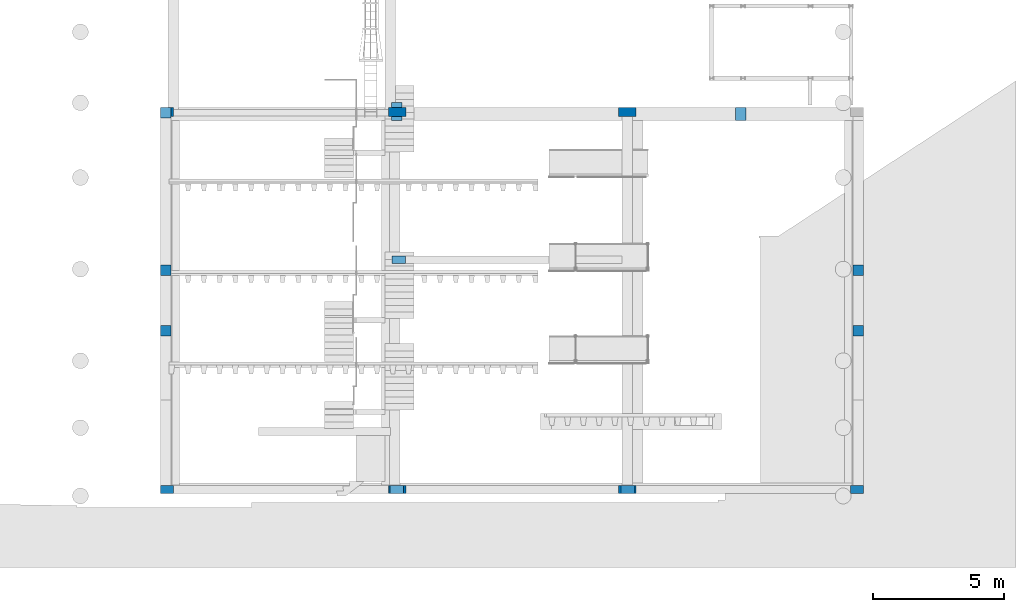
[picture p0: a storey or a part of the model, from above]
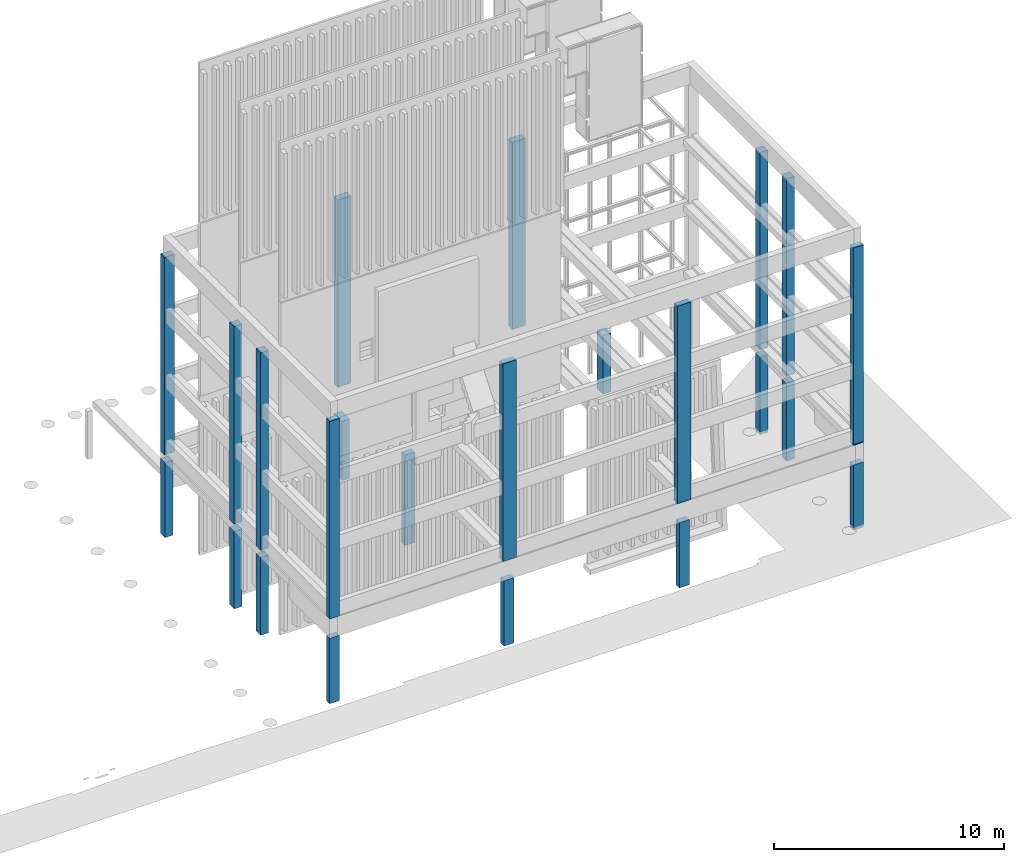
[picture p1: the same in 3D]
Properties of the parts of a building model (IFC2X3), part 1 of 16

# File
Description: ViewDefinition [CoordinationView_V2.0], Comment [Comments], Comment [System: OpenBuildings Designer24.00.03.14]
File name: SHE_DRAWING+SHEET revF16
Time: 2026-03-13T23:36:26+01:00
Author: First Name Last Name
Organization: Organization Name
Written by: ST-DEVELOPER v16.13
Made in: OpenBuildings Designer 24.00.03.14
Authorization: Administrator
Comment: Generated by software containing ST-Developer * from STEP Tools, Inc. (www.steptools.com)
Comment: description
Comment: implementation_level
Comment: name
Comment: time_stamp
Comment: author
Comment: organization
Comment: preprocessor_version
Comment: originating_system
Comment: authorisation

# IfcProject, BuildingTemplate_UK
Project - Project Name: BuildingTemplate_UK

# IfcSite, Site
RefElevation: 0 m
Pset_SiteCommon - BuildableArea: 0 m2
Site - Site Name: Site; Building Height Limit: 0 m

# IfcBuilding, Building01
ElevationOfRefHeight: 4.64 m; ElevationOfTerrain: 0 m
Classification - Uniclass2015: Co_20
Building Parameters - Building Name: Building01

# IfcBuildingStorey (2)
In: Building01
Pset_BuildingStoreyCommon - GrossAreaPlanned: 9600 m2; NetAreaPlanned: 9600 m2
Structural Floor Parameters - Column Splice Floor: no
Floor Parameters - Length (Approx.): 120 m; Width (Approx.): 80 m; Typical Floor: no; Typical Floor Base Elevation: 0 m; ACS Rotation Angle: 0:0; Annotate: yes
Floor - Area (Gross): 9600 m2; Area (Net): 9600 m2
Name | Elevation (m) = Elevation | Finished Floor | Floor Name | Typical Floor Height (m)
GF | 0 | GF | 3 | Description: Ground Floor; Floor Parameters - Description: Ground Floor
RL | 20.78 | RL | 0 | Classification - Uniclass2015: EF_30_20

# IfcSpace: A-AdministrativeCommercialAndProtectiveSer, 0
In: RL
Type - PredefinedType: USERDEFINED
Type - Space Parameters - Label: Administrative & Commercial Spaces; Ceiling Height: 3 m; major: 1; minor: 1
Type - Materials - Part Definition: A-Spaces::A_BSUK_AdministrativeCommercialAndProtectiveSer
Type - Energy Analysis - Energy Analysis | Space Category: Interior
Type - Discipline - Discipline: Architectural
Type - Construction Phase - Phase: New Construction
Type - Classification - Uniclass2015: SL_20
Description: UNIT; LongName: commercial; ElevationWithFlooring: -4.64 m
Space Parameters - Label: UNIT; Space Number: 0; Label 2: commercial; Ceiling Height: 4.5 m; Perimeter: 44.9707 m; Area | Program: 0 m2; Area | Actual: 99.3628 m2

# IfcSpace: A-CirculationAndStorageSpaces (61)
In: RL
Type - PredefinedType: USERDEFINED
Type - Space Parameters - Label: Circulation & Storage Spaces; Ceiling Height: 3 m; major: 1; minor: 1
Type - Materials - Part Definition: A-Spaces::A_BSUK_CirculationAndStorageSpaces
Type - Energy Analysis - Energy Analysis | Space Category: Interior
Type - Discipline - Discipline: Architectural
Type - Construction Phase - Phase: New Construction
ElevationWithFlooring: -4.64 m
Space Parameters - Area | Program: 0 m2
Name | Description = Label | LongName | Space Number | Label 2 | Ceiling Height (m) | Perimeter (m) | Area | Actual (m2)
1 | stair | vinyl (acD) | 1 | vinyl (acD) | 2.5 | 9.93685 | 4.25527
1 | riser | 1 | 1 |  | 2.5 | 3.72964 | 0.510705
0 | riser | 0 | 0 |  | 2.5 | 11.4772 | 2.99959
bike store | bike store | asphalt |  | asphalt | 2 | 15.5649 | 11.0029
bike store | bike store | asphalt |  | asphalt | 2 | 9.73329 | 5.58868
landing | landing | carpet (acD) |  | carpet (acD) | 2.5 | 11.3025 | 5.20961
WC | WC | tile |  | tile | 2.5 | 8.28221 | 4.08071
1 | storage | screed | 1 | screed | 2.5 | 8.26251 | 3.91896
storage | storage | screed |  | screed | 2.5 | 13.8687 | 10.5472
1 | stair | vinyl (acD) | 1 | vinyl (acD) | 2.5 | 11.6311 | 5.18709
2 | stair | vinyl (acD) | 2 | vinyl (acD) | 2.5 | 9.10975 | 3.67745
landing | landing | carpet (acD) |  | carpet (acD) | 2.5 | 6.70142 | 2.46885
storage | storage | parquet |  | parquet | 2.5 | 6.66153 | 2.57457
bath | bath | tile |  | tile | 2.5 | 8.02096 | 3.98235
3 x 1 | AOV | 1 | 1 |  | 2.6 | 3.35384 | 0.672727
3 x 1 | riser | 1 | 1 |  | 2.6 | 3.35384 | 0.672727
3 x hall (vented) | hall (vented) | carpet (acC) |  | carpet (acC) | 2.6 | 20.6 | 10.6
1 | stair | vinyl (acD) | 1 | vinyl (acD) | 2.5 | 11.2192 | 7.00439
landing | landing | vinyl (acD) |  | vinyl (acD) | 2.6 | 7.88137 | 3.11561
3 x 1 | lobby | carpet (acC) | 1 | carpet (acC) | 2.6 | 6.79532 | 2.84649
3 x 2 | riser | 2 | 2 |  | 2.6 | 3 | 0.36
3 x 2 | lobby | carpet (acC) | 2 | carpet (acC) | 2.6 | 13.6601 | 7.68884
2 x 1 | stair | vinyl (acD) | 1 | vinyl (acD) | 2.5 | 11.2192 | 7.00458
2 x landing | landing | vinyl (acD) |  | vinyl (acD) | 2.6 | 7.9118 | 3.13941
landing | landing | vinyl (acD) |  | vinyl (acD) | 2.5 | 7.02024 | 2.75607
hall (vented) | hall (vented) | carpet (acC) |  | carpet (acC) | 2.5 | 16.6709 | 8.79017
1 | lobby | carpet (acC) | 1 | carpet (acC) | 2.5 | 7.86583 | 3.64937
2 | lobby | carpet (acC) | 2 | carpet (acC) | 2.5 | 7.53988 | 3.40491
1 | AOV | 1 | 1 |  | 2.5 | 4.25 | 0.936464
1 | riser | 1 | 1 |  | 2.5 | 3.23114 | 0.605336
1 | stair | vinyl (acD) | 1 | vinyl (acD) | 2.5 | 11.3017 | 7.67441
3 | stair | parquet | 3 | parquet | 2.5 | 9.30005 | 3.43648
4 | stair | parquet | 4 | parquet | 2.5 | 9.86062 | 3.62728
5 | stair | parquet | 5 | parquet | 2.5 | 9.09993 | 3.28497
6 | stair | parquet | 6 | parquet | 2.5 | 9.4 | 3.42
26 | FLAT | 4b6p (upper) | 26 | 4b6p (upper) | 2.5 | 35.2527 | 38.2118
23 | FLAT | 4b6p (upper) | 23 | 4b6p (upper) | 2.5 | 35.2129 | 43.2149
24 | FLAT | 3b6p (upper) | 24 | 3b6p (upper) | 2.5 | 35.1807 | 43.4478
25 | FLAT | 3b6p (upper) | 25 | 3b6p (upper) | 2.5 | 38.0413 | 41.0862
1 | AOV | 1 | 1 |  | 2.5 | 3.5 | 0.715
2 | AOV | hatch over | 2 | hatch over | 2.5 | 5.99988 | 1.99994
ter.23 | ter.23 | tile |  | tile | 2.5 | 19.7927 | 12.5632
ter.24 | ter.24 | tile |  | tile | 2.5 | 19.7924 | 12.5622
ter.26 | ter.26 | tile |  | tile | 2.5 | 19.7922 | 12.5629
ter.25 | ter.25 | tile |  | tile | 2.5 | 19.7919 | 12.5618
2 | AOV | access hatch | 2 | access hatch | 2.5 | 5.99988 | 1.99994
1 | AOV | MSVS | 1 | MSVS | 2.5 | 10.8891 | 5.66237

# IfcSpace: A-ResidentialSpaces (28)
In: RL
Type - PredefinedType: USERDEFINED
Type - Space Parameters - Label: Residential Spaces; Ceiling Height: 3 m; major: 1; minor: 1
Type - Materials - Part Definition: A-Spaces::A_BSUK_ResidentialSpaces
Type - Energy Analysis - Energy Analysis | Space Category: Interior
Type - Discipline - Discipline: Architectural
Type - Construction Phase - Phase: New Construction
Type - Classification - Uniclass2015: SL_45
ElevationWithFlooring: -4.64 m
Space Parameters - Area | Program: 0 m2
Name | Description = Label | LongName = Label 2 | Space Number | Ceiling Height (m) | Perimeter (m) | Area | Actual (m2)
01 | FLAT | 2b4p (lower) | 01 | 2.5 | 30.3387 | 47.5078
ENTRANCE | ENTRANCE | residential |  | 4.5 | 31.3079 | 32.4907
01 | FLAT | 2b4p (upper) | 01 | 2.5 | 38.9093 | 49.176
07 | FLAT | 1b1p | 07 | 2.6 | 25.786 | 41.2992
06 | FLAT | 1b1p | 06 | 2.6 | 30.6107 | 40.6276
05 | FLAT | 1b1p | 05 | 2.6 | 28.883 | 41.0837
04 | FLAT | 1b1p | 04 | 2.6 | 28.903 | 41.1303
03 | FLAT | 1b1p | 03 | 2.6 | 30.9647 | 42.3191
02 | FLAT | 2b4p | 02 | 2.6 | 40.6617 | 73.0942
08 | FLAT | 1b1p | 08 | 2.6 | 29.5789 | 45.4997
21 | FLAT | 1b1p | 21 | 2.6 | 27.53 | 42.5859
20 | FLAT | 1b1p | 20 | 2.6 | 31.4827 | 41.2785
19 | FLAT | 1b1p | 19 | 2.6 | 28.883 | 41.0727
18 | FLAT | 1b1p | 18 | 2.6 | 28.903 | 41.1303
17 | FLAT | 1b1p | 17 | 2.6 | 31.8367 | 42.96
16 | FLAT | 2b4p | 16 | 2.6 | 41.0977 | 73.4146
22 | FLAT | 1b1p | 22 | 2.6 | 30.0149 | 45.8163
26 | FLAT | 4b6p (lower) | 26 | 2.5 | 39.478 | 74.3995
23 | FLAT | 4b6p (lower) | 23 | 2.5 | 39.2381 | 76.1835
24 | FLAT | 3b6p (lower) | 24 | 2.5 | 39.6636 | 68.1409
25 | FLAT | 3b6p (lower) | 25 | 2.5 | 39.3775 | 63.4613
14 | FLAT | 1b1p | 14 | 2.6 | 27.53 | 42.5859
13 | FLAT | 1b1p | 13 | 2.6 | 31.4827 | 41.2785
12 | FLAT | 1b1p | 12 | 2.6 | 28.883 | 41.0837
11 | FLAT | 1b1p | 11 | 2.6 | 28.903 | 41.1303
10 | FLAT | 1b1p | 10 | 2.6 | 31.8367 | 42.96
09 | FLAT | 2b4p | 09 | 2.6 | 41.0977 | 73.4146
15 | FLAT | 1b1p | 15 | 2.6 | 30.0149 | 45.8163

# IfcSpace: _Exterior Space (23)
Type - PredefinedType: USERDEFINED
Type - Space Parameters - Label: EXTERIOR SPACE; Ceiling Height: 3 m; Area | Program: 0 m2; major: 1; minor: 1
Type - Materials - Part Definition: A-Spaces::_Exterior_Space
Type - Energy Analysis - Energy Analysis | Space Category: Exterior
Type - Discipline - Discipline: Architectural
Type - Construction Phase - Phase: New Construction
Type - Classification - Uniclass2015: PM_40_30_17
ElevationWithFlooring: -4.64 m
Name | In | Description = Label | LongName = Label 2 | Ceiling Height (m) | Perimeter (m) | Area | Actual (m2) | Space Number
storage | RL | storage | asphalt | 2.5 | 10.2434 | 4.88146
plant | RL | plant | sprinkler | 2.5 | 13.8942 | 9.76522
refuse area | RL | refuse area | asphalt | 2 | 23.634 | 16.6836
bike store | RL | bike store | asphalt | 2 | 15.0532 | 9.86402
0 | RL | YARD | asphalt | 4 | 45.5698 | 90.2117 | 0
UNDERCROFT (front) | RL | UNDERCROFT (front) | paving | 4 | 62.6011 | 86.1884
UNDERCROFT (back) | RL | UNDERCROFT (back) | asphalt | 4 | 58.8215 | 136.239
1 | RL | Car P. | flat23 | 2 | 14.8 | 12 | 1
2 | RL | Car P. | flat24 | 2 | 14.8 | 12 | 2
3 | RL | Car P. | flat25 | 2 | 14.8002 | 12.0005 | 3
4 | RL | Car P. | flat26 | 2 | 14.8 | 12 | 4
1 | RL | YARD | asphalt (flat01) | 4 | 17.9409 | 17.4995 | 1
5 | RL | Car P. | flat01 | 2 | 14.8 | 12 | 5
storage | RL | storage | carpet | 2.5 | 8.04048 | 2.75523
storage | RL | storage | carpet | 2.5 | 8.04048 | 3.18825
1 | RL | AC | optional |  | 2.79325 | 0.397029 | 1
2 | RL | AC | optional |  | 2.79325 | 0.397029 | 2
4 | RL | AC | optional |  | 2.79325 | 0.397029 | 4
3 | RL | AC | optional |  | 2.79325 | 0.397029 | 3
flat roof | RL | flat roof | brown roof (tbc) | 2 | 56.1601 | 160.64
16 | GF | balc. | tile |  | 17.6972 | 14.8939 | 16
09 | GF | balc. | tile |  | 17.6972 | 14.8939 | 09
02 | GF | balc. | tile |  | 17.6972 | 14.8939 | 02

# IfcSpace: _Interior (139)
In: RL
Type - PredefinedType: USERDEFINED
Type - Space Parameters - Label: INTERIOR SPACE; Ceiling Height: 3 m; Area | Program: 0 m2; major: 1; minor: 1
Type - Materials - Part Definition: A-Spaces::_Interior_Space
Type - Energy Analysis - Energy Analysis | Space Category: Interior
Type - Discipline - Discipline: Architectural
Type - Construction Phase - Phase: New Construction
Type - Classification - Uniclass2015: PM_40_30_17
ElevationWithFlooring: -4.64 m
Name | Description = Label | LongName = Label 2 | Ceiling Height (m) | Perimeter (m) | Area | Actual (m2)
7 x firef. LIFT | firef. LIFT | (1.1x1.4m) | 2.2 | 4.8 | 1.4
bed | bed | carpet | 2.6 | 16.9306 | 16.1823
bath | bath | tile | 2.6 | 8.42663 | 4.02329
corridor | corridor | parquet | 2.6 | 22.8095 | 18.4831
F | WC | tile (disab.) | 2.6 | 8.46664 | 4.29711 | Space Parameters - Space Number: F
M | WC | tile | 2.6 | 6.8273 | 2.65638 | Space Parameters - Space Number: M
2 | bed | carpet | 2.6 | 15.1363 | 13.1528 | Space Parameters - Space Number: 2
k/d/l | k/d/l | parquet | 2.6 | 21.6917 | 25.0467
k/d/l | k/d/l | parquet | 2.6 | 19.206 | 18.8529
3 x bath | bath | tile | 2.6 | 7.57 | 3.188
3 x storage | storage | parquet | 2.6 | 5 | 1.26
3 x bath | bath | tile | 2.6 | 8.85627 | 3.75315
3 x storage | storage | parquet | 2.6 | 4.75839 | 1.24325
k/d/l | k/d/l | parquet | 2.6 | 25.4441 | 23.3097
6 x bed | bed | carpet | 2.6 | 14.94 | 11.4885
3 x k/d/l | k/d/l | parquet | 2.6 | 24.0409 | 23.4095
6 x bath | bath | tile | 2.6 | 7.8 | 3.6
3 x storage | storage | parquet | 2.6 | 6.58993 | 1.70217
3 x storage | storage | parquet | 2.6 | 6.59 | 1.70223
3 x k/d/l | k/d/l | parquet | 2.6 | 24.497 | 23.2991
studio | studio | parquet | 2.6 | 31.4647 | 37.2975
3 x bath | bath | tile | 2.6 | 7.898 | 3.43088
3 x corridor | corridor | parquet | 2.6 | 16.5296 | 9.0203
3 x bath | bath | tile | 2.6 | 8.35 | 4.35
k/d/l | k/d/l | parquet | 2.6 | 20.4702 | 23.828
3 x 2 | bed | carpet | 2.6 | 15.0894 | 11.9399 | Space Parameters - Space Number: 2
3 x 1 | bed | carpet | 2.6 | 17.0797 | 15.1572 | Space Parameters - Space Number: 1
3 x storage | storage | parquet | 2.6 | 2.74374 | 0.470142
k/d/l | k/d/l | parquet | 2.6 | 20.6123 | 21.7383
corridor | corridor | parquet | 2.6 | 11.3315 | 6.13542
3 x bath | bath | tile | 2.6 | 7.80943 | 3.60707
3 x storage | storage | parquet | 2.6 | 4.56315 | 1.30038
3 x corridor | corridor | parquet | 2.6 | 13.57 | 6.7325
bed | bed | carpet | 2.6 | 14.4144 | 11.4258
bed | bed | carpet | 2.6 | 12.7068 | 9.99626
3 x bed | bed | carpet | 2.6 | 14.3106 | 11.3749
3 x ensuite | ensuite | tile | 2.6 | 7.89374 | 3.31102
3 x storage | storage | parquet | 2.6 | 4.59 | 1.1165
3 x storage | storage | parquet | 2.6 | 10.8267 | 2.53079
2 x k/d/l | k/d/l | parquet | 2.6 | 20.514 | 19.8142
2 x k/d/l | k/d/l | parquet | 2.6 | 26.3161 | 23.9605
2 x studio | studio | parquet | 2.6 | 32.3367 | 37.9385
2 x k/d/l | k/d/l | parquet | 2.6 | 20.9062 | 24.1484
2 x k/d/l | k/d/l | parquet | 2.6 | 20.8123 | 22.155
2 x corridor | corridor | parquet | 2.6 | 11.1315 | 6.01011
2 x bed | bed | carpet | 2.6 | 14.6504 | 11.4605
2 x bed | bed | carpet | 2.6 | 13.1428 | 10.3217
1 | bed | carpet | 2.5 | 18.5595 | 16.7018 | Space Parameters - Space Number: 1
2 | bed | carpet | 2.5 | 17.0596 | 17.0642 | Space Parameters - Space Number: 2
3 | bed | carpet | 2.5 | 15.5204 | 13.1055 | Space Parameters - Space Number: 3
1 | bed | carpet | 2.5 | 15.4796 | 12.4714 | Space Parameters - Space Number: 1
2 | bed | carpet | 2.5 | 17.0597 | 17.0642 | Space Parameters - Space Number: 2
3 | bed | carpet | 2.5 | 21.2205 | 20.0816 | Space Parameters - Space Number: 3
1 | bed | carpet | 2.5 | 15.8135 | 14.5623 | Space Parameters - Space Number: 1
2 | bed | carpet | 2.5 | 13.9942 | 11.7202 | Space Parameters - Space Number: 2
3 | bed | carpet | 2.5 | 15.43 | 13.4523 | Space Parameters - Space Number: 3
1 | bed | carpet | 2.5 | 15.9594 | 15.0373 | Space Parameters - Space Number: 1
2 | bed | carpet | 2.5 | 13.98 | 10.1834 | Space Parameters - Space Number: 2
3 | bed | carpet | 2.5 | 15.39 | 13.2723 | Space Parameters - Space Number: 3
corridor (protected) | corridor (protected) | parquet | 2.5 | 17.0031 | 11.5791
corridor (protected) | corridor (protected) | parquet | 2.5 | 15.5899 | 9.09301
corridor (protected) | corridor (protected) | parquet | 2.5 | 14.14 | 7.78613
corridor (protected) | corridor (protected) | parquet | 2.5 | 17.46 | 9.28961
bath | bath | tile | 2.5 | 11.4399 | 7.26747
bath | bath | tile | 2.5 | 9.60027 | 4.97525
bath | bath | tile | 2.5 | 9.61248 | 4.99208
ensuite | ensuite | tile | 2.5 | 9.6127 | 4.9406
ensuite | ensuite | tile | 2.5 | 8.21964 | 4.07132
ensuite | ensuite | tile | 2.5 | 8.21964 | 4.07133
bath | bath | tile | 2.5 | 8.94446 | 4.54559
ensuite | ensuite | tile | 2.5 | 7.27294 | 3.08918
storage | storage | parquet | 2.5 | 4.47976 | 1.20139
storage | storage | parquet | 2.5 | 5.08042 | 1.46085

# IfcBeam: A-Beams-Steel (168)
Type - PredefinedType: BEAM
Type - Profile - Name: UB203X133X25
Type - Thermal Transmittance - Is External: no; Is Below Grade: no
Type - Structural Usage - Structural | Material: Steel
Type - Structural Parameters - Section Name: UB203X133X25; Structural Type: Beam; Tapered Member: no
Type - Steel Beam Results - End 1 Shear: 0; End 2 Shear: 0
Type - Materials - Part Definition: A-Beams::A_BSUK_Beams_Steel
Type - Fireproofing - Has Fireproofing: no
Type - Fire Resistance - Fire | IsCombustible: no; Fire | Compartmentation: no
Type - Discipline - Discipline: Architectural
Type - Construction Phase - Phase: New Construction
Type - Classification - Uniclass2015: Pr_20_85_08_11
Material: A_BSUK_Beams_Steel
Pset_BeamCommon - IsExternal: no; LoadBearing: no
Steel Beam Results - Camber: 0 m
Quantities | Structural - Material Density: 7850.000000
Fireproofing - Fireproofing Thickness: 0 m
BuildingDesignerForm - Cope Flange Clearance: 0.000; Cope Web Clearance: 0.000; Cope Corner Treatment: 0; Cope Corner Radius: 0.000; Local Y Offset: 0.000; Local Z Offset: 0.000
Name | In | Description | CodeSystem | Name = StructuralFramingCommon, Section Name | Structural Parameters, Section Name | Length (m) | Area | Cross-sectional (m2) | Area | Cross-sectional Modeled (m2) | Area | Side Surfaces Modeled (Gross) (m2) | Area | All Surfaces Modeled (Net) (m2) | Volume | Perforation(s) (m3) | Volume (Gross) (m3) | Volume (Gross Modeled) (m3) | Volume (Net) (m3) | Volume (Net Modeled) (m3) | Unit Weight | Length x Unit Weight | Volume (Gross) x Density | Volume (Gross Modeled) x Density | Volume (Net) x Density | Volume (Net Modeled) x Density
A-Beams-Steel | RL | 1 ,SHE_DRAWING+SHEET.dgn,Design Model;2,SHE-02.MEZZANINE.dgn,Design Model:192737 | BS UC | UC203X203X46 | 1\BS UC\UC203X203X46 | 6.35664 | 0.00587 | 0.005784 | 7.66866 | 7.68022 | 0 | 0.037314 | 0.036766 | 0.037314 | 0.036766 | 46.100000 | 293.041306 | 292.910995 | 288.611640 | 292.910995 | 288.611640 | Construction Phase - Phase: Existing to Remain
A-Beams-Steel | RL | 1 ,SHE_DRAWING+SHEET.dgn,Design Model;2,SHE-02.MEZZANINE.dgn,Design Model:192800 | BS UC | UC203X203X46 | 1\BS UC\UC203X203X46 | 6.46778 | 0.00587 | 0.005784 | 7.80273 | 7.8143 | 0 | 0.037966 | 0.037409 | 0.037966 | 0.037409 | 46.100000 | 298.164608 | 298.032018 | 293.657497 | 298.032018 | 293.657497 | Construction Phase - Phase: Existing to Remain
A-Beams-Steel | RL | 1 ,SHE_DRAWING+SHEET.dgn,Design Model;5,SHE-13.STEEL.dgn,Design Model:105049 | BS UC | UC203X203X46 | 1\BS UC\UC203X203X46 | 2.3816 | 0.00587 | 0.005784 | 2.87316 | 2.88473 | 0 | 0.01398 | 0.013775 | 0.01398 | 0.013775 | 46.100000 | 109.791760 | 109.742937 | 108.132128 | 109.742937 | 108.132128
A-Beams-Steel | RL | 1 ,SHE_DRAWING+SHEET.dgn,Design Model;5,SHE-13.STEEL.dgn,Design Model:105052 | BS UC | UC305X305X158 | 1\BS UC\UC305X305X158 | 4.03635 | 0.0201 | 0.019938 | 7.53748 | 7.57736 | 0 | 0.081131 | 0.080477 | 0.081131 | 0.080477 | 158.100000 | 638.146935 | 636.875485 | 631.748162 | 636.875485 | 631.748162 | Identification - ID | Notes: PRE-CAMBER
A-Beams-Steel | RL | 1 ,SHE_DRAWING+SHEET.dgn,Design Model;5,SHE-13.STEEL.dgn,Design Model:105055 | BS UC | UC305X305X240 | 1\BS UC\UC305X305X240 | 4.2009 | 0.0306 | 0.030381 | 8.11866 | 8.17942 | 0 | 0.128548 | 0.127626 | 0.128548 | 0.127626 | 240.000000 | 1008.216000 | 1009.098189 | 1001.865000 | 1009.098189 | 1001.865000 | Identification - ID | Notes: PRE-CAMBER
A-Beams-Steel | RL | 1 ,SHE_DRAWING+SHEET.dgn,Design Model;5,SHE-13.STEEL.dgn,Design Model:105057 | BS UC | UC305X305X158 | 1\BS UC\UC305X305X158 | 3.9209 | 0.0201 | 0.019938 | 7.32189 | 7.36177 | 0 | 0.07881 | 0.078176 | 0.07881 | 0.078176 | 158.100000 | 619.894290 | 618.659207 | 613.678538 | 618.659207 | 613.678538 | Identification - ID | Notes: PRE-CAMBER
A-Beams-Steel | RL | 1 ,SHE_DRAWING+SHEET.dgn,Design Model;5,SHE-13.STEEL.dgn,Design Model:105059 | BS UC | UC305X305X158 | 1\BS UC\UC305X305X158 | 3.9185 | 0.0201 | 0.019938 | 7.31741 | 7.35728 | 0 | 0.078762 | 0.078128 | 0.078762 | 0.078128 | 158.100000 | 619.514850 | 618.280523 | 613.302903 | 618.280523 | 613.302903 | Identification - ID | Notes: PRE-CAMBER
A-Beams-Steel | RL | 1 ,SHE_DRAWING+SHEET.dgn,Design Model;5,SHE-13.STEEL.dgn,Design Model:105061 | BS UC | UC305X305X240 | 1\BS UC\UC305X305X240 | 4.2009 | 0.0306 | 0.030381 | 8.11866 | 8.17942 | 0 | 0.128548 | 0.127626 | 0.128548 | 0.127626 | 240.000000 | 1008.216000 | 1009.098189 | 1001.865000 | 1009.098189 | 1001.865000 | Identification - ID | Notes: PRE-CAMBER
A-Beams-Steel | RL | 1 ,SHE_DRAWING+SHEET.dgn,Design Model;5,SHE-13.STEEL.dgn,Design Model:105063 | BS UC | UC305X305X240 | 1\BS UC\UC305X305X240 | 8.42545 | 0.0306 | 0.030381 | 16.283 | 16.3438 | 0 | 0.257819 | 0.255971 | 0.257819 | 0.255971 | 240.000000 | 2022.108000 | 2023.877344 | 2009.370245 | 2023.877344 | 2009.370245
A-Beams-Steel | RL | 1 ,SHE_DRAWING+SHEET.dgn,Design Model;5,SHE-13.STEEL.dgn,Design Model:105065 | BS UC | UC305X305X240 | 1\BS UC\UC305X305X240 | 5.70725 | 0.0306 | 0.030381 | 11.0298 | 11.0906 | 0 | 0.174642 | 0.17339 | 0.174642 | 0.17339 | 240.000000 | 1369.740000 | 1370.938522 | 1361.111671 | 1370.938522 | 1361.111671
A-Beams-Steel | RL | 1 ,SHE_DRAWING+SHEET.dgn,Design Model;5,SHE-13.STEEL.dgn,Design Model:105067 | BS UC | UC305X305X240 | 1\BS UC\UC305X305X240 | 8.385 | 0.0306 | 0.030381 | 16.2049 | 16.2656 | 0 | 0.256581 | 0.254742 | 0.256581 | 0.254742 | 240.000000 | 2012.400000 | 2014.160850 | 1999.723398 | 2014.160850 | 1999.723398
A-Beams-Steel | RL | 1 ,SHE_DRAWING+SHEET.dgn,Design Model;5,SHE-13.STEEL.dgn,Design Model:105069 | BS UC | UC305X305X240 | 1\BS UC\UC305X305X240 | 8.42545 | 0.0306 | 0.030381 | 16.283 | 16.3438 | 0 | 0.257819 | 0.255971 | 0.257819 | 0.255971 | 240.000000 | 2022.108000 | 2023.877344 | 2009.370245 | 2023.877344 | 2009.370245
A-Beams-Steel | RL | 1 ,SHE_DRAWING+SHEET.dgn,Design Model;5,SHE-13.STEEL.dgn,Design Model:105071 | BS UC | UC305X305X240 | 1\BS UC\UC305X305X240 | 8.66545 | 0.0306 | 0.030381 | 16.7468 | 16.8076 | 0 | 0.265163 | 0.263262 | 0.265163 | 0.263262 | 240.000000 | 2079.708000 | 2081.527744 | 2066.607408 | 2081.527744 | 2066.607408
A-Beams-Steel | RL | 1 ,SHE_DRAWING+SHEET.dgn,Design Model;5,SHE-13.STEEL.dgn,Design Model:105073 | BS UC | UC305X305X240 | 1\BS UC\UC305X305X240 | 8.36 | 0.0306 | 0.030381 | 16.1565 | 16.2173 | 0 | 0.255816 | 0.253982 | 0.255816 | 0.253982 | 240.000000 | 2006.400000 | 2008.155600 | 1993.761193 | 2008.155600 | 1993.761193
A-Beams-Steel | RL | 1 ,SHE_DRAWING+SHEET.dgn,Design Model;5,SHE-13.STEEL.dgn,Design Model:105076 | BS UC | UC203X203X86 | 1\BS UC\UC203X203X86 | 5.4208 | 0.011 | 0.010874 | 6.80527 | 6.82702 | 0 | 0.059629 | 0.058948 | 0.059629 | 0.058948 | 86.100000 | 466.730880 | 468.086080 | 462.738835 | 468.086080 | 462.738835
A-Beams-Steel | RL | 1 ,SHE_DRAWING+SHEET.dgn,Design Model;5,SHE-13.STEEL.dgn,Design Model:105078 | BS UC | UC203X203X86 | 1\BS UC\UC203X203X86 | 5.4208 | 0.011 | 0.010874 | 6.80527 | 6.82702 | 0 | 0.059629 | 0.058948 | 0.059629 | 0.058948 | 86.100000 | 466.730880 | 468.086080 | 462.738835 | 468.086080 | 462.738835
A-Beams-Steel | RL | 1 ,SHE_DRAWING+SHEET.dgn,Design Model;5,SHE-13.STEEL.dgn,Design Model:105080 | BS UC | UC203X203X86 | 1\BS UC\UC203X203X86 | 5.7392 | 0.011 | 0.010874 | 7.20499 | 7.22674 | 0 | 0.063131 | 0.06241 | 0.063131 | 0.06241 | 86.100000 | 494.145120 | 495.579920 | 489.918595 | 495.579920 | 489.918595
A-Beams-Steel | RL | 1 ,SHE_DRAWING+SHEET.dgn,Design Model;5,SHE-13.STEEL.dgn,Design Model:105082 | BS UC | UC203X203X86 | 1\BS UC\UC203X203X86 | 5.4208 | 0.011 | 0.010874 | 6.80527 | 6.82702 | 0 | 0.059629 | 0.058948 | 0.059629 | 0.058948 | 86.100000 | 466.730880 | 468.086080 | 462.738835 | 468.086080 | 462.738835
A-Beams-Steel | RL | 1 ,SHE_DRAWING+SHEET.dgn,Design Model;5,SHE-13.STEEL.dgn,Design Model:105084 | BS UC | UC203X203X86 | 1\BS UC\UC203X203X86 | 5.505 | 0.011 | 0.010874 | 6.91098 | 6.93273 | 0 | 0.060555 | 0.059863 | 0.060555 | 0.059863 | 86.100000 | 473.980500 | 475.356750 | 469.926447 | 475.356750 | 469.926447
A-Beams-Steel | RL | 1 ,SHE_DRAWING+SHEET.dgn,Design Model;5,SHE-13.STEEL.dgn,Design Model:105086 | BS UC | UC203X203X86 | 1\BS UC\UC203X203X86 | 5.4208 | 0.011 | 0.010874 | 6.80527 | 6.82702 | 0 | 0.059629 | 0.058948 | 0.059629 | 0.058948 | 86.100000 | 466.730880 | 468.086080 | 462.738835 | 468.086080 | 462.738835
A-Beams-Steel | RL | 1 ,SHE_DRAWING+SHEET.dgn,Design Model;5,SHE-13.STEEL.dgn,Design Model:105088 | BS UC | UC203X203X86 | 1\BS UC\UC203X203X86 | 5.4208 | 0.011 | 0.010874 | 6.80527 | 6.82702 | 0 | 0.059629 | 0.058948 | 0.059629 | 0.058948 | 86.100000 | 466.730880 | 468.086080 | 462.738835 | 468.086080 | 462.738835
A-Beams-Steel | RL | 1 ,SHE_DRAWING+SHEET.dgn,Design Model;5,SHE-13.STEEL.dgn,Design Model:105090 | BS UC | UC203X203X86 | 1\BS UC\UC203X203X86 | 5.4208 | 0.011 | 0.010874 | 6.80527 | 6.82702 | 0 | 0.059629 | 0.058948 | 0.059629 | 0.058948 | 86.100000 | 466.730880 | 468.086080 | 462.738835 | 468.086080 | 462.738835
A-Beams-Steel | RL | 1 ,SHE_DRAWING+SHEET.dgn,Design Model;5,SHE-13.STEEL.dgn,Design Model:105092 | BS UC | UC203X203X86 | 1\BS UC\UC203X203X86 | 5.4208 | 0.011 | 0.010874 | 6.80527 | 6.82702 | 0 | 0.059629 | 0.058948 | 0.059629 | 0.058948 | 86.100000 | 466.730880 | 468.086080 | 462.738835 | 468.086080 | 462.738835
A-Beams-Steel | RL | 1 ,SHE_DRAWING+SHEET.dgn,Design Model;5,SHE-13.STEEL.dgn,Design Model:105094 | BS UC | UC203X203X86 | 1\BS UC\UC203X203X86 | 5.7392 | 0.011 | 0.010874 | 7.20499 | 7.22674 | 0 | 0.063131 | 0.06241 | 0.063131 | 0.06241 | 86.100000 | 494.145120 | 495.579920 | 489.918595 | 495.579920 | 489.918595
A-Beams-Steel | RL | 1 ,SHE_DRAWING+SHEET.dgn,Design Model;5,SHE-13.STEEL.dgn,Design Model:105096 | BS UC | UC203X203X86 | 1\BS UC\UC203X203X86 | 5.4208 | 0.011 | 0.010874 | 6.80527 | 6.82702 | 0 | 0.059629 | 0.058948 | 0.059629 | 0.058948 | 86.100000 | 466.730874 | 468.086074 | 462.738829 | 468.086074 | 462.738829
A-Beams-Steel | RL | 1 ,SHE_DRAWING+SHEET.dgn,Design Model;5,SHE-13.STEEL.dgn,Design Model:105098 | BS UC | UC203X203X86 | 1\BS UC\UC203X203X86 | 5.58 | 0.011 | 0.010874 | 7.00513 | 7.02688 | 0 | 0.06138 | 0.060679 | 0.06138 | 0.060679 | 86.100000 | 480.438000 | 481.833000 | 476.328715 | 481.833000 | 476.328715
A-Beams-Steel | RL | 1 ,SHE_DRAWING+SHEET.dgn,Design Model;5,SHE-13.STEEL.dgn,Design Model:105100 | BS UC | UC203X203X86 | 1\BS UC\UC203X203X86 | 5.4208 | 0.011 | 0.010874 | 6.80527 | 6.82702 | 0 | 0.059629 | 0.058948 | 0.059629 | 0.058948 | 86.100000 | 466.730880 | 468.086080 | 462.738835 | 468.086080 | 462.738835
A-Beams-Steel | RL | 1 ,SHE_DRAWING+SHEET.dgn,Design Model;5,SHE-13.STEEL.dgn,Design Model:105102 | BS UC | UC203X203X86 | 1\BS UC\UC203X203X86 | 5.4208 | 0.011 | 0.010874 | 6.80527 | 6.82702 | 0 | 0.059629 | 0.058948 | 0.059629 | 0.058948 | 86.100000 | 466.730880 | 468.086080 | 462.738835 | 468.086080 | 462.738835
A-Beams-Steel | RL | 1 ,SHE_DRAWING+SHEET.dgn,Design Model;5,SHE-13.STEEL.dgn,Design Model:105104 | BS UC | UC203X203X46 | 1\BS UC\UC203X203X46 | 2.3816 | 0.00587 | 0.005784 | 2.87316 | 2.88473 | 0 | 0.01398 | 0.013775 | 0.01398 | 0.013775 | 46.100000 | 109.791760 | 109.742937 | 108.132128 | 109.742937 | 108.132128
A-Beams-Steel | RL | 1 ,SHE_DRAWING+SHEET.dgn,Design Model;5,SHE-13.STEEL.dgn,Design Model:105106 | BS UC | UC203X203X46 | 1\BS UC\UC203X203X46 | 2.3816 | 0.00587 | 0.005784 | 2.87316 | 2.88473 | 0 | 0.01398 | 0.013775 | 0.01398 | 0.013775 | 46.100000 | 109.791763 | 109.742940 | 108.132131 | 109.742940 | 108.132131
A-Beams-Steel | RL | 1 ,SHE_DRAWING+SHEET.dgn,Design Model;5,SHE-13.STEEL.dgn,Design Model:105108 | BS UC | UC203X203X46 | 1\BS UC\UC203X203X46 | 2.3816 | 0.00587 | 0.005784 | 2.87316 | 2.88473 | 0 | 0.01398 | 0.013775 | 0.01398 | 0.013775 | 46.100000 | 109.791763 | 109.742940 | 108.132131 | 109.742940 | 108.132131
A-Beams-Steel | RL | 1 ,SHE_DRAWING+SHEET.dgn,Design Model;5,SHE-13.STEEL.dgn,Design Model:105110 | BS UC | UC203X203X46 | 1\BS UC\UC203X203X46 | 1.9664 | 0.00587 | 0.005784 | 2.37227 | 2.38383 | 0 | 0.011543 | 0.011373 | 0.011543 | 0.011373 | 46.100000 | 90.651040 | 90.610729 | 89.280742 | 90.610729 | 89.280742
A-Beams-Steel | RL | 1 ,SHE_DRAWING+SHEET.dgn,Design Model;5,SHE-13.STEEL.dgn,Design Model:105112 | BS UC | UC203X203X46 | 1\BS UC\UC203X203X46 | 2.3816 | 0.00587 | 0.005784 | 2.87316 | 2.88473 | 0 | 0.01398 | 0.013775 | 0.01398 | 0.013775 | 46.100000 | 109.791760 | 109.742937 | 108.132128 | 109.742937 | 108.132128
A-Beams-Steel | RL | 1 ,SHE_DRAWING+SHEET.dgn,Design Model;5,SHE-13.STEEL.dgn,Design Model:105114 | BS UC | UC203X203X46 | 1\BS UC\UC203X203X46 | 2.3816 | 0.00587 | 0.005784 | 2.87316 | 2.88473 | 0 | 0.01398 | 0.013775 | 0.01398 | 0.013775 | 46.100000 | 109.791760 | 109.742937 | 108.132128 | 109.742937 | 108.132128
A-Beams-Steel | RL | 1 ,SHE_DRAWING+SHEET.dgn,Design Model;5,SHE-13.STEEL.dgn,Design Model:105116 | BS UC | UC203X203X46 | 1\BS UC\UC203X203X46 | 4.2009 | 0.00587 | 0.005784 | 5.06797 | 5.07953 | 0 | 0.024659 | 0.024297 | 0.024659 | 0.024297 | 46.100000 | 193.661490 | 193.575372 | 190.734068 | 193.575372 | 190.734068
A-Beams-Steel | RL | 1 ,SHE_DRAWING+SHEET.dgn,Design Model;5,SHE-13.STEEL.dgn,Design Model:105118 | BS UC | UC203X203X46 | 1\BS UC\UC203X203X46 | 4.2009 | 0.00587 | 0.005784 | 5.06797 | 5.07953 | 0 | 0.024659 | 0.024297 | 0.024659 | 0.024297 | 46.100000 | 193.661490 | 193.575372 | 190.734068 | 193.575372 | 190.734068
A-Beams-Steel | RL | 1 ,SHE_DRAWING+SHEET.dgn,Design Model;5,SHE-13.STEEL.dgn,Design Model:105120 | BS UC | UC203X203X46 | 1\BS UC\UC203X203X46 | 0.7764 | 0.00587 | 0.005784 | 0.936649 | 0.948217 | 0 | 0.004557 | 0.004491 | 0.004557 | 0.004491 | 46.100000 | 35.792040 | 35.776124 | 35.251001 | 35.776124 | 35.251001
A-Beams-Steel | RL | 1 ,SHE_DRAWING+SHEET.dgn,Design Model;5,SHE-13.STEEL.dgn,Design Model:105122 | BS UC | UC203X203X46 | 1\BS UC\UC203X203X46 | 0.7764 | 0.00587 | 0.005784 | 0.936649 | 0.948217 | 0 | 0.004557 | 0.004491 | 0.004557 | 0.004491 | 46.100000 | 35.792040 | 35.776124 | 35.251001 | 35.776124 | 35.251001
A-Beams-Steel | RL | 1 ,SHE_DRAWING+SHEET.dgn,Design Model;5,SHE-13.STEEL.dgn,Design Model:105124 | BS UC | UC203X203X46 | 1\BS UC\UC203X203X46 | 4.2509 | 0.00587 | 0.005784 | 5.12829 | 5.13985 | 0 | 0.024953 | 0.024587 | 0.024953 | 0.024587 | 46.100000 | 195.966490 | 195.879347 | 193.004225 | 195.879347 | 193.004225
A-Beams-Steel | RL | 1 ,SHE_DRAWING+SHEET.dgn,Design Model;5,SHE-13.STEEL.dgn,Design Model:105126 | BS UC | UC203X203X46 | 1\BS UC\UC203X203X46 | 4.2509 | 0.00587 | 0.005784 | 5.12829 | 5.13985 | 0 | 0.024953 | 0.024587 | 0.024953 | 0.024587 | 46.100000 | 195.966490 | 195.879347 | 193.004225 | 195.879347 | 193.004225
A-Beams-Steel | RL | 1 ,SHE_DRAWING+SHEET.dgn,Design Model;5,SHE-13.STEEL.dgn,Design Model:105252 | BS UC | UC305X305X240 | 1\BS UC\UC305X305X240 | 4.2509 | 0.0306 | 0.030381 | 8.21529 | 8.27605 | 0 | 0.130078 | 0.129145 | 0.130078 | 0.129145 | 240.000000 | 1020.216000 | 1021.108689 | 1013.789409 | 1021.108689 | 1013.789409 | Identification - ID | Notes: PRE-CAMBER
A-Beams-Steel | RL | 1 ,SHE_DRAWING+SHEET.dgn,Design Model;5,SHE-13.STEEL.dgn,Design Model:105254 | BS UC | UC305X305X158 | 1\BS UC\UC305X305X158 | 4.01635 | 0.0201 | 0.019938 | 7.50013 | 7.54001 | 0 | 0.080729 | 0.080079 | 0.080729 | 0.080079 | 158.100000 | 634.984935 | 633.719785 | 628.617868 | 633.719785 | 628.617868 | Identification - ID | Notes: PRE-CAMBER
A-Beams-Steel | RL | 1 ,SHE_DRAWING+SHEET.dgn,Design Model;5,SHE-13.STEEL.dgn,Design Model:105256 | BS UC | UC305X305X158 | 1\BS UC\UC305X305X158 | 3.9709 | 0.0201 | 0.019938 | 7.41526 | 7.45514 | 0 | 0.079815 | 0.079173 | 0.079815 | 0.079173 | 158.100000 | 627.799290 | 626.548457 | 621.504274 | 626.548457 | 621.504274 | Identification - ID | Notes: PRE-CAMBER
A-Beams-Steel | RL | 1 ,SHE_DRAWING+SHEET.dgn,Design Model;5,SHE-13.STEEL.dgn,Design Model:105258 | BS UC | UC305X305X158 | 1\BS UC\UC305X305X158 | 4.03635 | 0.0201 | 0.019938 | 7.53748 | 7.57736 | 0 | 0.081131 | 0.080477 | 0.081131 | 0.080477 | 158.100000 | 638.146935 | 636.875485 | 631.748162 | 636.875485 | 631.748162 | Identification - ID | Notes: PRE-CAMBER
A-Beams-Steel | RL | 1 ,SHE_DRAWING+SHEET.dgn,Design Model;5,SHE-13.STEEL.dgn,Design Model:105260 | BS UC | UC305X305X158 | 1\BS UC\UC305X305X158 | 3.9709 | 0.0201 | 0.019938 | 7.41526 | 7.45514 | 0 | 0.079815 | 0.079173 | 0.079815 | 0.079173 | 158.100000 | 627.799290 | 626.548457 | 621.504274 | 626.548457 | 621.504274 | Identification - ID | Notes: PRE-CAMBER
A-Beams-Steel | RL | 1 ,SHE_DRAWING+SHEET.dgn,Design Model;5,SHE-13.STEEL.dgn,Design Model:105262 | BS UC | UC305X305X240 | 1\BS UC\UC305X305X240 | 4.2509 | 0.0306 | 0.030381 | 8.21529 | 8.27605 | 0 | 0.130078 | 0.129145 | 0.130078 | 0.129145 | 240.000000 | 1020.216000 | 1021.108689 | 1013.789409 | 1021.108689 | 1013.789409 | Identification - ID | Notes: PRE-CAMBER
A-Beams-Steel | RL | 1 ,SHE_DRAWING+SHEET.dgn,Design Model;5,SHE-13.STEEL.dgn,Design Model:105264 | BS UC | UC305X305X158 | 1\BS UC\UC305X305X158 | 4.01635 | 0.0201 | 0.019938 | 7.50013 | 7.54001 | 0 | 0.080729 | 0.080079 | 0.080729 | 0.080079 | 158.100000 | 634.984935 | 633.719785 | 628.617868 | 633.719785 | 628.617868 | Identification - ID | Notes: PRE-CAMBER
A-Beams-Steel | RL | 1 ,SHE_DRAWING+SHEET.dgn,Design Model;5,SHE-13.STEEL.dgn,Design Model:105292 | BS UC | UC305X305X240 | 1\BS UC\UC305X305X240 | 3.97593 | 0.0306 | 0.030381 | 7.68388 | 7.74464 | 0 | 0.121663 | 0.120791 | 0.121663 | 0.120791 | 240.000000 | 954.222994 | 955.057939 | 948.212108 | 955.057939 | 948.212108
A-Beams-Steel | RL | 1 ,SHE_DRAWING+SHEET.dgn,Design Model;5,SHE-13.STEEL.dgn,Design Model:105294 | BS UC | UC305X305X240 | 1\BS UC\UC305X305X240 | 4.2564 | 0.0306 | 0.030381 | 8.22592 | 8.28668 | 0 | 0.130246 | 0.129312 | 0.130246 | 0.129312 | 240.000000 | 1021.536000 | 1022.429844 | 1015.101094 | 1022.429844 | 1015.101094
A-Beams-Steel | RL | 1 ,SHE_DRAWING+SHEET.dgn,Design Model;5,SHE-13.STEEL.dgn,Design Model:105296 | BS UC | UC305X305X240 | 1\BS UC\UC305X305X240 | 3.92637 | 0.0306 | 0.030381 | 7.5881 | 7.64886 | 0 | 0.120147 | 0.119286 | 0.120147 | 0.119286 | 240.000000 | 942.327813 | 943.152349 | 936.391858 | 943.152349 | 936.391858
A-Beams-Steel | RL | 1 ,SHE_DRAWING+SHEET.dgn,Design Model;5,SHE-13.STEEL.dgn,Design Model:105298 | BS UC | UC305X305X240 | 1\BS UC\UC305X305X240 | 4.2064 | 0.0306 | 0.030381 | 8.12929 | 8.19005 | 0 | 0.128716 | 0.127793 | 0.128716 | 0.127793 | 240.000000 | 1009.536000 | 1010.419344 | 1003.176685 | 1010.419344 | 1003.176685
A-Beams-Steel | RL | 1 ,SHE_DRAWING+SHEET.dgn,Design Model;5,SHE-13.STEEL.dgn,Design Model:105300 | BS UC | UC203X203X46 | 1\BS UC\UC203X203X46 | 2.3424 | 0.00587 | 0.005784 | 2.82587 | 2.83744 | 0 | 0.01375 | 0.013548 | 0.01375 | 0.013548 | 46.100000 | 107.984640 | 107.936621 | 106.352325 | 107.936621 | 106.352325
A-Beams-Steel | RL | 1 ,SHE_DRAWING+SHEET.dgn,Design Model;5,SHE-13.STEEL.dgn,Design Model:105302 | BS UC | UC203X203X46 | 1\BS UC\UC203X203X46 | 2.546 | 0.00587 | 0.005784 | 3.07149 | 3.08306 | 0 | 0.014945 | 0.014726 | 0.014945 | 0.014726 | 46.100000 | 117.370600 | 117.318407 | 115.596405 | 117.318407 | 115.596405
A-Beams-Steel | RL | 1 ,SHE_DRAWING+SHEET.dgn,Design Model;5,SHE-13.STEEL.dgn,Design Model:105304 | BS UC | UC203X203X46 | 1\BS UC\UC203X203X46 | 2.49165 | 0.00587 | 0.005784 | 3.00593 | 3.01749 | 0 | 0.014626 | 0.014411 | 0.014626 | 0.014411 | 46.100000 | 114.865065 | 114.813986 | 113.128744 | 114.813986 | 113.128744
A-Beams-Steel | RL | 1 ,SHE_DRAWING+SHEET.dgn,Design Model;5,SHE-13.STEEL.dgn,Design Model:105306 | BS UC | UC203X203X46 | 1\BS UC\UC203X203X46 | 2.4936 | 0.00587 | 0.005784 | 3.00828 | 3.01985 | 0 | 0.014637 | 0.014423 | 0.014637 | 0.014423 | 46.100000 | 114.954960 | 114.903841 | 113.217280 | 114.903841 | 113.217280
A-Beams-Steel | RL | 1 ,SHE_DRAWING+SHEET.dgn,Design Model;5,SHE-13.STEEL.dgn,Design Model:105308 | BS UC | UC203X203X46 | 1\BS UC\UC203X203X46 | 2.546 | 0.00587 | 0.005784 | 3.07149 | 3.08306 | 0 | 0.014945 | 0.014726 | 0.014945 | 0.014726 | 46.100000 | 117.370600 | 117.318407 | 115.596405 | 117.318407 | 115.596405
A-Beams-Steel | RL | 1 ,SHE_DRAWING+SHEET.dgn,Design Model;5,SHE-13.STEEL.dgn,Design Model:105310 | BS UC | UC203X203X46 | 1\BS UC\UC203X203X46 | 2.3424 | 0.00587 | 0.005784 | 2.82587 | 2.83744 | 0 | 0.01375 | 0.013548 | 0.01375 | 0.013548 | 46.100000 | 107.984640 | 107.936621 | 106.352325 | 107.936621 | 106.352325
A-Beams-Steel | RL | 1 ,SHE_DRAWING+SHEET.dgn,Design Model;5,SHE-13.STEEL.dgn,Design Model:105312 | BS UC | UC203X203X46 | 1\BS UC\UC203X203X46 | 1.15342 | 0.00587 | 0.005784 | 1.39149 | 1.40306 | 0 | 0.006771 | 0.006671 | 0.006771 | 0.006671 | 46.100000 | 53.172740 | 53.149095 | 52.368971 | 53.149095 | 52.368971
A-Beams-Steel | RL | 1 ,SHE_DRAWING+SHEET.dgn,Design Model;5,SHE-13.STEEL.dgn,Design Model:105314 | BS UC | UC203X203X46 | 1\BS UC\UC203X203X46 | 1.15342 | 0.00587 | 0.005784 | 1.39149 | 1.40306 | 0 | 0.006771 | 0.006671 | 0.006771 | 0.006671 | 46.100000 | 53.172740 | 53.149095 | 52.368971 | 53.149095 | 52.368971
A-Beams-Steel | RL | 1 ,SHE_DRAWING+SHEET.dgn,Design Model;5,SHE-13.STEEL.dgn,Design Model:105316 | BS UC | UC203X203X46 | 1\BS UC\UC203X203X46 | 2.546 | 0.00587 | 0.005784 | 3.07149 | 3.08306 | 0 | 0.014945 | 0.014726 | 0.014945 | 0.014726 | 46.100000 | 117.370600 | 117.318407 | 115.596405 | 117.318407 | 115.596405
A-Beams-Steel | RL | 1 ,SHE_DRAWING+SHEET.dgn,Design Model;5,SHE-13.STEEL.dgn,Design Model:105318 | BS UC | UC203X203X46 | 1\BS UC\UC203X203X46 | 2.4968 | 0.00587 | 0.005784 | 3.01214 | 3.02371 | 0 | 0.014656 | 0.014441 | 0.014656 | 0.014441 | 46.100000 | 115.102480 | 115.051296 | 113.362570 | 115.051296 | 113.362570
A-Beams-Steel | RL | 1 ,SHE_DRAWING+SHEET.dgn,Design Model;5,SHE-13.STEEL.dgn,Design Model:105320 | BS UC | UC203X203X46 | 1\BS UC\UC203X203X46 | 2.6492 | 0.00587 | 0.005784 | 3.19599 | 3.20756 | 0 | 0.015551 | 0.015323 | 0.015551 | 0.015323 | 46.100000 | 122.128120 | 122.073811 | 120.282009 | 122.073811 | 120.282009
A-Beams-Steel | RL | 1 ,SHE_DRAWING+SHEET.dgn,Design Model;5,SHE-13.STEEL.dgn,Design Model:105322 | BS UC | UC203X203X46 | 1\BS UC\UC203X203X46 | 2.5349 | 0.00587 | 0.005784 | 3.0581 | 3.06967 | 0 | 0.01488 | 0.014661 | 0.01488 | 0.014661 | 46.100000 | 116.858890 | 116.806925 | 115.092430 | 116.806925 | 115.092430
A-Beams-Steel | RL | 1 ,SHE_DRAWING+SHEET.dgn,Design Model;5,SHE-13.STEEL.dgn,Design Model:105324 | BS UC | UC203X203X46 | 1\BS UC\UC203X203X46 | 2.4857 | 0.00587 | 0.005784 | 2.99875 | 3.01032 | 0 | 0.014591 | 0.014377 | 0.014591 | 0.014377 | 46.100000 | 114.590770 | 114.539813 | 112.858595 | 114.539813 | 112.858595
A-Beams-Steel | RL | 1 ,SHE_DRAWING+SHEET.dgn,Design Model;5,SHE-13.STEEL.dgn,Design Model:105326 | BS UC | UC203X203X46 | 1\BS UC\UC203X203X46 | 2.6492 | 0.00587 | 0.005784 | 3.19599 | 3.20756 | 0 | 0.015551 | 0.015323 | 0.015551 | 0.015323 | 46.100000 | 122.128120 | 122.073811 | 120.282009 | 122.073811 | 120.282009
A-Beams-Steel | RL | 1 ,SHE_DRAWING+SHEET.dgn,Design Model;5,SHE-13.STEEL.dgn,Design Model:105328 | BS UC | UC203X203X46 | 1\BS UC\UC203X203X46 | 2.546 | 0.00587 | 0.005784 | 3.07149 | 3.08306 | 0 | 0.014945 | 0.014726 | 0.014945 | 0.014726 | 46.100000 | 117.370600 | 117.318407 | 115.596405 | 117.318407 | 115.596405
A-Beams-Steel | RL | 1 ,SHE_DRAWING+SHEET.dgn,Design Model;5,SHE-13.STEEL.dgn,Design Model:105330 | BS UC | UC203X203X46 | 1\BS UC\UC203X203X46 | 2.495 | 0.00587 | 0.005784 | 3.00997 | 3.02154 | 0 | 0.014646 | 0.014431 | 0.014646 | 0.014431 | 46.100000 | 115.019500 | 114.968353 | 113.280844 | 114.968353 | 113.280844
A-Beams-Steel | RL | 1 ,SHE_DRAWING+SHEET.dgn,Design Model;5,SHE-13.STEEL.dgn,Design Model:105332 | BS UC | UC203X203X46 | 1\BS UC\UC203X203X46 | 2.5474 | 0.00587 | 0.005784 | 3.07318 | 3.08475 | 0 | 0.014953 | 0.014734 | 0.014953 | 0.014734 | 46.100000 | 117.435140 | 117.382918 | 115.659969 | 117.382918 | 115.659969
A-Beams-Steel | RL | 1 ,SHE_DRAWING+SHEET.dgn,Design Model;5,SHE-13.STEEL.dgn,Design Model:105334 | BS UC | UC203X203X46 | 1\BS UC\UC203X203X46 | 2.546 | 0.00587 | 0.005784 | 3.07149 | 3.08306 | 0 | 0.014945 | 0.014726 | 0.014945 | 0.014726 | 46.100000 | 117.370600 | 117.318407 | 115.596405 | 117.318407 | 115.596405
A-Beams-Steel | RL | 1 ,SHE_DRAWING+SHEET.dgn,Design Model;5,SHE-13.STEEL.dgn,Design Model:105336 | BS UC | UC203X203X46 | 1\BS UC\UC203X203X46 | 2.4936 | 0.00587 | 0.005784 | 3.00828 | 3.01985 | 0 | 0.014637 | 0.014423 | 0.014637 | 0.014423 | 46.100000 | 114.954960 | 114.903841 | 113.217280 | 114.903841 | 113.217280
A-Beams-Steel | RL | 1 ,SHE_DRAWING+SHEET.dgn,Design Model;5,SHE-13.STEEL.dgn,Design Model:105338 | BS UC | UC203X203X46 | 1\BS UC\UC203X203X46 | 2.546 | 0.00587 | 0.005784 | 3.07149 | 3.08306 | 0 | 0.014945 | 0.014726 | 0.014945 | 0.014726 | 46.100000 | 117.370600 | 117.318407 | 115.596405 | 117.318407 | 115.596405
A-Beams-Steel | RL | 1 ,SHE_DRAWING+SHEET.dgn,Design Model;5,SHE-13.STEEL.dgn,Design Model:105340 | BS UC | UC203X203X46 | 1\BS UC\UC203X203X46 | 2.3424 | 0.00587 | 0.005784 | 2.82587 | 2.83744 | 0 | 0.01375 | 0.013548 | 0.01375 | 0.013548 | 46.100000 | 107.984640 | 107.936621 | 106.352325 | 107.936621 | 106.352325
A-Beams-Steel | RL | 1 ,SHE_DRAWING+SHEET.dgn,Design Model;5,SHE-13.STEEL.dgn,Design Model:105342 | BS UC | UC203X203X46 | 1\BS UC\UC203X203X46 | 2.4936 | 0.00587 | 0.005784 | 3.00828 | 3.01985 | 0 | 0.014637 | 0.014423 | 0.014637 | 0.014423 | 46.100000 | 114.954960 | 114.903841 | 113.217280 | 114.903841 | 113.217280
A-Beams-Steel | RL | 1 ,SHE_DRAWING+SHEET.dgn,Design Model;5,SHE-13.STEEL.dgn,Design Model:105344 | BS UC | UC203X203X46 | 1\BS UC\UC203X203X46 | 2.3424 | 0.00587 | 0.005784 | 2.82587 | 2.83744 | 0 | 0.01375 | 0.013548 | 0.01375 | 0.013548 | 46.100000 | 107.984640 | 107.936621 | 106.352325 | 107.936621 | 106.352325
A-Beams-Steel | RL | 1 ,SHE_DRAWING+SHEET.dgn,Design Model;5,SHE-13.STEEL.dgn,Design Model:105346 | BS UC | UC203X203X46 | 1\BS UC\UC203X203X46 | 1.13364 | 0.00587 | 0.005784 | 1.36762 | 1.37919 | 0 | 0.006654 | 0.006557 | 0.006654 | 0.006557 | 46.100000 | 52.260631 | 52.237392 | 51.470650 | 52.237392 | 51.470650
A-Beams-Steel | RL | 1 ,SHE_DRAWING+SHEET.dgn,Design Model;5,SHE-13.STEEL.dgn,Design Model:105348 | BS UC | UC203X203X46 | 1\BS UC\UC203X203X46 | 1.13364 | 0.00587 | 0.005784 | 1.36762 | 1.37919 | 0 | 0.006654 | 0.006557 | 0.006654 | 0.006557 | 46.100000 | 52.260631 | 52.237392 | 51.470650 | 52.237392 | 51.470650
A-Beams-Steel | RL | 1 ,SHE_DRAWING+SHEET.dgn,Design Model;5,SHE-13.STEEL.dgn,Design Model:105350 | BS UC | UC203X203X46 | 1\BS UC\UC203X203X46 | 2.0364 | 0.00587 | 0.005784 | 2.45671 | 2.46828 | 0 | 0.011954 | 0.011778 | 0.011954 | 0.011778 | 46.100000 | 93.878040 | 93.836294 | 92.458962 | 93.836294 | 92.458962
A-Beams-Steel | RL | 1 ,SHE_DRAWING+SHEET.dgn,Design Model;5,SHE-13.STEEL.dgn,Design Model:105352 | BS UC | UC203X203X46 | 1\BS UC\UC203X203X46 | 1.9664 | 0.00587 | 0.005784 | 2.37227 | 2.38383 | 0 | 0.011543 | 0.011373 | 0.011543 | 0.011373 | 46.100000 | 90.651040 | 90.610729 | 89.280742 | 90.610729 | 89.280742
A-Beams-Steel | RL | 1 ,SHE_DRAWING+SHEET.dgn,Design Model;5,SHE-13.STEEL.dgn,Design Model:105354 | BS UC | UC203X203X46 | 1\BS UC\UC203X203X46 | 1.9597 | 0.00587 | 0.005784 | 2.36418 | 2.37575 | 0 | 0.011503 | 0.011335 | 0.011503 | 0.011335 | 46.100000 | 90.342170 | 90.301996 | 88.976541 | 90.301996 | 88.976541
A-Beams-Steel | RL | 1 ,SHE_DRAWING+SHEET.dgn,Design Model;5,SHE-13.STEEL.dgn,Design Model:105356 | BS UC | UC203X203X46 | 1\BS UC\UC203X203X46 | 2.4839 | 0.00587 | 0.005784 | 2.99658 | 3.00814 | 0 | 0.01458 | 0.014366 | 0.01458 | 0.014366 | 46.100000 | 114.507790 | 114.456870 | 112.776869 | 114.456870 | 112.776869
A-Beams-Steel | RL | 1 ,SHE_DRAWING+SHEET.dgn,Design Model;5,SHE-13.STEEL.dgn,Design Model:105358 | BS UC | UC203X203X46 | 1\BS UC\UC203X203X46 | 2.0297 | 0.00587 | 0.005784 | 2.44863 | 2.4602 | 0 | 0.011914 | 0.011739 | 0.011914 | 0.011739 | 46.100000 | 93.569170 | 93.527561 | 92.154761 | 93.527561 | 92.154761
A-Beams-Steel | RL | 1 ,SHE_DRAWING+SHEET.dgn,Design Model;5,SHE-13.STEEL.dgn,Design Model:105360 | BS UC | UC203X203X46 | 1\BS UC\UC203X203X46 | 0.6964 | 0.00587 | 0.005784 | 0.840137 | 0.851705 | 0 | 0.004088 | 0.004028 | 0.004088 | 0.004028 | 46.100000 | 32.104040 | 32.089764 | 31.618749 | 32.089764 | 31.618749
A-Beams-Steel | RL | 1 ,SHE_DRAWING+SHEET.dgn,Design Model;5,SHE-13.STEEL.dgn,Design Model:105362 | BS UC | UC203X203X46 | 1\BS UC\UC203X203X46 | 2.229 | 0.00587 | 0.005784 | 2.68907 | 2.70063 | 0 | 0.013084 | 0.012892 | 0.013084 | 0.012892 | 46.100000 | 102.756900 | 102.711206 | 101.203608 | 102.711206 | 101.203608
A-Beams-Steel | RL | 1 ,SHE_DRAWING+SHEET.dgn,Design Model;5,SHE-13.STEEL.dgn,Design Model:105364 | BS UC | UC203X203X46 | 1\BS UC\UC203X203X46 | 4.25305 | 0.00587 | 0.005784 | 5.13088 | 5.14245 | 0 | 0.024965 | 0.024599 | 0.024965 | 0.024599 | 46.100000 | 196.065605 | 195.978417 | 193.101842 | 195.978417 | 193.101842
A-Beams-Steel | RL | 1 ,SHE_DRAWING+SHEET.dgn,Design Model;5,SHE-13.STEEL.dgn,Design Model:105366 | BS UC | UC203X203X46 | 1\BS UC\UC203X203X46 | 4.2564 | 0.00587 | 0.005784 | 5.13492 | 5.14649 | 0 | 0.024985 | 0.024618 | 0.024985 | 0.024618 | 46.100000 | 196.220040 | 196.132784 | 193.253942 | 196.132784 | 193.253942
A-Beams-Steel | RL | 1 ,SHE_DRAWING+SHEET.dgn,Design Model;5,SHE-13.STEEL.dgn,Design Model:105368 | BS UC | UC203X203X46 | 1\BS UC\UC203X203X46 | 4.2582 | 0.00587 | 0.005784 | 5.13709 | 5.14866 | 0 | 0.024996 | 0.024629 | 0.024996 | 0.024629 | 46.100000 | 196.303020 | 196.215727 | 193.335668 | 196.215727 | 193.335668
A-Beams-Steel | RL | 1 ,SHE_DRAWING+SHEET.dgn,Design Model;5,SHE-13.STEEL.dgn,Design Model:105370 | BS UC | UC203X203X46 | 1\BS UC\UC203X203X46 | 4.2082 | 0.00587 | 0.005784 | 5.07677 | 5.08834 | 0 | 0.024702 | 0.02434 | 0.024702 | 0.02434 | 46.100000 | 193.998020 | 193.911752 | 191.065511 | 193.911752 | 191.065511
A-Beams-Steel | RL | 1 ,SHE_DRAWING+SHEET.dgn,Design Model;5,SHE-13.STEEL.dgn,Design Model:105373 | BS UC | UC203X203X71 | 1\BS UC\UC203X203X71 | 5.53365 | 0.00904 | 0.008953 | 6.84623 | 6.86414 | 0 | 0.050024 | 0.049545 | 0.050024 | 0.049545 | 71.000000 | 392.889150 | 392.689939 | 388.929846 | 392.689939 | 388.929846
A-Beams-Steel | RL | 1 ,SHE_DRAWING+SHEET.dgn,Design Model;5,SHE-13.STEEL.dgn,Design Model:105375 | BS UC | UC203X203X71 | 1\BS UC\UC203X203X71 | 5.537 | 0.00904 | 0.008953 | 6.85038 | 6.86828 | 0 | 0.050054 | 0.049575 | 0.050054 | 0.049575 | 71.000000 | 393.127000 | 392.927668 | 389.165299 | 392.927668 | 389.165299
A-Beams-Steel | RL | 1 ,SHE_DRAWING+SHEET.dgn,Design Model;5,SHE-13.STEEL.dgn,Design Model:105377 | BS UC | UC203X203X71 | 1\BS UC\UC203X203X71 | 5.4672 | 0.00904 | 0.008953 | 6.76402 | 6.78193 | 0 | 0.049424 | 0.04895 | 0.049424 | 0.04895 | 71.000000 | 388.171352 | 387.974533 | 384.259591 | 387.974533 | 384.259591
A-Beams-Steel | RL | 1 ,SHE_DRAWING+SHEET.dgn,Design Model;5,SHE-13.STEEL.dgn,Design Model:105379 | BS UC | UC203X203X71 | 1\BS UC\UC203X203X71 | 5.4672 | 0.00904 | 0.008953 | 6.76402 | 6.78193 | 0 | 0.049424 | 0.04895 | 0.049424 | 0.04895 | 71.000000 | 388.171352 | 387.974533 | 384.259591 | 387.974533 | 384.259591
A-Beams-Steel | RL | 1 ,SHE_DRAWING+SHEET.dgn,Design Model;5,SHE-13.STEEL.dgn,Design Model:105381 | BS UC | UC305X305X240 | 1\BS UC\UC305X305X240 | 4.2564 | 0.0306 | 0.030381 | 8.22592 | 8.28668 | 0 | 0.130246 | 0.129312 | 0.130246 | 0.129312 | 240.000000 | 1021.536000 | 1022.429844 | 1015.101094 | 1022.429844 | 1015.101094
A-Beams-Steel | RL | 1 ,SHE_DRAWING+SHEET.dgn,Design Model;5,SHE-13.STEEL.dgn,Design Model:105383 | BS UC | UC305X305X240 | 1\BS UC\UC305X305X240 | 3.97638 | 0.0306 | 0.030381 | 7.68475 | 7.74551 | 0 | 0.121677 | 0.120805 | 0.121677 | 0.120805 | 240.000000 | 954.330796 | 955.165835 | 948.319231 | 955.165835 | 948.319231
A-Beams-Steel | RL | 1 ,SHE_DRAWING+SHEET.dgn,Design Model;5,SHE-13.STEEL.dgn,Design Model:105385 | BS UC | UC305X305X240 | 1\BS UC\UC305X305X240 | 4.2064 | 0.0306 | 0.030381 | 8.12929 | 8.19005 | 0 | 0.128716 | 0.127793 | 0.128716 | 0.127793 | 240.000000 | 1009.536000 | 1010.419344 | 1003.176685 | 1010.419344 | 1003.176685
A-Beams-Steel | RL | 1 ,SHE_DRAWING+SHEET.dgn,Design Model;5,SHE-13.STEEL.dgn,Design Model:105387 | BS UC | UC305X305X240 | 1\BS UC\UC305X305X240 | 3.92637 | 0.0306 | 0.030381 | 7.5881 | 7.64886 | 0 | 0.120147 | 0.119286 | 0.120147 | 0.119286 | 240.000000 | 942.327813 | 943.152349 | 936.391858 | 943.152349 | 936.391858
A-Beams-Steel | RL | 1 ,SHE_DRAWING+SHEET.dgn,Design Model;5,SHE-13.STEEL.dgn,Design Model:105389 | BS UC | UC203X203X46 | 1\BS UC\UC203X203X46 | 2.4348 | 0.00587 | 0.005784 | 2.93734 | 2.94891 | 0 | 0.014292 | 0.014082 | 0.014292 | 0.014082 | 46.100000 | 112.244283 | 112.194370 | 110.547578 | 112.194370 | 110.547578
A-Beams-Steel | RL | 1 ,SHE_DRAWING+SHEET.dgn,Design Model;5,SHE-13.STEEL.dgn,Design Model:105391 | BS UC | UC203X203X46 | 1\BS UC\UC203X203X46 | 3.5036 | 0.00587 | 0.005784 | 4.22674 | 4.23831 | 0 | 0.020566 | 0.020264 | 0.020566 | 0.020264 | 46.100000 | 161.515960 | 161.444136 | 159.074455 | 161.444136 | 159.074455
A-Beams-Steel | RL | 1 ,SHE_DRAWING+SHEET.dgn,Design Model;5,SHE-13.STEEL.dgn,Design Model:105393 | BS UC | UC203X203X46 | 1\BS UC\UC203X203X46 | 8.3836 | 0.00587 | 0.005784 | 10.114 | 10.1255 | 0 | 0.049212 | 0.048489 | 0.049212 | 0.048489 | 46.100000 | 386.483960 | 386.312096 | 380.641798 | 386.312096 | 380.641798
A-Beams-Steel | RL | 1 ,SHE_DRAWING+SHEET.dgn,Design Model;5,SHE-13.STEEL.dgn,Design Model:105395 | BS UC | UC203X203X46 | 1\BS UC\UC203X203X46 | 8.3936 | 0.00587 | 0.005784 | 10.126 | 10.1376 | 0 | 0.04927 | 0.048547 | 0.04927 | 0.048547 | 46.100000 | 386.944960 | 386.772891 | 381.095829 | 386.772891 | 381.095829
A-Beams-Steel | RL | 1 ,SHE_DRAWING+SHEET.dgn,Design Model;5,SHE-13.STEEL.dgn,Design Model:105397 | BS UC | UC203X203X46 | 1\BS UC\UC203X203X46 | 3.4636 | 0.00587 | 0.005784 | 4.17849 | 4.19006 | 0 | 0.020331 | 0.020033 | 0.020331 | 0.020033 | 46.100000 | 159.671960 | 159.600956 | 157.258330 | 159.600956 | 157.258330
A-Beams-Steel | RL | 1 ,SHE_DRAWING+SHEET.dgn,Design Model;5,SHE-13.STEEL.dgn,Design Model:105399 | BS UC | UC203X203X71 | 1\BS UC\UC203X203X71 | 4.66557 | 0.00904 | 0.008953 | 5.77225 | 5.79015 | 0 | 0.042177 | 0.041773 | 0.042177 | 0.041773 | 71.000000 | 331.255712 | 331.087752 | 327.917513 | 331.087752 | 327.917513
A-Beams-Steel | RL | 1 ,SHE_DRAWING+SHEET.dgn,Design Model;5,SHE-13.STEEL.dgn,Design Model:105401 | BS UC | UC203X203X71 | 1\BS UC\UC203X203X71 | 4.66557 | 0.00904 | 0.008953 | 5.77225 | 5.79015 | 0 | 0.042177 | 0.041773 | 0.042177 | 0.041773 | 71.000000 | 331.255712 | 331.087752 | 327.917513 | 331.087752 | 327.917513
A-Beams-Steel | RL | 1 ,SHE_DRAWING+SHEET.dgn,Design Model;5,SHE-13.STEEL.dgn,Design Model:105403 | BS UC | UC203X203X71 | 1\BS UC\UC203X203X71 | 4.6839 | 0.00904 | 0.008953 | 5.79492 | 5.81283 | 0 | 0.042342 | 0.041937 | 0.042342 | 0.041937 | 71.000000 | 332.556900 | 332.388280 | 329.205588 | 332.388280 | 329.205588
A-Beams-Steel | RL | 1 ,SHE_DRAWING+SHEET.dgn,Design Model;5,SHE-13.STEEL.dgn,Design Model:105405 | BS UC | UC203X203X71 | 1\BS UC\UC203X203X71 | 4.6839 | 0.00904 | 0.008953 | 5.79492 | 5.81283 | 0 | 0.042342 | 0.041937 | 0.042342 | 0.041937 | 71.000000 | 332.556900 | 332.388280 | 329.205588 | 332.388280 | 329.205588
A-Beams-Steel | RL | 1 ,SHE_DRAWING+SHEET.dgn,Design Model;5,SHE-13.STEEL.dgn,Design Model:105407 | BS UC | UC203X203X71 | 1\BS UC\UC203X203X71 | 4.7232 | 0.00904 | 0.008953 | 5.84354 | 5.86145 | 0 | 0.042698 | 0.042289 | 0.042698 | 0.042289 | 71.000000 | 335.347200 | 335.177165 | 331.967769 | 335.177165 | 331.967769
A-Beams-Steel | RL | 1 ,SHE_DRAWING+SHEET.dgn,Design Model;5,SHE-13.STEEL.dgn,Design Model:105409 | BS UC | UC203X203X71 | 1\BS UC\UC203X203X71 | 4.66557 | 0.00904 | 0.008953 | 5.77225 | 5.79015 | 0 | 0.042177 | 0.041773 | 0.042177 | 0.041773 | 71.000000 | 331.255712 | 331.087752 | 327.917513 | 331.087752 | 327.917513
A-Beams-Steel | RL | 1 ,SHE_DRAWING+SHEET.dgn,Design Model;5,SHE-13.STEEL.dgn,Design Model:105411 | BS UC | UC203X203X71 | 1\BS UC\UC203X203X71 | 4.66557 | 0.00904 | 0.008953 | 5.77225 | 5.79015 | 0 | 0.042177 | 0.041773 | 0.042177 | 0.041773 | 71.000000 | 331.255712 | 331.087752 | 327.917513 | 331.087752 | 327.917513
A-Beams-Steel | RL | 1 ,SHE_DRAWING+SHEET.dgn,Design Model;5,SHE-13.STEEL.dgn,Design Model:105413 | BS UC | UC203X203X46 | 1\BS UC\UC203X203X46 | 3.5036 | 0.00587 | 0.005784 | 4.22674 | 4.23831 | 0 | 0.020566 | 0.020264 | 0.020566 | 0.020264 | 46.100000 | 161.515960 | 161.444136 | 159.074455 | 161.444136 | 159.074455
A-Beams-Steel | RL | 1 ,SHE_DRAWING+SHEET.dgn,Design Model;5,SHE-13.STEEL.dgn,Design Model:105415 | BS UC | UC203X203X46 | 1\BS UC\UC203X203X46 | 8.3836 | 0.00587 | 0.005784 | 10.114 | 10.1255 | 0 | 0.049212 | 0.048489 | 0.049212 | 0.048489 | 46.100000 | 386.483960 | 386.312096 | 380.641798 | 386.312096 | 380.641798
A-Beams-Steel | RL | 1 ,SHE_DRAWING+SHEET.dgn,Design Model;5,SHE-13.STEEL.dgn,Design Model:105417 | BS UC | UC203X203X46 | 1\BS UC\UC203X203X46 | 8.3936 | 0.00587 | 0.005784 | 10.126 | 10.1376 | 0 | 0.04927 | 0.048547 | 0.04927 | 0.048547 | 46.100000 | 386.944960 | 386.772891 | 381.095829 | 386.772891 | 381.095829
A-Beams-Steel | RL | 1 ,SHE_DRAWING+SHEET.dgn,Design Model;5,SHE-13.STEEL.dgn,Design Model:105419 | BS UC | UC203X203X46 | 1\BS UC\UC203X203X46 | 3.4636 | 0.00587 | 0.005784 | 4.17849 | 4.19006 | 0 | 0.020331 | 0.020033 | 0.020331 | 0.020033 | 46.100000 | 159.671960 | 159.600956 | 157.258330 | 159.600956 | 157.258330
A-Beams-Steel | RL | 1 ,SHE_DRAWING+SHEET.dgn,Design Model;5,SHE-13.STEEL.dgn,Design Model:105421 | BS UC | UC203X203X71 | 1\BS UC\UC203X203X71 | 4.66557 | 0.00904 | 0.008953 | 5.77225 | 5.79015 | 0 | 0.042177 | 0.041773 | 0.042177 | 0.041773 | 71.000000 | 331.255712 | 331.087752 | 327.917513 | 331.087752 | 327.917513
A-Beams-Steel | RL | 1 ,SHE_DRAWING+SHEET.dgn,Design Model;5,SHE-13.STEEL.dgn,Design Model:105423 | BS UC | UC203X203X71 | 1\BS UC\UC203X203X71 | 4.66557 | 0.00904 | 0.008953 | 5.77225 | 5.79015 | 0 | 0.042177 | 0.041773 | 0.042177 | 0.041773 | 71.000000 | 331.255712 | 331.087752 | 327.917513 | 331.087752 | 327.917513
A-Beams-Steel | RL | 1 ,SHE_DRAWING+SHEET.dgn,Design Model;5,SHE-13.STEEL.dgn,Design Model:105425 | BS UC | UC203X203X71 | 1\BS UC\UC203X203X71 | 4.7982 | 0.00904 | 0.008953 | 5.93633 | 5.95424 | 0 | 0.043376 | 0.04296 | 0.043376 | 0.04296 | 71.000000 | 340.672200 | 340.499465 | 337.239107 | 340.499465 | 337.239107
A-Beams-Steel | RL | 1 ,SHE_DRAWING+SHEET.dgn,Design Model;5,SHE-13.STEEL.dgn,Design Model:105427 | BS UC | UC203X203X71 | 1\BS UC\UC203X203X71 | 4.7982 | 0.00904 | 0.008953 | 5.93633 | 5.95424 | 0 | 0.043376 | 0.04296 | 0.043376 | 0.04296 | 71.000000 | 340.672200 | 340.499465 | 337.239107 | 340.499465 | 337.239107
A-Beams-Steel | RL | 1 ,SHE_DRAWING+SHEET.dgn,Design Model;5,SHE-13.STEEL.dgn,Design Model:105429 | BS UC | UC203X203X71 | 1\BS UC\UC203X203X71 | 4.7982 | 0.00904 | 0.008953 | 5.93633 | 5.95424 | 0 | 0.043376 | 0.04296 | 0.043376 | 0.04296 | 71.000000 | 340.672200 | 340.499465 | 337.239107 | 340.499465 | 337.239107
A-Beams-Steel | RL | 1 ,SHE_DRAWING+SHEET.dgn,Design Model;5,SHE-13.STEEL.dgn,Design Model:105431 | BS UC | UC203X203X71 | 1\BS UC\UC203X203X71 | 4.66557 | 0.00904 | 0.008953 | 5.77225 | 5.79015 | 0 | 0.042177 | 0.041773 | 0.042177 | 0.041773 | 71.000000 | 331.255712 | 331.087752 | 327.917513 | 331.087752 | 327.917513
A-Beams-Steel | RL | 1 ,SHE_DRAWING+SHEET.dgn,Design Model;5,SHE-13.STEEL.dgn,Design Model:105433 | BS UC | UC203X203X71 | 1\BS UC\UC203X203X71 | 4.66557 | 0.00904 | 0.008953 | 5.77225 | 5.79015 | 0 | 0.042177 | 0.041773 | 0.042177 | 0.041773 | 71.000000 | 331.255712 | 331.087752 | 327.917513 | 331.087752 | 327.917513
A-Beams-Steel | RL | 1 ,SHE_DRAWING+SHEET.dgn,Design Model;5,SHE-13.STEEL.dgn,Design Model:105435 | BS UC | UC203X203X46 | 1\BS UC\UC203X203X46 | 1.06349 | 0.00587 | 0.005784 | 1.283 | 1.29456 | 0 | 0.006243 | 0.006151 | 0.006243 | 0.006151 | 46.100000 | 49.027000 | 49.005198 | 48.285899 | 49.005198 | 48.285899
A-Beams-Steel | RL | 1 ,SHE_DRAWING+SHEET.dgn,Design Model;5,SHE-13.STEEL.dgn,Design Model:105437 | BS UC | UC203X203X46 | 1\BS UC\UC203X203X46 | 1.06349 | 0.00587 | 0.005784 | 1.283 | 1.29456 | 0 | 0.006243 | 0.006151 | 0.006243 | 0.006151 | 46.100000 | 49.027000 | 49.005198 | 48.285899 | 49.005198 | 48.285899
A-Beams-Steel | RL | 1 ,SHE_DRAWING+SHEET.dgn,Design Model;5,SHE-13.STEEL.dgn,Design Model:105439 | BS UC | UC203X203X46 | 1\BS UC\UC203X203X46 | 1.06349 | 0.00587 | 0.005784 | 1.283 | 1.29456 | 0 | 0.006243 | 0.006151 | 0.006243 | 0.006151 | 46.100000 | 49.027000 | 49.005198 | 48.285899 | 49.005198 | 48.285899
A-Beams-Steel | RL | 1 ,SHE_DRAWING+SHEET.dgn,Design Model;5,SHE-13.STEEL.dgn,Design Model:105441 | BS UC | UC203X203X46 | 1\BS UC\UC203X203X46 | 1.06349 | 0.00587 | 0.005784 | 1.283 | 1.29456 | 0 | 0.006243 | 0.006151 | 0.006243 | 0.006151 | 46.100000 | 49.027000 | 49.005198 | 48.285899 | 49.005198 | 48.285899
A-Beams-Steel | RL | 1 ,SHE_DRAWING+SHEET.dgn,Design Model;5,SHE-13.STEEL.dgn,Design Model:105443 | BS UC | UC203X203X46 | 1\BS UC\UC203X203X46 | 2.4857 | 0.00587 | 0.005784 | 2.99875 | 3.01032 | 0 | 0.014591 | 0.014377 | 0.014591 | 0.014377 | 46.100000 | 114.590770 | 114.539813 | 112.858595 | 114.539813 | 112.858595
A-Beams-Steel | RL | 1 ,SHE_DRAWING+SHEET.dgn,Design Model;5,SHE-13.STEEL.dgn,Design Model:105445 | BS UC | UC203X203X46 | 1\BS UC\UC203X203X46 | 2.4839 | 0.00587 | 0.005784 | 2.99658 | 3.00815 | 0 | 0.01458 | 0.014366 | 0.01458 | 0.014366 | 46.100000 | 114.507833 | 114.456913 | 112.776911 | 114.456913 | 112.776911
A-Beams-Steel | RL | 1 ,SHE_DRAWING+SHEET.dgn,Design Model;5,SHE-13.STEEL.dgn,Design Model:105447 | BS UC | UC203X203X46 | 1\BS UC\UC203X203X46 | 2.4857 | 0.00587 | 0.005784 | 2.99875 | 3.01032 | 0 | 0.014591 | 0.014377 | 0.014591 | 0.014377 | 46.100000 | 114.590770 | 114.539813 | 112.858595 | 114.539813 | 112.858595
A-Beams-Steel | RL | 1 ,SHE_DRAWING+SHEET.dgn,Design Model;5,SHE-13.STEEL.dgn,Design Model:105449 | BS UC | UC203X203X46 | 1\BS UC\UC203X203X46 | 2.525 | 0.00587 | 0.005784 | 3.04616 | 3.05773 | 0 | 0.014822 | 0.014604 | 0.014822 | 0.014604 | 46.100000 | 116.402500 | 116.350737 | 114.642939 | 116.350737 | 114.642939
A-Beams-Steel | RL | 1 ,SHE_DRAWING+SHEET.dgn,Design Model;5,SHE-13.STEEL.dgn,Design Model:105451 | BS UC | UC203X203X46 | 1\BS UC\UC203X203X46 | 1.08642 | 0.00587 | 0.005784 | 1.31065 | 1.32222 | 0 | 0.006377 | 0.006284 | 0.006377 | 0.006284 | 46.100000 | 50.083858 | 50.061587 | 49.326781 | 50.061587 | 49.326781
A-Beams-Steel | RL | 1 ,SHE_DRAWING+SHEET.dgn,Design Model;5,SHE-13.STEEL.dgn,Design Model:105453 | BS UC | UC203X203X46 | 1\BS UC\UC203X203X46 | 1.08642 | 0.00587 | 0.005784 | 1.31065 | 1.32222 | 0 | 0.006377 | 0.006284 | 0.006377 | 0.006284 | 46.100000 | 50.083858 | 50.061587 | 49.326781 | 50.061587 | 49.326781
A-Beams-Steel | RL | 1 ,SHE_DRAWING+SHEET.dgn,Design Model;5,SHE-13.STEEL.dgn,Design Model:105455 | BS UC | UC203X203X46 | 1\BS UC\UC203X203X46 | 2.43448 | 0.00587 | 0.005784 | 2.93696 | 2.94853 | 0 | 0.01429 | 0.014081 | 0.01429 | 0.014081 | 46.100000 | 112.229692 | 112.179785 | 110.533208 | 112.179785 | 110.533208
A-Beams-Steel | RL | 1 ,SHE_DRAWING+SHEET.dgn,Design Model;5,SHE-13.STEEL.dgn,Design Model:105457 | BS UC | UC203X203X46 | 1\BS UC\UC203X203X46 | 2.53639 | 0.00587 | 0.005784 | 3.0599 | 3.07147 | 0 | 0.014889 | 0.01467 | 0.014889 | 0.01467 | 46.100000 | 116.927702 | 116.875705 | 115.160201 | 116.875705 | 115.160201
A-Beams-Steel | RL | 1 ,SHE_DRAWING+SHEET.dgn,Design Model;5,SHE-13.STEEL.dgn,Design Model:105459 | BS UC | UC203X203X46 | 1\BS UC\UC203X203X46 | 0.695 | 0.00587 | 0.005784 | 0.838448 | 0.850016 | 0 | 0.00408 | 0.00402 | 0.00408 | 0.00402 | 46.100000 | 32.039500 | 32.025252 | 31.555185 | 32.025252 | 31.555185
A-Beams-Steel | RL | 1 ,SHE_DRAWING+SHEET.dgn,Design Model;5,SHE-13.STEEL.dgn,Design Model:105461 | BS UC | UC203X203X46 | 1\BS UC\UC203X203X46 | 0.695 | 0.00587 | 0.005784 | 0.838448 | 0.850016 | 0 | 0.00408 | 0.00402 | 0.00408 | 0.00402 | 46.100000 | 32.039500 | 32.025252 | 31.555185 | 32.025252 | 31.555185
A-Beams-Steel | RL | 1 ,SHE_DRAWING+SHEET.dgn,Design Model;5,SHE-13.STEEL.dgn,Design Model:105463 | BS UC | UC203X203X46 | 1\BS UC\UC203X203X46 | 1.9682 | 0.00587 | 0.005784 | 2.37444 | 2.386 | 0 | 0.011553 | 0.011384 | 0.011553 | 0.011384 | 46.100000 | 90.734020 | 90.693672 | 89.362468 | 90.693672 | 89.362468
A-Beams-Steel | RL | 1 ,SHE_DRAWING+SHEET.dgn,Design Model;5,SHE-13.STEEL.dgn,Design Model:105465 | BS UC | UC203X203X46 | 1\BS UC\UC203X203X46 | 1.86305 | 0.00587 | 0.005784 | 2.24758 | 2.25915 | 0 | 0.010936 | 0.010776 | 0.010936 | 0.010776 | 46.100000 | 85.886605 | 85.848412 | 84.588327 | 85.848412 | 84.588327
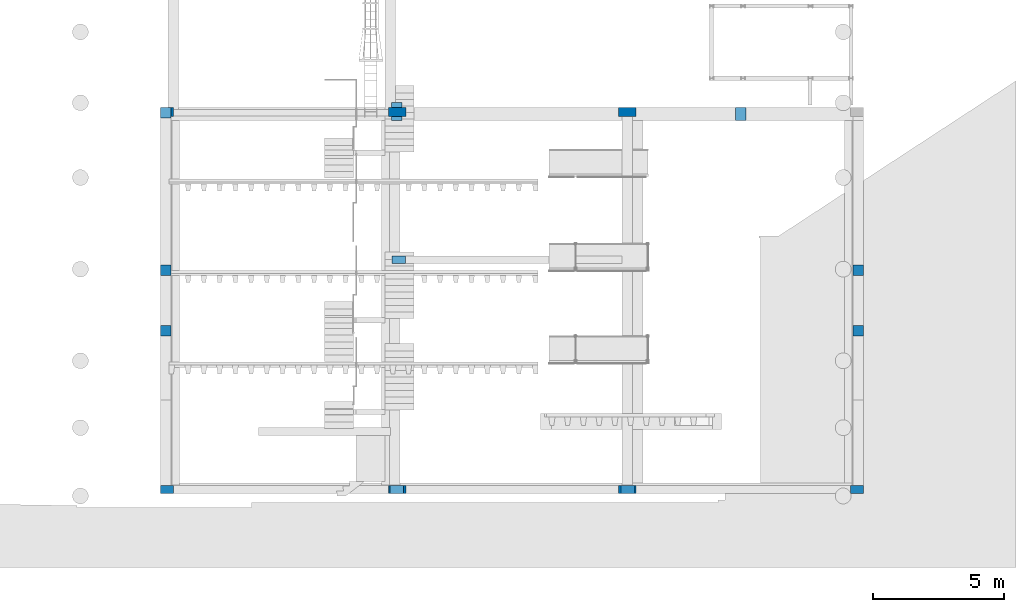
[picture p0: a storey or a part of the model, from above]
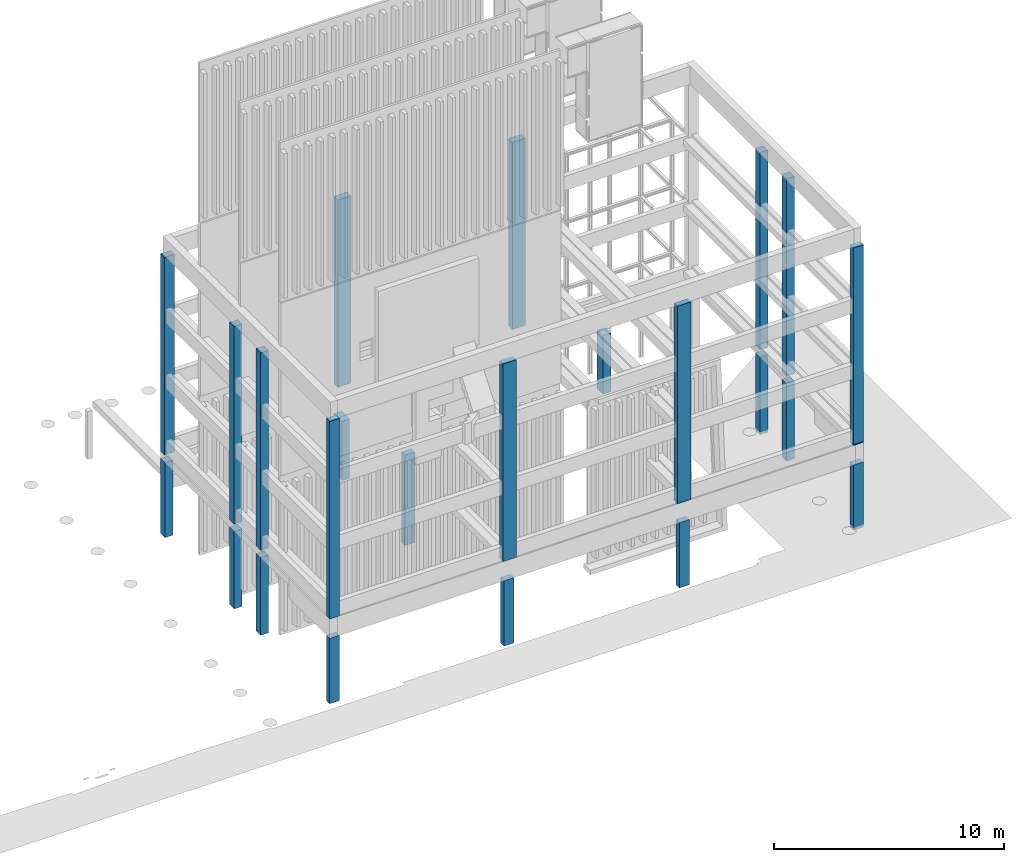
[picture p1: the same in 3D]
Properties of the parts of a building model (IFC2X3), part 2 of 16

# IfcBeam: A-Beams-Steel (168)
Name | In | Description | CodeSystem | Name = StructuralFramingCommon, Section Name | Structural Parameters, Section Name | Length (m) | Area | Cross-sectional (m2) | Area | Cross-sectional Modeled (m2) | Area | Side Surfaces Modeled (Gross) (m2) | Area | All Surfaces Modeled (Net) (m2) | Volume | Perforation(s) (m3) | Volume (Gross) (m3) | Volume (Gross Modeled) (m3) | Volume (Net) (m3) | Volume (Net Modeled) (m3) | Unit Weight | Length x Unit Weight | Volume (Gross) x Density | Volume (Gross Modeled) x Density | Volume (Net) x Density | Volume (Net Modeled) x Density
A-Beams-Steel | RL | 1 ,SHE_DRAWING+SHEET.dgn,Design Model;5,SHE-13.STEEL.dgn,Design Model:105467 | BS UC | UC203X203X46 | 1\BS UC\UC203X203X46 | 2.1297 | 0.00587 | 0.005784 | 2.56927 | 2.58084 | 0 | 0.012501 | 0.012318 | 0.012501 | 0.012318 | 46.100000 | 98.179170 | 98.135511 | 96.695076 | 98.135511 | 96.695076
A-Beams-Steel | RL | 1 ,SHE_DRAWING+SHEET.dgn,Design Model;5,SHE-13.STEEL.dgn,Design Model:105469 | BS UC | UC203X203X46 | 1\BS UC\UC203X203X46 | 4.27985 | 0.00587 | 0.005784 | 5.16321 | 5.17478 | 0 | 0.025123 | 0.024754 | 0.025123 | 0.024754 | 46.100000 | 197.301085 | 197.213348 | 194.318646 | 197.213348 | 194.318646
A-Beams-Steel | RL | 1 ,SHE_DRAWING+SHEET.dgn,Design Model;5,SHE-13.STEEL.dgn,Design Model:105471 | BS UC | UC203X203X46 | 1\BS UC\UC203X203X46 | 4.26 | 0.00587 | 0.005784 | 5.13926 | 5.15083 | 0 | 0.025006 | 0.024639 | 0.025006 | 0.024639 | 46.100000 | 196.386000 | 196.298670 | 193.417393 | 196.298670 | 193.417393
A-Beams-Steel | RL | 1 ,SHE_DRAWING+SHEET.dgn,Design Model;5,SHE-13.STEEL.dgn,Design Model:105473 | BS UC | UC203X203X46 | 1\BS UC\UC203X203X46 | 2.13899 | 0.00587 | 0.005784 | 2.58047 | 2.59204 | 0 | 0.012556 | 0.012372 | 0.012556 | 0.012372 | 46.100000 | 98.607302 | 98.563452 | 97.116736 | 98.563452 | 97.116736
A-Beams-Steel | RL | 1 ,SHE_DRAWING+SHEET.dgn,Design Model;5,SHE-13.STEEL.dgn,Design Model:105475 | BS UC | UC203X203X46 | 1\BS UC\UC203X203X46 | 1.865 | 0.00587 | 0.005784 | 2.24994 | 2.2615 | 0 | 0.010948 | 0.010787 | 0.010948 | 0.010787 | 46.100000 | 85.976500 | 85.938268 | 84.676864 | 85.938268 | 84.676864
A-Beams-Steel | RL | 1 ,SHE_DRAWING+SHEET.dgn,Design Model;5,SHE-13.STEEL.dgn,Design Model:105477 | BS UC | UC203X203X46 | 1\BS UC\UC203X203X46 | 4.2536 | 0.00587 | 0.005784 | 5.13154 | 5.14311 | 0 | 0.024969 | 0.024602 | 0.024969 | 0.024602 | 46.100000 | 196.090960 | 196.003761 | 193.126813 | 196.003761 | 193.126813
A-Beams-Steel | RL | 1 ,SHE_DRAWING+SHEET.dgn,Design Model;5,SHE-13.STEEL.dgn,Design Model:105479 | BS UC | UC203X203X46 | 1\BS UC\UC203X203X46 | 3.9336 | 0.00587 | 0.005784 | 4.7455 | 4.75706 | 0 | 0.02309 | 0.022751 | 0.02309 | 0.022751 | 46.100000 | 181.338960 | 181.258321 | 178.597807 | 181.258321 | 178.597807
A-Beams-Steel | RL | 1 ,SHE_DRAWING+SHEET.dgn,Design Model;5,SHE-13.STEEL.dgn,Design Model:105481 | BS UC | UC203X203X46 | 1\BS UC\UC203X203X46 | 4.20358 | 0.00587 | 0.005784 | 5.07119 | 5.08276 | 0 | 0.024675 | 0.024313 | 0.024675 | 0.024313 | 46.100000 | 193.784852 | 193.698678 | 190.855564 | 193.698678 | 190.855564
A-Beams-Steel | RL | 1 ,SHE_DRAWING+SHEET.dgn,Design Model;5,SHE-13.STEEL.dgn,Design Model:105483 | BS UC | UC203X203X46 | 1\BS UC\UC203X203X46 | 3.9736 | 0.00587 | 0.005784 | 4.79375 | 4.80532 | 0 | 0.023325 | 0.022983 | 0.023325 | 0.022983 | 46.100000 | 183.182960 | 183.101501 | 180.413933 | 183.101501 | 180.413933
A-Beams-Steel | RL | 1 ,SHE_DRAWING+SHEET.dgn,Design Model;5,SHE-13.STEEL.dgn,Design Model:105485 | BS UC | UC203X203X46 | 1\BS UC\UC203X203X46 | 3.9736 | 0.00587 | 0.005784 | 4.79375 | 4.80532 | 0 | 0.023325 | 0.022983 | 0.023325 | 0.022983 | 46.100000 | 183.182960 | 183.101501 | 180.413933 | 183.101501 | 180.413933
A-Beams-Steel | RL | 1 ,SHE_DRAWING+SHEET.dgn,Design Model;5,SHE-13.STEEL.dgn,Design Model:105487 | BS UC | UC203X203X46 | 1\BS UC\UC203X203X46 | 4.20358 | 0.00587 | 0.005784 | 5.07119 | 5.08276 | 0 | 0.024675 | 0.024313 | 0.024675 | 0.024313 | 46.100000 | 193.784852 | 193.698678 | 190.855564 | 193.698678 | 190.855564
A-Beams-Steel | RL | 1 ,SHE_DRAWING+SHEET.dgn,Design Model;5,SHE-13.STEEL.dgn,Design Model:105489 | BS UC | UC203X203X46 | 1\BS UC\UC203X203X46 | 4.2536 | 0.00587 | 0.005784 | 5.13154 | 5.14311 | 0 | 0.024969 | 0.024602 | 0.024969 | 0.024602 | 46.100000 | 196.090960 | 196.003761 | 193.126813 | 196.003761 | 193.126813
A-Beams-Steel | RL | 1 ,SHE_DRAWING+SHEET.dgn,Design Model;5,SHE-13.STEEL.dgn,Design Model:105491 | BS UC | UC203X203X46 | 1\BS UC\UC203X203X46 | 3.9336 | 0.00587 | 0.005784 | 4.7455 | 4.75706 | 0 | 0.02309 | 0.022751 | 0.02309 | 0.022751 | 46.100000 | 181.338960 | 181.258321 | 178.597807 | 181.258321 | 178.597807
A-Beams-Steel | RL | 1 ,SHE_DRAWING+SHEET.dgn,Design Model;5,SHE-13.STEEL.dgn,Design Model:105494 | BS UC | UC254X254X167 | 1\BS UC\UC254X254X167 | 7.88305 | 0.0213 | 0.021147 | 12.6176 | 12.6599 | 0 | 0.167909 | 0.166704 | 0.167909 | 0.166704 | 167.100000 | 1317.257655 | 1318.085375 | 1308.624864 | 1318.085375 | 1308.624864
A-Beams-Steel | RL | 1 ,SHE_DRAWING+SHEET.dgn,Design Model;5,SHE-13.STEEL.dgn,Design Model:105496 | BS UC | UC254X254X167 | 1\BS UC\UC254X254X167 | 7.685 | 0.0213 | 0.021147 | 12.3006 | 12.3429 | 0 | 0.163691 | 0.162516 | 0.163691 | 0.162516 | 167.100000 | 1284.163500 | 1284.970425 | 1275.747595 | 1284.970425 | 1275.747595
A-Beams-Steel | RL | 1 ,SHE_DRAWING+SHEET.dgn,Design Model;5,SHE-13.STEEL.dgn,Design Model:105498 | BS UC | UC254X254X167 | 1\BS UC\UC254X254X167 | 7.685 | 0.0213 | 0.021147 | 12.3006 | 12.3429 | 0 | 0.16369 | 0.162516 | 0.16369 | 0.162516 | 167.100000 | 1284.163500 | 1284.970425 | 1275.747595 | 1284.970425 | 1275.747595
A-Beams-Steel | RL | 1 ,SHE_DRAWING+SHEET.dgn,Design Model;5,SHE-13.STEEL.dgn,Design Model:105500 | BS UC | UC254X254X167 | 1\BS UC\UC254X254X167 | 7.6068 | 0.0213 | 0.021147 | 12.1754 | 12.2177 | 0 | 0.162025 | 0.160862 | 0.162025 | 0.160862 | 167.100000 | 1271.096280 | 1271.894994 | 1262.766012 | 1271.894994 | 1262.766012
A-Beams-Steel | RL | 1 ,SHE_DRAWING+SHEET.dgn,Design Model;5,SHE-13.STEEL.dgn,Design Model:105502 | BS UC | UC254X254X167 | 1\BS UC\UC254X254X167 | 7.59359 | 0.0213 | 0.021147 | 12.1543 | 12.1966 | 0 | 0.161744 | 0.160583 | 0.161744 | 0.160583 | 167.100000 | 1268.889413 | 1269.686740 | 1260.573608 | 1269.686740 | 1260.573608
A-Beams-Steel | RL | 1 ,SHE_DRAWING+SHEET.dgn,Design Model;5,SHE-13.STEEL.dgn,Design Model:105504 | BS UC | UC254X254X167 | 1\BS UC\UC254X254X167 | 7.6318 | 0.0213 | 0.021147 | 12.2155 | 12.2578 | 0 | 0.162557 | 0.161391 | 0.162557 | 0.161391 | 167.100000 | 1275.273780 | 1276.075119 | 1266.916135 | 1276.075119 | 1266.916135
A-Beams-Steel | GF | 1 ,SHE_DRAWING+SHEET.dgn,Design Model;15,SHE-14.BALCONY.dgn,Design Model:168529 | BS5950_UC | UC152X152X51 | 1\BS5950_UC\UC152X152X51 | 5.3944 | 0.0065 | 0.006469 | 5.11389 | 5.04575 | 0.000509 | 0.035064 | 0.034897 | 0.034554 | 0.034388 | 51.200000 | 276.193337 | 275.249317 | 273.943365 | 271.252702 | 269.946750
A-Beams-Steel | GF | 1 ,SHE_DRAWING+SHEET.dgn,Design Model;15,SHE-14.BALCONY.dgn,Design Model:168535 | BS5950_UC | UC152X152X51 | 1\BS5950_UC\UC152X152X51 | 5.4786 | 0.0065 | 0.006469 | 5.19371 | 5.0445 | 0.001018 | 0.035611 | 0.035442 | 0.034593 | 0.034424 | 51.200000 | 280.504377 | 279.545622 | 278.219285 | 271.552392 | 270.226056
A-Beams-Steel | GF | 1 ,SHE_DRAWING+SHEET.dgn,Design Model;15,SHE-14.BALCONY.dgn,Design Model:168539 | BS5950_UC | UC152X152X51 | 1\BS5950_UC\UC152X152X51 | 5.4786 | 0.0065 | 0.006469 | 5.19371 | 5.0445 | 0.001018 | 0.035611 | 0.035442 | 0.034593 | 0.034424 | 51.200000 | 280.504377 | 279.545622 | 278.219285 | 271.552392 | 270.226056
A-Beams-Steel | GF | 1 ,SHE_DRAWING+SHEET.dgn,Design Model;15,SHE-14.BALCONY.dgn,Design Model:168541 | BS5950_UC | UC152X152X51 | 1\BS5950_UC\UC152X152X51 | 2.905 | 0.0065 | 0.006469 | 2.75394 | 2.60473 | 0.001018 | 0.018882 | 0.018793 | 0.017864 | 0.017775 | 51.200000 | 148.736000 | 148.227625 | 147.524342 | 140.234396 | 139.531113
A-Beams-Steel | GF | 1 ,SHE_DRAWING+SHEET.dgn,Design Model;15,SHE-14.BALCONY.dgn,Design Model:168551 | BS5950_UC | UC152X152X51 | 1\BS5950_UC\UC152X152X51 | 3.84218 | 0.0065 | 0.006469 | 3.64239 | 3.57425 | 0.000509 | 0.024974 | 0.024856 | 0.024465 | 0.024347 | 51.200000 | 196.719650 | 196.047268 | 195.117099 | 192.050653 | 191.120485
A-Beams-Steel | GF | 1 ,SHE_DRAWING+SHEET.dgn,Design Model;15,SHE-14.BALCONY.dgn,Design Model:169209 | BS5950_UC | UC152X152X51 | 1\BS5950_UC\UC152X152X51 | 1.01038 | 0.0065 | 0.006469 | 0.957841 | 0.970779 | 0 | 0.006567 | 0.006536 | 0.006567 | 0.006536 | 51.200000 | 51.731490 | 51.554673 | 51.310066 | 51.554673 | 51.310066
A-Beams-Steel | GF | 1 ,SHE_DRAWING+SHEET.dgn,Design Model;15,SHE-14.BALCONY.dgn,Design Model:174204 | BS5950_UC | UC152X152X51 | 1\BS5950_UC\UC152X152X51 | 1.01038 | 0.0065 | 0.006469 | 0.957841 | 0.970779 | 0 | 0.006567 | 0.006536 | 0.006567 | 0.006536 | 51.200000 | 51.731490 | 51.554673 | 51.310066 | 51.554673 | 51.310066
A-Beams-Steel | GF | 1 ,SHE_DRAWING+SHEET.dgn,Design Model;15,SHE-14.BALCONY.dgn,Design Model:174262 | BS5950_UC | UC152X152X51 | 1\BS5950_UC\UC152X152X51 | 1.01038 | 0.0065 | 0.006469 | 0.957841 | 0.970779 | 0 | 0.006567 | 0.006536 | 0.006567 | 0.006536 | 51.200000 | 51.731490 | 51.554673 | 51.310066 | 51.554673 | 51.310066
A-Beams-Steel | GF | 1 ,SHE_DRAWING+SHEET.dgn,Design Model;15,SHE-14.BALCONY.dgn,Design Model:179383 | BS5950_UC | UC152X152X51 | 1\BS5950_UC\UC152X152X51 | 2.905 | 0.0065 | 0.006469 | 2.75394 | 2.60473 | 0.001018 | 0.018882 | 0.018793 | 0.017864 | 0.017775 | 51.200000 | 148.736000 | 148.227625 | 147.524342 | 140.234396 | 139.531113
A-Beams-Steel | GF | 1 ,SHE_DRAWING+SHEET.dgn,Design Model;15,SHE-14.BALCONY.dgn,Design Model:179385 | BS5950_UC | UC152X152X51 | 1\BS5950_UC\UC152X152X51 | 2.905 | 0.0065 | 0.006469 | 2.75394 | 2.60473 | 0.001018 | 0.018882 | 0.018793 | 0.017864 | 0.017775 | 51.200000 | 148.736000 | 148.227625 | 147.524342 | 140.234396 | 139.531113
A-Beams-Steel | GF | 1 ,SHE_DRAWING+SHEET.dgn,Design Model;15,SHE-14.BALCONY.dgn,Design Model:179389 | BS5950_UC | UC152X152X51 | 1\BS5950_UC\UC152X152X51 | 3.84218 | 0.0065 | 0.006469 | 3.64239 | 3.57425 | 0.000509 | 0.024974 | 0.024856 | 0.024465 | 0.024347 | 51.200000 | 196.719650 | 196.047268 | 195.117099 | 192.050653 | 191.120485
A-Beams-Steel | GF | 1 ,SHE_DRAWING+SHEET.dgn,Design Model;15,SHE-14.BALCONY.dgn,Design Model:179391 | BS5950_UC | UC152X152X51 | 1\BS5950_UC\UC152X152X51 | 3.84218 | 0.0065 | 0.006469 | 3.64239 | 3.57425 | 0.000509 | 0.024974 | 0.024856 | 0.024465 | 0.024347 | 51.200000 | 196.719650 | 196.047268 | 195.117099 | 192.050653 | 191.120485
A-Beams-Steel | GF | 1 ,SHE_DRAWING+SHEET.dgn,Design Model;15,SHE-14.BALCONY.dgn,Design Model:179394 | BS5950_UC | UC152X152X51 | 1\BS5950_UC\UC152X152X51 | 5.4786 | 0.0065 | 0.006469 | 5.19371 | 5.0445 | 0.001018 | 0.035611 | 0.035442 | 0.034593 | 0.034424 | 51.200000 | 280.504377 | 279.545622 | 278.219285 | 271.552392 | 270.226056
A-Beams-Steel | GF | 1 ,SHE_DRAWING+SHEET.dgn,Design Model;15,SHE-14.BALCONY.dgn,Design Model:179404 | BS5950_UC | UC152X152X51 | 1\BS5950_UC\UC152X152X51 | 5.3944 | 0.0065 | 0.006469 | 5.11389 | 5.04575 | 0.000509 | 0.035064 | 0.034897 | 0.034554 | 0.034388 | 51.200000 | 276.193337 | 275.249317 | 273.943365 | 271.252702 | 269.946750
A-Beams-Steel | GF | 1 ,SHE_DRAWING+SHEET.dgn,Design Model;15,SHE-14.BALCONY.dgn,Design Model:179406 | BS5950_UC | UC152X152X51 | 1\BS5950_UC\UC152X152X51 | 5.3944 | 0.0065 | 0.006469 | 5.11389 | 5.04575 | 0.000509 | 0.035064 | 0.034897 | 0.034554 | 0.034388 | 51.200000 | 276.193337 | 275.249317 | 273.943365 | 271.252702 | 269.946750

# IfcBeam: S-Beams-PrecastConcrete (24)
In: GF
Type - PredefinedType: BEAM
Type - Thermal Transmittance - Is External: no; Is Below Grade: no
Type - Structural Usage - Structural | Function: Undefined; Structural | Material: Concrete
Type - Structural Parameters - Section Name: 300x600; Structural Type: Beam; Tapered Member: no
Type - Quantities | Structural - Length: 0 m; Area | Cross-sectional: 0 m2; Area | Cross-sectional Modeled: 0 m2; Volume | Perforation(s): 0 m3; Volume (Gross): 0 m3; Volume (Gross Modeled): 0 m3; Volume (Net): 0 m3; Volume (Net Modeled): 0 m3; Unit Weight: 0; Material Density: 0; Length x Unit Weight: 0; Volume (Gross) x Density: 0; Volume (Gross Modeled) x Density: 0; Volume (Net) x Density: 0; Volume (Net Modeled) x Density: 0
Type - Materials - Part Definition: S-Beams::S_BSUK_Beams_PrecastConcrete
Type - LEED Parameters - LEED | Pre-consumer Recycled (%): 0; LEED | Regional Material: no; LEED | Post-consumer Recycled (%): 0
Type - Fire Resistance - Fire | IsCombustible: no; Fire | Compartmentation: no
Type - Discipline - Discipline: Structural
Type - Construction Phase - Phase: New Construction
Type - Classification - Uniclass2015: Pr_20_85_08_15
Material: S_BSUK_Beams_PrecastConcrete
Pset_BeamCommon - IsExternal: no; LoadBearing: no
Quantities | Structural - Material Density: 2400.000000
Construction Phase - Phase: Existing to Remain
BuildingDesignerForm - Type: Beam; Material: Concrete; Grade: C40; Class: Gravity; Cope Flange Clearance: 0.000; Cope Web Clearance: 0.000; Cope Corner Treatment: 0; Cope Corner Radius: 0.000; Local Y Offset: 0.000; Local Z Offset: 0.000
Name | Description | StructuralFramingCommon, Section Name | Structural Parameters, Section Name | Length (m) | Area | Cross-sectional (m2) = Area | Cross-sectional Modeled (m2) | Area | Side Surfaces Modeled (Gross) (m2) | Area | All Surfaces Modeled (Net) (m2) | Volume (Gross) (m3) = Volume (Gross Modeled) (m3) = Volume (Net) (m3) = Volume (Net Modeled) (m3) | Unit Weight | Length x Unit Weight | Volume (Gross) x Density = Volume (Gross Modeled) x Density = Volume (Net) x Density = Volume (Net Modeled) x Density
S-Beams-PrecastConcrete | 1 ,SHE_DRAWING+SHEET.dgn,Design Model;9,SHE-10.CONCRETE.dgn,Design Model:202130 | 0.400X0.500 | 6\RECTANGLE\0.400X0.500 | 14.06 | 0.2 | 25.308 | 25.708 | 2.812 | 1570.000000 | 22074.200000 | 6748.800000
S-Beams-PrecastConcrete | 1 ,SHE_DRAWING+SHEET.dgn,Design Model;9,SHE-10.CONCRETE.dgn,Design Model:202139 | 0.400X0.500 | 6\RECTANGLE\0.400X0.500 | 14.06 | 0.2 | 25.308 | 25.708 | 2.812 | 1570.000000 | 22074.200000 | 6748.800000
S-Beams-PrecastConcrete | 1 ,SHE_DRAWING+SHEET.dgn,Design Model;9,SHE-10.CONCRETE.dgn,Design Model:202150 | 0.400X0.500 | 6\RECTANGLE\0.400X0.500 | 14.06 | 0.2 | 25.308 | 25.708 | 2.812 | 1570.000000 | 22074.200000 | 6748.800000
S-Beams-PrecastConcrete | 1 ,SHE_DRAWING+SHEET.dgn,Design Model;9,SHE-10.CONCRETE.dgn,Design Model:202152 | 0.400X0.500 | 6\RECTANGLE\0.400X0.500 | 14.06 | 0.2 | 25.308 | 25.708 | 2.812 | 1570.000000 | 22074.200000 | 6748.800000
S-Beams-PrecastConcrete | 1 ,SHE_DRAWING+SHEET.dgn,Design Model;9,SHE-10.CONCRETE.dgn,Design Model:202154 | 0.400X0.500 | 6\RECTANGLE\0.400X0.500 | 14.06 | 0.2 | 25.308 | 25.708 | 2.812 | 1570.000000 | 22074.200000 | 6748.800000
S-Beams-PrecastConcrete | 1 ,SHE_DRAWING+SHEET.dgn,Design Model;9,SHE-10.CONCRETE.dgn,Design Model:202156 | 0.400X0.500 | 6\RECTANGLE\0.400X0.500 | 14.06 | 0.2 | 25.308 | 25.708 | 2.812 | 1570.000000 | 22074.200000 | 6748.800000
S-Beams-PrecastConcrete | 1 ,SHE_DRAWING+SHEET.dgn,Design Model;9,SHE-10.CONCRETE.dgn,Design Model:201619 | 0.400X0.380 | 6\RECTANGLE\0.400X0.380 | 11.1535 | 0.152 | 17.3995 | 17.7035 | 1.69534 | 1193.200000 | 13308.401638 | 4068.810692
S-Beams-PrecastConcrete | 1 ,SHE_DRAWING+SHEET.dgn,Design Model;9,SHE-10.CONCRETE.dgn,Design Model:141247 | 0.500X1.800 | 6\RECTANGLE\0.500X1.800 | 13.62 | 0.9 | 62.652 | 64.452 | 12.258 | 7065.000000 | 96225.300000 | 29419.200000
S-Beams-PrecastConcrete | 1 ,SHE_DRAWING+SHEET.dgn,Design Model;9,SHE-10.CONCRETE.dgn,Design Model:201617 | 0.400X1.030 | 6\RECTANGLE\0.400X1.030 | 3.54646 | 0.412 | 10.1429 | 10.9669 | 1.46114 | 3234.200000 | 11469.967139 | 3506.741546
S-Beams-PrecastConcrete | 1 ,SHE_DRAWING+SHEET.dgn,Design Model;9,SHE-10.CONCRETE.dgn,Design Model:141269 | 0.300X1.030 | 6\RECTANGLE\0.300X1.030 | 25.98 | 0.309 | 69.1068 | 69.7248 | 8.02782 | 2425.650000 | 63018.387000 | 19266.768000
S-Beams-PrecastConcrete | 1 ,SHE_DRAWING+SHEET.dgn,Design Model;9,SHE-10.CONCRETE.dgn,Design Model:201404 | 0.400X1.030 | 6\RECTANGLE\0.400X1.030 | 3.54646 | 0.412 | 10.1429 | 10.9669 | 1.46114 | 3234.200000 | 11469.967139 | 3506.741546
S-Beams-PrecastConcrete | 1 ,SHE_DRAWING+SHEET.dgn,Design Model;9,SHE-10.CONCRETE.dgn,Design Model:201590 | 0.400X0.380 | 6\RECTANGLE\0.400X0.380 | 11.1535 | 0.152 | 17.3995 | 17.7035 | 1.69534 | 1193.200000 | 13308.401638 | 4068.810692
S-Beams-PrecastConcrete | 1 ,SHE_DRAWING+SHEET.dgn,Design Model;9,SHE-10.CONCRETE.dgn,Design Model:204340 | 0.500X0.380 | 6\RECTANGLE\0.500X0.380 | 4.07 | 0.19 | 7.1632 | 7.5432 | 0.7733 | 1491.500000 | 6070.405000 | 1855.920000
S-Beams-PrecastConcrete | 1 ,SHE_DRAWING+SHEET.dgn,Design Model;9,SHE-10.CONCRETE.dgn,Design Model:204388 | 0.500X0.380 | 6\RECTANGLE\0.500X0.380 | 8.29 | 0.19 | 14.5904 | 14.9704 | 1.5751 | 1491.500000 | 12364.535000 | 3780.240000
S-Beams-PrecastConcrete | 1 ,SHE_DRAWING+SHEET.dgn,Design Model;9,SHE-10.CONCRETE.dgn,Design Model:221948 | 0.300X0.250 | 6\RECTANGLE\0.300X0.250 | 8.36 | 0.075 | 9.196 | 9.346 | 0.627 | 588.750000 | 4921.950000 | 1504.800000
S-Beams-PrecastConcrete | 1 ,SHE_DRAWING+SHEET.dgn,Design Model;9,SHE-10.CONCRETE.dgn,Design Model:223033 | 0.250X0.700 | 6\RECTANGLE\0.250X0.700 | 8.40304 | 0.175 | 15.9658 | 16.3158 | 1.47053 | 1373.750000 | 11543.673441 | 3529.275956
S-Beams-PrecastConcrete | 1 ,SHE_DRAWING+SHEET.dgn,Design Model;9,SHE-10.CONCRETE.dgn,Design Model:223466 | 0.400X0.340 | 6\RECTANGLE\0.400X0.340 | 14.06 | 0.136 | 20.8088 | 21.0808 | 1.91216 | 1067.600000 | 15010.456000 | 4589.184000
S-Beams-PrecastConcrete | 1 ,SHE_DRAWING+SHEET.dgn,Design Model;9,SHE-10.CONCRETE.dgn,Design Model:223473 | 0.400X0.340 | 6\RECTANGLE\0.400X0.340 | 14.06 | 0.136 | 20.8088 | 21.0808 | 1.91216 | 1067.600000 | 15010.456000 | 4589.184000
S-Beams-PrecastConcrete | 1 ,SHE_DRAWING+SHEET.dgn,Design Model;9,SHE-10.CONCRETE.dgn,Design Model:224976 | 0.400X0.340 | 6\RECTANGLE\0.400X0.340 | 6.47788 | 0.136 | 9.58727 | 9.85927 | 0.880992 | 1067.600000 | 6915.788288 | 2114.381133
S-Beams-PrecastConcrete | 1 ,SHE_DRAWING+SHEET.dgn,Design Model;9,SHE-10.CONCRETE.dgn,Design Model:224978 | 0.400X0.340 | 6\RECTANGLE\0.400X0.340 | 6.17178 | 0.136 | 9.13424 | 9.40624 | 0.839363 | 1067.600000 | 6588.997190 | 2014.470479
S-Beams-PrecastConcrete | 1 ,SHE_DRAWING+SHEET.dgn,Design Model;9,SHE-10.CONCRETE.dgn,Design Model:292563 | 0.330X0.950 | 6\RECTANGLE\0.330X0.950 | 25.9 | 0.3135 | 66.304 | 66.931 | 8.11965 | 2460.975000 | 63739.252500 | 19487.160000
S-Beams-PrecastConcrete | 1 ,SHE_DRAWING+SHEET.dgn,Design Model;9,SHE-10.CONCRETE.dgn,Design Model:292566 | 0.370X0.950 | 6\RECTANGLE\0.370X0.950 | 14.56 | 0.3515 | 38.4384 | 39.1414 | 5.11784 | 2759.275000 | 40175.044000 | 12282.816000
S-Beams-PrecastConcrete | 1 ,SHE_DRAWING+SHEET.dgn,Design Model;9,SHE-10.CONCRETE.dgn,Design Model:292568 | 0.330X0.950 | 6\RECTANGLE\0.330X0.950 | 25.9 | 0.3135 | 66.304 | 66.931 | 8.11965 | 2460.975000 | 63739.252500 | 19487.160000
S-Beams-PrecastConcrete | 1 ,SHE_DRAWING+SHEET.dgn,Design Model;9,SHE-10.CONCRETE.dgn,Design Model:292570 | 0.370X0.950 | 6\RECTANGLE\0.370X0.950 | 14.56 | 0.3515 | 38.4384 | 39.1414 | 5.11784 | 2759.275000 | 40175.044000 | 12282.816000

# IfcBuildingElementPart (3560)
In: RL
Name | Material
631 x 1 | A_BSUK_Insulation
747 x 2 | A_BSUK_Walls_Timber
461 x 3 | A_BSUK_WallInternal_Finishes_Plasterboard
386 x 4 | A_BSUK_WallInternal_Finishes_Plasterboard
236 x 5 | A_BSUK_WallInternal_Finishes_Plasterboard
119 x 6 | A_BSUK_WallInternal_Finishes_Plasterboard
86 x 7 | A_BSUK_Walls_Timber
107 x 5 | A_BSUK_Walls_Timber
133 x 1 | A_BSUK_OpeningsClearance
38 x 8 | A_BSUK_Walls_Timber
25 x 9 | A_BSUK_Walls_Timber
22 x 6 | A_BSUK_Walls_Timber
51 x 7 | A_BSUK_WallInternal_Finishes_Plasterboard
24 x 1 | A_BSUK_WallsInternal_Block
24 x 3 | A_BSUK_WallInternal_Finishes_Plaster
11 x 6 | A_BSUK_WallInternal_Finishes_Plaster
17 x 8 | A_BSUK_WallInternal_Finishes_Plasterboard
18 x 9 | A_BSUK_WallInternal_Finishes_Plasterboard
18 x 10 | A_BSUK_WallInternal_Finishes_Plasterboard
9 x 11 | A_BSUK_WallInternal_Finishes_Plasterboard
184 x 3 | A_BSUK_Walls_Timber
16 x 10 | A_BSUK_Walls_Timber
15 x 11 | A_BSUK_Walls_Timber
9 x 12 | A_BSUK_Walls_Timber
9 x 12 | A_BSUK_WallInternal_Finishes_Plasterboard
9 x 13 | A_BSUK_WallInternal_Finishes_Plasterboard
4 x 14 | A_BSUK_Walls_Timber
3 x 15 | A_BSUK_Walls_Timber
3 x 16 | A_BSUK_Walls_Timber
3 x 17 | A_BSUK_Walls_Timber
14 x 1 | A_BSUK_Walls_Timber
22 x 2 | A_BSUK_WallInternal_Finishes_Plasterboard
3 x 7 | A_BSUK_WallInternal_Finishes_Plaster
35 x 4 | A_BSUK_Walls_Timber
13 | A_BSUK_Walls_Timber
33 x 2 | A_BSUK_Insulation
2 x 14 | A_BSUK_WallInternal_Finishes_Plasterboard
30 x 6 | A_BSUK_WallInternal_Finishes_Metal
2 x 8 | A_BSUK_WallInternal_Finishes_Metal

# IfcBuildingElementProxy (76)
Name | In | Description
 | GF | 0 , SHE_DRAWING+SHEET.dgn, C-C:1008963
 | GF | 0 , SHE_DRAWING+SHEET.dgn, C-C:1499294 | Group: Section CC - Grid Lines
 | GF | 0 , SHE_DRAWING+SHEET.dgn, C-C:1499301 | Group: Section CC - Grid Lines
 | GF | 0 , SHE_DRAWING+SHEET.dgn, C-C:1499308 | Group: Section CC - Grid Lines
 | GF | 0 , SHE_DRAWING+SHEET.dgn, C-C:1499315 | Group: Section CC - Grid Lines
 | GF | 0 , SHE_DRAWING+SHEET.dgn, C-C:1499322 | Group: Section CC - Grid Lines
 | GF | 0 , SHE_DRAWING+SHEET.dgn, C-C:1499329 | Group: Section CC - Grid Lines
 | GF | 0 , SHE_DRAWING+SHEET.dgn, C-C:1499336 | Group: Section CC - Grid Lines
 | GF | 0 , SHE_DRAWING+SHEET.dgn, C-C:1499343 | Group: Section CC - Grid Lines
 | GF | 0 , SHE_DRAWING+SHEET.dgn, C-C:1499350 | Group: Section CC - Grid Lines
 | GF | 0 , SHE_DRAWING+SHEET.dgn, C-C:1499357 | Group: Section CC - Grid Lines
 | GF | 0 , SHE_DRAWING+SHEET.dgn, C-C:1499364 | Group: Section CC - Grid Lines
 | GF | 0 , SHE_DRAWING+SHEET.dgn, C-C:1499371 | Group: Section CC - Grid Lines
 | GF | 0 , SHE_DRAWING+SHEET.dgn, C-C:1499378 | Group: Section CC - Grid Lines
 | GF | 0 , SHE_DRAWING+SHEET.dgn, C-C:1499385 | Group: Section CC - Grid Lines
 | GF | 0 , SHE_DRAWING+SHEET.dgn, C-C:1499391 | Group: Section CC - Floor Lines
 | GF | 0 , SHE_DRAWING+SHEET.dgn, C-C:1499392 | Group: Section CC - Floor Lines
 | GF | 0 , SHE_DRAWING+SHEET.dgn, C-C:1499400 | Group: Section CC - Floor Lines
 | GF | 0 , SHE_DRAWING+SHEET.dgn, C-C:1499401 | Group: Section CC - Floor Lines
 | GF | 0 , SHE_DRAWING+SHEET.dgn, C-C:1499409 | Group: Section CC - Floor Lines
 | GF | 0 , SHE_DRAWING+SHEET.dgn, C-C:1499410 | Group: Section CC - Floor Lines
 | GF | 0 , SHE_DRAWING+SHEET.dgn, C-C:1499418 | Group: Section CC - Floor Lines
 | GF | 0 , SHE_DRAWING+SHEET.dgn, C-C:1499419 | Group: Section CC - Floor Lines
 | GF | 0 , SHE_DRAWING+SHEET.dgn, C-C:1499427 | Group: Section CC - Floor Lines
 | GF | 0 , SHE_DRAWING+SHEET.dgn, C-C:1499428 | Group: Section CC - Floor Lines
 | GF | 0 , SHE_DRAWING+SHEET.dgn, C-C:1499436 | Group: Section CC - Floor Lines
 | GF | 0 , SHE_DRAWING+SHEET.dgn, C-C:1499437 | Group: Section CC - Floor Lines
 | GF | 0 , SHE_DRAWING+SHEET.dgn, C-C:1499445 | Group: Section CC - Floor Lines
 | GF | 0 , SHE_DRAWING+SHEET.dgn, C-C:1499446 | Group: Section CC - Floor Lines
 | GF | 0 , SHE_DRAWING+SHEET.dgn, C-C:1499454 | Group: Section CC - Floor Lines
 | GF | 0 , SHE_DRAWING+SHEET.dgn, C-C:1499455 | Group: Section CC - Floor Lines
 | RL | 1 ,SHE_DRAWING+SHEET.dgn,Design Model;7,SHE-06.FOURTH.dgn,Design Model:387761
 | RL | 1 ,SHE_DRAWING+SHEET.dgn,Design Model;7,SHE-06.FOURTH.dgn,Design Model:388003
 | RL | 1 ,SHE_DRAWING+SHEET.dgn,Design Model;7,SHE-06.FOURTH.dgn,Design Model:388052
 | RL | 1 ,SHE_DRAWING+SHEET.dgn,Design Model;7,SHE-06.FOURTH.dgn,Design Model:388101
 | RL | 1 ,SHE_DRAWING+SHEET.dgn,Design Model;7,SHE-06.FOURTH.dgn,Design Model:388150
 | RL | 1 ,SHE_DRAWING+SHEET.dgn,Design Model;7,SHE-06.FOURTH.dgn,Design Model:388199
 | RL | 1 ,SHE_DRAWING+SHEET.dgn,Design Model;7,SHE-06.FOURTH.dgn,Design Model:388248
 | RL | 1 ,SHE_DRAWING+SHEET.dgn,Design Model;7,SHE-06.FOURTH.dgn,Design Model:388297
 | RL | 1 ,SHE_DRAWING+SHEET.dgn,Design Model;7,SHE-06.FOURTH.dgn,Design Model:388346
 | RL | 1 ,SHE_DRAWING+SHEET.dgn,Design Model;7,SHE-06.FOURTH.dgn,Design Model:388395
 | RL | 1 ,SHE_DRAWING+SHEET.dgn,Design Model;7,SHE-06.FOURTH.dgn,Design Model:388493
 | RL | 1 ,SHE_DRAWING+SHEET.dgn,Design Model;7,SHE-06.FOURTH.dgn,Design Model:388542
 | RL | 1 ,SHE_DRAWING+SHEET.dgn,Design Model;7,SHE-06.FOURTH.dgn,Design Model:388591
 | RL | 1 ,SHE_DRAWING+SHEET.dgn,Design Model;7,SHE-06.FOURTH.dgn,Design Model:388640
 | RL | 1 ,SHE_DRAWING+SHEET.dgn,Design Model;7,SHE-06.FOURTH.dgn,Design Model:388689
 | RL | 1 ,SHE_DRAWING+SHEET.dgn,Design Model;7,SHE-06.FOURTH.dgn,Design Model:388738
 | RL | 1 ,SHE_DRAWING+SHEET.dgn,Design Model;7,SHE-06.FOURTH.dgn,Design Model:388787
 | RL | 1 ,SHE_DRAWING+SHEET.dgn,Design Model;7,SHE-06.FOURTH.dgn,Design Model:388836
 | RL | 1 ,SHE_DRAWING+SHEET.dgn,Design Model;7,SHE-06.FOURTH.dgn,Design Model:388885
 | RL | 1 ,SHE_DRAWING+SHEET.dgn,Design Model;7,SHE-06.FOURTH.dgn,Design Model:388934
 | RL | 1 ,SHE_DRAWING+SHEET.dgn,Design Model;7,SHE-06.FOURTH.dgn,Design Model:388983
 | RL | 1 ,SHE_DRAWING+SHEET.dgn,Design Model;7,SHE-06.FOURTH.dgn,Design Model:389032
 | RL | 1 ,SHE_DRAWING+SHEET.dgn,Design Model;7,SHE-06.FOURTH.dgn,Design Model:389081
 | RL | 1 ,SHE_DRAWING+SHEET.dgn,Design Model;7,SHE-06.FOURTH.dgn,Design Model:389179
 | RL | 1 ,SHE_DRAWING+SHEET.dgn,Design Model;7,SHE-06.FOURTH.dgn,Design Model:389228
 | RL | 1 ,SHE_DRAWING+SHEET.dgn,Design Model;7,SHE-06.FOURTH.dgn,Design Model:389277
 | RL | 1 ,SHE_DRAWING+SHEET.dgn,Design Model;8,SHE-07.FIFTH.dgn,Design Model:213484
 | RL | 1 ,SHE_DRAWING+SHEET.dgn,Design Model;8,SHE-07.FIFTH.dgn,Design Model:213545
 | RL | 1 ,SHE_DRAWING+SHEET.dgn,Design Model;8,SHE-07.FIFTH.dgn,Design Model:294809
 | RL | 1 ,SHE_DRAWING+SHEET.dgn,Design Model;8,SHE-07.FIFTH.dgn,Design Model:294810
 | RL | 1 ,SHE_DRAWING+SHEET.dgn,Design Model;8,SHE-07.FIFTH.dgn,Design Model:295030
 | RL | 1 ,SHE_DRAWING+SHEET.dgn,Design Model;8,SHE-07.FIFTH.dgn,Design Model:295250
 | GF | 1 ,SHE_DRAWING+SHEET.dgn,Design Model;9,SHE-10.CONCRETE.dgn,Design Model:220361
 | GF | 1 ,SHE_DRAWING+SHEET.dgn,Design Model;9,SHE-10.CONCRETE.dgn,Design Model:220623
 | GF | 1 ,SHE_DRAWING+SHEET.dgn,Design Model;9,SHE-10.CONCRETE.dgn,Design Model:221043
 | GF | 1 ,SHE_DRAWING+SHEET.dgn,Design Model;9,SHE-10.CONCRETE.dgn,Design Model:223608
 | GF | 1 ,SHE_DRAWING+SHEET.dgn,Design Model;9,SHE-10.CONCRETE.dgn,Design Model:223614
 | GF | 1 ,SHE_DRAWING+SHEET.dgn,Design Model;9,SHE-10.CONCRETE.dgn,Design Model:223954
 | GF | 1 ,SHE_DRAWING+SHEET.dgn,Design Model;9,SHE-10.CONCRETE.dgn,Design Model:224296
 | GF | 1 ,SHE_DRAWING+SHEET.dgn,Design Model;9,SHE-10.CONCRETE.dgn,Design Model:224636
 | GF | 1 ,SHE_DRAWING+SHEET.dgn,Design Model;9,SHE-10.CONCRETE.dgn,Design Model:208085
 | RL | 1 ,SHE_DRAWING+SHEET.dgn,Design Model;11,SHE-15.MEHP.dgn,Design Model:265965
 | RL | 1 ,SHE_DRAWING+SHEET.dgn,Design Model;11,SHE-15.MEHP.dgn,Design Model:266692
 | RL | 1 ,SHE_DRAWING+SHEET.dgn,Design Model;11,SHE-15.MEHP.dgn,Design Model:267722
 | RL | 1 ,SHE_DRAWING+SHEET.dgn,Design Model;11,SHE-15.MEHP.dgn,Design Model:271784

# IfcBuildingElementProxy: Fireproofing:Cementitious (9)
In: RL
Material: Cementitious
Name | Description
Fireproofing--Cementitious | 1,SHE_DRAWING+SHEET.dgn,Design Model;5 ,SHE-13.STEEL.dgn,Design Model:112387
Fireproofing--Cementitious | 1,SHE_DRAWING+SHEET.dgn,Design Model;5 ,SHE-13.STEEL.dgn,Design Model:112437
Fireproofing--Cementitious | 1,SHE_DRAWING+SHEET.dgn,Design Model;5 ,SHE-13.STEEL.dgn,Design Model:112503
Fireproofing--Cementitious | 1,SHE_DRAWING+SHEET.dgn,Design Model;5 ,SHE-13.STEEL.dgn,Design Model:112553
Fireproofing--Cementitious | 1,SHE_DRAWING+SHEET.dgn,Design Model;5 ,SHE-13.STEEL.dgn,Design Model:112587
Fireproofing--Cementitious | 1,SHE_DRAWING+SHEET.dgn,Design Model;5 ,SHE-13.STEEL.dgn,Design Model:112621
Fireproofing--Cementitious | 1,SHE_DRAWING+SHEET.dgn,Design Model;5 ,SHE-13.STEEL.dgn,Design Model:112671
Fireproofing--Cementitious | 1,SHE_DRAWING+SHEET.dgn,Design Model;5 ,SHE-13.STEEL.dgn,Design Model:112721
Fireproofing--Cementitious | 1,SHE_DRAWING+SHEET.dgn,Design Model;5 ,SHE-13.STEEL.dgn,Design Model:112755

# IfcColumn: A-Columns-Concrete (27)
In: GF
Type - PredefinedType: COLUMN
Type - Thermal Transmittance - Is External: no; Is Below Grade: no
Type - Structural Usage - Structural | Material: Concrete
Type - Structural Parameters - Section Name: 600x600; Structural Type: Column; Tapered Member: no
Type - Space Bounding - Is Space Bounding: yes
Type - Materials - Part Definition: A-Columns::A_BSUK_Columns_ReinforcedConcrete
Type - Fire Resistance - Fire | IsCombustible: no; Fire | Compartmentation: no
Type - Discipline - Discipline: Architectural
Type - Construction Phase - Phase: New Construction
Type - Classification - Uniclass2015: Pr_20_85_16_15
Material: A_BSUK_Columns_ReinforcedConcrete
Pset_ColumnCommon - IsExternal: no; LoadBearing: no
Structural Location - Column Location: N/A
Quantities | Structural - Volume | Perforation(s): 0 m3; Material Density: 2400.000000
Construction Phase - Phase: Existing to Remain
BuildingDesignerForm - Cope Flange Clearance: 0.000; Cope Web Clearance: 0.000; Cope Corner Treatment: 0; Cope Corner Radius: 0.000; Local Y Offset: 0.000; Local Z Offset: 0.000
Name | Description | StructuralFramingCommon, Section Name | Structural Parameters, Section Name | Length (m) | Area | Cross-sectional (m2) = Area | Cross-sectional Modeled (m2) | Area | Side Surfaces Modeled (Gross) (m2) | Area | All Surfaces Modeled (Net) (m2) | Volume (Gross) (m3) = Volume (Gross Modeled) (m3) = Volume (Net) (m3) = Volume (Net Modeled) (m3) | Unit Weight | Length x Unit Weight | Volume (Gross) x Density = Volume (Gross Modeled) x Density = Volume (Net) x Density = Volume (Net Modeled) x Density
A-Columns-Concrete | 1 ,SHE_DRAWING+SHEET.dgn,Design Model;9,SHE-10.CONCRETE.dgn,Design Model:128950 | 0.400X0.400 | 6\RECTANGLE\0.400X0.400 | 4.115 | 0.16 | 6.584 | 6.904 | 0.6584 | 1256.000000 | 5168.440000 | 1580.160000
A-Columns-Concrete | 1 ,SHE_DRAWING+SHEET.dgn,Design Model;9,SHE-10.CONCRETE.dgn,Design Model:128956 | 0.500X0.350 | 6\RECTANGLE\0.500X0.350 | 10.48 | 0.175 | 17.816 | 18.166 | 1.834 | 1373.750000 | 14396.900000 | 4401.600000
A-Columns-Concrete | 1 ,SHE_DRAWING+SHEET.dgn,Design Model;9,SHE-10.CONCRETE.dgn,Design Model:129684 | 0.400X0.400 | 6\RECTANGLE\0.400X0.400 | 4.115 | 0.16 | 6.584 | 6.904 | 0.6584 | 1256.000000 | 5168.440000 | 1580.160000
A-Columns-Concrete | 1 ,SHE_DRAWING+SHEET.dgn,Design Model;9,SHE-10.CONCRETE.dgn,Design Model:129690 | 0.400X0.400 | 6\RECTANGLE\0.400X0.400 | 4.115 | 0.16 | 6.584 | 6.904 | 0.6584 | 1256.000000 | 5168.440000 | 1580.160000
A-Columns-Concrete | 1 ,SHE_DRAWING+SHEET.dgn,Design Model;9,SHE-10.CONCRETE.dgn,Design Model:129692 | 0.400X0.400 | 6\RECTANGLE\0.400X0.400 | 4.115 | 0.16 | 6.584 | 6.904 | 0.6584 | 1256.000000 | 5168.440000 | 1580.160000
A-Columns-Concrete | 1 ,SHE_DRAWING+SHEET.dgn,Design Model;9,SHE-10.CONCRETE.dgn,Design Model:129694 | 0.500X0.300 | 6\RECTANGLE\0.500X0.300 | 3.465 | 0.15 | 5.544 | 5.844 | 0.51975 | 1177.500000 | 4080.037500 | 1247.400000
A-Columns-Concrete | 1 ,SHE_DRAWING+SHEET.dgn,Design Model;9,SHE-10.CONCRETE.dgn,Design Model:130413 | 0.670X0.350 | 6\RECTANGLE\0.670X0.350 | 9.93 | 0.2345 | 20.2572 | 20.7262 | 2.32858 | 1840.825000 | 18279.392250 | 5588.604000
A-Columns-Concrete | 1 ,SHE_DRAWING+SHEET.dgn,Design Model;9,SHE-10.CONCRETE.dgn,Design Model:130415 | 0.670X0.350 | 6\RECTANGLE\0.670X0.350 | 9.93 | 0.2345 | 20.2572 | 20.7262 | 2.32858 | 1840.825000 | 18279.392250 | 5588.604000
A-Columns-Concrete | 1 ,SHE_DRAWING+SHEET.dgn,Design Model;9,SHE-10.CONCRETE.dgn,Design Model:130419 | 0.500X0.300 | 6\RECTANGLE\0.500X0.300 | 3.465 | 0.15 | 5.544 | 5.844 | 0.51975 | 1177.500000 | 4080.037500 | 1247.400000
A-Columns-Concrete | 1 ,SHE_DRAWING+SHEET.dgn,Design Model;9,SHE-10.CONCRETE.dgn,Design Model:130423 | 0.500X0.300 | 6\RECTANGLE\0.500X0.300 | 3.465 | 0.15 | 5.544 | 5.844 | 0.51975 | 1177.500000 | 4080.037500 | 1247.400000
A-Columns-Concrete | 1 ,SHE_DRAWING+SHEET.dgn,Design Model;9,SHE-10.CONCRETE.dgn,Design Model:132869 | 0.500X0.300 | 6\RECTANGLE\0.500X0.300 | 3.465 | 0.15 | 5.544 | 5.844 | 0.51975 | 1177.500000 | 4080.037500 | 1247.400000
A-Columns-Concrete | 1 ,SHE_DRAWING+SHEET.dgn,Design Model;9,SHE-10.CONCRETE.dgn,Design Model:132871 | 0.500X0.350 | 6\RECTANGLE\0.500X0.350 | 10.48 | 0.175 | 17.816 | 18.166 | 1.834 | 1373.750000 | 14396.900000 | 4401.600000
A-Columns-Concrete | 1 ,SHE_DRAWING+SHEET.dgn,Design Model;9,SHE-10.CONCRETE.dgn,Design Model:141219 | 0.400X0.700 | 6\RECTANGLE\0.400X0.700 | 3.135 | 0.28 | 6.897 | 7.457 | 0.8778 | 2198.000000 | 6890.730000 | 2106.720000
A-Columns-Concrete | 1 ,SHE_DRAWING+SHEET.dgn,Design Model;9,SHE-10.CONCRETE.dgn,Design Model:141223 | 0.400X0.500 | 6\RECTANGLE\0.400X0.500 | 3.97 | 0.2 | 7.146 | 7.546 | 0.794 | 1570.000000 | 6232.900000 | 1905.600000
A-Columns-Concrete | 1 ,SHE_DRAWING+SHEET.dgn,Design Model;9,SHE-10.CONCRETE.dgn,Design Model:141283 | 0.400X0.500 | 6\RECTANGLE\0.400X0.500 | 3.1 | 0.2 | 5.58 | 5.98 | 0.62 | 1570.000000 | 4867.000000 | 1488.000000
A-Columns-Concrete | 1 ,SHE_DRAWING+SHEET.dgn,Design Model;9,SHE-10.CONCRETE.dgn,Design Model:200731 | 0.670X0.300 | 6\RECTANGLE\0.670X0.300 | 10.48 | 0.201 | 20.3312 | 20.7332 | 2.10648 | 1577.850000 | 16535.868000 | 5055.552000
A-Columns-Concrete | 1 ,SHE_DRAWING+SHEET.dgn,Design Model;9,SHE-10.CONCRETE.dgn,Design Model:200733 | 0.670X0.300 | 6\RECTANGLE\0.670X0.300 | 10.48 | 0.201 | 20.3312 | 20.7332 | 2.10648 | 1577.850000 | 16535.868000 | 5055.552000
A-Columns-Concrete | 1 ,SHE_DRAWING+SHEET.dgn,Design Model;9,SHE-10.CONCRETE.dgn,Design Model:201598 | 0.400X0.400 | 6\RECTANGLE\0.400X0.400 | 3.97 | 0.16 | 6.352 | 6.672 | 0.6352 | 1256.000000 | 4986.320000 | 1524.480000
A-Columns-Concrete | 1 ,SHE_DRAWING+SHEET.dgn,Design Model;9,SHE-10.CONCRETE.dgn,Design Model:201636 | 0.500X0.300 | 6\RECTANGLE\0.500X0.300 | 10.48 | 0.15 | 16.768 | 17.068 | 1.572 | 1177.500000 | 12340.200000 | 3772.800000
A-Columns-Concrete | 1 ,SHE_DRAWING+SHEET.dgn,Design Model;9,SHE-10.CONCRETE.dgn,Design Model:201638 | 0.500X0.300 | 6\RECTANGLE\0.500X0.300 | 10.48 | 0.15 | 16.768 | 17.068 | 1.572 | 1177.500000 | 12340.200000 | 3772.800000
A-Columns-Concrete | 1 ,SHE_DRAWING+SHEET.dgn,Design Model;9,SHE-10.CONCRETE.dgn,Design Model:201640 | 0.400X0.400 | 6\RECTANGLE\0.400X0.400 | 10.48 | 0.16 | 16.768 | 17.088 | 1.6768 | 1256.000000 | 13162.880000 | 4024.320000
A-Columns-Concrete | 1 ,SHE_DRAWING+SHEET.dgn,Design Model;9,SHE-10.CONCRETE.dgn,Design Model:201642 | 0.400X0.400 | 6\RECTANGLE\0.400X0.400 | 10.48 | 0.16 | 16.768 | 17.088 | 1.6768 | 1256.000000 | 13162.880000 | 4024.320000
A-Columns-Concrete | 1 ,SHE_DRAWING+SHEET.dgn,Design Model;9,SHE-10.CONCRETE.dgn,Design Model:201644 | 0.400X0.400 | 6\RECTANGLE\0.400X0.400 | 10.48 | 0.16 | 16.768 | 17.088 | 1.6768 | 1256.000000 | 13162.880000 | 4024.320000
A-Columns-Concrete | 1 ,SHE_DRAWING+SHEET.dgn,Design Model;9,SHE-10.CONCRETE.dgn,Design Model:201646 | 0.400X0.400 | 6\RECTANGLE\0.400X0.400 | 10.48 | 0.16 | 16.768 | 17.088 | 1.6768 | 1256.000000 | 13162.880000 | 4024.320000
A-Columns-Concrete | 1 ,SHE_DRAWING+SHEET.dgn,Design Model;9,SHE-10.CONCRETE.dgn,Design Model:219914 | 0.250X0.250 | 6\RECTANGLE\0.250X0.250 | 2.535 | 0.0625 | 2.535 | 2.66 | 0.158437 | 490.625000 | 1243.734375 | 380.250000
A-Columns-Concrete | 1 ,SHE_DRAWING+SHEET.dgn,Design Model;9,SHE-10.CONCRETE.dgn,Design Model:219933 | 0.250X0.250 | 6\RECTANGLE\0.250X0.250 | 2.535 | 0.0625 | 2.535 | 2.66 | 0.158437 | 490.625000 | 1243.734375 | 380.250000
A-Columns-Concrete | 1 ,SHE_DRAWING+SHEET.dgn,Design Model;9,SHE-10.CONCRETE.dgn,Design Model:221932 | 0.300X0.500 | 6\RECTANGLE\0.300X0.500 | 4.795 | 0.15 | 7.672 | 7.972 | 0.71925 | 1177.500000 | 5646.112500 | 1726.200000

# IfcColumn: A-Columns-Steel (97)
Type - PredefinedType: COLUMN
Type - Thermal Transmittance - Is External: no; Is Below Grade: no
Type - Structural Usage - Structural | Material: Steel
Type - Structural Parameters - Section Name: UC254X254X107; Structural Type: Column; Tapered Member: no
Type - Materials - Part Definition: A-Columns::A_BSUK_Columns_Steel
Type - Fireproofing - Has Fireproofing: no
Type - Fire Resistance - Fire | IsCombustible: no; Fire | Compartmentation: no
Type - Discipline - Discipline: Architectural
Type - Construction Phase - Phase: New Construction
Type - Classification - Uniclass2015: Pr_20_85_16_11
Material: A_BSUK_Columns_Steel
Pset_ColumnCommon - IsExternal: no; LoadBearing: no
Structural Location - Column Location: N/A
Quantities | Structural - Material Density: 600.000000
BuildingDesignerForm - Cope Flange Clearance: 0.000; Cope Web Clearance: 0.000; Cope Corner Treatment: 0; Cope Corner Radius: 0.000; Local Y Offset: 0.000; Local Z Offset: 0.000
Name | In | Description | StructuralFramingCommon, Section Name | Structural Parameters, Section Name | Length (m) | Area | Cross-sectional (m2) | Area | Cross-sectional Modeled (m2) | Area | Side Surfaces Modeled (Gross) (m2) | Area | All Surfaces Modeled (Net) (m2) | Volume | Perforation(s) (m3) | Volume (Gross) (m3) | Volume (Gross Modeled) (m3) | Volume (Net) (m3) | Volume (Net Modeled) (m3) | Unit Weight | Length x Unit Weight | Volume (Gross) x Density | Volume (Gross Modeled) x Density | Volume (Net) x Density | Volume (Net Modeled) x Density | Fireproofing Thickness (m) | ID | Type ID
A-Columns-Steel | RL | 1 ,SHE_DRAWING+SHEET.dgn,Design Model;5,SHE-13.STEEL.dgn,Design Model:105129 | UC203X203X100 | 1\BS_UC\UC203X203X100 | 5.4468 | 0.0127 | 0.012596 | 6.91417 | 6.93936 | 0 | 0.069174 | 0.068606 | 0.069174 | 0.068606 | 99.600000 | 542.501280 | 41.504616 | 41.163494 | 41.504616 | 41.163494 | 0.02 | Fireproofing - Has Fireproofing: yes; Fire Proofing Type: S-Fireproofing-Cementitious; Fireproofing Material: Cementitious; Fireproofing Part Definition: Fireproofing::Cementitious
A-Columns-Steel | RL | 1 ,SHE_DRAWING+SHEET.dgn,Design Model;5,SHE-13.STEEL.dgn,Design Model:105131 | UC203X203X100 | 1\BS_UC\UC203X203X100 | 5.4468 | 0.0127 | 0.012596 | 6.91417 | 6.93936 | 0 | 0.069174 | 0.068606 | 0.069174 | 0.068606 | 99.600000 | 542.501280 | 41.504616 | 41.163494 | 41.504616 | 41.163494 | 0.02 | Fireproofing - Has Fireproofing: yes; Fire Proofing Type: S-Fireproofing-Cementitious; Fireproofing Material: Cementitious; Fireproofing Part Definition: Fireproofing::Cementitious
A-Columns-Steel | RL | 1 ,SHE_DRAWING+SHEET.dgn,Design Model;5,SHE-13.STEEL.dgn,Design Model:105133 | UC203X203X100 | 1\BS_UC\UC203X203X100 | 5.4468 | 0.0127 | 0.012596 | 6.91417 | 6.93936 | 0 | 0.069174 | 0.068606 | 0.069174 | 0.068606 | 99.600000 | 542.501280 | 41.504616 | 41.163494 | 41.504616 | 41.163494 | 0.02 | Fireproofing - Has Fireproofing: yes; Fire Proofing Type: S-Fireproofing-Cementitious; Fireproofing Material: Cementitious; Fireproofing Part Definition: Fireproofing::Cementitious
A-Columns-Steel | RL | 1 ,SHE_DRAWING+SHEET.dgn,Design Model;5,SHE-13.STEEL.dgn,Design Model:105136 | SHS150X150X5 | 1\BS HYBOX SHS\SHS150X150X5 | 5.4468 | 0.00284 | 0.0029 | 6.31829 | 6.32409 | 0 | 0.015469 | 0.015796 | 0.015469 | 0.015796 | 22.300000 | 121.463640 | 9.281347 | 9.477432 | 9.281347 | 9.477432 | 0.02 | Fireproofing - Has Fireproofing: yes; Fire Proofing Type: S-Fireproofing-Cementitious; Fireproofing Material: Cementitious; Fireproofing Part Definition: Fireproofing::Cementitious
A-Columns-Steel | RL | 1 ,SHE_DRAWING+SHEET.dgn,Design Model;5,SHE-13.STEEL.dgn,Design Model:105139 | RHS200X100X10 | 1\BS CELSIUS RHS\RHS200X100X10 | 5.4468 | 0.00549 | 0.0056 | 6.10042 | 6.11162 | 0 | 0.029903 | 0.030502 | 0.029903 | 0.030502 | 43.100000 | 234.757080 | 17.941759 | 18.301248 | 17.941759 | 18.301248 | 0.02 | Fireproofing - Has Fireproofing: yes; Fire Proofing Type: S-Fireproofing-Cementitious; Fireproofing Material: Cementitious; Fireproofing Part Definition: Fireproofing::Cementitious
A-Columns-Steel | RL | 1 ,SHE_DRAWING+SHEET.dgn,Design Model;5,SHE-13.STEEL.dgn,Design Model:105141 | RHS200X100X10 | 1\BS CELSIUS RHS\RHS200X100X10 | 2.4968 | 0.00549 | 0.0056 | 2.79642 | 2.80762 | 0 | 0.013707 | 0.013982 | 0.013707 | 0.013982 | 43.100000 | 107.612080 | 8.224459 | 8.389248 | 8.224459 | 8.389248 | 0.02 | Fireproofing - Has Fireproofing: yes; Fire Proofing Type: S-Fireproofing-Cementitious; Fireproofing Material: Cementitious; Fireproofing Part Definition: Fireproofing::Cementitious
A-Columns-Steel | RL | 1 ,SHE_DRAWING+SHEET.dgn,Design Model;5,SHE-13.STEEL.dgn,Design Model:105143 | RHS200X100X10 | 1\BS CELSIUS RHS\RHS200X100X10 | 2.7468 | 0.00549 | 0.0056 | 3.07642 | 3.08762 | 0 | 0.01508 | 0.015382 | 0.01508 | 0.015382 | 43.100000 | 118.387080 | 9.047959 | 9.229248 | 9.047959 | 9.229248 | 0.02 | Fireproofing - Has Fireproofing: yes; Fire Proofing Type: S-Fireproofing-Cementitious; Fireproofing Material: Cementitious; Fireproofing Part Definition: Fireproofing::Cementitious
A-Columns-Steel | RL | 1 ,SHE_DRAWING+SHEET.dgn,Design Model;5,SHE-13.STEEL.dgn,Design Model:105145 | RHS200X100X10 | 1\BS CELSIUS RHS\RHS200X100X10 | 5.4468 | 0.00549 | 0.0056 | 6.10042 | 6.11162 | 0 | 0.029903 | 0.030502 | 0.029903 | 0.030502 | 43.100000 | 234.757080 | 17.941759 | 18.301248 | 17.941759 | 18.301248 | 0.02 | Fireproofing - Has Fireproofing: yes; Fire Proofing Type: S-Fireproofing-Cementitious; Fireproofing Material: Cementitious; Fireproofing Part Definition: Fireproofing::Cementitious
A-Columns-Steel | RL | 1 ,SHE_DRAWING+SHEET.dgn,Design Model;5,SHE-13.STEEL.dgn,Design Model:105147 | RHS200X100X10 | 1\BS CELSIUS RHS\RHS200X100X10 | 5.4468 | 0.00549 | 0.0056 | 6.10042 | 6.11162 | 0 | 0.029903 | 0.030502 | 0.029903 | 0.030502 | 43.100000 | 234.757080 | 17.941759 | 18.301248 | 17.941759 | 18.301248 | 0.02 | Fireproofing - Has Fireproofing: yes; Fire Proofing Type: S-Fireproofing-Cementitious; Fireproofing Material: Cementitious; Fireproofing Part Definition: Fireproofing::Cementitious
A2 | RL | 1,SHE_DRAWING+SHEET.dgn ,Design Model;5,SHE-13.STEEL.dgn,Design Model:105150 | UC203X203X127 | 1\BS5950_UC\UC203X203X127 | 2.26935 | 0.0162 | 0.016157 | 2.95515 | 2.84984 | 0.001307 | 0.036763 | 0.036665 | 0.035457 | 0.035358 | 127.500000 | 289.342189 | 22.058087 | 21.998857 | 21.274130 | 21.214900 | 0 | A2
A2 | RL | 1,SHE_DRAWING+SHEET.dgn ,Design Model;5,SHE-13.STEEL.dgn,Design Model:105152 | UC203X203X127 | 1\BS5950_UC\UC203X203X127 | 2.96629 | 0.0162 | 0.016157 | 3.86271 | 3.81432 | 0.0006 | 0.048054 | 0.047925 | 0.047454 | 0.047325 | 127.500000 | 378.202407 | 28.832372 | 28.754951 | 28.472188 | 28.394767 | 0 | A2
A2 | RL | 1,SHE_DRAWING+SHEET.dgn ,Design Model;5,SHE-13.STEEL.dgn,Design Model:105154 | UC203X203X127 | 1\BS5950_UC\UC203X203X127 | 0.969944 | 0.0162 | 0.016157 | 1.26306 | 1.25432 | 0.000309 | 0.015713 | 0.015671 | 0.015404 | 0.015362 | 127.500000 | 123.667890 | 9.427858 | 9.402542 | 9.242540 | 9.217224 | 0 | A2
A2 | RL | 1,SHE_DRAWING+SHEET.dgn ,Design Model;5,SHE-13.STEEL.dgn,Design Model:105156 | UC203X203X127 | 1\BS5950_UC\UC203X203X127 | 0.677619 | 0.0162 | 0.016157 | 0.882395 | 0.816731 | 0.001015 | 0.010977 | 0.010948 | 0.009962 | 0.009933 | 127.500000 | 86.396417 | 6.586456 | 6.568770 | 5.977365 | 5.959679 | 0 | A2
A2 | RL | 1,SHE_DRAWING+SHEET.dgn ,Design Model;5,SHE-13.STEEL.dgn,Design Model:105158 | UC203X203X127 | 1\BS5950_UC\UC203X203X127 | 0.969944 | 0.0162 | 0.016157 | 1.26306 | 1.25432 | 0.000309 | 0.015713 | 0.015671 | 0.015404 | 0.015362 | 127.500000 | 123.667890 | 9.427858 | 9.402542 | 9.242540 | 9.217224 | 0 | A2
A2 | RL | 1,SHE_DRAWING+SHEET.dgn ,Design Model;5,SHE-13.STEEL.dgn,Design Model:105160 | UC203X203X127 | 1\BS5950_UC\UC203X203X127 | 1.80756 | 0.0162 | 0.016156 | 2.35381 | 2.34507 | 0.000309 | 0.029283 | 0.029204 | 0.028974 | 0.028895 | 127.500000 | 230.464369 | 17.569519 | 17.522342 | 17.384201 | 17.337023 | 0 | A2
A2 | RL | 1,SHE_DRAWING+SHEET.dgn ,Design Model;5,SHE-13.STEEL.dgn,Design Model:105162 | UC203X203X127 | 1\BS5950_UC\UC203X203X127 | 0.969944 | 0.0162 | 0.016157 | 1.26306 | 1.25432 | 0.000309 | 0.015713 | 0.015671 | 0.015404 | 0.015362 | 127.500000 | 123.667890 | 9.427858 | 9.402542 | 9.242540 | 9.217224 | 0 | A2
A2 | RL | 1,SHE_DRAWING+SHEET.dgn ,Design Model;5,SHE-13.STEEL.dgn,Design Model:105164 | UC203X203X127 | 1\BS5950_UC\UC203X203X127 | 2.96629 | 0.0162 | 0.016157 | 3.86271 | 3.81432 | 0.0006 | 0.048054 | 0.047925 | 0.047454 | 0.047325 | 127.500000 | 378.202407 | 28.832372 | 28.754951 | 28.472188 | 28.394767 | 0 | A2
A2 | RL | 1,SHE_DRAWING+SHEET.dgn ,Design Model;5,SHE-13.STEEL.dgn,Design Model:105166 | UC203X203X127 | 1\BS5950_UC\UC203X203X127 | 2.26935 | 0.0162 | 0.016157 | 2.95515 | 2.84984 | 0.001307 | 0.036763 | 0.036665 | 0.035457 | 0.035358 | 127.500000 | 289.342189 | 22.058087 | 21.998857 | 21.274130 | 21.214900 | 0 | A2
A2 | RL | 1,SHE_DRAWING+SHEET.dgn ,Design Model;5,SHE-13.STEEL.dgn,Design Model:105168 | UC203X203X127 | 1\BS5950_UC\UC203X203X127 | 0.677495 | 0.0162 | 0.016157 | 0.882234 | 0.81657 | 0.001015 | 0.010975 | 0.010946 | 0.00996 | 0.009931 | 127.500000 | 86.380566 | 6.585248 | 6.567565 | 5.976156 | 5.958474 | 0 | A2
A2 | RL | 1,SHE_DRAWING+SHEET.dgn ,Design Model;5,SHE-13.STEEL.dgn,Design Model:105170 | UC203X203X127 | 1\BS5950_UC\UC203X203X127 | 0.969944 | 0.0162 | 0.016157 | 1.26306 | 1.25432 | 0.000309 | 0.015713 | 0.015671 | 0.015404 | 0.015362 | 127.500000 | 123.667890 | 9.427858 | 9.402542 | 9.242540 | 9.217224 | 0 | A2
A2 | RL | 1,SHE_DRAWING+SHEET.dgn ,Design Model;5,SHE-13.STEEL.dgn,Design Model:105172 | UC203X203X127 | 1\BS5950_UC\UC203X203X127 | 1.80756 | 0.0162 | 0.016156 | 2.35381 | 2.34507 | 0.000309 | 0.029283 | 0.029204 | 0.028974 | 0.028895 | 127.500000 | 230.464369 | 17.569519 | 17.522342 | 17.384201 | 17.337023 | 0 | A2
A2 | RL | 1,SHE_DRAWING+SHEET.dgn ,Design Model;5,SHE-13.STEEL.dgn,Design Model:105174 | UC203X203X127 | 1\BS5950_UC\UC203X203X127 | 0.969944 | 0.0162 | 0.016157 | 1.26306 | 1.25432 | 0.000309 | 0.015713 | 0.015671 | 0.015404 | 0.015362 | 127.500000 | 123.667890 | 9.427858 | 9.402542 | 9.242540 | 9.217224 | 0 | A2
A2 | RL | 1,SHE_DRAWING+SHEET.dgn ,Design Model;5,SHE-13.STEEL.dgn,Design Model:105176 | UC203X203X127 | 1\BS5950_UC\UC203X203X127 | 2.96629 | 0.0162 | 0.016157 | 3.86271 | 3.81432 | 0.0006 | 0.048054 | 0.047925 | 0.047454 | 0.047325 | 127.500000 | 378.202407 | 28.832372 | 28.754951 | 28.472188 | 28.394767 | 0 | A2
A2 | RL | 1,SHE_DRAWING+SHEET.dgn ,Design Model;5,SHE-13.STEEL.dgn,Design Model:105178 | UC203X203X127 | 1\BS5950_UC\UC203X203X127 | 2.26935 | 0.0162 | 0.016157 | 2.95515 | 2.84984 | 0.001307 | 0.036763 | 0.036665 | 0.035457 | 0.035358 | 127.500000 | 289.342189 | 22.058087 | 21.998857 | 21.274130 | 21.214900 | 0 | A2
A2 | RL | 1,SHE_DRAWING+SHEET.dgn ,Design Model;5,SHE-13.STEEL.dgn,Design Model:105180 | UC203X203X127 | 1\BS5950_UC\UC203X203X127 | 0.677619 | 0.0162 | 0.016157 | 0.882395 | 0.816731 | 0.001015 | 0.010977 | 0.010948 | 0.009962 | 0.009933 | 127.500000 | 86.396417 | 6.586456 | 6.568770 | 5.977365 | 5.959679 | 0 | A2
A2 | RL | 1,SHE_DRAWING+SHEET.dgn ,Design Model;5,SHE-13.STEEL.dgn,Design Model:105182 | UC203X203X127 | 1\BS5950_UC\UC203X203X127 | 0.677619 | 0.0162 | 0.016157 | 0.882395 | 0.816731 | 0.001015 | 0.010977 | 0.010948 | 0.009962 | 0.009933 | 127.500000 | 86.396417 | 6.586456 | 6.568770 | 5.977365 | 5.959679 | 0 | A2
A2 | RL | 1,SHE_DRAWING+SHEET.dgn ,Design Model;5,SHE-13.STEEL.dgn,Design Model:105184 | UC203X203X127 | 1\BS5950_UC\UC203X203X127 | 2.26935 | 0.0162 | 0.016157 | 2.95515 | 2.84984 | 0.001307 | 0.036763 | 0.036665 | 0.035457 | 0.035358 | 127.500000 | 289.342189 | 22.058087 | 21.998857 | 21.274130 | 21.214900 | 0 | A2
A2 | RL | 1,SHE_DRAWING+SHEET.dgn ,Design Model;5,SHE-13.STEEL.dgn,Design Model:105186 | UC203X203X127 | 1\BS5950_UC\UC203X203X127 | 2.96629 | 0.0162 | 0.016157 | 3.86271 | 3.81432 | 0.0006 | 0.048054 | 0.047925 | 0.047454 | 0.047325 | 127.500000 | 378.202407 | 28.832372 | 28.754951 | 28.472188 | 28.394767 | 0 | A2
A2 | RL | 1,SHE_DRAWING+SHEET.dgn ,Design Model;5,SHE-13.STEEL.dgn,Design Model:105188 | UC203X203X127 | 1\BS5950_UC\UC203X203X127 | 0.969944 | 0.0162 | 0.016157 | 1.26306 | 1.25432 | 0.000309 | 0.015713 | 0.015671 | 0.015404 | 0.015362 | 127.500000 | 123.667890 | 9.427858 | 9.402542 | 9.242540 | 9.217224 | 0 | A2
A2 | RL | 1,SHE_DRAWING+SHEET.dgn ,Design Model;5,SHE-13.STEEL.dgn,Design Model:105190 | UC203X203X127 | 1\BS5950_UC\UC203X203X127 | 1.80756 | 0.0162 | 0.016157 | 2.35381 | 2.34507 | 0.000309 | 0.029283 | 0.029204 | 0.028974 | 0.028895 | 127.500000 | 230.464369 | 17.569519 | 17.522342 | 17.384201 | 17.337023 | 0 | A2
A2 | RL | 1,SHE_DRAWING+SHEET.dgn ,Design Model;5,SHE-13.STEEL.dgn,Design Model:105192 | UC203X203X127 | 1\BS5950_UC\UC203X203X127 | 0.969944 | 0.0162 | 0.016157 | 1.26306 | 1.25432 | 0.000309 | 0.015713 | 0.015671 | 0.015404 | 0.015362 | 127.500000 | 123.667890 | 9.427858 | 9.402542 | 9.242540 | 9.217224 | 0 | A2
A2 | RL | 1,SHE_DRAWING+SHEET.dgn ,Design Model;5,SHE-13.STEEL.dgn,Design Model:105194 | UC203X203X127 | 1\BS5950_UC\UC203X203X127 | 0.969944 | 0.0162 | 0.016157 | 1.26306 | 1.25432 | 0.000309 | 0.015713 | 0.015671 | 0.015404 | 0.015362 | 127.500000 | 123.667890 | 9.427858 | 9.402542 | 9.242540 | 9.217224 | 0 | A2
A2 | RL | 1,SHE_DRAWING+SHEET.dgn ,Design Model;5,SHE-13.STEEL.dgn,Design Model:105196 | UC203X203X127 | 1\BS5950_UC\UC203X203X127 | 2.96629 | 0.0162 | 0.016157 | 3.86271 | 3.81432 | 0.0006 | 0.048054 | 0.047925 | 0.047454 | 0.047325 | 127.500000 | 378.202407 | 28.832372 | 28.754951 | 28.472188 | 28.394767 | 0 | A2
A2 | RL | 1,SHE_DRAWING+SHEET.dgn ,Design Model;5,SHE-13.STEEL.dgn,Design Model:105198 | UC203X203X127 | 1\BS5950_UC\UC203X203X127 | 0.677619 | 0.0162 | 0.016157 | 0.882395 | 0.816731 | 0.001015 | 0.010977 | 0.010948 | 0.009962 | 0.009933 | 127.500000 | 86.396417 | 6.586456 | 6.568770 | 5.977365 | 5.959679 | 0 | A2
A2 | RL | 1,SHE_DRAWING+SHEET.dgn ,Design Model;5,SHE-13.STEEL.dgn,Design Model:105200 | UC203X203X127 | 1\BS5950_UC\UC203X203X127 | 2.26935 | 0.0162 | 0.016157 | 2.95515 | 2.84984 | 0.001307 | 0.036763 | 0.036665 | 0.035457 | 0.035358 | 127.500000 | 289.342189 | 22.058087 | 21.998857 | 21.274130 | 21.214900 | 0 | A2
A2 | RL | 1,SHE_DRAWING+SHEET.dgn ,Design Model;5,SHE-13.STEEL.dgn,Design Model:105202 | UC203X203X127 | 1\BS5950_UC\UC203X203X127 | 0.969944 | 0.0162 | 0.016157 | 1.26306 | 1.25432 | 0.000309 | 0.015713 | 0.015671 | 0.015404 | 0.015362 | 127.500000 | 123.667890 | 9.427858 | 9.402542 | 9.242540 | 9.217224 | 0 | A2
A2 | RL | 1,SHE_DRAWING+SHEET.dgn ,Design Model;5,SHE-13.STEEL.dgn,Design Model:105204 | UC203X203X127 | 1\BS5950_UC\UC203X203X127 | 1.80756 | 0.0162 | 0.016157 | 2.35381 | 2.34507 | 0.000309 | 0.029283 | 0.029204 | 0.028974 | 0.028895 | 127.500000 | 230.464369 | 17.569519 | 17.522342 | 17.384201 | 17.337023 | 0 | A2
A2 | RL | 1,SHE_DRAWING+SHEET.dgn ,Design Model;5,SHE-13.STEEL.dgn,Design Model:105206 | UC203X203X127 | 1\BS5950_UC\UC203X203X127 | 0.969944 | 0.0162 | 0.016157 | 1.26306 | 1.25432 | 0.000309 | 0.015713 | 0.015671 | 0.015404 | 0.015362 | 127.500000 | 123.667890 | 9.427858 | 9.402542 | 9.242540 | 9.217224 | 0 | A2
A2 | RL | 1,SHE_DRAWING+SHEET.dgn ,Design Model;5,SHE-13.STEEL.dgn,Design Model:105208 | UC203X203X127 | 1\BS5950_UC\UC203X203X127 | 2.96629 | 0.0162 | 0.016157 | 3.86271 | 3.81432 | 0.0006 | 0.048054 | 0.047925 | 0.047454 | 0.047325 | 127.500000 | 378.202407 | 28.832372 | 28.754951 | 28.472188 | 28.394767 | 0 | A2
A2 | RL | 1,SHE_DRAWING+SHEET.dgn ,Design Model;5,SHE-13.STEEL.dgn,Design Model:105210 | UC203X203X127 | 1\BS5950_UC\UC203X203X127 | 2.26935 | 0.0162 | 0.016157 | 2.95515 | 2.84984 | 0.001307 | 0.036763 | 0.036665 | 0.035457 | 0.035358 | 127.500000 | 289.342189 | 22.058087 | 21.998857 | 21.274130 | 21.214900 | 0 | A2
A2 | RL | 1,SHE_DRAWING+SHEET.dgn ,Design Model;5,SHE-13.STEEL.dgn,Design Model:105212 | UC203X203X127 | 1\BS5950_UC\UC203X203X127 | 0.677619 | 0.0162 | 0.016157 | 0.882395 | 0.816731 | 0.001015 | 0.010977 | 0.010948 | 0.009962 | 0.009933 | 127.500000 | 86.396417 | 6.586456 | 6.568770 | 5.977365 | 5.959679 | 0 | A2
A2 | RL | 1,SHE_DRAWING+SHEET.dgn ,Design Model;5,SHE-13.STEEL.dgn,Design Model:105214 | UC203X203X127 | 1\BS5950_UC\UC203X203X127 | 0.672919 | 0.0162 | 0.016157 | 0.876275 | 0.810611 | 0.001015 | 0.010901 | 0.010872 | 0.009886 | 0.009857 | 127.500000 | 85.797167 | 6.540772 | 6.523209 | 5.931681 | 5.914118 | 0 | A2
A2 | RL | 1,SHE_DRAWING+SHEET.dgn ,Design Model;5,SHE-13.STEEL.dgn,Design Model:105216 | UC203X203X127 | 1\BS5950_UC\UC203X203X127 | 2.26935 | 0.0162 | 0.016157 | 2.95515 | 2.84984 | 0.001307 | 0.036763 | 0.036665 | 0.035457 | 0.035358 | 127.500000 | 289.342189 | 22.058087 | 21.998857 | 21.274130 | 21.214900 | 0 | A2
A2 | RL | 1,SHE_DRAWING+SHEET.dgn ,Design Model;5,SHE-13.STEEL.dgn,Design Model:105218 | UC203X203X127 | 1\BS5950_UC\UC203X203X127 | 2.96629 | 0.0162 | 0.016156 | 3.86271 | 3.81432 | 0.0006 | 0.048054 | 0.047925 | 0.047454 | 0.047325 | 127.500000 | 378.202407 | 28.832372 | 28.754951 | 28.472188 | 28.394767 | 0 | A2
A2 | RL | 1,SHE_DRAWING+SHEET.dgn ,Design Model;5,SHE-13.STEEL.dgn,Design Model:105220 | UC203X203X127 | 1\BS5950_UC\UC203X203X127 | 0.969944 | 0.0162 | 0.016157 | 1.26306 | 1.25432 | 0.000309 | 0.015713 | 0.015671 | 0.015404 | 0.015362 | 127.500000 | 123.667890 | 9.427858 | 9.402542 | 9.242540 | 9.217224 | 0 | A2
A2 | RL | 1,SHE_DRAWING+SHEET.dgn ,Design Model;5,SHE-13.STEEL.dgn,Design Model:105222 | UC203X203X127 | 1\BS5950_UC\UC203X203X127 | 0.969944 | 0.0162 | 0.016157 | 1.26306 | 1.25432 | 0.000309 | 0.015713 | 0.015671 | 0.015404 | 0.015362 | 127.500000 | 123.667890 | 9.427858 | 9.402542 | 9.242540 | 9.217224 | 0 | A2
A2 | RL | 1,SHE_DRAWING+SHEET.dgn ,Design Model;5,SHE-13.STEEL.dgn,Design Model:105224 | UC203X203X127 | 1\BS5950_UC\UC203X203X127 | 2.96629 | 0.0162 | 0.016156 | 3.86271 | 3.81432 | 0.0006 | 0.048054 | 0.047925 | 0.047454 | 0.047325 | 127.500000 | 378.202407 | 28.832372 | 28.754951 | 28.472188 | 28.394767 | 0 | A2
A2 | RL | 1,SHE_DRAWING+SHEET.dgn ,Design Model;5,SHE-13.STEEL.dgn,Design Model:105226 | UC203X203X127 | 1\BS5950_UC\UC203X203X127 | 2.26935 | 0.0162 | 0.016156 | 2.95515 | 2.84984 | 0.001307 | 0.036763 | 0.036665 | 0.035457 | 0.035358 | 127.500000 | 289.342189 | 22.058087 | 21.998857 | 21.274130 | 21.214900 | 0 | A2
A2 | RL | 1,SHE_DRAWING+SHEET.dgn ,Design Model;5,SHE-13.STEEL.dgn,Design Model:105228 | UC203X203X127 | 1\BS5950_UC\UC203X203X127 | 0.672919 | 0.0162 | 0.016157 | 0.876275 | 0.810611 | 0.001015 | 0.010901 | 0.010872 | 0.009886 | 0.009857 | 127.500000 | 85.797167 | 6.540772 | 6.523209 | 5.931681 | 5.914118 | 0 | A2
A2 | RL | 1,SHE_DRAWING+SHEET.dgn ,Design Model;5,SHE-13.STEEL.dgn,Design Model:105230 | UC203X203X127 | 1\BS5950_UC\UC203X203X127 | 0.969944 | 0.0162 | 0.016157 | 1.26306 | 1.25432 | 0.000309 | 0.015713 | 0.015671 | 0.015404 | 0.015362 | 127.500000 | 123.667890 | 9.427858 | 9.402542 | 9.242540 | 9.217224 | 0 | A2
A2 | RL | 1,SHE_DRAWING+SHEET.dgn ,Design Model;5,SHE-13.STEEL.dgn,Design Model:105232 | UC203X203X127 | 1\BS5950_UC\UC203X203X127 | 2.96629 | 0.0162 | 0.016156 | 3.86271 | 3.81432 | 0.0006 | 0.048054 | 0.047925 | 0.047454 | 0.047325 | 127.500000 | 378.202407 | 28.832372 | 28.754951 | 28.472188 | 28.394767 | 0 | A2
A2 | RL | 1,SHE_DRAWING+SHEET.dgn ,Design Model;5,SHE-13.STEEL.dgn,Design Model:105234 | UC203X203X127 | 1\BS5950_UC\UC203X203X127 | 2.26935 | 0.0162 | 0.016157 | 2.95515 | 2.84984 | 0.001307 | 0.036763 | 0.036665 | 0.035457 | 0.035358 | 127.500000 | 289.342189 | 22.058087 | 21.998857 | 21.274130 | 21.214900 | 0 | A2
A2 | RL | 1,SHE_DRAWING+SHEET.dgn ,Design Model;5,SHE-13.STEEL.dgn,Design Model:105236 | UC203X203X127 | 1\BS5950_UC\UC203X203X127 | 0.672717 | 0.0162 | 0.016157 | 0.876012 | 0.810348 | 0.001015 | 0.010898 | 0.010869 | 0.009883 | 0.009854 | 127.500000 | 85.771394 | 6.538807 | 6.521250 | 5.929716 | 5.912158 | 0 | A2
A2 | RL | 1,SHE_DRAWING+SHEET.dgn ,Design Model;5,SHE-13.STEEL.dgn,Design Model:105238 | UC203X203X127 | 1\BS5950_UC\UC203X203X127 | 0.672717 | 0.0162 | 0.016157 | 0.876012 | 0.810348 | 0.001015 | 0.010898 | 0.010869 | 0.009883 | 0.009854 | 127.500000 | 85.771394 | 6.538807 | 6.521250 | 5.929716 | 5.912158 | 0 | A2
A2 | RL | 1,SHE_DRAWING+SHEET.dgn ,Design Model;5,SHE-13.STEEL.dgn,Design Model:105240 | UC203X203X127 | 1\BS5950_UC\UC203X203X127 | 2.26935 | 0.0162 | 0.016157 | 2.95515 | 2.84984 | 0.001307 | 0.036763 | 0.036665 | 0.035457 | 0.035358 | 127.500000 | 289.342189 | 22.058087 | 21.998857 | 21.274130 | 21.214900 | 0 | A2
A2 | RL | 1,SHE_DRAWING+SHEET.dgn ,Design Model;5,SHE-13.STEEL.dgn,Design Model:105242 | UC203X203X127 | 1\BS5950_UC\UC203X203X127 | 2.96629 | 0.0162 | 0.016156 | 3.86271 | 3.81432 | 0.0006 | 0.048054 | 0.047925 | 0.047454 | 0.047325 | 127.500000 | 378.202407 | 28.832372 | 28.754951 | 28.472188 | 28.394767 | 0 | A2
A2 | RL | 1,SHE_DRAWING+SHEET.dgn ,Design Model;5,SHE-13.STEEL.dgn,Design Model:105244 | UC203X203X127 | 1\BS5950_UC\UC203X203X127 | 0.969944 | 0.0162 | 0.016157 | 1.26306 | 1.25432 | 0.000309 | 0.015713 | 0.015671 | 0.015404 | 0.015362 | 127.500000 | 123.667890 | 9.427858 | 9.402542 | 9.242540 | 9.217224 | 0 | A2
A2 | RL | 1,SHE_DRAWING+SHEET.dgn ,Design Model;5,SHE-13.STEEL.dgn,Design Model:105246 | UC203X203X127 | 1\BS5950_UC\UC203X203X127 | 2.93867 | 0.0162 | 0.016157 | 3.82673 | 3.76452 | 0.000772 | 0.047606 | 0.047479 | 0.046834 | 0.046707 | 127.500000 | 374.679987 | 28.563839 | 28.487140 | 28.100697 | 28.023997 | 0 | A2
A2 | RL | 1,SHE_DRAWING+SHEET.dgn ,Design Model;5,SHE-13.STEEL.dgn,Design Model:105248 | UC203X203X127 | 1\BS5950_UC\UC203X203X127 | 1.14825 | 0.0162 | 0.016156 | 1.49525 | 1.4747 | 0.000455 | 0.018602 | 0.018552 | 0.018146 | 0.018096 | 127.500000 | 146.401807 | 11.160985 | 11.131015 | 10.887763 | 10.857794 | 0 | A2
A2 | RL | 1,SHE_DRAWING+SHEET.dgn ,Design Model;5,SHE-13.STEEL.dgn,Design Model:105250 | UC203X203X127 | 1\BS5950_UC\UC203X203X127 | 1.06535 | 0.0162 | 0.016156 | 1.3873 | 1.33791 | 0.000813 | 0.017259 | 0.017212 | 0.016445 | 0.016399 | 127.500000 | 135.831917 | 10.355186 | 10.327381 | 9.867264 | 9.839458 | 0 | A2
A2 | RL | 1,SHE_DRAWING+SHEET.dgn ,Design Model;5,SHE-13.STEEL.dgn,Design Model:105266 | UC203X203X127 | 1\BS5950_UC\UC203X203X127 | 2.60108 | 0.0162 | 0.016157 | 3.38713 | 3.29608 | 0.00113 | 0.042138 | 0.042024 | 0.041008 | 0.040895 | 127.500000 | 331.638384 | 25.282550 | 25.214662 | 24.604707 | 24.536818 | 0 | A2
A2 | RL | 1,SHE_DRAWING+SHEET.dgn ,Design Model;5,SHE-13.STEEL.dgn,Design Model:105268 | UC203X203X127 | 1\BS5950_UC\UC203X203X127 | 1.14825 | 0.0162 | 0.016157 | 1.49525 | 1.4747 | 0.000455 | 0.018602 | 0.018552 | 0.018146 | 0.018096 | 127.500000 | 146.401807 | 11.160985 | 11.131015 | 10.887763 | 10.857794 | 0 | A2
A2 | RL | 1,SHE_DRAWING+SHEET.dgn ,Design Model;5,SHE-13.STEEL.dgn,Design Model:105270 | UC203X203X127 | 1\BS5950_UC\UC203X203X127 | 2.93867 | 0.0162 | 0.016157 | 3.82673 | 3.76452 | 0.000772 | 0.047606 | 0.047479 | 0.046834 | 0.046707 | 127.500000 | 374.679987 | 28.563839 | 28.487140 | 28.100697 | 28.023997 | 0 | A2
A2 | RL | 1,SHE_DRAWING+SHEET.dgn ,Design Model;5,SHE-13.STEEL.dgn,Design Model:105272 | UC203X203X127 | 1\BS5950_UC\UC203X203X127 | 2.60108 | 0.0162 | 0.016156 | 3.38713 | 3.29608 | 0.00113 | 0.042138 | 0.042024 | 0.041008 | 0.040895 | 127.500000 | 331.638384 | 25.282550 | 25.214661 | 24.604707 | 24.536818 | 0 | A2
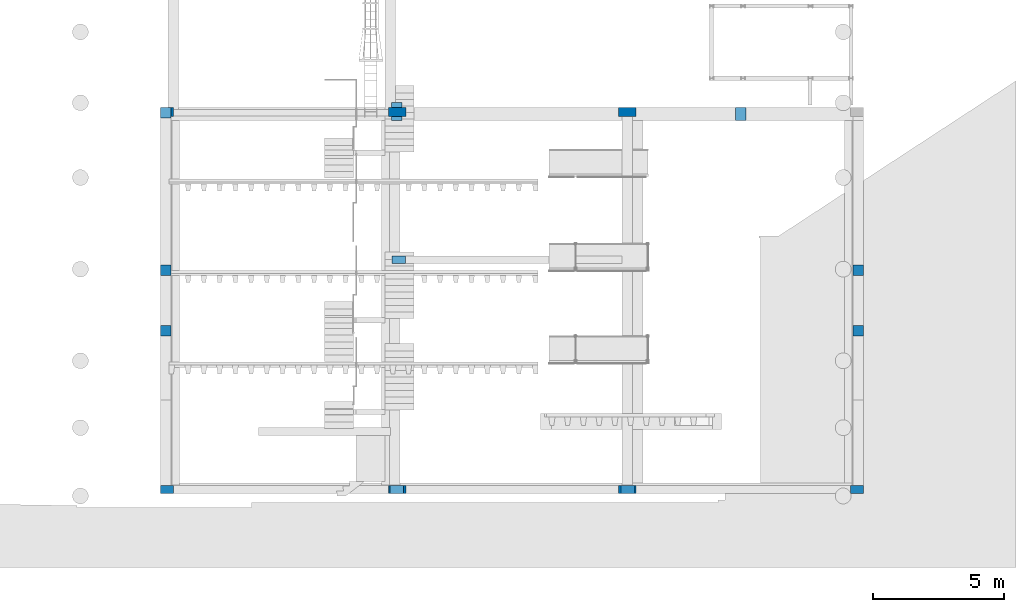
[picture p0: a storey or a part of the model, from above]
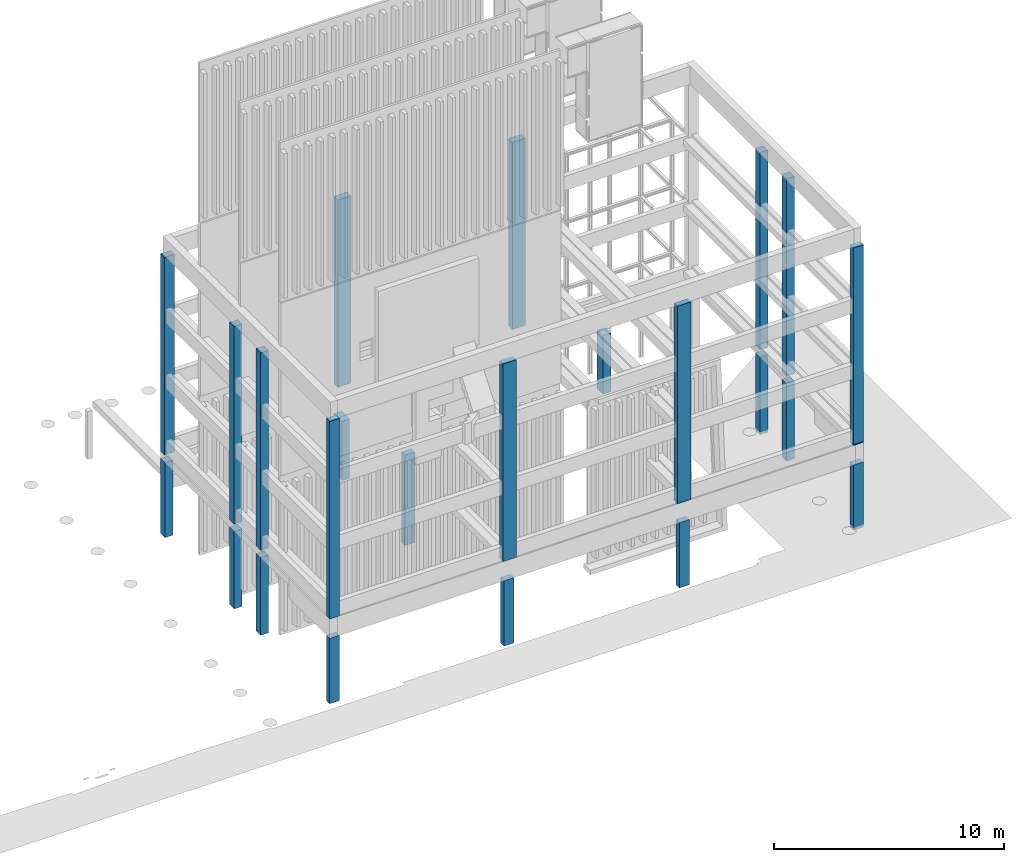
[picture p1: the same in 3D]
Properties of the parts of a building model (IFC2X3), part 4 of 16

# IfcDoor: A-Doors-SingleFlush (24)
Type - Door Parameters - Parametric | File Type: PAZ; Parametric | File Name: DoorSingleFlush; Dimension | Leaf Width: 0.826 m; Dimension | Height: 2.058 m; Dimension | Frame Depth: 0.095 m; Dimension | Frame Depth Match Wall: yes; Dimension | Architrave Width: 0.069 m; Dimension | Leaf Thickness: 0.04 m
Type - Door - Door | Type: F - Flush; Door | IsEgress: no; Frame | Material: HM
Type - Discipline - Discipline: Architectural
Type - Classification - Uniclass2015: Pr_30_59_23
OverallHeight: 2.169 m; Material: A_BSUK_Doors
Pset_DoorCommon - FireExit: no
Door Parameters - Dimension | Height: 2.1 m; Dimension | Frame Depth Match Wall: no
Door - Door | Finish: white; Door | Under Cut: 0 m; Glazing: no; Louver: no
Construction Phase - Phase: New Construction
Name | In | Description | OverallWidth (m) | ID | Number | ID | Description | Dimension | Leaf Width (m)
1.06 | 02 | bedroom :1 ,SHE_DRAWING+SHEET.dgn,Design Model;4,SHE-03.FIRST.dgn,Design Model:137121 | 1.038 | 1.06 | bedroom | 0.9
1.16 | RL | bedroom :1 ,SHE_DRAWING+SHEET.dgn,Design Model;4,SHE-03.FIRST.dgn,Design Model:138669 | 1.038 | 1.16 | bedroom | 0.9
1.11 | RL | bathroom :1 ,SHE_DRAWING+SHEET.dgn,Design Model;4,SHE-03.FIRST.dgn,Design Model:142544 | 0.888 | 1.11 | bathroom | 0.75
1.13 | RL | bathroom :1 ,SHE_DRAWING+SHEET.dgn,Design Model;4,SHE-03.FIRST.dgn,Design Model:136863 | 0.888 | 1.13 | bathroom | 0.75
1.24 | RL | storage :1 ,SHE_DRAWING+SHEET.dgn,Design Model;4,SHE-03.FIRST.dgn,Design Model:172500 | 0.888 | 1.24 | storage | 0.75
1.26 | RL | bathroom :1 ,SHE_DRAWING+SHEET.dgn,Design Model;4,SHE-03.FIRST.dgn,Design Model:172809 | 0.888 | 1.26 | bathroom | 0.75
1.25 | RL | bedroom :1 ,SHE_DRAWING+SHEET.dgn,Design Model;4,SHE-03.FIRST.dgn,Design Model:176072 | 1.038 | 1.25 | bedroom | 0.9
1.22 | RL | bathroom :1 ,SHE_DRAWING+SHEET.dgn,Design Model;4,SHE-03.FIRST.dgn,Design Model:241330 | 0.888 | 1.22 | bathroom | 0.75
3.06 | 16 | bedroom :1 ,SHE_DRAWING+SHEET.dgn,Design Model;6,SHE-05.THIRD.dgn,Design Model:137121 | 1.038 | 3.06 | bedroom | 0.9
3.16 | RL | bedroom :1 ,SHE_DRAWING+SHEET.dgn,Design Model;6,SHE-05.THIRD.dgn,Design Model:138669 | 1.038 | 3.16 | bedroom | 0.9
3.11 | RL | bathroom :1 ,SHE_DRAWING+SHEET.dgn,Design Model;6,SHE-05.THIRD.dgn,Design Model:142544 | 0.888 | 3.11 | bathroom | 0.75
3.13 | RL | bathroom :1 ,SHE_DRAWING+SHEET.dgn,Design Model;6,SHE-05.THIRD.dgn,Design Model:136863 | 0.888 | 3.13 | bathroom | 0.75
3.24 | RL | storage :1 ,SHE_DRAWING+SHEET.dgn,Design Model;6,SHE-05.THIRD.dgn,Design Model:172500 | 0.888 | 3.24 | storage | 0.75
3.26 | RL | bathroom :1 ,SHE_DRAWING+SHEET.dgn,Design Model;6,SHE-05.THIRD.dgn,Design Model:172809 | 0.888 | 3.26 | bathroom | 0.75
3.25 | RL | bedroom :1 ,SHE_DRAWING+SHEET.dgn,Design Model;6,SHE-05.THIRD.dgn,Design Model:176072 | 1.038 | 3.25 | bedroom | 0.9
3.22 | RL | bathroom :1 ,SHE_DRAWING+SHEET.dgn,Design Model;6,SHE-05.THIRD.dgn,Design Model:241330 | 0.888 | 3.22 | bathroom | 0.75
2.06 | 09 | bedroom :1 ,SHE_DRAWING+SHEET.dgn,Design Model;18,SHE-04.SECOND.dgn,Design Model:137121 | 1.038 | 2.06 | bedroom | 0.9
2.16 | RL | bedroom :1 ,SHE_DRAWING+SHEET.dgn,Design Model;18,SHE-04.SECOND.dgn,Design Model:138669 | 1.038 | 2.16 | bedroom | 0.9
2.11 | RL | bathroom :1 ,SHE_DRAWING+SHEET.dgn,Design Model;18,SHE-04.SECOND.dgn,Design Model:142544 | 0.888 | 2.11 | bathroom | 0.75
2.13 | RL | bathroom :1 ,SHE_DRAWING+SHEET.dgn,Design Model;18,SHE-04.SECOND.dgn,Design Model:136863 | 0.888 | 2.13 | bathroom | 0.75
2.24 | RL | storage :1 ,SHE_DRAWING+SHEET.dgn,Design Model;18,SHE-04.SECOND.dgn,Design Model:172500 | 0.888 | 2.24 | storage | 0.75
2.26 | RL | bathroom :1 ,SHE_DRAWING+SHEET.dgn,Design Model;18,SHE-04.SECOND.dgn,Design Model:172809 | 0.888 | 2.26 | bathroom | 0.75
2.25 | RL | bedroom :1 ,SHE_DRAWING+SHEET.dgn,Design Model;18,SHE-04.SECOND.dgn,Design Model:176072 | 1.038 | 2.25 | bedroom | 0.9
2.22 | RL | bathroom :1 ,SHE_DRAWING+SHEET.dgn,Design Model;18,SHE-04.SECOND.dgn,Design Model:241330 | 0.888 | 2.22 | bathroom | 0.75

# IfcDoor: A-Doors-SingleFlush, 0.19
In: RL
Type - OperationType: SINGLE_SWING_RIGHT; ConstructionType: USERDEFINED; ParameterTakesPrecedence: no; Sizeable: no
Type - Lining - LiningDepth: 0.118 m; LiningThickness: 0.069 m
Type - Thermal Transmittance - Is External: no; Is Below Grade: no
Type - Fire Resistance - Fire | IsCombustible: no; Fire | Compartmentation: no
Type - Door Parameters - Parametric | File Type: PAZ; Parametric | File Name: DoorSingleFlush; Dimension | Leaf Width: 0.826 m; Dimension | Height: 2.058 m; Dimension | Frame Depth: 0.118 m; Dimension | Frame Depth Match Wall: yes; Dimension | Architrave Width: 0.069 m; Dimension | Leaf Thickness: 0.04 m
Type - Door - Door | Type: F - Flush; Door | IsEgress: no; Frame | Material: HM
Type - Discipline - Discipline: Architectural
Type - Classification - Uniclass2015: Pr_30_59_23
Description: bathroom :1 ,SHE_DRAWING+SHEET.dgn,Design Model;2,SHE-02.MEZZANINE.dgn,Design Model:94569; OverallHeight: 2.1 m; OverallWidth: 0.734 m; Material: A_BSUK_Doors
Pset_DoorCommon - FireExit: no
Identification - ID | Number: 0.19; ID | Description: bathroom
Door Parameters - Dimension | Leaf Width: 0.65 m
Door - Door | Finish: white; Door | Under Cut: 0 m; Glazing: no; Louver: no
Construction Phase - Phase: New Construction

# IfcDoor: A-Doors-SingleFlush, 0.21
In: RL
Type - OperationType: SINGLE_SWING_RIGHT; ConstructionType: USERDEFINED; ParameterTakesPrecedence: no; Sizeable: no
Type - Lining - LiningDepth: 0.12 m; LiningThickness: 0.069 m
Type - Thermal Transmittance - Is External: no; Is Below Grade: no
Type - Fire Resistance - Fire | IsCombustible: no; Fire | Compartmentation: no
Type - Door Parameters - Parametric | File Type: PAZ; Parametric | File Name: DoorSingleFlush; Dimension | Leaf Width: 0.826 m; Dimension | Height: 2.058 m; Dimension | Frame Depth: 0.12 m; Dimension | Frame Depth Match Wall: yes; Dimension | Architrave Width: 0.069 m; Dimension | Leaf Thickness: 0.04 m
Type - Door - Door | Type: F - Flush; Door | IsEgress: no; Frame | Material: HM
Type - Discipline - Discipline: Architectural
Type - Classification - Uniclass2015: Pr_30_59_23
Description: bathroom :1 ,SHE_DRAWING+SHEET.dgn,Design Model;2,SHE-02.MEZZANINE.dgn,Design Model:96528; OverallHeight: 2.1 m; OverallWidth: 0.814003 m; Material: A_BSUK_Doors
Pset_DoorCommon - FireExit: no
Identification - ID | Number: 0.21; ID | Description: bathroom
Door Parameters - Dimension | Leaf Width: 0.73 m
Door - Door | Finish: white; Door | Under Cut: 0 m; Glazing: no; Louver: no
Construction Phase - Phase: New Construction

# IfcDoor: A-Doors-SingleFlush (2)
In: RL
Type - OperationType: SINGLE_SWING_RIGHT; ConstructionType: USERDEFINED; ParameterTakesPrecedence: no; Sizeable: no
Type - Lining - LiningDepth: 0.131 m; LiningThickness: 0.069 m
Type - Thermal Transmittance - Is External: no; Is Below Grade: no
Type - Fire Resistance - Fire | IsCombustible: no; Fire | Compartmentation: no
Type - Door Parameters - Parametric | File Type: PAZ; Parametric | File Name: DoorSingleFlush; Dimension | Leaf Width: 0.826 m; Dimension | Height: 2.058 m; Dimension | Frame Depth: 0.131 m; Dimension | Frame Depth Match Wall: yes; Dimension | Architrave Width: 0.069 m; Dimension | Leaf Thickness: 0.04 m
Type - Door - Door | Type: F - Flush; Door | IsEgress: no; Frame | Material: HM
Type - Discipline - Discipline: Architectural
Type - Classification - Uniclass2015: Pr_30_59_23
OverallHeight: 2.1 m; Material: A_BSUK_Doors
Pset_DoorCommon - FireExit: no
Door - Door | Finish: white; Door | Under Cut: 0 m; Glazing: no; Louver: no
Construction Phase - Phase: New Construction
Name | Description | OverallWidth (m) | ID | Number | ID | Description | Dimension | Leaf Width (m)
0.09 | stair :1 ,SHE_DRAWING+SHEET.dgn,Design Model;1,SHE-01.GROUND.dgn,Design Model:102581 | 0.984 | 0.09 | stair | 0.9
0.10 | storage :1 ,SHE_DRAWING+SHEET.dgn,Design Model;1,SHE-01.GROUND.dgn,Design Model:102839 | 0.834 | 0.10 | storage | 0.75

# IfcDoor: A-Doors-SingleFlush (2)
In: RL
Type - OperationType: SINGLE_SWING_RIGHT; ConstructionType: USERDEFINED; ParameterTakesPrecedence: no; Sizeable: no
Type - Lining - LiningDepth: 0.2 m; LiningThickness: 0.069 m
Type - Thermal Transmittance - Is External: no; Is Below Grade: no
Type - Fire Resistance - Fire | IsCombustible: no; Fire | Compartmentation: no
Type - Door Parameters - Parametric | File Type: PAZ; Parametric | File Name: DoorSingleFlush; Dimension | Leaf Width: 0.826 m; Dimension | Height: 2.058 m; Dimension | Frame Depth: 0.2 m; Dimension | Frame Depth Match Wall: yes; Dimension | Architrave Width: 0.069 m; Dimension | Leaf Thickness: 0.04 m
Type - Door - Door | Type: F - Flush; Door | IsEgress: no; Frame | Material: HM
Type - Discipline - Discipline: Architectural
Type - Classification - Uniclass2015: Pr_30_59_23
Material: A_BSUK_Doors
Pset_DoorCommon - FireExit: no; FireRating: FD30S
Identification - ID | Description: flat entrance
Fire Resistance - Fire | Rating: FD30S
Door Parameters - Dimension | Leaf Width: 1 m; Dimension | Height: 2.1 m; Dimension | Frame Depth Match Wall: no
Door - Door | Finish: french oak veneer; Door | Under Cut: 0 m; Glazing: no; Louver: no
Construction Phase - Phase: New Construction
Name | Description | OverallHeight (m) | OverallWidth (m) | ID | Number
4.18 | flat entrance :1 ,SHE_DRAWING+SHEET.dgn,Design Model;7,SHE-06.FOURTH.dgn,Design Model:104284 | 2.169 | 1.138 | 4.18
4.25 | flat entrance :1 ,SHE_DRAWING+SHEET.dgn,Design Model;7,SHE-06.FOURTH.dgn,Design Model:197915 | 2.142 | 1.084 | 4.25

# IfcDoor: A-Doors-SingleFlush (9)
Type - OperationType: SINGLE_SWING_RIGHT; ConstructionType: USERDEFINED; ParameterTakesPrecedence: no; Sizeable: no
Type - Lining - LiningDepth: 0.225 m; LiningThickness: 0.069 m
Type - Thermal Transmittance - Is External: no; Is Below Grade: no
Type - Fire Resistance - Fire | IsCombustible: no; Fire | Compartmentation: no
Type - Door Parameters - Parametric | File Type: PAZ; Parametric | File Name: DoorSingleFlush; Dimension | Leaf Width: 0.826 m; Dimension | Height: 2.058 m; Dimension | Frame Depth: 0.225 m; Dimension | Frame Depth Match Wall: yes; Dimension | Architrave Width: 0.069 m; Dimension | Leaf Thickness: 0.04 m
Type - Door - Door | Type: F - Flush; Door | IsEgress: no; Frame | Material: HM
Type - Discipline - Discipline: Architectural
Type - Classification - Uniclass2015: Pr_30_59_23
OverallHeight: 2.169 m; OverallWidth: 1.138 m; Material: A_BSUK_Doors
Pset_DoorCommon - FireExit: no; FireRating: FD30S
Identification - ID | Description: flat entrance
Fire Resistance - Fire | Rating: FD30S
Door Parameters - Dimension | Leaf Width: 1 m; Dimension | Height: 2.1 m; Dimension | Frame Depth Match Wall: no
Door - Door | Finish: french oak veneer; Door | Under Cut: 0 m; Glazing: no; Louver: no
Construction Phase - Phase: New Construction
Name | In | Description | ID | Number
1.10 | RL | flat entrance :1 ,SHE_DRAWING+SHEET.dgn,Design Model;4,SHE-03.FIRST.dgn,Design Model:132330 | 1.10
1.09 | 02 | flat entrance :1 ,SHE_DRAWING+SHEET.dgn,Design Model;4,SHE-03.FIRST.dgn,Design Model:141106 | 1.09
1.27 | RL | flat entrance :1 ,SHE_DRAWING+SHEET.dgn,Design Model;4,SHE-03.FIRST.dgn,Design Model:141624 | 1.27
3.10 | RL | flat entrance :1 ,SHE_DRAWING+SHEET.dgn,Design Model;6,SHE-05.THIRD.dgn,Design Model:132330 | 3.10
3.09 | 16 | flat entrance :1 ,SHE_DRAWING+SHEET.dgn,Design Model;6,SHE-05.THIRD.dgn,Design Model:141106 | 3.09
3.27 | RL | flat entrance :1 ,SHE_DRAWING+SHEET.dgn,Design Model;6,SHE-05.THIRD.dgn,Design Model:141624 | 3.27
2.10 | RL | flat entrance :1 ,SHE_DRAWING+SHEET.dgn,Design Model;18,SHE-04.SECOND.dgn,Design Model:132330 | 2.10
2.09 | 09 | flat entrance :1 ,SHE_DRAWING+SHEET.dgn,Design Model;18,SHE-04.SECOND.dgn,Design Model:141106 | 2.09
2.27 | RL | flat entrance :1 ,SHE_DRAWING+SHEET.dgn,Design Model;18,SHE-04.SECOND.dgn,Design Model:141624 | 2.27

# IfcDoor: A-Doors-SingleFlush (3)
Type - OperationType: SINGLE_SWING_RIGHT; ConstructionType: USERDEFINED; ParameterTakesPrecedence: no; Sizeable: no
Type - Lining - LiningDepth: 0.25 m; LiningThickness: 0.069 m
Type - Thermal Transmittance - Is External: no; Is Below Grade: no
Type - Fire Resistance - Fire | IsCombustible: no; Fire | Compartmentation: no
Type - Door Parameters - Parametric | File Type: PAZ; Parametric | File Name: DoorSingleFlush; Dimension | Leaf Width: 0.826 m; Dimension | Height: 2.058 m; Dimension | Frame Depth: 0.25 m; Dimension | Frame Depth Match Wall: yes; Dimension | Architrave Width: 0.069 m; Dimension | Leaf Thickness: 0.04 m
Type - Door - Door | Type: F - Flush; Door | IsEgress: no; Frame | Material: HM
Type - Discipline - Discipline: Architectural
Type - Classification - Uniclass2015: Pr_30_59_23
OverallHeight: 2.169 m; OverallWidth: 0.888 m; Material: A_BSUK_Doors
Pset_DoorCommon - FireExit: no
Identification - ID | Description: bathroom
Door Parameters - Dimension | Leaf Width: 0.75 m; Dimension | Height: 2.1 m; Dimension | Frame Depth Match Wall: no
Door - Door | Finish: white; Door | Under Cut: 0 m; Glazing: no; Louver: no
Construction Phase - Phase: New Construction
Name | In | Description | ID | Number
1.08 | 02 | bathroom :1 ,SHE_DRAWING+SHEET.dgn,Design Model;4,SHE-03.FIRST.dgn,Design Model:140141 | 1.08
3.08 | 16 | bathroom :1 ,SHE_DRAWING+SHEET.dgn,Design Model;6,SHE-05.THIRD.dgn,Design Model:140141 | 3.08
2.08 | 09 | bathroom :1 ,SHE_DRAWING+SHEET.dgn,Design Model;18,SHE-04.SECOND.dgn,Design Model:140141 | 2.08

# IfcDoor: A-Doors-SingleVisionPanels, 0.13
In: RL
Type - OperationType: SINGLE_SWING_LEFT; ConstructionType: USERDEFINED; ParameterTakesPrecedence: no; Sizeable: no
Type - Lining - LiningDepth: 0.1 m; LiningThickness: 0.069 m
Type - Thermal Transmittance - Is External: no; Is Below Grade: no
Type - Fire Resistance - Fire | IsCombustible: no; Fire | Compartmentation: no
Type - Door Parameters - Parametric | File Type: PAZ; Parametric | File Name: DoorSingle2Lites; Dimension | Leaf Width: 0.826 m; Dimension | Height: 2.058 m; Dimension | Frame Depth: 0.1 m; Dimension | Frame Depth Match Wall: yes; Dimension | Architrave Width: 0.069 m; Dimension | Leaf Thickness: 0.04 m
Type - Door - Door | Type: 2G - 2 Lite; Door | IsEgress: no; Glazing: yes; Frame | Material: HM
Type - Discipline - Discipline: Architectural
Type - Classification - Uniclass2015: Pr_30_59_23
Description: entrance - commercial unit :1,SHE_DRAWING+SHEET.dgn,Design Model;1 ,SHE-01.GROUND.dgn,Design Model:119205; OverallHeight: 2.172 m; OverallWidth: 1.134 m; Material: A_BSUK_Doors
Pset_DoorCommon - FireExit: no
Identification - ID | Number: 0.13; ID | Description: entrance - commercial unit; ID | Keynote: security - Part Q / PAS24 compliance
Door Parameters - Dimension | Leaf Width: 1.05 m; Dimension | Height: 2.13 m
Door - Door | Finish: RAL 9017 - traffic black matt textured; Door | Under Cut: 0 m; Louver: no
Construction Phase - Phase: New Construction

# IfcDoor: A-Doors-SingleVisionPanels (3)
In: RL
Type - OperationType: SINGLE_SWING_LEFT; ConstructionType: USERDEFINED; ParameterTakesPrecedence: no; Sizeable: no
Type - Lining - LiningDepth: 0.17 m; LiningThickness: 0.069 m
Type - Thermal Transmittance - Is External: no; Is Below Grade: no
Type - Fire Resistance - Fire | IsCombustible: no; Fire | Compartmentation: no
Type - Door Parameters - Parametric | File Type: PAZ; Parametric | File Name: DoorSingle2Lites; Dimension | Leaf Width: 0.826 m; Dimension | Height: 2.058 m; Dimension | Frame Depth: 0.17 m; Dimension | Frame Depth Match Wall: yes; Dimension | Architrave Width: 0.069 m; Dimension | Leaf Thickness: 0.04 m
Type - Door - Door | Type: 2G - 2 Lite; Door | IsEgress: no; Glazing: yes; Frame | Material: HM
Type - Discipline - Discipline: Architectural
Type - Classification - Uniclass2015: Pr_30_59_23
OverallHeight: 2.169 m; OverallWidth: 1.038 m; Material: A_BSUK_Doors
Pset_DoorCommon - FireExit: no; FireRating: FD30S
Identification - ID | Description: hall with vision panel; ID | Keynote: FIRE DOOR KEEP CLOSED
Fire Resistance - Fire | Rating: FD30S
Door Parameters - Dimension | Leaf Width: 0.9 m; Dimension | Height: 2.1 m; Dimension | Frame Depth Match Wall: no
Door - Door | Finish: white; Door | Under Cut: 0 m; Louver: no
Construction Phase - Phase: New Construction
Name | Description | ID | Number
1.02 | hall with vision panel :1 ,SHE_DRAWING+SHEET.dgn,Design Model;4,SHE-03.FIRST.dgn,Design Model:140403 | 1.02
3.02 | hall with vision panel :1 ,SHE_DRAWING+SHEET.dgn,Design Model;6,SHE-05.THIRD.dgn,Design Model:140403 | 3.02
2.02 | hall with vision panel :1 ,SHE_DRAWING+SHEET.dgn,Design Model;18,SHE-04.SECOND.dgn,Design Model:140403 | 2.02

# IfcDoor: A-Doors-SingleVisionPanels, 4.02
In: RL
Type - OperationType: SINGLE_SWING_LEFT; ConstructionType: USERDEFINED; ParameterTakesPrecedence: no; Sizeable: no
Type - Lining - LiningDepth: 0.2 m; LiningThickness: 0.069 m
Type - Thermal Transmittance - Is External: no; Is Below Grade: no
Type - Fire Resistance - Fire | IsCombustible: no; Fire | Compartmentation: no
Type - Door Parameters - Parametric | File Type: PAZ; Parametric | File Name: DoorSingle2Lites; Dimension | Leaf Width: 0.826 m; Dimension | Height: 2.058 m; Dimension | Frame Depth: 0.2 m; Dimension | Frame Depth Match Wall: yes; Dimension | Architrave Width: 0.069 m; Dimension | Leaf Thickness: 0.04 m
Type - Door - Door | Type: 2G - 2 Lite; Door | IsEgress: no; Glazing: yes; Frame | Material: HM
Type - Discipline - Discipline: Architectural
Type - Classification - Uniclass2015: Pr_30_59_23
Description: hall with vision panel :1 ,SHE_DRAWING+SHEET.dgn,Design Model;7,SHE-06.FOURTH.dgn,Design Model:194839; OverallHeight: 2.169 m; OverallWidth: 1.038 m; Material: A_BSUK_Doors
Pset_DoorCommon - FireExit: no; FireRating: FD30S
Identification - ID | Number: 4.02; ID | Description: hall with vision panel; ID | Keynote: FIRE DOOR KEEP CLOSED
Fire Resistance - Fire | Rating: FD30S
Door Parameters - Dimension | Leaf Width: 0.9 m; Dimension | Height: 2.1 m; Dimension | Frame Depth Match Wall: no
Door - Door | Finish: white; Door | Under Cut: 0 m; Louver: no
Construction Phase - Phase: New Construction

# IfcDoor: A-Doors-SingleVisionPanels (5)
In: RL
Type - OperationType: SINGLE_SWING_RIGHT; ConstructionType: USERDEFINED; ParameterTakesPrecedence: no; Sizeable: no
Type - Lining - LiningDepth: 0.1 m; LiningThickness: 0.069 m
Type - Thermal Transmittance - Is External: no; Is Below Grade: no
Type - Fire Resistance - Fire | IsCombustible: no; Fire | Compartmentation: no
Type - Door Parameters - Parametric | File Type: PAZ; Parametric | File Name: DoorSingle2Lites; Dimension | Leaf Width: 0.826 m; Dimension | Height: 2.058 m; Dimension | Frame Depth: 0.1 m; Dimension | Frame Depth Match Wall: yes; Dimension | Architrave Width: 0.069 m; Dimension | Leaf Thickness: 0.04 m
Type - Door - Door | Type: 2G - 2 Lite; Door | IsEgress: no; Glazing: yes; Frame | Material: HM
Type - Discipline - Discipline: Architectural
Type - Classification - Uniclass2015: Pr_30_59_23
Material: A_BSUK_Doors
Pset_DoorCommon - FireExit: no
Door - Door | Under Cut: 0 m; Louver: no
Construction Phase - Phase: New Construction
Name | Description | OverallHeight (m) | OverallWidth (m) | ID | Number | ID | Description | ID | Keynote | Dimension | Leaf Width (m) | Dimension | Height (m) | Door | Finish | FireRating = Fire | Rating | Dimension | Frame Depth Match Wall
0.14 | entrance - commercial unit :1,SHE_DRAWING+SHEET.dgn,Design Model;1 ,SHE-01.GROUND.dgn,Design Model:122638 | 2.172 | 1.134 | 0.14 | entrance - commercial unit | security - Part Q / PAS24 compliance | 1.05 | 2.13 | RAL 9017 - traffic black matt textured
1.04 | stair with vision panel :1 ,SHE_DRAWING+SHEET.dgn,Design Model;4,SHE-03.FIRST.dgn,Design Model:138927 | 2.169 | 1.038 | 1.04 | stair with vision panel | FIRE DOOR KEEP CLOSED | 0.9 | 2.1 | white | FD60S | no
3.04 | stair with vision panel :1 ,SHE_DRAWING+SHEET.dgn,Design Model;6,SHE-05.THIRD.dgn,Design Model:138927 | 2.169 | 1.038 | 3.04 | stair with vision panel | FIRE DOOR KEEP CLOSED | 0.9 | 2.1 | white | FD60S | no
4.04 | stair with vision panel :1 ,SHE_DRAWING+SHEET.dgn,Design Model;7,SHE-06.FOURTH.dgn,Design Model:190650 | 2.169 | 1.038 | 4.04 | stair with vision panel | FIRE DOOR KEEP CLOSED | 0.9 | 2.1 | white | FD60S | no
2.04 | stair with vision panel :1 ,SHE_DRAWING+SHEET.dgn,Design Model;18,SHE-04.SECOND.dgn,Design Model:138927 | 2.169 | 1.038 | 2.04 | stair with vision panel | FIRE DOOR KEEP CLOSED | 0.9 | 2.1 | white | FD60S | no

# IfcDoor: A-Doors-SingleVisionPanels (4)
In: RL
Type - OperationType: SINGLE_SWING_RIGHT; ConstructionType: USERDEFINED; ParameterTakesPrecedence: no; Sizeable: no
Type - Lining - LiningDepth: 0.17 m; LiningThickness: 0.069 m
Type - Thermal Transmittance - Is External: no; Is Below Grade: no
Type - Fire Resistance - Fire | IsCombustible: no; Fire | Compartmentation: no
Type - Door Parameters - Parametric | File Type: PAZ; Parametric | File Name: DoorSingle2Lites; Dimension | Leaf Width: 0.826 m; Dimension | Height: 2.058 m; Dimension | Frame Depth: 0.17 m; Dimension | Frame Depth Match Wall: yes; Dimension | Architrave Width: 0.069 m; Dimension | Leaf Thickness: 0.04 m
Type - Door - Door | Type: 2G - 2 Lite; Door | IsEgress: no; Glazing: yes; Frame | Material: HM
Type - Discipline - Discipline: Architectural
Type - Classification - Uniclass2015: Pr_30_59_23
OverallHeight: 2.169 m; OverallWidth: 1.038 m; Material: A_BSUK_Doors
Pset_DoorCommon - FireExit: no; FireRating: FD30S
Identification - ID | Description: hall with vision panel; ID | Keynote: FIRE DOOR KEEP CLOSED
Fire Resistance - Fire | Rating: FD30S
Door Parameters - Dimension | Leaf Width: 0.9 m; Dimension | Height: 2.1 m; Dimension | Frame Depth Match Wall: no
Door - Door | Finish: white; Door | Under Cut: 0 m; Louver: no
Construction Phase - Phase: New Construction
Name | Description | ID | Number
1.01 | hall with vision panel :1 ,SHE_DRAWING+SHEET.dgn,Design Model;4,SHE-03.FIRST.dgn,Design Model:139747 | 1.01
3.01 | hall with vision panel :1 ,SHE_DRAWING+SHEET.dgn,Design Model;6,SHE-05.THIRD.dgn,Design Model:139747 | 3.01
4.01 | hall with vision panel :1 ,SHE_DRAWING+SHEET.dgn,Design Model;7,SHE-06.FOURTH.dgn,Design Model:191470 | 4.01
2.01 | hall with vision panel :1 ,SHE_DRAWING+SHEET.dgn,Design Model;18,SHE-04.SECOND.dgn,Design Model:139747 | 2.01

# IfcDoor: A-ElevatorCallButton
In: RL
Type - Description: Elevator Call Button; ConstructionType: USERDEFINED; ParameterTakesPrecedence: no; Sizeable: no
Type - Lining - LiningDepth: 0 m; LiningThickness: 0.002 m
Type - Parametric Definition - Parametric | File Type: PAZ; Parametric | File Name: Elev_CallButton
Type - Identification - ID | Description: Elevator Call Button
Type - Elevator Door - Frame | Thickness: 0.002 m; Frame | Depth: 0 m
Description: Elevator Call Button :1,SHE_DRAWING+SHEET.dgn,Design Model;1 ,SHE-01.GROUND.dgn,Design Model:94580; OverallHeight: 0.2794 m; OverallWidth: 0.127 m; Material: A_BSUK_Doors
Elevator Door - Lift Door | Width: 0 m; Lift Door | Height: 0 m; Frame | Head Thickness: 0 m; Lift Door | Side Offset: 0 m; Frame | Return Thickness: 0 m; Lift Cab | Height: 0 m; Lift Cab | Width: 0 m; Lift Cab | Side Wall Thickness: 0 m; Lift Cab | Depth: 0 m; Lift Cab | Door Thickness: 0 m; Lift Cab | Front Wall Thickness: 0 m; Lift Cab | Inset: 0 m

# IfcDoor: A-ElevatorDoor-2Speed (4)
In: RL
Type - Description: 2-Speed Elevator Door; OperationType: USERDEFINED; ConstructionType: USERDEFINED; ParameterTakesPrecedence: no; Sizeable: no
Type - Lining - LiningDepth: 0.125 m; LiningThickness: 0.05 m
Type - Parametric Definition - Parametric | File Type: PAZ; Parametric | File Name: ElevatorDoor_1_2speed_NoCab
Type - Identification - ID | Description: 2-Speed Elevator Door
Type - Elevator Door - Lift Doors | Type: Two-Speed Side Opening; Lift Door | Width: 1.2 m; Lift Door | Height: 2.1 m; Frame | Thickness: 0.05 m; Frame | Head Thickness: 0.1 m; Frame | Return Thickness: 0.012 m; Frame | Depth: 0.125 m; Lift Cab | Width: 2.4 m; Lift Cab | Side Wall Thickness: 0.1 m; Lift Cab | Depth: 1.8 m; Lift Cab | Door Thickness: 0.05 m; Lift Cab | Front Wall Thickness: 0.225 m; Lift Cab | Inset: 0.1 m
Type - Discipline - Discipline: Architectural
Type - Classification - Uniclass2015: Pr_30_59_46_46
OverallHeight: 2.2594 m; OverallWidth: 1.1 m; Material: A_BSUK_Doors
Elevator Door - Lift Doors | Type: Single-Speed; Lift Door | Width: 1 m; Lift Door | Side Offset: 0 m; Lift Cab | Height: 0 m; Lift Cab | Width: 1.35 m; Lift Cab | Depth: 1.15 m
Name | Description
A-ElevatorDoor-2Speed | 2-Speed Elevator Door :1,SHE_DRAWING+SHEET.dgn,Design Model;4 ,SHE-03.FIRST.dgn,Design Model:139324
A-ElevatorDoor-2Speed | 2-Speed Elevator Door :1,SHE_DRAWING+SHEET.dgn,Design Model;6 ,SHE-05.THIRD.dgn,Design Model:139324
A-ElevatorDoor-2Speed | 2-Speed Elevator Door :1,SHE_DRAWING+SHEET.dgn,Design Model;7 ,SHE-06.FOURTH.dgn,Design Model:191047
A-ElevatorDoor-2Speed | 2-Speed Elevator Door :1,SHE_DRAWING+SHEET.dgn,Design Model;18 ,SHE-04.SECOND.dgn,Design Model:139324

# IfcDoor: A-ElevatorDoor-2SpeedWithCab
In: RL
Type - Description: 2-Speed Elevator Door; OperationType: USERDEFINED; ConstructionType: USERDEFINED; ParameterTakesPrecedence: no; Sizeable: no
Type - Lining - LiningDepth: 0.125 m; LiningThickness: 0.05 m
Type - Parametric Definition - Parametric | File Type: PAZ; Parametric | File Name: ElevatorDoor_1_2speed
Type - Identification - ID | Description: 2-Speed Elevator Door
Type - Elevator Door - Lift Doors | Type: Two-Speed Side Opening; Lift Door | Width: 1.2 m; Lift Door | Height: 2.1 m; Frame | Thickness: 0.05 m; Frame | Head Thickness: 0.1 m; Lift Door | Side Offset: 0.15 m; Frame | Return Thickness: 0.012 m; Frame | Depth: 0.125 m; Lift Cab | Height: 3 m; Lift Cab | Width: 2.4 m; Lift Cab | Side Wall Thickness: 0.1 m; Lift Cab | Depth: 1.8 m; Lift Cab | Door Thickness: 0.05 m; Lift Cab | Front Wall Thickness: 0.225 m; Lift Cab | Inset: 0.1 m
Type - Discipline - Discipline: Architectural
Type - Classification - Uniclass2015: Pr_30_59_46_46
Description: 2-Speed Elevator Door :1,SHE_DRAWING+SHEET.dgn,Design Model;1 ,SHE-01.GROUND.dgn,Design Model:129492; OverallHeight: 2.14 m; OverallWidth: 1.08 m; Material: A_BSUK_Doors
Elevator Door - Lift Door | Width: 1 m; Lift Door | Side Offset: 0 m; Lift Cab | Height: 2.4 m; Lift Cab | Width: 1.35 m; Lift Cab | Depth: 1.15 m

# IfcFlowFitting: A-RainwaterDrainageSystems-GutterCorner (4)
In: RL
Type - Description: Manufactured Gutter Corner
Type - Roof Specialty - Roof Type: Gutter; Dimension | Length: 0.3 m; Dimension | Width: 0.15 m; Dimension | Height: 0.1 m
Type - Parametric Definition - Parametric | File Type: PAZ; Parametric | File Name: GutterType1_Corner
Type - Identification - ID | Description: Manufactured Gutter Corner
Type - Discipline - Discipline: Architectural
Type - Classification - Uniclass2015: Ss_50_30_02_28
Material: A_BSUK_RainwaterDrainageSystems
Construction Phase - Phase: New Construction
Name | Description
A-RainwaterDrainageSystems-GutterCorner | Manufactured Gutter Corner :1 ,SHE_DRAWING+SHEET.dgn,Design Model;7,SHE-06.FOURTH.dgn,Design Model:99780
A-RainwaterDrainageSystems-GutterCorner | Manufactured Gutter Corner :1 ,SHE_DRAWING+SHEET.dgn,Design Model;7,SHE-06.FOURTH.dgn,Design Model:100026
A-RainwaterDrainageSystems-GutterCorner | Manufactured Gutter Corner :1 ,SHE_DRAWING+SHEET.dgn,Design Model;7,SHE-06.FOURTH.dgn,Design Model:100272
A-RainwaterDrainageSystems-GutterCorner | Manufactured Gutter Corner :1 ,SHE_DRAWING+SHEET.dgn,Design Model;7,SHE-06.FOURTH.dgn,Design Model:100518

# IfcFlowFitting: A-RainwaterDrainageSystems-GutterStraight (4)
In: RL
Type - Roof Specialty - Roof Type: Gutter; Dimension | Length: 3 m; Dimension | Width: 0.15 m; Dimension | Height: 0.1 m
Type - Parametric Definition - Parametric | File Type: PAZ; Parametric | File Name: GutterType1_Straight
Type - Discipline - Discipline: Architectural
Type - Classification - Uniclass2015: Ss_50_30_02_28
Material: A_BSUK_RainwaterDrainageSystems
Name | Description | Dimension | Length (m)
A-RainwaterDrainageSystems-GutterStraight | 1,SHE_DRAWING+SHEET.dgn ,Design Model;7,SHE-06.FOURTH.dgn,Design Model:100170 | 25.951
A-RainwaterDrainageSystems-GutterStraight | 1,SHE_DRAWING+SHEET.dgn ,Design Model;7,SHE-06.FOURTH.dgn,Design Model:355454 | 13.871
A-RainwaterDrainageSystems-GutterStraight | 1,SHE_DRAWING+SHEET.dgn ,Design Model;7,SHE-06.FOURTH.dgn,Design Model:385278 | 13.871
A-RainwaterDrainageSystems-GutterStraight | 1,SHE_DRAWING+SHEET.dgn ,Design Model;7,SHE-06.FOURTH.dgn,Design Model:385380 | 25.951

# IfcFlowFitting: M-BmpElbow-DefaultElbow (65)
In: RL
Type - PredefinedType: BEND
Type - Plumbing Elbow Parameters - AutoSize: Radius; Inlet | Outer Diameter: 25; Outlet | Outer Diameter: 25; Standard Angle: 90; Bend Angle: 90; Bending Radius: 50; Radius to Diameter Ratio: 1; Connection 1 | Length (L1): 0; Connection 2 | Length (L2): 0; View Display: iso
Type - Parameters - Insulation | Thickness (mm): 0; Correction Factor: 1.0; Wall Thickness: 0
Type - Insulation/Lining Symbology Parameters - Insulation/Lining | Color: 4; Insulation/Lining | Line Weight: 2; Insulation/ Lining | Line Style: 0; Insulation/Lining | Level Name: Level 2
Type - End Spec2_22 (2 Connections: Round | Round) - Diameter 1 (D1 Ø): 50; Diameter 2 (D2 Ø): 50
Type - Classification - Uniclass2015: Pr_65_52_63
Material: M_BSUK_ColdWater
Plumbing Elbow Parameters - Inlet | Outer Diameter: 100; Outlet | Outer Diameter: 100; Connection | End Type: -;-;
Parameters - Insulation | Surface Area: 0 m2; Lining | Thickness (mm): 0; Lining | Surface Area: 0 m2; Status: BSUK; Pressure Class: PN16; Air Flow: M
End Spec2_22 (2 Connections: Round | Round) - Diameter 1 (D1 Ø): 100; Diameter 2 (D2 Ø): 100
Name | Description | AutoSize | Standard Angle = Bend Angle | Bending Radius | Surface Area (m2) | Center Of Gravity | System ID | Phase | Group
M-BmpElbow-DefaultElbow | 1 ,SHE_DRAWING+SHEET.dgn,Design Model;11,SHE-15.MEHP.dgn,Design Model:188232 | RadToDia | 89.2838 | 100 | 0.048955 | 71.29; 0.00; -27.81; | SVP7 | New Construction | SVP
M-BmpElbow-DefaultElbow | 1 ,SHE_DRAWING+SHEET.dgn,Design Model;11,SHE-15.MEHP.dgn,Design Model:188357 | RadToDia | 89.2838 | 100 | 0.048955 | 71.29; 0.00; -27.81; | SVP7 | New Construction | SVP
M-BmpElbow-DefaultElbow | 1 ,SHE_DRAWING+SHEET.dgn,Design Model;11,SHE-15.MEHP.dgn,Design Model:188476 | RadToDia | 89.2838 | 100 | 0.048955 | 71.29; 0.00; -27.81; | SVP7 | New Construction | SVP
M-BmpElbow-DefaultElbow | 1 ,SHE_DRAWING+SHEET.dgn,Design Model;11,SHE-15.MEHP.dgn,Design Model:192476 | RadToDia | 89.2838 | 100 | 0.048955 | 71.29; 0.00; -27.81; | SVP4 | New Construction | SVP
M-BmpElbow-DefaultElbow | 1 ,SHE_DRAWING+SHEET.dgn,Design Model;11,SHE-15.MEHP.dgn,Design Model:197584 | RadToDia | 89.2838 | 100 | 0.048955 | 71.29; 0.00; -27.81; | SVP1 | New Construction | SVP
M-BmpElbow-DefaultElbow | 1 ,SHE_DRAWING+SHEET.dgn,Design Model;11,SHE-15.MEHP.dgn,Design Model:197710 | RadToDia | 89.2838 | 100 | 0.048955 | 71.29; 0.00; -27.81; | SVP1 | New Construction | SVP
M-BmpElbow-DefaultElbow | 1 ,SHE_DRAWING+SHEET.dgn,Design Model;11,SHE-15.MEHP.dgn,Design Model:197879 | RadToDia | 89.2838 | 100 | 0.048955 | 71.29; 0.00; -27.81; | SVP1 | New Construction | SVP
M-BmpElbow-DefaultElbow | 1 ,SHE_DRAWING+SHEET.dgn,Design Model;11,SHE-15.MEHP.dgn,Design Model:201466 | RadToDia | 89.991 | 100 | 0.049343 | 0.00; 0.00; 0.00; | SVP3 | New Construction | SVP
M-BmpElbow-DefaultElbow | 1 ,SHE_DRAWING+SHEET.dgn,Design Model;11,SHE-15.MEHP.dgn,Design Model:201563 | RadToDia | 89.991 | 100 | 0.049343 | 0.00; 0.00; 0.00; | SVP3 | New Construction | SVP
M-BmpElbow-DefaultElbow | 1 ,SHE_DRAWING+SHEET.dgn,Design Model;11,SHE-15.MEHP.dgn,Design Model:201664 | RadToDia | 89.2838 | 100 | 0.048955 | 0.00; 0.00; 0.00; | SVP3 | New Construction | SVP
M-BmpElbow-DefaultElbow | 1 ,SHE_DRAWING+SHEET.dgn,Design Model;11,SHE-15.MEHP.dgn,Design Model:201764 | RadToDia | 89.2838 | 100 | 0.048955 | 0.00; 0.00; 0.00; | SVP3 | New Construction | SVP
M-BmpElbow-DefaultElbow | 1 ,SHE_DRAWING+SHEET.dgn,Design Model;11,SHE-15.MEHP.dgn,Design Model:201890 | RadToDia | 89.2838 | 100 | 0.048955 | 0.00; 0.00; 0.00; | SVP5 | New Construction | SVP
M-BmpElbow-DefaultElbow | 1 ,SHE_DRAWING+SHEET.dgn,Design Model;11,SHE-15.MEHP.dgn,Design Model:201940 | RadToDia | 89.991 | 100 | 0.049343 | 0.00; 0.00; 0.00; | SVP5 | New Construction | SVP
M-BmpElbow-DefaultElbow | 1 ,SHE_DRAWING+SHEET.dgn,Design Model;11,SHE-15.MEHP.dgn,Design Model:202016 | RadToDia | 89.991 | 100 | 0.049343 | 0.00; 0.00; 0.00; | SVP5 | New Construction | SVP
M-BmpElbow-DefaultElbow | 1 ,SHE_DRAWING+SHEET.dgn,Design Model;11,SHE-15.MEHP.dgn,Design Model:202092 | RadToDia | 89.2838 | 100 | 0.048955 | 0.00; 0.00; 0.00; | SVP5 | New Construction | SVP
M-BmpElbow-DefaultElbow | 1 ,SHE_DRAWING+SHEET.dgn,Design Model;11,SHE-15.MEHP.dgn,Design Model:206706 |  | 60 | 80 | 0.026319 | 45.66; 0.00; -0.92; | SVP7 | New Construction | SVP | Plumbing Elbow Parameters - Radius to Diameter Ratio: 0.8
M-BmpElbow-DefaultElbow | 1 ,SHE_DRAWING+SHEET.dgn,Design Model;11,SHE-15.MEHP.dgn,Design Model:206756 |  | 60 | 80 | 0.026319 | 45.66; 0.00; -0.92; | SVP7 | New Construction | SVP | Plumbing Elbow Parameters - Radius to Diameter Ratio: 0.8
M-BmpElbow-DefaultElbow | 1 ,SHE_DRAWING+SHEET.dgn,Design Model;11,SHE-15.MEHP.dgn,Design Model:219166 | RadToDia | 35.9648 | 100 | 0.01972 | 34.16; 0.00; 5.26; | SVP4 | New Construction | SVP
M-BmpElbow-DefaultElbow | 1 ,SHE_DRAWING+SHEET.dgn,Design Model;11,SHE-15.MEHP.dgn,Design Model:219216 | RadToDia | 35.9648 | 100 | 0.01972 | 34.16; 0.00; 5.26;
M-BmpElbow-DefaultElbow | 1 ,SHE_DRAWING+SHEET.dgn,Design Model;11,SHE-15.MEHP.dgn,Design Model:219373 | RadToDia | 44.9963 | 100 | 0.024672 | 41.95; 0.00; 1.29; | SVP4 | New Construction | SVP
M-BmpElbow-DefaultElbow | 1 ,SHE_DRAWING+SHEET.dgn,Design Model;11,SHE-15.MEHP.dgn,Design Model:219470 | RadToDia | 44.9963 | 100 | 0.024672 | 41.95; 0.00; 1.29; | SVP4 | New Construction | SVP
M-BmpElbow-DefaultElbow | 1 ,SHE_DRAWING+SHEET.dgn,Design Model;11,SHE-15.MEHP.dgn,Design Model:219567 | RadToDia | 89.2838 | 100 | 0.048955 | 71.29; 0.00; -27.81; | SVP4 | New Construction | SVP
M-BmpElbow-DefaultElbow | 1 ,SHE_DRAWING+SHEET.dgn,Design Model;11,SHE-15.MEHP.dgn,Design Model:219642 | RadToDia | 89.2838 | 100 | 0.048955 | 71.29; 0.00; -27.81; | SVP4 | New Construction | SVP
M-BmpElbow-DefaultElbow | 1 ,SHE_DRAWING+SHEET.dgn,Design Model;11,SHE-15.MEHP.dgn,Design Model:222473 | RadToDia | 89.2838 | 100 | 0.048955 | 71.29; 0.00; -27.81; | SVP6 | New Construction | SVP
M-BmpElbow-DefaultElbow | 1 ,SHE_DRAWING+SHEET.dgn,Design Model;11,SHE-15.MEHP.dgn,Design Model:222548 | RadToDia | 89.2838 | 100 | 0.048955 | 71.29; 0.00; -27.81; | SVP6 | New Construction | SVP
M-BmpElbow-DefaultElbow | 1 ,SHE_DRAWING+SHEET.dgn,Design Model;11,SHE-15.MEHP.dgn,Design Model:223332 | RadToDia | 44.9963 | 100 | 0.024672 | 41.95; 0.00; 1.29; | SVP3 | New Construction | SVP
M-BmpElbow-DefaultElbow | 1 ,SHE_DRAWING+SHEET.dgn,Design Model;11,SHE-15.MEHP.dgn,Design Model:223429 | RadToDia | 44.9963 | 100 | 0.024672 | 41.95; 0.00; 1.29; | SVP3-5 | New Construction | SVP3
M-BmpElbow-DefaultElbow | 1 ,SHE_DRAWING+SHEET.dgn,Design Model;11,SHE-15.MEHP.dgn,Design Model:223526 | RadToDia | 44.9963 | 100 | 0.024672 | 41.95; 0.00; 1.29; | SVP3-5 | New Construction | SVP3
M-BmpElbow-DefaultElbow | 1 ,SHE_DRAWING+SHEET.dgn,Design Model;11,SHE-15.MEHP.dgn,Design Model:224338 | RadToDia | 89.2838 | 100 | 0.048955 | 71.29; 0.00; -27.81; | SVP5 | New Construction | SVP
M-BmpElbow-DefaultElbow | 1 ,SHE_DRAWING+SHEET.dgn,Design Model;11,SHE-15.MEHP.dgn,Design Model:224388 | RadToDia | 89.2838 | 100 | 0.048955 | 71.29; 0.00; -27.81; | SVP3 | New Construction | SVP
M-BmpElbow-DefaultElbow | 1 ,SHE_DRAWING+SHEET.dgn,Design Model;11,SHE-15.MEHP.dgn,Design Model:228845 | RadToDia | 44.9963 | 100 | 0.024672 | 41.95; 0.00; 1.29; | SVP7 | New Construction | SVP
M-BmpElbow-DefaultElbow | 1 ,SHE_DRAWING+SHEET.dgn,Design Model;11,SHE-15.MEHP.dgn,Design Model:228942 | RadToDia | 89.2838 | 100 | 0.048955 | 71.29; 0.00; -27.81; | SVP7 | New Construction | SVP
M-BmpElbow-DefaultElbow | 1 ,SHE_DRAWING+SHEET.dgn,Design Model;11,SHE-15.MEHP.dgn,Design Model:229042 | RadToDia | 89.2838 | 100 | 0.048955 | 71.29; 0.00; -27.81; | SVP7 | New Construction | SVP
M-BmpElbow-DefaultElbow | 1 ,SHE_DRAWING+SHEET.dgn,Design Model;11,SHE-15.MEHP.dgn,Design Model:230605 | RadToDia | 89.2838 | 100 | 0.048955 | 71.29; 0.00; -27.81; | SVP3-4-5-6 | New Construction | SVP3-4-5
M-BmpElbow-DefaultElbow | 1 ,SHE_DRAWING+SHEET.dgn,Design Model;11,SHE-15.MEHP.dgn,Design Model:232128 | RadToDia | 44.9963 | 100 | 0.024672 | 41.95; 0.00; 1.29; | SVP1 | New Construction | SVP
M-BmpElbow-DefaultElbow | 1 ,SHE_DRAWING+SHEET.dgn,Design Model;11,SHE-15.MEHP.dgn,Design Model:232225 | RadToDia | 44.9963 | 100 | 0.024672 | 41.95; 0.00; 1.29; | SVP1 | New Construction | SVP
M-BmpElbow-DefaultElbow | 1 ,SHE_DRAWING+SHEET.dgn,Design Model;11,SHE-15.MEHP.dgn,Design Model:232348 | RadToDia | 44.9963 | 100 | 0.024672 | 41.95; 0.00; 1.29; | SVP2 | New Construction | SVP
M-BmpElbow-DefaultElbow | 1 ,SHE_DRAWING+SHEET.dgn,Design Model;11,SHE-15.MEHP.dgn,Design Model:232564 | RadToDia | 89.2838 | 100 | 0.048955 | 71.29; 0.00; -27.81; | SVP2 | New Construction | SVP
M-BmpElbow-DefaultElbow | 1 ,SHE_DRAWING+SHEET.dgn,Design Model;11,SHE-15.MEHP.dgn,Design Model:232639 | RadToDia | 89.2838 | 100 | 0.048955 | 71.29; 0.00; -27.81; | SVP1 | New Construction | SVP
M-BmpElbow-DefaultElbow | 1 ,SHE_DRAWING+SHEET.dgn,Design Model;11,SHE-15.MEHP.dgn,Design Model:232739 | RadToDia | 89.2838 | 100 | 0.048955 | 71.29; 0.00; -27.81; | SVP1-2 | New Construction | SVP1
M-BmpElbow-DefaultElbow | 1 ,SHE_DRAWING+SHEET.dgn,Design Model;11,SHE-15.MEHP.dgn,Design Model:245104 | RadToDia | 88.8542 | 100 | 0.04872 | 71.09; 0.00; -27.47; | RW3 | New Construction | RW
M-BmpElbow-DefaultElbow | 1 ,SHE_DRAWING+SHEET.dgn,Design Model;11,SHE-15.MEHP.dgn,Design Model:245154 | RadToDia | 88.8542 | 100 | 0.04872 | 71.09; 0.00; -27.47; | RW3 | New Construction | RW
M-BmpElbow-DefaultElbow | 1 ,SHE_DRAWING+SHEET.dgn,Design Model;11,SHE-15.MEHP.dgn,Design Model:245965 | RadToDia | 88.8542 | 100 | 0.04872 | 71.09; 0.00; -27.47; | RW3 | New Construction | RW
M-BmpElbow-DefaultElbow | 1 ,SHE_DRAWING+SHEET.dgn,Design Model;11,SHE-15.MEHP.dgn,Design Model:246136 | RadToDia | 88.8542 | 100 | 0.04872 | 71.09; 0.00; -27.47; | RW4 | New Construction | RW
M-BmpElbow-DefaultElbow | 1 ,SHE_DRAWING+SHEET.dgn,Design Model;11,SHE-15.MEHP.dgn,Design Model:246212 | RadToDia | 88.8542 | 100 | 0.04872 | 71.09; 0.00; -27.47; | RW4 | New Construction | RW
M-BmpElbow-DefaultElbow | 1 ,SHE_DRAWING+SHEET.dgn,Design Model;11,SHE-15.MEHP.dgn,Design Model:246288 | RadToDia | 88.8542 | 100 | 0.04872 | 71.09; 0.00; -27.47; | RW4 | New Construction | RW
M-BmpElbow-DefaultElbow | 1 ,SHE_DRAWING+SHEET.dgn,Design Model;11,SHE-15.MEHP.dgn,Design Model:247250 | RadToDia | 88.8542 | 100 | 0.04872 | 71.09; 0.00; -27.47; | RW5 | New Construction | RW
M-BmpElbow-DefaultElbow | 1 ,SHE_DRAWING+SHEET.dgn,Design Model;11,SHE-15.MEHP.dgn,Design Model:248308 | RadToDia | 88.8542 | 100 | 0.04872 | 71.09; 0.00; -27.47; | RW3 | New Construction | RW
M-BmpElbow-DefaultElbow | 1 ,SHE_DRAWING+SHEET.dgn,Design Model;11,SHE-15.MEHP.dgn,Design Model:248856 | RadToDia | 88.8542 | 100 | 0.04872 | 71.09; 0.00; -27.47; | RW4 | New Construction | RW
M-BmpElbow-DefaultElbow | 1 ,SHE_DRAWING+SHEET.dgn,Design Model;11,SHE-15.MEHP.dgn,Design Model:290680 | RadToDia | 89.2838 | 100 | 0.048955 | 71.29; 0.00; -27.81; | DRM | New Construction | DRM
M-BmpElbow-DefaultElbow | 1 ,SHE_DRAWING+SHEET.dgn,Design Model;11,SHE-15.MEHP.dgn,Design Model:291145 | RadToDia | 89.2838 | 100 | 0.048955 | 71.29; 0.00; -27.81; | DRM | New Construction | DRM
M-BmpElbow-DefaultElbow | 1 ,SHE_DRAWING+SHEET.dgn,Design Model;11,SHE-15.MEHP.dgn,Design Model:291195 | RadToDia | 89.2838 | 100 | 0.048955 | 71.29; 0.00; -27.81; | DRM | New Construction | DRM
M-BmpElbow-DefaultElbow | 1 ,SHE_DRAWING+SHEET.dgn,Design Model;11,SHE-15.MEHP.dgn,Design Model:293600 | RadToDia | 89.2838 | 100 | 0.048955 | 71.29; 0.00; -27.81; | DRM | New Construction | DRM
M-BmpElbow-DefaultElbow | 1 ,SHE_DRAWING+SHEET.dgn,Design Model;11,SHE-15.MEHP.dgn,Design Model:293650 | RadToDia | 89.2838 | 100 | 0.048955 | 71.29; 0.00; -27.81; | DRM | New Construction | DRM
M-BmpElbow-DefaultElbow | 1 ,SHE_DRAWING+SHEET.dgn,Design Model;11,SHE-15.MEHP.dgn,Design Model:299728 | RadToDia | 88.8542 | 100 | 0.04872 | 71.09; 0.00; -27.47; | RW5 | New Construction | RW
M-BmpElbow-DefaultElbow | 1 ,SHE_DRAWING+SHEET.dgn,Design Model;11,SHE-15.MEHP.dgn,Design Model:299856 | RadToDia | 88.8542 | 100 | 0.04872 | 71.09; 0.00; -27.47; | RW5 | New Construction | RW
M-BmpElbow-DefaultElbow | 1 ,SHE_DRAWING+SHEET.dgn,Design Model;11,SHE-15.MEHP.dgn,Design Model:299958 | RadToDia | 88.8542 | 100 | 0.04872 | 71.09; 0.00; -27.47; | RW5 | New Construction | RW
M-BmpElbow-DefaultElbow | 1 ,SHE_DRAWING+SHEET.dgn,Design Model;11,SHE-15.MEHP.dgn,Design Model:301830 | RadToDia | 88.8542 | 100 | 0.04872 | 71.09; 0.00; -27.47; | RW3 | New Construction | RW
M-BmpElbow-DefaultElbow | 1 ,SHE_DRAWING+SHEET.dgn,Design Model;11,SHE-15.MEHP.dgn,Design Model:301932 | RadToDia | 88.8542 | 100 | 0.04872 | 71.09; 0.00; -27.47; | RW3 | New Construction | RW
M-BmpElbow-DefaultElbow | 1 ,SHE_DRAWING+SHEET.dgn,Design Model;11,SHE-15.MEHP.dgn,Design Model:302008 | RadToDia | 88.8542 | 100 | 0.04872 | 71.09; 0.00; -27.47; | RW3 | New Construction | RW
M-BmpElbow-DefaultElbow | 1 ,SHE_DRAWING+SHEET.dgn,Design Model;11,SHE-15.MEHP.dgn,Design Model:302134 | RadToDia | 88.8542 | 100 | 0.04872 | 71.09; 0.00; -27.47; | RW3 | New Construction | RW
M-BmpElbow-DefaultElbow | 1 ,SHE_DRAWING+SHEET.dgn,Design Model;11,SHE-15.MEHP.dgn,Design Model:302184 | RadToDia | 88.8542 | 100 | 0.04872 | 71.09; 0.00; -27.47; | RW5 | New Construction | RW
M-BmpElbow-DefaultElbow | 1 ,SHE_DRAWING+SHEET.dgn,Design Model;11,SHE-15.MEHP.dgn,Design Model:302259 | RadToDia | 88.8542 | 100 | 0.04872 | 71.09; 0.00; -27.47; | RW5 | New Construction | RW
M-BmpElbow-DefaultElbow | 1 ,SHE_DRAWING+SHEET.dgn,Design Model;11,SHE-15.MEHP.dgn,Design Model:311717 | RadToDia | 89.2838 | 100 | 0.048955 | 71.29; 0.00; -27.81; | RW2 | New Construction | RW
M-BmpElbow-DefaultElbow | 1 ,SHE_DRAWING+SHEET.dgn,Design Model;11,SHE-15.MEHP.dgn,Design Model:311793 | RadToDia | 89.2838 | 100 | 0.048955 | 71.29; 0.00; -27.81; | RW2 | New Construction | RW

# IfcFlowFitting: M-BmpTee-DefaultTee (11)
In: RL
Type - PredefinedType: JUNCTION
Type - Plumbing Tee Parameters - Standard Angle: 88; Angle: 88; Inlet | Outer Diameter: 28.575; Outlet | Outer Diameter: 28.575; Branch | Outer Diameter: 15.875; Total Length: 28.575; Inlet | Length: 5; Outlet | Length: 5; Branch | Connection Length: 5; Center to Branch Distance: 25; Center to Inlet Distance: 6.35; Connection | End Type: m-1;m-1;m-1;; View Display: iso
Type - Parameters - Insulation | Thickness (mm): 0; Lining | Thickness (mm): 0; Status: New; Pressure Class: Low; Air Flow: Supply; Correction Factor: 1.0; Wall Thickness: 0
Type - Insulation/Lining Symbology Parameters - Insulation/Lining | Color: 4; Insulation/Lining | Line Weight: 2; Insulation/ Lining | Line Style: 0; Insulation/Lining | Level Name: Level 2
Type - End Spec3_222 (3 Connections: 3 Round) - Diameter 1 (D1 Ø): 50; Diameter 2 (D2 Ø): 50; Diameter 3 (D3 Ø): 50
Type - Classification - Uniclass2015: Pr_65_52_63
Material: M_BSUK_ColdWater
Plumbing Tee Parameters - Inlet | Outer Diameter: 100; Outlet | Outer Diameter: 100; Branch | Outer Diameter: 100; Connection | End Type: -;-;-;
Parameters - Insulation | Surface Area: 0 m2; Lining | Surface Area: 0 m2; Status: BSUK; Pressure Class: PN16; Air Flow: M
End Spec3_222 (3 Connections: 3 Round) - Diameter 1 (D1 Ø): 100; Diameter 2 (D2 Ø): 100; Diameter 3 (D3 Ø): 100
Construction Phase - Phase: New Construction
Name | Description | Standard Angle = Angle | Total Length | Center to Branch Distance | Center to Inlet Distance | Surface Area (m2) | Center Of Gravity | System ID | Group
M-BmpTee-DefaultTee | 1 ,SHE_DRAWING+SHEET.dgn,Design Model;11,SHE-15.MEHP.dgn,Design Model:188407 | 89.2838 | 100.012 | 50.6299 | 49.3819 | 0.032036 | 49.86; 0.00; 3.21; | SVP7 | SVP
M-BmpTee-DefaultTee | 1 ,SHE_DRAWING+SHEET.dgn,Design Model;11,SHE-15.MEHP.dgn,Design Model:192842 | 89.2838 | 100.012 | 50.6299 | 49.3819 | 0.032036 | 49.86; 0.00; 3.21; | SVP4 | SVP
M-BmpTee-DefaultTee | 1 ,SHE_DRAWING+SHEET.dgn,Design Model;11,SHE-15.MEHP.dgn,Design Model:197785 | 89.2838 | 100.012 | 50.6299 | 49.3819 | 0.032036 | 49.86; 0.00; 3.21; | SVP1 | SVP
M-BmpTee-DefaultTee | 1 ,SHE_DRAWING+SHEET.dgn,Design Model;11,SHE-15.MEHP.dgn,Design Model:223649 | 44.9963 | 141.433 | 120.723 | 20.7098 | 0.058785 | 69.79; 0.00; -18.05; | SVP3-5 | SVP3
M-BmpTee-DefaultTee | 1 ,SHE_DRAWING+SHEET.dgn,Design Model;11,SHE-15.MEHP.dgn,Design Model:223981 | 89.2838 | 100.012 | 50.6299 | 49.3819 | 0.032036 | 49.86; 0.00; 3.21; | SVP3-5 | SVP3
M-BmpTee-DefaultTee | 1 ,SHE_DRAWING+SHEET.dgn,Design Model;11,SHE-15.MEHP.dgn,Design Model:230756 | 89.2838 | 100.012 | 50.6299 | 49.3819 | 0.032036 | 49.86; 0.00; 3.21; | SVP3-4-5-6-7 | SVP3-4-5-6
M-BmpTee-DefaultTee | 1 ,SHE_DRAWING+SHEET.dgn,Design Model;11,SHE-15.MEHP.dgn,Design Model:291296 | 89.2838 | 100.012 | 50.6299 | 49.3819 | 0.032036 | 49.86; 0.00; 3.21; | DRM | DRM
M-BmpTee-DefaultTee | 1 ,SHE_DRAWING+SHEET.dgn,Design Model;11,SHE-15.MEHP.dgn,Design Model:292419 | 89.2838 | 100.012 | 50.6299 | 49.3819 | 0.032036 | 49.86; 0.00; 3.21; | DRM | DRM
M-BmpTee-DefaultTee | 1 ,SHE_DRAWING+SHEET.dgn,Design Model;11,SHE-15.MEHP.dgn,Design Model:293213 | 89.2838 | 100.012 | 50.6299 | 49.3819 | 0.032036 | 49.86; 0.00; 3.21; | DRM | DRM
M-BmpTee-DefaultTee | 1 ,SHE_DRAWING+SHEET.dgn,Design Model;11,SHE-15.MEHP.dgn,Design Model:293282 | 89.2838 | 100.012 | 50.6299 | 49.3819 | 0.032036 | 49.86; 0.00; 3.21; | DRM | DRM
M-BmpTee-DefaultTee | 1 ,SHE_DRAWING+SHEET.dgn,Design Model;11,SHE-15.MEHP.dgn,Design Model:293428 | 89.2838 | 100.012 | 50.6299 | 49.3819 | 0.032036 | 49.86; 0.00; 3.21; | DRM | DRM

# IfcFlowFitting: M-BmpTransition-DefaultTransition
In: RL
Type - PredefinedType: TRANSITION
Type - Plumbing Transition Parameters - Inlet | Outer Diameter: 56; Outlet | Outer Diameter: 28.5; Total Length: 132; Rise: 0; Run: 0; Inlet | Length: 12; Outlet | Length: 12; Connection | End Type: -;-;; View Display: iso
Type - Parameters - Insulation | Thickness (mm): 0; Correction Factor: 1.0; Wall Thickness: 0
Type - Insulation/Lining Symbology Parameters - Insulation/Lining | Color: 4; Insulation/Lining | Line Weight: 2; Insulation/ Lining | Line Style: 0; Insulation/Lining | Level Name: Level 2
Type - End Spec2_22 (2 Connections: Round | Round) - Diameter 1 (D1 Ø): 100; Diameter 2 (D2 Ø): 50
Type - Classification - Uniclass2015: Pr_65_52_63
Description: 1,SHE_DRAWING+SHEET.dgn,Design Model;11 ,SHE-15.MEHP.dgn,Design Model:224076; Material: M_BSUK_ColdWater; Group: SVP3
Plumbing Transition Parameters - Inlet | Outer Diameter: 100; Outlet | Outer Diameter: 100; Total Length: 25.000000; Offset Options: t;; Run: 0.964637
Parameters - Surface Area: 0.015396 m2; Center Of Gravity: 12.50; -0.48; 0.00;; System ID: SVP3-5; Insulation | Surface Area: 0 m2; Lining | Thickness (mm): 0; Lining | Surface Area: 0 m2; Status: BSUK; Pressure Class: PN16; Air Flow: M
End Spec2_22 (2 Connections: Round | Round) - Diameter 2 (D2 Ø): 100
Construction Phase - Phase: New Construction

# IfcFlowFitting: M-PlenumBoxOvalMultiPort-Side (2)
In: RL
Type - PredefinedType: JUNCTION
Type - Parameters - Insulation | Thickness (mm): 0; Lining | Thickness (mm): 0; Correction Factor: 1.0; Wall Thickness: 0
Type - Multi Port Plenum Box Parameters - Box | Height: 200; Box | Width: 550; Box | Depth: 150; No. Of Ports: 2; Port | Offset: 50; Connection | On Left Side: 2-No; Connection | On Right Side: 2-No; Duct Connection Length: 50; Equipment Connection Length: 50; Connection | End Type: -;; View Display: iso; Air Flow Rate: 0; Air Flow Rate Unit: 1-l/s
Type - End Spec7_1333333 (7 Connections: 1 Rect | 6 Oval) - Width 1 (W1): 550; Depth 1 (D1): 150; Width 2 (W2): 250; Depth 2 (D2): 150; Width 3 (W3): 250; Depth 3 (D3): 150; Width 4 (W4): 250; Depth 4 (D4): 150; Width 5 (W5): 250; Depth 5 (D5): 150; Width 6 (W6): 250; Depth 6 (D6): 150; Width 7 (W7): 250; Depth 7 (D7): 150
Type - Classification - Uniclass2015: Pr_70_65_04_04
Material: M_BSUK_Ventilation
Parameters - Surface Area: 0.469336 m2; Center Of Gravity: -3.86; 0.00; 98.92;; Insulation | Surface Area: 0 m2; Lining | Surface Area: 0 m2; Status: BSUK; Air Flow: M
Multi Port Plenum Box Parameters - Box | Width: 600; Connection | End Type: -;-;-;-;-;-;-;
Name | Description
M-PlenumBoxOvalMultiPort-Side | 1,SHE_DRAWING+SHEET.dgn,Design Model;11 ,SHE-15.MEHP.dgn,Design Model:269846
M-PlenumBoxOvalMultiPort-Side | 1,SHE_DRAWING+SHEET.dgn,Design Model;11 ,SHE-15.MEHP.dgn,Design Model:269961

# IfcFlowFitting: M-PlenumBoxRoundMultiPort-Side (2)
In: RL
Type - PredefinedType: JUNCTION
Type - Parameters - Insulation | Thickness (mm): 0; Lining | Thickness (mm): 0; Correction Factor: 1.0; Wall Thickness: 0
Type - Multi Port Plenum Box Parameters - Box | Height: 200; Box | Width: 550; Box | Depth: 150; No. Of Ports: 3; Port | Offset: 50; Connection | On Left Side: 2-No; Connection | On Right Side: 2-No; Duct Connection Length: 50; Equipment Connection Length: 50; Connection | End Type: -;; View Display: iso; Air Flow Rate: 0; Air Flow Rate Unit: 1-l/s
Type - End Spec7_1222222 (7 Connections: 1 Rect | 6 Round) - Width 1 (W1): 550; Depth 1 (D1): 150; Diameter 2 (D2 Ø): 150; Diameter 3 (D3 Ø): 150; Diameter 4 (D4 Ø): 150; Diameter 5 (D5 Ø): 150; Diameter 6 (D6 Ø): 150; Diameter 7 (D7 Ø): 150
Type - Classification - Uniclass2015: Pr_70_65_04_04
Material: M_BSUK_Ventilation
Parameters - Surface Area: 0.485226 m2; Center Of Gravity: -6.37; 0.00; 98.96;; Insulation | Surface Area: 0 m2; Lining | Surface Area: 0 m2; Status: BSUK; Air Flow: M
Multi Port Plenum Box Parameters - Box | Width: 600; Connection | End Type: -;-;-;-;-;-;-;
Name | Description
M-PlenumBoxRoundMultiPort-Side | 1,SHE_DRAWING+SHEET.dgn,Design Model;11 ,SHE-15.MEHP.dgn,Design Model:269781
M-PlenumBoxRoundMultiPort-Side | 1,SHE_DRAWING+SHEET.dgn,Design Model;11 ,SHE-15.MEHP.dgn,Design Model:270076

# IfcFlowFitting: M-Roundelbow-DefaultRound (7)
In: RL
Type - PredefinedType: BEND
Type - Round Elbow Parameters - AutoSize: Radius; Standard Angle: 90; Angle: 90; Radius to Diameter Ratio: 1.5; Radius: 750; Connection 1 | Length (L1): 50; Connection 2 | Length (L2): 50; Connection | End Type: m-5;m-5; View Display: iso
Type - Parameters - Insulation | Thickness (mm): 0; Lining | Thickness (mm): 0; Correction Factor: 1.0; Wall Thickness: 0
Type - End Spec2_22 (2 Connections: Round | Round) - Diameter 1 (D1 Ø): 500; Diameter 2 (D2 Ø): 500
Type - Classification - Uniclass2015: Pr_65_65_25_14
Material: M_BSUK_Ventilation; Group: EXT. Flat
Round Elbow Parameters - AutoSize: RadToDia; Radius to Diameter Ratio: 1; Radius: 100; Connection | End Type: -;-;
Parameters - Surface Area: 0.080764 m2; Center Of Gravity: 58.35; 0.00; -41.65;; Insulation | Surface Area: 0 m2; Lining | Surface Area: 0 m2; Status: BSUK; Air Flow: M
End Spec2_22 (2 Connections: Round | Round) - Diameter 1 (D1 Ø): 100; Diameter 2 (D2 Ø): 100
Construction Phase - Phase: New Construction
Name | Description | System ID
M-Roundelbow-DefaultRound | 1,SHE_DRAWING+SHEET.dgn,Design Model;11,SHE-15.MEHP.dgn,Design Model:257449 | EXT. Flat 23
M-Roundelbow-DefaultRound | 1,SHE_DRAWING+SHEET.dgn,Design Model;11,SHE-15.MEHP.dgn,Design Model:257593 | EXT. Flat 23
M-Roundelbow-DefaultRound | 1,SHE_DRAWING+SHEET.dgn,Design Model;11,SHE-15.MEHP.dgn,Design Model:259104 | EXT. Flat 24
M-Roundelbow-DefaultRound | 1,SHE_DRAWING+SHEET.dgn,Design Model;11,SHE-15.MEHP.dgn,Design Model:259248 | EXT. Flat 24
M-Roundelbow-DefaultRound | 1,SHE_DRAWING+SHEET.dgn,Design Model;11,SHE-15.MEHP.dgn,Design Model:260800 | EXT. Flat 25
M-Roundelbow-DefaultRound | 1,SHE_DRAWING+SHEET.dgn,Design Model;11,SHE-15.MEHP.dgn,Design Model:261634 | EXT. Flat 26
M-Roundelbow-DefaultRound | 1,SHE_DRAWING+SHEET.dgn,Design Model;11,SHE-15.MEHP.dgn,Design Model:262247 | EXT. Flat 26

# IfcFlowSegment: M-BmpStraightpipe-DefaultPipe (87)
In: RL
Type - PredefinedType: RIGIDSEGMENT
Type - Pipe Parameters - Pipe Outer Diameter: 25; Pipe Length: 500; Minimum Length: 50; Connection 1 | Length (L1): 0; Connection 2 | Length (L2): 0; Connection | End Type: -;-;; View Display: iso
Type - Pipe Analytical Parameters - Additional Loss (N/m^2): 0; Additional K Value: 0; Insulation K Value (W/m°C): 0.03
Type - Parameters - Insulation | Thickness (mm): 0; Lining | Thickness (mm): 0; Status: New; Pressure Class: PN16; Air Flow: Supply; Correction Factor: 1.0; Wall Thickness: 0
Type - Insulation/Lining Symbology Parameters - Insulation/Lining | Color: 4; Insulation/Lining | Line Weight: 2; Insulation/ Lining | Line Style: 0; Insulation/Lining | Level Name: Level 2
Type - End Spec1_2 (1 Connection: Round) - Diameter 1 (D1 Ø): 50
Type - Classification - Uniclass2015: Pr_65_52_63
Material: M_BSUK_ColdWater
Pipe Parameters - Pipe Outer Diameter: 100.000000; Base Offset: 0.000
Parameters - Insulation | Surface Area: 0 m2; Lining | Surface Area: 0 m2; Status: BSUK; Air Flow: M
End Spec1_2 (1 Connection: Round) - Diameter 1 (D1 Ø): 100
Name | Description | Pipe Length | Slope Value | Slope Method | Surface Area (m2) | Center Of Gravity | System ID | Phase | Group
M-BmpStraightpipe-DefaultPipe | 1,SHE_DRAWING+SHEET.dgn,Design Model;11 ,SHE-15.MEHP.dgn,Design Model:187191 | 92.4989 | 0.0 | Degree | 0.029059 | 46.25; 0.00; 0.00; | SVP7 | New Construction | SVP
M-BmpStraightpipe-DefaultPipe | 1,SHE_DRAWING+SHEET.dgn,Design Model;11 ,SHE-15.MEHP.dgn,Design Model:186873 | 99.9126 | 0.0 | Degree | 0.031388 | 49.96; 0.00; 0.00; | SVP1 | New Construction | SVP
M-BmpStraightpipe-DefaultPipe | 1,SHE_DRAWING+SHEET.dgn,Design Model;11 ,SHE-15.MEHP.dgn,Design Model:182242 | 272.077 | 0.0 | Degree | 0.085475 | 136.04; 0.00; 0.00; | SVP4 | New Construction | SVP
M-BmpStraightpipe-DefaultPipe | 1,SHE_DRAWING+SHEET.dgn,Design Model;11 ,SHE-15.MEHP.dgn,Design Model:186924 | 376.115 | 0.0 | Degree | 0.11816 | 188.06; 0.00; 0.00; | SVP1 | New Construction | SVP
M-BmpStraightpipe-DefaultPipe | 1,SHE_DRAWING+SHEET.dgn,Design Model;11 ,SHE-15.MEHP.dgn,Design Model:187268 | 365.312 | 0.0 | Degree | 0.114766 | 182.66; 0.00; 0.00; | SVP7 | New Construction | SVP
M-BmpStraightpipe-DefaultPipe | 1,SHE_DRAWING+SHEET.dgn,Design Model;11 ,SHE-15.MEHP.dgn,Design Model:187535 | 327.379 | 0.0 | Degree | 0.102849 | 163.69; 0.00; 0.00; | SVP4 | New Construction | SVP
M-BmpStraightpipe-DefaultPipe | 1,SHE_DRAWING+SHEET.dgn,Design Model;11 ,SHE-15.MEHP.dgn,Design Model:182060 | 9199.95 | 0.0 | Degree | 2.89025 | 4599.98; 0.00; 0.00; | SVP4 | New Construction | SVP
M-BmpStraightpipe-DefaultPipe | 1,SHE_DRAWING+SHEET.dgn,Design Model;11 ,SHE-15.MEHP.dgn,Design Model:187832 | 2950.35 | 1 : 80 | Rise / Run | 0.926879 | 1475.17; 0.00; 0.00; | SVP7 | New Construction | SVP
M-BmpStraightpipe-DefaultPipe | 1,SHE_DRAWING+SHEET.dgn,Design Model;11 ,SHE-15.MEHP.dgn,Design Model:188105 | 2744.81 | 1 : 80 | Rise / Run | 0.862308 | 1372.41; 0.00; 0.00; | SVP7 | New Construction | SVP
M-BmpStraightpipe-DefaultPipe | 1,SHE_DRAWING+SHEET.dgn,Design Model;11 ,SHE-15.MEHP.dgn,Design Model:188156 | 115.318 | 0.0 | Degree | 0.036228 | 57.66; 0.00; 0.00; | SVP7 | New Construction | SVP
M-BmpStraightpipe-DefaultPipe | 1,SHE_DRAWING+SHEET.dgn,Design Model;11 ,SHE-15.MEHP.dgn,Design Model:192072 | 819.683 | 1 : 80 | Rise / Run | 0.257511 | 409.84; 0.00; 0.00; | SVP4 | New Construction | SVP
M-BmpStraightpipe-DefaultPipe | 1,SHE_DRAWING+SHEET.dgn,Design Model;11 ,SHE-15.MEHP.dgn,Design Model:182008 | 9644.6 | 0.0 | Degree | 3.02994 | 4822.30; 0.00; 0.00; | SVP1 | New Construction | SVP
M-BmpStraightpipe-DefaultPipe | 1,SHE_DRAWING+SHEET.dgn,Design Model;11 ,SHE-15.MEHP.dgn,Design Model:182034 | 7432.07 | 0.0 | Degree | 2.33486 | 3716.04; 0.00; 0.00; | SVP2 | New Construction | SVP
M-BmpStraightpipe-DefaultPipe | 1,SHE_DRAWING+SHEET.dgn,Design Model;11 ,SHE-15.MEHP.dgn,Design Model:182086 | 7206.42 | 0.0 | Degree | 2.26396 | 3603.21; 0.00; 0.00; | SVP6 | New Construction | SVP
M-BmpStraightpipe-DefaultPipe | 1,SHE_DRAWING+SHEET.dgn,Design Model;11 ,SHE-15.MEHP.dgn,Design Model:182164 | 9685.92 | 0.0 | Degree | 3.04292 | 4842.96; 0.00; 0.00; | SVP3 | New Construction | SVP
M-BmpStraightpipe-DefaultPipe | 1,SHE_DRAWING+SHEET.dgn,Design Model;11 ,SHE-15.MEHP.dgn,Design Model:182138 | 9722.06 | 0.0 | Degree | 3.05428 | 4861.03; 0.00; 0.00; | SVP5 | New Construction | SVP
M-BmpStraightpipe-DefaultPipe | 1,SHE_DRAWING+SHEET.dgn,Design Model;11 ,SHE-15.MEHP.dgn,Design Model:197348 | 2295.8 | 1 : 80 | Rise / Run | 0.721246 | 1147.90; 0.00; 0.00; | SVP1 | New Construction | SVP
M-BmpStraightpipe-DefaultPipe | 1,SHE_DRAWING+SHEET.dgn,Design Model;11 ,SHE-15.MEHP.dgn,Design Model:197498 | 1947.92 | 1 : 80 | Rise / Run | 0.611956 | 973.96; 0.00; 0.00; | SVP1 | New Construction | SVP
M-BmpStraightpipe-DefaultPipe | 1,SHE_DRAWING+SHEET.dgn,Design Model;11 ,SHE-15.MEHP.dgn,Design Model:197659 | 125.624 | 0.0 | Degree | 0.039466 | 62.81; 0.00; 0.00; | SVP1 | New Construction | SVP
M-BmpStraightpipe-DefaultPipe | 1,SHE_DRAWING+SHEET.dgn,Design Model;11 ,SHE-15.MEHP.dgn,Design Model:201095 | 240.779 | 0.0 | Degree | 0.075643 | 120.39; 0.00; 0.00; | SVP3 | New Construction | SVP
M-BmpStraightpipe-DefaultPipe | 1,SHE_DRAWING+SHEET.dgn,Design Model;11 ,SHE-15.MEHP.dgn,Design Model:201121 | 240.779 | 0.0 | Degree | 0.075643 | 0.00; 0.00; 0.00; | SVP5 | New Construction | SVP
M-BmpStraightpipe-DefaultPipe | 1,SHE_DRAWING+SHEET.dgn,Design Model;11 ,SHE-15.MEHP.dgn,Design Model:201440 | 1151.36 | 1 : 80 | Rise / Run | 0.361711 | 575.68; 0.00; 0.00; | SVP3 | New Construction | SVP
M-BmpStraightpipe-DefaultPipe | 1,SHE_DRAWING+SHEET.dgn,Design Model;11 ,SHE-15.MEHP.dgn,Design Model:201537 | 1000.12 | 1 : 80 | Rise / Run | 0.314199 | 500.06; 0.00; 0.00; | SVP3 | New Construction | SVP
M-BmpStraightpipe-DefaultPipe | 1,SHE_DRAWING+SHEET.dgn,Design Model;11 ,SHE-15.MEHP.dgn,Design Model:201613 | 528.362 | 1 : 80 | Rise / Run | 0.16599 | 264.18; 0.00; 0.00; | SVP3 | New Construction | SVP
M-BmpStraightpipe-DefaultPipe | 1,SHE_DRAWING+SHEET.dgn,Design Model;11 ,SHE-15.MEHP.dgn,Design Model:201864 | 1151.36 | 1 : 80 | Rise / Run | 0.361711 | 0.00; 0.00; 0.00; | SVP5 | New Construction | SVP
M-BmpStraightpipe-DefaultPipe | 1,SHE_DRAWING+SHEET.dgn,Design Model;11 ,SHE-15.MEHP.dgn,Design Model:201990 | 1000.12 | 1 : 80 | Rise / Run | 0.314199 | 0.00; 0.00; 0.00; | SVP5 | New Construction | SVP
M-BmpStraightpipe-DefaultPipe | 1,SHE_DRAWING+SHEET.dgn,Design Model;11 ,SHE-15.MEHP.dgn,Design Model:202066 | 528.362 | 1 : 80 | Rise / Run | 0.16599 | 0.00; 0.00; 0.00; | SVP5 | New Construction | SVP
M-BmpStraightpipe-DefaultPipe | 1,SHE_DRAWING+SHEET.dgn,Design Model;11 ,SHE-15.MEHP.dgn,Design Model:206580 | 9008.09 | 0.0 | Degree | 2.82998 | 4504.05; 0.00; 0.00; | SVP7 | New Construction | SVP
M-BmpStraightpipe-DefaultPipe | 1,SHE_DRAWING+SHEET.dgn,Design Model;11 ,SHE-15.MEHP.dgn,Design Model:206806 | 400.104 | 0.0 | Degree | 0.125696 | 200.05; 0.00; 0.00; | SVP7 | New Construction | SVP
M-BmpStraightpipe-DefaultPipe | 1,SHE_DRAWING+SHEET.dgn,Design Model;11 ,SHE-15.MEHP.dgn,Design Model:206858 | 254.034 | 0.0 | Degree | 0.079807 | 127.02; 0.00; 0.00; | SVP7 | New Construction | SVP
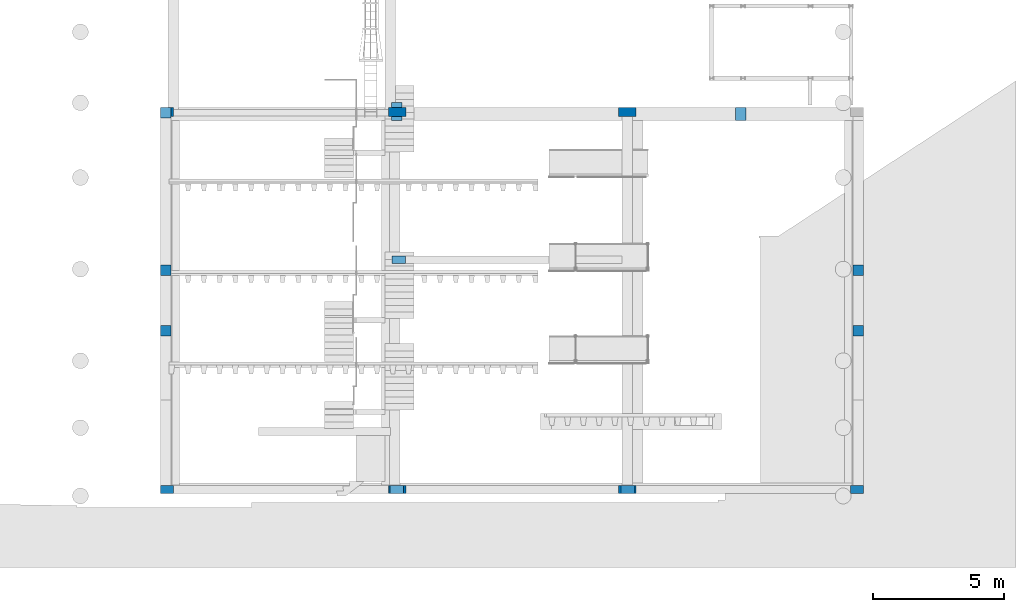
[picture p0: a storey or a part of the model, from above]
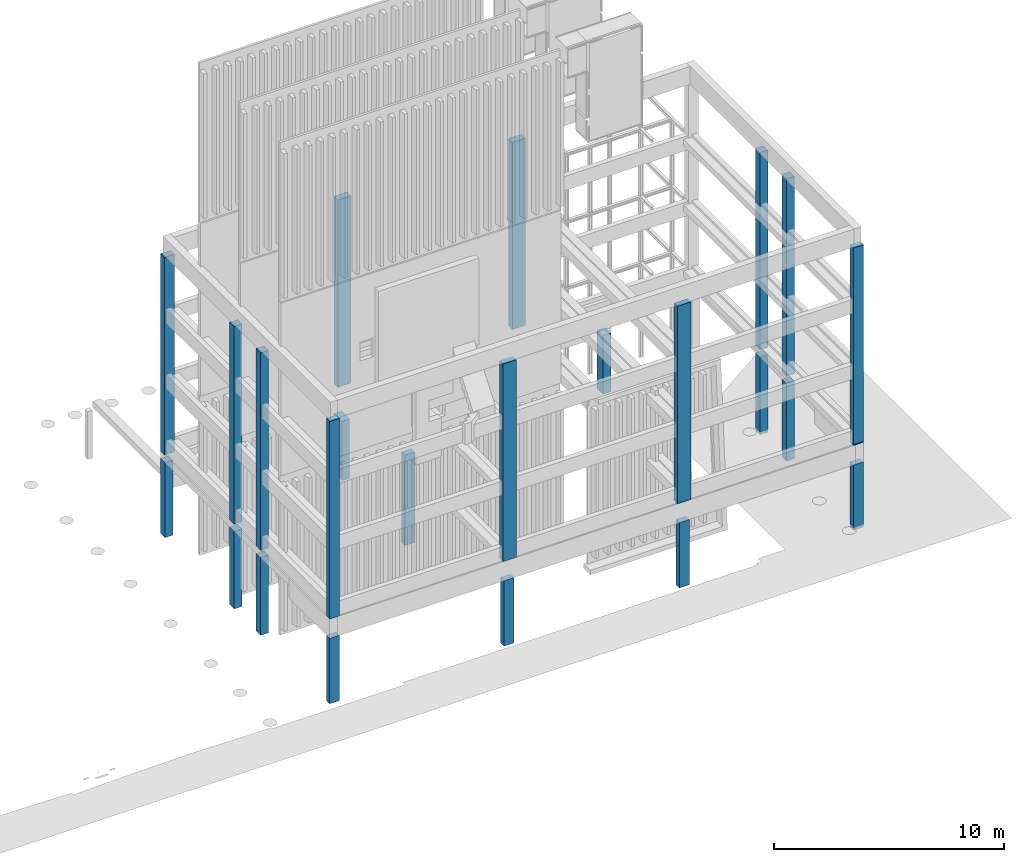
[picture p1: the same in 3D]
Properties of the parts of a building model (IFC2X3), part 5 of 16

# IfcFlowSegment: M-BmpStraightpipe-DefaultPipe (87)
Name | Description | Pipe Length | Slope Value | Slope Method | Surface Area (m2) | Center Of Gravity | System ID | Phase | Group
M-BmpStraightpipe-DefaultPipe | 1,SHE_DRAWING+SHEET.dgn,Design Model;11 ,SHE-15.MEHP.dgn,Design Model:167296 | 24351.6 | 0.0 | Degree | 7.65027 | 12175.79; 0.00; 0.00; | RW1 | New Construction | RW
M-BmpStraightpipe-DefaultPipe | 1,SHE_DRAWING+SHEET.dgn,Design Model;11 ,SHE-15.MEHP.dgn,Design Model:200936 | 7805.33 | 0.0 | Degree | 2.45212 | 3902.66; 0.00; 0.00; | SVP0 | New Construction | SVP
M-BmpStraightpipe-DefaultPipe | 1,SHE_DRAWING+SHEET.dgn,Design Model;11 ,SHE-15.MEHP.dgn,Design Model:219027 | 20.788 | 0.0 | Degree | 0.006531 | 10.39; 0.00; 0.00; | SVP7 | New Construction | SVP | Pipe Parameters - Minimum Length: 20.788
M-BmpStraightpipe-DefaultPipe | 1,SHE_DRAWING+SHEET.dgn,Design Model;11 ,SHE-15.MEHP.dgn,Design Model:219140 | 224.045 | 0.0 | Degree | 0.070386 | 112.02; 0.00; 0.00; | SVP4 | New Construction | SVP
M-BmpStraightpipe-DefaultPipe | 1,SHE_DRAWING+SHEET.dgn,Design Model;11 ,SHE-15.MEHP.dgn,Design Model:219266 | 105.358 | 0.0 | Degree | 0.033099 | 52.68; 0.00; 0.00; | SVP4 | New Construction | SVP
M-BmpStraightpipe-DefaultPipe | 1,SHE_DRAWING+SHEET.dgn,Design Model;11 ,SHE-15.MEHP.dgn,Design Model:219347 | 185.116 | 1 : 80 | Rise / Run | 0.058156 | 92.56; 0.00; 0.00; | SVP4 | New Construction | SVP
M-BmpStraightpipe-DefaultPipe | 1,SHE_DRAWING+SHEET.dgn,Design Model;11 ,SHE-15.MEHP.dgn,Design Model:219444 | 3529.67 | 1 : 80 | Rise / Run | 1.10888 | 1764.83; 0.00; 0.00; | SVP4 | New Construction | SVP
M-BmpStraightpipe-DefaultPipe | 1,SHE_DRAWING+SHEET.dgn,Design Model;11 ,SHE-15.MEHP.dgn,Design Model:219541 | 971.684 | 1 : 80 | Rise / Run | 0.305264 | 485.84; 0.00; 0.00; | SVP4 | New Construction | SVP
M-BmpStraightpipe-DefaultPipe | 1,SHE_DRAWING+SHEET.dgn,Design Model;11 ,SHE-15.MEHP.dgn,Design Model:222145 | 1204.91 | 1 : 80 | Rise / Run | 0.378534 | 602.46; 0.00; 0.00; | SVP6 | New Construction | SVP
M-BmpStraightpipe-DefaultPipe | 1,SHE_DRAWING+SHEET.dgn,Design Model;11 ,SHE-15.MEHP.dgn,Design Model:223306 | 1157.49 | 1 : 80 | Rise / Run | 0.363635 | 578.74; 0.00; 0.00; | SVP3 | New Construction | SVP
M-BmpStraightpipe-DefaultPipe | 1,SHE_DRAWING+SHEET.dgn,Design Model;11 ,SHE-15.MEHP.dgn,Design Model:223403 | 2632.82 | 1 : 80 | Rise / Run | 0.827125 | 1316.41; 0.00; 0.00; | SVP3 | New Construction | SVP
M-BmpStraightpipe-DefaultPipe | 1,SHE_DRAWING+SHEET.dgn,Design Model;11 ,SHE-15.MEHP.dgn,Design Model:223500 | 1027.66 | 1 : 80 | Rise / Run | 0.322849 | 513.83; 0.00; 0.00; | SVP3-5 | New Construction | SVP3
M-BmpStraightpipe-DefaultPipe | 1,SHE_DRAWING+SHEET.dgn,Design Model;11 ,SHE-15.MEHP.dgn,Design Model:223597 | 3622.03 | 1 : 80 | Rise / Run | 1.13789 | 1811.01; 0.00; 0.00; | SVP3-5 | New Construction | SVP3
M-BmpStraightpipe-DefaultPipe | 1,SHE_DRAWING+SHEET.dgn,Design Model;11 ,SHE-15.MEHP.dgn,Design Model:223718 | 736.484 | 1 : 80 | Rise / Run | 0.231373 | 368.24; 0.00; 0.00; | SVP3-5 | New Construction | SVP3
M-BmpStraightpipe-DefaultPipe | 1,SHE_DRAWING+SHEET.dgn,Design Model;11 ,SHE-15.MEHP.dgn,Design Model:223879 | 1072.99 | 1 : 80 | Rise / Run | 0.337089 | 536.49; 0.00; 0.00; | SVP5 | New Construction | SVP
M-BmpStraightpipe-DefaultPipe | 1,SHE_DRAWING+SHEET.dgn,Design Model;11 ,SHE-15.MEHP.dgn,Design Model:223930 | 88.98 | 0.0 | Degree | 0.027954 | 44.49; 0.00; 0.00; | SVP3-4-5-6 | New Construction | SVP3-4-5
M-BmpStraightpipe-DefaultPipe | 1,SHE_DRAWING+SHEET.dgn,Design Model;11 ,SHE-15.MEHP.dgn,Design Model:224050 | 50 | 0.0 | Degree | 0.015708 | 25.00; 0.00; 0.00;
M-BmpStraightpipe-DefaultPipe | 1,SHE_DRAWING+SHEET.dgn,Design Model;11 ,SHE-15.MEHP.dgn,Design Model:228790 | 122.618 | 0.0 | Degree | 0.038521 | 61.31; 0.00; 0.00; | SVP7 | New Construction | SVP
M-BmpStraightpipe-DefaultPipe | 1,SHE_DRAWING+SHEET.dgn,Design Model;11 ,SHE-15.MEHP.dgn,Design Model:228819 | 2682.17 | 1 : 80 | Rise / Run | 0.842628 | 1341.08; 0.00; 0.00; | SVP7 | New Construction | SVP
M-BmpStraightpipe-DefaultPipe | 1,SHE_DRAWING+SHEET.dgn,Design Model;11 ,SHE-15.MEHP.dgn,Design Model:228916 | 425.554 | 1 : 80 | Rise / Run | 0.133692 | 212.78; 0.00; 0.00; | SVP7 | New Construction | SVP
M-BmpStraightpipe-DefaultPipe | 1,SHE_DRAWING+SHEET.dgn,Design Model;11 ,SHE-15.MEHP.dgn,Design Model:230579 | 1293.32 | 1 : 80 | Rise / Run | 0.406307 | 646.66; 0.00; 0.00; | SVP3-4-5-6 | New Construction | SVP3-4-5
M-BmpStraightpipe-DefaultPipe | 1,SHE_DRAWING+SHEET.dgn,Design Model;11 ,SHE-15.MEHP.dgn,Design Model:230730 | 7759.69 | 0.0 | Degree | 2.43778 | 3879.85; 0.00; 0.00; | SVP3-4-5-6-7 | New Construction | SVP3-4-5-6
M-BmpStraightpipe-DefaultPipe | 1,SHE_DRAWING+SHEET.dgn,Design Model;11 ,SHE-15.MEHP.dgn,Design Model:232045 | 7925.4 | 0.0 | Degree | 2.48984 | 3962.70; 0.00; 0.00; | SVP1-2 | New Construction | SVP1
M-BmpStraightpipe-DefaultPipe | 1,SHE_DRAWING+SHEET.dgn,Design Model;11 ,SHE-15.MEHP.dgn,Design Model:232102 | 4139.69 | 1 : 80 | Rise / Run | 1.30052 | 2069.84; 0.00; 0.00; | SVP1 | New Construction | SVP
M-BmpStraightpipe-DefaultPipe | 1,SHE_DRAWING+SHEET.dgn,Design Model;11 ,SHE-15.MEHP.dgn,Design Model:232199 | 362.22 | 1 : 80 | Rise / Run | 0.113795 | 181.11; 0.00; 0.00; | SVP1 | New Construction | SVP
M-BmpStraightpipe-DefaultPipe | 1,SHE_DRAWING+SHEET.dgn,Design Model;11 ,SHE-15.MEHP.dgn,Design Model:232296 | 5796.24 | 1 : 80 | Rise / Run | 1.82094 | 2898.12; 0.00; 0.00; | SVP1-2 | New Construction | SVP1
M-BmpStraightpipe-DefaultPipe | 1,SHE_DRAWING+SHEET.dgn,Design Model;11 ,SHE-15.MEHP.dgn,Design Model:232322 | 1522.04 | 1 : 80 | Rise / Run | 0.478162 | 761.02; 0.00; 0.00; | SVP2 | New Construction | SVP
M-BmpStraightpipe-DefaultPipe | 1,SHE_DRAWING+SHEET.dgn,Design Model;11 ,SHE-15.MEHP.dgn,Design Model:232419 | 403.638 | 1 : 80 | Rise / Run | 0.126807 | 201.82; 0.00; 0.00; | SVP2 | New Construction | SVP
M-BmpStraightpipe-DefaultPipe | 1,SHE_DRAWING+SHEET.dgn,Design Model;11 ,SHE-15.MEHP.dgn,Design Model:167322 | 9027.6 | 0.0 | Degree | 2.83611 | 4513.80; 0.00; 0.00; | RW3 | New Construction | RW
M-BmpStraightpipe-DefaultPipe | 1,SHE_DRAWING+SHEET.dgn,Design Model;11 ,SHE-15.MEHP.dgn,Design Model:167348 | 9229.31 | 0.0 | Degree | 2.89947 | 4614.66; 0.00; 0.00; | RW4 | New Construction | RW
M-BmpStraightpipe-DefaultPipe | 1,SHE_DRAWING+SHEET.dgn,Design Model;11 ,SHE-15.MEHP.dgn,Design Model:167374 | 15176.6 | 0.0 | Degree | 4.76787 | 7588.31; 0.00; 0.00; | RW5 | New Construction | RW
M-BmpStraightpipe-DefaultPipe | 1,SHE_DRAWING+SHEET.dgn,Design Model;11 ,SHE-15.MEHP.dgn,Design Model:245027 | 6071.43 | 0.0 | Degree | 1.9074 | 3035.71; 0.00; 0.00; | RW3 | New Construction | RW
M-BmpStraightpipe-DefaultPipe | 1,SHE_DRAWING+SHEET.dgn,Design Model;11 ,SHE-15.MEHP.dgn,Design Model:245053 | 311.95 | 0.0 | Degree | 0.098002 | 155.98; 0.00; 0.00; | RW3 | New Construction | RW
M-BmpStraightpipe-DefaultPipe | 1,SHE_DRAWING+SHEET.dgn,Design Model;11 ,SHE-15.MEHP.dgn,Design Model:246186 | 5986.89 | 0.0 | Degree | 1.88084 | 2993.45; 0.00; 0.00; | RW4 | New Construction | RW
M-BmpStraightpipe-DefaultPipe | 1,SHE_DRAWING+SHEET.dgn,Design Model;11 ,SHE-15.MEHP.dgn,Design Model:246262 | 234.392 | 0.0 | Degree | 0.073636 | 117.20; 0.00; 0.00; | RW4 | New Construction | RW
M-BmpStraightpipe-DefaultPipe | 1,SHE_DRAWING+SHEET.dgn,Design Model;11 ,SHE-15.MEHP.dgn,Design Model:248830 | 50 | 1 : 80 | Rise / Run | 0.015708 | 25.00; 0.00; 0.00; | RW4 | New Construction | RW
M-BmpStraightpipe-DefaultPipe | 1,SHE_DRAWING+SHEET.dgn,Design Model;11 ,SHE-15.MEHP.dgn,Design Model:268855 | 15419.3 | 0.0 | Degree | 4.84412 | 7709.66; 0.00; 0.00; | RW6 | New Construction | RW
M-BmpStraightpipe-DefaultPipe | 1,SHE_DRAWING+SHEET.dgn,Design Model;11 ,SHE-15.MEHP.dgn,Design Model:287569 | 1019.92 | 0.0 | Degree | 0.320417 | 509.96; 0.00; 0.00; | DRM | New Construction | DRM
M-BmpStraightpipe-DefaultPipe | 1,SHE_DRAWING+SHEET.dgn,Design Model;11 ,SHE-15.MEHP.dgn,Design Model:289773 | 1519.3 | 0.0 | Degree | 0.477302 | 759.65; 0.00; 0.00; | DRM | New Construction | DRM
M-BmpStraightpipe-DefaultPipe | 1,SHE_DRAWING+SHEET.dgn,Design Model;11 ,SHE-15.MEHP.dgn,Design Model:290654 | 4452.11 | 1 : 80 | Rise / Run | 1.39867 | 2226.05; 0.00; 0.00; | DRM | New Construction | DRM
M-BmpStraightpipe-DefaultPipe | 1,SHE_DRAWING+SHEET.dgn,Design Model;11 ,SHE-15.MEHP.dgn,Design Model:291245 | 466.449 | 1 : 80 | Rise / Run | 0.146539 | 233.22; 0.00; 0.00; | DRM | New Construction | DRM
M-BmpStraightpipe-DefaultPipe | 1,SHE_DRAWING+SHEET.dgn,Design Model;11 ,SHE-15.MEHP.dgn,Design Model:292488 | 2439.99 | 0.0 | Degree | 0.766545 | 1219.99; 0.00; 0.00; | DRM | New Construction | DRM
M-BmpStraightpipe-DefaultPipe | 1,SHE_DRAWING+SHEET.dgn,Design Model;11 ,SHE-15.MEHP.dgn,Design Model:293351 | 3379.99 | 0.0 | Degree | 1.06185 | 1689.99; 0.00; 0.00; | DRM | New Construction | DRM
M-BmpStraightpipe-DefaultPipe | 1,SHE_DRAWING+SHEET.dgn,Design Model;11 ,SHE-15.MEHP.dgn,Design Model:293402 | 3379.99 | 0.0 | Degree | 1.06185 | 1689.99; 0.00; 0.00; | DRM | New Construction | DRM
M-BmpStraightpipe-DefaultPipe | 1,SHE_DRAWING+SHEET.dgn,Design Model;11 ,SHE-15.MEHP.dgn,Design Model:293497 | 893.583 | 0.0 | Degree | 0.280727 | 446.79; 0.00; 0.00; | DRM | New Construction | DRM
M-BmpStraightpipe-DefaultPipe | 1,SHE_DRAWING+SHEET.dgn,Design Model;11 ,SHE-15.MEHP.dgn,Design Model:293574 | 1647.66 | 0.0 | Degree | 0.517627 | 823.83; 0.00; 0.00; | DRM | New Construction | DRM
M-BmpStraightpipe-DefaultPipe | 1,SHE_DRAWING+SHEET.dgn,Design Model;11 ,SHE-15.MEHP.dgn,Design Model:295986 | 13297.2 | 0.0 | Degree | 4.17744 | 6648.61; 0.00; 0.00; | RW5 | New Construction | RW
M-BmpStraightpipe-DefaultPipe | 1,SHE_DRAWING+SHEET.dgn,Design Model;11 ,SHE-15.MEHP.dgn,Design Model:299780 | 14511.9 | 0.0 | Degree | 4.55904 | 7255.93; 0.00; 0.00; | RW5 | New Construction | RW
M-BmpStraightpipe-DefaultPipe | 1,SHE_DRAWING+SHEET.dgn,Design Model;11 ,SHE-15.MEHP.dgn,Design Model:299932 | 4475.88 | 0.0 | Degree | 1.40614 | 2237.94; 0.00; 0.00; | RW5 | New Construction | RW
M-BmpStraightpipe-DefaultPipe | 1,SHE_DRAWING+SHEET.dgn,Design Model;11 ,SHE-15.MEHP.dgn,Design Model:300211 | 8636.03 | 0.0 | Degree | 2.71309 | 4318.01; 0.00; 0.00; | RW5 | New Construction | RW
M-BmpStraightpipe-DefaultPipe | 1,SHE_DRAWING+SHEET.dgn,Design Model;11 ,SHE-15.MEHP.dgn,Design Model:301880 | 117.502 | 0.0 | Degree | 0.036914 | 58.75; 0.00; 0.00; | RW3 | New Construction | RW
M-BmpStraightpipe-DefaultPipe | 1,SHE_DRAWING+SHEET.dgn,Design Model;11 ,SHE-15.MEHP.dgn,Design Model:301906 | 12987.9 | 0.0 | Degree | 4.08026 | 6493.94; 0.00; 0.00; | RW3 | New Construction | RW
M-BmpStraightpipe-DefaultPipe | 1,SHE_DRAWING+SHEET.dgn,Design Model;11 ,SHE-15.MEHP.dgn,Design Model:301982 | 14511.9 | 0.0 | Degree | 4.55904 | 7255.93; 0.00; 0.00; | RW3 | New Construction | RW
M-BmpStraightpipe-DefaultPipe | 1,SHE_DRAWING+SHEET.dgn,Design Model;11 ,SHE-15.MEHP.dgn,Design Model:302058 | 13297.2 | 0.0 | Degree | 4.17744 | 6648.61; 0.00; 0.00; | RW3 | New Construction | RW
M-BmpStraightpipe-DefaultPipe | 1,SHE_DRAWING+SHEET.dgn,Design Model;11 ,SHE-15.MEHP.dgn,Design Model:303276 | 5974.07 | 0.0 | Degree | 1.87681 | 2987.04; 0.00; 0.00; | RW2 | New Construction | RW
M-BmpStraightpipe-DefaultPipe | 1,SHE_DRAWING+SHEET.dgn,Design Model;11 ,SHE-15.MEHP.dgn,Design Model:311016 | 18166 | 0.0 | Degree | 5.70702 | 9083.01; 0.00; 0.00; | RW2 | New Construction | RW
M-BmpStraightpipe-DefaultPipe | 1,SHE_DRAWING+SHEET.dgn,Design Model;11 ,SHE-15.MEHP.dgn,Design Model:311767 | 172.177 | 1 : 80 | Rise / Run | 0.054091 | 86.09; 0.00; 0.00; | RW2 | New Construction | RW

# IfcFlowSegment: M-RoundDuct (25)
In: RL
Type - PredefinedType: RIGIDSEGMENT
Type - Round Duct Parameters - Length: 2000; Minimum Length: 100; Connection 1 | Length (L1): 0; Connection 2 | Length (L2): 0; Connection | End Type: m-5;m-5; View Display: iso
Type - Parameters - Insulation | Thickness (mm): 0; Lining | Thickness (mm): 0; Correction Factor: 1.0; Wall Thickness: 0
Type - End Spec1_2 (1 Connection: Round) - Diameter 1 (D1 Ø): 500
Type - Classification - Uniclass2015: Pr_65_65_25_14
Material: M_BSUK_Ventilation
Round Duct Parameters - Connection | End Type: m-5;m-5;; Base Offset: 0.000
Parameters - Insulation | Surface Area: 0 m2; Lining | Surface Area: 0 m2; Status: BSUK; Air Flow: M
Name | Description | Length | VulcanParameters | Surface Area (m2) | Center Of Gravity | System ID | Diameter 1 (D1 Ø) | Phase | Group
M-RoundDuct | 1 ,SHE_DRAWING+SHEET.dgn,Design Model;11,SHE-15.MEHP.dgn,Design Model:256730 | 3209.54 | FN=302-m;W=100;L=3209.544714;CN1=Male 5;CN2=Male 5;END | 1.00831 | 1604.77; 0.00; 0.00; | EXT. Flat 23 | 100 | New Construction | EXT. Flat
M-RoundDuct | 1 ,SHE_DRAWING+SHEET.dgn,Design Model;11,SHE-15.MEHP.dgn,Design Model:256892 | 3108.93 | FN=302-m;W=100;L=3108.93321;CN1=Male 5;CN2=Male 5;END | 0.9767 | 1554.47; 0.00; 0.00; | EXT. Flat 26 | 100 | New Construction | EXT. Flat
M-RoundDuct | 1 ,SHE_DRAWING+SHEET.dgn,Design Model;11,SHE-15.MEHP.dgn,Design Model:257407 | 100 | FN=302-m;W=100;L=100;CN1=Male 5;CN2=Male 5;END | 0.031416 | 50.00; 0.00; 0.00; | EXT. Flat 23 | 100 | New Construction | EXT. Flat
M-RoundDuct | 1 ,SHE_DRAWING+SHEET.dgn,Design Model;11,SHE-15.MEHP.dgn,Design Model:257551 | 662.619 | FN=302-m;W=100;L=662.619324;CN1=Male 5;CN2=Male 5;END | 0.208168 | 331.31; 0.00; 0.00; | EXT. Flat 23 | 100 | New Construction | EXT. Flat
M-RoundDuct | 1 ,SHE_DRAWING+SHEET.dgn,Design Model;11,SHE-15.MEHP.dgn,Design Model:257658 | 7980.06 | FN=302-m;W=100;L=7980.060544;CN1=Male 5;CN2=Male 5;END | 2.50701 | 3990.03; 0.00; 0.00; | EXT. Flat 23 | 100 | New Construction | EXT. Flat
M-RoundDuct | 1 ,SHE_DRAWING+SHEET.dgn,Design Model;11,SHE-15.MEHP.dgn,Design Model:257853 | 282.911 | FN=302-m;W=100;L=282.910663;CN1=Male 5;CN2=Male 5;END | 0.088879 | 141.46; 0.00; 0.00; | EXT. Flat 23 | 100 | New Construction | EXT. Flat
M-RoundDuct | 1 ,SHE_DRAWING+SHEET.dgn,Design Model;11,SHE-15.MEHP.dgn,Design Model:259062 | 2100.06 | FN=302-m;W=100;L=2100.060544;CN1=Male 5;CN2=Male 5;END | 0.659753 | 1050.03; 0.00; 0.00; | EXT. Flat 24 | 100 | New Construction | EXT. Flat
M-RoundDuct | 1 ,SHE_DRAWING+SHEET.dgn,Design Model;11,SHE-15.MEHP.dgn,Design Model:259206 | 982.619 | FN=302-m;W=100;L=982.619324;CN1=Male 5;CN2=Male 5;END | 0.308699 | 491.31; 0.00; 0.00; | EXT. Flat 24 | 100 | New Construction | EXT. Flat
M-RoundDuct | 1 ,SHE_DRAWING+SHEET.dgn,Design Model;11,SHE-15.MEHP.dgn,Design Model:259350 | 320.63 | FN=302-m;W=100;L=320.629531;CN1=Male 5;CN2=Male 5;END | 0.100729 | 160.31; 0.00; 0.00; | EXT. Flat 24 | 100 | New Construction | EXT. Flat
M-RoundDuct | 1 ,SHE_DRAWING+SHEET.dgn,Design Model;11,SHE-15.MEHP.dgn,Design Model:260434 | 922.649 | FN=302-m;W=100;L=922.64892;CN1=Male 5;CN2=Male 5;END | 0.289859 | 461.32; 0.00; 0.00; | EXT. Flat 24 | 100 | New Construction | EXT. Flat
M-RoundDuct | 1 ,SHE_DRAWING+SHEET.dgn,Design Model;11,SHE-15.MEHP.dgn,Design Model:260536 | 922.649 | FN=302-m;W=100;L=922.64892;CN1=Male 5;CN2=Male 5;END | 0.289859 | 461.32; 0.00; 0.00; | EXT. Flat 25 | 100 | New Construction | EXT. Flat
M-RoundDuct | 1 ,SHE_DRAWING+SHEET.dgn,Design Model;11,SHE-15.MEHP.dgn,Design Model:260758 | 1172.6 | FN=302-m;W=100;L=1172.595446;CN1=Male 5;CN2=Male 5;END | 0.368382 | 586.30; 0.00; 0.00; | EXT. Flat 25 | 100 | New Construction | EXT. Flat
M-RoundDuct | 1 ,SHE_DRAWING+SHEET.dgn,Design Model;11,SHE-15.MEHP.dgn,Design Model:260902 | 2120.1 | FN=302-m;W=100;L=2120.095613;CN1=Male 5;CN2=Male 5;END | 0.666048 | 1060.05; 0.00; 0.00; | EXT. Flat 25 | 100 | New Construction | EXT. Flat
M-RoundDuct | 1 ,SHE_DRAWING+SHEET.dgn,Design Model;11,SHE-15.MEHP.dgn,Design Model:261701 | 2620.1 | FN=302-m;W=100;L=2620.095613;CN1=Male 5;CN2=Male 5;END | 0.823127 | 1310.05; 0.00; 0.00; | EXT. Flat 26 | 100 | New Construction | EXT. Flat
M-RoundDuct | 1 ,SHE_DRAWING+SHEET.dgn,Design Model;11,SHE-15.MEHP.dgn,Design Model:262205 | 2682.64 | FN=302-m;W=100;L=2682.641613;CN1=Male 5;CN2=Male 5;END | 0.842777 | 1341.32; 0.00; 0.00; | EXT. Flat 26 | 100 | New Construction | EXT. Flat
M-RoundDuct | 1 ,SHE_DRAWING+SHEET.dgn,Design Model;11,SHE-15.MEHP.dgn,Design Model:262349 | 1188.14 | FN=302-m;W=100;L=1188.137127;CN1=Male 5;CN2=Male 5;END | 0.373264 | 594.07; 0.00; 0.00; | EXT. Flat 26 | 100 | New Construction | EXT. Flat
M-RoundDuct | 1 ,SHE_DRAWING+SHEET.dgn,Design Model;11,SHE-15.MEHP.dgn,Design Model:262853 | 2106.22 | FN=302-m;W=100;L=2106.217613;CN1=Male 5;CN2=Male 5;END | 0.661688 | 1053.11; 0.00; 0.00; | EXT. Flat 23 | 100 | New Construction | EXT. Flat
M-RoundDuct | 1 ,SHE_DRAWING+SHEET.dgn,Design Model;11,SHE-15.MEHP.dgn,Design Model:262955 | 2106.22 | FN=302-m;W=100;L=2106.217613;CN1=Male 5;CN2=Male 5;END | 0.661688 | 1053.11; 0.00; 0.00; | EXT. Flat 24 | 100 | New Construction | EXT. Flat
M-RoundDuct | 1 ,SHE_DRAWING+SHEET.dgn,Design Model;11,SHE-15.MEHP.dgn,Design Model:263057 | 1075 | FN=302-m;W=100;L=1075;CN1=Male 5;CN2=Male 5;END | 0.337721 | 537.50; 0.00; 0.00; | EXT. Flat 25 | 100 | New Construction | EXT. Flat
M-RoundDuct | 1 ,SHE_DRAWING+SHEET.dgn,Design Model;11,SHE-15.MEHP.dgn,Design Model:263392 | 4044.55 | FN=302-m;W=1200;L=4044.548191;CN1=Male 5;CN2=Male 5;END | 15.2476 | 2022.27; 0.00; 0.00; | EXT. AOV | 1200 |  | EXT. AOV
M-RoundDuct | 1 ,SHE_DRAWING+SHEET.dgn,Design Model;11,SHE-15.MEHP.dgn,Design Model:293776 | 100 | FN=302-m;W=100;L=100;CN1=Male 5;CN2=Male 5;END | 0.031416 | 50.00; 0.00; 0.00; | DRM | 100 | New Construction | DRM
M-RoundDuct | 1 ,SHE_DRAWING+SHEET.dgn,Design Model;11,SHE-15.MEHP.dgn,Design Model:293938 | 100 | FN=302-m;W=100;L=100;CN1=Male 5;CN2=Male 5;END | 0.031416 | 50.00; 0.00; 0.00; | DRM | 100 | New Construction | DRM
M-RoundDuct | 1 ,SHE_DRAWING+SHEET.dgn,Design Model;11,SHE-15.MEHP.dgn,Design Model:293980 | 100 | FN=302-m;W=100;L=100;CN1=Male 5;CN2=Male 5;END | 0.031416 | 50.00; 0.00; 0.00; | DRM | 100 | New Construction | DRM
M-RoundDuct | 1 ,SHE_DRAWING+SHEET.dgn,Design Model;11,SHE-15.MEHP.dgn,Design Model:294022 | 100 | FN=302-m;W=100;L=100;CN1=Male 5;CN2=Male 5;END | 0.031416 | 50.00; 0.00; 0.00; | DRM | 100 | New Construction | DRM
M-RoundDuct | 1 ,SHE_DRAWING+SHEET.dgn,Design Model;11,SHE-15.MEHP.dgn,Design Model:294064 | 100 | FN=302-m;W=100;L=100;CN1=Male 5;CN2=Male 5;END | 0.031416 | 50.00; 0.00; 0.00; | DRM | 100 | New Construction | DRM

# IfcFlowTerminal: M-BmvRadiator-Column (34)
In: RL
Type - Radiator Parameters - Box | Height: 625; Box | Width: 150; Box | Length: 500; Number Of Sections: 10; Flow | Connection Side: 1-Left; Flow | Outside Diameter: 25; Flow Top Offset: 525; Flow | Length: 50; Return | Connection Side: 2-Right; Return | Outer Diameter: 25; Return | Top Offset: 100; Return | Length: 50; Connection 1 | Length (L1): 0; Connection | End Type: -; View Display: Iso
Type - Parameters - Insulation | Thickness (mm): 0; Lining | Thickness (mm): 0; Correction Factor: 1.0; Wall Thickness: 0
Type - End Spec1_2 (1 Connection: Round) - Diameter 1 (D1 Ø): 100
Type - Emitters Analytical Parameters - Heat Emission (W): 0; Pressure Drop Type: 1-k value; Emitter Pressure Drop: 0; Flow Valve Type: 1-No Valve; Flow Valve K Value (W/m°C): 0; Return Valve Type: 1-No Valve; Return Valve K Value (W/m°C): 0
Type - Classification - Uniclass2015: Pr_70_60_36_72
Material: M_BSUK_Ventilation
Radiator Parameters - Box | Height: 1200; Box | Width: 25; Number Of Sections: 5; Flow | Outside Diameter: 20; Flow Top Offset: 107.5; Return | Outer Diameter: 20; Return | Top Offset: 101.6; Connection | End Type: -;
Parameters - Type: Towel warmer; Insulation | Surface Area: 0 m2; Lining | Surface Area: 0 m2; Status: BSUK; Air Flow: M
Name | Description | Surface Area (m2) | Center Of Gravity
M-BmvRadiator-Column | 1 ,SHE_DRAWING+SHEET.dgn,Design Model;1,SHE-01.GROUND.dgn,Design Model:262253 | 0.801283 | 150.00; 0.00; 3.89; | Radiator Parameters - Box | Length: 300
M-BmvRadiator-Column | 1 ,SHE_DRAWING+SHEET.dgn,Design Model;2,SHE-02.MEZZANINE.dgn,Design Model:194896 | 0.801283 | 150.00; 0.00; 3.89; | Radiator Parameters - Box | Length: 300
M-BmvRadiator-Column | 1 ,SHE_DRAWING+SHEET.dgn,Design Model;2,SHE-02.MEZZANINE.dgn,Design Model:195239 | 0.801283 | 150.00; 0.00; 3.89; | Radiator Parameters - Box | Length: 300
M-BmvRadiator-Column | 1 ,SHE_DRAWING+SHEET.dgn,Design Model;2,SHE-02.MEZZANINE.dgn,Design Model:195352 | 0.801283 | 150.00; 0.00; 3.89; | Radiator Parameters - Box | Length: 300
M-BmvRadiator-Column | 1 ,SHE_DRAWING+SHEET.dgn,Design Model;4,SHE-03.FIRST.dgn,Design Model:133362 | 1.04628 | 200.00; 0.00; 2.98; | Radiator Parameters - Box | Length: 400
M-BmvRadiator-Column | 1 ,SHE_DRAWING+SHEET.dgn,Design Model;4,SHE-03.FIRST.dgn,Design Model:143194 | 1.29128 | 250.00; 0.00; 2.41;
M-BmvRadiator-Column | 1 ,SHE_DRAWING+SHEET.dgn,Design Model;4,SHE-03.FIRST.dgn,Design Model:145994 | 1.29128 | 250.00; 0.00; 2.41;
M-BmvRadiator-Column | 1 ,SHE_DRAWING+SHEET.dgn,Design Model;4,SHE-03.FIRST.dgn,Design Model:142051 | 1.29128 | 250.00; 0.00; 2.41;
M-BmvRadiator-Column | 1 ,SHE_DRAWING+SHEET.dgn,Design Model;4,SHE-03.FIRST.dgn,Design Model:133475 | 0.801283 | 150.00; 0.00; 3.89; | Radiator Parameters - Box | Length: 300
M-BmvRadiator-Column | 1 ,SHE_DRAWING+SHEET.dgn,Design Model;4,SHE-03.FIRST.dgn,Design Model:229302 | 1.29128 | 250.00; 0.00; 2.41;
M-BmvRadiator-Column | 1 ,SHE_DRAWING+SHEET.dgn,Design Model;4,SHE-03.FIRST.dgn,Design Model:300364 | 1.29128 | 250.00; 0.00; 2.41;
M-BmvRadiator-Column | 1 ,SHE_DRAWING+SHEET.dgn,Design Model;4,SHE-03.FIRST.dgn,Design Model:352516 | 1.29128 | 250.00; 0.00; 2.41;
M-BmvRadiator-Column | 1 ,SHE_DRAWING+SHEET.dgn,Design Model;6,SHE-05.THIRD.dgn,Design Model:133362 | 1.04628 | 200.00; 0.00; 2.98; | Radiator Parameters - Box | Length: 400
M-BmvRadiator-Column | 1 ,SHE_DRAWING+SHEET.dgn,Design Model;6,SHE-05.THIRD.dgn,Design Model:143194 | 1.29128 | 250.00; 0.00; 2.41;
M-BmvRadiator-Column | 1 ,SHE_DRAWING+SHEET.dgn,Design Model;6,SHE-05.THIRD.dgn,Design Model:145994 | 1.29128 | 250.00; 0.00; 2.41;
M-BmvRadiator-Column | 1 ,SHE_DRAWING+SHEET.dgn,Design Model;6,SHE-05.THIRD.dgn,Design Model:142051 | 1.29128 | 250.00; 0.00; 2.41;
M-BmvRadiator-Column | 1 ,SHE_DRAWING+SHEET.dgn,Design Model;6,SHE-05.THIRD.dgn,Design Model:133475 | 0.801283 | 150.00; 0.00; 3.89; | Radiator Parameters - Box | Length: 300
M-BmvRadiator-Column | 1 ,SHE_DRAWING+SHEET.dgn,Design Model;6,SHE-05.THIRD.dgn,Design Model:229302 | 1.29128 | 250.00; 0.00; 2.41;
M-BmvRadiator-Column | 1 ,SHE_DRAWING+SHEET.dgn,Design Model;6,SHE-05.THIRD.dgn,Design Model:300364 | 1.29128 | 250.00; 0.00; 2.41;
M-BmvRadiator-Column | 1 ,SHE_DRAWING+SHEET.dgn,Design Model;6,SHE-05.THIRD.dgn,Design Model:435141 | 1.29128 | 250.00; 0.00; 2.41;
M-BmvRadiator-Column | 1 ,SHE_DRAWING+SHEET.dgn,Design Model;7,SHE-06.FOURTH.dgn,Design Model:485879 | 1.29128 | 250.00; 0.00; 2.41;
M-BmvRadiator-Column | 1 ,SHE_DRAWING+SHEET.dgn,Design Model;7,SHE-06.FOURTH.dgn,Design Model:488452 | 1.29128 | 250.00; 0.00; 2.41;
M-BmvRadiator-Column | 1 ,SHE_DRAWING+SHEET.dgn,Design Model;7,SHE-06.FOURTH.dgn,Design Model:488565 | 1.29128 | 250.00; 0.00; 2.41;
M-BmvRadiator-Column | 1 ,SHE_DRAWING+SHEET.dgn,Design Model;7,SHE-06.FOURTH.dgn,Design Model:488678 | 1.29128 | 250.00; 0.00; 2.41;
M-BmvRadiator-Column | 1 ,SHE_DRAWING+SHEET.dgn,Design Model;7,SHE-06.FOURTH.dgn,Design Model:488791 | 1.29128 | 250.00; 0.00; 2.41;
M-BmvRadiator-Column | 1 ,SHE_DRAWING+SHEET.dgn,Design Model;7,SHE-06.FOURTH.dgn,Design Model:488904 | 1.29128 | 250.00; 0.00; 2.41;
M-BmvRadiator-Column | 1 ,SHE_DRAWING+SHEET.dgn,Design Model;18,SHE-04.SECOND.dgn,Design Model:133362 | 1.04628 | 200.00; 0.00; 2.98; | Radiator Parameters - Box | Length: 400
M-BmvRadiator-Column | 1 ,SHE_DRAWING+SHEET.dgn,Design Model;18,SHE-04.SECOND.dgn,Design Model:143194 | 1.29128 | 250.00; 0.00; 2.41;
M-BmvRadiator-Column | 1 ,SHE_DRAWING+SHEET.dgn,Design Model;18,SHE-04.SECOND.dgn,Design Model:145994 | 1.29128 | 250.00; 0.00; 2.41;
M-BmvRadiator-Column | 1 ,SHE_DRAWING+SHEET.dgn,Design Model;18,SHE-04.SECOND.dgn,Design Model:142051 | 1.29128 | 250.00; 0.00; 2.41;
M-BmvRadiator-Column | 1 ,SHE_DRAWING+SHEET.dgn,Design Model;18,SHE-04.SECOND.dgn,Design Model:133475 | 0.801283 | 150.00; 0.00; 3.89; | Radiator Parameters - Box | Length: 300
M-BmvRadiator-Column | 1 ,SHE_DRAWING+SHEET.dgn,Design Model;18,SHE-04.SECOND.dgn,Design Model:229302 | 1.29128 | 250.00; 0.00; 2.41;
M-BmvRadiator-Column | 1 ,SHE_DRAWING+SHEET.dgn,Design Model;18,SHE-04.SECOND.dgn,Design Model:300364 | 1.29128 | 250.00; 0.00; 2.41;
M-BmvRadiator-Column | 1 ,SHE_DRAWING+SHEET.dgn,Design Model;18,SHE-04.SECOND.dgn,Design Model:374557 | 0.801283 | 150.00; 0.00; 3.89; | Radiator Parameters - Box | Length: 300

# IfcFlowTerminal: M-BmvRadiatorpanel-Panel (66)
In: RL
Type - Radiator Panel Parameters - Box | Height: 450; Box | Width: 150; Box | Length: 750; Mounting Height: 350; Mounting Width: 50; Mounting Length: 600; Radiator Type: 1-Panel; Panel Type: 1-Single; Flow | Connection Side: 1-Left; Flow Location: 1-Panel 1; Flow | Outside Diameter: 25; Flow Top Offset: 375; Flow | Length: 50; Return | Connection Side: 2-Right; Return Location: 1-Panel 1; Return | Outer Diameter: 25; Return | Top Offset: 100; Return | Length: 50; Connection 1 | Length (L1): 0; Connection | End Type: -; View Display: Iso
Type - Parameters - Insulation | Thickness (mm): 0; Lining | Thickness (mm): 0; Correction Factor: 1.0; Wall Thickness: 0
Type - End Spec1_2 (1 Connection: Round) - Diameter 1 (D1 Ø): 100
Type - Emitters Analytical Parameters - Heat Emission (W): 0; Pressure Drop Type: 1-k value; Emitter Pressure Drop: 0; Flow Valve Type: 1-No Valve; Flow Valve K Value (W/m°C): 0; Return Valve Type: 1-No Valve; Return Valve K Value (W/m°C): 0
Type - Classification - Uniclass2015: Pr_70_60_36_71
Material: M_BSUK_Ventilation
Radiator Panel Parameters - Box | Height: 730; Box | Width: 185; Mounting Width: 25; Connection | End Type: -;
Parameters - Insulation | Surface Area: 0 m2; Lining | Surface Area: 0 m2; Status: BSUK; Air Flow: M
Construction Phase - Phase: New Construction
Name | Description | Box | Length | Type | Surface Area (m2) | Center Of Gravity
M-BmvRadiatorpanel-Panel | 1,SHE_DRAWING+SHEET.dgn,Design Model;1,SHE-01.GROUND.dgn,Design Model:257385 | 865 | Dimplex QM100RF | 2.3441 | 0.00; 0.00; 0.00;
M-BmvRadiatorpanel-Panel | 1,SHE_DRAWING+SHEET.dgn,Design Model;1,SHE-01.GROUND.dgn,Design Model:259679 | 865 | Dimplex QM100RF | 2.3441 | 0.00; 0.00; 0.00;
M-BmvRadiatorpanel-Panel | 1,SHE_DRAWING+SHEET.dgn,Design Model;2,SHE-02.MEZZANINE.dgn ,Design Model:195011 | 865 | Dimplex QM100RF | 2.3441 | 0.00; 0.00; 0.00;
M-BmvRadiatorpanel-Panel | 1,SHE_DRAWING+SHEET.dgn,Design Model;2,SHE-02.MEZZANINE.dgn ,Design Model:195087 | 865 | Dimplex QM100RF | 2.3441 | 0.00; 0.00; 0.00;
M-BmvRadiatorpanel-Panel | 1,SHE_DRAWING+SHEET.dgn,Design Model;2,SHE-02.MEZZANINE.dgn ,Design Model:195163 | 865 | Dimplex QM100RF | 2.3441 | 0.00; 0.00; 0.00;
M-BmvRadiatorpanel-Panel | 1,SHE_DRAWING+SHEET.dgn,Design Model;4,SHE-03.FIRST.dgn,Design Model:351056 | 865 | Dimplex QM100RF | 2.3441 | 0.00; 0.00; 0.00;
M-BmvRadiatorpanel-Panel | 1,SHE_DRAWING+SHEET.dgn,Design Model;4,SHE-03.FIRST.dgn,Design Model:351132 | 1069 | Dimplex QM150RF | 2.71742 | 534.50; 23.45; 1.08;
M-BmvRadiatorpanel-Panel | 1,SHE_DRAWING+SHEET.dgn,Design Model;4,SHE-03.FIRST.dgn,Design Model:351832 | 1069 | Dimplex QM150RF | 2.71742 | 534.50; 23.45; 1.08;
M-BmvRadiatorpanel-Panel | 1,SHE_DRAWING+SHEET.dgn,Design Model;4,SHE-03.FIRST.dgn,Design Model:351908 | 865 | Dimplex QM100RF | 2.3441 | 0.00; 0.00; 0.00;
M-BmvRadiatorpanel-Panel | 1,SHE_DRAWING+SHEET.dgn,Design Model;4,SHE-03.FIRST.dgn,Design Model:351984 | 1069 | Dimplex QM150RF | 2.71742 | 534.50; 23.45; 1.08;
M-BmvRadiatorpanel-Panel | 1,SHE_DRAWING+SHEET.dgn,Design Model;4,SHE-03.FIRST.dgn,Design Model:352060 | 1069 | Dimplex QM150RF | 2.71742 | 534.50; 23.45; 1.08;
M-BmvRadiatorpanel-Panel | 1,SHE_DRAWING+SHEET.dgn,Design Model;4,SHE-03.FIRST.dgn,Design Model:352136 | 1069 | Dimplex QM150RF | 2.71742 | 534.50; 23.45; 1.08;
M-BmvRadiatorpanel-Panel | 1,SHE_DRAWING+SHEET.dgn,Design Model;4,SHE-03.FIRST.dgn,Design Model:352212 | 865 | Dimplex QM100RF | 2.3441 | 0.00; 0.00; 0.00;
M-BmvRadiatorpanel-Panel | 1,SHE_DRAWING+SHEET.dgn,Design Model;4,SHE-03.FIRST.dgn,Design Model:352288 | 865 | Dimplex QM100RF | 2.3441 | 0.00; 0.00; 0.00;
M-BmvRadiatorpanel-Panel | 1,SHE_DRAWING+SHEET.dgn,Design Model;4,SHE-03.FIRST.dgn,Design Model:352364 | 1069 | Dimplex QM150RF | 2.71742 | 534.50; 23.45; 1.08;
M-BmvRadiatorpanel-Panel | 1,SHE_DRAWING+SHEET.dgn,Design Model;4,SHE-03.FIRST.dgn,Design Model:352440 | 865 | Dimplex QM100RF | 2.3441 | 0.00; 0.00; 0.00;
M-BmvRadiatorpanel-Panel | 1,SHE_DRAWING+SHEET.dgn,Design Model;4,SHE-03.FIRST.dgn,Design Model:352815 | 865 | Dimplex QM100RF | 2.3441 | 0.00; 0.00; 0.00;
M-BmvRadiatorpanel-Panel | 1,SHE_DRAWING+SHEET.dgn,Design Model;4,SHE-03.FIRST.dgn,Design Model:352967 | 865 | Dimplex QM100RF | 2.3441 | 0.00; 0.00; 0.00;
M-BmvRadiatorpanel-Panel | 1,SHE_DRAWING+SHEET.dgn,Design Model;4,SHE-03.FIRST.dgn,Design Model:353043 | 865 | Dimplex QM100RF | 2.3441 | 0.00; 0.00; 0.00;
M-BmvRadiatorpanel-Panel | 1,SHE_DRAWING+SHEET.dgn,Design Model;4,SHE-03.FIRST.dgn,Design Model:353119 | 1069 | Dimplex QM150RF | 2.71742 | 534.50; 23.45; 1.08;
M-BmvRadiatorpanel-Panel | 1,SHE_DRAWING+SHEET.dgn,Design Model;6,SHE-05.THIRD.dgn,Design Model:435952 | 1069 | Dimplex QM150RF | 2.71742 | 534.50; 23.45; 1.08;
M-BmvRadiatorpanel-Panel | 1,SHE_DRAWING+SHEET.dgn,Design Model;6,SHE-05.THIRD.dgn,Design Model:436028 | 865 | Dimplex QM100RF | 2.3441 | 0.00; 0.00; 0.00;
M-BmvRadiatorpanel-Panel | 1,SHE_DRAWING+SHEET.dgn,Design Model;6,SHE-05.THIRD.dgn,Design Model:436104 | 1069 | Dimplex QM150RF | 2.71742 | 534.50; 23.45; 1.08;
M-BmvRadiatorpanel-Panel | 1,SHE_DRAWING+SHEET.dgn,Design Model;6,SHE-05.THIRD.dgn,Design Model:436180 | 865 | Dimplex QM100RF | 2.3441 | 0.00; 0.00; 0.00;
M-BmvRadiatorpanel-Panel | 1,SHE_DRAWING+SHEET.dgn,Design Model;6,SHE-05.THIRD.dgn,Design Model:436256 | 865 | Dimplex QM100RF | 2.3441 | 0.00; 0.00; 0.00;
M-BmvRadiatorpanel-Panel | 1,SHE_DRAWING+SHEET.dgn,Design Model;6,SHE-05.THIRD.dgn,Design Model:436332 | 1069 | Dimplex QM150RF | 2.71742 | 534.50; 23.45; 1.08;
M-BmvRadiatorpanel-Panel | 1,SHE_DRAWING+SHEET.dgn,Design Model;6,SHE-05.THIRD.dgn,Design Model:436408 | 1069 | Dimplex QM150RF | 2.71742 | 534.50; 23.45; 1.08;
M-BmvRadiatorpanel-Panel | 1,SHE_DRAWING+SHEET.dgn,Design Model;6,SHE-05.THIRD.dgn,Design Model:436484 | 865 | Dimplex QM100RF | 2.3441 | 0.00; 0.00; 0.00;
M-BmvRadiatorpanel-Panel | 1,SHE_DRAWING+SHEET.dgn,Design Model;6,SHE-05.THIRD.dgn,Design Model:436560 | 1069 | Dimplex QM150RF | 2.71742 | 534.50; 23.45; 1.08;
M-BmvRadiatorpanel-Panel | 1,SHE_DRAWING+SHEET.dgn,Design Model;6,SHE-05.THIRD.dgn,Design Model:436636 | 865 | Dimplex QM100RF | 2.3441 | 0.00; 0.00; 0.00;
M-BmvRadiatorpanel-Panel | 1,SHE_DRAWING+SHEET.dgn,Design Model;6,SHE-05.THIRD.dgn,Design Model:436712 | 1069 | Dimplex QM150RF | 2.71742 | 534.50; 23.45; 1.08;
M-BmvRadiatorpanel-Panel | 1,SHE_DRAWING+SHEET.dgn,Design Model;6,SHE-05.THIRD.dgn,Design Model:436788 | 865 | Dimplex QM100RF | 2.3441 | 0.00; 0.00; 0.00;
M-BmvRadiatorpanel-Panel | 1,SHE_DRAWING+SHEET.dgn,Design Model;6,SHE-05.THIRD.dgn,Design Model:436864 | 865 | Dimplex QM100RF | 2.3441 | 0.00; 0.00; 0.00;
M-BmvRadiatorpanel-Panel | 1,SHE_DRAWING+SHEET.dgn,Design Model;6,SHE-05.THIRD.dgn,Design Model:436940 | 1069 | Dimplex QM150RF | 2.71742 | 534.50; 23.45; 1.08;
M-BmvRadiatorpanel-Panel | 1,SHE_DRAWING+SHEET.dgn,Design Model;6,SHE-05.THIRD.dgn,Design Model:437016 | 865 | Dimplex QM100RF | 2.3441 | 0.00; 0.00; 0.00;
M-BmvRadiatorpanel-Panel | 1,SHE_DRAWING+SHEET.dgn,Design Model;7,SHE-06.FOURTH.dgn,Design Model:485803 | 865 | Dimplex QM100RF | 2.3441 | 0.00; 0.00; 0.00;
M-BmvRadiatorpanel-Panel | 1,SHE_DRAWING+SHEET.dgn,Design Model;7,SHE-06.FOURTH.dgn,Design Model:485992 | 865 | Dimplex QM100RF | 2.3441 | 0.00; 0.00; 0.00;
M-BmvRadiatorpanel-Panel | 1,SHE_DRAWING+SHEET.dgn,Design Model;7,SHE-06.FOURTH.dgn,Design Model:486068 | 865 | Dimplex QM100RF | 2.3441 | 0.00; 0.00; 0.00;
M-BmvRadiatorpanel-Panel | 1,SHE_DRAWING+SHEET.dgn,Design Model;7,SHE-06.FOURTH.dgn,Design Model:486144 | 865 | Dimplex QM100RF | 2.3441 | 0.00; 0.00; 0.00;
M-BmvRadiatorpanel-Panel | 1,SHE_DRAWING+SHEET.dgn,Design Model;7,SHE-06.FOURTH.dgn,Design Model:486220 | 865 | Dimplex QM100RF | 2.3441 | 0.00; 0.00; 0.00;
M-BmvRadiatorpanel-Panel | 1,SHE_DRAWING+SHEET.dgn,Design Model;7,SHE-06.FOURTH.dgn,Design Model:487072 | 580 | Dimplex QM150RF | 1.80702 | 290.00; 34.14; 1.58; | Radiator Panel Parameters - Mounting Length: 580
M-BmvRadiatorpanel-Panel | 1,SHE_DRAWING+SHEET.dgn,Design Model;7,SHE-06.FOURTH.dgn,Design Model:487616 | 580 | Dimplex QM150RF | 1.80702 | 290.00; 34.14; 1.58; | Radiator Panel Parameters - Mounting Length: 580
M-BmvRadiatorpanel-Panel | 1,SHE_DRAWING+SHEET.dgn,Design Model;7,SHE-06.FOURTH.dgn,Design Model:487692 | 580 | Dimplex QM150RF | 1.80702 | 290.00; 34.14; 1.58; | Radiator Panel Parameters - Mounting Length: 580
M-BmvRadiatorpanel-Panel | 1,SHE_DRAWING+SHEET.dgn,Design Model;7,SHE-06.FOURTH.dgn,Design Model:487768 | 580 | Dimplex QM150RF | 1.80702 | 290.00; 34.14; 1.58; | Radiator Panel Parameters - Mounting Length: 580
M-BmvRadiatorpanel-Panel | 1,SHE_DRAWING+SHEET.dgn,Design Model;7,SHE-06.FOURTH.dgn,Design Model:487920 | 865 | Dimplex QM100RF | 2.3441 | 0.00; 0.00; 0.00;
M-BmvRadiatorpanel-Panel | 1,SHE_DRAWING+SHEET.dgn,Design Model;7,SHE-06.FOURTH.dgn,Design Model:487996 | 865 | Dimplex QM100RF | 2.3441 | 0.00; 0.00; 0.00;
M-BmvRadiatorpanel-Panel | 1,SHE_DRAWING+SHEET.dgn,Design Model;7,SHE-06.FOURTH.dgn,Design Model:488072 | 865 | Dimplex QM100RF | 2.3441 | 0.00; 0.00; 0.00;
M-BmvRadiatorpanel-Panel | 1,SHE_DRAWING+SHEET.dgn,Design Model;7,SHE-06.FOURTH.dgn,Design Model:488148 | 865 | Dimplex QM100RF | 2.3441 | 0.00; 0.00; 0.00;
M-BmvRadiatorpanel-Panel | 1,SHE_DRAWING+SHEET.dgn,Design Model;7,SHE-06.FOURTH.dgn,Design Model:488224 | 865 | Dimplex QM100RF | 2.3441 | 0.00; 0.00; 0.00;
M-BmvRadiatorpanel-Panel | 1,SHE_DRAWING+SHEET.dgn,Design Model;7,SHE-06.FOURTH.dgn,Design Model:488300 | 865 | Dimplex QM100RF | 2.3441 | 0.00; 0.00; 0.00;
M-BmvRadiatorpanel-Panel | 1,SHE_DRAWING+SHEET.dgn,Design Model;7,SHE-06.FOURTH.dgn,Design Model:488376 | 865 | Dimplex QM100RF | 2.3441 | 0.00; 0.00; 0.00;
M-BmvRadiatorpanel-Panel | 1,SHE_DRAWING+SHEET.dgn,Design Model;18,SHE-04.SECOND.dgn ,Design Model:373417 | 1069 | Dimplex QM150RF | 2.71742 | 534.50; 23.45; 1.08;
M-BmvRadiatorpanel-Panel | 1,SHE_DRAWING+SHEET.dgn,Design Model;18,SHE-04.SECOND.dgn ,Design Model:373493 | 865 | Dimplex QM100RF | 2.3441 | 0.00; 0.00; 0.00;
M-BmvRadiatorpanel-Panel | 1,SHE_DRAWING+SHEET.dgn,Design Model;18,SHE-04.SECOND.dgn ,Design Model:373569 | 1069 | Dimplex QM150RF | 2.71742 | 534.50; 23.45; 1.08;
M-BmvRadiatorpanel-Panel | 1,SHE_DRAWING+SHEET.dgn,Design Model;18,SHE-04.SECOND.dgn ,Design Model:373645 | 865 | Dimplex QM100RF | 2.3441 | 0.00; 0.00; 0.00;
M-BmvRadiatorpanel-Panel | 1,SHE_DRAWING+SHEET.dgn,Design Model;18,SHE-04.SECOND.dgn ,Design Model:373721 | 865 | Dimplex QM100RF | 2.3441 | 0.00; 0.00; 0.00;
M-BmvRadiatorpanel-Panel | 1,SHE_DRAWING+SHEET.dgn,Design Model;18,SHE-04.SECOND.dgn ,Design Model:373797 | 1069 | Dimplex QM150RF | 2.71742 | 534.50; 23.45; 1.08;
M-BmvRadiatorpanel-Panel | 1,SHE_DRAWING+SHEET.dgn,Design Model;18,SHE-04.SECOND.dgn ,Design Model:373873 | 1069 | Dimplex QM150RF | 2.71742 | 534.50; 23.45; 1.08;
M-BmvRadiatorpanel-Panel | 1,SHE_DRAWING+SHEET.dgn,Design Model;18,SHE-04.SECOND.dgn ,Design Model:373949 | 865 | Dimplex QM100RF | 2.3441 | 0.00; 0.00; 0.00;
M-BmvRadiatorpanel-Panel | 1,SHE_DRAWING+SHEET.dgn,Design Model;18,SHE-04.SECOND.dgn ,Design Model:374025 | 1069 | Dimplex QM150RF | 2.71742 | 534.50; 23.45; 1.08;
M-BmvRadiatorpanel-Panel | 1,SHE_DRAWING+SHEET.dgn,Design Model;18,SHE-04.SECOND.dgn ,Design Model:374101 | 865 | Dimplex QM100RF | 2.3441 | 0.00; 0.00; 0.00;
M-BmvRadiatorpanel-Panel | 1,SHE_DRAWING+SHEET.dgn,Design Model;18,SHE-04.SECOND.dgn ,Design Model:374177 | 1069 | Dimplex QM150RF | 2.71742 | 534.50; 23.45; 1.08;
M-BmvRadiatorpanel-Panel | 1,SHE_DRAWING+SHEET.dgn,Design Model;18,SHE-04.SECOND.dgn ,Design Model:374253 | 865 | Dimplex QM100RF | 2.3441 | 0.00; 0.00; 0.00;
M-BmvRadiatorpanel-Panel | 1,SHE_DRAWING+SHEET.dgn,Design Model;18,SHE-04.SECOND.dgn ,Design Model:374329 | 865 | Dimplex QM100RF | 2.3441 | 0.00; 0.00; 0.00;
M-BmvRadiatorpanel-Panel | 1,SHE_DRAWING+SHEET.dgn,Design Model;18,SHE-04.SECOND.dgn ,Design Model:374405 | 1069 | Dimplex QM150RF | 2.71742 | 534.50; 23.45; 1.08;
M-BmvRadiatorpanel-Panel | 1,SHE_DRAWING+SHEET.dgn,Design Model;18,SHE-04.SECOND.dgn ,Design Model:374481 | 865 | Dimplex QM100RF | 2.3441 | 0.00; 0.00; 0.00;

# IfcFlowTerminal: M-RectBarSlotsEndGrille-BarSlots (22)
In: RL
Type - PredefinedType: REGISTER
Type - Parameters - Insulation | Thickness (mm): 0; Lining | Thickness (mm): 0; Status: New; Pressure Class: Low; Air Flow: Supply; Correction Factor: 1.0; Wall Thickness: 0
Type - End Spec1_1 (1 Connection: Rect) - Width 1 (W1): 400; Depth 1 (D1): 350
Type - Classification - Uniclass2015: Pr_70_65_04_03
Type - Bar Slot Rectangular Grille Parameters - Thickness: 75; Side Distance: 25; Bottom Distance: 25; Inside Width: 350; Inside Depth: 300; No. Of Slots: 10; Slot Thickness: 5; Horizontal: yes; Panel Width: 0; Panel Depth: 0; Panel Thickness: 0; With Damper: no; Damper | Angle: 0; Damper | Thickness: 0; Connection | Offset: 0; Blade Orientation: 2-opposing; View Display: iso; Air Flow Rate: 0; Air Flow Rate Unit: 1-l/s; Center Offset: 0
Material: M_BSUK_Ventilation
Parameters - Insulation | Surface Area: 0 m2; Lining | Surface Area: 0 m2; Status: BSUK; Air Flow: M
End Spec1_1 (1 Connection: Rect) - Width 1 (W1): 800
Bar Slot Rectangular Grille Parameters - AutoSize: 1-symprop; Thickness: 20; Side Distance: 40; Inside Width: 720; Panel Width: 800; Outlet Pressure (Pa): 0
Name | Description | Surface Area (m2) | Center Of Gravity | Depth 1 (D1) = Panel Depth | Bottom Distance | Inside Depth
M-RectBarSlotsEndGrille-BarSlots | 1,SHE_DRAWING+SHEET.dgn,Design Model;7 ,SHE-06.FOURTH.dgn,Design Model:503159 | 0.0632 | 14.43; 0.00; 0.00; | 80 | 4 | 72
M-RectBarSlotsEndGrille-BarSlots | 1,SHE_DRAWING+SHEET.dgn,Design Model;7 ,SHE-06.FOURTH.dgn,Design Model:503649 | 0.0632 | 14.43; 0.00; 0.00; | 80 | 4 | 72
M-RectBarSlotsEndGrille-BarSlots | 1,SHE_DRAWING+SHEET.dgn,Design Model;7 ,SHE-06.FOURTH.dgn,Design Model:503727 | 0.0632 | 14.43; 0.00; 0.00; | 80 | 4 | 72
M-RectBarSlotsEndGrille-BarSlots | 1,SHE_DRAWING+SHEET.dgn,Design Model;7 ,SHE-06.FOURTH.dgn,Design Model:503884 | 0.0632 | 14.43; 0.00; 0.00; | 80 | 4 | 72
M-RectBarSlotsEndGrille-BarSlots | 1,SHE_DRAWING+SHEET.dgn,Design Model;7 ,SHE-06.FOURTH.dgn,Design Model:503962 | 0.0632 | 14.43; 0.00; 0.00; | 80 | 4 | 72
M-RectBarSlotsEndGrille-BarSlots | 1,SHE_DRAWING+SHEET.dgn,Design Model;7 ,SHE-06.FOURTH.dgn,Design Model:504040 | 0.0632 | 14.43; 0.00; 0.00; | 80 | 4 | 72
M-RectBarSlotsEndGrille-BarSlots | 1,SHE_DRAWING+SHEET.dgn,Design Model;8 ,SHE-07.FIFTH.dgn,Design Model:291397 | 0.08 | 15.50; 0.00; 0.00; | 100 | 5 | 90
M-RectBarSlotsEndGrille-BarSlots | 1,SHE_DRAWING+SHEET.dgn,Design Model;8 ,SHE-07.FIFTH.dgn,Design Model:292002 | 0.08 | 15.50; 0.00; 0.00; | 100 | 5 | 90
M-RectBarSlotsEndGrille-BarSlots | 1,SHE_DRAWING+SHEET.dgn,Design Model;8 ,SHE-07.FIFTH.dgn,Design Model:292080 | 0.08 | 15.50; 0.00; 0.00; | 100 | 5 | 90
M-RectBarSlotsEndGrille-BarSlots | 1,SHE_DRAWING+SHEET.dgn,Design Model;8 ,SHE-07.FIFTH.dgn,Design Model:292158 | 0.08 | 15.50; 0.00; 0.00; | 100 | 5 | 90
M-RectBarSlotsEndGrille-BarSlots | 1,SHE_DRAWING+SHEET.dgn,Design Model;8 ,SHE-07.FIFTH.dgn,Design Model:292236 | 0.08 | 15.50; 0.00; 0.00; | 100 | 5 | 90
M-RectBarSlotsEndGrille-BarSlots | 1,SHE_DRAWING+SHEET.dgn,Design Model;8 ,SHE-07.FIFTH.dgn,Design Model:292314 | 0.08 | 15.50; 0.00; 0.00; | 100 | 5 | 90
M-RectBarSlotsEndGrille-BarSlots | 1,SHE_DRAWING+SHEET.dgn,Design Model;8 ,SHE-07.FIFTH.dgn,Design Model:292392 | 0.08 | 15.50; 0.00; 0.00; | 100 | 5 | 90
M-RectBarSlotsEndGrille-BarSlots | 1,SHE_DRAWING+SHEET.dgn,Design Model;8 ,SHE-07.FIFTH.dgn,Design Model:292470 | 0.08 | 15.50; 0.00; 0.00; | 100 | 5 | 90
M-RectBarSlotsEndGrille-BarSlots | 1,SHE_DRAWING+SHEET.dgn,Design Model;8 ,SHE-07.FIFTH.dgn,Design Model:292548 | 0.08 | 15.50; 0.00; 0.00; | 100 | 5 | 90
M-RectBarSlotsEndGrille-BarSlots | 1,SHE_DRAWING+SHEET.dgn,Design Model;8 ,SHE-07.FIFTH.dgn,Design Model:292626 | 0.08 | 15.50; 0.00; 0.00; | 100 | 5 | 90
M-RectBarSlotsEndGrille-BarSlots | 1,SHE_DRAWING+SHEET.dgn,Design Model;8 ,SHE-07.FIFTH.dgn,Design Model:292704 | 0.08 | 15.50; 0.00; 0.00; | 100 | 5 | 90
M-RectBarSlotsEndGrille-BarSlots | 1,SHE_DRAWING+SHEET.dgn,Design Model;8 ,SHE-07.FIFTH.dgn,Design Model:292782 | 0.08 | 15.50; 0.00; 0.00; | 100 | 5 | 90
M-RectBarSlotsEndGrille-BarSlots | 1,SHE_DRAWING+SHEET.dgn,Design Model;8 ,SHE-07.FIFTH.dgn,Design Model:292860 | 0.08 | 15.50; 0.00; 0.00; | 100 | 5 | 90
M-RectBarSlotsEndGrille-BarSlots | 1,SHE_DRAWING+SHEET.dgn,Design Model;8 ,SHE-07.FIFTH.dgn,Design Model:292938 | 0.08 | 15.50; 0.00; 0.00; | 100 | 5 | 90
M-RectBarSlotsEndGrille-BarSlots | 1,SHE_DRAWING+SHEET.dgn,Design Model;8 ,SHE-07.FIFTH.dgn,Design Model:293016 | 0.08 | 15.50; 0.00; 0.00; | 100 | 5 | 90
M-RectBarSlotsEndGrille-BarSlots | 1,SHE_DRAWING+SHEET.dgn,Design Model;8 ,SHE-07.FIFTH.dgn,Design Model:293094 | 0.08 | 15.50; 0.00; 0.00; | 100 | 5 | 90

# IfcFlowTerminal: SHE_A-Sink_47x100 (5)
In: RL
Type - Plumbing Fixture - Connection | Vent: no
Type - Accessibility - Accessibility | Handicap Accessible: no; Has Non-skid Surface: no
Plumbing Fixture - Connection | Cold Water: 0 m; Connection | Hot Water: 0 m; Connection | Waste: 0 m; Mounting | Height: 0 m
Parametric Definition - Parametric | File Type: BXC; Parametric | File Name: K-3206-3
Identification - ID | Description: washbasin
Discipline - Discipline: Architectural
Construction Phase - Phase: New Construction
Classification - Uniclass2015: Pr_40_20_96_15
Name | Description | ID | Notes
SHE_A-Sink_47x100 | washbasin :1,SHE_DRAWING+SHEET.dgn,Design Model;7,SHE-06.FOURTH.dgn ,Design Model:248381 | 600x470mm
SHE_A-Sink_47x100 | washbasin :1,SHE_DRAWING+SHEET.dgn,Design Model;7,SHE-06.FOURTH.dgn ,Design Model:263952 | 1000x470mm
SHE_A-Sink_47x100 | washbasin :1,SHE_DRAWING+SHEET.dgn,Design Model;7,SHE-06.FOURTH.dgn ,Design Model:406288 | 1000x470mm
SHE_A-Sink_47x100 | washbasin :1,SHE_DRAWING+SHEET.dgn,Design Model;7,SHE-06.FOURTH.dgn ,Design Model:407116 | 1000x470mm
SHE_A-Sink_47x100 | washbasin :1,SHE_DRAWING+SHEET.dgn,Design Model;7,SHE-06.FOURTH.dgn ,Design Model:416690 | 1000x470mm

# IfcFlowTerminal: SHE_A-Sink_47x60 (11)
In: RL
Type - Plumbing Fixture - Connection | Vent: no
Type - Accessibility - Accessibility | Handicap Accessible: no; Has Non-skid Surface: no
Plumbing Fixture - Connection | Cold Water: 0 m; Connection | Hot Water: 0 m; Connection | Waste: 0 m; Mounting | Height: 0 m
Parametric Definition - Parametric | File Type: BXC; Parametric | File Name: K-3206-3
Identification - ID | Description: washbasin
Discipline - Discipline: Architectural
Construction Phase - Phase: New Construction
Classification - Uniclass2015: Pr_40_20_96_15
Name | Description | ID | Notes
SHE_A-Sink_47x60 | washbasin :1,SHE_DRAWING+SHEET.dgn,Design Model;1,SHE-01.GROUND.dgn ,Design Model:155272 | 600x470mm
SHE_A-Sink_47x60 | washbasin :1,SHE_DRAWING+SHEET.dgn,Design Model;1,SHE-01.GROUND.dgn ,Design Model:156320 | 600x470mm
SHE_A-Sink_47x60 | washbasin :1,SHE_DRAWING+SHEET.dgn,Design Model;2,SHE-02.MEZZANINE.dgn ,Design Model:120921 | 600x470mm
SHE_A-Sink_47x60 | washbasin :1,SHE_DRAWING+SHEET.dgn,Design Model;2,SHE-02.MEZZANINE.dgn ,Design Model:120938 | 600x470mm
SHE_A-Sink_47x60 | washbasin :1,SHE_DRAWING+SHEET.dgn,Design Model;2,SHE-02.MEZZANINE.dgn ,Design Model:120946 | 600x470mm
SHE_A-Sink_47x60 | washbasin :1,SHE_DRAWING+SHEET.dgn,Design Model;4,SHE-03.FIRST.dgn ,Design Model:146459 | 600x470mm
SHE_A-Sink_47x60 | washbasin :1,SHE_DRAWING+SHEET.dgn,Design Model;6,SHE-05.THIRD.dgn ,Design Model:146459 | 600x470mm
SHE_A-Sink_47x60 | washbasin :1,SHE_DRAWING+SHEET.dgn,Design Model;7,SHE-06.FOURTH.dgn ,Design Model:248790 | 1000x470mm
SHE_A-Sink_47x60 | washbasin :1,SHE_DRAWING+SHEET.dgn,Design Model;7,SHE-06.FOURTH.dgn ,Design Model:256519 | 600x470mm
SHE_A-Sink_47x60 | washbasin :1,SHE_DRAWING+SHEET.dgn,Design Model;7,SHE-06.FOURTH.dgn ,Design Model:514928 | 600x470mm
SHE_A-Sink_47x60 | washbasin :1,SHE_DRAWING+SHEET.dgn,Design Model;18,SHE-04.SECOND.dgn ,Design Model:146459 | 600x470mm

# IfcFlowTerminal: SHE_A-Sink_47x70 (15)
In: RL
Type - Plumbing Fixture - Connection | Vent: no
Type - Accessibility - Accessibility | Handicap Accessible: no; Has Non-skid Surface: no
Plumbing Fixture - Connection | Cold Water: 0 m; Connection | Hot Water: 0 m; Connection | Waste: 0 m; Mounting | Height: 0 m
Parametric Definition - Parametric | File Type: BXC; Parametric | File Name: K-3206-3
Identification - ID | Description: washbasin; ID | Notes: 600x470mm
Discipline - Discipline: Architectural
Construction Phase - Phase: New Construction
Classification - Uniclass2015: Pr_40_20_96_15
Name | Description
SHE_A-Sink_47x70 | washbasin :1,SHE_DRAWING+SHEET.dgn,Design Model;4,SHE-03.FIRST.dgn ,Design Model:146478
SHE_A-Sink_47x70 | washbasin :1,SHE_DRAWING+SHEET.dgn,Design Model;4,SHE-03.FIRST.dgn ,Design Model:292382
SHE_A-Sink_47x70 | washbasin :1,SHE_DRAWING+SHEET.dgn,Design Model;4,SHE-03.FIRST.dgn ,Design Model:299615
SHE_A-Sink_47x70 | washbasin :1,SHE_DRAWING+SHEET.dgn,Design Model;4,SHE-03.FIRST.dgn ,Design Model:300571
SHE_A-Sink_47x70 | washbasin :1,SHE_DRAWING+SHEET.dgn,Design Model;4,SHE-03.FIRST.dgn ,Design Model:327377
SHE_A-Sink_47x70 | washbasin :1,SHE_DRAWING+SHEET.dgn,Design Model;6,SHE-05.THIRD.dgn ,Design Model:146478
SHE_A-Sink_47x70 | washbasin :1,SHE_DRAWING+SHEET.dgn,Design Model;6,SHE-05.THIRD.dgn ,Design Model:292382
SHE_A-Sink_47x70 | washbasin :1,SHE_DRAWING+SHEET.dgn,Design Model;6,SHE-05.THIRD.dgn ,Design Model:299615
SHE_A-Sink_47x70 | washbasin :1,SHE_DRAWING+SHEET.dgn,Design Model;6,SHE-05.THIRD.dgn ,Design Model:300571
SHE_A-Sink_47x70 | washbasin :1,SHE_DRAWING+SHEET.dgn,Design Model;6,SHE-05.THIRD.dgn ,Design Model:327377
SHE_A-Sink_47x70 | washbasin :1,SHE_DRAWING+SHEET.dgn,Design Model;18,SHE-04.SECOND.dgn ,Design Model:146478
SHE_A-Sink_47x70 | washbasin :1,SHE_DRAWING+SHEET.dgn,Design Model;18,SHE-04.SECOND.dgn ,Design Model:292382
SHE_A-Sink_47x70 | washbasin :1,SHE_DRAWING+SHEET.dgn,Design Model;18,SHE-04.SECOND.dgn ,Design Model:299615
SHE_A-Sink_47x70 | washbasin :1,SHE_DRAWING+SHEET.dgn,Design Model;18,SHE-04.SECOND.dgn ,Design Model:300571
SHE_A-Sink_47x70 | washbasin :1,SHE_DRAWING+SHEET.dgn,Design Model;18,SHE-04.SECOND.dgn ,Design Model:327377

# IfcFlowTerminal: SHE_A-Sink_47x80 (7)
In: RL
Type - Plumbing Fixture - Connection | Vent: no
Type - Accessibility - Accessibility | Handicap Accessible: no; Has Non-skid Surface: no
Plumbing Fixture - Connection | Cold Water: 0 m; Connection | Hot Water: 0 m; Connection | Waste: 0 m; Mounting | Height: 0 m
Parametric Definition - Parametric | File Type: BXC; Parametric | File Name: K-3206-3
Identification - ID | Description: washbasin; ID | Notes: 600x470mm
Discipline - Discipline: Architectural
Construction Phase - Phase: New Construction
Classification - Uniclass2015: Pr_40_20_96_15
Name | Description
SHE_A-Sink_47x80 | washbasin :1,SHE_DRAWING+SHEET.dgn,Design Model;1,SHE-01.GROUND.dgn ,Design Model:141034
SHE_A-Sink_47x80 | washbasin :1,SHE_DRAWING+SHEET.dgn,Design Model;4,SHE-03.FIRST.dgn ,Design Model:146548
SHE_A-Sink_47x80 | washbasin :1,SHE_DRAWING+SHEET.dgn,Design Model;4,SHE-03.FIRST.dgn ,Design Model:232319
SHE_A-Sink_47x80 | washbasin :1,SHE_DRAWING+SHEET.dgn,Design Model;6,SHE-05.THIRD.dgn ,Design Model:146548
SHE_A-Sink_47x80 | washbasin :1,SHE_DRAWING+SHEET.dgn,Design Model;6,SHE-05.THIRD.dgn ,Design Model:232319
SHE_A-Sink_47x80 | washbasin :1,SHE_DRAWING+SHEET.dgn,Design Model;18,SHE-04.SECOND.dgn ,Design Model:146548
SHE_A-Sink_47x80 | washbasin :1,SHE_DRAWING+SHEET.dgn,Design Model;18,SHE-04.SECOND.dgn ,Design Model:232319

# IfcFlowTerminal: SHE_A-Toilet_base (38)
In: RL
Plumbing Fixture - Connection | Cold Water: 0 m; Connection | Hot Water: 0 m; Connection | Waste: 0 m; Connection | Vent: no; Mounting | Height: 0 m
Parametric Definition - Parametric | File Type: CEL; Parametric | File Name: toilet
Identification - ID | Description: toilet; ID | Notes: 550x370mm
Discipline - Discipline: Architectural
Construction Phase - Phase: New Construction
Classification - Uniclass2015: Pr_40_20_06_11
Accessibility - Accessibility | Handicap Accessible: no; Has Non-skid Surface: no
Name | Description
SHE_A-Toilet_base | toilet :1,SHE_DRAWING+SHEET.dgn,Design Model;1,SHE-01.GROUND.dgn ,Design Model:155284
SHE_A-Toilet_base | toilet :1,SHE_DRAWING+SHEET.dgn,Design Model;1,SHE-01.GROUND.dgn ,Design Model:155702
SHE_A-Toilet_base | toilet :1,SHE_DRAWING+SHEET.dgn,Design Model;1,SHE-01.GROUND.dgn ,Design Model:183802
SHE_A-Toilet_base | toilet :1,SHE_DRAWING+SHEET.dgn,Design Model;2,SHE-02.MEZZANINE.dgn ,Design Model:120912
SHE_A-Toilet_base | toilet :1,SHE_DRAWING+SHEET.dgn,Design Model;2,SHE-02.MEZZANINE.dgn ,Design Model:120929
SHE_A-Toilet_base | toilet :1,SHE_DRAWING+SHEET.dgn,Design Model;2,SHE-02.MEZZANINE.dgn ,Design Model:120954
SHE_A-Toilet_base | toilet :1,SHE_DRAWING+SHEET.dgn,Design Model;4,SHE-03.FIRST.dgn ,Design Model:146467
SHE_A-Toilet_base | toilet :1,SHE_DRAWING+SHEET.dgn,Design Model;4,SHE-03.FIRST.dgn ,Design Model:146486
SHE_A-Toilet_base | toilet :1,SHE_DRAWING+SHEET.dgn,Design Model;4,SHE-03.FIRST.dgn ,Design Model:146539
SHE_A-Toilet_base | toilet :1,SHE_DRAWING+SHEET.dgn,Design Model;4,SHE-03.FIRST.dgn ,Design Model:146503
SHE_A-Toilet_base | toilet :1,SHE_DRAWING+SHEET.dgn,Design Model;4,SHE-03.FIRST.dgn ,Design Model:229416
SHE_A-Toilet_base | toilet :1,SHE_DRAWING+SHEET.dgn,Design Model;4,SHE-03.FIRST.dgn ,Design Model:270354
SHE_A-Toilet_base | toilet :1,SHE_DRAWING+SHEET.dgn,Design Model;4,SHE-03.FIRST.dgn ,Design Model:300522
SHE_A-Toilet_base | toilet :1,SHE_DRAWING+SHEET.dgn,Design Model;4,SHE-03.FIRST.dgn ,Design Model:327218
SHE_A-Toilet_base | toilet :1,SHE_DRAWING+SHEET.dgn,Design Model;6,SHE-05.THIRD.dgn ,Design Model:146467
SHE_A-Toilet_base | toilet :1,SHE_DRAWING+SHEET.dgn,Design Model;6,SHE-05.THIRD.dgn ,Design Model:146486
SHE_A-Toilet_base | toilet :1,SHE_DRAWING+SHEET.dgn,Design Model;6,SHE-05.THIRD.dgn ,Design Model:146539
SHE_A-Toilet_base | toilet :1,SHE_DRAWING+SHEET.dgn,Design Model;6,SHE-05.THIRD.dgn ,Design Model:146503
SHE_A-Toilet_base | toilet :1,SHE_DRAWING+SHEET.dgn,Design Model;6,SHE-05.THIRD.dgn ,Design Model:229416
SHE_A-Toilet_base | toilet :1,SHE_DRAWING+SHEET.dgn,Design Model;6,SHE-05.THIRD.dgn ,Design Model:270354
SHE_A-Toilet_base | toilet :1,SHE_DRAWING+SHEET.dgn,Design Model;6,SHE-05.THIRD.dgn ,Design Model:300522
SHE_A-Toilet_base | toilet :1,SHE_DRAWING+SHEET.dgn,Design Model;6,SHE-05.THIRD.dgn ,Design Model:327218
SHE_A-Toilet_base | toilet :1,SHE_DRAWING+SHEET.dgn,Design Model;7,SHE-06.FOURTH.dgn ,Design Model:245138
SHE_A-Toilet_base | toilet :1,SHE_DRAWING+SHEET.dgn,Design Model;7,SHE-06.FOURTH.dgn ,Design Model:245172
SHE_A-Toilet_base | toilet :1,SHE_DRAWING+SHEET.dgn,Design Model;7,SHE-06.FOURTH.dgn ,Design Model:245986
SHE_A-Toilet_base | toilet :1,SHE_DRAWING+SHEET.dgn,Design Model;7,SHE-06.FOURTH.dgn ,Design Model:248819
SHE_A-Toilet_base | toilet :1,SHE_DRAWING+SHEET.dgn,Design Model;7,SHE-06.FOURTH.dgn ,Design Model:248828
SHE_A-Toilet_base | toilet :1,SHE_DRAWING+SHEET.dgn,Design Model;7,SHE-06.FOURTH.dgn ,Design Model:258432
SHE_A-Toilet_base | toilet :1,SHE_DRAWING+SHEET.dgn,Design Model;7,SHE-06.FOURTH.dgn ,Design Model:408026
SHE_A-Toilet_base | toilet :1,SHE_DRAWING+SHEET.dgn,Design Model;7,SHE-06.FOURTH.dgn ,Design Model:408038
SHE_A-Toilet_base | toilet :1,SHE_DRAWING+SHEET.dgn,Design Model;18,SHE-04.SECOND.dgn ,Design Model:146467
SHE_A-Toilet_base | toilet :1,SHE_DRAWING+SHEET.dgn,Design Model;18,SHE-04.SECOND.dgn ,Design Model:146486
SHE_A-Toilet_base | toilet :1,SHE_DRAWING+SHEET.dgn,Design Model;18,SHE-04.SECOND.dgn ,Design Model:146539
SHE_A-Toilet_base | toilet :1,SHE_DRAWING+SHEET.dgn,Design Model;18,SHE-04.SECOND.dgn ,Design Model:146503
SHE_A-Toilet_base | toilet :1,SHE_DRAWING+SHEET.dgn,Design Model;18,SHE-04.SECOND.dgn ,Design Model:229416
SHE_A-Toilet_base | toilet :1,SHE_DRAWING+SHEET.dgn,Design Model;18,SHE-04.SECOND.dgn ,Design Model:270354
SHE_A-Toilet_base | toilet :1,SHE_DRAWING+SHEET.dgn,Design Model;18,SHE-04.SECOND.dgn ,Design Model:300522
SHE_A-Toilet_base | toilet :1,SHE_DRAWING+SHEET.dgn,Design Model;18,SHE-04.SECOND.dgn ,Design Model:327218

# IfcFurnishingElement: SHE_A-Cupboard_Electro (26)
Type - Pset_FurnitureTypeCommon - NominalDepth: 0.25 m; NominalHeight: 2.5 m; NominalLength: 0.7 m
Type - Discipline - Discipline: Architectural
Type - Classification - Uniclass2015: Pr_40_30_78
Type - Casework Parameters - Casework | Type: Tall
Type - Casework - Parametric | File Type: BXF; Parametric | File Name: 01-TallUK; Dimension | Width: 0.7 m; Dimension | Height: 2.5 m; Dimension | Depth: 0.25 m
Casework - Dimension | Width: 0.25 m
Name | In | Description
SHE_A-Cupboard_Electro | RL | 1,SHE_DRAWING+SHEET.dgn,Design Model;1 ,SHE-01.GROUND.dgn,Design Model:263240
SHE_A-Cupboard_Electro | RL | 1,SHE_DRAWING+SHEET.dgn,Design Model;4 ,SHE-03.FIRST.dgn,Design Model:135481
SHE_A-Cupboard_Electro | RL | 1,SHE_DRAWING+SHEET.dgn,Design Model;4 ,SHE-03.FIRST.dgn,Design Model:135495
SHE_A-Cupboard_Electro | 02 | 1,SHE_DRAWING+SHEET.dgn,Design Model;4 ,SHE-03.FIRST.dgn,Design Model:135502
SHE_A-Cupboard_Electro | RL | 1,SHE_DRAWING+SHEET.dgn,Design Model;4 ,SHE-03.FIRST.dgn,Design Model:135523
SHE_A-Cupboard_Electro | RL | 1,SHE_DRAWING+SHEET.dgn,Design Model;4 ,SHE-03.FIRST.dgn,Design Model:272307
SHE_A-Cupboard_Electro | RL | 1,SHE_DRAWING+SHEET.dgn,Design Model;4 ,SHE-03.FIRST.dgn,Design Model:288350
SHE_A-Cupboard_Electro | RL | 1,SHE_DRAWING+SHEET.dgn,Design Model;4 ,SHE-03.FIRST.dgn,Design Model:302316
SHE_A-Cupboard_Electro | RL | 1,SHE_DRAWING+SHEET.dgn,Design Model;6 ,SHE-05.THIRD.dgn,Design Model:135481
SHE_A-Cupboard_Electro | RL | 1,SHE_DRAWING+SHEET.dgn,Design Model;6 ,SHE-05.THIRD.dgn,Design Model:135495
SHE_A-Cupboard_Electro | 16 | 1,SHE_DRAWING+SHEET.dgn,Design Model;6 ,SHE-05.THIRD.dgn,Design Model:135502
SHE_A-Cupboard_Electro | RL | 1,SHE_DRAWING+SHEET.dgn,Design Model;6 ,SHE-05.THIRD.dgn,Design Model:135523
SHE_A-Cupboard_Electro | RL | 1,SHE_DRAWING+SHEET.dgn,Design Model;6 ,SHE-05.THIRD.dgn,Design Model:272307
SHE_A-Cupboard_Electro | RL | 1,SHE_DRAWING+SHEET.dgn,Design Model;6 ,SHE-05.THIRD.dgn,Design Model:288350
SHE_A-Cupboard_Electro | RL | 1,SHE_DRAWING+SHEET.dgn,Design Model;6 ,SHE-05.THIRD.dgn,Design Model:302316
SHE_A-Cupboard_Electro | RL | 1,SHE_DRAWING+SHEET.dgn,Design Model;7 ,SHE-06.FOURTH.dgn,Design Model:490931
SHE_A-Cupboard_Electro | RL | 1,SHE_DRAWING+SHEET.dgn,Design Model;7 ,SHE-06.FOURTH.dgn,Design Model:490940
SHE_A-Cupboard_Electro | RL | 1,SHE_DRAWING+SHEET.dgn,Design Model;7 ,SHE-06.FOURTH.dgn,Design Model:490947
SHE_A-Cupboard_Electro | RL | 1,SHE_DRAWING+SHEET.dgn,Design Model;7 ,SHE-06.FOURTH.dgn,Design Model:490954
SHE_A-Cupboard_Electro | RL | 1,SHE_DRAWING+SHEET.dgn,Design Model;18 ,SHE-04.SECOND.dgn,Design Model:135481
SHE_A-Cupboard_Electro | RL | 1,SHE_DRAWING+SHEET.dgn,Design Model;18 ,SHE-04.SECOND.dgn,Design Model:135495
SHE_A-Cupboard_Electro | 09 | 1,SHE_DRAWING+SHEET.dgn,Design Model;18 ,SHE-04.SECOND.dgn,Design Model:135502
SHE_A-Cupboard_Electro | RL | 1,SHE_DRAWING+SHEET.dgn,Design Model;18 ,SHE-04.SECOND.dgn,Design Model:135523
SHE_A-Cupboard_Electro | RL | 1,SHE_DRAWING+SHEET.dgn,Design Model;18 ,SHE-04.SECOND.dgn,Design Model:272307
SHE_A-Cupboard_Electro | RL | 1,SHE_DRAWING+SHEET.dgn,Design Model;18 ,SHE-04.SECOND.dgn,Design Model:288350
SHE_A-Cupboard_Electro | RL | 1,SHE_DRAWING+SHEET.dgn,Design Model;18 ,SHE-04.SECOND.dgn,Design Model:302316

# IfcFurnishingElement: SHE_A-Kitchenunit-Base (120)
In: RL
Type - Pset_FurnitureTypeCommon - NominalDepth: 0.6 m; NominalHeight: 0.86 m; NominalLength: 0.6 m
Type - Discipline - Discipline: Architectural
Type - Classification - Uniclass2015: Pr_40_30_78
Type - Casework Parameters - Casework | Type: Base
Type - Casework - Parametric | File Type: BXF; Parametric | File Name: 01-BaseUK; Dimension | Width: 0.6 m; Dimension | Height: 0.86 m; Dimension | Depth: 0.6 m
Material: A_BSUK_StorageScreening_Ffe
Name | Description
SHE_A-Kitchenunit-Base | 1,SHE_DRAWING+SHEET.dgn,Design Model;2 ,SHE-02.MEZZANINE.dgn,Design Model:120072
SHE_A-Kitchenunit-Base | 1,SHE_DRAWING+SHEET.dgn,Design Model;2 ,SHE-02.MEZZANINE.dgn,Design Model:120083
SHE_A-Kitchenunit-Base | 1,SHE_DRAWING+SHEET.dgn,Design Model;2 ,SHE-02.MEZZANINE.dgn,Design Model:120092
SHE_A-Kitchenunit-Base | 1,SHE_DRAWING+SHEET.dgn,Design Model;2 ,SHE-02.MEZZANINE.dgn,Design Model:120100
SHE_A-Kitchenunit-Base | 1,SHE_DRAWING+SHEET.dgn,Design Model;2 ,SHE-02.MEZZANINE.dgn,Design Model:120108
SHE_A-Kitchenunit-Base | 1,SHE_DRAWING+SHEET.dgn,Design Model;2 ,SHE-02.MEZZANINE.dgn,Design Model:147775
SHE_A-Kitchenunit-Base | 1,SHE_DRAWING+SHEET.dgn,Design Model;4 ,SHE-03.FIRST.dgn,Design Model:134902
SHE_A-Kitchenunit-Base | 1,SHE_DRAWING+SHEET.dgn,Design Model;4 ,SHE-03.FIRST.dgn,Design Model:134910
SHE_A-Kitchenunit-Base | 1,SHE_DRAWING+SHEET.dgn,Design Model;4 ,SHE-03.FIRST.dgn,Design Model:134918
SHE_A-Kitchenunit-Base | 1,SHE_DRAWING+SHEET.dgn,Design Model;4 ,SHE-03.FIRST.dgn,Design Model:134968
SHE_A-Kitchenunit-Base | 1,SHE_DRAWING+SHEET.dgn,Design Model;4 ,SHE-03.FIRST.dgn,Design Model:134976
SHE_A-Kitchenunit-Base | 1,SHE_DRAWING+SHEET.dgn,Design Model;4 ,SHE-03.FIRST.dgn,Design Model:134977
SHE_A-Kitchenunit-Base | 1,SHE_DRAWING+SHEET.dgn,Design Model;4 ,SHE-03.FIRST.dgn,Design Model:134978
SHE_A-Kitchenunit-Base | 1,SHE_DRAWING+SHEET.dgn,Design Model;4 ,SHE-03.FIRST.dgn,Design Model:134979
SHE_A-Kitchenunit-Base | 1,SHE_DRAWING+SHEET.dgn,Design Model;4 ,SHE-03.FIRST.dgn,Design Model:135001
SHE_A-Kitchenunit-Base | 1,SHE_DRAWING+SHEET.dgn,Design Model;4 ,SHE-03.FIRST.dgn,Design Model:135003
SHE_A-Kitchenunit-Base | 1,SHE_DRAWING+SHEET.dgn,Design Model;4 ,SHE-03.FIRST.dgn,Design Model:135011
SHE_A-Kitchenunit-Base | 1,SHE_DRAWING+SHEET.dgn,Design Model;4 ,SHE-03.FIRST.dgn,Design Model:135019
SHE_A-Kitchenunit-Base | 1,SHE_DRAWING+SHEET.dgn,Design Model;4 ,SHE-03.FIRST.dgn,Design Model:135027
SHE_A-Kitchenunit-Base | 1,SHE_DRAWING+SHEET.dgn,Design Model;4 ,SHE-03.FIRST.dgn,Design Model:135035
SHE_A-Kitchenunit-Base | 1,SHE_DRAWING+SHEET.dgn,Design Model;4 ,SHE-03.FIRST.dgn,Design Model:135088
SHE_A-Kitchenunit-Base | 1,SHE_DRAWING+SHEET.dgn,Design Model;4 ,SHE-03.FIRST.dgn,Design Model:135176
SHE_A-Kitchenunit-Base | 1,SHE_DRAWING+SHEET.dgn,Design Model;4 ,SHE-03.FIRST.dgn,Design Model:135226
SHE_A-Kitchenunit-Base | 1,SHE_DRAWING+SHEET.dgn,Design Model;4 ,SHE-03.FIRST.dgn,Design Model:135269
SHE_A-Kitchenunit-Base | 1,SHE_DRAWING+SHEET.dgn,Design Model;4 ,SHE-03.FIRST.dgn,Design Model:135326
SHE_A-Kitchenunit-Base | 1,SHE_DRAWING+SHEET.dgn,Design Model;4 ,SHE-03.FIRST.dgn,Design Model:135405
SHE_A-Kitchenunit-Base | 1,SHE_DRAWING+SHEET.dgn,Design Model;4 ,SHE-03.FIRST.dgn,Design Model:135455
SHE_A-Kitchenunit-Base | 1,SHE_DRAWING+SHEET.dgn,Design Model;4 ,SHE-03.FIRST.dgn,Design Model:135463
SHE_A-Kitchenunit-Base | 1,SHE_DRAWING+SHEET.dgn,Design Model;4 ,SHE-03.FIRST.dgn,Design Model:135471
SHE_A-Kitchenunit-Base | 1,SHE_DRAWING+SHEET.dgn,Design Model;4 ,SHE-03.FIRST.dgn,Design Model:135479
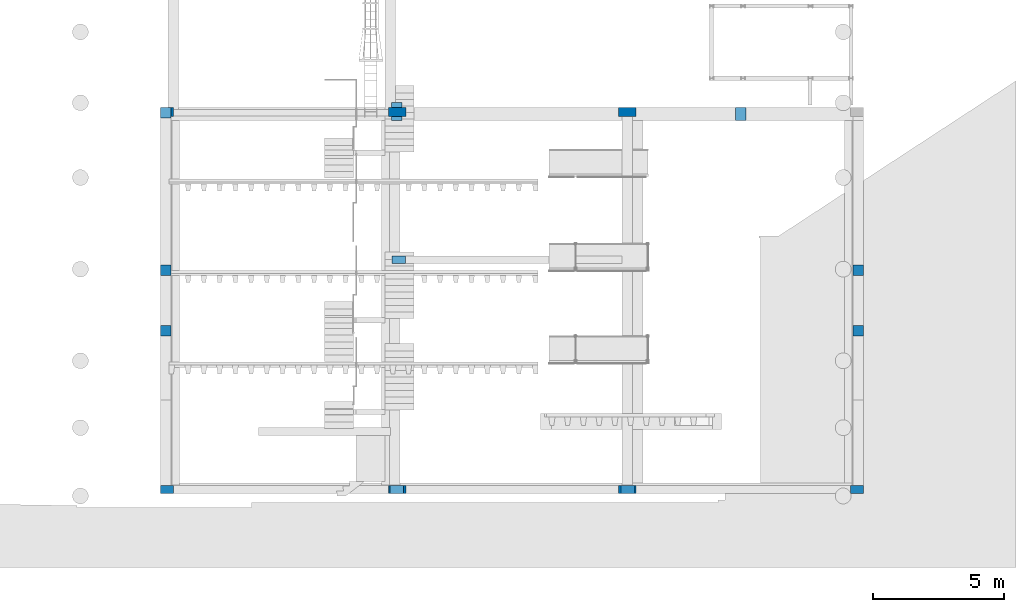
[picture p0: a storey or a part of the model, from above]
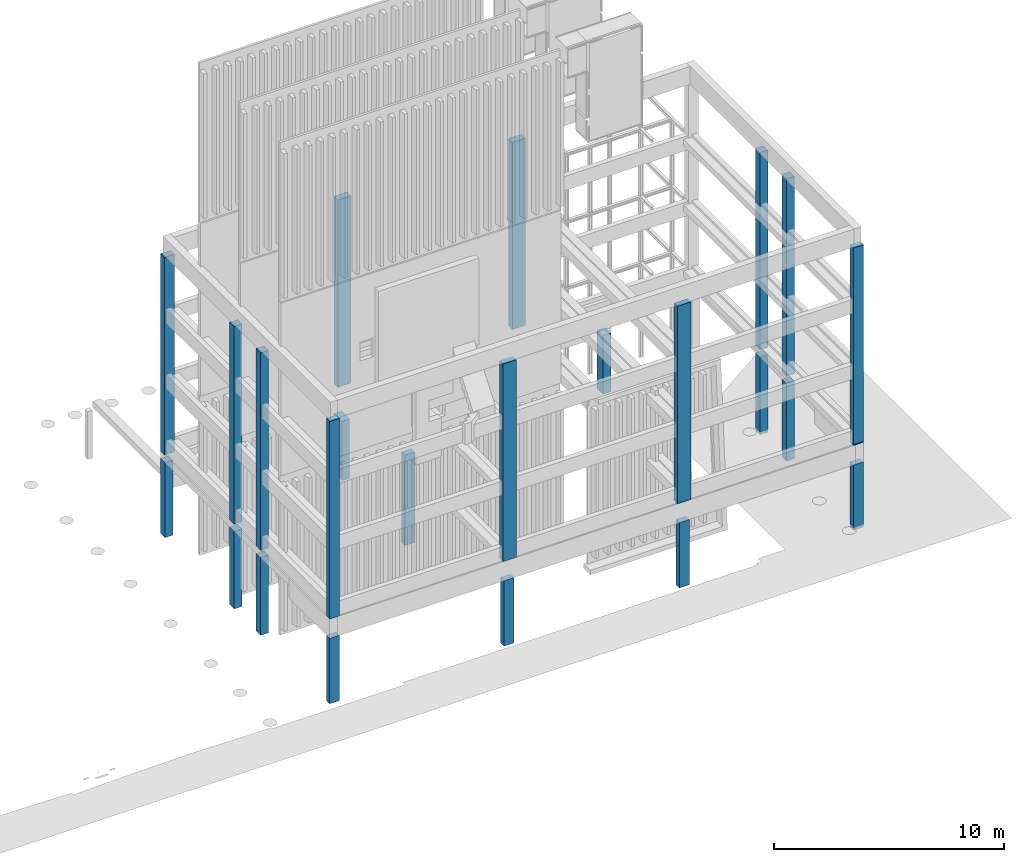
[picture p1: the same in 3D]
Properties of the parts of a building model (IFC2X3), part 6 of 16

# IfcFurnishingElement: SHE_A-Kitchenunit-Base (120)
Name | Description
SHE_A-Kitchenunit-Base | 1,SHE_DRAWING+SHEET.dgn,Design Model;4 ,SHE-03.FIRST.dgn,Design Model:186406
SHE_A-Kitchenunit-Base | 1,SHE_DRAWING+SHEET.dgn,Design Model;4 ,SHE-03.FIRST.dgn,Design Model:186431
SHE_A-Kitchenunit-Base | 1,SHE_DRAWING+SHEET.dgn,Design Model;4 ,SHE-03.FIRST.dgn,Design Model:254800 | Casework - Dimension | Width: 0.9 m
SHE_A-Kitchenunit-Base | 1,SHE_DRAWING+SHEET.dgn,Design Model;4 ,SHE-03.FIRST.dgn,Design Model:272203
SHE_A-Kitchenunit-Base | 1,SHE_DRAWING+SHEET.dgn,Design Model;4 ,SHE-03.FIRST.dgn,Design Model:272232
SHE_A-Kitchenunit-Base | 1,SHE_DRAWING+SHEET.dgn,Design Model;4 ,SHE-03.FIRST.dgn,Design Model:272292
SHE_A-Kitchenunit-Base | 1,SHE_DRAWING+SHEET.dgn,Design Model;6 ,SHE-05.THIRD.dgn,Design Model:134902
SHE_A-Kitchenunit-Base | 1,SHE_DRAWING+SHEET.dgn,Design Model;6 ,SHE-05.THIRD.dgn,Design Model:134910
SHE_A-Kitchenunit-Base | 1,SHE_DRAWING+SHEET.dgn,Design Model;6 ,SHE-05.THIRD.dgn,Design Model:134918
SHE_A-Kitchenunit-Base | 1,SHE_DRAWING+SHEET.dgn,Design Model;6 ,SHE-05.THIRD.dgn,Design Model:134968
SHE_A-Kitchenunit-Base | 1,SHE_DRAWING+SHEET.dgn,Design Model;6 ,SHE-05.THIRD.dgn,Design Model:134976
SHE_A-Kitchenunit-Base | 1,SHE_DRAWING+SHEET.dgn,Design Model;6 ,SHE-05.THIRD.dgn,Design Model:134977
SHE_A-Kitchenunit-Base | 1,SHE_DRAWING+SHEET.dgn,Design Model;6 ,SHE-05.THIRD.dgn,Design Model:134978
SHE_A-Kitchenunit-Base | 1,SHE_DRAWING+SHEET.dgn,Design Model;6 ,SHE-05.THIRD.dgn,Design Model:134979
SHE_A-Kitchenunit-Base | 1,SHE_DRAWING+SHEET.dgn,Design Model;6 ,SHE-05.THIRD.dgn,Design Model:135001
SHE_A-Kitchenunit-Base | 1,SHE_DRAWING+SHEET.dgn,Design Model;6 ,SHE-05.THIRD.dgn,Design Model:135003
SHE_A-Kitchenunit-Base | 1,SHE_DRAWING+SHEET.dgn,Design Model;6 ,SHE-05.THIRD.dgn,Design Model:135011
SHE_A-Kitchenunit-Base | 1,SHE_DRAWING+SHEET.dgn,Design Model;6 ,SHE-05.THIRD.dgn,Design Model:135019
SHE_A-Kitchenunit-Base | 1,SHE_DRAWING+SHEET.dgn,Design Model;6 ,SHE-05.THIRD.dgn,Design Model:135027
SHE_A-Kitchenunit-Base | 1,SHE_DRAWING+SHEET.dgn,Design Model;6 ,SHE-05.THIRD.dgn,Design Model:135035
SHE_A-Kitchenunit-Base | 1,SHE_DRAWING+SHEET.dgn,Design Model;6 ,SHE-05.THIRD.dgn,Design Model:135088
SHE_A-Kitchenunit-Base | 1,SHE_DRAWING+SHEET.dgn,Design Model;6 ,SHE-05.THIRD.dgn,Design Model:135176
SHE_A-Kitchenunit-Base | 1,SHE_DRAWING+SHEET.dgn,Design Model;6 ,SHE-05.THIRD.dgn,Design Model:135226
SHE_A-Kitchenunit-Base | 1,SHE_DRAWING+SHEET.dgn,Design Model;6 ,SHE-05.THIRD.dgn,Design Model:135269
SHE_A-Kitchenunit-Base | 1,SHE_DRAWING+SHEET.dgn,Design Model;6 ,SHE-05.THIRD.dgn,Design Model:135326
SHE_A-Kitchenunit-Base | 1,SHE_DRAWING+SHEET.dgn,Design Model;6 ,SHE-05.THIRD.dgn,Design Model:135405
SHE_A-Kitchenunit-Base | 1,SHE_DRAWING+SHEET.dgn,Design Model;6 ,SHE-05.THIRD.dgn,Design Model:135455
SHE_A-Kitchenunit-Base | 1,SHE_DRAWING+SHEET.dgn,Design Model;6 ,SHE-05.THIRD.dgn,Design Model:135463
SHE_A-Kitchenunit-Base | 1,SHE_DRAWING+SHEET.dgn,Design Model;6 ,SHE-05.THIRD.dgn,Design Model:135471
SHE_A-Kitchenunit-Base | 1,SHE_DRAWING+SHEET.dgn,Design Model;6 ,SHE-05.THIRD.dgn,Design Model:135479
SHE_A-Kitchenunit-Base | 1,SHE_DRAWING+SHEET.dgn,Design Model;6 ,SHE-05.THIRD.dgn,Design Model:186406
SHE_A-Kitchenunit-Base | 1,SHE_DRAWING+SHEET.dgn,Design Model;6 ,SHE-05.THIRD.dgn,Design Model:186431
SHE_A-Kitchenunit-Base | 1,SHE_DRAWING+SHEET.dgn,Design Model;6 ,SHE-05.THIRD.dgn,Design Model:254800 | Casework - Dimension | Width: 0.9 m
SHE_A-Kitchenunit-Base | 1,SHE_DRAWING+SHEET.dgn,Design Model;6 ,SHE-05.THIRD.dgn,Design Model:272203
SHE_A-Kitchenunit-Base | 1,SHE_DRAWING+SHEET.dgn,Design Model;6 ,SHE-05.THIRD.dgn,Design Model:272232
SHE_A-Kitchenunit-Base | 1,SHE_DRAWING+SHEET.dgn,Design Model;6 ,SHE-05.THIRD.dgn,Design Model:272292
SHE_A-Kitchenunit-Base | 1,SHE_DRAWING+SHEET.dgn,Design Model;8 ,SHE-07.FIFTH.dgn,Design Model:157111
SHE_A-Kitchenunit-Base | 1,SHE_DRAWING+SHEET.dgn,Design Model;8 ,SHE-07.FIFTH.dgn,Design Model:157192
SHE_A-Kitchenunit-Base | 1,SHE_DRAWING+SHEET.dgn,Design Model;8 ,SHE-07.FIFTH.dgn,Design Model:157200
SHE_A-Kitchenunit-Base | 1,SHE_DRAWING+SHEET.dgn,Design Model;8 ,SHE-07.FIFTH.dgn,Design Model:157208
SHE_A-Kitchenunit-Base | 1,SHE_DRAWING+SHEET.dgn,Design Model;8 ,SHE-07.FIFTH.dgn,Design Model:157232
SHE_A-Kitchenunit-Base | 1,SHE_DRAWING+SHEET.dgn,Design Model;8 ,SHE-07.FIFTH.dgn,Design Model:157255
SHE_A-Kitchenunit-Base | 1,SHE_DRAWING+SHEET.dgn,Design Model;8 ,SHE-07.FIFTH.dgn,Design Model:157278
SHE_A-Kitchenunit-Base | 1,SHE_DRAWING+SHEET.dgn,Design Model;8 ,SHE-07.FIFTH.dgn,Design Model:157287
SHE_A-Kitchenunit-Base | 1,SHE_DRAWING+SHEET.dgn,Design Model;8 ,SHE-07.FIFTH.dgn,Design Model:157295
SHE_A-Kitchenunit-Base | 1,SHE_DRAWING+SHEET.dgn,Design Model;8 ,SHE-07.FIFTH.dgn,Design Model:157303
SHE_A-Kitchenunit-Base | 1,SHE_DRAWING+SHEET.dgn,Design Model;8 ,SHE-07.FIFTH.dgn,Design Model:157311
SHE_A-Kitchenunit-Base | 1,SHE_DRAWING+SHEET.dgn,Design Model;8 ,SHE-07.FIFTH.dgn,Design Model:157335
SHE_A-Kitchenunit-Base | 1,SHE_DRAWING+SHEET.dgn,Design Model;8 ,SHE-07.FIFTH.dgn,Design Model:157358
SHE_A-Kitchenunit-Base | 1,SHE_DRAWING+SHEET.dgn,Design Model;8 ,SHE-07.FIFTH.dgn,Design Model:157381
SHE_A-Kitchenunit-Base | 1,SHE_DRAWING+SHEET.dgn,Design Model;8 ,SHE-07.FIFTH.dgn,Design Model:157426
SHE_A-Kitchenunit-Base | 1,SHE_DRAWING+SHEET.dgn,Design Model;8 ,SHE-07.FIFTH.dgn,Design Model:157470
SHE_A-Kitchenunit-Base | 1,SHE_DRAWING+SHEET.dgn,Design Model;8 ,SHE-07.FIFTH.dgn,Design Model:157523
SHE_A-Kitchenunit-Base | 1,SHE_DRAWING+SHEET.dgn,Design Model;8 ,SHE-07.FIFTH.dgn,Design Model:157546
SHE_A-Kitchenunit-Base | 1,SHE_DRAWING+SHEET.dgn,Design Model;8 ,SHE-07.FIFTH.dgn,Design Model:157569
SHE_A-Kitchenunit-Base | 1,SHE_DRAWING+SHEET.dgn,Design Model;8 ,SHE-07.FIFTH.dgn,Design Model:157637
SHE_A-Kitchenunit-Base | 1,SHE_DRAWING+SHEET.dgn,Design Model;8 ,SHE-07.FIFTH.dgn,Design Model:157645
SHE_A-Kitchenunit-Base | 1,SHE_DRAWING+SHEET.dgn,Design Model;8 ,SHE-07.FIFTH.dgn,Design Model:157653
SHE_A-Kitchenunit-Base | 1,SHE_DRAWING+SHEET.dgn,Design Model;8 ,SHE-07.FIFTH.dgn,Design Model:157661
SHE_A-Kitchenunit-Base | 1,SHE_DRAWING+SHEET.dgn,Design Model;8 ,SHE-07.FIFTH.dgn,Design Model:157669
SHE_A-Kitchenunit-Base | 1,SHE_DRAWING+SHEET.dgn,Design Model;18 ,SHE-04.SECOND.dgn,Design Model:134902
SHE_A-Kitchenunit-Base | 1,SHE_DRAWING+SHEET.dgn,Design Model;18 ,SHE-04.SECOND.dgn,Design Model:134910
SHE_A-Kitchenunit-Base | 1,SHE_DRAWING+SHEET.dgn,Design Model;18 ,SHE-04.SECOND.dgn,Design Model:134918
SHE_A-Kitchenunit-Base | 1,SHE_DRAWING+SHEET.dgn,Design Model;18 ,SHE-04.SECOND.dgn,Design Model:134968
SHE_A-Kitchenunit-Base | 1,SHE_DRAWING+SHEET.dgn,Design Model;18 ,SHE-04.SECOND.dgn,Design Model:134976
SHE_A-Kitchenunit-Base | 1,SHE_DRAWING+SHEET.dgn,Design Model;18 ,SHE-04.SECOND.dgn,Design Model:134977
SHE_A-Kitchenunit-Base | 1,SHE_DRAWING+SHEET.dgn,Design Model;18 ,SHE-04.SECOND.dgn,Design Model:134978
SHE_A-Kitchenunit-Base | 1,SHE_DRAWING+SHEET.dgn,Design Model;18 ,SHE-04.SECOND.dgn,Design Model:134979
SHE_A-Kitchenunit-Base | 1,SHE_DRAWING+SHEET.dgn,Design Model;18 ,SHE-04.SECOND.dgn,Design Model:135001
SHE_A-Kitchenunit-Base | 1,SHE_DRAWING+SHEET.dgn,Design Model;18 ,SHE-04.SECOND.dgn,Design Model:135003
SHE_A-Kitchenunit-Base | 1,SHE_DRAWING+SHEET.dgn,Design Model;18 ,SHE-04.SECOND.dgn,Design Model:135011
SHE_A-Kitchenunit-Base | 1,SHE_DRAWING+SHEET.dgn,Design Model;18 ,SHE-04.SECOND.dgn,Design Model:135019
SHE_A-Kitchenunit-Base | 1,SHE_DRAWING+SHEET.dgn,Design Model;18 ,SHE-04.SECOND.dgn,Design Model:135027
SHE_A-Kitchenunit-Base | 1,SHE_DRAWING+SHEET.dgn,Design Model;18 ,SHE-04.SECOND.dgn,Design Model:135035
SHE_A-Kitchenunit-Base | 1,SHE_DRAWING+SHEET.dgn,Design Model;18 ,SHE-04.SECOND.dgn,Design Model:135088
SHE_A-Kitchenunit-Base | 1,SHE_DRAWING+SHEET.dgn,Design Model;18 ,SHE-04.SECOND.dgn,Design Model:135176
SHE_A-Kitchenunit-Base | 1,SHE_DRAWING+SHEET.dgn,Design Model;18 ,SHE-04.SECOND.dgn,Design Model:135226
SHE_A-Kitchenunit-Base | 1,SHE_DRAWING+SHEET.dgn,Design Model;18 ,SHE-04.SECOND.dgn,Design Model:135269
SHE_A-Kitchenunit-Base | 1,SHE_DRAWING+SHEET.dgn,Design Model;18 ,SHE-04.SECOND.dgn,Design Model:135326
SHE_A-Kitchenunit-Base | 1,SHE_DRAWING+SHEET.dgn,Design Model;18 ,SHE-04.SECOND.dgn,Design Model:135405
SHE_A-Kitchenunit-Base | 1,SHE_DRAWING+SHEET.dgn,Design Model;18 ,SHE-04.SECOND.dgn,Design Model:135455
SHE_A-Kitchenunit-Base | 1,SHE_DRAWING+SHEET.dgn,Design Model;18 ,SHE-04.SECOND.dgn,Design Model:135463
SHE_A-Kitchenunit-Base | 1,SHE_DRAWING+SHEET.dgn,Design Model;18 ,SHE-04.SECOND.dgn,Design Model:135471
SHE_A-Kitchenunit-Base | 1,SHE_DRAWING+SHEET.dgn,Design Model;18 ,SHE-04.SECOND.dgn,Design Model:135479
SHE_A-Kitchenunit-Base | 1,SHE_DRAWING+SHEET.dgn,Design Model;18 ,SHE-04.SECOND.dgn,Design Model:186406
SHE_A-Kitchenunit-Base | 1,SHE_DRAWING+SHEET.dgn,Design Model;18 ,SHE-04.SECOND.dgn,Design Model:186431
SHE_A-Kitchenunit-Base | 1,SHE_DRAWING+SHEET.dgn,Design Model;18 ,SHE-04.SECOND.dgn,Design Model:254800 | Casework - Dimension | Width: 0.9 m
SHE_A-Kitchenunit-Base | 1,SHE_DRAWING+SHEET.dgn,Design Model;18 ,SHE-04.SECOND.dgn,Design Model:272203
SHE_A-Kitchenunit-Base | 1,SHE_DRAWING+SHEET.dgn,Design Model;18 ,SHE-04.SECOND.dgn,Design Model:272232
SHE_A-Kitchenunit-Base | 1,SHE_DRAWING+SHEET.dgn,Design Model;18 ,SHE-04.SECOND.dgn,Design Model:272292

# IfcFurnishingElement: SHE_A-Kitchenunit-Base 37x60 (9)
In: RL
Type - Pset_FurnitureTypeCommon - NominalDepth: 0.37 m; NominalHeight: 0.86 m; NominalLength: 0.6 m
Type - Discipline - Discipline: Architectural
Type - Classification - Uniclass2015: Pr_40_30_78
Type - Casework Parameters - Casework | Type: Base
Type - Casework - Parametric | File Type: BXF; Parametric | File Name: 01-BaseUK; Dimension | Width: 0.6 m; Dimension | Height: 0.86 m; Dimension | Depth: 0.37 m
Material: A_BSUK_StorageScreening_Ffe
Name | Description
SHE_A-Kitchenunit-Base 37x60 | 1,SHE_DRAWING+SHEET.dgn,Design Model;8 ,SHE-07.FIFTH.dgn,Design Model:157136
SHE_A-Kitchenunit-Base 37x60 | 1,SHE_DRAWING+SHEET.dgn,Design Model;8 ,SHE-07.FIFTH.dgn,Design Model:157233
SHE_A-Kitchenunit-Base 37x60 | 1,SHE_DRAWING+SHEET.dgn,Design Model;8 ,SHE-07.FIFTH.dgn,Design Model:157256
SHE_A-Kitchenunit-Base 37x60 | 1,SHE_DRAWING+SHEET.dgn,Design Model;8 ,SHE-07.FIFTH.dgn,Design Model:157313
SHE_A-Kitchenunit-Base 37x60 | 1,SHE_DRAWING+SHEET.dgn,Design Model;8 ,SHE-07.FIFTH.dgn,Design Model:157336
SHE_A-Kitchenunit-Base 37x60 | 1,SHE_DRAWING+SHEET.dgn,Design Model;8 ,SHE-07.FIFTH.dgn,Design Model:157359
SHE_A-Kitchenunit-Base 37x60 | 1,SHE_DRAWING+SHEET.dgn,Design Model;8 ,SHE-07.FIFTH.dgn,Design Model:157522
SHE_A-Kitchenunit-Base 37x60 | 1,SHE_DRAWING+SHEET.dgn,Design Model;8 ,SHE-07.FIFTH.dgn,Design Model:157545
SHE_A-Kitchenunit-Base 37x60 | 1,SHE_DRAWING+SHEET.dgn,Design Model;8 ,SHE-07.FIFTH.dgn,Design Model:157568

# IfcFurnishingElement: SHE_A-Kitchenunit-Base60x30
In: RL
Type - Pset_FurnitureTypeCommon - NominalDepth: 0.6 m; NominalHeight: 0.86 m; NominalLength: 0.3 m
Type - Discipline - Discipline: Architectural
Type - Classification - Uniclass2015: Pr_40_30_78
Type - Casework Parameters - Casework | Type: Base
Type - Casework - Parametric | File Type: BXF; Parametric | File Name: 01-BaseUK; Dimension | Width: 0.3 m; Dimension | Height: 0.86 m; Dimension | Depth: 0.6 m
Description: 1,SHE_DRAWING+SHEET.dgn,Design Model;8 ,SHE-07.FIFTH.dgn,Design Model:158601; Material: A_BSUK_StorageScreening_Ffe

# IfcFurnishingElement: SHE_A-Kitchenunit-Base60x45 (10)
In: RL
Type - Pset_FurnitureTypeCommon - NominalDepth: 0.6 m; NominalHeight: 0.86 m; NominalLength: 0.45 m
Type - Discipline - Discipline: Architectural
Type - Classification - Uniclass2015: Pr_40_30_78
Type - Casework Parameters - Casework | Type: Base
Type - Casework - Parametric | File Type: BXF; Parametric | File Name: 01-BaseUK; Dimension | Width: 0.45 m; Dimension | Height: 0.86 m; Dimension | Depth: 0.6 m
Material: A_BSUK_StorageScreening_Ffe
Name | Description
SHE_A-Kitchenunit-Base60x45 | 1,SHE_DRAWING+SHEET.dgn,Design Model;4 ,SHE-03.FIRST.dgn,Design Model:135593
SHE_A-Kitchenunit-Base60x45 | 1,SHE_DRAWING+SHEET.dgn,Design Model;4 ,SHE-03.FIRST.dgn,Design Model:135643
SHE_A-Kitchenunit-Base60x45 | 1,SHE_DRAWING+SHEET.dgn,Design Model;4 ,SHE-03.FIRST.dgn,Design Model:135651
SHE_A-Kitchenunit-Base60x45 | 1,SHE_DRAWING+SHEET.dgn,Design Model;6 ,SHE-05.THIRD.dgn,Design Model:135593
SHE_A-Kitchenunit-Base60x45 | 1,SHE_DRAWING+SHEET.dgn,Design Model;6 ,SHE-05.THIRD.dgn,Design Model:135643
SHE_A-Kitchenunit-Base60x45 | 1,SHE_DRAWING+SHEET.dgn,Design Model;6 ,SHE-05.THIRD.dgn,Design Model:135651
SHE_A-Kitchenunit-Base60x45 | 1,SHE_DRAWING+SHEET.dgn,Design Model;8 ,SHE-07.FIFTH.dgn,Design Model:158593
SHE_A-Kitchenunit-Base60x45 | 1,SHE_DRAWING+SHEET.dgn,Design Model;18 ,SHE-04.SECOND.dgn,Design Model:135593
SHE_A-Kitchenunit-Base60x45 | 1,SHE_DRAWING+SHEET.dgn,Design Model;18 ,SHE-04.SECOND.dgn,Design Model:135643
SHE_A-Kitchenunit-Base60x45 | 1,SHE_DRAWING+SHEET.dgn,Design Model;18 ,SHE-04.SECOND.dgn,Design Model:135651

# IfcFurnishingElement: SHE_A-Kitchenunit-Base60x75
In: RL
Type - Pset_FurnitureTypeCommon - NominalDepth: 0.6 m; NominalHeight: 0.86 m; NominalLength: 0.75 m
Type - Discipline - Discipline: Architectural
Type - Classification - Uniclass2015: Pr_40_30_78
Type - Casework Parameters - Casework | Type: Base
Type - Casework - Parametric | File Type: BXF; Parametric | File Name: 01-BaseUK; Dimension | Width: 0.75 m; Dimension | Height: 0.86 m; Dimension | Depth: 0.6 m
Description: 1,SHE_DRAWING+SHEET.dgn,Design Model;8 ,SHE-07.FIFTH.dgn,Design Model:158585; Material: A_BSUK_StorageScreening_Ffe

# IfcFurnishingElement: SHE_A-Kitchenunit-Base60x90
In: RL
Type - Pset_FurnitureTypeCommon - NominalDepth: 0.6 m; NominalHeight: 0.86 m; NominalLength: 0.9 m
Type - Discipline - Discipline: Architectural
Type - Classification - Uniclass2015: Pr_40_30_78
Type - Casework Parameters - Casework | Type: Base
Type - Casework - Parametric | File Type: BXF; Parametric | File Name: 01-BaseUK; Dimension | Width: 0.9 m; Dimension | Height: 0.86 m; Dimension | Depth: 0.6 m
Description: 1,SHE_DRAWING+SHEET.dgn,Design Model;2 ,SHE-02.MEZZANINE.dgn,Design Model:120963; Material: A_BSUK_StorageScreening_Ffe

# IfcFurnishingElement: SHE_A-Kitchenunit-Tall (35)
In: RL
Type - Pset_FurnitureTypeCommon - NominalDepth: 0.6 m; NominalHeight: 2.26 m; NominalLength: 0.6 m
Type - Discipline - Discipline: Architectural
Type - Classification - Uniclass2015: Pr_40_30_78
Type - Casework Parameters - Casework | Type: Tall
Type - Casework - Parametric | File Type: BXF; Parametric | File Name: 01-TallUK; Dimension | Width: 0.6 m; Dimension | Height: 2.26 m; Dimension | Depth: 0.6 m
Material: A_BSUK_StorageScreening_Ffe
Name | Description
SHE_A-Kitchenunit-Tall | 1,SHE_DRAWING+SHEET.dgn,Design Model;2 ,SHE-02.MEZZANINE.dgn,Design Model:120048
SHE_A-Kitchenunit-Tall | 1,SHE_DRAWING+SHEET.dgn,Design Model;2 ,SHE-02.MEZZANINE.dgn,Design Model:120091
SHE_A-Kitchenunit-Tall | 1,SHE_DRAWING+SHEET.dgn,Design Model;4 ,SHE-03.FIRST.dgn,Design Model:134878
SHE_A-Kitchenunit-Tall | 1,SHE_DRAWING+SHEET.dgn,Design Model;4 ,SHE-03.FIRST.dgn,Design Model:134967
SHE_A-Kitchenunit-Tall | 1,SHE_DRAWING+SHEET.dgn,Design Model;4 ,SHE-03.FIRST.dgn,Design Model:135002
SHE_A-Kitchenunit-Tall | 1,SHE_DRAWING+SHEET.dgn,Design Model;4 ,SHE-03.FIRST.dgn,Design Model:135043
SHE_A-Kitchenunit-Tall | 1,SHE_DRAWING+SHEET.dgn,Design Model;4 ,SHE-03.FIRST.dgn,Design Model:135126
SHE_A-Kitchenunit-Tall | 1,SHE_DRAWING+SHEET.dgn,Design Model;4 ,SHE-03.FIRST.dgn,Design Model:135355
SHE_A-Kitchenunit-Tall | 1,SHE_DRAWING+SHEET.dgn,Design Model;4 ,SHE-03.FIRST.dgn,Design Model:135480
SHE_A-Kitchenunit-Tall | 1,SHE_DRAWING+SHEET.dgn,Design Model;4 ,SHE-03.FIRST.dgn,Design Model:186405
SHE_A-Kitchenunit-Tall | 1,SHE_DRAWING+SHEET.dgn,Design Model;6 ,SHE-05.THIRD.dgn,Design Model:134878
SHE_A-Kitchenunit-Tall | 1,SHE_DRAWING+SHEET.dgn,Design Model;6 ,SHE-05.THIRD.dgn,Design Model:134967
SHE_A-Kitchenunit-Tall | 1,SHE_DRAWING+SHEET.dgn,Design Model;6 ,SHE-05.THIRD.dgn,Design Model:135002
SHE_A-Kitchenunit-Tall | 1,SHE_DRAWING+SHEET.dgn,Design Model;6 ,SHE-05.THIRD.dgn,Design Model:135043
SHE_A-Kitchenunit-Tall | 1,SHE_DRAWING+SHEET.dgn,Design Model;6 ,SHE-05.THIRD.dgn,Design Model:135126
SHE_A-Kitchenunit-Tall | 1,SHE_DRAWING+SHEET.dgn,Design Model;6 ,SHE-05.THIRD.dgn,Design Model:135355
SHE_A-Kitchenunit-Tall | 1,SHE_DRAWING+SHEET.dgn,Design Model;6 ,SHE-05.THIRD.dgn,Design Model:135480
SHE_A-Kitchenunit-Tall | 1,SHE_DRAWING+SHEET.dgn,Design Model;6 ,SHE-05.THIRD.dgn,Design Model:186405
SHE_A-Kitchenunit-Tall | 1,SHE_DRAWING+SHEET.dgn,Design Model;8 ,SHE-07.FIFTH.dgn,Design Model:157080
SHE_A-Kitchenunit-Tall | 1,SHE_DRAWING+SHEET.dgn,Design Model;8 ,SHE-07.FIFTH.dgn,Design Model:157209
SHE_A-Kitchenunit-Tall | 1,SHE_DRAWING+SHEET.dgn,Design Model;8 ,SHE-07.FIFTH.dgn,Design Model:157279
SHE_A-Kitchenunit-Tall | 1,SHE_DRAWING+SHEET.dgn,Design Model;8 ,SHE-07.FIFTH.dgn,Design Model:157312
SHE_A-Kitchenunit-Tall | 1,SHE_DRAWING+SHEET.dgn,Design Model;8 ,SHE-07.FIFTH.dgn,Design Model:157441
SHE_A-Kitchenunit-Tall | 1,SHE_DRAWING+SHEET.dgn,Design Model;8 ,SHE-07.FIFTH.dgn,Design Model:157584
SHE_A-Kitchenunit-Tall | 1,SHE_DRAWING+SHEET.dgn,Design Model;8 ,SHE-07.FIFTH.dgn,Design Model:157599
SHE_A-Kitchenunit-Tall | 1,SHE_DRAWING+SHEET.dgn,Design Model;8 ,SHE-07.FIFTH.dgn,Design Model:157614
SHE_A-Kitchenunit-Tall | 1,SHE_DRAWING+SHEET.dgn,Design Model;8 ,SHE-07.FIFTH.dgn,Design Model:157629
SHE_A-Kitchenunit-Tall | 1,SHE_DRAWING+SHEET.dgn,Design Model;18 ,SHE-04.SECOND.dgn,Design Model:134878
SHE_A-Kitchenunit-Tall | 1,SHE_DRAWING+SHEET.dgn,Design Model;18 ,SHE-04.SECOND.dgn,Design Model:134967
SHE_A-Kitchenunit-Tall | 1,SHE_DRAWING+SHEET.dgn,Design Model;18 ,SHE-04.SECOND.dgn,Design Model:135002
SHE_A-Kitchenunit-Tall | 1,SHE_DRAWING+SHEET.dgn,Design Model;18 ,SHE-04.SECOND.dgn,Design Model:135043
SHE_A-Kitchenunit-Tall | 1,SHE_DRAWING+SHEET.dgn,Design Model;18 ,SHE-04.SECOND.dgn,Design Model:135126
SHE_A-Kitchenunit-Tall | 1,SHE_DRAWING+SHEET.dgn,Design Model;18 ,SHE-04.SECOND.dgn,Design Model:135355
SHE_A-Kitchenunit-Tall | 1,SHE_DRAWING+SHEET.dgn,Design Model;18 ,SHE-04.SECOND.dgn,Design Model:135480
SHE_A-Kitchenunit-Tall | 1,SHE_DRAWING+SHEET.dgn,Design Model;18 ,SHE-04.SECOND.dgn,Design Model:186405

# IfcFurnishingElement: SHE_A-Kitchenunit-Wall (101)
In: RL
Type - Pset_FurnitureTypeCommon - NominalDepth: 0.37 m; NominalHeight: 0.76 m; NominalLength: 0.6 m
Type - Discipline - Discipline: Architectural
Type - Classification - Uniclass2015: Pr_40_30_78
Type - Casework Parameters - Casework | Type: Wall
Type - Casework - Parametric | File Type: BXF; Parametric | File Name: 01-WallUK; Dimension | Width: 0.6 m; Dimension | Height: 0.76 m; Dimension | Depth: 0.37 m
Casework - Dimension | Width: 0.37 m; Dimension | Depth: 0.6 m
Name | Description
SHE_A-Kitchenunit-Wall | 1,SHE_DRAWING+SHEET.dgn,Design Model;2 ,SHE-02.MEZZANINE.dgn,Design Model:120073
SHE_A-Kitchenunit-Wall | 1,SHE_DRAWING+SHEET.dgn,Design Model;2 ,SHE-02.MEZZANINE.dgn,Design Model:120084
SHE_A-Kitchenunit-Wall | 1,SHE_DRAWING+SHEET.dgn,Design Model;4 ,SHE-03.FIRST.dgn,Design Model:134903
SHE_A-Kitchenunit-Wall | 1,SHE_DRAWING+SHEET.dgn,Design Model;4 ,SHE-03.FIRST.dgn,Design Model:134911
SHE_A-Kitchenunit-Wall | 1,SHE_DRAWING+SHEET.dgn,Design Model;4 ,SHE-03.FIRST.dgn,Design Model:134919
SHE_A-Kitchenunit-Wall | 1,SHE_DRAWING+SHEET.dgn,Design Model;4 ,SHE-03.FIRST.dgn,Design Model:134969
SHE_A-Kitchenunit-Wall | 1,SHE_DRAWING+SHEET.dgn,Design Model;4 ,SHE-03.FIRST.dgn,Design Model:134980
SHE_A-Kitchenunit-Wall | 1,SHE_DRAWING+SHEET.dgn,Design Model;4 ,SHE-03.FIRST.dgn,Design Model:134987
SHE_A-Kitchenunit-Wall | 1,SHE_DRAWING+SHEET.dgn,Design Model;4 ,SHE-03.FIRST.dgn,Design Model:134994
SHE_A-Kitchenunit-Wall | 1,SHE_DRAWING+SHEET.dgn,Design Model;4 ,SHE-03.FIRST.dgn,Design Model:135004
SHE_A-Kitchenunit-Wall | 1,SHE_DRAWING+SHEET.dgn,Design Model;4 ,SHE-03.FIRST.dgn,Design Model:135012
SHE_A-Kitchenunit-Wall | 1,SHE_DRAWING+SHEET.dgn,Design Model;4 ,SHE-03.FIRST.dgn,Design Model:135020
SHE_A-Kitchenunit-Wall | 1,SHE_DRAWING+SHEET.dgn,Design Model;4 ,SHE-03.FIRST.dgn,Design Model:135028
SHE_A-Kitchenunit-Wall | 1,SHE_DRAWING+SHEET.dgn,Design Model;4 ,SHE-03.FIRST.dgn,Design Model:135036
SHE_A-Kitchenunit-Wall | 1,SHE_DRAWING+SHEET.dgn,Design Model;4 ,SHE-03.FIRST.dgn,Design Model:135089
SHE_A-Kitchenunit-Wall | 1,SHE_DRAWING+SHEET.dgn,Design Model;4 ,SHE-03.FIRST.dgn,Design Model:135127
SHE_A-Kitchenunit-Wall | 1,SHE_DRAWING+SHEET.dgn,Design Model;4 ,SHE-03.FIRST.dgn,Design Model:135177
SHE_A-Kitchenunit-Wall | 1,SHE_DRAWING+SHEET.dgn,Design Model;4 ,SHE-03.FIRST.dgn,Design Model:135270
SHE_A-Kitchenunit-Wall | 1,SHE_DRAWING+SHEET.dgn,Design Model;4 ,SHE-03.FIRST.dgn,Design Model:135277
SHE_A-Kitchenunit-Wall | 1,SHE_DRAWING+SHEET.dgn,Design Model;4 ,SHE-03.FIRST.dgn,Design Model:135356
SHE_A-Kitchenunit-Wall | 1,SHE_DRAWING+SHEET.dgn,Design Model;4 ,SHE-03.FIRST.dgn,Design Model:135406
SHE_A-Kitchenunit-Wall | 1,SHE_DRAWING+SHEET.dgn,Design Model;4 ,SHE-03.FIRST.dgn,Design Model:135456
SHE_A-Kitchenunit-Wall | 1,SHE_DRAWING+SHEET.dgn,Design Model;4 ,SHE-03.FIRST.dgn,Design Model:135464
SHE_A-Kitchenunit-Wall | 1,SHE_DRAWING+SHEET.dgn,Design Model;4 ,SHE-03.FIRST.dgn,Design Model:135472
SHE_A-Kitchenunit-Wall | 1,SHE_DRAWING+SHEET.dgn,Design Model;4 ,SHE-03.FIRST.dgn,Design Model:186432
SHE_A-Kitchenunit-Wall | 1,SHE_DRAWING+SHEET.dgn,Design Model;4 ,SHE-03.FIRST.dgn,Design Model:255109
SHE_A-Kitchenunit-Wall | 1,SHE_DRAWING+SHEET.dgn,Design Model;4 ,SHE-03.FIRST.dgn,Design Model:255116
SHE_A-Kitchenunit-Wall | 1,SHE_DRAWING+SHEET.dgn,Design Model;4 ,SHE-03.FIRST.dgn,Design Model:272204
SHE_A-Kitchenunit-Wall | 1,SHE_DRAWING+SHEET.dgn,Design Model;4 ,SHE-03.FIRST.dgn,Design Model:272233
SHE_A-Kitchenunit-Wall | 1,SHE_DRAWING+SHEET.dgn,Design Model;4 ,SHE-03.FIRST.dgn,Design Model:272300
SHE_A-Kitchenunit-Wall | 1,SHE_DRAWING+SHEET.dgn,Design Model;6 ,SHE-05.THIRD.dgn,Design Model:134903
SHE_A-Kitchenunit-Wall | 1,SHE_DRAWING+SHEET.dgn,Design Model;6 ,SHE-05.THIRD.dgn,Design Model:134911
SHE_A-Kitchenunit-Wall | 1,SHE_DRAWING+SHEET.dgn,Design Model;6 ,SHE-05.THIRD.dgn,Design Model:134919
SHE_A-Kitchenunit-Wall | 1,SHE_DRAWING+SHEET.dgn,Design Model;6 ,SHE-05.THIRD.dgn,Design Model:134969
SHE_A-Kitchenunit-Wall | 1,SHE_DRAWING+SHEET.dgn,Design Model;6 ,SHE-05.THIRD.dgn,Design Model:134980
SHE_A-Kitchenunit-Wall | 1,SHE_DRAWING+SHEET.dgn,Design Model;6 ,SHE-05.THIRD.dgn,Design Model:134987
SHE_A-Kitchenunit-Wall | 1,SHE_DRAWING+SHEET.dgn,Design Model;6 ,SHE-05.THIRD.dgn,Design Model:134994
SHE_A-Kitchenunit-Wall | 1,SHE_DRAWING+SHEET.dgn,Design Model;6 ,SHE-05.THIRD.dgn,Design Model:135004
SHE_A-Kitchenunit-Wall | 1,SHE_DRAWING+SHEET.dgn,Design Model;6 ,SHE-05.THIRD.dgn,Design Model:135012
SHE_A-Kitchenunit-Wall | 1,SHE_DRAWING+SHEET.dgn,Design Model;6 ,SHE-05.THIRD.dgn,Design Model:135020
SHE_A-Kitchenunit-Wall | 1,SHE_DRAWING+SHEET.dgn,Design Model;6 ,SHE-05.THIRD.dgn,Design Model:135028
SHE_A-Kitchenunit-Wall | 1,SHE_DRAWING+SHEET.dgn,Design Model;6 ,SHE-05.THIRD.dgn,Design Model:135036
SHE_A-Kitchenunit-Wall | 1,SHE_DRAWING+SHEET.dgn,Design Model;6 ,SHE-05.THIRD.dgn,Design Model:135089
SHE_A-Kitchenunit-Wall | 1,SHE_DRAWING+SHEET.dgn,Design Model;6 ,SHE-05.THIRD.dgn,Design Model:135127
SHE_A-Kitchenunit-Wall | 1,SHE_DRAWING+SHEET.dgn,Design Model;6 ,SHE-05.THIRD.dgn,Design Model:135177
SHE_A-Kitchenunit-Wall | 1,SHE_DRAWING+SHEET.dgn,Design Model;6 ,SHE-05.THIRD.dgn,Design Model:135270
SHE_A-Kitchenunit-Wall | 1,SHE_DRAWING+SHEET.dgn,Design Model;6 ,SHE-05.THIRD.dgn,Design Model:135277
SHE_A-Kitchenunit-Wall | 1,SHE_DRAWING+SHEET.dgn,Design Model;6 ,SHE-05.THIRD.dgn,Design Model:135356
SHE_A-Kitchenunit-Wall | 1,SHE_DRAWING+SHEET.dgn,Design Model;6 ,SHE-05.THIRD.dgn,Design Model:135406
SHE_A-Kitchenunit-Wall | 1,SHE_DRAWING+SHEET.dgn,Design Model;6 ,SHE-05.THIRD.dgn,Design Model:135456
SHE_A-Kitchenunit-Wall | 1,SHE_DRAWING+SHEET.dgn,Design Model;6 ,SHE-05.THIRD.dgn,Design Model:135464
SHE_A-Kitchenunit-Wall | 1,SHE_DRAWING+SHEET.dgn,Design Model;6 ,SHE-05.THIRD.dgn,Design Model:135472
SHE_A-Kitchenunit-Wall | 1,SHE_DRAWING+SHEET.dgn,Design Model;6 ,SHE-05.THIRD.dgn,Design Model:186432
SHE_A-Kitchenunit-Wall | 1,SHE_DRAWING+SHEET.dgn,Design Model;6 ,SHE-05.THIRD.dgn,Design Model:255109
SHE_A-Kitchenunit-Wall | 1,SHE_DRAWING+SHEET.dgn,Design Model;6 ,SHE-05.THIRD.dgn,Design Model:255116
SHE_A-Kitchenunit-Wall | 1,SHE_DRAWING+SHEET.dgn,Design Model;6 ,SHE-05.THIRD.dgn,Design Model:272204
SHE_A-Kitchenunit-Wall | 1,SHE_DRAWING+SHEET.dgn,Design Model;6 ,SHE-05.THIRD.dgn,Design Model:272233
SHE_A-Kitchenunit-Wall | 1,SHE_DRAWING+SHEET.dgn,Design Model;6 ,SHE-05.THIRD.dgn,Design Model:272300
SHE_A-Kitchenunit-Wall | 1,SHE_DRAWING+SHEET.dgn,Design Model;8 ,SHE-07.FIFTH.dgn,Design Model:157081
SHE_A-Kitchenunit-Wall | 1,SHE_DRAWING+SHEET.dgn,Design Model;8 ,SHE-07.FIFTH.dgn,Design Model:157185
SHE_A-Kitchenunit-Wall | 1,SHE_DRAWING+SHEET.dgn,Design Model;8 ,SHE-07.FIFTH.dgn,Design Model:157193
SHE_A-Kitchenunit-Wall | 1,SHE_DRAWING+SHEET.dgn,Design Model;8 ,SHE-07.FIFTH.dgn,Design Model:157201
SHE_A-Kitchenunit-Wall | 1,SHE_DRAWING+SHEET.dgn,Design Model;8 ,SHE-07.FIFTH.dgn,Design Model:157280
SHE_A-Kitchenunit-Wall | 1,SHE_DRAWING+SHEET.dgn,Design Model;8 ,SHE-07.FIFTH.dgn,Design Model:157288
SHE_A-Kitchenunit-Wall | 1,SHE_DRAWING+SHEET.dgn,Design Model;8 ,SHE-07.FIFTH.dgn,Design Model:157296
SHE_A-Kitchenunit-Wall | 1,SHE_DRAWING+SHEET.dgn,Design Model;8 ,SHE-07.FIFTH.dgn,Design Model:157304
SHE_A-Kitchenunit-Wall | 1,SHE_DRAWING+SHEET.dgn,Design Model;8 ,SHE-07.FIFTH.dgn,Design Model:157398
SHE_A-Kitchenunit-Wall | 1,SHE_DRAWING+SHEET.dgn,Design Model;8 ,SHE-07.FIFTH.dgn,Design Model:157442
SHE_A-Kitchenunit-Wall | 1,SHE_DRAWING+SHEET.dgn,Design Model;8 ,SHE-07.FIFTH.dgn,Design Model:157630
SHE_A-Kitchenunit-Wall | 1,SHE_DRAWING+SHEET.dgn,Design Model;8 ,SHE-07.FIFTH.dgn,Design Model:157638
SHE_A-Kitchenunit-Wall | 1,SHE_DRAWING+SHEET.dgn,Design Model;8 ,SHE-07.FIFTH.dgn,Design Model:157646
SHE_A-Kitchenunit-Wall | 1,SHE_DRAWING+SHEET.dgn,Design Model;8 ,SHE-07.FIFTH.dgn,Design Model:157654
SHE_A-Kitchenunit-Wall | 1,SHE_DRAWING+SHEET.dgn,Design Model;8 ,SHE-07.FIFTH.dgn,Design Model:157662
SHE_A-Kitchenunit-Wall | 1,SHE_DRAWING+SHEET.dgn,Design Model;18 ,SHE-04.SECOND.dgn,Design Model:134903
SHE_A-Kitchenunit-Wall | 1,SHE_DRAWING+SHEET.dgn,Design Model;18 ,SHE-04.SECOND.dgn,Design Model:134911
SHE_A-Kitchenunit-Wall | 1,SHE_DRAWING+SHEET.dgn,Design Model;18 ,SHE-04.SECOND.dgn,Design Model:134919
SHE_A-Kitchenunit-Wall | 1,SHE_DRAWING+SHEET.dgn,Design Model;18 ,SHE-04.SECOND.dgn,Design Model:134969
SHE_A-Kitchenunit-Wall | 1,SHE_DRAWING+SHEET.dgn,Design Model;18 ,SHE-04.SECOND.dgn,Design Model:134980
SHE_A-Kitchenunit-Wall | 1,SHE_DRAWING+SHEET.dgn,Design Model;18 ,SHE-04.SECOND.dgn,Design Model:134987
SHE_A-Kitchenunit-Wall | 1,SHE_DRAWING+SHEET.dgn,Design Model;18 ,SHE-04.SECOND.dgn,Design Model:134994
SHE_A-Kitchenunit-Wall | 1,SHE_DRAWING+SHEET.dgn,Design Model;18 ,SHE-04.SECOND.dgn,Design Model:135004
SHE_A-Kitchenunit-Wall | 1,SHE_DRAWING+SHEET.dgn,Design Model;18 ,SHE-04.SECOND.dgn,Design Model:135012
SHE_A-Kitchenunit-Wall | 1,SHE_DRAWING+SHEET.dgn,Design Model;18 ,SHE-04.SECOND.dgn,Design Model:135020
SHE_A-Kitchenunit-Wall | 1,SHE_DRAWING+SHEET.dgn,Design Model;18 ,SHE-04.SECOND.dgn,Design Model:135028
SHE_A-Kitchenunit-Wall | 1,SHE_DRAWING+SHEET.dgn,Design Model;18 ,SHE-04.SECOND.dgn,Design Model:135036
SHE_A-Kitchenunit-Wall | 1,SHE_DRAWING+SHEET.dgn,Design Model;18 ,SHE-04.SECOND.dgn,Design Model:135089
SHE_A-Kitchenunit-Wall | 1,SHE_DRAWING+SHEET.dgn,Design Model;18 ,SHE-04.SECOND.dgn,Design Model:135127
SHE_A-Kitchenunit-Wall | 1,SHE_DRAWING+SHEET.dgn,Design Model;18 ,SHE-04.SECOND.dgn,Design Model:135177
SHE_A-Kitchenunit-Wall | 1,SHE_DRAWING+SHEET.dgn,Design Model;18 ,SHE-04.SECOND.dgn,Design Model:135270
SHE_A-Kitchenunit-Wall | 1,SHE_DRAWING+SHEET.dgn,Design Model;18 ,SHE-04.SECOND.dgn,Design Model:135277
SHE_A-Kitchenunit-Wall | 1,SHE_DRAWING+SHEET.dgn,Design Model;18 ,SHE-04.SECOND.dgn,Design Model:135356
SHE_A-Kitchenunit-Wall | 1,SHE_DRAWING+SHEET.dgn,Design Model;18 ,SHE-04.SECOND.dgn,Design Model:135406
SHE_A-Kitchenunit-Wall | 1,SHE_DRAWING+SHEET.dgn,Design Model;18 ,SHE-04.SECOND.dgn,Design Model:135456
SHE_A-Kitchenunit-Wall | 1,SHE_DRAWING+SHEET.dgn,Design Model;18 ,SHE-04.SECOND.dgn,Design Model:135464
SHE_A-Kitchenunit-Wall | 1,SHE_DRAWING+SHEET.dgn,Design Model;18 ,SHE-04.SECOND.dgn,Design Model:135472
SHE_A-Kitchenunit-Wall | 1,SHE_DRAWING+SHEET.dgn,Design Model;18 ,SHE-04.SECOND.dgn,Design Model:186432
SHE_A-Kitchenunit-Wall | 1,SHE_DRAWING+SHEET.dgn,Design Model;18 ,SHE-04.SECOND.dgn,Design Model:255109
SHE_A-Kitchenunit-Wall | 1,SHE_DRAWING+SHEET.dgn,Design Model;18 ,SHE-04.SECOND.dgn,Design Model:255116
SHE_A-Kitchenunit-Wall | 1,SHE_DRAWING+SHEET.dgn,Design Model;18 ,SHE-04.SECOND.dgn,Design Model:272204
SHE_A-Kitchenunit-Wall | 1,SHE_DRAWING+SHEET.dgn,Design Model;18 ,SHE-04.SECOND.dgn,Design Model:272233
SHE_A-Kitchenunit-Wall | 1,SHE_DRAWING+SHEET.dgn,Design Model;18 ,SHE-04.SECOND.dgn,Design Model:272300

# IfcFurnishingElement: SHE_A-Kitchenunit-Wall37x30 (2)
In: RL
Type - Pset_FurnitureTypeCommon - NominalDepth: 0.37 m; NominalHeight: 0.76 m; NominalLength: 0.3 m
Type - Discipline - Discipline: Architectural
Type - Classification - Uniclass2015: Pr_40_30_78
Type - Casework Parameters - Casework | Type: Wall
Type - Casework - Parametric | File Type: BXF; Parametric | File Name: 01-WallUK; Dimension | Width: 0.3 m; Dimension | Height: 0.76 m; Dimension | Depth: 0.37 m
Casework - Dimension | Width: 0.37 m
Name | Description
SHE_A-Kitchenunit-Wall37x30 | 1,SHE_DRAWING+SHEET.dgn,Design Model;8 ,SHE-07.FIFTH.dgn,Design Model:158602
SHE_A-Kitchenunit-Wall37x30 | 1,SHE_DRAWING+SHEET.dgn,Design Model;8 ,SHE-07.FIFTH.dgn,Design Model:158609

# IfcFurnishingElement: SHE_A-Kitchenunit-Wall37x45 (10)
In: RL
Type - Pset_FurnitureTypeCommon - NominalDepth: 0.37 m; NominalHeight: 0.76 m; NominalLength: 0.45 m
Type - Discipline - Discipline: Architectural
Type - Classification - Uniclass2015: Pr_40_30_78
Type - Casework Parameters - Casework | Type: Wall
Type - Casework - Parametric | File Type: BXF; Parametric | File Name: 01-WallUK; Dimension | Width: 0.45 m; Dimension | Height: 0.76 m; Dimension | Depth: 0.37 m
Casework - Dimension | Width: 0.37 m
Name | Description
SHE_A-Kitchenunit-Wall37x45 | 1,SHE_DRAWING+SHEET.dgn,Design Model;4 ,SHE-03.FIRST.dgn,Design Model:135594
SHE_A-Kitchenunit-Wall37x45 | 1,SHE_DRAWING+SHEET.dgn,Design Model;4 ,SHE-03.FIRST.dgn,Design Model:135644
SHE_A-Kitchenunit-Wall37x45 | 1,SHE_DRAWING+SHEET.dgn,Design Model;4 ,SHE-03.FIRST.dgn,Design Model:135652
SHE_A-Kitchenunit-Wall37x45 | 1,SHE_DRAWING+SHEET.dgn,Design Model;6 ,SHE-05.THIRD.dgn,Design Model:135594
SHE_A-Kitchenunit-Wall37x45 | 1,SHE_DRAWING+SHEET.dgn,Design Model;6 ,SHE-05.THIRD.dgn,Design Model:135644
SHE_A-Kitchenunit-Wall37x45 | 1,SHE_DRAWING+SHEET.dgn,Design Model;6 ,SHE-05.THIRD.dgn,Design Model:135652
SHE_A-Kitchenunit-Wall37x45 | 1,SHE_DRAWING+SHEET.dgn,Design Model;8 ,SHE-07.FIFTH.dgn,Design Model:158594
SHE_A-Kitchenunit-Wall37x45 | 1,SHE_DRAWING+SHEET.dgn,Design Model;18 ,SHE-04.SECOND.dgn,Design Model:135594
SHE_A-Kitchenunit-Wall37x45 | 1,SHE_DRAWING+SHEET.dgn,Design Model;18 ,SHE-04.SECOND.dgn,Design Model:135644
SHE_A-Kitchenunit-Wall37x45 | 1,SHE_DRAWING+SHEET.dgn,Design Model;18 ,SHE-04.SECOND.dgn,Design Model:135652

# IfcFurnishingElement: SHE_A-Kitchenunit-Wall37x75
In: RL
Type - Pset_FurnitureTypeCommon - NominalDepth: 0.37 m; NominalHeight: 0.76 m; NominalLength: 0.75 m
Type - Discipline - Discipline: Architectural
Type - Classification - Uniclass2015: Pr_40_30_78
Type - Casework Parameters - Casework | Type: Wall
Type - Casework - Parametric | File Type: BXF; Parametric | File Name: 01-WallUK; Dimension | Width: 0.75 m; Dimension | Height: 0.76 m; Dimension | Depth: 0.37 m
Description: 1,SHE_DRAWING+SHEET.dgn,Design Model;8 ,SHE-07.FIFTH.dgn,Design Model:158586
Casework - Dimension | Width: 0.37 m

# IfcFurnishingElement: SHE_A-Kitchenunit-Wall37x90 (2)
In: RL
Type - Pset_FurnitureTypeCommon - NominalDepth: 0.37 m; NominalHeight: 0.76 m; NominalLength: 0.9 m
Type - Discipline - Discipline: Architectural
Type - Classification - Uniclass2015: Pr_40_30_78
Type - Casework Parameters - Casework | Type: Wall
Type - Casework - Parametric | File Type: BXF; Parametric | File Name: 01-WallUK; Dimension | Width: 0.9 m; Dimension | Height: 0.76 m; Dimension | Depth: 0.37 m
Casework - Dimension | Width: 0.37 m
Name | Description
SHE_A-Kitchenunit-Wall37x90 | 1,SHE_DRAWING+SHEET.dgn,Design Model;2 ,SHE-02.MEZZANINE.dgn,Design Model:120964
SHE_A-Kitchenunit-Wall37x90 | 1,SHE_DRAWING+SHEET.dgn,Design Model;2 ,SHE-02.MEZZANINE.dgn,Design Model:147783

# IfcFurnishingElement: SHE_A-UtilityCupbord (36)
Type - Pset_FurnitureTypeCommon - NominalDepth: 0.05 m; NominalHeight: 2.5 m; NominalLength: 0.7 m
Type - Discipline - Discipline: Architectural
Type - Classification - Uniclass2015: Pr_40_30_78
Type - Casework Parameters - Casework | Type: Tall
Type - Casework - Parametric | File Type: BXF; Parametric | File Name: 01-TallUK; Dimension | Width: 0.7 m; Dimension | Height: 2.5 m; Dimension | Depth: 0.05 m
Name | In | Description | Dimension | Width (m)
SHE_A-UtilityCupbord | RL | 1,SHE_DRAWING+SHEET.dgn,Design Model;4,SHE-03.FIRST.dgn,Design Model:146573 | 1.5817
SHE_A-UtilityCupbord | RL | 1,SHE_DRAWING+SHEET.dgn,Design Model;4,SHE-03.FIRST.dgn,Design Model:146594 | 0.7725
SHE_A-UtilityCupbord | RL | 1,SHE_DRAWING+SHEET.dgn,Design Model;4,SHE-03.FIRST.dgn,Design Model:165590 | 0.85
SHE_A-UtilityCupbord | RL | 1,SHE_DRAWING+SHEET.dgn,Design Model;4,SHE-03.FIRST.dgn,Design Model:165597 | 0.85
SHE_A-UtilityCupbord | RL | 1,SHE_DRAWING+SHEET.dgn,Design Model;4,SHE-03.FIRST.dgn,Design Model:189947 | 0.6
SHE_A-UtilityCupbord | 02 | 1,SHE_DRAWING+SHEET.dgn,Design Model;4,SHE-03.FIRST.dgn,Design Model:243611 | 0.3525
SHE_A-UtilityCupbord | 02 | 1,SHE_DRAWING+SHEET.dgn,Design Model;4,SHE-03.FIRST.dgn,Design Model:243618 | 0.3525
SHE_A-UtilityCupbord | RL | 1,SHE_DRAWING+SHEET.dgn,Design Model;4,SHE-03.FIRST.dgn,Design Model:267279 | 1.402 | Material: A_BSUK_StorageScreening_Ffe
SHE_A-UtilityCupbord | RL | 1,SHE_DRAWING+SHEET.dgn,Design Model;4,SHE-03.FIRST.dgn,Design Model:272168 | 0.6
SHE_A-UtilityCupbord | RL | 1,SHE_DRAWING+SHEET.dgn,Design Model;4,SHE-03.FIRST.dgn,Design Model:272175 | 0.6
SHE_A-UtilityCupbord | RL | 1,SHE_DRAWING+SHEET.dgn,Design Model;4,SHE-03.FIRST.dgn,Design Model:302323 | 0.85
SHE_A-UtilityCupbord | RL | 1,SHE_DRAWING+SHEET.dgn,Design Model;4,SHE-03.FIRST.dgn,Design Model:302330 | 0.85
SHE_A-UtilityCupbord | RL | 1,SHE_DRAWING+SHEET.dgn,Design Model;6,SHE-05.THIRD.dgn,Design Model:146573 | 1.5817
SHE_A-UtilityCupbord | RL | 1,SHE_DRAWING+SHEET.dgn,Design Model;6,SHE-05.THIRD.dgn,Design Model:146594 | 0.7725
SHE_A-UtilityCupbord | RL | 1,SHE_DRAWING+SHEET.dgn,Design Model;6,SHE-05.THIRD.dgn,Design Model:165590 | 0.85
SHE_A-UtilityCupbord | RL | 1,SHE_DRAWING+SHEET.dgn,Design Model;6,SHE-05.THIRD.dgn,Design Model:165597 | 0.85
SHE_A-UtilityCupbord | RL | 1,SHE_DRAWING+SHEET.dgn,Design Model;6,SHE-05.THIRD.dgn,Design Model:189947 | 0.6
SHE_A-UtilityCupbord | 16 | 1,SHE_DRAWING+SHEET.dgn,Design Model;6,SHE-05.THIRD.dgn,Design Model:243611 | 0.3525
SHE_A-UtilityCupbord | 16 | 1,SHE_DRAWING+SHEET.dgn,Design Model;6,SHE-05.THIRD.dgn,Design Model:243618 | 0.3525
SHE_A-UtilityCupbord | RL | 1,SHE_DRAWING+SHEET.dgn,Design Model;6,SHE-05.THIRD.dgn,Design Model:267279 | 1.402 | Material: A_BSUK_StorageScreening_Ffe
SHE_A-UtilityCupbord | RL | 1,SHE_DRAWING+SHEET.dgn,Design Model;6,SHE-05.THIRD.dgn,Design Model:272168 | 0.6
SHE_A-UtilityCupbord | RL | 1,SHE_DRAWING+SHEET.dgn,Design Model;6,SHE-05.THIRD.dgn,Design Model:272175 | 0.6
SHE_A-UtilityCupbord | RL | 1,SHE_DRAWING+SHEET.dgn,Design Model;6,SHE-05.THIRD.dgn,Design Model:302323 | 0.85
SHE_A-UtilityCupbord | RL | 1,SHE_DRAWING+SHEET.dgn,Design Model;6,SHE-05.THIRD.dgn,Design Model:302330 | 0.85
SHE_A-UtilityCupbord | RL | 1,SHE_DRAWING+SHEET.dgn,Design Model;18,SHE-04.SECOND.dgn ,Design Model:146573 | 1.5817
SHE_A-UtilityCupbord | RL | 1,SHE_DRAWING+SHEET.dgn,Design Model;18,SHE-04.SECOND.dgn ,Design Model:146594 | 0.7725
SHE_A-UtilityCupbord | RL | 1,SHE_DRAWING+SHEET.dgn,Design Model;18,SHE-04.SECOND.dgn ,Design Model:165590 | 0.85
SHE_A-UtilityCupbord | RL | 1,SHE_DRAWING+SHEET.dgn,Design Model;18,SHE-04.SECOND.dgn ,Design Model:165597 | 0.85
SHE_A-UtilityCupbord | RL | 1,SHE_DRAWING+SHEET.dgn,Design Model;18,SHE-04.SECOND.dgn ,Design Model:189947 | 0.6
SHE_A-UtilityCupbord | 09 | 1,SHE_DRAWING+SHEET.dgn,Design Model;18,SHE-04.SECOND.dgn ,Design Model:243611 | 0.3525
SHE_A-UtilityCupbord | 09 | 1,SHE_DRAWING+SHEET.dgn,Design Model;18,SHE-04.SECOND.dgn ,Design Model:243618 | 0.3525
SHE_A-UtilityCupbord | RL | 1,SHE_DRAWING+SHEET.dgn,Design Model;18,SHE-04.SECOND.dgn ,Design Model:267279 | 1.402 | Material: A_BSUK_StorageScreening_Ffe
SHE_A-UtilityCupbord | RL | 1,SHE_DRAWING+SHEET.dgn,Design Model;18,SHE-04.SECOND.dgn ,Design Model:272168 | 0.6
SHE_A-UtilityCupbord | RL | 1,SHE_DRAWING+SHEET.dgn,Design Model;18,SHE-04.SECOND.dgn ,Design Model:272175 | 0.6
SHE_A-UtilityCupbord | RL | 1,SHE_DRAWING+SHEET.dgn,Design Model;18,SHE-04.SECOND.dgn ,Design Model:302323 | 0.85
SHE_A-UtilityCupbord | RL | 1,SHE_DRAWING+SHEET.dgn,Design Model;18,SHE-04.SECOND.dgn ,Design Model:302330 | 0.85

# IfcFurnishingElement: SHE_A-Wardrobe_hall 40x90 (15)
In: RL
Type - Pset_FurnitureTypeCommon - NominalDepth: 0.4 m; NominalHeight: 2.1 m; NominalLength: 0.9 m
Type - Discipline - Discipline: Architectural
Type - Classification - Uniclass2015: Pr_40_30_78
Type - Casework Parameters - Casework | Type: Tall
Type - Casework - Parametric | File Type: BXF; Parametric | File Name: 01-TallUK; Dimension | Width: 0.9 m; Dimension | Height: 2.1 m; Dimension | Depth: 0.4 m
Casework - Dimension | Width: 0.6 m
Name | Description
SHE_A-Wardrobe_hall 40x90 | 1,SHE_DRAWING+SHEET.dgn,Design Model;4 ,SHE-03.FIRST.dgn,Design Model:134933
SHE_A-Wardrobe_hall 40x90 | 1,SHE_DRAWING+SHEET.dgn,Design Model;4 ,SHE-03.FIRST.dgn,Design Model:279673
SHE_A-Wardrobe_hall 40x90 | 1,SHE_DRAWING+SHEET.dgn,Design Model;4 ,SHE-03.FIRST.dgn,Design Model:282336
SHE_A-Wardrobe_hall 40x90 | 1,SHE_DRAWING+SHEET.dgn,Design Model;4 ,SHE-03.FIRST.dgn,Design Model:282519
SHE_A-Wardrobe_hall 40x90 | 1,SHE_DRAWING+SHEET.dgn,Design Model;4 ,SHE-03.FIRST.dgn,Design Model:282526
SHE_A-Wardrobe_hall 40x90 | 1,SHE_DRAWING+SHEET.dgn,Design Model;6 ,SHE-05.THIRD.dgn,Design Model:134933
SHE_A-Wardrobe_hall 40x90 | 1,SHE_DRAWING+SHEET.dgn,Design Model;6 ,SHE-05.THIRD.dgn,Design Model:279673
SHE_A-Wardrobe_hall 40x90 | 1,SHE_DRAWING+SHEET.dgn,Design Model;6 ,SHE-05.THIRD.dgn,Design Model:282336
SHE_A-Wardrobe_hall 40x90 | 1,SHE_DRAWING+SHEET.dgn,Design Model;6 ,SHE-05.THIRD.dgn,Design Model:282519
SHE_A-Wardrobe_hall 40x90 | 1,SHE_DRAWING+SHEET.dgn,Design Model;6 ,SHE-05.THIRD.dgn,Design Model:282526
SHE_A-Wardrobe_hall 40x90 | 1,SHE_DRAWING+SHEET.dgn,Design Model;18 ,SHE-04.SECOND.dgn,Design Model:134933
SHE_A-Wardrobe_hall 40x90 | 1,SHE_DRAWING+SHEET.dgn,Design Model;18 ,SHE-04.SECOND.dgn,Design Model:279673
SHE_A-Wardrobe_hall 40x90 | 1,SHE_DRAWING+SHEET.dgn,Design Model;18 ,SHE-04.SECOND.dgn,Design Model:282336
SHE_A-Wardrobe_hall 40x90 | 1,SHE_DRAWING+SHEET.dgn,Design Model;18 ,SHE-04.SECOND.dgn,Design Model:282519
SHE_A-Wardrobe_hall 40x90 | 1,SHE_DRAWING+SHEET.dgn,Design Model;18 ,SHE-04.SECOND.dgn,Design Model:282526

# IfcGrid, OrthogonalGrid
In: Building01
Description: Grid Template\Default, Orthogonal

# IfcMember: A-Baseplate (42)
In: RL
Type - PredefinedType: PLATE
Type - Parametric Definition - Parametric | File Type: PAZ; Parametric | File Name: BasePlate_NoGrout_Architectural
Type - Discipline - Discipline: Architectural
Type - Classification - Uniclass2015: Pr_20_29_03_13
Type - Base Plate | Steel - Plate | Thickness: 0.025 m; Plate | Length: 0.3 m; Plate | Width: 0.3 m; Grout | Thickness: 0 m; Grout | Angle: n/a
Material: A_BSUK_BasePlates
Identification - ID | Type ID: Solar panel
Construction Phase - Phase: New Construction
Base Plate | Steel - Bottom Elevation: 0 m; Plate | Thickness: 0.05 m; Plate | Length: 1 m; Plate | Width: 1.7 m
Name | Description
Solar panel | 1 ,SHE_DRAWING+SHEET.dgn,Design Model;11,SHE-15.MEHP.dgn,Design Model:263505
Solar panel | 1 ,SHE_DRAWING+SHEET.dgn,Design Model;11,SHE-15.MEHP.dgn,Design Model:263564
Solar panel | 1 ,SHE_DRAWING+SHEET.dgn,Design Model;11,SHE-15.MEHP.dgn,Design Model:263623
Solar panel | 1 ,SHE_DRAWING+SHEET.dgn,Design Model;11,SHE-15.MEHP.dgn,Design Model:263682
Solar panel | 1 ,SHE_DRAWING+SHEET.dgn,Design Model;11,SHE-15.MEHP.dgn,Design Model:263741
Solar panel | 1 ,SHE_DRAWING+SHEET.dgn,Design Model;11,SHE-15.MEHP.dgn,Design Model:263800
Solar panel | 1 ,SHE_DRAWING+SHEET.dgn,Design Model;11,SHE-15.MEHP.dgn,Design Model:263859
Solar panel | 1 ,SHE_DRAWING+SHEET.dgn,Design Model;11,SHE-15.MEHP.dgn,Design Model:263918
Solar panel | 1 ,SHE_DRAWING+SHEET.dgn,Design Model;11,SHE-15.MEHP.dgn,Design Model:263977
Solar panel | 1 ,SHE_DRAWING+SHEET.dgn,Design Model;11,SHE-15.MEHP.dgn,Design Model:264036
Solar panel | 1 ,SHE_DRAWING+SHEET.dgn,Design Model;11,SHE-15.MEHP.dgn,Design Model:264095
Solar panel | 1 ,SHE_DRAWING+SHEET.dgn,Design Model;11,SHE-15.MEHP.dgn,Design Model:264154
Solar panel | 1 ,SHE_DRAWING+SHEET.dgn,Design Model;11,SHE-15.MEHP.dgn,Design Model:264213
Solar panel | 1 ,SHE_DRAWING+SHEET.dgn,Design Model;11,SHE-15.MEHP.dgn,Design Model:264272
Solar panel | 1 ,SHE_DRAWING+SHEET.dgn,Design Model;11,SHE-15.MEHP.dgn,Design Model:264331
Solar panel | 1 ,SHE_DRAWING+SHEET.dgn,Design Model;11,SHE-15.MEHP.dgn,Design Model:264390
Solar panel | 1 ,SHE_DRAWING+SHEET.dgn,Design Model;11,SHE-15.MEHP.dgn,Design Model:264449
Solar panel | 1 ,SHE_DRAWING+SHEET.dgn,Design Model;11,SHE-15.MEHP.dgn,Design Model:264508
Solar panel | 1 ,SHE_DRAWING+SHEET.dgn,Design Model;11,SHE-15.MEHP.dgn,Design Model:264862
Solar panel | 1 ,SHE_DRAWING+SHEET.dgn,Design Model;11,SHE-15.MEHP.dgn,Design Model:264921
Solar panel | 1 ,SHE_DRAWING+SHEET.dgn,Design Model;11,SHE-15.MEHP.dgn,Design Model:264980
Solar panel | 1 ,SHE_DRAWING+SHEET.dgn,Design Model;11,SHE-15.MEHP.dgn,Design Model:265039
Solar panel | 1 ,SHE_DRAWING+SHEET.dgn,Design Model;11,SHE-15.MEHP.dgn,Design Model:265098
Solar panel | 1 ,SHE_DRAWING+SHEET.dgn,Design Model;11,SHE-15.MEHP.dgn,Design Model:265157
Solar panel | 1 ,SHE_DRAWING+SHEET.dgn,Design Model;11,SHE-15.MEHP.dgn,Design Model:265216
Solar panel | 1 ,SHE_DRAWING+SHEET.dgn,Design Model;11,SHE-15.MEHP.dgn,Design Model:265275
Solar panel | 1 ,SHE_DRAWING+SHEET.dgn,Design Model;11,SHE-15.MEHP.dgn,Design Model:265334
Solar panel | 1 ,SHE_DRAWING+SHEET.dgn,Design Model;11,SHE-15.MEHP.dgn,Design Model:265393
Solar panel | 1 ,SHE_DRAWING+SHEET.dgn,Design Model;11,SHE-15.MEHP.dgn,Design Model:265452
Solar panel | 1 ,SHE_DRAWING+SHEET.dgn,Design Model;11,SHE-15.MEHP.dgn,Design Model:265511
Solar panel | 1 ,SHE_DRAWING+SHEET.dgn,Design Model;11,SHE-15.MEHP.dgn,Design Model:265570
Solar panel | 1 ,SHE_DRAWING+SHEET.dgn,Design Model;11,SHE-15.MEHP.dgn,Design Model:265629
Solar panel | 1 ,SHE_DRAWING+SHEET.dgn,Design Model;11,SHE-15.MEHP.dgn,Design Model:265688
Solar panel | 1 ,SHE_DRAWING+SHEET.dgn,Design Model;11,SHE-15.MEHP.dgn,Design Model:265747
Solar panel | 1 ,SHE_DRAWING+SHEET.dgn,Design Model;11,SHE-15.MEHP.dgn,Design Model:265806
Solar panel | 1 ,SHE_DRAWING+SHEET.dgn,Design Model;11,SHE-15.MEHP.dgn,Design Model:265865
Solar panel | 1 ,SHE_DRAWING+SHEET.dgn,Design Model;11,SHE-15.MEHP.dgn,Design Model:294804
Solar panel | 1 ,SHE_DRAWING+SHEET.dgn,Design Model;11,SHE-15.MEHP.dgn,Design Model:294863
Solar panel | 1 ,SHE_DRAWING+SHEET.dgn,Design Model;11,SHE-15.MEHP.dgn,Design Model:294922
Solar panel | 1 ,SHE_DRAWING+SHEET.dgn,Design Model;11,SHE-15.MEHP.dgn,Design Model:294981
Solar panel | 1 ,SHE_DRAWING+SHEET.dgn,Design Model;11,SHE-15.MEHP.dgn,Design Model:295040
Solar panel | 1 ,SHE_DRAWING+SHEET.dgn,Design Model;11,SHE-15.MEHP.dgn,Design Model:295099

# IfcMember: A-FrameElements:A_BSUK_Steel_Miscellaneous (5)
In: RL
Material: A_BSUK_Steel_Miscellaneous
Name | Description
A-FrameElements--A_BSUK_Steel_Miscellaneous | 1,SHE_DRAWING+SHEET.dgn ,Design Model;1,SHE-01.GROUND.dgn,Design Model:148739
A-FrameElements--A_BSUK_Steel_Miscellaneous | 1,SHE_DRAWING+SHEET.dgn ,Design Model;1,SHE-01.GROUND.dgn,Design Model:148741
A-FrameElements--A_BSUK_Steel_Miscellaneous | 1,SHE_DRAWING+SHEET.dgn ,Design Model;1,SHE-01.GROUND.dgn,Design Model:148742
A-FrameElements--A_BSUK_Steel_Miscellaneous | 1,SHE_DRAWING+SHEET.dgn ,Design Model;1,SHE-01.GROUND.dgn,Design Model:148743
A-FrameElements--A_BSUK_Steel_Miscellaneous | 1,SHE_DRAWING+SHEET.dgn ,Design Model;1,SHE-01.GROUND.dgn,Design Model:148744

# IfcRailing: A-Handrail-900mm (6)
Type - Railing Quantities - Start Post | Count: 0; Corner Post | Count: 0; End Post | Count: 0; Intermediate Post | Count: 0; Mounting Bracket | Count: 0; Balusters 1 | Count: 0; Balusters 2 | Count: 0; Balusters 3 | Count: 0
Type - Railing Parameters - Part Definition: A-FrameElements::A_BSUK_Steel_Miscellaneous; Generate Drawing Symbols: no; Rail 1 | Name: Handrail; Rail 1 | Height: 0.9 m; Rail 1 | Profile Type: Structural Section; Rail 1 | Profile: CHS76.1X5; Rail 1 | Side Offset: 0.1 m; Rail 1 | Part Definition: A-FrameElements::A_BSUK_Steel_Miscellaneous; Rail 1 | Join Method: Vertical; Rail 2 | Name: Middle; Rail 2 | Height: 0.8 m; Rail 2 | Profile Type: <none>; Rail 2 | Profile: CHS42.4X3.2; Rail 2 | Side Offset: 0 m; Rail 2 | Part Definition: A-FrameElements::A_BSUK_Steel_Miscellaneous; Rail 2 | Join Method: Vertical; Rail 3 | Name: Bottom; Rail 3 | Height: 0.15 m; Rail 3 | Profile Type: <none>; Rail 3 | Profile: CHS42.4X3.2; Rail 3 | Side Offset: 0 m; Rail 3 | Part definition: A-FrameElements::A_BSUK_Steel_Miscellaneous; Rail 3 | Join Method: Vertical; Rail 4 | Name: Lower; Rail 4 | Height: 0.1 m; Rail 4 | Profile Type: <none>; Rail 4 | Profile: CHS42.4X3.2; Rail 4 | Side Offset: 0.1 m; Rail 4 | Join Method: Vertical; Rail 5 | Profile Type: <none>; Rail 5 | Height: 0 m; Rail 5 | Side Offset: 0 m; Rail 5 | Join Method: Vertical; Rail 6 | Profile Type: <none>; Rail 6 | Height: 0 m; Rail 6 | Side Offset: 0 m; Rail 6 | Join Method: Vertical; Start Post | Name: Start Post; Start Post | Spacing: 0 m; Start Post | Profile Type: <none>; Start Post | Profile: SHS40x40x3.0; Start Post | Height: 0.001 m; Start Post | Base Offset: 0 m; Start Post | Side Offset: 0 m; Start Post | Part Definition: A-FrameElements::A_BSUK_Steel_Miscellaneous; Corner Post | Name: Corner Post; Corner Post | Spacing: 0 m; Corner Post | Profile Type: <none>; Corner Post | Profile: SHS40x40x3.0; Corner Post | Height: 0.86 m; Corner Post | Base Offset: 0 m; Corner Post | Side Offset: 0 m; Corner Post | Part Definition: A-FrameElements::A_BSUK_Steel_Miscellaneous; End Post | Name: End Post; End Post | Spacing: 0 m; End Post | Profile Type: <none>; End Post | Profile: SHS40x40x3.0; End Post | Height: 0.86 m; End Post | Base Offset: 0 m; End Post | Side Offset: 0 m; End Post | Part Definition: A-FrameElements::A_BSUK_Steel_Miscellaneous; Intermediate Post 1 | Name: Intermediate Post; Intermediate Post 1 | Spacing: 1.2 m; Intermediate Post 1 | Profile Type: <none>; Intermediate Post 1 | Profile: SHS40x40x3.0; Intermediate Post1 | Height: 0.86 m; Intermediate Post1 | Base Offset: 0 m; Intermediate Post1 | Side Offset: 0 m; Intermediate Post 1 | Spacing Type: Max Spacing; Mounting Bracket | Spacing: 0 m; Mounting Bracket | Profile Type: <none>; Mounting Bracket | Height: 0 m; Mounting Bracket | Base Offset: 0 m; Mounting Bracket | Side Offset: 0 m; Mounting Bracket | Spacing Type: Max Spacing; Balusters 1 | Name: Pickets; Balusters 1 | Spacing: 0.1 m; Balusters 1 | Spacing Type: Max Spacing; Balusters 1 | Profile Type: <none>; Balusters 1 | Profile: CHS26.9x3.2; Balusters 1 | Height: 0.78 m; Balusters 1 | Base Offset: 0.15 m; Balusters 1 | Side Offset: 0 m; Balusters 1 | Part Definition: A-FrameElements::A_BSUK_Steel_Miscellaneous; Balusters 2 | Spacing: 0.1 m; Balusters 2 | Spacing Type: Max Spacing; Balusters 2 | Profile Type: <none>; Balusters 2 | Profile: CHS26.9x3.2; Balusters 2 | Height: 0.75 m; Balusters 2 | Base Offset: 0 m; Balusters 2 | Side Offset: 0 m; Balusters 2 | Part Definition: A-FrameElements::A_BSUK_Steel_Miscellaneous; Balusters 3 | Spacing: 0.425 m; Balusters 3 | Spacing Type: Max Spacing; Balusters 3 | Profile Type: <none>; Balusters 3 | Profile: CHS26.9x3.2; Balusters 3 | Height: 0.75 m; Balusters 3 | Base Offset: 0 m; Balusters 3 | Side Offset: 0 m; Balusters 3 | Part Definition: A-FrameElements::A_BSUK_Steel_Miscellaneous; Railing End | Start Name: Start; Railing End | Start Top Offset: 0 m; Railing End | Start Side Offset: 0.1 m; Railing End | End Name: End; Railing Ends | End Top Offset: 0 m; Railing End | End Side Offset: 0.1 m
Type - Classification - Uniclass2015: Ss_25_15_60_66
PredefinedType: HANDRAIL; Material: A_BSUK_Steel_Miscellaneous
Railing Quantities - Rail 2 | Length: 0 m; Rail 3 | Length: 0 m; Rail 4 | Length: 0 m; Rail 5 | Length: 0 m; Rail 6 | Length: 0 m; Start Post | Length: 0 m; Start Post | Total Length: 0 m; Corner Post | Length: 0 m; Corner Post | Total Length: 0 m; End Post | Length: 0 m; End Post | Total Length: 0 m; Intermediate Post | Length: 0 m; Intermediate Post | Total Length: 0 m; Mounting Bracket | Length: 0 m; Mounting Bracket | Total Length: 0 m; Balusters 1 | Length: 0 m; Balusters 1 | Total Length: 0 m; Balusters 2 | Length: 0 m; Balusters 2 | Total Length: 0 m; Balusters 3 | Length: 0 m; Balusters 3 | Total Length: 0 m
Railing Parameters - Rail 1 | Profile Type: ProStructures Shape; Balusters 1 | Thickness: 0 m; Balusters 2 | Thickness: 0 m; Balusters 3 | Thickness: 0 m
Name | In | Description | Rail 1 | Length (m) | Rail 1 | Profile | Rail 1 | Side Offset (m)
A-Handrail-900mm | RL | 1 ,SHE_DRAWING+SHEET.dgn,Design Model;1,SHE-01.GROUND.dgn,Design Model:156478 | 1.7989 | 1\ANSI_PIPE\15NBX3.73WT_PIPE | 0
A-Handrail-900mm | RL | 1 ,SHE_DRAWING+SHEET.dgn,Design Model;1,SHE-01.GROUND.dgn,Design Model:156544 | 1.13322 | 1\ANSI_PIPE\15NBX3.73WT_PIPE | 0
A-Handrail-900mm | GF | 1 ,SHE_DRAWING+SHEET.dgn,Design Model;16,SHE-12.STAIR.dgn,Design Model:223116 | 6.23703 | 1\AS_SHS_C450\40X4.0SHS | 0
A-Handrail-900mm | GF | 1 ,SHE_DRAWING+SHEET.dgn,Design Model;16,SHE-12.STAIR.dgn,Design Model:223387 | 6.37497 | 1\AS_SHS_C450\40X4.0SHS | 0
A-Handrail-900mm | GF | 1 ,SHE_DRAWING+SHEET.dgn,Design Model;16,SHE-12.STAIR.dgn,Design Model:223924 | 6.19752 | 1\AS_SHS_C450\40X4.0SHS | 0.001
A-Handrail-900mm | GF | 1 ,SHE_DRAWING+SHEET.dgn,Design Model;16,SHE-12.STAIR.dgn,Design Model:224304 | 4.98098 | 1\AS_SHS_C450\40X4.0SHS | 0

# IfcRailing: A-RailingGlassPanel-1050mm (25)
Type - Railing Parameters - Part Definition: A-FrameElements::A_BSUK_Steel_Miscellaneous; Generate Drawing Symbols: no; Rail 1 | Name: Top; Rail 1 | Height: 1.05 m; Rail 1 | Profile Type: Profile; Rail 1 | Profile: Round Cap; Rail 1 | Side Offset: 0 m; Rail 1 | Part Definition: A-Finishes::A_BSUK_ChromeRailingSystems; Rail 1 | Join Method: Vertical; Rail 2 | Name: Bottom; Rail 2 | Height: 0 m; Rail 2 | Profile Type: Profile; Rail 2 | Profile: Shoe 65x100; Rail 2 | Side Offset: 0 m; Rail 2 | Part Definition: A-Finishes::A_BSUK_ChromeRailingSystems; Rail 2 | Join Method: <none>; Rail 3 | Name: Bottom; Rail 3 | Height: 0.15 m; Rail 3 | Profile Type: <none>; Rail 3 | Profile: CHS42.4X3.2; Rail 3 | Side Offset: 0 m; Rail 3 | Part definition: A-FrameElements::A_BSUK_Steel_Miscellaneous; Rail 3 | Join Method: Vertical; Rail 4 | Name: Lower; Rail 4 | Height: 0.1 m; Rail 4 | Profile Type: <none>; Rail 4 | Profile: CHS42.4X3.2; Rail 4 | Side Offset: 0.1 m; Rail 4 | Join Method: Vertical; Rail 5 | Profile Type: <none>; Rail 5 | Height: 0 m; Rail 5 | Side Offset: 0 m; Rail 5 | Join Method: Vertical; Rail 6 | Profile Type: <none>; Rail 6 | Height: 0 m; Rail 6 | Side Offset: 0 m; Rail 6 | Join Method: Vertical; Start Post | Name: Start Post; Start Post | Spacing: 0 m; Start Post | Profile Type: Cell; Start Post | Profile: Gap; Start Post | Height: 1.05 m; Start Post | Base Offset: 0 m; Start Post | Side Offset: 0 m; Start Post | Part Definition: A-FrameElements::A_BSUK_Steel_Miscellaneous; Corner Post | Name: Corner Post; Corner Post | Spacing: 0 m; Corner Post | Profile Type: Cell; Corner Post | Profile: Gap; Corner Post | Height: 1.02 m; Corner Post | Base Offset: 0 m; Corner Post | Side Offset: 0 m; Corner Post | Part Definition: A-FrameElements::A_BSUK_Steel_Miscellaneous; End Post | Name: End Post; End Post | Spacing: 0 m; End Post | Profile Type: Cell; End Post | Profile: Gap; End Post | Height: 1.05 m; End Post | Base Offset: 0 m; End Post | Side Offset: 0 m; End Post | Part Definition: A-FrameElements::A_BSUK_Steel_Miscellaneous; Intermediate Post 1 | Name: Intermediate; Intermediate Post 1 | Spacing: 1.5 m; Intermediate Post 1 | Profile Type: Cell; Intermediate Post 1 | Profile: Gap; Intermediate Post1 | Height: 1.03 m; Intermediate Post1 | Base Offset: 0 m; Intermediate Post1 | Side Offset: 0 m; Intermediate Post 1 | Part Definition: A-Finishes::A_BSUK_ChromeRailingSystems; Intermediate Post 1 | Spacing Type: Max Spacing; Mounting Bracket | Spacing: 0 m; Mounting Bracket | Profile Type: <none>; Mounting Bracket | Height: 0 m; Mounting Bracket | Base Offset: 0 m; Mounting Bracket | Side Offset: 0 m; Balusters 1 | Name: Baluster 1; Balusters 1 | Spacing: 0 m; Balusters 1 | Spacing Type: Max Spacing; Balusters 1 | Profile Type: Parametric Panel; Balusters 1 | Profile: Panel Glass; Balusters 1 | Height: 1.025 m; Balusters 1 | Base Offset: 0.05 m; Balusters 1 | Side Offset: 0 m; Balusters 1 | Thickness: 0.01 m; Balusters 1 | Part Definition: A-Finishes::A_BSUK_GlassPanelRailingSystems; Balusters 2 | Spacing: 0.1 m; Balusters 2 | Spacing Type: Max Spacing; Balusters 2 | Profile Type: <none>; Balusters 2 | Profile: CHS26.9x3.2; Balusters 2 | Height: 0.75 m; Balusters 2 | Base Offset: 0 m; Balusters 2 | Side Offset: 0 m; Balusters 2 | Thickness: 0 m; Balusters 2 | Part Definition: A-FrameElements::A_BSUK_Steel_Miscellaneous; Balusters 3 | Spacing: 0.425 m; Balusters 3 | Spacing Type: Max Spacing; Balusters 3 | Profile Type: <none>; Balusters 3 | Profile: CHS26.9x3.2; Balusters 3 | Height: 0.75 m; Balusters 3 | Base Offset: 0 m; Balusters 3 | Side Offset: 0 m; Balusters 3 | Thickness: 0 m; Balusters 3 | Part Definition: A-FrameElements::A_BSUK_Steel_Miscellaneous; Railing End | Start Name: Start; Railing End | Start Top Offset: 0 m; Railing End | Start Side Offset: 0.1 m; Railing End | End Name: End; Railing Ends | End Top Offset: 0 m; Railing End | End Side Offset: 0.1 m
Type - Classification - Uniclass2015: Ss_25_15_60_66
PredefinedType: HANDRAIL; Material: A_BSUK_Steel_Miscellaneous
Railing Quantities - Rail 3 | Length: 0 m; Rail 4 | Length: 0 m; Rail 5 | Length: 0 m; Rail 6 | Length: 0 m; Mounting Bracket | Count: 0; Mounting Bracket | Length: 0 m; Mounting Bracket | Total Length: 0 m; Balusters 1 | Length: 0 m; Balusters 1 | Total Length: 0 m; Balusters 2 | Count: 0; Balusters 2 | Length: 0 m; Balusters 2 | Total Length: 0 m; Balusters 3 | Count: 0; Balusters 3 | Length: 0 m; Balusters 3 | Total Length: 0 m
Name | In | Description | Rail 1 | Length (m) | Rail 2 | Length (m) | Start Post | Count = End Post | Count | Start Post | Length (m) = Start Post | Total Length (m) = End Post | Length (m) = End Post | Total Length (m) | Corner Post | Count | Corner Post | Length (m) | Corner Post | Total Length (m) | Intermediate Post | Count | Intermediate Post | Length (m) = Intermediate Post | Total Length (m) | Balusters 1 | Count | Phase
A-RailingGlassPanel-1050mm | RL | 1 ,SHE_DRAWING+SHEET.dgn,Design Model;2,SHE-02.MEZZANINE.dgn,Design Model:204526 | 1.82104 | 1.82104 | 1 | 0 | 0 | 0 | 0 | 1 | 1.03 | 1 | Railing Parameters - Rail 1 | Height: 0.855 m; Rail 1 | Profile: Square 45x45mm; Rail 2 | Profile: Square 45x45mm; Balusters 1 | Height: 0.85 m
A-RailingGlassPanel-1050mm | RL | 1 ,SHE_DRAWING+SHEET.dgn,Design Model;8,SHE-07.FIFTH.dgn,Design Model:331689 | 5.50502 | 1.35631 | 1 | 0 | 3 | 0.68 | 2.04 | 1 | 1.03 | 2 | Railing Parameters - Rail 1 | Height: 0.855 m; Rail 1 | Profile: Square 45x45mm; Rail 2 | Profile: Square 45x45mm; Balusters 1 | Height: 0.85 m
A-RailingGlassPanel-1050mm | RL | 1 ,SHE_DRAWING+SHEET.dgn,Design Model;8,SHE-07.FIFTH.dgn,Design Model:332696 | 2.42085 | 2.42085 | 1 | 1.2 | 0 | 0 | 0 | 1 | 1.2 | 2 | Railing Parameters - Rail 1 | Height: 0.855 m; Rail 1 | Profile: Square 45x45mm; Rail 2 | Profile: Square 45x45mm; Balusters 1 | Height: 0.85 m
A-RailingGlassPanel-1050mm | RL | 1 ,SHE_DRAWING+SHEET.dgn,Design Model;8,SHE-07.FIFTH.dgn,Design Model:332857 | 1.21662 | 1.21662 | 1 | 0 | 0 | 0 | 0 | 0 | 0 | 1 | Railing Parameters - Rail 1 | Height: 0.855 m; Rail 1 | Profile: Square 45x45mm; Rail 2 | Profile: Square 45x45mm; Balusters 1 | Height: 0.85 m
A-RailingGlassPanel-1050mm | RL | 1 ,SHE_DRAWING+SHEET.dgn,Design Model;8,SHE-07.FIFTH.dgn,Design Model:333239 | 5.89924 | 1.45618 | 1 | 0 | 3 | 0.68 | 2.04 | 1 | 1.03 | 2 | Railing Parameters - Rail 1 | Height: 0.855 m; Rail 1 | Profile: Square 45x45mm; Rail 2 | Profile: Square 45x45mm; Balusters 1 | Height: 0.85 m
A-RailingGlassPanel-1050mm | RL | 1 ,SHE_DRAWING+SHEET.dgn,Design Model;8,SHE-07.FIFTH.dgn,Design Model:334241 | 5.56748 | 1.34192 | 1 | 0 | 3 | 0.68 | 2.04 | 1 | 1.03 | 2 | Railing Parameters - Rail 1 | Height: 0.855 m; Rail 1 | Profile: Square 45x45mm; Rail 2 | Profile: Square 45x45mm; Balusters 1 | Height: 0.85 m
A-RailingGlassPanel-1050mm | GF | 1 ,SHE_DRAWING+SHEET.dgn,Design Model;15,SHE-14.BALCONY.dgn,Design Model:174469 | 2.7366 | 2.7366 | 1 | 0 | 0 | 0 | 0 | 0 | 0 | 1 | New Construction
A-RailingGlassPanel-1050mm | GF | 1 ,SHE_DRAWING+SHEET.dgn,Design Model;15,SHE-14.BALCONY.dgn,Design Model:174632 | 0 | 0 | 0 | 0 | 0 | 0 | 0 | 0 | 0 | 0 | New Construction
A-RailingGlassPanel-1050mm | GF | 1 ,SHE_DRAWING+SHEET.dgn,Design Model;15,SHE-14.BALCONY.dgn,Design Model:174789 | 0 | 0 | 0 | 0 | 0 | 0 | 0 | 0 | 0 | 0 | New Construction
A-RailingGlassPanel-1050mm | GF | 1 ,SHE_DRAWING+SHEET.dgn,Design Model;15,SHE-14.BALCONY.dgn,Design Model:174944 | 0 | 0 | 0 | 0 | 0 | 0 | 0 | 0 | 0 | 0 | New Construction
A-RailingGlassPanel-1050mm | GF | 1 ,SHE_DRAWING+SHEET.dgn,Design Model;15,SHE-14.BALCONY.dgn,Design Model:175104 | 2.7366 | 2.7366 | 1 | 0 | 0 | 0 | 0 | 0 | 0 | 1 | New Construction
A-RailingGlassPanel-1050mm | GF | 1 ,SHE_DRAWING+SHEET.dgn,Design Model;15,SHE-14.BALCONY.dgn,Design Model:175267 | 1.01038 | 1.01038 | 1 | 0 | 0 | 0 | 0 | 0 | 0 | 1 | New Construction
A-RailingGlassPanel-1050mm | GF | 1 ,SHE_DRAWING+SHEET.dgn,Design Model;15,SHE-14.BALCONY.dgn,Design Model:175593 | 2.7366 | 2.7366 | 1 | 0 | 0 | 0 | 0 | 0 | 0 | 1 | New Construction
A-RailingGlassPanel-1050mm | GF | 1 ,SHE_DRAWING+SHEET.dgn,Design Model;15,SHE-14.BALCONY.dgn,Design Model:175756 | 0 | 0 | 0 | 0 | 0 | 0 | 0 | 0 | 0 | 0 | New Construction
A-RailingGlassPanel-1050mm | GF | 1 ,SHE_DRAWING+SHEET.dgn,Design Model;15,SHE-14.BALCONY.dgn,Design Model:175913 | 0 | 0 | 0 | 0 | 0 | 0 | 0 | 0 | 0 | 0 | New Construction
A-RailingGlassPanel-1050mm | GF | 1 ,SHE_DRAWING+SHEET.dgn,Design Model;15,SHE-14.BALCONY.dgn,Design Model:176068 | 0 | 0 | 0 | 0 | 0 | 0 | 0 | 0 | 0 | 0 | New Construction
A-RailingGlassPanel-1050mm | GF | 1 ,SHE_DRAWING+SHEET.dgn,Design Model;15,SHE-14.BALCONY.dgn,Design Model:176228 | 2.7366 | 2.7366 | 1 | 0 | 0 | 0 | 0 | 0 | 0 | 1 | New Construction
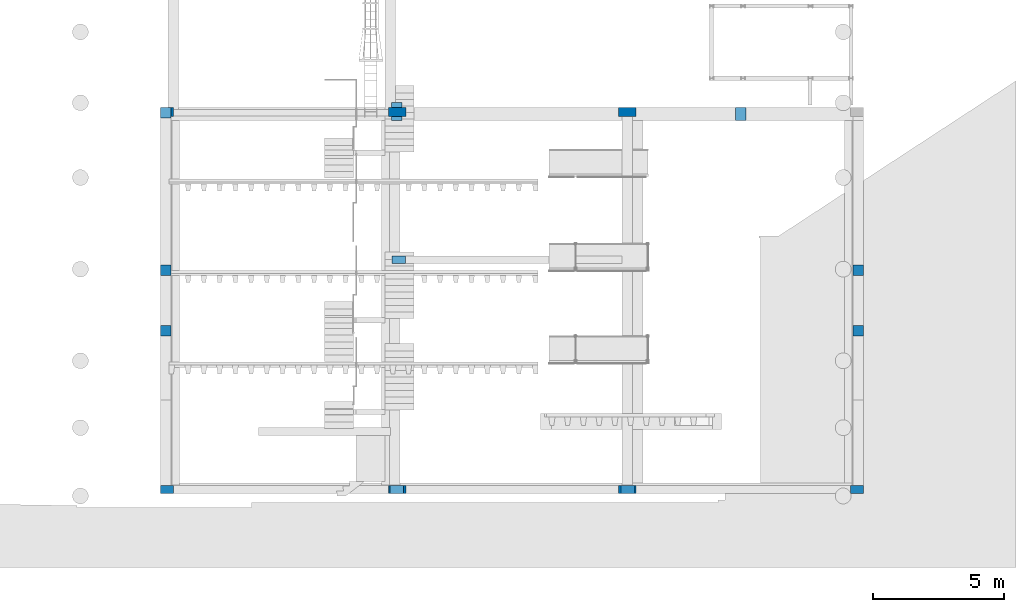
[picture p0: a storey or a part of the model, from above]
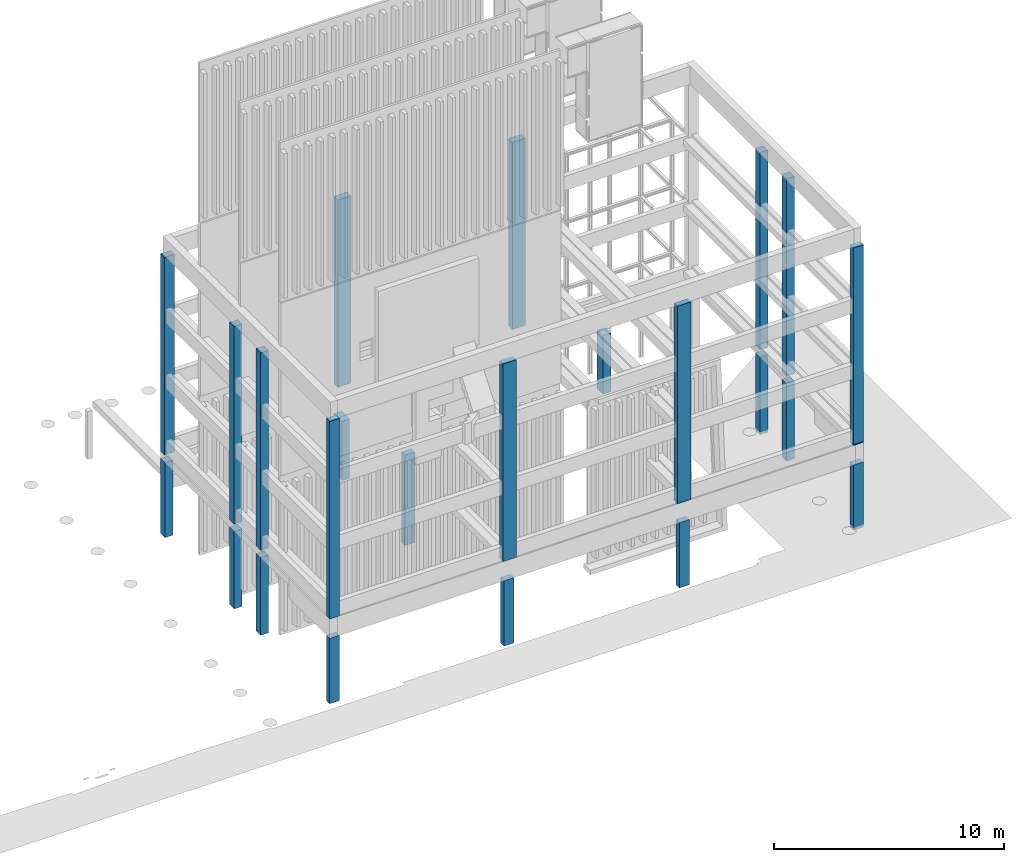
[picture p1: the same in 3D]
Properties of the parts of a building model (IFC2X3), part 7 of 16

# IfcRailing: A-RailingGlassPanel-1050mm (25)
Name | In | Description | Rail 1 | Length (m) | Rail 2 | Length (m) | Start Post | Count = End Post | Count | Start Post | Length (m) = Start Post | Total Length (m) = End Post | Length (m) = End Post | Total Length (m) | Corner Post | Count | Corner Post | Length (m) | Corner Post | Total Length (m) | Intermediate Post | Count | Intermediate Post | Length (m) = Intermediate Post | Total Length (m) | Balusters 1 | Count | Phase
A-RailingGlassPanel-1050mm | GF | 1 ,SHE_DRAWING+SHEET.dgn,Design Model;15,SHE-14.BALCONY.dgn,Design Model:176391 | 1.01038 | 1.01038 | 1 | 0 | 0 | 0 | 0 | 0 | 0 | 1 | New Construction
A-RailingGlassPanel-1050mm | GF | 1 ,SHE_DRAWING+SHEET.dgn,Design Model;15,SHE-14.BALCONY.dgn,Design Model:176718 | 1.01038 | 1.01038 | 1 | 0 | 0 | 0 | 0 | 0 | 0 | 1 | New Construction
A-RailingGlassPanel-1050mm | GF | 1 ,SHE_DRAWING+SHEET.dgn,Design Model;15,SHE-14.BALCONY.dgn,Design Model:176881 | 1.01038 | 1.01038 | 1 | 0 | 0 | 0 | 0 | 0 | 0 | 1 | New Construction
A-RailingGlassPanel-1050mm | GF | 1 ,SHE_DRAWING+SHEET.dgn,Design Model;15,SHE-14.BALCONY.dgn,Design Model:177356 | 0 | 0 | 0 | 0 | 0 | 0 | 0 | 0 | 0 | 0 | New Construction
A-RailingGlassPanel-1050mm | GF | 1 ,SHE_DRAWING+SHEET.dgn,Design Model;15,SHE-14.BALCONY.dgn,Design Model:177511 | 0 | 0 | 0 | 0 | 0 | 0 | 0 | 0 | 0 | 0 | New Construction
A-RailingGlassPanel-1050mm | GF | 1 ,SHE_DRAWING+SHEET.dgn,Design Model;15,SHE-14.BALCONY.dgn,Design Model:177668 | 0 | 0 | 0 | 0 | 0 | 0 | 0 | 0 | 0 | 0 | New Construction
A-RailingGlassPanel-1050mm | GF | 1 ,SHE_DRAWING+SHEET.dgn,Design Model;15,SHE-14.BALCONY.dgn,Design Model:177823 | 0 | 0 | 0 | 0 | 0 | 0 | 0 | 0 | 0 | 0 | New Construction
A-RailingGlassPanel-1050mm | GF | 1 ,SHE_DRAWING+SHEET.dgn,Design Model;15,SHE-14.BALCONY.dgn,Design Model:178589 | 17.6468 | 7.52716 | 1 | 0 | 4 | 0.51 | 2.04 | 3 | 0 | 6

# IfcRailing: S-Handrail-900mm (9)
Type - Railing Quantities - Start Post | Count: 0; Corner Post | Count: 0; End Post | Count: 0; Intermediate Post | Count: 0; Mounting Bracket | Count: 0; Balusters 1 | Count: 0; Balusters 2 | Count: 0; Balusters 3 | Count: 0
Type - Railing Parameters - Part Definition: A-FrameElements::A_BSUK_Steel_Miscellaneous; Generate Drawing Symbols: no; Rail 1 | Name: Handrail; Rail 1 | Height: 0.9 m; Rail 1 | Profile Type: Structural Section; Rail 1 | Profile: CHS76.1X5; Rail 1 | Side Offset: 0.1 m; Rail 1 | Part Definition: S-FrameElements::S_BSUK_Steel_Miscellaneous; Rail 1 | Join Method: Vertical; Rail 2 | Name: Middle; Rail 2 | Height: 0.8 m; Rail 2 | Profile Type: <none>; Rail 2 | Profile: CHS42.4X3.2; Rail 2 | Side Offset: 0 m; Rail 2 | Part Definition: S-FrameElements::S_BSUK_Steel_Miscellaneous; Rail 2 | Join Method: Vertical; Rail 3 | Name: Bottom; Rail 3 | Height: 0.15 m; Rail 3 | Profile Type: <none>; Rail 3 | Profile: CHS42.4X3.2; Rail 3 | Side Offset: 0 m; Rail 3 | Part definition: S-FrameElements::S_BSUK_Steel_Miscellaneous; Rail 3 | Join Method: Vertical; Rail 4 | Name: Lower; Rail 4 | Height: 0.1 m; Rail 4 | Profile Type: <none>; Rail 4 | Profile: CHS42.4X3.2; Rail 4 | Side Offset: 0.1 m; Rail 4 | Join Method: Vertical; Rail 5 | Profile Type: <none>; Rail 5 | Height: 0 m; Rail 5 | Side Offset: 0 m; Rail 5 | Join Method: Vertical; Rail 6 | Profile Type: <none>; Rail 6 | Height: 0 m; Rail 6 | Side Offset: 0 m; Rail 6 | Join Method: Vertical; Start Post | Name: Start Post; Start Post | Spacing: 0 m; Start Post | Profile Type: <none>; Start Post | Profile: SHS40x40x3.0; Start Post | Height: 0.001 m; Start Post | Base Offset: 0 m; Start Post | Side Offset: 0 m; Start Post | Part Definition: S-FrameElements::S_BSUK_Steel_Miscellaneous; Corner Post | Name: Corner Post; Corner Post | Spacing: 0 m; Corner Post | Profile Type: <none>; Corner Post | Profile: SHS40x40x3.0; Corner Post | Height: 0.86 m; Corner Post | Base Offset: 0 m; Corner Post | Side Offset: 0 m; Corner Post | Part Definition: S-FrameElements::S_BSUK_Steel_Miscellaneous; End Post | Name: End Post; End Post | Spacing: 0 m; End Post | Profile Type: <none>; End Post | Profile: SHS40x40x3.0; End Post | Height: 0.86 m; End Post | Base Offset: 0 m; End Post | Side Offset: 0 m; End Post | Part Definition: S-FrameElements::S_BSUK_Steel_Miscellaneous; Intermediate Post 1 | Name: Intermediate Post; Intermediate Post 1 | Spacing: 1.2 m; Intermediate Post 1 | Profile Type: <none>; Intermediate Post 1 | Profile: SHS40x40x3.0; Intermediate Post1 | Height: 0.86 m; Intermediate Post1 | Base Offset: 0 m; Intermediate Post1 | Side Offset: 0 m; Intermediate Post 1 | Spacing Type: Max Spacing; Mounting Bracket | Spacing: 0 m; Mounting Bracket | Profile Type: <none>; Mounting Bracket | Height: 0 m; Mounting Bracket | Base Offset: 0 m; Mounting Bracket | Side Offset: 0 m; Mounting Bracket | Spacing Type: Max Spacing; Balusters 1 | Name: Pickets; Balusters 1 | Spacing: 0.1 m; Balusters 1 | Spacing Type: Max Spacing; Balusters 1 | Profile Type: <none>; Balusters 1 | Profile: CHS26.9x3.2; Balusters 1 | Height: 0.78 m; Balusters 1 | Base Offset: 0.15 m; Balusters 1 | Side Offset: 0 m; Balusters 1 | Part Definition: S-FrameElements::S_BSUK_Steel_Miscellaneous; Balusters 2 | Spacing: 0.1 m; Balusters 2 | Spacing Type: Max Spacing; Balusters 2 | Profile Type: <none>; Balusters 2 | Profile: CHS26.9x3.2; Balusters 2 | Height: 0.75 m; Balusters 2 | Base Offset: 0 m; Balusters 2 | Side Offset: 0 m; Balusters 2 | Part Definition: S-FrameElements::S_BSUK_Steel_Miscellaneous; Balusters 3 | Spacing: 0.425 m; Balusters 3 | Spacing Type: Max Spacing; Balusters 3 | Profile Type: <none>; Balusters 3 | Profile: CHS26.9x3.2; Balusters 3 | Height: 0.75 m; Balusters 3 | Base Offset: 0 m; Balusters 3 | Side Offset: 0 m; Balusters 3 | Part Definition: S-FrameElements::S_BSUK_Steel_Miscellaneous; Railing End | Start Name: Start; Railing End | Start Top Offset: 0 m; Railing End | Start Side Offset: 0.1 m; Railing End | End Name: End; Railing Ends | End Top Offset: 0 m; Railing End | End Side Offset: 0.1 m
Type - Classification - Uniclass2015: Ss_25_15_60_66
PredefinedType: HANDRAIL; Material: A_BSUK_Steel_Miscellaneous
Railing Quantities - Rail 2 | Length: 0 m; Rail 3 | Length: 0 m; Rail 4 | Length: 0 m; Rail 5 | Length: 0 m; Rail 6 | Length: 0 m; Start Post | Length: 0 m; Start Post | Total Length: 0 m; Corner Post | Length: 0 m; Corner Post | Total Length: 0 m; End Post | Length: 0 m; End Post | Total Length: 0 m; Intermediate Post | Length: 0 m; Intermediate Post | Total Length: 0 m; Mounting Bracket | Length: 0 m; Mounting Bracket | Total Length: 0 m; Balusters 1 | Length: 0 m; Balusters 1 | Total Length: 0 m; Balusters 2 | Length: 0 m; Balusters 2 | Total Length: 0 m; Balusters 3 | Length: 0 m; Balusters 3 | Total Length: 0 m
Railing Parameters - Rail 1 | Profile Type: ProStructures Shape; Balusters 1 | Thickness: 0 m; Balusters 2 | Thickness: 0 m; Balusters 3 | Thickness: 0 m
Name | In | Description | Rail 1 | Length (m) | Rail 1 | Profile
S-Handrail-900mm | RL | 1 ,SHE_DRAWING+SHEET.dgn,Design Model;7,SHE-06.FOURTH.dgn,Design Model:149595 | 4.29032 | 1\AS_SHS_C450\40X4.0SHS | Railing Parameters - Rail 1 | Side Offset: -0.1 m
S-Handrail-900mm | RL | 1 ,SHE_DRAWING+SHEET.dgn,Design Model;7,SHE-06.FOURTH.dgn,Design Model:150039 | 4.1462 | 1\AS_SHS_C450\40X4.0SHS | Railing Parameters - Rail 1 | Side Offset: -0.1 m
S-Handrail-900mm | RL | 1 ,SHE_DRAWING+SHEET.dgn,Design Model;7,SHE-06.FOURTH.dgn,Design Model:153072 | 4.57865 | 1\AS_SHS_C450\40X4.0SHS | Railing Parameters - Rail 1 | Side Offset: -0.1 m
S-Handrail-900mm | RL | 1 ,SHE_DRAWING+SHEET.dgn,Design Model;7,SHE-06.FOURTH.dgn,Design Model:148849 | 4.41933 | 1\AS_SHS_C450\40X4.0SHS | Railing Parameters - Rail 1 | Side Offset: -0.1 m
S-Handrail-900mm | RL | 1 ,SHE_DRAWING+SHEET.dgn,Design Model;8,SHE-07.FIFTH.dgn,Design Model:148301 | 8.31043 | 1\BS_CHS\CHS76.1X5 | Construction Phase - Phase: New Construction
S-Handrail-900mm | RL | 1 ,SHE_DRAWING+SHEET.dgn,Design Model;8,SHE-07.FIFTH.dgn,Design Model:148337 | 8.31043 | 1\BS_CHS\CHS76.1X5 | Construction Phase - Phase: New Construction
S-Handrail-900mm | RL | 1 ,SHE_DRAWING+SHEET.dgn,Design Model;8,SHE-07.FIFTH.dgn,Design Model:148350 | 8.31043 | 1\BS_CHS\CHS76.1X5 | Construction Phase - Phase: New Construction
S-Handrail-900mm | RL | 1 ,SHE_DRAWING+SHEET.dgn,Design Model;8,SHE-07.FIFTH.dgn,Design Model:148361 | 8.31043 | 1\BS_CHS\CHS76.1X5 | Construction Phase - Phase: New Construction
S-Handrail-900mm | GF | 1 ,SHE_DRAWING+SHEET.dgn,Design Model;16,SHE-12.STAIR.dgn,Design Model:253213 | 1.22 | 1\AS_SHS_C450\40X4.0SHS

# IfcRoof: A-Roofs:A_BSUK_Roofs (8)
In: RL
ShapeType: FREEFORM; Material: A_BSUK_Roofs
Name | Description
A-Roofs--A_BSUK_Roofs | 1 ,SHE_DRAWING+SHEET.dgn,Design Model;10,SHE-08.ROOF mansard volume.dgn ,Design Model:91768
A-Roofs--A_BSUK_Roofs | 1 ,SHE_DRAWING+SHEET.dgn,Design Model;10,SHE-08.ROOF mansard volume.dgn ,Design Model:91829
A-Roofs--A_BSUK_Roofs | 1 ,SHE_DRAWING+SHEET.dgn,Design Model;10,SHE-08.ROOF mansard volume.dgn ,Design Model:91868
A-Roofs--A_BSUK_Roofs | 1 ,SHE_DRAWING+SHEET.dgn,Design Model;10,SHE-08.ROOF mansard volume.dgn ,Design Model:91929
A-Roofs--A_BSUK_Roofs | 1 ,SHE_DRAWING+SHEET.dgn,Design Model;10,SHE-08.ROOF mansard volume.dgn ,Design Model:91993
A-Roofs--A_BSUK_Roofs | 1 ,SHE_DRAWING+SHEET.dgn,Design Model;10,SHE-08.ROOF mansard volume.dgn ,Design Model:92062
A-Roofs--A_BSUK_Roofs | 1 ,SHE_DRAWING+SHEET.dgn,Design Model;10,SHE-08.ROOF mansard volume.dgn ,Design Model:92115
A-Roofs--A_BSUK_Roofs | 1 ,SHE_DRAWING+SHEET.dgn,Design Model;10,SHE-08.ROOF mansard volume.dgn ,Design Model:92191

# IfcRoof: A-ZeeProfile01 (51)
In: RL
ShapeType: FREEFORM; Material: A_BSUK_Roofs
Profile Parameters - Cell Symbol Name: Profiles::Zee-Profile-01; Rotation Angle: 0; Flip State: no
Materials - Part Definition: A-Roofs::A_BSUK_Roofs
Name | Description | Uniclass2015 | ID | Description | ID | Notes
A-ZeeProfile01 | 1 ,SHE_DRAWING+SHEET.dgn,Design Model;2,SHE-02.MEZZANINE.dgn,Design Model:108082 | Pr_35_90_43
A-ZeeProfile01 | 1 ,SHE_DRAWING+SHEET.dgn,Design Model;2,SHE-02.MEZZANINE.dgn,Design Model:108095 | Pr_35_90_43
A-ZeeProfile01 | 1 ,SHE_DRAWING+SHEET.dgn,Design Model;2,SHE-02.MEZZANINE.dgn,Design Model:108107 | Pr_35_90_43
A-ZeeProfile01 | 1 ,SHE_DRAWING+SHEET.dgn,Design Model;8,SHE-07.FIFTH.dgn,Design Model:118604 | Pr_35_90_43
A-ZeeProfile01 | 1 ,SHE_DRAWING+SHEET.dgn,Design Model;8,SHE-07.FIFTH.dgn,Design Model:118616 | Pr_35_90_43
A-ZeeProfile01 | 1 ,SHE_DRAWING+SHEET.dgn,Design Model;8,SHE-07.FIFTH.dgn,Design Model:119524 | Pr_35_90_43
A-ZeeProfile01 | 1 ,SHE_DRAWING+SHEET.dgn,Design Model;8,SHE-07.FIFTH.dgn,Design Model:119536 | Pr_35_90_43
A-ZeeProfile01 | 1 ,SHE_DRAWING+SHEET.dgn,Design Model;8,SHE-07.FIFTH.dgn,Design Model:119911 | Pr_35_90_43
A-ZeeProfile01 | 1 ,SHE_DRAWING+SHEET.dgn,Design Model;8,SHE-07.FIFTH.dgn,Design Model:119923 | Pr_35_90_43
A-ZeeProfile01 | 1 ,SHE_DRAWING+SHEET.dgn,Design Model;8,SHE-07.FIFTH.dgn,Design Model:119937 | Pr_35_90_43
A-ZeeProfile01 | 1 ,SHE_DRAWING+SHEET.dgn,Design Model;8,SHE-07.FIFTH.dgn,Design Model:119949 | Pr_35_90_43
A-ZeeProfile01 | ParapetCladding :1,SHE_DRAWING+SHEET.dgn,Design Model;14,SHE-08.ROOF.dgn ,Design Model:112325 | Pr_35_90_43 | ParapetCladding | mansard roof
A-ZeeProfile01 | ParapetCladding :1,SHE_DRAWING+SHEET.dgn,Design Model;14,SHE-08.ROOF.dgn ,Design Model:112337 | Pr_35_90_43 | ParapetCladding | mansard roof
A-ZeeProfile01 | ParapetCladding :1,SHE_DRAWING+SHEET.dgn,Design Model;14,SHE-08.ROOF.dgn ,Design Model:113008 | Pr_20_76_51_04 | ParapetCladding | main building
A-ZeeProfile01 | ParapetCladding :1,SHE_DRAWING+SHEET.dgn,Design Model;14,SHE-08.ROOF.dgn ,Design Model:113022 | Pr_20_76_51_04 | ParapetCladding | main building
A-ZeeProfile01 | ParapetCladding :1,SHE_DRAWING+SHEET.dgn,Design Model;14,SHE-08.ROOF.dgn ,Design Model:113034 | Pr_20_76_51_04 | ParapetCladding | main building
A-ZeeProfile01 | ParapetCladding :1,SHE_DRAWING+SHEET.dgn,Design Model;14,SHE-08.ROOF.dgn ,Design Model:113048 | Pr_20_76_51_04 | ParapetCladding | main building
A-ZeeProfile01 | ParapetCladding :1,SHE_DRAWING+SHEET.dgn,Design Model;14,SHE-08.ROOF.dgn ,Design Model:113062 | Pr_20_76_51_04 | ParapetCladding | main building
A-ZeeProfile01 | ParapetCladding :1,SHE_DRAWING+SHEET.dgn,Design Model;14,SHE-08.ROOF.dgn ,Design Model:113124 | Pr_20_76_51_04 | ParapetCladding | main building
A-ZeeProfile01 | ParapetCladding :1,SHE_DRAWING+SHEET.dgn,Design Model;14,SHE-08.ROOF.dgn ,Design Model:113136 | Pr_20_76_51_04 | ParapetCladding | main building
A-ZeeProfile01 | ParapetCladding :1,SHE_DRAWING+SHEET.dgn,Design Model;14,SHE-08.ROOF.dgn ,Design Model:113148 | Pr_20_76_51_04 | ParapetCladding | main building
A-ZeeProfile01 | ParapetCladding :1,SHE_DRAWING+SHEET.dgn,Design Model;14,SHE-08.ROOF.dgn ,Design Model:113160 | Pr_20_76_51_04 | ParapetCladding | main building
A-ZeeProfile01 | ParapetCladding :1,SHE_DRAWING+SHEET.dgn,Design Model;14,SHE-08.ROOF.dgn ,Design Model:113172 | Pr_20_76_51_04 | ParapetCladding | main building
A-ZeeProfile01 | ParapetCladding :1,SHE_DRAWING+SHEET.dgn,Design Model;14,SHE-08.ROOF.dgn ,Design Model:113186 | Pr_20_76_51_04 | ParapetCladding | main building
A-ZeeProfile01 | ParapetCladding :1,SHE_DRAWING+SHEET.dgn,Design Model;14,SHE-08.ROOF.dgn ,Design Model:113200 | Pr_20_76_51_04 | ParapetCladding | main building
A-ZeeProfile01 | ParapetCladding :1,SHE_DRAWING+SHEET.dgn,Design Model;14,SHE-08.ROOF.dgn ,Design Model:113214 | Pr_20_76_51_04 | ParapetCladding | main building
A-ZeeProfile01 | ParapetCladding :1,SHE_DRAWING+SHEET.dgn,Design Model;14,SHE-08.ROOF.dgn ,Design Model:113228 | Pr_20_76_51_04 | ParapetCladding | main building
A-ZeeProfile01 | ParapetCladding :1,SHE_DRAWING+SHEET.dgn,Design Model;14,SHE-08.ROOF.dgn ,Design Model:113242 | Pr_20_76_51_04 | ParapetCladding | main building
A-ZeeProfile01 | ParapetCladding :1,SHE_DRAWING+SHEET.dgn,Design Model;14,SHE-08.ROOF.dgn ,Design Model:113256 | Pr_20_76_51_04 | ParapetCladding | main building
A-ZeeProfile01 | ParapetCladding :1,SHE_DRAWING+SHEET.dgn,Design Model;14,SHE-08.ROOF.dgn ,Design Model:113270 | Pr_20_76_51_04 | ParapetCladding | main building
A-ZeeProfile01 | ParapetCladding :1,SHE_DRAWING+SHEET.dgn,Design Model;14,SHE-08.ROOF.dgn ,Design Model:113284 | Pr_20_76_51_04 | ParapetCladding | main building
A-ZeeProfile01 | ParapetCladding :1,SHE_DRAWING+SHEET.dgn,Design Model;14,SHE-08.ROOF.dgn ,Design Model:113298 | Pr_20_76_51_04 | ParapetCladding | main building
A-ZeeProfile01 | ParapetCladding :1,SHE_DRAWING+SHEET.dgn,Design Model;14,SHE-08.ROOF.dgn ,Design Model:113312 | Pr_20_76_51_04 | ParapetCladding | main building
A-ZeeProfile01 | ParapetCladding :1,SHE_DRAWING+SHEET.dgn,Design Model;14,SHE-08.ROOF.dgn ,Design Model:113326 | Pr_20_76_51_04 | ParapetCladding | main building
A-ZeeProfile01 | ParapetCladding :1,SHE_DRAWING+SHEET.dgn,Design Model;14,SHE-08.ROOF.dgn ,Design Model:113340 | Pr_20_76_51_04 | ParapetCladding | main building
A-ZeeProfile01 | ParapetCladding :1,SHE_DRAWING+SHEET.dgn,Design Model;14,SHE-08.ROOF.dgn ,Design Model:113354 | Pr_20_76_51_04 | ParapetCladding | main building
A-ZeeProfile01 | ParapetCladding :1,SHE_DRAWING+SHEET.dgn,Design Model;14,SHE-08.ROOF.dgn ,Design Model:113368 | Pr_20_76_51_04 | ParapetCladding | main building
A-ZeeProfile01 | ParapetCladding :1,SHE_DRAWING+SHEET.dgn,Design Model;14,SHE-08.ROOF.dgn ,Design Model:113382 | Pr_20_76_51_04 | ParapetCladding | main building
A-ZeeProfile01 | ParapetCladding :1,SHE_DRAWING+SHEET.dgn,Design Model;14,SHE-08.ROOF.dgn ,Design Model:113396 | Pr_20_76_51_04 | ParapetCladding | main building
A-ZeeProfile01 | ParapetCladding :1,SHE_DRAWING+SHEET.dgn,Design Model;14,SHE-08.ROOF.dgn ,Design Model:113410 | Pr_20_76_51_04 | ParapetCladding | main building
A-ZeeProfile01 | ParapetCladding :1,SHE_DRAWING+SHEET.dgn,Design Model;14,SHE-08.ROOF.dgn ,Design Model:113424 | Pr_20_76_51_04 | ParapetCladding | main building
A-ZeeProfile01 | ParapetCladding :1,SHE_DRAWING+SHEET.dgn,Design Model;14,SHE-08.ROOF.dgn ,Design Model:113438 | Pr_20_76_51_04 | ParapetCladding | main building
A-ZeeProfile01 | ParapetCladding :1,SHE_DRAWING+SHEET.dgn,Design Model;14,SHE-08.ROOF.dgn ,Design Model:113452 | Pr_20_76_51_04 | ParapetCladding | main building
A-ZeeProfile01 | ParapetCladding :1,SHE_DRAWING+SHEET.dgn,Design Model;14,SHE-08.ROOF.dgn ,Design Model:113466 | Pr_20_76_51_04 | ParapetCladding | main building
A-ZeeProfile01 | ParapetCladding :1,SHE_DRAWING+SHEET.dgn,Design Model;14,SHE-08.ROOF.dgn ,Design Model:113480 | Pr_20_76_51_04 | ParapetCladding | main building
A-ZeeProfile01 | ParapetCladding :1,SHE_DRAWING+SHEET.dgn,Design Model;14,SHE-08.ROOF.dgn ,Design Model:113494 | Pr_20_76_51_04 | ParapetCladding | main building
A-ZeeProfile01 | ParapetCladding :1,SHE_DRAWING+SHEET.dgn,Design Model;14,SHE-08.ROOF.dgn ,Design Model:113508 | Pr_20_76_51_04 | ParapetCladding | main building
A-ZeeProfile01 | ParapetCladding :1,SHE_DRAWING+SHEET.dgn,Design Model;14,SHE-08.ROOF.dgn ,Design Model:113522 | Pr_20_76_51_04 | ParapetCladding | main building
A-ZeeProfile01 | ParapetCladding :1,SHE_DRAWING+SHEET.dgn,Design Model;14,SHE-08.ROOF.dgn ,Design Model:113536 | Pr_20_76_51_04 | ParapetCladding | main building
A-ZeeProfile01 | ParapetCladding :1,SHE_DRAWING+SHEET.dgn,Design Model;14,SHE-08.ROOF.dgn ,Design Model:113550 | Pr_20_76_51_04 | ParapetCladding | main building
A-ZeeProfile01 | ParapetCladding :1,SHE_DRAWING+SHEET.dgn,Design Model;14,SHE-08.ROOF.dgn ,Design Model:113564 | Pr_20_76_51_04 | ParapetCladding | main building

# IfcSlab: A-Finishes A_BSUK_Carpet-Pile (19)
In: RL
Type - PredefinedType: FLOOR
Type - Thermal Transmittance - Is External: no; Is Below Grade: no
Type - Space Bounding - Is Space Bounding: yes
Type - Materials - Part Definition: A-Finishes::A_BSUK_Carpet-Pile
Type - Fire Resistance - Fire | IsCombustible: no; Fire | Compartmentation: no
Type - Classification - Uniclass2015: Pr_35_57_11
Material: A_BSUK_Carpet-Pile
Name | Description
A-Finishes A_BSUK_Carpet-Pile | 1 ,SHE_DRAWING+SHEET.dgn,Design Model;7,SHE-06.FOURTH.dgn,Design Model:272815
A-Finishes A_BSUK_Carpet-Pile | 1 ,SHE_DRAWING+SHEET.dgn,Design Model;7,SHE-06.FOURTH.dgn,Design Model:272848
A-Finishes A_BSUK_Carpet-Pile | 1 ,SHE_DRAWING+SHEET.dgn,Design Model;7,SHE-06.FOURTH.dgn,Design Model:272875
A-Finishes A_BSUK_Carpet-Pile | 1 ,SHE_DRAWING+SHEET.dgn,Design Model;7,SHE-06.FOURTH.dgn,Design Model:272902
A-Finishes A_BSUK_Carpet-Pile | 1 ,SHE_DRAWING+SHEET.dgn,Design Model;7,SHE-06.FOURTH.dgn,Design Model:272947
A-Finishes A_BSUK_Carpet-Pile | 1 ,SHE_DRAWING+SHEET.dgn,Design Model;7,SHE-06.FOURTH.dgn,Design Model:272986
A-Finishes A_BSUK_Carpet-Pile | 1 ,SHE_DRAWING+SHEET.dgn,Design Model;7,SHE-06.FOURTH.dgn,Design Model:273013
A-Finishes A_BSUK_Carpet-Pile | 1 ,SHE_DRAWING+SHEET.dgn,Design Model;7,SHE-06.FOURTH.dgn,Design Model:273040
A-Finishes A_BSUK_Carpet-Pile | 1 ,SHE_DRAWING+SHEET.dgn,Design Model;7,SHE-06.FOURTH.dgn,Design Model:273085
A-Finishes A_BSUK_Carpet-Pile | 1 ,SHE_DRAWING+SHEET.dgn,Design Model;7,SHE-06.FOURTH.dgn,Design Model:273118
A-Finishes A_BSUK_Carpet-Pile | 1 ,SHE_DRAWING+SHEET.dgn,Design Model;7,SHE-06.FOURTH.dgn,Design Model:273145
A-Finishes A_BSUK_Carpet-Pile | 1 ,SHE_DRAWING+SHEET.dgn,Design Model;7,SHE-06.FOURTH.dgn,Design Model:273178
A-Finishes A_BSUK_Carpet-Pile | 1 ,SHE_DRAWING+SHEET.dgn,Design Model;7,SHE-06.FOURTH.dgn,Design Model:273211
A-Finishes A_BSUK_Carpet-Pile | 1 ,SHE_DRAWING+SHEET.dgn,Design Model;7,SHE-06.FOURTH.dgn,Design Model:273244
A-Finishes A_BSUK_Carpet-Pile | 1 ,SHE_DRAWING+SHEET.dgn,Design Model;7,SHE-06.FOURTH.dgn,Design Model:273424
A-Finishes A_BSUK_Carpet-Pile | 1 ,SHE_DRAWING+SHEET.dgn,Design Model;7,SHE-06.FOURTH.dgn,Design Model:273499
A-Finishes A_BSUK_Carpet-Pile | 1 ,SHE_DRAWING+SHEET.dgn,Design Model;7,SHE-06.FOURTH.dgn,Design Model:273601
A-Finishes A_BSUK_Carpet-Pile | 1 ,SHE_DRAWING+SHEET.dgn,Design Model;7,SHE-06.FOURTH.dgn,Design Model:273664
A-Finishes A_BSUK_Carpet-Pile | 1 ,SHE_DRAWING+SHEET.dgn,Design Model;7,SHE-06.FOURTH.dgn,Design Model:273691

# IfcSlab: A-Finishes A_BSUK_Ceramic_FloorTiles (11)
In: RL
Type - PredefinedType: FLOOR
Type - Thermal Transmittance - Is External: no; Is Below Grade: no
Type - Space Bounding - Is Space Bounding: yes
Type - Materials - Part Definition: A-Finishes::A_BSUK_Ceramic_FloorTiles
Type - Fire Resistance - Fire | IsCombustible: no; Fire | Compartmentation: no
Type - Classification - Uniclass2015: Pr_35_93_96
Material: A_BSUK_Ceramic_FloorTiles
Name | Description
A-Finishes A_BSUK_Ceramic_FloorTiles | 1,SHE_DRAWING+SHEET.dgn,Design Model;1 ,SHE-01.GROUND.dgn,Design Model:155307
A-Finishes A_BSUK_Ceramic_FloorTiles | 1,SHE_DRAWING+SHEET.dgn,Design Model;1 ,SHE-01.GROUND.dgn,Design Model:155662
A-Finishes A_BSUK_Ceramic_FloorTiles | 1,SHE_DRAWING+SHEET.dgn,Design Model;1 ,SHE-01.GROUND.dgn,Design Model:183812
A-Finishes A_BSUK_Ceramic_FloorTiles | 1,SHE_DRAWING+SHEET.dgn,Design Model;7 ,SHE-06.FOURTH.dgn,Design Model:273277
A-Finishes A_BSUK_Ceramic_FloorTiles | 1,SHE_DRAWING+SHEET.dgn,Design Model;7 ,SHE-06.FOURTH.dgn,Design Model:273346
A-Finishes A_BSUK_Ceramic_FloorTiles | 1,SHE_DRAWING+SHEET.dgn,Design Model;7 ,SHE-06.FOURTH.dgn,Design Model:273439
A-Finishes A_BSUK_Ceramic_FloorTiles | 1,SHE_DRAWING+SHEET.dgn,Design Model;7 ,SHE-06.FOURTH.dgn,Design Model:273457
A-Finishes A_BSUK_Ceramic_FloorTiles | 1,SHE_DRAWING+SHEET.dgn,Design Model;7 ,SHE-06.FOURTH.dgn,Design Model:273547
A-Finishes A_BSUK_Ceramic_FloorTiles | 1,SHE_DRAWING+SHEET.dgn,Design Model;7 ,SHE-06.FOURTH.dgn,Design Model:273574
A-Finishes A_BSUK_Ceramic_FloorTiles | 1,SHE_DRAWING+SHEET.dgn,Design Model;7 ,SHE-06.FOURTH.dgn,Design Model:273643
A-Finishes A_BSUK_Ceramic_FloorTiles | 1,SHE_DRAWING+SHEET.dgn,Design Model;7 ,SHE-06.FOURTH.dgn,Design Model:273712

# IfcSlab: A-FloorsSlabs A_BSUK_ExpandedPolystyreneBoards (87)
In: RL
Type - PredefinedType: FLOOR
Type - Thermal Transmittance - Is External: no; Is Below Grade: no
Type - Space Bounding - Is Space Bounding: yes
Type - Materials - Part Definition: A-FloorsSlabs::A_BSUK_ExpandedPolystyreneBoards
Type - Fire Resistance - Fire | IsCombustible: no; Fire | Compartmentation: no
Type - Classification - Uniclass2015: Pr_25_71_63_26
Material: A_BSUK_ExpandedPolystyreneBoards
Name | Description
A-FloorsSlabs A_BSUK_ExpandedPolystyreneBoards | 1,SHE_DRAWING+SHEET.dgn ,Design Model;1,SHE-01.GROUND.dgn,Design Model:189262
A-FloorsSlabs A_BSUK_ExpandedPolystyreneBoards | 1,SHE_DRAWING+SHEET.dgn ,Design Model;1,SHE-01.GROUND.dgn,Design Model:189322
A-FloorsSlabs A_BSUK_ExpandedPolystyreneBoards | 1,SHE_DRAWING+SHEET.dgn ,Design Model;1,SHE-01.GROUND.dgn,Design Model:189323
A-FloorsSlabs A_BSUK_ExpandedPolystyreneBoards | 1,SHE_DRAWING+SHEET.dgn ,Design Model;1,SHE-01.GROUND.dgn,Design Model:189785
A-FloorsSlabs A_BSUK_ExpandedPolystyreneBoards | 1,SHE_DRAWING+SHEET.dgn ,Design Model;1,SHE-01.GROUND.dgn,Design Model:189813
A-FloorsSlabs A_BSUK_ExpandedPolystyreneBoards | 1,SHE_DRAWING+SHEET.dgn ,Design Model;1,SHE-01.GROUND.dgn,Design Model:235851
A-FloorsSlabs A_BSUK_ExpandedPolystyreneBoards | 1,SHE_DRAWING+SHEET.dgn ,Design Model;1,SHE-01.GROUND.dgn,Design Model:237555
A-FloorsSlabs A_BSUK_ExpandedPolystyreneBoards | 1,SHE_DRAWING+SHEET.dgn ,Design Model;1,SHE-01.GROUND.dgn,Design Model:239339
A-FloorsSlabs A_BSUK_ExpandedPolystyreneBoards | 1,SHE_DRAWING+SHEET.dgn ,Design Model;1,SHE-01.GROUND.dgn,Design Model:239340
A-FloorsSlabs A_BSUK_ExpandedPolystyreneBoards | 1,SHE_DRAWING+SHEET.dgn ,Design Model;1,SHE-01.GROUND.dgn,Design Model:239341
A-FloorsSlabs A_BSUK_ExpandedPolystyreneBoards | 1,SHE_DRAWING+SHEET.dgn ,Design Model;1,SHE-01.GROUND.dgn,Design Model:239342
A-FloorsSlabs A_BSUK_ExpandedPolystyreneBoards | 1,SHE_DRAWING+SHEET.dgn ,Design Model;4,SHE-03.FIRST.dgn,Design Model:414607
A-FloorsSlabs A_BSUK_ExpandedPolystyreneBoards | 1,SHE_DRAWING+SHEET.dgn ,Design Model;4,SHE-03.FIRST.dgn,Design Model:414608
A-FloorsSlabs A_BSUK_ExpandedPolystyreneBoards | 1,SHE_DRAWING+SHEET.dgn ,Design Model;4,SHE-03.FIRST.dgn,Design Model:414609
A-FloorsSlabs A_BSUK_ExpandedPolystyreneBoards | 1,SHE_DRAWING+SHEET.dgn ,Design Model;4,SHE-03.FIRST.dgn,Design Model:414610
A-FloorsSlabs A_BSUK_ExpandedPolystyreneBoards | 1,SHE_DRAWING+SHEET.dgn ,Design Model;4,SHE-03.FIRST.dgn,Design Model:414611
A-FloorsSlabs A_BSUK_ExpandedPolystyreneBoards | 1,SHE_DRAWING+SHEET.dgn ,Design Model;4,SHE-03.FIRST.dgn,Design Model:414612
A-FloorsSlabs A_BSUK_ExpandedPolystyreneBoards | 1,SHE_DRAWING+SHEET.dgn ,Design Model;4,SHE-03.FIRST.dgn,Design Model:414613
A-FloorsSlabs A_BSUK_ExpandedPolystyreneBoards | 1,SHE_DRAWING+SHEET.dgn ,Design Model;4,SHE-03.FIRST.dgn,Design Model:414614
A-FloorsSlabs A_BSUK_ExpandedPolystyreneBoards | 1,SHE_DRAWING+SHEET.dgn ,Design Model;4,SHE-03.FIRST.dgn,Design Model:414615
A-FloorsSlabs A_BSUK_ExpandedPolystyreneBoards | 1,SHE_DRAWING+SHEET.dgn ,Design Model;4,SHE-03.FIRST.dgn,Design Model:414616
A-FloorsSlabs A_BSUK_ExpandedPolystyreneBoards | 1,SHE_DRAWING+SHEET.dgn ,Design Model;4,SHE-03.FIRST.dgn,Design Model:414617
A-FloorsSlabs A_BSUK_ExpandedPolystyreneBoards | 1,SHE_DRAWING+SHEET.dgn ,Design Model;4,SHE-03.FIRST.dgn,Design Model:414618
A-FloorsSlabs A_BSUK_ExpandedPolystyreneBoards | 1,SHE_DRAWING+SHEET.dgn ,Design Model;4,SHE-03.FIRST.dgn,Design Model:414619
A-FloorsSlabs A_BSUK_ExpandedPolystyreneBoards | 1,SHE_DRAWING+SHEET.dgn ,Design Model;4,SHE-03.FIRST.dgn,Design Model:414620
A-FloorsSlabs A_BSUK_ExpandedPolystyreneBoards | 1,SHE_DRAWING+SHEET.dgn ,Design Model;4,SHE-03.FIRST.dgn,Design Model:414621
A-FloorsSlabs A_BSUK_ExpandedPolystyreneBoards | 1,SHE_DRAWING+SHEET.dgn ,Design Model;4,SHE-03.FIRST.dgn,Design Model:414622
A-FloorsSlabs A_BSUK_ExpandedPolystyreneBoards | 1,SHE_DRAWING+SHEET.dgn ,Design Model;4,SHE-03.FIRST.dgn,Design Model:414623
A-FloorsSlabs A_BSUK_ExpandedPolystyreneBoards | 1,SHE_DRAWING+SHEET.dgn ,Design Model;4,SHE-03.FIRST.dgn,Design Model:414624
A-FloorsSlabs A_BSUK_ExpandedPolystyreneBoards | 1,SHE_DRAWING+SHEET.dgn ,Design Model;4,SHE-03.FIRST.dgn,Design Model:414625
A-FloorsSlabs A_BSUK_ExpandedPolystyreneBoards | 1,SHE_DRAWING+SHEET.dgn ,Design Model;4,SHE-03.FIRST.dgn,Design Model:414626
A-FloorsSlabs A_BSUK_ExpandedPolystyreneBoards | 1,SHE_DRAWING+SHEET.dgn ,Design Model;4,SHE-03.FIRST.dgn,Design Model:415567
A-FloorsSlabs A_BSUK_ExpandedPolystyreneBoards | 1,SHE_DRAWING+SHEET.dgn ,Design Model;4,SHE-03.FIRST.dgn,Design Model:415642
A-FloorsSlabs A_BSUK_ExpandedPolystyreneBoards | 1,SHE_DRAWING+SHEET.dgn ,Design Model;4,SHE-03.FIRST.dgn,Design Model:415643
A-FloorsSlabs A_BSUK_ExpandedPolystyreneBoards | 1,SHE_DRAWING+SHEET.dgn ,Design Model;6,SHE-05.THIRD.dgn,Design Model:134765
A-FloorsSlabs A_BSUK_ExpandedPolystyreneBoards | 1,SHE_DRAWING+SHEET.dgn ,Design Model;6,SHE-05.THIRD.dgn,Design Model:134792
A-FloorsSlabs A_BSUK_ExpandedPolystyreneBoards | 1,SHE_DRAWING+SHEET.dgn ,Design Model;6,SHE-05.THIRD.dgn,Design Model:134816
A-FloorsSlabs A_BSUK_ExpandedPolystyreneBoards | 1,SHE_DRAWING+SHEET.dgn ,Design Model;6,SHE-05.THIRD.dgn,Design Model:154694
A-FloorsSlabs A_BSUK_ExpandedPolystyreneBoards | 1,SHE_DRAWING+SHEET.dgn ,Design Model;6,SHE-05.THIRD.dgn,Design Model:154742
A-FloorsSlabs A_BSUK_ExpandedPolystyreneBoards | 1,SHE_DRAWING+SHEET.dgn ,Design Model;6,SHE-05.THIRD.dgn,Design Model:155063
A-FloorsSlabs A_BSUK_ExpandedPolystyreneBoards | 1,SHE_DRAWING+SHEET.dgn ,Design Model;6,SHE-05.THIRD.dgn,Design Model:155064
A-FloorsSlabs A_BSUK_ExpandedPolystyreneBoards | 1,SHE_DRAWING+SHEET.dgn ,Design Model;6,SHE-05.THIRD.dgn,Design Model:155065
A-FloorsSlabs A_BSUK_ExpandedPolystyreneBoards | 1,SHE_DRAWING+SHEET.dgn ,Design Model;6,SHE-05.THIRD.dgn,Design Model:155066
A-FloorsSlabs A_BSUK_ExpandedPolystyreneBoards | 1,SHE_DRAWING+SHEET.dgn ,Design Model;6,SHE-05.THIRD.dgn,Design Model:155067
A-FloorsSlabs A_BSUK_ExpandedPolystyreneBoards | 1,SHE_DRAWING+SHEET.dgn ,Design Model;6,SHE-05.THIRD.dgn,Design Model:155068
A-FloorsSlabs A_BSUK_ExpandedPolystyreneBoards | 1,SHE_DRAWING+SHEET.dgn ,Design Model;6,SHE-05.THIRD.dgn,Design Model:155069
A-FloorsSlabs A_BSUK_ExpandedPolystyreneBoards | 1,SHE_DRAWING+SHEET.dgn ,Design Model;6,SHE-05.THIRD.dgn,Design Model:155084
A-FloorsSlabs A_BSUK_ExpandedPolystyreneBoards | 1,SHE_DRAWING+SHEET.dgn ,Design Model;6,SHE-05.THIRD.dgn,Design Model:155099
A-FloorsSlabs A_BSUK_ExpandedPolystyreneBoards | 1,SHE_DRAWING+SHEET.dgn ,Design Model;6,SHE-05.THIRD.dgn,Design Model:155370
A-FloorsSlabs A_BSUK_ExpandedPolystyreneBoards | 1,SHE_DRAWING+SHEET.dgn ,Design Model;6,SHE-05.THIRD.dgn,Design Model:155371
A-FloorsSlabs A_BSUK_ExpandedPolystyreneBoards | 1,SHE_DRAWING+SHEET.dgn ,Design Model;6,SHE-05.THIRD.dgn,Design Model:155619
A-FloorsSlabs A_BSUK_ExpandedPolystyreneBoards | 1,SHE_DRAWING+SHEET.dgn ,Design Model;6,SHE-05.THIRD.dgn,Design Model:155620
A-FloorsSlabs A_BSUK_ExpandedPolystyreneBoards | 1,SHE_DRAWING+SHEET.dgn ,Design Model;6,SHE-05.THIRD.dgn,Design Model:155621
A-FloorsSlabs A_BSUK_ExpandedPolystyreneBoards | 1,SHE_DRAWING+SHEET.dgn ,Design Model;6,SHE-05.THIRD.dgn,Design Model:155622
A-FloorsSlabs A_BSUK_ExpandedPolystyreneBoards | 1,SHE_DRAWING+SHEET.dgn ,Design Model;6,SHE-05.THIRD.dgn,Design Model:155623
A-FloorsSlabs A_BSUK_ExpandedPolystyreneBoards | 1,SHE_DRAWING+SHEET.dgn ,Design Model;6,SHE-05.THIRD.dgn,Design Model:155624
A-FloorsSlabs A_BSUK_ExpandedPolystyreneBoards | 1,SHE_DRAWING+SHEET.dgn ,Design Model;6,SHE-05.THIRD.dgn,Design Model:155626
A-FloorsSlabs A_BSUK_ExpandedPolystyreneBoards | 1,SHE_DRAWING+SHEET.dgn ,Design Model;6,SHE-05.THIRD.dgn,Design Model:220881
A-FloorsSlabs A_BSUK_ExpandedPolystyreneBoards | 1,SHE_DRAWING+SHEET.dgn ,Design Model;6,SHE-05.THIRD.dgn,Design Model:220882
A-FloorsSlabs A_BSUK_ExpandedPolystyreneBoards | 1,SHE_DRAWING+SHEET.dgn ,Design Model;6,SHE-05.THIRD.dgn,Design Model:220883
A-FloorsSlabs A_BSUK_ExpandedPolystyreneBoards | 1,SHE_DRAWING+SHEET.dgn ,Design Model;7,SHE-06.FOURTH.dgn,Design Model:473652
A-FloorsSlabs A_BSUK_ExpandedPolystyreneBoards | 1,SHE_DRAWING+SHEET.dgn ,Design Model;7,SHE-06.FOURTH.dgn,Design Model:489978
A-FloorsSlabs A_BSUK_ExpandedPolystyreneBoards | 1,SHE_DRAWING+SHEET.dgn ,Design Model;7,SHE-06.FOURTH.dgn,Design Model:491292
A-FloorsSlabs A_BSUK_ExpandedPolystyreneBoards | 1,SHE_DRAWING+SHEET.dgn ,Design Model;7,SHE-06.FOURTH.dgn,Design Model:492620
A-FloorsSlabs A_BSUK_ExpandedPolystyreneBoards | 1,SHE_DRAWING+SHEET.dgn ,Design Model;18,SHE-04.SECOND.dgn,Design Model:389771
A-FloorsSlabs A_BSUK_ExpandedPolystyreneBoards | 1,SHE_DRAWING+SHEET.dgn ,Design Model;18,SHE-04.SECOND.dgn,Design Model:389772
A-FloorsSlabs A_BSUK_ExpandedPolystyreneBoards | 1,SHE_DRAWING+SHEET.dgn ,Design Model;18,SHE-04.SECOND.dgn,Design Model:389773
A-FloorsSlabs A_BSUK_ExpandedPolystyreneBoards | 1,SHE_DRAWING+SHEET.dgn ,Design Model;18,SHE-04.SECOND.dgn,Design Model:389774
A-FloorsSlabs A_BSUK_ExpandedPolystyreneBoards | 1,SHE_DRAWING+SHEET.dgn ,Design Model;18,SHE-04.SECOND.dgn,Design Model:389775
A-FloorsSlabs A_BSUK_ExpandedPolystyreneBoards | 1,SHE_DRAWING+SHEET.dgn ,Design Model;18,SHE-04.SECOND.dgn,Design Model:389776
A-FloorsSlabs A_BSUK_ExpandedPolystyreneBoards | 1,SHE_DRAWING+SHEET.dgn ,Design Model;18,SHE-04.SECOND.dgn,Design Model:389777
A-FloorsSlabs A_BSUK_ExpandedPolystyreneBoards | 1,SHE_DRAWING+SHEET.dgn ,Design Model;18,SHE-04.SECOND.dgn,Design Model:389778
A-FloorsSlabs A_BSUK_ExpandedPolystyreneBoards | 1,SHE_DRAWING+SHEET.dgn ,Design Model;18,SHE-04.SECOND.dgn,Design Model:389779
A-FloorsSlabs A_BSUK_ExpandedPolystyreneBoards | 1,SHE_DRAWING+SHEET.dgn ,Design Model;18,SHE-04.SECOND.dgn,Design Model:389780
A-FloorsSlabs A_BSUK_ExpandedPolystyreneBoards | 1,SHE_DRAWING+SHEET.dgn ,Design Model;18,SHE-04.SECOND.dgn,Design Model:389781
A-FloorsSlabs A_BSUK_ExpandedPolystyreneBoards | 1,SHE_DRAWING+SHEET.dgn ,Design Model;18,SHE-04.SECOND.dgn,Design Model:389782
A-FloorsSlabs A_BSUK_ExpandedPolystyreneBoards | 1,SHE_DRAWING+SHEET.dgn ,Design Model;18,SHE-04.SECOND.dgn,Design Model:389783
A-FloorsSlabs A_BSUK_ExpandedPolystyreneBoards | 1,SHE_DRAWING+SHEET.dgn ,Design Model;18,SHE-04.SECOND.dgn,Design Model:389784
A-FloorsSlabs A_BSUK_ExpandedPolystyreneBoards | 1,SHE_DRAWING+SHEET.dgn ,Design Model;18,SHE-04.SECOND.dgn,Design Model:389785
A-FloorsSlabs A_BSUK_ExpandedPolystyreneBoards | 1,SHE_DRAWING+SHEET.dgn ,Design Model;18,SHE-04.SECOND.dgn,Design Model:389786
A-FloorsSlabs A_BSUK_ExpandedPolystyreneBoards | 1,SHE_DRAWING+SHEET.dgn ,Design Model;18,SHE-04.SECOND.dgn,Design Model:389787
A-FloorsSlabs A_BSUK_ExpandedPolystyreneBoards | 1,SHE_DRAWING+SHEET.dgn ,Design Model;18,SHE-04.SECOND.dgn,Design Model:389788
A-FloorsSlabs A_BSUK_ExpandedPolystyreneBoards | 1,SHE_DRAWING+SHEET.dgn ,Design Model;18,SHE-04.SECOND.dgn,Design Model:389789
A-FloorsSlabs A_BSUK_ExpandedPolystyreneBoards | 1,SHE_DRAWING+SHEET.dgn ,Design Model;18,SHE-04.SECOND.dgn,Design Model:389790
A-FloorsSlabs A_BSUK_ExpandedPolystyreneBoards | 1,SHE_DRAWING+SHEET.dgn ,Design Model;18,SHE-04.SECOND.dgn,Design Model:389814
A-FloorsSlabs A_BSUK_ExpandedPolystyreneBoards | 1,SHE_DRAWING+SHEET.dgn ,Design Model;18,SHE-04.SECOND.dgn,Design Model:389867
A-FloorsSlabs A_BSUK_ExpandedPolystyreneBoards | 1,SHE_DRAWING+SHEET.dgn ,Design Model;18,SHE-04.SECOND.dgn,Design Model:389868

# IfcSlab: A-FloorsSlabs A_BSUK_InternalFinishes_FloorScreed (5)
In: RL
Type - PredefinedType: FLOOR
Type - Thermal Transmittance - Is External: no; Is Below Grade: no
Type - Space Bounding - Is Space Bounding: yes
Type - Materials - Part Definition: A-FloorsSlabs::A_BSUK_InternalFinishes_FloorScreed
Type - Fire Resistance - Fire | IsCombustible: no; Fire | Compartmentation: no
Type - Classification - Uniclass2015: Pr_35_31_06_29
Material: A_BSUK_InternalFinishes_FloorScreed
Name | Description
A-FloorsSlabs A_BSUK_InternalFinishes_FloorScreed | 1,SHE_DRAWING+SHEET.dgn ,Design Model;7,SHE-06.FOURTH.dgn,Design Model:273307
A-FloorsSlabs A_BSUK_InternalFinishes_FloorScreed | 1,SHE_DRAWING+SHEET.dgn ,Design Model;7,SHE-06.FOURTH.dgn,Design Model:273385
A-FloorsSlabs A_BSUK_InternalFinishes_FloorScreed | 1,SHE_DRAWING+SHEET.dgn ,Design Model;7,SHE-06.FOURTH.dgn,Design Model:277592
A-FloorsSlabs A_BSUK_InternalFinishes_FloorScreed | 1,SHE_DRAWING+SHEET.dgn ,Design Model;7,SHE-06.FOURTH.dgn,Design Model:315857
A-FloorsSlabs A_BSUK_InternalFinishes_FloorScreed | 1,SHE_DRAWING+SHEET.dgn ,Design Model;7,SHE-06.FOURTH.dgn,Design Model:319650

# IfcSlab: A-FloorsSlabs A_BSUK_Slabs (1241)
Type - PredefinedType: FLOOR
Type - Thermal Transmittance - Is External: no; Is Below Grade: no
Type - Space Bounding - Is Space Bounding: yes
Type - Materials - Part Definition: A-FloorsSlabs::A_BSUK_Slabs
Type - Fire Resistance - Fire | IsCombustible: no; Fire | Compartmentation: no
Type - Classification - Uniclass2015: Ss_30_12_85_18
Name | In | Description | Material | Phase | Part Definition
A-FloorsSlabs A_BSUK_Slabs | RL | 1 ,SHE_DRAWING+SHEET.dgn,Design Model;1,SHE-01.GROUND.dgn,Design Model:90221 | A_BSUK_Slabs | Existing to Remain
A-FloorsSlabs A_BSUK_Slabs | RL | 1 ,SHE_DRAWING+SHEET.dgn,Design Model;1,SHE-01.GROUND.dgn,Design Model:90223 | A_BSUK_Slabs
A-FloorsSlabs A_BSUK_Slabs | RL | 1 ,SHE_DRAWING+SHEET.dgn,Design Model;1,SHE-01.GROUND.dgn,Design Model:90224 | A_BSUK_Slabs | Existing to Remain
A-FloorsSlabs A_BSUK_Slabs | RL | 1 ,SHE_DRAWING+SHEET.dgn,Design Model;1,SHE-01.GROUND.dgn,Design Model:90225 | A_BSUK_Slabs
A-FloorsSlabs A_BSUK_Slabs | RL | 1 ,SHE_DRAWING+SHEET.dgn,Design Model;1,SHE-01.GROUND.dgn,Design Model:90226 | A_BSUK_Slabs | Existing to Remain
A-FloorsSlabs A_BSUK_Slabs | RL | 1 ,SHE_DRAWING+SHEET.dgn,Design Model;1,SHE-01.GROUND.dgn,Design Model:90227 | A_BSUK_Slabs | Existing to Remain
A-FloorsSlabs A_BSUK_Slabs | RL | 1 ,SHE_DRAWING+SHEET.dgn,Design Model;1,SHE-01.GROUND.dgn,Design Model:90229 | A_BSUK_Slabs
A-FloorsSlabs A_BSUK_Slabs | RL | 1 ,SHE_DRAWING+SHEET.dgn,Design Model;1,SHE-01.GROUND.dgn,Design Model:90231 | A_BSUK_Slabs | Existing to Remain
A-FloorsSlabs A_BSUK_Slabs | RL | 1 ,SHE_DRAWING+SHEET.dgn,Design Model;1,SHE-01.GROUND.dgn,Design Model:90232 | A_BSUK_Slabs | Existing to Remain
A-FloorsSlabs A_BSUK_Slabs | RL | window sill - timber :1,SHE_DRAWING+SHEET.dgn,Design Model;1 ,SHE-01.GROUND.dgn,Design Model:90233 | A_BSUK_Slabs | Existing to Remain | Identification - ID | Description: window sill - timber
A-FloorsSlabs A_BSUK_Slabs | RL | window sill - timber :1,SHE_DRAWING+SHEET.dgn,Design Model;1 ,SHE-01.GROUND.dgn,Design Model:90234 | A_BSUK_Slabs | Existing to Remain | Identification - ID | Description: window sill - timber
A-FloorsSlabs A_BSUK_Slabs | RL | 1 ,SHE_DRAWING+SHEET.dgn,Design Model;1,SHE-01.GROUND.dgn,Design Model:90235 | A_BSUK_Slabs | Existing to Remain
A-FloorsSlabs A_BSUK_Slabs | RL | 1 ,SHE_DRAWING+SHEET.dgn,Design Model;1,SHE-01.GROUND.dgn,Design Model:90236 | A_BSUK_Slabs | Existing to Remain
A-FloorsSlabs A_BSUK_Slabs | RL | 1 ,SHE_DRAWING+SHEET.dgn,Design Model;1,SHE-01.GROUND.dgn,Design Model:90237 | A_BSUK_Slabs | Existing to Remain
A-FloorsSlabs A_BSUK_Slabs | RL | 1 ,SHE_DRAWING+SHEET.dgn,Design Model;1,SHE-01.GROUND.dgn,Design Model:90238 | A_BSUK_Slabs | Existing to Remain
A-FloorsSlabs A_BSUK_Slabs | RL | window sill - timber :1,SHE_DRAWING+SHEET.dgn,Design Model;1 ,SHE-01.GROUND.dgn,Design Model:90239 | A_BSUK_Slabs | Existing to Remain | Identification - ID | Description: window sill - timber
A-FloorsSlabs A_BSUK_Slabs | RL | 1 ,SHE_DRAWING+SHEET.dgn,Design Model;1,SHE-01.GROUND.dgn,Design Model:90240 | A_BSUK_Slabs | Existing to Remain
A-FloorsSlabs A_BSUK_Slabs | RL | 1 ,SHE_DRAWING+SHEET.dgn,Design Model;1,SHE-01.GROUND.dgn,Design Model:90241 | A_BSUK_Slabs | Existing to Remain
A-FloorsSlabs A_BSUK_Slabs | RL | 1 ,SHE_DRAWING+SHEET.dgn,Design Model;1,SHE-01.GROUND.dgn,Design Model:90242 | A_BSUK_Slabs | Existing to Remain
A-FloorsSlabs A_BSUK_Slabs | RL | 1 ,SHE_DRAWING+SHEET.dgn,Design Model;1,SHE-01.GROUND.dgn,Design Model:90243 | A_BSUK_Slabs
A-FloorsSlabs A_BSUK_Slabs | RL | 1 ,SHE_DRAWING+SHEET.dgn,Design Model;1,SHE-01.GROUND.dgn,Design Model:90244 | A_BSUK_Slabs
A-FloorsSlabs A_BSUK_Slabs | RL | 1 ,SHE_DRAWING+SHEET.dgn,Design Model;1,SHE-01.GROUND.dgn,Design Model:90245 | A_BSUK_Slabs
A-FloorsSlabs A_BSUK_Slabs | RL | 1 ,SHE_DRAWING+SHEET.dgn,Design Model;1,SHE-01.GROUND.dgn,Design Model:90246 | A_BSUK_Slabs
A-FloorsSlabs A_BSUK_Slabs | RL | 1 ,SHE_DRAWING+SHEET.dgn,Design Model;1,SHE-01.GROUND.dgn,Design Model:90247 | A_BSUK_Slabs | Existing to Remain
A-FloorsSlabs A_BSUK_Slabs | RL | 1 ,SHE_DRAWING+SHEET.dgn,Design Model;1,SHE-01.GROUND.dgn,Design Model:90248 | A_BSUK_Slabs | Existing to Remain
A-FloorsSlabs A_BSUK_Slabs | RL | 1 ,SHE_DRAWING+SHEET.dgn,Design Model;1,SHE-01.GROUND.dgn,Design Model:90249 | A_BSUK_Slabs | Existing to Remain
A-FloorsSlabs A_BSUK_Slabs | RL | 1 ,SHE_DRAWING+SHEET.dgn,Design Model;1,SHE-01.GROUND.dgn,Design Model:90250 | A_BSUK_Slabs | Existing to Remain
A-FloorsSlabs A_BSUK_Slabs | RL | 1 ,SHE_DRAWING+SHEET.dgn,Design Model;1,SHE-01.GROUND.dgn,Design Model:90251 | A_BSUK_Slabs
A-FloorsSlabs A_BSUK_Slabs | RL | 1 ,SHE_DRAWING+SHEET.dgn,Design Model;1,SHE-01.GROUND.dgn,Design Model:118360 | A_BSUK_Slabs
A-FloorsSlabs A_BSUK_Slabs | RL | 1 ,SHE_DRAWING+SHEET.dgn,Design Model;1,SHE-01.GROUND.dgn,Design Model:118459 | A_BSUK_Slabs
A-FloorsSlabs A_BSUK_Slabs | RL | 1 ,SHE_DRAWING+SHEET.dgn,Design Model;1,SHE-01.GROUND.dgn,Design Model:118506 | A_BSUK_Slabs
A-FloorsSlabs A_BSUK_Slabs | RL | 1 ,SHE_DRAWING+SHEET.dgn,Design Model;1,SHE-01.GROUND.dgn,Design Model:118727 | A_BSUK_Slabs
A-FloorsSlabs A_BSUK_Slabs | RL | 1 ,SHE_DRAWING+SHEET.dgn,Design Model;1,SHE-01.GROUND.dgn,Design Model:123091 | A_BSUK_Slabs | Existing to Remain
A-FloorsSlabs A_BSUK_Slabs | RL | 1 ,SHE_DRAWING+SHEET.dgn,Design Model;1,SHE-01.GROUND.dgn,Design Model:155799 | A_BSUK_Ceramic_WallTiles | New Construction | A-Finishes::A_BSUK_Ceramic_WallTiles
A-FloorsSlabs A_BSUK_Slabs | RL | 1 ,SHE_DRAWING+SHEET.dgn,Design Model;1,SHE-01.GROUND.dgn,Design Model:155800 | A_BSUK_Ceramic_WallTiles | New Construction | A-Finishes::A_BSUK_Ceramic_WallTiles
A-FloorsSlabs A_BSUK_Slabs | RL | 1 ,SHE_DRAWING+SHEET.dgn,Design Model;1,SHE-01.GROUND.dgn,Design Model:155855 | A_BSUK_Ceramic_WallTiles | New Construction | A-Finishes::A_BSUK_Ceramic_WallTiles
A-FloorsSlabs A_BSUK_Slabs | RL | 1 ,SHE_DRAWING+SHEET.dgn,Design Model;1,SHE-01.GROUND.dgn,Design Model:155856 | A_BSUK_Ceramic_WallTiles | New Construction | A-Finishes::A_BSUK_Ceramic_WallTiles
A-FloorsSlabs A_BSUK_Slabs | RL | 1 ,SHE_DRAWING+SHEET.dgn,Design Model;1,SHE-01.GROUND.dgn,Design Model:180163 | A_BSUK_Slabs
A-FloorsSlabs A_BSUK_Slabs | RL | 1 ,SHE_DRAWING+SHEET.dgn,Design Model;1,SHE-01.GROUND.dgn,Design Model:180256 | A_BSUK_Slabs
A-FloorsSlabs A_BSUK_Slabs | RL | 1 ,SHE_DRAWING+SHEET.dgn,Design Model;1,SHE-01.GROUND.dgn,Design Model:180811 | A_BSUK_Ceramic_FloorTiles |  | A-Finishes::A_BSUK_Ceramic_FloorTiles
A-FloorsSlabs A_BSUK_Slabs | RL | 1 ,SHE_DRAWING+SHEET.dgn,Design Model;1,SHE-01.GROUND.dgn,Design Model:181088 | A_BSUK_Carpet-Pile |  | A-Finishes::A_BSUK_Carpet-Pile
A-FloorsSlabs A_BSUK_Slabs | RL | 1 ,SHE_DRAWING+SHEET.dgn,Design Model;1,SHE-01.GROUND.dgn,Design Model:182836 | A_BSUK_Parquet_Floor |  | A-Finishes::A_BSUK_Parquet_Floor
A-FloorsSlabs A_BSUK_Slabs | RL | 1 ,SHE_DRAWING+SHEET.dgn,Design Model;1,SHE-01.GROUND.dgn,Design Model:183841 | A_BSUK_Ceramic_WallTiles | New Construction | A-Finishes::A_BSUK_Ceramic_WallTiles
A-FloorsSlabs A_BSUK_Slabs | RL | 1 ,SHE_DRAWING+SHEET.dgn,Design Model;1,SHE-01.GROUND.dgn,Design Model:186951 | A_BSUK_CeilingSoffitFinishes_Suspended | New Construction | A-Ceilings::A_BSUK_CeilingSoffitFinishes_Suspended
A-FloorsSlabs A_BSUK_Slabs | RL | 1 ,SHE_DRAWING+SHEET.dgn,Design Model;1,SHE-01.GROUND.dgn,Design Model:188241 | A_BSUK_Timber_Miscellaneous | New Construction | A-FrameElements::A_BSUK_Timber_Miscellaneous
A-FloorsSlabs A_BSUK_Slabs | RL | 1 ,SHE_DRAWING+SHEET.dgn,Design Model;1,SHE-01.GROUND.dgn,Design Model:190233 | A_BSUK_Parquet_Floor | New Construction | A-Finishes::A_BSUK_Parquet_Floor
A-FloorsSlabs A_BSUK_Slabs | RL | 1 ,SHE_DRAWING+SHEET.dgn,Design Model;1,SHE-01.GROUND.dgn,Design Model:190248 | A_BSUK_Parquet_Floor | New Construction | A-Finishes::A_BSUK_Parquet_Floor
A-FloorsSlabs A_BSUK_Slabs | RL | plasterboard - ceiling :1,SHE_DRAWING+SHEET.dgn,Design Model;1 ,SHE-01.GROUND.dgn,Design Model:235747 | A_BSUK_Slabs | Existing to Remain | Identification - ID | Description: plasterboard - ceiling; ID | Notes: req. 60dB
A-FloorsSlabs A_BSUK_Slabs | RL | plasterboard - ceiling :1,SHE_DRAWING+SHEET.dgn,Design Model;1 ,SHE-01.GROUND.dgn,Design Model:235953 | A_BSUK_Slabs | Existing to Remain | Identification - ID | Description: plasterboard - ceiling; ID | Notes: req. 60dB
A-FloorsSlabs A_BSUK_Slabs | RL | plasterboard - ceiling :1,SHE_DRAWING+SHEET.dgn,Design Model;1 ,SHE-01.GROUND.dgn,Design Model:237528 | A_BSUK_Slabs | Existing to Remain | Identification - ID | Description: plasterboard - ceiling; ID | Notes: req. 60dB
A-FloorsSlabs A_BSUK_Slabs | RL | plasterboard - ceiling :1,SHE_DRAWING+SHEET.dgn,Design Model;1 ,SHE-01.GROUND.dgn,Design Model:237582 | A_BSUK_Slabs | Existing to Remain | Identification - ID | Description: plasterboard - ceiling; ID | Notes: req. 60dB
A-FloorsSlabs A_BSUK_Slabs | RL | plasterboard - ceiling :1,SHE_DRAWING+SHEET.dgn,Design Model;1 ,SHE-01.GROUND.dgn,Design Model:238977 | A_BSUK_CeilingSoffitFinishes_Suspended | New Construction | A-Ceilings::A_BSUK_CeilingSoffitFinishes_Suspended | Identification - ID | Description: plasterboard - ceiling
A-FloorsSlabs A_BSUK_Slabs | RL | plasterboard - ceiling :1,SHE_DRAWING+SHEET.dgn,Design Model;1 ,SHE-01.GROUND.dgn,Design Model:238978 | A_BSUK_CeilingSoffitFinishes_Suspended | New Construction | A-Ceilings::A_BSUK_CeilingSoffitFinishes_Suspended | Identification - ID | Description: plasterboard - ceiling
A-FloorsSlabs A_BSUK_Slabs | RL | plasterboard - ceiling :1,SHE_DRAWING+SHEET.dgn,Design Model;1 ,SHE-01.GROUND.dgn,Design Model:238979 | A_BSUK_CeilingSoffitFinishes_Suspended | New Construction | A-Ceilings::A_BSUK_CeilingSoffitFinishes_Suspended | Identification - ID | Description: plasterboard - ceiling
A-FloorsSlabs A_BSUK_Slabs | RL | plasterboard - ceiling :1,SHE_DRAWING+SHEET.dgn,Design Model;1 ,SHE-01.GROUND.dgn,Design Model:238980 | A_BSUK_CeilingSoffitFinishes_Suspended | New Construction | A-Ceilings::A_BSUK_CeilingSoffitFinishes_Suspended | Identification - ID | Description: plasterboard - ceiling
A-FloorsSlabs A_BSUK_Slabs | RL | 1 ,SHE_DRAWING+SHEET.dgn,Design Model;1,SHE-01.GROUND.dgn,Design Model:249470 | A_BSUK_Timber_Miscellaneous | New Construction | A-FrameElements::A_BSUK_Timber_Miscellaneous
A-FloorsSlabs A_BSUK_Slabs | RL | 1 ,SHE_DRAWING+SHEET.dgn,Design Model;1,SHE-01.GROUND.dgn,Design Model:249552 | A_BSUK_Timber_Miscellaneous | New Construction | A-FrameElements::A_BSUK_Timber_Miscellaneous
A-FloorsSlabs A_BSUK_Slabs | RL | 1 ,SHE_DRAWING+SHEET.dgn,Design Model;1,SHE-01.GROUND.dgn,Design Model:249580 | A_BSUK_Timber_Miscellaneous | New Construction | A-FrameElements::A_BSUK_Timber_Miscellaneous
A-FloorsSlabs A_BSUK_Slabs | RL | 1 ,SHE_DRAWING+SHEET.dgn,Design Model;1,SHE-01.GROUND.dgn,Design Model:249608 | A_BSUK_Timber_Miscellaneous | New Construction | A-FrameElements::A_BSUK_Timber_Miscellaneous
A-FloorsSlabs A_BSUK_Slabs | RL | 1 ,SHE_DRAWING+SHEET.dgn,Design Model;2,SHE-02.MEZZANINE.dgn,Design Model:90007 | A_BSUK_Slabs | Existing to Remain
A-FloorsSlabs A_BSUK_Slabs | RL | 1 ,SHE_DRAWING+SHEET.dgn,Design Model;2,SHE-02.MEZZANINE.dgn,Design Model:90008 | A_BSUK_Slabs | Existing to Remain
A-FloorsSlabs A_BSUK_Slabs | RL | 1 ,SHE_DRAWING+SHEET.dgn,Design Model;2,SHE-02.MEZZANINE.dgn,Design Model:90009 | A_BSUK_Slabs | Existing to Remain
A-FloorsSlabs A_BSUK_Slabs | RL | 1 ,SHE_DRAWING+SHEET.dgn,Design Model;2,SHE-02.MEZZANINE.dgn,Design Model:90010 | A_BSUK_Slabs | Existing to Remain
A-FloorsSlabs A_BSUK_Slabs | RL | 1 ,SHE_DRAWING+SHEET.dgn,Design Model;2,SHE-02.MEZZANINE.dgn,Design Model:90011 | A_BSUK_Slabs | Existing to Remain
A-FloorsSlabs A_BSUK_Slabs | RL | insulation - sound undercroft :1,SHE_DRAWING+SHEET.dgn,Design Model;2 ,SHE-02.MEZZANINE.dgn,Design Model:90018 | A_BSUK_ExpandedPolystyreneBoards | New Construction | A-FloorsSlabs::A_BSUK_ExpandedPolystyreneBoards | Identification - ID | Description: insulation - sound undercroft
A-FloorsSlabs A_BSUK_Slabs | RL | insulation - sound undercroft :1,SHE_DRAWING+SHEET.dgn,Design Model;2 ,SHE-02.MEZZANINE.dgn,Design Model:90019 | A_BSUK_ExpandedPolystyreneBoards | New Construction | A-FloorsSlabs::A_BSUK_ExpandedPolystyreneBoards | Identification - ID | Description: insulation - sound undercroft
A-FloorsSlabs A_BSUK_Slabs | RL | insulation - sound undercroft :1,SHE_DRAWING+SHEET.dgn,Design Model;2 ,SHE-02.MEZZANINE.dgn,Design Model:90020 | A_BSUK_ExpandedPolystyreneBoards | New Construction | A-FloorsSlabs::A_BSUK_ExpandedPolystyreneBoards | Identification - ID | Description: insulation - sound undercroft
A-FloorsSlabs A_BSUK_Slabs | RL | insulation - sound undercroft :1,SHE_DRAWING+SHEET.dgn,Design Model;2 ,SHE-02.MEZZANINE.dgn,Design Model:90021 | A_BSUK_ExpandedPolystyreneBoards | New Construction | A-FloorsSlabs::A_BSUK_ExpandedPolystyreneBoards | Identification - ID | Description: insulation - sound undercroft
A-FloorsSlabs A_BSUK_Slabs | RL | 1 ,SHE_DRAWING+SHEET.dgn,Design Model;2,SHE-02.MEZZANINE.dgn,Design Model:90026 | A_BSUK_Slabs | Existing to Remain
A-FloorsSlabs A_BSUK_Slabs | RL | 1 ,SHE_DRAWING+SHEET.dgn,Design Model;2,SHE-02.MEZZANINE.dgn,Design Model:90027 | A_BSUK_Slabs | Existing to Remain
A-FloorsSlabs A_BSUK_Slabs | RL | 1 ,SHE_DRAWING+SHEET.dgn,Design Model;2,SHE-02.MEZZANINE.dgn,Design Model:90028 | A_BSUK_Slabs | Existing to Remain
A-FloorsSlabs A_BSUK_Slabs | RL | 1 ,SHE_DRAWING+SHEET.dgn,Design Model;2,SHE-02.MEZZANINE.dgn,Design Model:90029 | A_BSUK_Slabs | Existing to Remain
A-FloorsSlabs A_BSUK_Slabs | RL | 1 ,SHE_DRAWING+SHEET.dgn,Design Model;2,SHE-02.MEZZANINE.dgn,Design Model:90030 | A_BSUK_Slabs | Existing to Remain
A-FloorsSlabs A_BSUK_Slabs | RL | 1 ,SHE_DRAWING+SHEET.dgn,Design Model;2,SHE-02.MEZZANINE.dgn,Design Model:111402 | A_BSUK_InternalFinishes_FloorScreed | Existing to Remain | A-FloorsSlabs::A_BSUK_InternalFinishes_FloorScreed
A-FloorsSlabs A_BSUK_Slabs | RL | 1 ,SHE_DRAWING+SHEET.dgn,Design Model;2,SHE-02.MEZZANINE.dgn,Design Model:111861 | A_BSUK_Parquet_Floor | New Construction | A-Finishes::A_BSUK_Parquet_Floor
A-FloorsSlabs A_BSUK_Slabs | RL | 1 ,SHE_DRAWING+SHEET.dgn,Design Model;2,SHE-02.MEZZANINE.dgn,Design Model:116897 | A_BSUK_Slabs | Existing to Remain
A-FloorsSlabs A_BSUK_Slabs | RL | 1 ,SHE_DRAWING+SHEET.dgn,Design Model;2,SHE-02.MEZZANINE.dgn,Design Model:117018 | A_BSUK_Slabs | Existing to Remain
A-FloorsSlabs A_BSUK_Slabs | RL | 1 ,SHE_DRAWING+SHEET.dgn,Design Model;2,SHE-02.MEZZANINE.dgn,Design Model:117055 | A_BSUK_Slabs | Existing to Remain
A-FloorsSlabs A_BSUK_Slabs | RL | 1 ,SHE_DRAWING+SHEET.dgn,Design Model;2,SHE-02.MEZZANINE.dgn,Design Model:117092 | A_BSUK_Slabs | Existing to Remain
A-FloorsSlabs A_BSUK_Slabs | RL | 1 ,SHE_DRAWING+SHEET.dgn,Design Model;2,SHE-02.MEZZANINE.dgn,Design Model:117258 | A_BSUK_Slabs | Existing to Remain
A-FloorsSlabs A_BSUK_Slabs | RL | insulation - sound undercroft :1,SHE_DRAWING+SHEET.dgn,Design Model;2 ,SHE-02.MEZZANINE.dgn,Design Model:119660 | A_BSUK_ExpandedPolystyreneBoards | New Construction | A-FloorsSlabs::A_BSUK_ExpandedPolystyreneBoards | Identification - ID | Description: insulation - sound undercroft
A-FloorsSlabs A_BSUK_Slabs | RL | 1 ,SHE_DRAWING+SHEET.dgn,Design Model;2,SHE-02.MEZZANINE.dgn,Design Model:127631 | A_BSUK_Ceramic_WallTiles |  | A-Finishes::A_BSUK_Ceramic_WallTiles
A-FloorsSlabs A_BSUK_Slabs | RL | 1 ,SHE_DRAWING+SHEET.dgn,Design Model;2,SHE-02.MEZZANINE.dgn,Design Model:127725 | A_BSUK_Ceramic_WallTiles |  | A-Finishes::A_BSUK_Ceramic_WallTiles
A-FloorsSlabs A_BSUK_Slabs | RL | 1 ,SHE_DRAWING+SHEET.dgn,Design Model;2,SHE-02.MEZZANINE.dgn,Design Model:145718 | A_BSUK_Carpet-Pile | New Construction | A-Finishes::A_BSUK_Carpet-Pile
A-FloorsSlabs A_BSUK_Slabs | RL | 1 ,SHE_DRAWING+SHEET.dgn,Design Model;2,SHE-02.MEZZANINE.dgn,Design Model:145759 | A_BSUK_Ceramic_FloorTiles | New Construction | A-Finishes::A_BSUK_Ceramic_FloorTiles
A-FloorsSlabs A_BSUK_Slabs | RL | 1 ,SHE_DRAWING+SHEET.dgn,Design Model;2,SHE-02.MEZZANINE.dgn,Design Model:148232 | A_BSUK_Timber_Miscellaneous |  | A-FrameElements::A_BSUK_Timber_Miscellaneous
A-FloorsSlabs A_BSUK_Slabs | RL | 1 ,SHE_DRAWING+SHEET.dgn,Design Model;2,SHE-02.MEZZANINE.dgn,Design Model:148352 | A_BSUK_Timber_Miscellaneous |  | A-FrameElements::A_BSUK_Timber_Miscellaneous
A-FloorsSlabs A_BSUK_Slabs | RL | 1 ,SHE_DRAWING+SHEET.dgn,Design Model;2,SHE-02.MEZZANINE.dgn,Design Model:148380 | A_BSUK_Timber_Miscellaneous |  | A-FrameElements::A_BSUK_Timber_Miscellaneous
A-FloorsSlabs A_BSUK_Slabs | RL | 1 ,SHE_DRAWING+SHEET.dgn,Design Model;2,SHE-02.MEZZANINE.dgn,Design Model:148421 | A_BSUK_Timber_Miscellaneous |  | A-FrameElements::A_BSUK_Timber_Miscellaneous
A-FloorsSlabs A_BSUK_Slabs | RL | 1 ,SHE_DRAWING+SHEET.dgn,Design Model;2,SHE-02.MEZZANINE.dgn,Design Model:148489 | A_BSUK_Timber_Miscellaneous |  | A-FrameElements::A_BSUK_Timber_Miscellaneous
A-FloorsSlabs A_BSUK_Slabs | RL | Celotex XR4000 :1,SHE_DRAWING+SHEET.dgn,Design Model;2,SHE-02.MEZZANINE.dgn ,Design Model:148568 | A_BSUK_Insulation | New Construction | A-Walls::A_BSUK_Insulation | Identification - ID | Description: Celotex XR4000
A-FloorsSlabs A_BSUK_Slabs | RL | Deck (PLY) :1,SHE_DRAWING+SHEET.dgn,Design Model;2,SHE-02.MEZZANINE.dgn ,Design Model:149582 | A_BSUK_Timber_Miscellaneous | New Construction | A-FrameElements::A_BSUK_Timber_Miscellaneous | Identification - ID | Description: Deck (PLY)
A-FloorsSlabs A_BSUK_Slabs | RL | single ply membrane or felt :1,SHE_DRAWING+SHEET.dgn,Design Model;2 ,SHE-02.MEZZANINE.dgn,Design Model:149695 | A_BSUK_Roofs | New Construction | A-Roofs::A_BSUK_Roofs | Identification - ID | Description: single ply membrane or felt
A-FloorsSlabs A_BSUK_Slabs | RL | 1 ,SHE_DRAWING+SHEET.dgn,Design Model;2,SHE-02.MEZZANINE.dgn,Design Model:149954 | A_BSUK_ExpandedPolystyreneBoards | Existing to Remain | A-FloorsSlabs::A_BSUK_ExpandedPolystyreneBoards
A-FloorsSlabs A_BSUK_Slabs | RL | insulation - sound undercroft rear :1,SHE_DRAWING+SHEET.dgn,Design Model;2 ,SHE-02.MEZZANINE.dgn,Design Model:181350 | A_BSUK_ExpandedPolystyreneBoards | New Construction | A-FloorsSlabs::A_BSUK_ExpandedPolystyreneBoards | Identification - ID | Description: insulation - sound undercroft rear
A-FloorsSlabs A_BSUK_Slabs | RL | insulation - sound undercroft rear :1,SHE_DRAWING+SHEET.dgn,Design Model;2 ,SHE-02.MEZZANINE.dgn,Design Model:181351 | A_BSUK_ExpandedPolystyreneBoards | New Construction | A-FloorsSlabs::A_BSUK_ExpandedPolystyreneBoards | Identification - ID | Description: insulation - sound undercroft rear
A-FloorsSlabs A_BSUK_Slabs | RL | insulation - sound undercroft rear :1,SHE_DRAWING+SHEET.dgn,Design Model;2 ,SHE-02.MEZZANINE.dgn,Design Model:182230 | A_BSUK_ExpandedPolystyreneBoards | New Construction | A-FloorsSlabs::A_BSUK_ExpandedPolystyreneBoards | Identification - ID | Description: insulation - sound undercroft rear
A-FloorsSlabs A_BSUK_Slabs | RL | insulation - sound undercroft rear :1,SHE_DRAWING+SHEET.dgn,Design Model;2 ,SHE-02.MEZZANINE.dgn,Design Model:182386 | A_BSUK_ExpandedPolystyreneBoards | New Construction | A-FloorsSlabs::A_BSUK_ExpandedPolystyreneBoards | Identification - ID | Description: insulation - sound undercroft rear
A-FloorsSlabs A_BSUK_Slabs | RL | insulation - sound undercroft rear :1,SHE_DRAWING+SHEET.dgn,Design Model;2 ,SHE-02.MEZZANINE.dgn,Design Model:182453 | A_BSUK_ExpandedPolystyreneBoards | New Construction | A-FloorsSlabs::A_BSUK_ExpandedPolystyreneBoards | Identification - ID | Description: insulation - sound undercroft rear
A-FloorsSlabs A_BSUK_Slabs | RL | fire board - ceiling :1,SHE_DRAWING+SHEET.dgn,Design Model;2 ,SHE-02.MEZZANINE.dgn,Design Model:190283 | A_BSUK_CeilingSoffitFinishes_Suspended | New Construction | A-Ceilings::A_BSUK_CeilingSoffitFinishes_Suspended | Identification - ID | Description: fire board - ceiling
A-FloorsSlabs A_BSUK_Slabs | RL | ext. OSB panels :1,SHE_DRAWING+SHEET.dgn,Design Model;2,SHE-02.MEZZANINE.dgn ,Design Model:190359 | A_BSUK_InternalFinishesCeilingOrSoffit | Existing to Remain | A-Ceilings::A_BSUK_InternalFinishesCeilingOrSoffit | Identification - ID | Description: ext. OSB panels
A-FloorsSlabs A_BSUK_Slabs | RL | dry screed board :1,SHE_DRAWING+SHEET.dgn,Design Model;2,SHE-02.MEZZANINE.dgn ,Design Model:191699 | A_BSUK_InternalFinishes_FloorScreed | New Construction | A-FloorsSlabs::A_BSUK_InternalFinishes_FloorScreed | Identification - ID | Description: dry screed board
A-FloorsSlabs A_BSUK_Slabs | RL | fire board - ceiling :1,SHE_DRAWING+SHEET.dgn,Design Model;2 ,SHE-02.MEZZANINE.dgn,Design Model:193482 | A_BSUK_CeilingSoffitFinishes_Suspended | New Construction | A-Ceilings::A_BSUK_CeilingSoffitFinishes_Suspended | Identification - ID | Description: fire board - ceiling
A-FloorsSlabs A_BSUK_Slabs | RL | shelving - bath :1,SHE_DRAWING+SHEET.dgn,Design Model;4,SHE-03.FIRST.dgn ,Design Model:142164 | A_BSUK_Ceramic_WallTiles | New Construction | A-Finishes::A_BSUK_Ceramic_WallTiles | Identification - ID | Description: shelving - bath
A-FloorsSlabs A_BSUK_Slabs | RL | shelving - bath :1,SHE_DRAWING+SHEET.dgn,Design Model;4,SHE-03.FIRST.dgn ,Design Model:142179 | A_BSUK_Ceramic_WallTiles | New Construction | A-Finishes::A_BSUK_Ceramic_WallTiles | Identification - ID | Description: shelving - bath
A-FloorsSlabs A_BSUK_Slabs | RL | shelving - bath :1,SHE_DRAWING+SHEET.dgn,Design Model;4,SHE-03.FIRST.dgn ,Design Model:142194 | A_BSUK_Ceramic_WallTiles | New Construction | A-Finishes::A_BSUK_Ceramic_WallTiles | Identification - ID | Description: shelving - bath
A-FloorsSlabs A_BSUK_Slabs | RL | shelving - bath :1,SHE_DRAWING+SHEET.dgn,Design Model;4,SHE-03.FIRST.dgn ,Design Model:300477 | A_BSUK_Ceramic_WallTiles | New Construction | A-Finishes::A_BSUK_Ceramic_WallTiles | Identification - ID | Description: shelving - bath
A-FloorsSlabs A_BSUK_Slabs | RL | shelving - bath :1,SHE_DRAWING+SHEET.dgn,Design Model;4,SHE-03.FIRST.dgn ,Design Model:300491 | A_BSUK_Ceramic_WallTiles | New Construction | A-Finishes::A_BSUK_Ceramic_WallTiles | Identification - ID | Description: shelving - bath
A-FloorsSlabs A_BSUK_Slabs | RL | shelving - bath :1,SHE_DRAWING+SHEET.dgn,Design Model;4,SHE-03.FIRST.dgn ,Design Model:300505 | A_BSUK_Ceramic_WallTiles | New Construction | A-Finishes::A_BSUK_Ceramic_WallTiles | Identification - ID | Description: shelving - bath
A-FloorsSlabs A_BSUK_Slabs | RL | shelving - bath :1,SHE_DRAWING+SHEET.dgn,Design Model;4,SHE-03.FIRST.dgn ,Design Model:327204 | A_BSUK_Ceramic_WallTiles | New Construction | A-Finishes::A_BSUK_Ceramic_WallTiles | Identification - ID | Description: shelving - bath
A-FloorsSlabs A_BSUK_Slabs | RL | 1 ,SHE_DRAWING+SHEET.dgn,Design Model;4,SHE-03.FIRST.dgn,Design Model:134765 | A_BSUK_CeilingSoffitFinishes_Suspended | New Construction | A-Ceilings::A_BSUK_CeilingSoffitFinishes_Suspended | Fire Resistance - Fire | Rating: FD60
A-FloorsSlabs A_BSUK_Slabs | RL | 1 ,SHE_DRAWING+SHEET.dgn,Design Model;4,SHE-03.FIRST.dgn,Design Model:134792 | A_BSUK_CeilingSoffitFinishes_Suspended | New Construction | A-Ceilings::A_BSUK_CeilingSoffitFinishes_Suspended | Fire Resistance - Fire | Rating: FD60
A-FloorsSlabs A_BSUK_Slabs | RL | 1 ,SHE_DRAWING+SHEET.dgn,Design Model;4,SHE-03.FIRST.dgn,Design Model:134816 | A_BSUK_CeilingSoffitFinishes_Suspended | New Construction | A-Ceilings::A_BSUK_CeilingSoffitFinishes_Suspended | Fire Resistance - Fire | Rating: FD60
A-FloorsSlabs A_BSUK_Slabs | RL | 1 ,SHE_DRAWING+SHEET.dgn,Design Model;4,SHE-03.FIRST.dgn,Design Model:134859 | A_BSUK_InternalFinishes_FloorScreed | New Construction | A-FloorsSlabs::A_BSUK_InternalFinishes_FloorScreed
A-FloorsSlabs A_BSUK_Slabs | RL | 1 ,SHE_DRAWING+SHEET.dgn,Design Model;4,SHE-03.FIRST.dgn,Design Model:134860 | A_BSUK_InternalFinishes_FloorScreed | New Construction | A-FloorsSlabs::A_BSUK_InternalFinishes_FloorScreed
A-FloorsSlabs A_BSUK_Slabs | RL | 1 ,SHE_DRAWING+SHEET.dgn,Design Model;4,SHE-03.FIRST.dgn,Design Model:135695 | A_BSUK_Ceramic_WallTiles | New Construction | A-Finishes::A_BSUK_Ceramic_WallTiles
A-FloorsSlabs A_BSUK_Slabs | RL | 1 ,SHE_DRAWING+SHEET.dgn,Design Model;4,SHE-03.FIRST.dgn,Design Model:135710 | A_BSUK_Ceramic_WallTiles | New Construction | A-Finishes::A_BSUK_Ceramic_WallTiles
A-FloorsSlabs A_BSUK_Slabs | RL | 1 ,SHE_DRAWING+SHEET.dgn,Design Model;4,SHE-03.FIRST.dgn,Design Model:135725 | A_BSUK_Ceramic_WallTiles | New Construction | A-Finishes::A_BSUK_Ceramic_WallTiles
A-FloorsSlabs A_BSUK_Slabs | RL | 1 ,SHE_DRAWING+SHEET.dgn,Design Model;4,SHE-03.FIRST.dgn,Design Model:135770 | A_BSUK_Ceramic_WallTiles | New Construction | A-Finishes::A_BSUK_Ceramic_WallTiles
A-FloorsSlabs A_BSUK_Slabs | RL | 1 ,SHE_DRAWING+SHEET.dgn,Design Model;4,SHE-03.FIRST.dgn,Design Model:142049 | A_BSUK_InternalFinishes_FloorScreed | Existing to Remain | A-FloorsSlabs::A_BSUK_InternalFinishes_FloorScreed
A-FloorsSlabs A_BSUK_Slabs | RL | 1 ,SHE_DRAWING+SHEET.dgn,Design Model;4,SHE-03.FIRST.dgn,Design Model:143321 | A_BSUK_Ceramic_WallTiles | New Construction | A-Finishes::A_BSUK_Ceramic_WallTiles
A-FloorsSlabs A_BSUK_Slabs | RL | 1 ,SHE_DRAWING+SHEET.dgn,Design Model;4,SHE-03.FIRST.dgn,Design Model:143864 | A_BSUK_ExpandedPolystyreneBoards | New Construction | A-FloorsSlabs::A_BSUK_ExpandedPolystyreneBoards
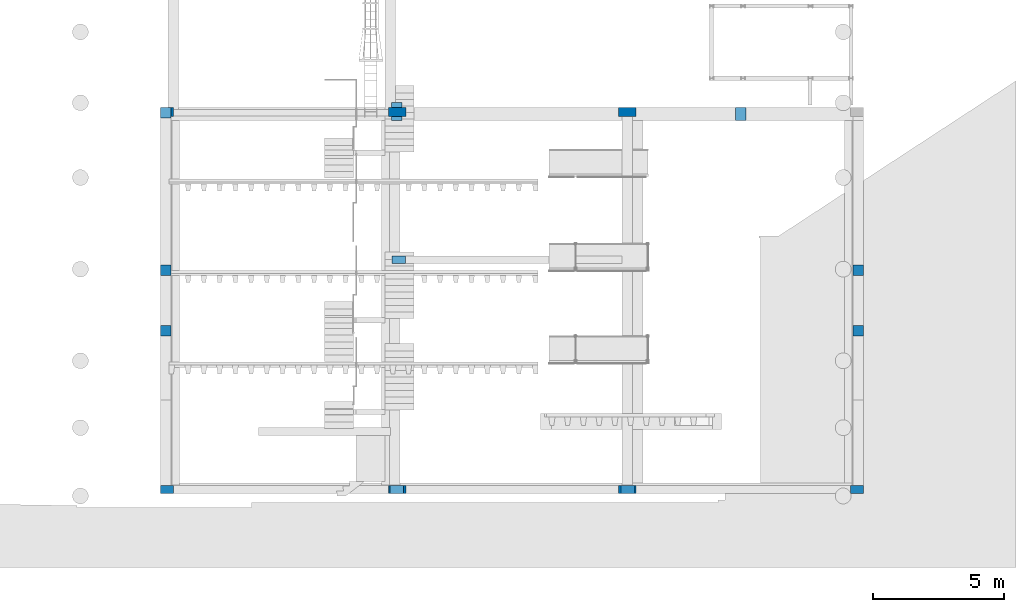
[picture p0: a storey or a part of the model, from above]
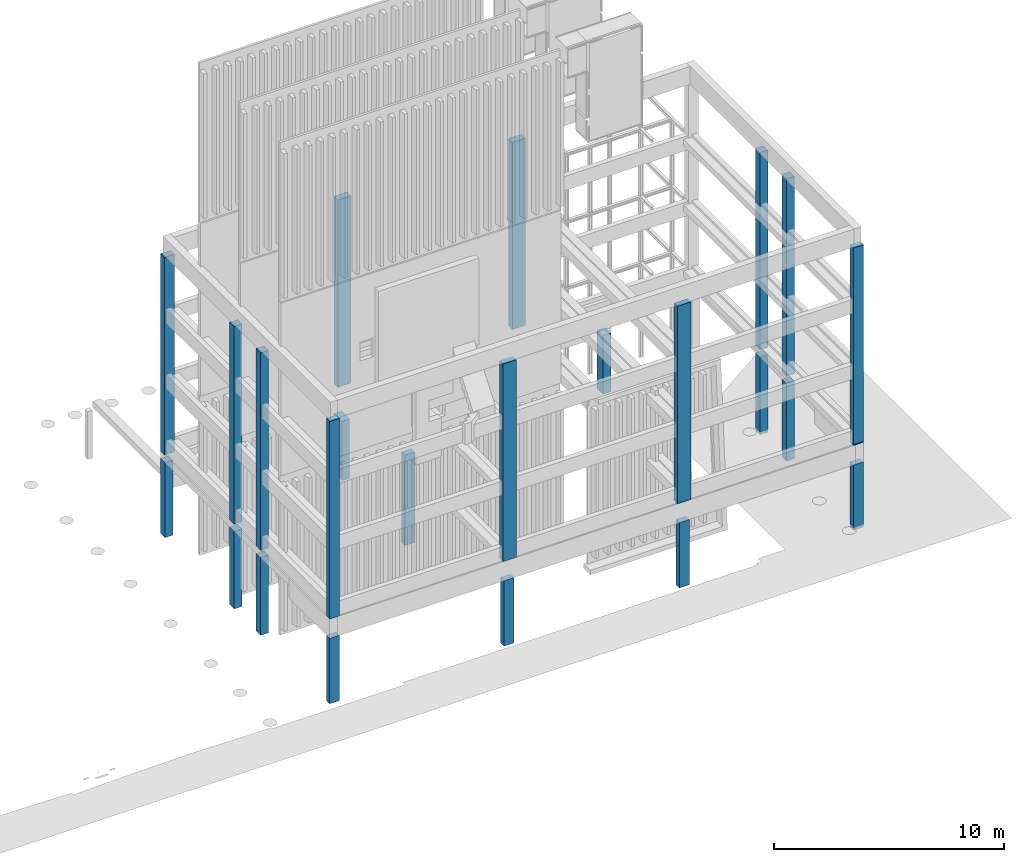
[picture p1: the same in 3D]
Properties of the parts of a building model (IFC2X3), part 10 of 16

# IfcSlab: A-FloorsSlabs A_BSUK_Slabs (1241)
Name | In | Description | Material | Phase | Part Definition
A-FloorsSlabs A_BSUK_Slabs | RL | 1 ,SHE_DRAWING+SHEET.dgn,Design Model;14,SHE-08.ROOF.dgn,Design Model:106348 | A_BSUK_Roofs | New Construction | A-Roofs::A_BSUK_Roofs
A-FloorsSlabs A_BSUK_Slabs | RL | 1 ,SHE_DRAWING+SHEET.dgn,Design Model;14,SHE-08.ROOF.dgn,Design Model:106362 | A_BSUK_Roofs | New Construction | A-Roofs::A_BSUK_Roofs
A-FloorsSlabs A_BSUK_Slabs | RL | 1 ,SHE_DRAWING+SHEET.dgn,Design Model;14,SHE-08.ROOF.dgn,Design Model:106376 | A_BSUK_Roofs | New Construction | A-Roofs::A_BSUK_Roofs
A-FloorsSlabs A_BSUK_Slabs | RL | 1 ,SHE_DRAWING+SHEET.dgn,Design Model;14,SHE-08.ROOF.dgn,Design Model:106390 | A_BSUK_Roofs | New Construction | A-Roofs::A_BSUK_Roofs
A-FloorsSlabs A_BSUK_Slabs | RL | 1 ,SHE_DRAWING+SHEET.dgn,Design Model;14,SHE-08.ROOF.dgn,Design Model:106404 | A_BSUK_Roofs | New Construction | A-Roofs::A_BSUK_Roofs
A-FloorsSlabs A_BSUK_Slabs | RL | 1 ,SHE_DRAWING+SHEET.dgn,Design Model;14,SHE-08.ROOF.dgn,Design Model:106419 | A_BSUK_Roofs | New Construction | A-Roofs::A_BSUK_Roofs
A-FloorsSlabs A_BSUK_Slabs | RL | 1 ,SHE_DRAWING+SHEET.dgn,Design Model;14,SHE-08.ROOF.dgn,Design Model:106430 | A_BSUK_Roofs | New Construction | A-Roofs::A_BSUK_Roofs
A-FloorsSlabs A_BSUK_Slabs | RL | 1 ,SHE_DRAWING+SHEET.dgn,Design Model;14,SHE-08.ROOF.dgn,Design Model:106444 | A_BSUK_Roofs | New Construction | A-Roofs::A_BSUK_Roofs
A-FloorsSlabs A_BSUK_Slabs | RL | 1 ,SHE_DRAWING+SHEET.dgn,Design Model;14,SHE-08.ROOF.dgn,Design Model:106458 | A_BSUK_Roofs | New Construction | A-Roofs::A_BSUK_Roofs
A-FloorsSlabs A_BSUK_Slabs | RL | 1 ,SHE_DRAWING+SHEET.dgn,Design Model;14,SHE-08.ROOF.dgn,Design Model:106472 | A_BSUK_Roofs | New Construction | A-Roofs::A_BSUK_Roofs
A-FloorsSlabs A_BSUK_Slabs | RL | 1 ,SHE_DRAWING+SHEET.dgn,Design Model;14,SHE-08.ROOF.dgn,Design Model:106486 | A_BSUK_Roofs | New Construction | A-Roofs::A_BSUK_Roofs
A-FloorsSlabs A_BSUK_Slabs | RL | 1 ,SHE_DRAWING+SHEET.dgn,Design Model;14,SHE-08.ROOF.dgn,Design Model:106500 | A_BSUK_Roofs | New Construction | A-Roofs::A_BSUK_Roofs
A-FloorsSlabs A_BSUK_Slabs | RL | 1 ,SHE_DRAWING+SHEET.dgn,Design Model;14,SHE-08.ROOF.dgn,Design Model:106514 | A_BSUK_Roofs | New Construction | A-Roofs::A_BSUK_Roofs
A-FloorsSlabs A_BSUK_Slabs | RL | 1 ,SHE_DRAWING+SHEET.dgn,Design Model;14,SHE-08.ROOF.dgn,Design Model:106528 | A_BSUK_Roofs | New Construction | A-Roofs::A_BSUK_Roofs
A-FloorsSlabs A_BSUK_Slabs | RL | 1 ,SHE_DRAWING+SHEET.dgn,Design Model;14,SHE-08.ROOF.dgn,Design Model:106542 | A_BSUK_Roofs | New Construction | A-Roofs::A_BSUK_Roofs
A-FloorsSlabs A_BSUK_Slabs | RL | 1 ,SHE_DRAWING+SHEET.dgn,Design Model;14,SHE-08.ROOF.dgn,Design Model:106557 | A_BSUK_Roofs | New Construction | A-Roofs::A_BSUK_Roofs
A-FloorsSlabs A_BSUK_Slabs | RL | 1 ,SHE_DRAWING+SHEET.dgn,Design Model;14,SHE-08.ROOF.dgn,Design Model:106568 | A_BSUK_Roofs | New Construction | A-Roofs::A_BSUK_Roofs
A-FloorsSlabs A_BSUK_Slabs | RL | 1 ,SHE_DRAWING+SHEET.dgn,Design Model;14,SHE-08.ROOF.dgn,Design Model:106582 | A_BSUK_Roofs | New Construction | A-Roofs::A_BSUK_Roofs
A-FloorsSlabs A_BSUK_Slabs | RL | 1 ,SHE_DRAWING+SHEET.dgn,Design Model;14,SHE-08.ROOF.dgn,Design Model:106596 | A_BSUK_Roofs | New Construction | A-Roofs::A_BSUK_Roofs
A-FloorsSlabs A_BSUK_Slabs | RL | 1 ,SHE_DRAWING+SHEET.dgn,Design Model;14,SHE-08.ROOF.dgn,Design Model:106610 | A_BSUK_Roofs | New Construction | A-Roofs::A_BSUK_Roofs
A-FloorsSlabs A_BSUK_Slabs | RL | 1 ,SHE_DRAWING+SHEET.dgn,Design Model;14,SHE-08.ROOF.dgn,Design Model:106624 | A_BSUK_Roofs | New Construction | A-Roofs::A_BSUK_Roofs
A-FloorsSlabs A_BSUK_Slabs | RL | 1 ,SHE_DRAWING+SHEET.dgn,Design Model;14,SHE-08.ROOF.dgn,Design Model:106638 | A_BSUK_Roofs | New Construction | A-Roofs::A_BSUK_Roofs
A-FloorsSlabs A_BSUK_Slabs | RL | 1 ,SHE_DRAWING+SHEET.dgn,Design Model;14,SHE-08.ROOF.dgn,Design Model:106652 | A_BSUK_Roofs | New Construction | A-Roofs::A_BSUK_Roofs
A-FloorsSlabs A_BSUK_Slabs | RL | 1 ,SHE_DRAWING+SHEET.dgn,Design Model;14,SHE-08.ROOF.dgn,Design Model:106666 | A_BSUK_Roofs | New Construction | A-Roofs::A_BSUK_Roofs
A-FloorsSlabs A_BSUK_Slabs | RL | 1 ,SHE_DRAWING+SHEET.dgn,Design Model;14,SHE-08.ROOF.dgn,Design Model:106680 | A_BSUK_Roofs | New Construction | A-Roofs::A_BSUK_Roofs
A-FloorsSlabs A_BSUK_Slabs | RL | 1 ,SHE_DRAWING+SHEET.dgn,Design Model;14,SHE-08.ROOF.dgn,Design Model:106695 | A_BSUK_Roofs | New Construction | A-Roofs::A_BSUK_Roofs
A-FloorsSlabs A_BSUK_Slabs | RL | 1 ,SHE_DRAWING+SHEET.dgn,Design Model;14,SHE-08.ROOF.dgn,Design Model:106706 | A_BSUK_Roofs | New Construction | A-Roofs::A_BSUK_Roofs
A-FloorsSlabs A_BSUK_Slabs | RL | 1 ,SHE_DRAWING+SHEET.dgn,Design Model;14,SHE-08.ROOF.dgn,Design Model:106720 | A_BSUK_Roofs | New Construction | A-Roofs::A_BSUK_Roofs
A-FloorsSlabs A_BSUK_Slabs | RL | 1 ,SHE_DRAWING+SHEET.dgn,Design Model;14,SHE-08.ROOF.dgn,Design Model:106734 | A_BSUK_Roofs | New Construction | A-Roofs::A_BSUK_Roofs
A-FloorsSlabs A_BSUK_Slabs | RL | 1 ,SHE_DRAWING+SHEET.dgn,Design Model;14,SHE-08.ROOF.dgn,Design Model:106748 | A_BSUK_Roofs | New Construction | A-Roofs::A_BSUK_Roofs
A-FloorsSlabs A_BSUK_Slabs | RL | 1 ,SHE_DRAWING+SHEET.dgn,Design Model;14,SHE-08.ROOF.dgn,Design Model:106762 | A_BSUK_Roofs | New Construction | A-Roofs::A_BSUK_Roofs
A-FloorsSlabs A_BSUK_Slabs | RL | 1 ,SHE_DRAWING+SHEET.dgn,Design Model;14,SHE-08.ROOF.dgn,Design Model:106776 | A_BSUK_Roofs | New Construction | A-Roofs::A_BSUK_Roofs
A-FloorsSlabs A_BSUK_Slabs | RL | 1 ,SHE_DRAWING+SHEET.dgn,Design Model;14,SHE-08.ROOF.dgn,Design Model:106791 | A_BSUK_Roofs | New Construction | A-Roofs::A_BSUK_Roofs
A-FloorsSlabs A_BSUK_Slabs | RL | 1 ,SHE_DRAWING+SHEET.dgn,Design Model;14,SHE-08.ROOF.dgn,Design Model:106805 | A_BSUK_Roofs | New Construction | A-Roofs::A_BSUK_Roofs
A-FloorsSlabs A_BSUK_Slabs | RL | 1 ,SHE_DRAWING+SHEET.dgn,Design Model;14,SHE-08.ROOF.dgn,Design Model:106821 | A_BSUK_Roofs | New Construction | A-Roofs::A_BSUK_Roofs
A-FloorsSlabs A_BSUK_Slabs | RL | 1 ,SHE_DRAWING+SHEET.dgn,Design Model;14,SHE-08.ROOF.dgn,Design Model:106832 | A_BSUK_Roofs | New Construction | A-Roofs::A_BSUK_Roofs
A-FloorsSlabs A_BSUK_Slabs | RL | 1 ,SHE_DRAWING+SHEET.dgn,Design Model;14,SHE-08.ROOF.dgn,Design Model:106846 | A_BSUK_Roofs | New Construction | A-Roofs::A_BSUK_Roofs
A-FloorsSlabs A_BSUK_Slabs | RL | 1 ,SHE_DRAWING+SHEET.dgn,Design Model;14,SHE-08.ROOF.dgn,Design Model:106857 | A_BSUK_Roofs | New Construction | A-Roofs::A_BSUK_Roofs
A-FloorsSlabs A_BSUK_Slabs | RL | 1 ,SHE_DRAWING+SHEET.dgn,Design Model;14,SHE-08.ROOF.dgn,Design Model:106871 | A_BSUK_Roofs | New Construction | A-Roofs::A_BSUK_Roofs
A-FloorsSlabs A_BSUK_Slabs | RL | 1 ,SHE_DRAWING+SHEET.dgn,Design Model;14,SHE-08.ROOF.dgn,Design Model:106885 | A_BSUK_Roofs | New Construction | A-Roofs::A_BSUK_Roofs
A-FloorsSlabs A_BSUK_Slabs | RL | 1 ,SHE_DRAWING+SHEET.dgn,Design Model;14,SHE-08.ROOF.dgn,Design Model:106896 | A_BSUK_Roofs | New Construction | A-Roofs::A_BSUK_Roofs
A-FloorsSlabs A_BSUK_Slabs | RL | 1 ,SHE_DRAWING+SHEET.dgn,Design Model;14,SHE-08.ROOF.dgn,Design Model:106910 | A_BSUK_Roofs | New Construction | A-Roofs::A_BSUK_Roofs
A-FloorsSlabs A_BSUK_Slabs | RL | 1 ,SHE_DRAWING+SHEET.dgn,Design Model;14,SHE-08.ROOF.dgn,Design Model:106924 | A_BSUK_Roofs | New Construction | A-Roofs::A_BSUK_Roofs
A-FloorsSlabs A_BSUK_Slabs | RL | 1 ,SHE_DRAWING+SHEET.dgn,Design Model;14,SHE-08.ROOF.dgn,Design Model:106935 | A_BSUK_Roofs | New Construction | A-Roofs::A_BSUK_Roofs
A-FloorsSlabs A_BSUK_Slabs | RL | 1 ,SHE_DRAWING+SHEET.dgn,Design Model;14,SHE-08.ROOF.dgn,Design Model:106949 | A_BSUK_Roofs | New Construction | A-Roofs::A_BSUK_Roofs
A-FloorsSlabs A_BSUK_Slabs | RL | 1 ,SHE_DRAWING+SHEET.dgn,Design Model;14,SHE-08.ROOF.dgn,Design Model:106963 | A_BSUK_Roofs | New Construction | A-Roofs::A_BSUK_Roofs
A-FloorsSlabs A_BSUK_Slabs | RL | 1 ,SHE_DRAWING+SHEET.dgn,Design Model;14,SHE-08.ROOF.dgn,Design Model:106977 | A_BSUK_Roofs | New Construction | A-Roofs::A_BSUK_Roofs
A-FloorsSlabs A_BSUK_Slabs | RL | 1 ,SHE_DRAWING+SHEET.dgn,Design Model;14,SHE-08.ROOF.dgn,Design Model:106988 | A_BSUK_Roofs | New Construction | A-Roofs::A_BSUK_Roofs
A-FloorsSlabs A_BSUK_Slabs | RL | 1 ,SHE_DRAWING+SHEET.dgn,Design Model;14,SHE-08.ROOF.dgn,Design Model:106999 | A_BSUK_Roofs | New Construction | A-Roofs::A_BSUK_Roofs
A-FloorsSlabs A_BSUK_Slabs | RL | 1 ,SHE_DRAWING+SHEET.dgn,Design Model;14,SHE-08.ROOF.dgn,Design Model:107013 | A_BSUK_Roofs | New Construction | A-Roofs::A_BSUK_Roofs
A-FloorsSlabs A_BSUK_Slabs | RL | 1 ,SHE_DRAWING+SHEET.dgn,Design Model;14,SHE-08.ROOF.dgn,Design Model:107027 | A_BSUK_Roofs | New Construction | A-Roofs::A_BSUK_Roofs
A-FloorsSlabs A_BSUK_Slabs | RL | 1 ,SHE_DRAWING+SHEET.dgn,Design Model;14,SHE-08.ROOF.dgn,Design Model:107041 | A_BSUK_Roofs | New Construction | A-Roofs::A_BSUK_Roofs
A-FloorsSlabs A_BSUK_Slabs | RL | 1 ,SHE_DRAWING+SHEET.dgn,Design Model;14,SHE-08.ROOF.dgn,Design Model:107052 | A_BSUK_Roofs | New Construction | A-Roofs::A_BSUK_Roofs
A-FloorsSlabs A_BSUK_Slabs | RL | 1 ,SHE_DRAWING+SHEET.dgn,Design Model;14,SHE-08.ROOF.dgn,Design Model:107063 | A_BSUK_Roofs | New Construction | A-Roofs::A_BSUK_Roofs
A-FloorsSlabs A_BSUK_Slabs | RL | 1 ,SHE_DRAWING+SHEET.dgn,Design Model;14,SHE-08.ROOF.dgn,Design Model:107077 | A_BSUK_Roofs | New Construction | A-Roofs::A_BSUK_Roofs
A-FloorsSlabs A_BSUK_Slabs | RL | 1 ,SHE_DRAWING+SHEET.dgn,Design Model;14,SHE-08.ROOF.dgn,Design Model:107091 | A_BSUK_Roofs | New Construction | A-Roofs::A_BSUK_Roofs
A-FloorsSlabs A_BSUK_Slabs | RL | 1 ,SHE_DRAWING+SHEET.dgn,Design Model;14,SHE-08.ROOF.dgn,Design Model:107102 | A_BSUK_Roofs | New Construction | A-Roofs::A_BSUK_Roofs
A-FloorsSlabs A_BSUK_Slabs | RL | 1 ,SHE_DRAWING+SHEET.dgn,Design Model;14,SHE-08.ROOF.dgn,Design Model:107116 | A_BSUK_Roofs | New Construction | A-Roofs::A_BSUK_Roofs
A-FloorsSlabs A_BSUK_Slabs | RL | 1 ,SHE_DRAWING+SHEET.dgn,Design Model;14,SHE-08.ROOF.dgn,Design Model:107127 | A_BSUK_Roofs | New Construction | A-Roofs::A_BSUK_Roofs
A-FloorsSlabs A_BSUK_Slabs | RL | 1 ,SHE_DRAWING+SHEET.dgn,Design Model;14,SHE-08.ROOF.dgn,Design Model:107141 | A_BSUK_Roofs | New Construction | A-Roofs::A_BSUK_Roofs
A-FloorsSlabs A_BSUK_Slabs | RL | 1 ,SHE_DRAWING+SHEET.dgn,Design Model;14,SHE-08.ROOF.dgn,Design Model:107155 | A_BSUK_Roofs | New Construction | A-Roofs::A_BSUK_Roofs
A-FloorsSlabs A_BSUK_Slabs | RL | 1 ,SHE_DRAWING+SHEET.dgn,Design Model;14,SHE-08.ROOF.dgn,Design Model:107166 | A_BSUK_Roofs | New Construction | A-Roofs::A_BSUK_Roofs
A-FloorsSlabs A_BSUK_Slabs | RL | 1 ,SHE_DRAWING+SHEET.dgn,Design Model;14,SHE-08.ROOF.dgn,Design Model:107180 | A_BSUK_Roofs | New Construction | A-Roofs::A_BSUK_Roofs
A-FloorsSlabs A_BSUK_Slabs | RL | 1 ,SHE_DRAWING+SHEET.dgn,Design Model;14,SHE-08.ROOF.dgn,Design Model:107191 | A_BSUK_Roofs | New Construction | A-Roofs::A_BSUK_Roofs
A-FloorsSlabs A_BSUK_Slabs | RL | 1 ,SHE_DRAWING+SHEET.dgn,Design Model;14,SHE-08.ROOF.dgn,Design Model:107205 | A_BSUK_Roofs | New Construction | A-Roofs::A_BSUK_Roofs
A-FloorsSlabs A_BSUK_Slabs | RL | 1 ,SHE_DRAWING+SHEET.dgn,Design Model;14,SHE-08.ROOF.dgn,Design Model:107219 | A_BSUK_Roofs | New Construction | A-Roofs::A_BSUK_Roofs
A-FloorsSlabs A_BSUK_Slabs | RL | 1 ,SHE_DRAWING+SHEET.dgn,Design Model;14,SHE-08.ROOF.dgn,Design Model:107233 | A_BSUK_Roofs | New Construction | A-Roofs::A_BSUK_Roofs
A-FloorsSlabs A_BSUK_Slabs | RL | 1 ,SHE_DRAWING+SHEET.dgn,Design Model;14,SHE-08.ROOF.dgn,Design Model:107248 | A_BSUK_Roofs | New Construction | A-Roofs::A_BSUK_Roofs
A-FloorsSlabs A_BSUK_Slabs | RL | 1 ,SHE_DRAWING+SHEET.dgn,Design Model;14,SHE-08.ROOF.dgn,Design Model:107259 | A_BSUK_Roofs | New Construction | A-Roofs::A_BSUK_Roofs
A-FloorsSlabs A_BSUK_Slabs | RL | 1 ,SHE_DRAWING+SHEET.dgn,Design Model;14,SHE-08.ROOF.dgn,Design Model:107273 | A_BSUK_Roofs | New Construction | A-Roofs::A_BSUK_Roofs
A-FloorsSlabs A_BSUK_Slabs | RL | 1 ,SHE_DRAWING+SHEET.dgn,Design Model;14,SHE-08.ROOF.dgn,Design Model:107287 | A_BSUK_Roofs | New Construction | A-Roofs::A_BSUK_Roofs
A-FloorsSlabs A_BSUK_Slabs | RL | 1 ,SHE_DRAWING+SHEET.dgn,Design Model;14,SHE-08.ROOF.dgn,Design Model:107301 | A_BSUK_Roofs | New Construction | A-Roofs::A_BSUK_Roofs
A-FloorsSlabs A_BSUK_Slabs | RL | 1 ,SHE_DRAWING+SHEET.dgn,Design Model;14,SHE-08.ROOF.dgn,Design Model:107315 | A_BSUK_Roofs | New Construction | A-Roofs::A_BSUK_Roofs
A-FloorsSlabs A_BSUK_Slabs | RL | 1 ,SHE_DRAWING+SHEET.dgn,Design Model;14,SHE-08.ROOF.dgn,Design Model:107329 | A_BSUK_Roofs | New Construction | A-Roofs::A_BSUK_Roofs
A-FloorsSlabs A_BSUK_Slabs | RL | 1 ,SHE_DRAWING+SHEET.dgn,Design Model;14,SHE-08.ROOF.dgn,Design Model:107343 | A_BSUK_Roofs | New Construction | A-Roofs::A_BSUK_Roofs
A-FloorsSlabs A_BSUK_Slabs | RL | 1 ,SHE_DRAWING+SHEET.dgn,Design Model;14,SHE-08.ROOF.dgn,Design Model:107357 | A_BSUK_Roofs | New Construction | A-Roofs::A_BSUK_Roofs
A-FloorsSlabs A_BSUK_Slabs | RL | 1 ,SHE_DRAWING+SHEET.dgn,Design Model;14,SHE-08.ROOF.dgn,Design Model:107371 | A_BSUK_Roofs | New Construction | A-Roofs::A_BSUK_Roofs
A-FloorsSlabs A_BSUK_Slabs | RL | 1 ,SHE_DRAWING+SHEET.dgn,Design Model;14,SHE-08.ROOF.dgn,Design Model:107386 | A_BSUK_Roofs | New Construction | A-Roofs::A_BSUK_Roofs
A-FloorsSlabs A_BSUK_Slabs | RL | 1 ,SHE_DRAWING+SHEET.dgn,Design Model;14,SHE-08.ROOF.dgn,Design Model:107397 | A_BSUK_Roofs | New Construction | A-Roofs::A_BSUK_Roofs
A-FloorsSlabs A_BSUK_Slabs | RL | 1 ,SHE_DRAWING+SHEET.dgn,Design Model;14,SHE-08.ROOF.dgn,Design Model:107411 | A_BSUK_Roofs | New Construction | A-Roofs::A_BSUK_Roofs
A-FloorsSlabs A_BSUK_Slabs | RL | 1 ,SHE_DRAWING+SHEET.dgn,Design Model;14,SHE-08.ROOF.dgn,Design Model:107425 | A_BSUK_Roofs | New Construction | A-Roofs::A_BSUK_Roofs
A-FloorsSlabs A_BSUK_Slabs | RL | 1 ,SHE_DRAWING+SHEET.dgn,Design Model;14,SHE-08.ROOF.dgn,Design Model:107439 | A_BSUK_Roofs | New Construction | A-Roofs::A_BSUK_Roofs
A-FloorsSlabs A_BSUK_Slabs | RL | 1 ,SHE_DRAWING+SHEET.dgn,Design Model;14,SHE-08.ROOF.dgn,Design Model:107453 | A_BSUK_Roofs | New Construction | A-Roofs::A_BSUK_Roofs
A-FloorsSlabs A_BSUK_Slabs | RL | 1 ,SHE_DRAWING+SHEET.dgn,Design Model;14,SHE-08.ROOF.dgn,Design Model:107467 | A_BSUK_Roofs | New Construction | A-Roofs::A_BSUK_Roofs
A-FloorsSlabs A_BSUK_Slabs | RL | 1 ,SHE_DRAWING+SHEET.dgn,Design Model;14,SHE-08.ROOF.dgn,Design Model:107481 | A_BSUK_Roofs | New Construction | A-Roofs::A_BSUK_Roofs
A-FloorsSlabs A_BSUK_Slabs | RL | 1 ,SHE_DRAWING+SHEET.dgn,Design Model;14,SHE-08.ROOF.dgn,Design Model:107495 | A_BSUK_Roofs | New Construction | A-Roofs::A_BSUK_Roofs
A-FloorsSlabs A_BSUK_Slabs | RL | 1 ,SHE_DRAWING+SHEET.dgn,Design Model;14,SHE-08.ROOF.dgn,Design Model:107509 | A_BSUK_Roofs | New Construction | A-Roofs::A_BSUK_Roofs
A-FloorsSlabs A_BSUK_Slabs | RL | 1 ,SHE_DRAWING+SHEET.dgn,Design Model;14,SHE-08.ROOF.dgn,Design Model:107524 | A_BSUK_Roofs | New Construction | A-Roofs::A_BSUK_Roofs
A-FloorsSlabs A_BSUK_Slabs | RL | 1 ,SHE_DRAWING+SHEET.dgn,Design Model;14,SHE-08.ROOF.dgn,Design Model:107535 | A_BSUK_Roofs | New Construction | A-Roofs::A_BSUK_Roofs
A-FloorsSlabs A_BSUK_Slabs | RL | 1 ,SHE_DRAWING+SHEET.dgn,Design Model;14,SHE-08.ROOF.dgn,Design Model:107549 | A_BSUK_Roofs | New Construction | A-Roofs::A_BSUK_Roofs
A-FloorsSlabs A_BSUK_Slabs | RL | 1 ,SHE_DRAWING+SHEET.dgn,Design Model;14,SHE-08.ROOF.dgn,Design Model:107563 | A_BSUK_Roofs | New Construction | A-Roofs::A_BSUK_Roofs
A-FloorsSlabs A_BSUK_Slabs | RL | 1 ,SHE_DRAWING+SHEET.dgn,Design Model;14,SHE-08.ROOF.dgn,Design Model:107577 | A_BSUK_Roofs | New Construction | A-Roofs::A_BSUK_Roofs
A-FloorsSlabs A_BSUK_Slabs | RL | 1 ,SHE_DRAWING+SHEET.dgn,Design Model;14,SHE-08.ROOF.dgn,Design Model:107591 | A_BSUK_Roofs | New Construction | A-Roofs::A_BSUK_Roofs
A-FloorsSlabs A_BSUK_Slabs | RL | 1 ,SHE_DRAWING+SHEET.dgn,Design Model;14,SHE-08.ROOF.dgn,Design Model:107605 | A_BSUK_Roofs | New Construction | A-Roofs::A_BSUK_Roofs
A-FloorsSlabs A_BSUK_Slabs | RL | 1 ,SHE_DRAWING+SHEET.dgn,Design Model;14,SHE-08.ROOF.dgn,Design Model:107620 | A_BSUK_Roofs | New Construction | A-Roofs::A_BSUK_Roofs
A-FloorsSlabs A_BSUK_Slabs | RL | 1 ,SHE_DRAWING+SHEET.dgn,Design Model;14,SHE-08.ROOF.dgn,Design Model:107634 | A_BSUK_Roofs | New Construction | A-Roofs::A_BSUK_Roofs
A-FloorsSlabs A_BSUK_Slabs | RL | 1 ,SHE_DRAWING+SHEET.dgn,Design Model;14,SHE-08.ROOF.dgn,Design Model:107650 | A_BSUK_Roofs | New Construction | A-Roofs::A_BSUK_Roofs
A-FloorsSlabs A_BSUK_Slabs | RL | 1 ,SHE_DRAWING+SHEET.dgn,Design Model;14,SHE-08.ROOF.dgn,Design Model:107661 | A_BSUK_Roofs | New Construction | A-Roofs::A_BSUK_Roofs
A-FloorsSlabs A_BSUK_Slabs | RL | 1 ,SHE_DRAWING+SHEET.dgn,Design Model;14,SHE-08.ROOF.dgn,Design Model:107675 | A_BSUK_Roofs | New Construction | A-Roofs::A_BSUK_Roofs
A-FloorsSlabs A_BSUK_Slabs | RL | 1 ,SHE_DRAWING+SHEET.dgn,Design Model;14,SHE-08.ROOF.dgn,Design Model:107686 | A_BSUK_Roofs | New Construction | A-Roofs::A_BSUK_Roofs
A-FloorsSlabs A_BSUK_Slabs | RL | 1 ,SHE_DRAWING+SHEET.dgn,Design Model;14,SHE-08.ROOF.dgn,Design Model:107700 | A_BSUK_Roofs | New Construction | A-Roofs::A_BSUK_Roofs
A-FloorsSlabs A_BSUK_Slabs | RL | 1 ,SHE_DRAWING+SHEET.dgn,Design Model;14,SHE-08.ROOF.dgn,Design Model:107715 | A_BSUK_Roofs | New Construction | A-Roofs::A_BSUK_Roofs
A-FloorsSlabs A_BSUK_Slabs | RL | 1 ,SHE_DRAWING+SHEET.dgn,Design Model;14,SHE-08.ROOF.dgn,Design Model:107726 | A_BSUK_Roofs | New Construction | A-Roofs::A_BSUK_Roofs
A-FloorsSlabs A_BSUK_Slabs | RL | 1 ,SHE_DRAWING+SHEET.dgn,Design Model;14,SHE-08.ROOF.dgn,Design Model:107740 | A_BSUK_Roofs | New Construction | A-Roofs::A_BSUK_Roofs
A-FloorsSlabs A_BSUK_Slabs | RL | 1 ,SHE_DRAWING+SHEET.dgn,Design Model;14,SHE-08.ROOF.dgn,Design Model:107754 | A_BSUK_Roofs | New Construction | A-Roofs::A_BSUK_Roofs
A-FloorsSlabs A_BSUK_Slabs | RL | 1 ,SHE_DRAWING+SHEET.dgn,Design Model;14,SHE-08.ROOF.dgn,Design Model:107768 | A_BSUK_Roofs | New Construction | A-Roofs::A_BSUK_Roofs
A-FloorsSlabs A_BSUK_Slabs | RL | 1 ,SHE_DRAWING+SHEET.dgn,Design Model;14,SHE-08.ROOF.dgn,Design Model:107782 | A_BSUK_Roofs | New Construction | A-Roofs::A_BSUK_Roofs
A-FloorsSlabs A_BSUK_Slabs | RL | 1 ,SHE_DRAWING+SHEET.dgn,Design Model;14,SHE-08.ROOF.dgn,Design Model:107796 | A_BSUK_Roofs | New Construction | A-Roofs::A_BSUK_Roofs
A-FloorsSlabs A_BSUK_Slabs | RL | 1 ,SHE_DRAWING+SHEET.dgn,Design Model;14,SHE-08.ROOF.dgn,Design Model:107810 | A_BSUK_Roofs | New Construction | A-Roofs::A_BSUK_Roofs
A-FloorsSlabs A_BSUK_Slabs | RL | 1 ,SHE_DRAWING+SHEET.dgn,Design Model;14,SHE-08.ROOF.dgn,Design Model:107824 | A_BSUK_Roofs | New Construction | A-Roofs::A_BSUK_Roofs
A-FloorsSlabs A_BSUK_Slabs | RL | 1 ,SHE_DRAWING+SHEET.dgn,Design Model;14,SHE-08.ROOF.dgn,Design Model:107838 | A_BSUK_Roofs | New Construction | A-Roofs::A_BSUK_Roofs
A-FloorsSlabs A_BSUK_Slabs | RL | 1 ,SHE_DRAWING+SHEET.dgn,Design Model;14,SHE-08.ROOF.dgn,Design Model:107853 | A_BSUK_Roofs | New Construction | A-Roofs::A_BSUK_Roofs
A-FloorsSlabs A_BSUK_Slabs | RL | 1 ,SHE_DRAWING+SHEET.dgn,Design Model;14,SHE-08.ROOF.dgn,Design Model:107864 | A_BSUK_Roofs | New Construction | A-Roofs::A_BSUK_Roofs
A-FloorsSlabs A_BSUK_Slabs | RL | 1 ,SHE_DRAWING+SHEET.dgn,Design Model;14,SHE-08.ROOF.dgn,Design Model:107878 | A_BSUK_Roofs | New Construction | A-Roofs::A_BSUK_Roofs
A-FloorsSlabs A_BSUK_Slabs | RL | 1 ,SHE_DRAWING+SHEET.dgn,Design Model;14,SHE-08.ROOF.dgn,Design Model:107892 | A_BSUK_Roofs | New Construction | A-Roofs::A_BSUK_Roofs
A-FloorsSlabs A_BSUK_Slabs | RL | 1 ,SHE_DRAWING+SHEET.dgn,Design Model;14,SHE-08.ROOF.dgn,Design Model:107906 | A_BSUK_Roofs | New Construction | A-Roofs::A_BSUK_Roofs
A-FloorsSlabs A_BSUK_Slabs | RL | 1 ,SHE_DRAWING+SHEET.dgn,Design Model;14,SHE-08.ROOF.dgn,Design Model:107920 | A_BSUK_Roofs | New Construction | A-Roofs::A_BSUK_Roofs
A-FloorsSlabs A_BSUK_Slabs | RL | 1 ,SHE_DRAWING+SHEET.dgn,Design Model;14,SHE-08.ROOF.dgn,Design Model:107934 | A_BSUK_Roofs | New Construction | A-Roofs::A_BSUK_Roofs
A-FloorsSlabs A_BSUK_Slabs | RL | 1 ,SHE_DRAWING+SHEET.dgn,Design Model;14,SHE-08.ROOF.dgn,Design Model:107948 | A_BSUK_Roofs | New Construction | A-Roofs::A_BSUK_Roofs
A-FloorsSlabs A_BSUK_Slabs | RL | 1 ,SHE_DRAWING+SHEET.dgn,Design Model;14,SHE-08.ROOF.dgn,Design Model:107962 | A_BSUK_Roofs | New Construction | A-Roofs::A_BSUK_Roofs
A-FloorsSlabs A_BSUK_Slabs | RL | 1 ,SHE_DRAWING+SHEET.dgn,Design Model;14,SHE-08.ROOF.dgn,Design Model:107976 | A_BSUK_Roofs | New Construction | A-Roofs::A_BSUK_Roofs
A-FloorsSlabs A_BSUK_Slabs | RL | 1 ,SHE_DRAWING+SHEET.dgn,Design Model;14,SHE-08.ROOF.dgn,Design Model:107991 | A_BSUK_Roofs | New Construction | A-Roofs::A_BSUK_Roofs
A-FloorsSlabs A_BSUK_Slabs | RL | 1 ,SHE_DRAWING+SHEET.dgn,Design Model;14,SHE-08.ROOF.dgn,Design Model:108002 | A_BSUK_Roofs | New Construction | A-Roofs::A_BSUK_Roofs
A-FloorsSlabs A_BSUK_Slabs | RL | 1 ,SHE_DRAWING+SHEET.dgn,Design Model;14,SHE-08.ROOF.dgn,Design Model:108016 | A_BSUK_Roofs | New Construction | A-Roofs::A_BSUK_Roofs
A-FloorsSlabs A_BSUK_Slabs | RL | 1 ,SHE_DRAWING+SHEET.dgn,Design Model;14,SHE-08.ROOF.dgn,Design Model:108030 | A_BSUK_Roofs | New Construction | A-Roofs::A_BSUK_Roofs
A-FloorsSlabs A_BSUK_Slabs | RL | 1 ,SHE_DRAWING+SHEET.dgn,Design Model;14,SHE-08.ROOF.dgn,Design Model:108044 | A_BSUK_Roofs | New Construction | A-Roofs::A_BSUK_Roofs
A-FloorsSlabs A_BSUK_Slabs | RL | 1 ,SHE_DRAWING+SHEET.dgn,Design Model;14,SHE-08.ROOF.dgn,Design Model:108058 | A_BSUK_Roofs | New Construction | A-Roofs::A_BSUK_Roofs
A-FloorsSlabs A_BSUK_Slabs | RL | 1 ,SHE_DRAWING+SHEET.dgn,Design Model;14,SHE-08.ROOF.dgn,Design Model:108072 | A_BSUK_Roofs | New Construction | A-Roofs::A_BSUK_Roofs
A-FloorsSlabs A_BSUK_Slabs | RL | 1 ,SHE_DRAWING+SHEET.dgn,Design Model;14,SHE-08.ROOF.dgn,Design Model:108086 | A_BSUK_Roofs | New Construction | A-Roofs::A_BSUK_Roofs
A-FloorsSlabs A_BSUK_Slabs | RL | 1 ,SHE_DRAWING+SHEET.dgn,Design Model;14,SHE-08.ROOF.dgn,Design Model:108100 | A_BSUK_Roofs | New Construction | A-Roofs::A_BSUK_Roofs
A-FloorsSlabs A_BSUK_Slabs | RL | 1 ,SHE_DRAWING+SHEET.dgn,Design Model;14,SHE-08.ROOF.dgn,Design Model:108114 | A_BSUK_Roofs | New Construction | A-Roofs::A_BSUK_Roofs
A-FloorsSlabs A_BSUK_Slabs | RL | 1 ,SHE_DRAWING+SHEET.dgn,Design Model;14,SHE-08.ROOF.dgn,Design Model:108129 | A_BSUK_Roofs | New Construction | A-Roofs::A_BSUK_Roofs
A-FloorsSlabs A_BSUK_Slabs | RL | 1 ,SHE_DRAWING+SHEET.dgn,Design Model;14,SHE-08.ROOF.dgn,Design Model:108140 | A_BSUK_Roofs | New Construction | A-Roofs::A_BSUK_Roofs
A-FloorsSlabs A_BSUK_Slabs | RL | 1 ,SHE_DRAWING+SHEET.dgn,Design Model;14,SHE-08.ROOF.dgn,Design Model:108154 | A_BSUK_Roofs | New Construction | A-Roofs::A_BSUK_Roofs
A-FloorsSlabs A_BSUK_Slabs | RL | 1 ,SHE_DRAWING+SHEET.dgn,Design Model;14,SHE-08.ROOF.dgn,Design Model:108168 | A_BSUK_Roofs | New Construction | A-Roofs::A_BSUK_Roofs
A-FloorsSlabs A_BSUK_Slabs | RL | 1 ,SHE_DRAWING+SHEET.dgn,Design Model;14,SHE-08.ROOF.dgn,Design Model:108182 | A_BSUK_Roofs | New Construction | A-Roofs::A_BSUK_Roofs
A-FloorsSlabs A_BSUK_Slabs | RL | 1 ,SHE_DRAWING+SHEET.dgn,Design Model;14,SHE-08.ROOF.dgn,Design Model:108196 | A_BSUK_Roofs | New Construction | A-Roofs::A_BSUK_Roofs
A-FloorsSlabs A_BSUK_Slabs | RL | 1 ,SHE_DRAWING+SHEET.dgn,Design Model;14,SHE-08.ROOF.dgn,Design Model:108210 | A_BSUK_Roofs | New Construction | A-Roofs::A_BSUK_Roofs
A-FloorsSlabs A_BSUK_Slabs | RL | 1 ,SHE_DRAWING+SHEET.dgn,Design Model;14,SHE-08.ROOF.dgn,Design Model:108225 | A_BSUK_Roofs | New Construction | A-Roofs::A_BSUK_Roofs
A-FloorsSlabs A_BSUK_Slabs | RL | 1 ,SHE_DRAWING+SHEET.dgn,Design Model;14,SHE-08.ROOF.dgn,Design Model:108239 | A_BSUK_Roofs | New Construction | A-Roofs::A_BSUK_Roofs
A-FloorsSlabs A_BSUK_Slabs | RL | 1 ,SHE_DRAWING+SHEET.dgn,Design Model;14,SHE-08.ROOF.dgn,Design Model:108255 | A_BSUK_Roofs | New Construction | A-Roofs::A_BSUK_Roofs
A-FloorsSlabs A_BSUK_Slabs | RL | 1 ,SHE_DRAWING+SHEET.dgn,Design Model;14,SHE-08.ROOF.dgn,Design Model:108266 | A_BSUK_Roofs | New Construction | A-Roofs::A_BSUK_Roofs
A-FloorsSlabs A_BSUK_Slabs | RL | 1 ,SHE_DRAWING+SHEET.dgn,Design Model;14,SHE-08.ROOF.dgn,Design Model:108280 | A_BSUK_Roofs | New Construction | A-Roofs::A_BSUK_Roofs
A-FloorsSlabs A_BSUK_Slabs | RL | 1 ,SHE_DRAWING+SHEET.dgn,Design Model;14,SHE-08.ROOF.dgn,Design Model:108291 | A_BSUK_Roofs | New Construction | A-Roofs::A_BSUK_Roofs
A-FloorsSlabs A_BSUK_Slabs | RL | 1 ,SHE_DRAWING+SHEET.dgn,Design Model;14,SHE-08.ROOF.dgn,Design Model:108305 | A_BSUK_Roofs | New Construction | A-Roofs::A_BSUK_Roofs
A-FloorsSlabs A_BSUK_Slabs | RL | 1 ,SHE_DRAWING+SHEET.dgn,Design Model;14,SHE-08.ROOF.dgn,Design Model:108319 | A_BSUK_Roofs | New Construction | A-Roofs::A_BSUK_Roofs
A-FloorsSlabs A_BSUK_Slabs | RL | 1 ,SHE_DRAWING+SHEET.dgn,Design Model;14,SHE-08.ROOF.dgn,Design Model:108330 | A_BSUK_Roofs | New Construction | A-Roofs::A_BSUK_Roofs
A-FloorsSlabs A_BSUK_Slabs | RL | 1 ,SHE_DRAWING+SHEET.dgn,Design Model;14,SHE-08.ROOF.dgn,Design Model:108344 | A_BSUK_Roofs | New Construction | A-Roofs::A_BSUK_Roofs
A-FloorsSlabs A_BSUK_Slabs | RL | 1 ,SHE_DRAWING+SHEET.dgn,Design Model;14,SHE-08.ROOF.dgn,Design Model:108358 | A_BSUK_Roofs | New Construction | A-Roofs::A_BSUK_Roofs
A-FloorsSlabs A_BSUK_Slabs | RL | 1 ,SHE_DRAWING+SHEET.dgn,Design Model;14,SHE-08.ROOF.dgn,Design Model:108369 | A_BSUK_Roofs | New Construction | A-Roofs::A_BSUK_Roofs
A-FloorsSlabs A_BSUK_Slabs | RL | 1 ,SHE_DRAWING+SHEET.dgn,Design Model;14,SHE-08.ROOF.dgn,Design Model:108383 | A_BSUK_Roofs | New Construction | A-Roofs::A_BSUK_Roofs
A-FloorsSlabs A_BSUK_Slabs | RL | 1 ,SHE_DRAWING+SHEET.dgn,Design Model;14,SHE-08.ROOF.dgn,Design Model:108397 | A_BSUK_Roofs | New Construction | A-Roofs::A_BSUK_Roofs
A-FloorsSlabs A_BSUK_Slabs | RL | 1 ,SHE_DRAWING+SHEET.dgn,Design Model;14,SHE-08.ROOF.dgn,Design Model:108411 | A_BSUK_Roofs | New Construction | A-Roofs::A_BSUK_Roofs
A-FloorsSlabs A_BSUK_Slabs | RL | 1 ,SHE_DRAWING+SHEET.dgn,Design Model;14,SHE-08.ROOF.dgn,Design Model:108422 | A_BSUK_Roofs | New Construction | A-Roofs::A_BSUK_Roofs
A-FloorsSlabs A_BSUK_Slabs | RL | 1 ,SHE_DRAWING+SHEET.dgn,Design Model;14,SHE-08.ROOF.dgn,Design Model:108433 | A_BSUK_Roofs | New Construction | A-Roofs::A_BSUK_Roofs
A-FloorsSlabs A_BSUK_Slabs | RL | 1 ,SHE_DRAWING+SHEET.dgn,Design Model;14,SHE-08.ROOF.dgn,Design Model:108447 | A_BSUK_Roofs | New Construction | A-Roofs::A_BSUK_Roofs
A-FloorsSlabs A_BSUK_Slabs | RL | 1 ,SHE_DRAWING+SHEET.dgn,Design Model;14,SHE-08.ROOF.dgn,Design Model:108461 | A_BSUK_Roofs | New Construction | A-Roofs::A_BSUK_Roofs
A-FloorsSlabs A_BSUK_Slabs | RL | 1 ,SHE_DRAWING+SHEET.dgn,Design Model;14,SHE-08.ROOF.dgn,Design Model:108475 | A_BSUK_Roofs | New Construction | A-Roofs::A_BSUK_Roofs
A-FloorsSlabs A_BSUK_Slabs | RL | 1 ,SHE_DRAWING+SHEET.dgn,Design Model;14,SHE-08.ROOF.dgn,Design Model:108486 | A_BSUK_Roofs | New Construction | A-Roofs::A_BSUK_Roofs
A-FloorsSlabs A_BSUK_Slabs | RL | 1 ,SHE_DRAWING+SHEET.dgn,Design Model;14,SHE-08.ROOF.dgn,Design Model:108497 | A_BSUK_Roofs | New Construction | A-Roofs::A_BSUK_Roofs
A-FloorsSlabs A_BSUK_Slabs | RL | 1 ,SHE_DRAWING+SHEET.dgn,Design Model;14,SHE-08.ROOF.dgn,Design Model:108511 | A_BSUK_Roofs | New Construction | A-Roofs::A_BSUK_Roofs
A-FloorsSlabs A_BSUK_Slabs | RL | 1 ,SHE_DRAWING+SHEET.dgn,Design Model;14,SHE-08.ROOF.dgn,Design Model:108525 | A_BSUK_Roofs | New Construction | A-Roofs::A_BSUK_Roofs
A-FloorsSlabs A_BSUK_Slabs | RL | 1 ,SHE_DRAWING+SHEET.dgn,Design Model;14,SHE-08.ROOF.dgn,Design Model:108536 | A_BSUK_Roofs | New Construction | A-Roofs::A_BSUK_Roofs
A-FloorsSlabs A_BSUK_Slabs | RL | 1 ,SHE_DRAWING+SHEET.dgn,Design Model;14,SHE-08.ROOF.dgn,Design Model:108550 | A_BSUK_Roofs | New Construction | A-Roofs::A_BSUK_Roofs
A-FloorsSlabs A_BSUK_Slabs | RL | 1 ,SHE_DRAWING+SHEET.dgn,Design Model;14,SHE-08.ROOF.dgn,Design Model:108561 | A_BSUK_Roofs | New Construction | A-Roofs::A_BSUK_Roofs
A-FloorsSlabs A_BSUK_Slabs | RL | 1 ,SHE_DRAWING+SHEET.dgn,Design Model;14,SHE-08.ROOF.dgn,Design Model:108575 | A_BSUK_Roofs | New Construction | A-Roofs::A_BSUK_Roofs
A-FloorsSlabs A_BSUK_Slabs | RL | 1 ,SHE_DRAWING+SHEET.dgn,Design Model;14,SHE-08.ROOF.dgn,Design Model:108589 | A_BSUK_Roofs | New Construction | A-Roofs::A_BSUK_Roofs
A-FloorsSlabs A_BSUK_Slabs | RL | 1 ,SHE_DRAWING+SHEET.dgn,Design Model;14,SHE-08.ROOF.dgn,Design Model:108600 | A_BSUK_Roofs | New Construction | A-Roofs::A_BSUK_Roofs
A-FloorsSlabs A_BSUK_Slabs | RL | 1 ,SHE_DRAWING+SHEET.dgn,Design Model;14,SHE-08.ROOF.dgn,Design Model:108614 | A_BSUK_Roofs | New Construction | A-Roofs::A_BSUK_Roofs
A-FloorsSlabs A_BSUK_Slabs | RL | 1 ,SHE_DRAWING+SHEET.dgn,Design Model;14,SHE-08.ROOF.dgn,Design Model:108628 | A_BSUK_Roofs | New Construction | A-Roofs::A_BSUK_Roofs
A-FloorsSlabs A_BSUK_Slabs | RL | 1 ,SHE_DRAWING+SHEET.dgn,Design Model;14,SHE-08.ROOF.dgn,Design Model:108642 | A_BSUK_Roofs | New Construction | A-Roofs::A_BSUK_Roofs
A-FloorsSlabs A_BSUK_Slabs | RL | 1 ,SHE_DRAWING+SHEET.dgn,Design Model;14,SHE-08.ROOF.dgn,Design Model:108656 | A_BSUK_Roofs | New Construction | A-Roofs::A_BSUK_Roofs
A-FloorsSlabs A_BSUK_Slabs | RL | 1 ,SHE_DRAWING+SHEET.dgn,Design Model;14,SHE-08.ROOF.dgn,Design Model:108670 | A_BSUK_Roofs | New Construction | A-Roofs::A_BSUK_Roofs
A-FloorsSlabs A_BSUK_Slabs | RL | 1 ,SHE_DRAWING+SHEET.dgn,Design Model;14,SHE-08.ROOF.dgn,Design Model:108684 | A_BSUK_Roofs | New Construction | A-Roofs::A_BSUK_Roofs
A-FloorsSlabs A_BSUK_Slabs | RL | 1 ,SHE_DRAWING+SHEET.dgn,Design Model;14,SHE-08.ROOF.dgn,Design Model:108698 | A_BSUK_Roofs | New Construction | A-Roofs::A_BSUK_Roofs
A-FloorsSlabs A_BSUK_Slabs | RL | 1 ,SHE_DRAWING+SHEET.dgn,Design Model;14,SHE-08.ROOF.dgn,Design Model:108712 | A_BSUK_Roofs | New Construction | A-Roofs::A_BSUK_Roofs
A-FloorsSlabs A_BSUK_Slabs | RL | 1 ,SHE_DRAWING+SHEET.dgn,Design Model;14,SHE-08.ROOF.dgn,Design Model:108723 | A_BSUK_Roofs | New Construction | A-Roofs::A_BSUK_Roofs
A-FloorsSlabs A_BSUK_Slabs | RL | 1 ,SHE_DRAWING+SHEET.dgn,Design Model;14,SHE-08.ROOF.dgn,Design Model:108737 | A_BSUK_Roofs | New Construction | A-Roofs::A_BSUK_Roofs
A-FloorsSlabs A_BSUK_Slabs | RL | 1 ,SHE_DRAWING+SHEET.dgn,Design Model;14,SHE-08.ROOF.dgn,Design Model:108751 | A_BSUK_Roofs | New Construction | A-Roofs::A_BSUK_Roofs
A-FloorsSlabs A_BSUK_Slabs | RL | 1 ,SHE_DRAWING+SHEET.dgn,Design Model;14,SHE-08.ROOF.dgn,Design Model:108762 | A_BSUK_Roofs | New Construction | A-Roofs::A_BSUK_Roofs
A-FloorsSlabs A_BSUK_Slabs | RL | 1 ,SHE_DRAWING+SHEET.dgn,Design Model;14,SHE-08.ROOF.dgn,Design Model:108776 | A_BSUK_Roofs | New Construction | A-Roofs::A_BSUK_Roofs
A-FloorsSlabs A_BSUK_Slabs | RL | 1 ,SHE_DRAWING+SHEET.dgn,Design Model;14,SHE-08.ROOF.dgn,Design Model:108790 | A_BSUK_Roofs | New Construction | A-Roofs::A_BSUK_Roofs
A-FloorsSlabs A_BSUK_Slabs | RL | 1 ,SHE_DRAWING+SHEET.dgn,Design Model;14,SHE-08.ROOF.dgn,Design Model:108804 | A_BSUK_Roofs | New Construction | A-Roofs::A_BSUK_Roofs
A-FloorsSlabs A_BSUK_Slabs | RL | 1 ,SHE_DRAWING+SHEET.dgn,Design Model;14,SHE-08.ROOF.dgn,Design Model:108815 | A_BSUK_Roofs | New Construction | A-Roofs::A_BSUK_Roofs
A-FloorsSlabs A_BSUK_Slabs | RL | 1 ,SHE_DRAWING+SHEET.dgn,Design Model;14,SHE-08.ROOF.dgn,Design Model:108826 | A_BSUK_Roofs | New Construction | A-Roofs::A_BSUK_Roofs
A-FloorsSlabs A_BSUK_Slabs | RL | 1 ,SHE_DRAWING+SHEET.dgn,Design Model;14,SHE-08.ROOF.dgn,Design Model:108840 | A_BSUK_Roofs | New Construction | A-Roofs::A_BSUK_Roofs
A-FloorsSlabs A_BSUK_Slabs | RL | 1 ,SHE_DRAWING+SHEET.dgn,Design Model;14,SHE-08.ROOF.dgn,Design Model:108854 | A_BSUK_Roofs | New Construction | A-Roofs::A_BSUK_Roofs
A-FloorsSlabs A_BSUK_Slabs | RL | 1 ,SHE_DRAWING+SHEET.dgn,Design Model;14,SHE-08.ROOF.dgn,Design Model:108868 | A_BSUK_Roofs | New Construction | A-Roofs::A_BSUK_Roofs
A-FloorsSlabs A_BSUK_Slabs | RL | 1 ,SHE_DRAWING+SHEET.dgn,Design Model;14,SHE-08.ROOF.dgn,Design Model:108879 | A_BSUK_Roofs | New Construction | A-Roofs::A_BSUK_Roofs
A-FloorsSlabs A_BSUK_Slabs | RL | 1 ,SHE_DRAWING+SHEET.dgn,Design Model;14,SHE-08.ROOF.dgn,Design Model:108890 | A_BSUK_Roofs | New Construction | A-Roofs::A_BSUK_Roofs
A-FloorsSlabs A_BSUK_Slabs | RL | 1 ,SHE_DRAWING+SHEET.dgn,Design Model;14,SHE-08.ROOF.dgn,Design Model:108904 | A_BSUK_Roofs | New Construction | A-Roofs::A_BSUK_Roofs
A-FloorsSlabs A_BSUK_Slabs | RL | 1 ,SHE_DRAWING+SHEET.dgn,Design Model;14,SHE-08.ROOF.dgn,Design Model:108918 | A_BSUK_Roofs | New Construction | A-Roofs::A_BSUK_Roofs
A-FloorsSlabs A_BSUK_Slabs | RL | 1 ,SHE_DRAWING+SHEET.dgn,Design Model;14,SHE-08.ROOF.dgn,Design Model:108929 | A_BSUK_Roofs | New Construction | A-Roofs::A_BSUK_Roofs
A-FloorsSlabs A_BSUK_Slabs | RL | 1 ,SHE_DRAWING+SHEET.dgn,Design Model;14,SHE-08.ROOF.dgn,Design Model:108943 | A_BSUK_Roofs | New Construction | A-Roofs::A_BSUK_Roofs
A-FloorsSlabs A_BSUK_Slabs | RL | 1 ,SHE_DRAWING+SHEET.dgn,Design Model;14,SHE-08.ROOF.dgn,Design Model:108954 | A_BSUK_Roofs | New Construction | A-Roofs::A_BSUK_Roofs
A-FloorsSlabs A_BSUK_Slabs | RL | 1 ,SHE_DRAWING+SHEET.dgn,Design Model;14,SHE-08.ROOF.dgn,Design Model:108968 | A_BSUK_Roofs | New Construction | A-Roofs::A_BSUK_Roofs
A-FloorsSlabs A_BSUK_Slabs | RL | 1 ,SHE_DRAWING+SHEET.dgn,Design Model;14,SHE-08.ROOF.dgn,Design Model:108982 | A_BSUK_Roofs | New Construction | A-Roofs::A_BSUK_Roofs
A-FloorsSlabs A_BSUK_Slabs | RL | 1 ,SHE_DRAWING+SHEET.dgn,Design Model;14,SHE-08.ROOF.dgn,Design Model:108993 | A_BSUK_Roofs | New Construction | A-Roofs::A_BSUK_Roofs
A-FloorsSlabs A_BSUK_Slabs | RL | 1 ,SHE_DRAWING+SHEET.dgn,Design Model;14,SHE-08.ROOF.dgn,Design Model:109007 | A_BSUK_Roofs | New Construction | A-Roofs::A_BSUK_Roofs
A-FloorsSlabs A_BSUK_Slabs | RL | 1 ,SHE_DRAWING+SHEET.dgn,Design Model;14,SHE-08.ROOF.dgn,Design Model:109018 | A_BSUK_Roofs | New Construction | A-Roofs::A_BSUK_Roofs
A-FloorsSlabs A_BSUK_Slabs | RL | 1 ,SHE_DRAWING+SHEET.dgn,Design Model;14,SHE-08.ROOF.dgn,Design Model:109032 | A_BSUK_Roofs | New Construction | A-Roofs::A_BSUK_Roofs
A-FloorsSlabs A_BSUK_Slabs | RL | 1 ,SHE_DRAWING+SHEET.dgn,Design Model;14,SHE-08.ROOF.dgn,Design Model:109043 | A_BSUK_Roofs | New Construction | A-Roofs::A_BSUK_Roofs
A-FloorsSlabs A_BSUK_Slabs | RL | 1 ,SHE_DRAWING+SHEET.dgn,Design Model;14,SHE-08.ROOF.dgn,Design Model:109057 | A_BSUK_Roofs | New Construction | A-Roofs::A_BSUK_Roofs
A-FloorsSlabs A_BSUK_Slabs | RL | 1 ,SHE_DRAWING+SHEET.dgn,Design Model;14,SHE-08.ROOF.dgn,Design Model:109071 | A_BSUK_Roofs | New Construction | A-Roofs::A_BSUK_Roofs
A-FloorsSlabs A_BSUK_Slabs | RL | 1 ,SHE_DRAWING+SHEET.dgn,Design Model;14,SHE-08.ROOF.dgn,Design Model:109085 | A_BSUK_Roofs | New Construction | A-Roofs::A_BSUK_Roofs
A-FloorsSlabs A_BSUK_Slabs | RL | 1 ,SHE_DRAWING+SHEET.dgn,Design Model;14,SHE-08.ROOF.dgn,Design Model:109099 | A_BSUK_Roofs | New Construction | A-Roofs::A_BSUK_Roofs
A-FloorsSlabs A_BSUK_Slabs | RL | 1 ,SHE_DRAWING+SHEET.dgn,Design Model;14,SHE-08.ROOF.dgn,Design Model:109110 | A_BSUK_Roofs | New Construction | A-Roofs::A_BSUK_Roofs
A-FloorsSlabs A_BSUK_Slabs | RL | 1 ,SHE_DRAWING+SHEET.dgn,Design Model;14,SHE-08.ROOF.dgn,Design Model:109124 | A_BSUK_Roofs | New Construction | A-Roofs::A_BSUK_Roofs
A-FloorsSlabs A_BSUK_Slabs | RL | 1 ,SHE_DRAWING+SHEET.dgn,Design Model;14,SHE-08.ROOF.dgn,Design Model:109138 | A_BSUK_Roofs | New Construction | A-Roofs::A_BSUK_Roofs
A-FloorsSlabs A_BSUK_Slabs | RL | 1 ,SHE_DRAWING+SHEET.dgn,Design Model;14,SHE-08.ROOF.dgn,Design Model:109149 | A_BSUK_Roofs | New Construction | A-Roofs::A_BSUK_Roofs
A-FloorsSlabs A_BSUK_Slabs | RL | 1 ,SHE_DRAWING+SHEET.dgn,Design Model;14,SHE-08.ROOF.dgn,Design Model:109164 | A_BSUK_Roofs | New Construction | A-Roofs::A_BSUK_Roofs
A-FloorsSlabs A_BSUK_Slabs | RL | 1 ,SHE_DRAWING+SHEET.dgn,Design Model;14,SHE-08.ROOF.dgn,Design Model:109175 | A_BSUK_Roofs | New Construction | A-Roofs::A_BSUK_Roofs
A-FloorsSlabs A_BSUK_Slabs | RL | 1 ,SHE_DRAWING+SHEET.dgn,Design Model;14,SHE-08.ROOF.dgn,Design Model:109190 | A_BSUK_Roofs | New Construction | A-Roofs::A_BSUK_Roofs
A-FloorsSlabs A_BSUK_Slabs | RL | 1 ,SHE_DRAWING+SHEET.dgn,Design Model;14,SHE-08.ROOF.dgn,Design Model:109201 | A_BSUK_Roofs | New Construction | A-Roofs::A_BSUK_Roofs
A-FloorsSlabs A_BSUK_Slabs | RL | 1 ,SHE_DRAWING+SHEET.dgn,Design Model;14,SHE-08.ROOF.dgn,Design Model:109215 | A_BSUK_Roofs | New Construction | A-Roofs::A_BSUK_Roofs
A-FloorsSlabs A_BSUK_Slabs | RL | 1 ,SHE_DRAWING+SHEET.dgn,Design Model;14,SHE-08.ROOF.dgn,Design Model:109229 | A_BSUK_Roofs | New Construction | A-Roofs::A_BSUK_Roofs
A-FloorsSlabs A_BSUK_Slabs | RL | 1 ,SHE_DRAWING+SHEET.dgn,Design Model;14,SHE-08.ROOF.dgn,Design Model:109243 | A_BSUK_Roofs | New Construction | A-Roofs::A_BSUK_Roofs
A-FloorsSlabs A_BSUK_Slabs | RL | 1 ,SHE_DRAWING+SHEET.dgn,Design Model;14,SHE-08.ROOF.dgn,Design Model:109254 | A_BSUK_Roofs | New Construction | A-Roofs::A_BSUK_Roofs
A-FloorsSlabs A_BSUK_Slabs | RL | 1 ,SHE_DRAWING+SHEET.dgn,Design Model;14,SHE-08.ROOF.dgn,Design Model:109268 | A_BSUK_Roofs | New Construction | A-Roofs::A_BSUK_Roofs
A-FloorsSlabs A_BSUK_Slabs | RL | 1 ,SHE_DRAWING+SHEET.dgn,Design Model;14,SHE-08.ROOF.dgn,Design Model:109279 | A_BSUK_Roofs | New Construction | A-Roofs::A_BSUK_Roofs
A-FloorsSlabs A_BSUK_Slabs | RL | 1 ,SHE_DRAWING+SHEET.dgn,Design Model;14,SHE-08.ROOF.dgn,Design Model:109293 | A_BSUK_Roofs | New Construction | A-Roofs::A_BSUK_Roofs
A-FloorsSlabs A_BSUK_Slabs | RL | 1 ,SHE_DRAWING+SHEET.dgn,Design Model;14,SHE-08.ROOF.dgn,Design Model:109304 | A_BSUK_Roofs | New Construction | A-Roofs::A_BSUK_Roofs
A-FloorsSlabs A_BSUK_Slabs | RL | 1 ,SHE_DRAWING+SHEET.dgn,Design Model;14,SHE-08.ROOF.dgn,Design Model:109318 | A_BSUK_Roofs | New Construction | A-Roofs::A_BSUK_Roofs
A-FloorsSlabs A_BSUK_Slabs | RL | 1 ,SHE_DRAWING+SHEET.dgn,Design Model;14,SHE-08.ROOF.dgn,Design Model:109332 | A_BSUK_Roofs | New Construction | A-Roofs::A_BSUK_Roofs
A-FloorsSlabs A_BSUK_Slabs | RL | 1 ,SHE_DRAWING+SHEET.dgn,Design Model;14,SHE-08.ROOF.dgn,Design Model:109347 | A_BSUK_Roofs | New Construction | A-Roofs::A_BSUK_Roofs
A-FloorsSlabs A_BSUK_Slabs | RL | 1 ,SHE_DRAWING+SHEET.dgn,Design Model;14,SHE-08.ROOF.dgn,Design Model:109373 | A_BSUK_Roofs | New Construction | A-Roofs::A_BSUK_Roofs
A-FloorsSlabs A_BSUK_Slabs | RL | 1 ,SHE_DRAWING+SHEET.dgn,Design Model;14,SHE-08.ROOF.dgn,Design Model:109389 | A_BSUK_Roofs | New Construction | A-Roofs::A_BSUK_Roofs
A-FloorsSlabs A_BSUK_Slabs | RL | 1 ,SHE_DRAWING+SHEET.dgn,Design Model;14,SHE-08.ROOF.dgn,Design Model:109400 | A_BSUK_Roofs | New Construction | A-Roofs::A_BSUK_Roofs
A-FloorsSlabs A_BSUK_Slabs | RL | 1 ,SHE_DRAWING+SHEET.dgn,Design Model;14,SHE-08.ROOF.dgn,Design Model:109415 | A_BSUK_Roofs | New Construction | A-Roofs::A_BSUK_Roofs
A-FloorsSlabs A_BSUK_Slabs | RL | 1 ,SHE_DRAWING+SHEET.dgn,Design Model;14,SHE-08.ROOF.dgn,Design Model:109426 | A_BSUK_Roofs | New Construction | A-Roofs::A_BSUK_Roofs
A-FloorsSlabs A_BSUK_Slabs | RL | 1 ,SHE_DRAWING+SHEET.dgn,Design Model;14,SHE-08.ROOF.dgn,Design Model:109441 | A_BSUK_Roofs | New Construction | A-Roofs::A_BSUK_Roofs
A-FloorsSlabs A_BSUK_Slabs | RL | 1 ,SHE_DRAWING+SHEET.dgn,Design Model;14,SHE-08.ROOF.dgn,Design Model:109466 | A_BSUK_Roofs | New Construction | A-Roofs::A_BSUK_Roofs
A-FloorsSlabs A_BSUK_Slabs | RL | 1 ,SHE_DRAWING+SHEET.dgn,Design Model;14,SHE-08.ROOF.dgn,Design Model:109492 | A_BSUK_Roofs | New Construction | A-Roofs::A_BSUK_Roofs
A-FloorsSlabs A_BSUK_Slabs | RL | 1 ,SHE_DRAWING+SHEET.dgn,Design Model;14,SHE-08.ROOF.dgn,Design Model:109518 | A_BSUK_Roofs | New Construction | A-Roofs::A_BSUK_Roofs
A-FloorsSlabs A_BSUK_Slabs | RL | 1 ,SHE_DRAWING+SHEET.dgn,Design Model;14,SHE-08.ROOF.dgn,Design Model:109544 | A_BSUK_Roofs | New Construction | A-Roofs::A_BSUK_Roofs
A-FloorsSlabs A_BSUK_Slabs | RL | 1 ,SHE_DRAWING+SHEET.dgn,Design Model;14,SHE-08.ROOF.dgn,Design Model:109555 | A_BSUK_Roofs | New Construction | A-Roofs::A_BSUK_Roofs
A-FloorsSlabs A_BSUK_Slabs | RL | 1 ,SHE_DRAWING+SHEET.dgn,Design Model;14,SHE-08.ROOF.dgn,Design Model:109569 | A_BSUK_Roofs | New Construction | A-Roofs::A_BSUK_Roofs
A-FloorsSlabs A_BSUK_Slabs | RL | 1 ,SHE_DRAWING+SHEET.dgn,Design Model;14,SHE-08.ROOF.dgn,Design Model:109580 | A_BSUK_Roofs | New Construction | A-Roofs::A_BSUK_Roofs
A-FloorsSlabs A_BSUK_Slabs | RL | 1 ,SHE_DRAWING+SHEET.dgn,Design Model;14,SHE-08.ROOF.dgn,Design Model:109609 | A_BSUK_Roofs | New Construction | A-Roofs::A_BSUK_Roofs
A-FloorsSlabs A_BSUK_Slabs | RL | 1 ,SHE_DRAWING+SHEET.dgn,Design Model;14,SHE-08.ROOF.dgn,Design Model:109620 | A_BSUK_Roofs | New Construction | A-Roofs::A_BSUK_Roofs
A-FloorsSlabs A_BSUK_Slabs | RL | 1 ,SHE_DRAWING+SHEET.dgn,Design Model;14,SHE-08.ROOF.dgn,Design Model:109634 | A_BSUK_Roofs | New Construction | A-Roofs::A_BSUK_Roofs
A-FloorsSlabs A_BSUK_Slabs | RL | 1 ,SHE_DRAWING+SHEET.dgn,Design Model;14,SHE-08.ROOF.dgn,Design Model:109645 | A_BSUK_Roofs | New Construction | A-Roofs::A_BSUK_Roofs
A-FloorsSlabs A_BSUK_Slabs | RL | 1 ,SHE_DRAWING+SHEET.dgn,Design Model;14,SHE-08.ROOF.dgn,Design Model:109674 | A_BSUK_Roofs | New Construction | A-Roofs::A_BSUK_Roofs
A-FloorsSlabs A_BSUK_Slabs | RL | 1 ,SHE_DRAWING+SHEET.dgn,Design Model;14,SHE-08.ROOF.dgn,Design Model:109685 | A_BSUK_Roofs | New Construction | A-Roofs::A_BSUK_Roofs
A-FloorsSlabs A_BSUK_Slabs | RL | 1 ,SHE_DRAWING+SHEET.dgn,Design Model;14,SHE-08.ROOF.dgn,Design Model:109714 | A_BSUK_Roofs | New Construction | A-Roofs::A_BSUK_Roofs
A-FloorsSlabs A_BSUK_Slabs | RL | 1 ,SHE_DRAWING+SHEET.dgn,Design Model;14,SHE-08.ROOF.dgn,Design Model:109726 | A_BSUK_Roofs | New Construction | A-Roofs::A_BSUK_Roofs
A-FloorsSlabs A_BSUK_Slabs | RL | 1 ,SHE_DRAWING+SHEET.dgn,Design Model;14,SHE-08.ROOF.dgn,Design Model:109740 | A_BSUK_Roofs | New Construction | A-Roofs::A_BSUK_Roofs
A-FloorsSlabs A_BSUK_Slabs | RL | 1 ,SHE_DRAWING+SHEET.dgn,Design Model;14,SHE-08.ROOF.dgn,Design Model:109754 | A_BSUK_Roofs | New Construction | A-Roofs::A_BSUK_Roofs
A-FloorsSlabs A_BSUK_Slabs | RL | 1 ,SHE_DRAWING+SHEET.dgn,Design Model;14,SHE-08.ROOF.dgn,Design Model:109768 | A_BSUK_Roofs | New Construction | A-Roofs::A_BSUK_Roofs
A-FloorsSlabs A_BSUK_Slabs | RL | 1 ,SHE_DRAWING+SHEET.dgn,Design Model;14,SHE-08.ROOF.dgn,Design Model:109796 | A_BSUK_Roofs | New Construction | A-Roofs::A_BSUK_Roofs
A-FloorsSlabs A_BSUK_Slabs | RL | 1 ,SHE_DRAWING+SHEET.dgn,Design Model;14,SHE-08.ROOF.dgn,Design Model:109807 | A_BSUK_Roofs | New Construction | A-Roofs::A_BSUK_Roofs
A-FloorsSlabs A_BSUK_Slabs | RL | 1 ,SHE_DRAWING+SHEET.dgn,Design Model;14,SHE-08.ROOF.dgn,Design Model:109836 | A_BSUK_Roofs | New Construction | A-Roofs::A_BSUK_Roofs
A-FloorsSlabs A_BSUK_Slabs | RL | 1 ,SHE_DRAWING+SHEET.dgn,Design Model;14,SHE-08.ROOF.dgn,Design Model:109847 | A_BSUK_Roofs | New Construction | A-Roofs::A_BSUK_Roofs
A-FloorsSlabs A_BSUK_Slabs | RL | 1 ,SHE_DRAWING+SHEET.dgn,Design Model;14,SHE-08.ROOF.dgn,Design Model:109861 | A_BSUK_Roofs | New Construction | A-Roofs::A_BSUK_Roofs
A-FloorsSlabs A_BSUK_Slabs | RL | 1 ,SHE_DRAWING+SHEET.dgn,Design Model;14,SHE-08.ROOF.dgn,Design Model:109872 | A_BSUK_Roofs | New Construction | A-Roofs::A_BSUK_Roofs
A-FloorsSlabs A_BSUK_Slabs | RL | 1 ,SHE_DRAWING+SHEET.dgn,Design Model;14,SHE-08.ROOF.dgn,Design Model:109901 | A_BSUK_Roofs | New Construction | A-Roofs::A_BSUK_Roofs
A-FloorsSlabs A_BSUK_Slabs | RL | 1 ,SHE_DRAWING+SHEET.dgn,Design Model;14,SHE-08.ROOF.dgn,Design Model:109912 | A_BSUK_Roofs | New Construction | A-Roofs::A_BSUK_Roofs
A-FloorsSlabs A_BSUK_Slabs | RL | 1 ,SHE_DRAWING+SHEET.dgn,Design Model;14,SHE-08.ROOF.dgn,Design Model:109926 | A_BSUK_Roofs | New Construction | A-Roofs::A_BSUK_Roofs
A-FloorsSlabs A_BSUK_Slabs | RL | 1 ,SHE_DRAWING+SHEET.dgn,Design Model;14,SHE-08.ROOF.dgn,Design Model:109937 | A_BSUK_Roofs | New Construction | A-Roofs::A_BSUK_Roofs
A-FloorsSlabs A_BSUK_Slabs | RL | 1 ,SHE_DRAWING+SHEET.dgn,Design Model;14,SHE-08.ROOF.dgn,Design Model:109966 | A_BSUK_Roofs | New Construction | A-Roofs::A_BSUK_Roofs
A-FloorsSlabs A_BSUK_Slabs | RL | 1 ,SHE_DRAWING+SHEET.dgn,Design Model;14,SHE-08.ROOF.dgn,Design Model:109978 | A_BSUK_Roofs | New Construction | A-Roofs::A_BSUK_Roofs
A-FloorsSlabs A_BSUK_Slabs | RL | 1 ,SHE_DRAWING+SHEET.dgn,Design Model;14,SHE-08.ROOF.dgn,Design Model:110006 | A_BSUK_Roofs | New Construction | A-Roofs::A_BSUK_Roofs
A-FloorsSlabs A_BSUK_Slabs | RL | 1 ,SHE_DRAWING+SHEET.dgn,Design Model;14,SHE-08.ROOF.dgn,Design Model:110018 | A_BSUK_Roofs | New Construction | A-Roofs::A_BSUK_Roofs
A-FloorsSlabs A_BSUK_Slabs | RL | 1 ,SHE_DRAWING+SHEET.dgn,Design Model;14,SHE-08.ROOF.dgn,Design Model:110046 | A_BSUK_Roofs | New Construction | A-Roofs::A_BSUK_Roofs
A-FloorsSlabs A_BSUK_Slabs | RL | 1 ,SHE_DRAWING+SHEET.dgn,Design Model;14,SHE-08.ROOF.dgn,Design Model:110058 | A_BSUK_Roofs | New Construction | A-Roofs::A_BSUK_Roofs
A-FloorsSlabs A_BSUK_Slabs | RL | 1 ,SHE_DRAWING+SHEET.dgn,Design Model;14,SHE-08.ROOF.dgn,Design Model:110087 | A_BSUK_Roofs | New Construction | A-Roofs::A_BSUK_Roofs
A-FloorsSlabs A_BSUK_Slabs | RL | 1 ,SHE_DRAWING+SHEET.dgn,Design Model;14,SHE-08.ROOF.dgn,Design Model:110103 | A_BSUK_Roofs | New Construction | A-Roofs::A_BSUK_Roofs
A-FloorsSlabs A_BSUK_Slabs | RL | 1 ,SHE_DRAWING+SHEET.dgn,Design Model;14,SHE-08.ROOF.dgn,Design Model:110114 | A_BSUK_Roofs | New Construction | A-Roofs::A_BSUK_Roofs
A-FloorsSlabs A_BSUK_Slabs | RL | 1 ,SHE_DRAWING+SHEET.dgn,Design Model;14,SHE-08.ROOF.dgn,Design Model:110129 | A_BSUK_Roofs | New Construction | A-Roofs::A_BSUK_Roofs
A-FloorsSlabs A_BSUK_Slabs | RL | 1 ,SHE_DRAWING+SHEET.dgn,Design Model;14,SHE-08.ROOF.dgn,Design Model:110140 | A_BSUK_Roofs | New Construction | A-Roofs::A_BSUK_Roofs
A-FloorsSlabs A_BSUK_Slabs | RL | 1 ,SHE_DRAWING+SHEET.dgn,Design Model;14,SHE-08.ROOF.dgn,Design Model:110154 | A_BSUK_Roofs | New Construction | A-Roofs::A_BSUK_Roofs
A-FloorsSlabs A_BSUK_Slabs | RL | 1 ,SHE_DRAWING+SHEET.dgn,Design Model;14,SHE-08.ROOF.dgn,Design Model:110165 | A_BSUK_Roofs | New Construction | A-Roofs::A_BSUK_Roofs
A-FloorsSlabs A_BSUK_Slabs | RL | 1 ,SHE_DRAWING+SHEET.dgn,Design Model;14,SHE-08.ROOF.dgn,Design Model:110179 | A_BSUK_Roofs | New Construction | A-Roofs::A_BSUK_Roofs
A-FloorsSlabs A_BSUK_Slabs | RL | 1 ,SHE_DRAWING+SHEET.dgn,Design Model;14,SHE-08.ROOF.dgn,Design Model:110194 | A_BSUK_Roofs | New Construction | A-Roofs::A_BSUK_Roofs
A-FloorsSlabs A_BSUK_Slabs | RL | 1 ,SHE_DRAWING+SHEET.dgn,Design Model;14,SHE-08.ROOF.dgn,Design Model:110205 | A_BSUK_Roofs | New Construction | A-Roofs::A_BSUK_Roofs
A-FloorsSlabs A_BSUK_Slabs | RL | 1 ,SHE_DRAWING+SHEET.dgn,Design Model;14,SHE-08.ROOF.dgn,Design Model:110219 | A_BSUK_Roofs | New Construction | A-Roofs::A_BSUK_Roofs
A-FloorsSlabs A_BSUK_Slabs | RL | 1 ,SHE_DRAWING+SHEET.dgn,Design Model;14,SHE-08.ROOF.dgn,Design Model:110230 | A_BSUK_Roofs | New Construction | A-Roofs::A_BSUK_Roofs
A-FloorsSlabs A_BSUK_Slabs | RL | 1 ,SHE_DRAWING+SHEET.dgn,Design Model;14,SHE-08.ROOF.dgn,Design Model:110245 | A_BSUK_Roofs | New Construction | A-Roofs::A_BSUK_Roofs
A-FloorsSlabs A_BSUK_Slabs | RL | 1 ,SHE_DRAWING+SHEET.dgn,Design Model;14,SHE-08.ROOF.dgn,Design Model:110256 | A_BSUK_Roofs | New Construction | A-Roofs::A_BSUK_Roofs
A-FloorsSlabs A_BSUK_Slabs | RL | 1 ,SHE_DRAWING+SHEET.dgn,Design Model;14,SHE-08.ROOF.dgn,Design Model:110271 | A_BSUK_Roofs | New Construction | A-Roofs::A_BSUK_Roofs
A-FloorsSlabs A_BSUK_Slabs | RL | 1 ,SHE_DRAWING+SHEET.dgn,Design Model;14,SHE-08.ROOF.dgn,Design Model:110282 | A_BSUK_Roofs | New Construction | A-Roofs::A_BSUK_Roofs
A-FloorsSlabs A_BSUK_Slabs | RL | 1 ,SHE_DRAWING+SHEET.dgn,Design Model;14,SHE-08.ROOF.dgn,Design Model:110296 | A_BSUK_Roofs | New Construction | A-Roofs::A_BSUK_Roofs
A-FloorsSlabs A_BSUK_Slabs | RL | 1 ,SHE_DRAWING+SHEET.dgn,Design Model;14,SHE-08.ROOF.dgn,Design Model:110310 | A_BSUK_Roofs | New Construction | A-Roofs::A_BSUK_Roofs
A-FloorsSlabs A_BSUK_Slabs | RL | 1 ,SHE_DRAWING+SHEET.dgn,Design Model;14,SHE-08.ROOF.dgn,Design Model:110324 | A_BSUK_Roofs | New Construction | A-Roofs::A_BSUK_Roofs
A-FloorsSlabs A_BSUK_Slabs | RL | 1 ,SHE_DRAWING+SHEET.dgn,Design Model;14,SHE-08.ROOF.dgn,Design Model:110335 | A_BSUK_Roofs | New Construction | A-Roofs::A_BSUK_Roofs
A-FloorsSlabs A_BSUK_Slabs | RL | 1 ,SHE_DRAWING+SHEET.dgn,Design Model;14,SHE-08.ROOF.dgn,Design Model:110349 | A_BSUK_Roofs | New Construction | A-Roofs::A_BSUK_Roofs
A-FloorsSlabs A_BSUK_Slabs | RL | 1 ,SHE_DRAWING+SHEET.dgn,Design Model;14,SHE-08.ROOF.dgn,Design Model:110360 | A_BSUK_Roofs | New Construction | A-Roofs::A_BSUK_Roofs
A-FloorsSlabs A_BSUK_Slabs | RL | 1 ,SHE_DRAWING+SHEET.dgn,Design Model;14,SHE-08.ROOF.dgn,Design Model:110374 | A_BSUK_Roofs | New Construction | A-Roofs::A_BSUK_Roofs
A-FloorsSlabs A_BSUK_Slabs | RL | 1 ,SHE_DRAWING+SHEET.dgn,Design Model;14,SHE-08.ROOF.dgn,Design Model:110389 | A_BSUK_Roofs | New Construction | A-Roofs::A_BSUK_Roofs
A-FloorsSlabs A_BSUK_Slabs | RL | 1 ,SHE_DRAWING+SHEET.dgn,Design Model;14,SHE-08.ROOF.dgn,Design Model:110400 | A_BSUK_Roofs | New Construction | A-Roofs::A_BSUK_Roofs
A-FloorsSlabs A_BSUK_Slabs | RL | 1 ,SHE_DRAWING+SHEET.dgn,Design Model;14,SHE-08.ROOF.dgn,Design Model:110414 | A_BSUK_Roofs | New Construction | A-Roofs::A_BSUK_Roofs
A-FloorsSlabs A_BSUK_Slabs | RL | 1 ,SHE_DRAWING+SHEET.dgn,Design Model;14,SHE-08.ROOF.dgn,Design Model:110425 | A_BSUK_Roofs | New Construction | A-Roofs::A_BSUK_Roofs
A-FloorsSlabs A_BSUK_Slabs | RL | 1 ,SHE_DRAWING+SHEET.dgn,Design Model;14,SHE-08.ROOF.dgn,Design Model:110439 | A_BSUK_Roofs | New Construction | A-Roofs::A_BSUK_Roofs
A-FloorsSlabs A_BSUK_Slabs | RL | 1 ,SHE_DRAWING+SHEET.dgn,Design Model;14,SHE-08.ROOF.dgn,Design Model:110453 | A_BSUK_Roofs | New Construction | A-Roofs::A_BSUK_Roofs
A-FloorsSlabs A_BSUK_Slabs | RL | 1 ,SHE_DRAWING+SHEET.dgn,Design Model;14,SHE-08.ROOF.dgn,Design Model:110468 | A_BSUK_Roofs | New Construction | A-Roofs::A_BSUK_Roofs
A-FloorsSlabs A_BSUK_Slabs | RL | 1 ,SHE_DRAWING+SHEET.dgn,Design Model;14,SHE-08.ROOF.dgn,Design Model:110479 | A_BSUK_Roofs | New Construction | A-Roofs::A_BSUK_Roofs
A-FloorsSlabs A_BSUK_Slabs | RL | 1 ,SHE_DRAWING+SHEET.dgn,Design Model;14,SHE-08.ROOF.dgn,Design Model:110493 | A_BSUK_Roofs | New Construction | A-Roofs::A_BSUK_Roofs
A-FloorsSlabs A_BSUK_Slabs | RL | 1 ,SHE_DRAWING+SHEET.dgn,Design Model;14,SHE-08.ROOF.dgn,Design Model:110504 | A_BSUK_Roofs | New Construction | A-Roofs::A_BSUK_Roofs
A-FloorsSlabs A_BSUK_Slabs | RL | 1 ,SHE_DRAWING+SHEET.dgn,Design Model;14,SHE-08.ROOF.dgn,Design Model:110519 | A_BSUK_Roofs | New Construction | A-Roofs::A_BSUK_Roofs
A-FloorsSlabs A_BSUK_Slabs | RL | 1 ,SHE_DRAWING+SHEET.dgn,Design Model;14,SHE-08.ROOF.dgn,Design Model:110530 | A_BSUK_Roofs | New Construction | A-Roofs::A_BSUK_Roofs
A-FloorsSlabs A_BSUK_Slabs | RL | 1 ,SHE_DRAWING+SHEET.dgn,Design Model;14,SHE-08.ROOF.dgn,Design Model:110545 | A_BSUK_Roofs | New Construction | A-Roofs::A_BSUK_Roofs
A-FloorsSlabs A_BSUK_Slabs | RL | 1 ,SHE_DRAWING+SHEET.dgn,Design Model;14,SHE-08.ROOF.dgn,Design Model:110556 | A_BSUK_Roofs | New Construction | A-Roofs::A_BSUK_Roofs
A-FloorsSlabs A_BSUK_Slabs | RL | 1 ,SHE_DRAWING+SHEET.dgn,Design Model;14,SHE-08.ROOF.dgn,Design Model:110570 | A_BSUK_Roofs | New Construction | A-Roofs::A_BSUK_Roofs
A-FloorsSlabs A_BSUK_Slabs | RL | 1 ,SHE_DRAWING+SHEET.dgn,Design Model;14,SHE-08.ROOF.dgn,Design Model:110584 | A_BSUK_Roofs | New Construction | A-Roofs::A_BSUK_Roofs
A-FloorsSlabs A_BSUK_Slabs | RL | 1 ,SHE_DRAWING+SHEET.dgn,Design Model;14,SHE-08.ROOF.dgn,Design Model:110598 | A_BSUK_Roofs | New Construction | A-Roofs::A_BSUK_Roofs
A-FloorsSlabs A_BSUK_Slabs | RL | 1 ,SHE_DRAWING+SHEET.dgn,Design Model;14,SHE-08.ROOF.dgn,Design Model:110609 | A_BSUK_Roofs | New Construction | A-Roofs::A_BSUK_Roofs
A-FloorsSlabs A_BSUK_Slabs | RL | 1 ,SHE_DRAWING+SHEET.dgn,Design Model;14,SHE-08.ROOF.dgn,Design Model:110623 | A_BSUK_Roofs | New Construction | A-Roofs::A_BSUK_Roofs
A-FloorsSlabs A_BSUK_Slabs | RL | 1 ,SHE_DRAWING+SHEET.dgn,Design Model;14,SHE-08.ROOF.dgn,Design Model:110634 | A_BSUK_Roofs | New Construction | A-Roofs::A_BSUK_Roofs
A-FloorsSlabs A_BSUK_Slabs | RL | 1 ,SHE_DRAWING+SHEET.dgn,Design Model;14,SHE-08.ROOF.dgn,Design Model:110648 | A_BSUK_Roofs | New Construction | A-Roofs::A_BSUK_Roofs
A-FloorsSlabs A_BSUK_Slabs | RL | 1 ,SHE_DRAWING+SHEET.dgn,Design Model;14,SHE-08.ROOF.dgn,Design Model:110663 | A_BSUK_Roofs | New Construction | A-Roofs::A_BSUK_Roofs
A-FloorsSlabs A_BSUK_Slabs | RL | 1 ,SHE_DRAWING+SHEET.dgn,Design Model;14,SHE-08.ROOF.dgn,Design Model:110674 | A_BSUK_Roofs | New Construction | A-Roofs::A_BSUK_Roofs
A-FloorsSlabs A_BSUK_Slabs | RL | 1 ,SHE_DRAWING+SHEET.dgn,Design Model;14,SHE-08.ROOF.dgn,Design Model:110688 | A_BSUK_Roofs | New Construction | A-Roofs::A_BSUK_Roofs
A-FloorsSlabs A_BSUK_Slabs | RL | 1 ,SHE_DRAWING+SHEET.dgn,Design Model;14,SHE-08.ROOF.dgn,Design Model:110699 | A_BSUK_Roofs | New Construction | A-Roofs::A_BSUK_Roofs
A-FloorsSlabs A_BSUK_Slabs | RL | 1 ,SHE_DRAWING+SHEET.dgn,Design Model;14,SHE-08.ROOF.dgn,Design Model:110713 | A_BSUK_Roofs | New Construction | A-Roofs::A_BSUK_Roofs
A-FloorsSlabs A_BSUK_Slabs | RL | 1 ,SHE_DRAWING+SHEET.dgn,Design Model;14,SHE-08.ROOF.dgn,Design Model:110727 | A_BSUK_Roofs | New Construction | A-Roofs::A_BSUK_Roofs
A-FloorsSlabs A_BSUK_Slabs | RL | 1 ,SHE_DRAWING+SHEET.dgn,Design Model;14,SHE-08.ROOF.dgn,Design Model:110738 | A_BSUK_Roofs | New Construction | A-Roofs::A_BSUK_Roofs
A-FloorsSlabs A_BSUK_Slabs | RL | 1 ,SHE_DRAWING+SHEET.dgn,Design Model;14,SHE-08.ROOF.dgn,Design Model:110753 | A_BSUK_Roofs | New Construction | A-Roofs::A_BSUK_Roofs
A-FloorsSlabs A_BSUK_Slabs | RL | 1 ,SHE_DRAWING+SHEET.dgn,Design Model;14,SHE-08.ROOF.dgn,Design Model:110767 | A_BSUK_Roofs | New Construction | A-Roofs::A_BSUK_Roofs
A-FloorsSlabs A_BSUK_Slabs | RL | 1 ,SHE_DRAWING+SHEET.dgn,Design Model;14,SHE-08.ROOF.dgn,Design Model:110778 | A_BSUK_Roofs | New Construction | A-Roofs::A_BSUK_Roofs
A-FloorsSlabs A_BSUK_Slabs | RL | 1 ,SHE_DRAWING+SHEET.dgn,Design Model;14,SHE-08.ROOF.dgn,Design Model:110792 | A_BSUK_Roofs | New Construction | A-Roofs::A_BSUK_Roofs
A-FloorsSlabs A_BSUK_Slabs | RL | 1 ,SHE_DRAWING+SHEET.dgn,Design Model;14,SHE-08.ROOF.dgn,Design Model:110803 | A_BSUK_Roofs | New Construction | A-Roofs::A_BSUK_Roofs
A-FloorsSlabs A_BSUK_Slabs | RL | 1 ,SHE_DRAWING+SHEET.dgn,Design Model;14,SHE-08.ROOF.dgn,Design Model:110818 | A_BSUK_Roofs | New Construction | A-Roofs::A_BSUK_Roofs
A-FloorsSlabs A_BSUK_Slabs | RL | 1 ,SHE_DRAWING+SHEET.dgn,Design Model;14,SHE-08.ROOF.dgn,Design Model:110832 | A_BSUK_Roofs | New Construction | A-Roofs::A_BSUK_Roofs
A-FloorsSlabs A_BSUK_Slabs | RL | 1 ,SHE_DRAWING+SHEET.dgn,Design Model;14,SHE-08.ROOF.dgn,Design Model:110843 | A_BSUK_Roofs | New Construction | A-Roofs::A_BSUK_Roofs
A-FloorsSlabs A_BSUK_Slabs | RL | 1 ,SHE_DRAWING+SHEET.dgn,Design Model;14,SHE-08.ROOF.dgn,Design Model:110857 | A_BSUK_Roofs | New Construction | A-Roofs::A_BSUK_Roofs
A-FloorsSlabs A_BSUK_Slabs | RL | 1 ,SHE_DRAWING+SHEET.dgn,Design Model;14,SHE-08.ROOF.dgn,Design Model:110868 | A_BSUK_Roofs | New Construction | A-Roofs::A_BSUK_Roofs
A-FloorsSlabs A_BSUK_Slabs | RL | 1 ,SHE_DRAWING+SHEET.dgn,Design Model;14,SHE-08.ROOF.dgn,Design Model:110883 | A_BSUK_Roofs | New Construction | A-Roofs::A_BSUK_Roofs
A-FloorsSlabs A_BSUK_Slabs | RL | 1 ,SHE_DRAWING+SHEET.dgn,Design Model;14,SHE-08.ROOF.dgn,Design Model:110897 | A_BSUK_Roofs | New Construction | A-Roofs::A_BSUK_Roofs
A-FloorsSlabs A_BSUK_Slabs | RL | 1 ,SHE_DRAWING+SHEET.dgn,Design Model;14,SHE-08.ROOF.dgn,Design Model:110909 | A_BSUK_Roofs | New Construction | A-Roofs::A_BSUK_Roofs
A-FloorsSlabs A_BSUK_Slabs | RL | 1 ,SHE_DRAWING+SHEET.dgn,Design Model;14,SHE-08.ROOF.dgn,Design Model:110923 | A_BSUK_Roofs | New Construction | A-Roofs::A_BSUK_Roofs
A-FloorsSlabs A_BSUK_Slabs | RL | 1 ,SHE_DRAWING+SHEET.dgn,Design Model;14,SHE-08.ROOF.dgn,Design Model:110937 | A_BSUK_Roofs | New Construction | A-Roofs::A_BSUK_Roofs
A-FloorsSlabs A_BSUK_Slabs | RL | 1 ,SHE_DRAWING+SHEET.dgn,Design Model;14,SHE-08.ROOF.dgn,Design Model:110949 | A_BSUK_Roofs | New Construction | A-Roofs::A_BSUK_Roofs
A-FloorsSlabs A_BSUK_Slabs | RL | 1 ,SHE_DRAWING+SHEET.dgn,Design Model;14,SHE-08.ROOF.dgn,Design Model:110963 | A_BSUK_Roofs | New Construction | A-Roofs::A_BSUK_Roofs
A-FloorsSlabs A_BSUK_Slabs | RL | 1 ,SHE_DRAWING+SHEET.dgn,Design Model;14,SHE-08.ROOF.dgn,Design Model:110977 | A_BSUK_Roofs | New Construction | A-Roofs::A_BSUK_Roofs
A-FloorsSlabs A_BSUK_Slabs | RL | 1 ,SHE_DRAWING+SHEET.dgn,Design Model;14,SHE-08.ROOF.dgn,Design Model:110989 | A_BSUK_Roofs | New Construction | A-Roofs::A_BSUK_Roofs
A-FloorsSlabs A_BSUK_Slabs | RL | 1 ,SHE_DRAWING+SHEET.dgn,Design Model;14,SHE-08.ROOF.dgn,Design Model:111004 | A_BSUK_Roofs | New Construction | A-Roofs::A_BSUK_Roofs
A-FloorsSlabs A_BSUK_Slabs | RL | 1 ,SHE_DRAWING+SHEET.dgn,Design Model;14,SHE-08.ROOF.dgn,Design Model:111018 | A_BSUK_Roofs | New Construction | A-Roofs::A_BSUK_Roofs
A-FloorsSlabs A_BSUK_Slabs | RL | 1 ,SHE_DRAWING+SHEET.dgn,Design Model;14,SHE-08.ROOF.dgn,Design Model:111034 | A_BSUK_Roofs | New Construction | A-Roofs::A_BSUK_Roofs
A-FloorsSlabs A_BSUK_Slabs | RL | 1 ,SHE_DRAWING+SHEET.dgn,Design Model;14,SHE-08.ROOF.dgn,Design Model:111045 | A_BSUK_Roofs | New Construction | A-Roofs::A_BSUK_Roofs
A-FloorsSlabs A_BSUK_Slabs | RL | 1 ,SHE_DRAWING+SHEET.dgn,Design Model;14,SHE-08.ROOF.dgn,Design Model:111060 | A_BSUK_Roofs | New Construction | A-Roofs::A_BSUK_Roofs
A-FloorsSlabs A_BSUK_Slabs | RL | 1 ,SHE_DRAWING+SHEET.dgn,Design Model;14,SHE-08.ROOF.dgn,Design Model:111071 | A_BSUK_Roofs | New Construction | A-Roofs::A_BSUK_Roofs
A-FloorsSlabs A_BSUK_Slabs | RL | 1 ,SHE_DRAWING+SHEET.dgn,Design Model;14,SHE-08.ROOF.dgn,Design Model:111085 | A_BSUK_Roofs | New Construction | A-Roofs::A_BSUK_Roofs
A-FloorsSlabs A_BSUK_Slabs | RL | 1 ,SHE_DRAWING+SHEET.dgn,Design Model;14,SHE-08.ROOF.dgn,Design Model:111096 | A_BSUK_Roofs | New Construction | A-Roofs::A_BSUK_Roofs
A-FloorsSlabs A_BSUK_Slabs | RL | 1 ,SHE_DRAWING+SHEET.dgn,Design Model;14,SHE-08.ROOF.dgn,Design Model:111110 | A_BSUK_Roofs | New Construction | A-Roofs::A_BSUK_Roofs
A-FloorsSlabs A_BSUK_Slabs | RL | 1 ,SHE_DRAWING+SHEET.dgn,Design Model;14,SHE-08.ROOF.dgn,Design Model:111125 | A_BSUK_Roofs | New Construction | A-Roofs::A_BSUK_Roofs
A-FloorsSlabs A_BSUK_Slabs | RL | 1 ,SHE_DRAWING+SHEET.dgn,Design Model;14,SHE-08.ROOF.dgn,Design Model:111136 | A_BSUK_Roofs | New Construction | A-Roofs::A_BSUK_Roofs
A-FloorsSlabs A_BSUK_Slabs | RL | 1 ,SHE_DRAWING+SHEET.dgn,Design Model;14,SHE-08.ROOF.dgn,Design Model:111150 | A_BSUK_Roofs | New Construction | A-Roofs::A_BSUK_Roofs
A-FloorsSlabs A_BSUK_Slabs | RL | 1 ,SHE_DRAWING+SHEET.dgn,Design Model;14,SHE-08.ROOF.dgn,Design Model:111161 | A_BSUK_Roofs | New Construction | A-Roofs::A_BSUK_Roofs
A-FloorsSlabs A_BSUK_Slabs | RL | 1 ,SHE_DRAWING+SHEET.dgn,Design Model;14,SHE-08.ROOF.dgn,Design Model:111176 | A_BSUK_Roofs | New Construction | A-Roofs::A_BSUK_Roofs
A-FloorsSlabs A_BSUK_Slabs | RL | 1 ,SHE_DRAWING+SHEET.dgn,Design Model;14,SHE-08.ROOF.dgn,Design Model:111187 | A_BSUK_Roofs | New Construction | A-Roofs::A_BSUK_Roofs
A-FloorsSlabs A_BSUK_Slabs | RL | 1 ,SHE_DRAWING+SHEET.dgn,Design Model;14,SHE-08.ROOF.dgn,Design Model:111202 | A_BSUK_Roofs | New Construction | A-Roofs::A_BSUK_Roofs
A-FloorsSlabs A_BSUK_Slabs | RL | 1 ,SHE_DRAWING+SHEET.dgn,Design Model;14,SHE-08.ROOF.dgn,Design Model:111213 | A_BSUK_Roofs | New Construction | A-Roofs::A_BSUK_Roofs
A-FloorsSlabs A_BSUK_Slabs | RL | 1 ,SHE_DRAWING+SHEET.dgn,Design Model;14,SHE-08.ROOF.dgn,Design Model:111227 | A_BSUK_Roofs | New Construction | A-Roofs::A_BSUK_Roofs
A-FloorsSlabs A_BSUK_Slabs | RL | 1 ,SHE_DRAWING+SHEET.dgn,Design Model;14,SHE-08.ROOF.dgn,Design Model:111241 | A_BSUK_Roofs | New Construction | A-Roofs::A_BSUK_Roofs
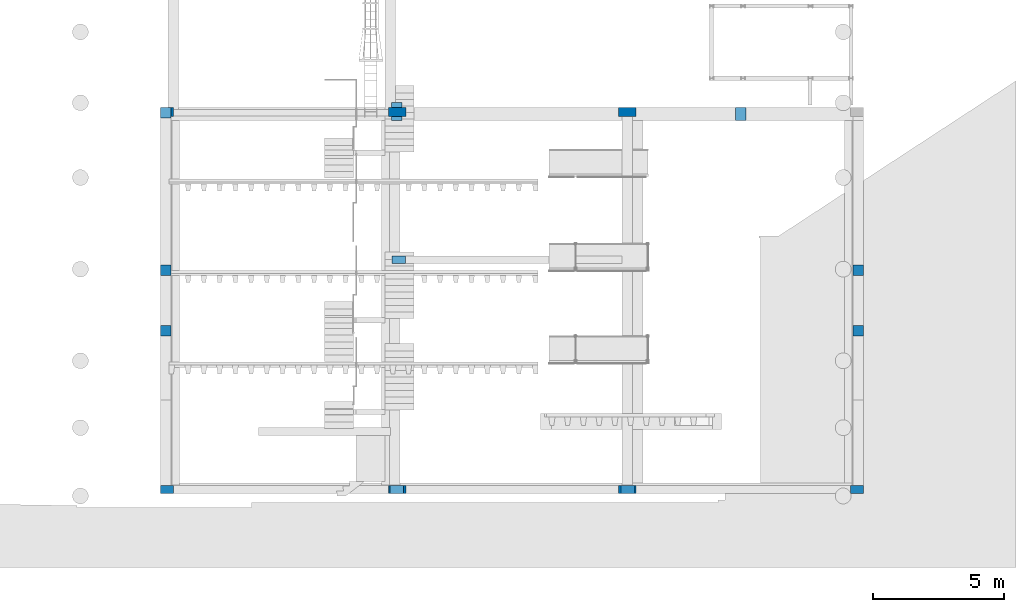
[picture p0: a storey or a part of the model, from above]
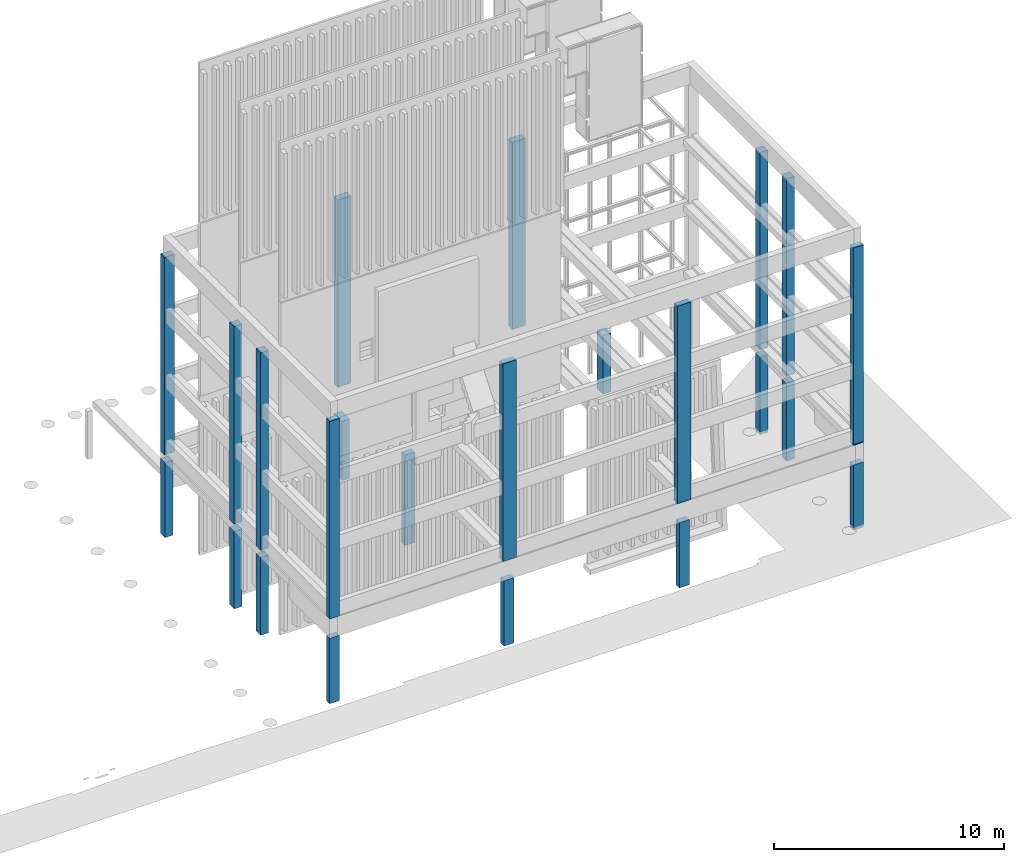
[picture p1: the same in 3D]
Properties of the parts of a building model (IFC2X3), part 11 of 16

# IfcSlab: A-FloorsSlabs A_BSUK_Slabs (1241)
Name | In | Description | Material | Phase | Part Definition
A-FloorsSlabs A_BSUK_Slabs | RL | 1 ,SHE_DRAWING+SHEET.dgn,Design Model;14,SHE-08.ROOF.dgn,Design Model:111255 | A_BSUK_Roofs | New Construction | A-Roofs::A_BSUK_Roofs
A-FloorsSlabs A_BSUK_Slabs | RL | 1 ,SHE_DRAWING+SHEET.dgn,Design Model;14,SHE-08.ROOF.dgn,Design Model:111266 | A_BSUK_Roofs | New Construction | A-Roofs::A_BSUK_Roofs
A-FloorsSlabs A_BSUK_Slabs | RL | 1 ,SHE_DRAWING+SHEET.dgn,Design Model;14,SHE-08.ROOF.dgn,Design Model:111280 | A_BSUK_Roofs | New Construction | A-Roofs::A_BSUK_Roofs
A-FloorsSlabs A_BSUK_Slabs | RL | 1 ,SHE_DRAWING+SHEET.dgn,Design Model;14,SHE-08.ROOF.dgn,Design Model:111291 | A_BSUK_Roofs | New Construction | A-Roofs::A_BSUK_Roofs
A-FloorsSlabs A_BSUK_Slabs | RL | 1 ,SHE_DRAWING+SHEET.dgn,Design Model;14,SHE-08.ROOF.dgn,Design Model:111305 | A_BSUK_Roofs | New Construction | A-Roofs::A_BSUK_Roofs
A-FloorsSlabs A_BSUK_Slabs | RL | 1 ,SHE_DRAWING+SHEET.dgn,Design Model;14,SHE-08.ROOF.dgn,Design Model:111320 | A_BSUK_Roofs | New Construction | A-Roofs::A_BSUK_Roofs
A-FloorsSlabs A_BSUK_Slabs | RL | 1 ,SHE_DRAWING+SHEET.dgn,Design Model;14,SHE-08.ROOF.dgn,Design Model:111331 | A_BSUK_Roofs | New Construction | A-Roofs::A_BSUK_Roofs
A-FloorsSlabs A_BSUK_Slabs | RL | 1 ,SHE_DRAWING+SHEET.dgn,Design Model;14,SHE-08.ROOF.dgn,Design Model:111345 | A_BSUK_Roofs | New Construction | A-Roofs::A_BSUK_Roofs
A-FloorsSlabs A_BSUK_Slabs | RL | 1 ,SHE_DRAWING+SHEET.dgn,Design Model;14,SHE-08.ROOF.dgn,Design Model:111356 | A_BSUK_Roofs | New Construction | A-Roofs::A_BSUK_Roofs
A-FloorsSlabs A_BSUK_Slabs | RL | 1 ,SHE_DRAWING+SHEET.dgn,Design Model;14,SHE-08.ROOF.dgn,Design Model:111370 | A_BSUK_Roofs | New Construction | A-Roofs::A_BSUK_Roofs
A-FloorsSlabs A_BSUK_Slabs | RL | 1 ,SHE_DRAWING+SHEET.dgn,Design Model;14,SHE-08.ROOF.dgn,Design Model:111384 | A_BSUK_Roofs | New Construction | A-Roofs::A_BSUK_Roofs
A-FloorsSlabs A_BSUK_Slabs | RL | 1 ,SHE_DRAWING+SHEET.dgn,Design Model;14,SHE-08.ROOF.dgn,Design Model:111396 | A_BSUK_Roofs | New Construction | A-Roofs::A_BSUK_Roofs
A-FloorsSlabs A_BSUK_Slabs | RL | 1 ,SHE_DRAWING+SHEET.dgn,Design Model;14,SHE-08.ROOF.dgn,Design Model:111424 | A_BSUK_Roofs | New Construction | A-Roofs::A_BSUK_Roofs
A-FloorsSlabs A_BSUK_Slabs | RL | 1 ,SHE_DRAWING+SHEET.dgn,Design Model;14,SHE-08.ROOF.dgn,Design Model:111435 | A_BSUK_Roofs | New Construction | A-Roofs::A_BSUK_Roofs
A-FloorsSlabs A_BSUK_Slabs | RL | 1 ,SHE_DRAWING+SHEET.dgn,Design Model;14,SHE-08.ROOF.dgn,Design Model:111450 | A_BSUK_Roofs | New Construction | A-Roofs::A_BSUK_Roofs
A-FloorsSlabs A_BSUK_Slabs | RL | 1 ,SHE_DRAWING+SHEET.dgn,Design Model;14,SHE-08.ROOF.dgn,Design Model:111464 | A_BSUK_Roofs | New Construction | A-Roofs::A_BSUK_Roofs
A-FloorsSlabs A_BSUK_Slabs | RL | 1 ,SHE_DRAWING+SHEET.dgn,Design Model;14,SHE-08.ROOF.dgn,Design Model:111475 | A_BSUK_Roofs | New Construction | A-Roofs::A_BSUK_Roofs
A-FloorsSlabs A_BSUK_Slabs | RL | 1 ,SHE_DRAWING+SHEET.dgn,Design Model;14,SHE-08.ROOF.dgn,Design Model:111489 | A_BSUK_Roofs | New Construction | A-Roofs::A_BSUK_Roofs
A-FloorsSlabs A_BSUK_Slabs | RL | 1 ,SHE_DRAWING+SHEET.dgn,Design Model;14,SHE-08.ROOF.dgn,Design Model:111500 | A_BSUK_Roofs | New Construction | A-Roofs::A_BSUK_Roofs
A-FloorsSlabs A_BSUK_Slabs | RL | 1 ,SHE_DRAWING+SHEET.dgn,Design Model;14,SHE-08.ROOF.dgn,Design Model:111515 | A_BSUK_Roofs | New Construction | A-Roofs::A_BSUK_Roofs
A-FloorsSlabs A_BSUK_Slabs | RL | 1 ,SHE_DRAWING+SHEET.dgn,Design Model;14,SHE-08.ROOF.dgn,Design Model:111529 | A_BSUK_Roofs | New Construction | A-Roofs::A_BSUK_Roofs
A-FloorsSlabs A_BSUK_Slabs | RL | 1 ,SHE_DRAWING+SHEET.dgn,Design Model;14,SHE-08.ROOF.dgn,Design Model:111540 | A_BSUK_Roofs | New Construction | A-Roofs::A_BSUK_Roofs
A-FloorsSlabs A_BSUK_Slabs | RL | 1 ,SHE_DRAWING+SHEET.dgn,Design Model;14,SHE-08.ROOF.dgn,Design Model:111554 | A_BSUK_Roofs | New Construction | A-Roofs::A_BSUK_Roofs
A-FloorsSlabs A_BSUK_Slabs | RL | 1 ,SHE_DRAWING+SHEET.dgn,Design Model;14,SHE-08.ROOF.dgn,Design Model:111565 | A_BSUK_Roofs | New Construction | A-Roofs::A_BSUK_Roofs
A-FloorsSlabs A_BSUK_Slabs | RL | 1 ,SHE_DRAWING+SHEET.dgn,Design Model;14,SHE-08.ROOF.dgn,Design Model:111580 | A_BSUK_Roofs | New Construction | A-Roofs::A_BSUK_Roofs
A-FloorsSlabs A_BSUK_Slabs | RL | 1 ,SHE_DRAWING+SHEET.dgn,Design Model;14,SHE-08.ROOF.dgn,Design Model:111594 | A_BSUK_Roofs | New Construction | A-Roofs::A_BSUK_Roofs
A-FloorsSlabs A_BSUK_Slabs | RL | 1 ,SHE_DRAWING+SHEET.dgn,Design Model;14,SHE-08.ROOF.dgn,Design Model:111606 | A_BSUK_Roofs | New Construction | A-Roofs::A_BSUK_Roofs
A-FloorsSlabs A_BSUK_Slabs | RL | 1 ,SHE_DRAWING+SHEET.dgn,Design Model;14,SHE-08.ROOF.dgn,Design Model:111620 | A_BSUK_Roofs | New Construction | A-Roofs::A_BSUK_Roofs
A-FloorsSlabs A_BSUK_Slabs | RL | 1 ,SHE_DRAWING+SHEET.dgn,Design Model;14,SHE-08.ROOF.dgn,Design Model:111634 | A_BSUK_Roofs | New Construction | A-Roofs::A_BSUK_Roofs
A-FloorsSlabs A_BSUK_Slabs | RL | 1 ,SHE_DRAWING+SHEET.dgn,Design Model;14,SHE-08.ROOF.dgn,Design Model:111646 | A_BSUK_Roofs | New Construction | A-Roofs::A_BSUK_Roofs
A-FloorsSlabs A_BSUK_Slabs | RL | 1 ,SHE_DRAWING+SHEET.dgn,Design Model;14,SHE-08.ROOF.dgn,Design Model:111660 | A_BSUK_Roofs | New Construction | A-Roofs::A_BSUK_Roofs
A-FloorsSlabs A_BSUK_Slabs | RL | 1 ,SHE_DRAWING+SHEET.dgn,Design Model;14,SHE-08.ROOF.dgn,Design Model:111674 | A_BSUK_Roofs | New Construction | A-Roofs::A_BSUK_Roofs
A-FloorsSlabs A_BSUK_Slabs | RL | 1 ,SHE_DRAWING+SHEET.dgn,Design Model;14,SHE-08.ROOF.dgn,Design Model:111686 | A_BSUK_Roofs | New Construction | A-Roofs::A_BSUK_Roofs
A-FloorsSlabs A_BSUK_Slabs | RL | 1 ,SHE_DRAWING+SHEET.dgn,Design Model;14,SHE-08.ROOF.dgn,Design Model:111701 | A_BSUK_Roofs | New Construction | A-Roofs::A_BSUK_Roofs
A-FloorsSlabs A_BSUK_Slabs | RL | 1 ,SHE_DRAWING+SHEET.dgn,Design Model;14,SHE-08.ROOF.dgn,Design Model:111715 | A_BSUK_Roofs | New Construction | A-Roofs::A_BSUK_Roofs
A-FloorsSlabs A_BSUK_Slabs | RL | 1 ,SHE_DRAWING+SHEET.dgn,Design Model;14,SHE-08.ROOF.dgn,Design Model:111731 | A_BSUK_Roofs | New Construction | A-Roofs::A_BSUK_Roofs
A-FloorsSlabs A_BSUK_Slabs | RL | 1 ,SHE_DRAWING+SHEET.dgn,Design Model;14,SHE-08.ROOF.dgn,Design Model:111742 | A_BSUK_Roofs | New Construction | A-Roofs::A_BSUK_Roofs
A-FloorsSlabs A_BSUK_Slabs | RL | 1 ,SHE_DRAWING+SHEET.dgn,Design Model;14,SHE-08.ROOF.dgn,Design Model:111757 | A_BSUK_Roofs | New Construction | A-Roofs::A_BSUK_Roofs
A-FloorsSlabs A_BSUK_Slabs | RL | 1 ,SHE_DRAWING+SHEET.dgn,Design Model;14,SHE-08.ROOF.dgn,Design Model:111768 | A_BSUK_Roofs | New Construction | A-Roofs::A_BSUK_Roofs
A-FloorsSlabs A_BSUK_Slabs | RL | 1 ,SHE_DRAWING+SHEET.dgn,Design Model;14,SHE-08.ROOF.dgn,Design Model:111782 | A_BSUK_Roofs | New Construction | A-Roofs::A_BSUK_Roofs
A-FloorsSlabs A_BSUK_Slabs | RL | 1 ,SHE_DRAWING+SHEET.dgn,Design Model;14,SHE-08.ROOF.dgn,Design Model:111793 | A_BSUK_Roofs | New Construction | A-Roofs::A_BSUK_Roofs
A-FloorsSlabs A_BSUK_Slabs | RL | 1 ,SHE_DRAWING+SHEET.dgn,Design Model;14,SHE-08.ROOF.dgn,Design Model:111807 | A_BSUK_Roofs | New Construction | A-Roofs::A_BSUK_Roofs
A-FloorsSlabs A_BSUK_Slabs | RL | 1 ,SHE_DRAWING+SHEET.dgn,Design Model;14,SHE-08.ROOF.dgn,Design Model:111818 | A_BSUK_Roofs | New Construction | A-Roofs::A_BSUK_Roofs
A-FloorsSlabs A_BSUK_Slabs | RL | 1 ,SHE_DRAWING+SHEET.dgn,Design Model;14,SHE-08.ROOF.dgn,Design Model:111832 | A_BSUK_Roofs | New Construction | A-Roofs::A_BSUK_Roofs
A-FloorsSlabs A_BSUK_Slabs | RL | 1 ,SHE_DRAWING+SHEET.dgn,Design Model;14,SHE-08.ROOF.dgn,Design Model:111843 | A_BSUK_Roofs | New Construction | A-Roofs::A_BSUK_Roofs
A-FloorsSlabs A_BSUK_Slabs | RL | 1 ,SHE_DRAWING+SHEET.dgn,Design Model;14,SHE-08.ROOF.dgn,Design Model:111857 | A_BSUK_Roofs | New Construction | A-Roofs::A_BSUK_Roofs
A-FloorsSlabs A_BSUK_Slabs | RL | 1 ,SHE_DRAWING+SHEET.dgn,Design Model;14,SHE-08.ROOF.dgn,Design Model:111871 | A_BSUK_Roofs | New Construction | A-Roofs::A_BSUK_Roofs
A-FloorsSlabs A_BSUK_Slabs | RL | 1 ,SHE_DRAWING+SHEET.dgn,Design Model;14,SHE-08.ROOF.dgn,Design Model:111882 | A_BSUK_Roofs | New Construction | A-Roofs::A_BSUK_Roofs
A-FloorsSlabs A_BSUK_Slabs | RL | 1 ,SHE_DRAWING+SHEET.dgn,Design Model;14,SHE-08.ROOF.dgn,Design Model:111896 | A_BSUK_Roofs | New Construction | A-Roofs::A_BSUK_Roofs
A-FloorsSlabs A_BSUK_Slabs | RL | 1 ,SHE_DRAWING+SHEET.dgn,Design Model;14,SHE-08.ROOF.dgn,Design Model:111907 | A_BSUK_Roofs | New Construction | A-Roofs::A_BSUK_Roofs
A-FloorsSlabs A_BSUK_Slabs | RL | 1 ,SHE_DRAWING+SHEET.dgn,Design Model;14,SHE-08.ROOF.dgn,Design Model:111921 | A_BSUK_Roofs | New Construction | A-Roofs::A_BSUK_Roofs
A-FloorsSlabs A_BSUK_Slabs | RL | 1 ,SHE_DRAWING+SHEET.dgn,Design Model;14,SHE-08.ROOF.dgn,Design Model:111935 | A_BSUK_Roofs | New Construction | A-Roofs::A_BSUK_Roofs
A-FloorsSlabs A_BSUK_Slabs | RL | 1 ,SHE_DRAWING+SHEET.dgn,Design Model;14,SHE-08.ROOF.dgn,Design Model:111946 | A_BSUK_Roofs | New Construction | A-Roofs::A_BSUK_Roofs
A-FloorsSlabs A_BSUK_Slabs | RL | 1 ,SHE_DRAWING+SHEET.dgn,Design Model;14,SHE-08.ROOF.dgn,Design Model:111960 | A_BSUK_Roofs | New Construction | A-Roofs::A_BSUK_Roofs
A-FloorsSlabs A_BSUK_Slabs | RL | 1 ,SHE_DRAWING+SHEET.dgn,Design Model;14,SHE-08.ROOF.dgn,Design Model:111971 | A_BSUK_Roofs | New Construction | A-Roofs::A_BSUK_Roofs
A-FloorsSlabs A_BSUK_Slabs | RL | 1 ,SHE_DRAWING+SHEET.dgn,Design Model;14,SHE-08.ROOF.dgn,Design Model:111985 | A_BSUK_Roofs | New Construction | A-Roofs::A_BSUK_Roofs
A-FloorsSlabs A_BSUK_Slabs | RL | 1 ,SHE_DRAWING+SHEET.dgn,Design Model;14,SHE-08.ROOF.dgn,Design Model:111999 | A_BSUK_Roofs | New Construction | A-Roofs::A_BSUK_Roofs
A-FloorsSlabs A_BSUK_Slabs | RL | 1 ,SHE_DRAWING+SHEET.dgn,Design Model;14,SHE-08.ROOF.dgn,Design Model:112010 | A_BSUK_Roofs | New Construction | A-Roofs::A_BSUK_Roofs
A-FloorsSlabs A_BSUK_Slabs | RL | 1 ,SHE_DRAWING+SHEET.dgn,Design Model;14,SHE-08.ROOF.dgn,Design Model:112024 | A_BSUK_Roofs | New Construction | A-Roofs::A_BSUK_Roofs
A-FloorsSlabs A_BSUK_Slabs | RL | 1 ,SHE_DRAWING+SHEET.dgn,Design Model;14,SHE-08.ROOF.dgn,Design Model:112035 | A_BSUK_Roofs | New Construction | A-Roofs::A_BSUK_Roofs
A-FloorsSlabs A_BSUK_Slabs | RL | dry screed board :1,SHE_DRAWING+SHEET.dgn,Design Model;14,SHE-08.ROOF.dgn ,Design Model:105266 | A_BSUK_InternalFinishes_FloorScreed | New Construction | A-FloorsSlabs::A_BSUK_InternalFinishes_FloorScreed | Identification - ID | Description: dry screed board
A-FloorsSlabs A_BSUK_Slabs | RL | 1 ,SHE_DRAWING+SHEET.dgn,Design Model;14,SHE-08.ROOF.dgn,Design Model:105267 | A_BSUK_Roofs |  | A-Roofs::A_BSUK_Roofs
A-FloorsSlabs A_BSUK_Slabs | RL | 1 ,SHE_DRAWING+SHEET.dgn,Design Model;14,SHE-08.ROOF.dgn,Design Model:105290 | A_BSUK_Roofs |  | A-Roofs::A_BSUK_Roofs
A-FloorsSlabs A_BSUK_Slabs | RL | 1 ,SHE_DRAWING+SHEET.dgn,Design Model;14,SHE-08.ROOF.dgn,Design Model:105302 | A_BSUK_Roofs |  | A-Roofs::A_BSUK_Roofs
A-FloorsSlabs A_BSUK_Slabs | RL | 1 ,SHE_DRAWING+SHEET.dgn,Design Model;14,SHE-08.ROOF.dgn,Design Model:105314 | A_BSUK_Roofs |  | A-Roofs::A_BSUK_Roofs
A-FloorsSlabs A_BSUK_Slabs | RL | 1 ,SHE_DRAWING+SHEET.dgn,Design Model;14,SHE-08.ROOF.dgn,Design Model:105315 | A_BSUK_Roofs | New Construction | A-Roofs::A_BSUK_Roofs
A-FloorsSlabs A_BSUK_Slabs | RL | 1 ,SHE_DRAWING+SHEET.dgn,Design Model;14,SHE-08.ROOF.dgn,Design Model:105894 | A_BSUK_Roofs | New Construction | A-Roofs::A_BSUK_Roofs
A-FloorsSlabs A_BSUK_Slabs | RL | 1 ,SHE_DRAWING+SHEET.dgn,Design Model;14,SHE-08.ROOF.dgn,Design Model:109358 | A_BSUK_Roofs | New Construction | A-Roofs::A_BSUK_Roofs
A-FloorsSlabs A_BSUK_Slabs | RL | 1 ,SHE_DRAWING+SHEET.dgn,Design Model;14,SHE-08.ROOF.dgn,Design Model:109477 | A_BSUK_Roofs | New Construction | A-Roofs::A_BSUK_Roofs
A-FloorsSlabs A_BSUK_Slabs | RL | 1 ,SHE_DRAWING+SHEET.dgn,Design Model;14,SHE-08.ROOF.dgn,Design Model:109503 | A_BSUK_Roofs | New Construction | A-Roofs::A_BSUK_Roofs
A-FloorsSlabs A_BSUK_Slabs | RL | 1 ,SHE_DRAWING+SHEET.dgn,Design Model;14,SHE-08.ROOF.dgn,Design Model:109529 | A_BSUK_Roofs | New Construction | A-Roofs::A_BSUK_Roofs
A-FloorsSlabs A_BSUK_Slabs | RL | 1 ,SHE_DRAWING+SHEET.dgn,Design Model;14,SHE-08.ROOF.dgn,Design Model:109594 | A_BSUK_Roofs | New Construction | A-Roofs::A_BSUK_Roofs
A-FloorsSlabs A_BSUK_Slabs | RL | 1 ,SHE_DRAWING+SHEET.dgn,Design Model;14,SHE-08.ROOF.dgn,Design Model:109659 | A_BSUK_Roofs | New Construction | A-Roofs::A_BSUK_Roofs
A-FloorsSlabs A_BSUK_Slabs | RL | 1 ,SHE_DRAWING+SHEET.dgn,Design Model;14,SHE-08.ROOF.dgn,Design Model:109699 | A_BSUK_Roofs | New Construction | A-Roofs::A_BSUK_Roofs
A-FloorsSlabs A_BSUK_Slabs | RL | 1 ,SHE_DRAWING+SHEET.dgn,Design Model;14,SHE-08.ROOF.dgn,Design Model:109725 | A_BSUK_Roofs | New Construction | A-Roofs::A_BSUK_Roofs
A-FloorsSlabs A_BSUK_Slabs | RL | 1 ,SHE_DRAWING+SHEET.dgn,Design Model;14,SHE-08.ROOF.dgn,Design Model:109821 | A_BSUK_Roofs | New Construction | A-Roofs::A_BSUK_Roofs
A-FloorsSlabs A_BSUK_Slabs | RL | 1 ,SHE_DRAWING+SHEET.dgn,Design Model;14,SHE-08.ROOF.dgn,Design Model:109886 | A_BSUK_Roofs | New Construction | A-Roofs::A_BSUK_Roofs
A-FloorsSlabs A_BSUK_Slabs | RL | 1 ,SHE_DRAWING+SHEET.dgn,Design Model;14,SHE-08.ROOF.dgn,Design Model:109951 | A_BSUK_Roofs | New Construction | A-Roofs::A_BSUK_Roofs
A-FloorsSlabs A_BSUK_Slabs | RL | 1 ,SHE_DRAWING+SHEET.dgn,Design Model;14,SHE-08.ROOF.dgn,Design Model:109977 | A_BSUK_Roofs | New Construction | A-Roofs::A_BSUK_Roofs
A-FloorsSlabs A_BSUK_Slabs | RL | 1 ,SHE_DRAWING+SHEET.dgn,Design Model;14,SHE-08.ROOF.dgn,Design Model:110017 | A_BSUK_Roofs | New Construction | A-Roofs::A_BSUK_Roofs
A-FloorsSlabs A_BSUK_Slabs | RL | 1 ,SHE_DRAWING+SHEET.dgn,Design Model;14,SHE-08.ROOF.dgn,Design Model:110057 | A_BSUK_Roofs | New Construction | A-Roofs::A_BSUK_Roofs
A-FloorsSlabs A_BSUK_Slabs | RL | 1 ,SHE_DRAWING+SHEET.dgn,Design Model;14,SHE-08.ROOF.dgn,Design Model:110072 | A_BSUK_Roofs | New Construction | A-Roofs::A_BSUK_Roofs
A-FloorsSlabs A_BSUK_Slabs | RL | 1 ,SHE_DRAWING+SHEET.dgn,Design Model;14,SHE-08.ROOF.dgn,Design Model:111449 | A_BSUK_Roofs | New Construction | A-Roofs::A_BSUK_Roofs
A-FloorsSlabs A_BSUK_Slabs | RL | Celotex XR4000 :1,SHE_DRAWING+SHEET.dgn,Design Model;14,SHE-08.ROOF.dgn ,Design Model:112087 | A_BSUK_Insulation | New Construction | A-Walls::A_BSUK_Insulation | Identification - ID | Description: Celotex XR4000
A-FloorsSlabs A_BSUK_Slabs | RL | Deck (PLY) :1,SHE_DRAWING+SHEET.dgn,Design Model;14,SHE-08.ROOF.dgn ,Design Model:112126 | A_BSUK_Timber_Miscellaneous | New Construction | A-FrameElements::A_BSUK_Timber_Miscellaneous | Identification - ID | Description: Deck (PLY)
A-FloorsSlabs A_BSUK_Slabs | RL | single ply membrane or felt :1,SHE_DRAWING+SHEET.dgn,Design Model;14 ,SHE-08.ROOF.dgn,Design Model:112165 | A_BSUK_Roofs | New Construction | A-Roofs::A_BSUK_Roofs | Identification - ID | Description: single ply membrane or felt
A-FloorsSlabs A_BSUK_Slabs | GF | 1 ,SHE_DRAWING+SHEET.dgn,Design Model;15,SHE-14.BALCONY.dgn,Design Model:168902 | A_BSUK_StainlessSteelRailingSystems | New Construction | A-Finishes::A_BSUK_StainlessSteelRailingSystems
A-FloorsSlabs A_BSUK_Slabs | GF | 1 ,SHE_DRAWING+SHEET.dgn,Design Model;15,SHE-14.BALCONY.dgn,Design Model:169208 | A_BSUK_StainlessSteelRailingSystems | New Construction | A-Finishes::A_BSUK_StainlessSteelRailingSystems
A-FloorsSlabs A_BSUK_Slabs | GF | 1 ,SHE_DRAWING+SHEET.dgn,Design Model;15,SHE-14.BALCONY.dgn,Design Model:174220 | A_BSUK_StainlessSteelRailingSystems | New Construction | A-Finishes::A_BSUK_StainlessSteelRailingSystems
A-FloorsSlabs A_BSUK_Slabs | GF | 1 ,SHE_DRAWING+SHEET.dgn,Design Model;15,SHE-14.BALCONY.dgn,Design Model:174221 | A_BSUK_StainlessSteelRailingSystems | New Construction | A-Finishes::A_BSUK_StainlessSteelRailingSystems
A-FloorsSlabs A_BSUK_Slabs | GF | 1 ,SHE_DRAWING+SHEET.dgn,Design Model;15,SHE-14.BALCONY.dgn,Design Model:174278 | A_BSUK_StainlessSteelRailingSystems | New Construction | A-Finishes::A_BSUK_StainlessSteelRailingSystems
A-FloorsSlabs A_BSUK_Slabs | GF | 1 ,SHE_DRAWING+SHEET.dgn,Design Model;15,SHE-14.BALCONY.dgn,Design Model:174279 | A_BSUK_StainlessSteelRailingSystems | New Construction | A-Finishes::A_BSUK_StainlessSteelRailingSystems
A-FloorsSlabs A_BSUK_Slabs | GF | 1 ,SHE_DRAWING+SHEET.dgn,Design Model;16,SHE-12.STAIR.dgn,Design Model:224343 | A_BSUK_Slabs | Existing to Remain
A-FloorsSlabs A_BSUK_Slabs | GF | 1 ,SHE_DRAWING+SHEET.dgn,Design Model;16,SHE-12.STAIR.dgn,Design Model:220521 | A_BSUK_Slabs | Existing to Remain
A-FloorsSlabs A_BSUK_Slabs | GF | 1 ,SHE_DRAWING+SHEET.dgn,Design Model;16,SHE-12.STAIR.dgn,Design Model:220523 | A_BSUK_Slabs | Existing to Remain
A-FloorsSlabs A_BSUK_Slabs | RL | shelving - bath :1,SHE_DRAWING+SHEET.dgn,Design Model;18,SHE-04.SECOND.dgn ,Design Model:142164 | A_BSUK_Ceramic_WallTiles | New Construction | A-Finishes::A_BSUK_Ceramic_WallTiles | Identification - ID | Description: shelving - bath
A-FloorsSlabs A_BSUK_Slabs | RL | shelving - bath :1,SHE_DRAWING+SHEET.dgn,Design Model;18,SHE-04.SECOND.dgn ,Design Model:142179 | A_BSUK_Ceramic_WallTiles | New Construction | A-Finishes::A_BSUK_Ceramic_WallTiles | Identification - ID | Description: shelving - bath
A-FloorsSlabs A_BSUK_Slabs | RL | shelving - bath :1,SHE_DRAWING+SHEET.dgn,Design Model;18,SHE-04.SECOND.dgn ,Design Model:142194 | A_BSUK_Ceramic_WallTiles | New Construction | A-Finishes::A_BSUK_Ceramic_WallTiles | Identification - ID | Description: shelving - bath
A-FloorsSlabs A_BSUK_Slabs | RL | shelving - bath :1,SHE_DRAWING+SHEET.dgn,Design Model;18,SHE-04.SECOND.dgn ,Design Model:300477 | A_BSUK_Ceramic_WallTiles | New Construction | A-Finishes::A_BSUK_Ceramic_WallTiles | Identification - ID | Description: shelving - bath
A-FloorsSlabs A_BSUK_Slabs | RL | shelving - bath :1,SHE_DRAWING+SHEET.dgn,Design Model;18,SHE-04.SECOND.dgn ,Design Model:300491 | A_BSUK_Ceramic_WallTiles | New Construction | A-Finishes::A_BSUK_Ceramic_WallTiles | Identification - ID | Description: shelving - bath
A-FloorsSlabs A_BSUK_Slabs | RL | shelving - bath :1,SHE_DRAWING+SHEET.dgn,Design Model;18,SHE-04.SECOND.dgn ,Design Model:300505 | A_BSUK_Ceramic_WallTiles | New Construction | A-Finishes::A_BSUK_Ceramic_WallTiles | Identification - ID | Description: shelving - bath
A-FloorsSlabs A_BSUK_Slabs | RL | shelving - bath :1,SHE_DRAWING+SHEET.dgn,Design Model;18,SHE-04.SECOND.dgn ,Design Model:327204 | A_BSUK_Ceramic_WallTiles | New Construction | A-Finishes::A_BSUK_Ceramic_WallTiles | Identification - ID | Description: shelving - bath
A-FloorsSlabs A_BSUK_Slabs | RL | 1 ,SHE_DRAWING+SHEET.dgn,Design Model;18,SHE-04.SECOND.dgn,Design Model:134765 | A_BSUK_CeilingSoffitFinishes_Suspended | New Construction | A-Ceilings::A_BSUK_CeilingSoffitFinishes_Suspended | Fire Resistance - Fire | Rating: FD60
A-FloorsSlabs A_BSUK_Slabs | RL | 1 ,SHE_DRAWING+SHEET.dgn,Design Model;18,SHE-04.SECOND.dgn,Design Model:134792 | A_BSUK_CeilingSoffitFinishes_Suspended | New Construction | A-Ceilings::A_BSUK_CeilingSoffitFinishes_Suspended | Fire Resistance - Fire | Rating: FD60
A-FloorsSlabs A_BSUK_Slabs | RL | 1 ,SHE_DRAWING+SHEET.dgn,Design Model;18,SHE-04.SECOND.dgn,Design Model:134816 | A_BSUK_CeilingSoffitFinishes_Suspended | New Construction | A-Ceilings::A_BSUK_CeilingSoffitFinishes_Suspended | Fire Resistance - Fire | Rating: FD60
A-FloorsSlabs A_BSUK_Slabs | RL | 1 ,SHE_DRAWING+SHEET.dgn,Design Model;18,SHE-04.SECOND.dgn,Design Model:134859 | A_BSUK_InternalFinishes_FloorScreed | New Construction | A-FloorsSlabs::A_BSUK_InternalFinishes_FloorScreed
A-FloorsSlabs A_BSUK_Slabs | RL | 1 ,SHE_DRAWING+SHEET.dgn,Design Model;18,SHE-04.SECOND.dgn,Design Model:134860 | A_BSUK_InternalFinishes_FloorScreed | New Construction | A-FloorsSlabs::A_BSUK_InternalFinishes_FloorScreed
A-FloorsSlabs A_BSUK_Slabs | RL | 1 ,SHE_DRAWING+SHEET.dgn,Design Model;18,SHE-04.SECOND.dgn,Design Model:135695 | A_BSUK_Ceramic_WallTiles | New Construction | A-Finishes::A_BSUK_Ceramic_WallTiles
A-FloorsSlabs A_BSUK_Slabs | RL | 1 ,SHE_DRAWING+SHEET.dgn,Design Model;18,SHE-04.SECOND.dgn,Design Model:135710 | A_BSUK_Ceramic_WallTiles | New Construction | A-Finishes::A_BSUK_Ceramic_WallTiles
A-FloorsSlabs A_BSUK_Slabs | RL | 1 ,SHE_DRAWING+SHEET.dgn,Design Model;18,SHE-04.SECOND.dgn,Design Model:135725 | A_BSUK_Ceramic_WallTiles | New Construction | A-Finishes::A_BSUK_Ceramic_WallTiles
A-FloorsSlabs A_BSUK_Slabs | RL | 1 ,SHE_DRAWING+SHEET.dgn,Design Model;18,SHE-04.SECOND.dgn,Design Model:135770 | A_BSUK_Ceramic_WallTiles | New Construction | A-Finishes::A_BSUK_Ceramic_WallTiles
A-FloorsSlabs A_BSUK_Slabs | RL | 1 ,SHE_DRAWING+SHEET.dgn,Design Model;18,SHE-04.SECOND.dgn,Design Model:142049 | A_BSUK_InternalFinishes_FloorScreed | Existing to Remain | A-FloorsSlabs::A_BSUK_InternalFinishes_FloorScreed
A-FloorsSlabs A_BSUK_Slabs | RL | 1 ,SHE_DRAWING+SHEET.dgn,Design Model;18,SHE-04.SECOND.dgn,Design Model:143321 | A_BSUK_Ceramic_WallTiles | New Construction | A-Finishes::A_BSUK_Ceramic_WallTiles
A-FloorsSlabs A_BSUK_Slabs | RL | 1 ,SHE_DRAWING+SHEET.dgn,Design Model;18,SHE-04.SECOND.dgn,Design Model:143864 | A_BSUK_ExpandedPolystyreneBoards | New Construction | A-FloorsSlabs::A_BSUK_ExpandedPolystyreneBoards
A-FloorsSlabs A_BSUK_Slabs | RL | 1 ,SHE_DRAWING+SHEET.dgn,Design Model;18,SHE-04.SECOND.dgn,Design Model:143891 | A_BSUK_ExpandedPolystyreneBoards | New Construction | A-FloorsSlabs::A_BSUK_ExpandedPolystyreneBoards
A-FloorsSlabs A_BSUK_Slabs | RL | 1 ,SHE_DRAWING+SHEET.dgn,Design Model;18,SHE-04.SECOND.dgn,Design Model:143969 | A_BSUK_ExpandedPolystyreneBoards | New Construction | A-FloorsSlabs::A_BSUK_ExpandedPolystyreneBoards
A-FloorsSlabs A_BSUK_Slabs | RL | 1 ,SHE_DRAWING+SHEET.dgn,Design Model;18,SHE-04.SECOND.dgn,Design Model:144064 | A_BSUK_ExpandedPolystyreneBoards | New Construction | A-FloorsSlabs::A_BSUK_ExpandedPolystyreneBoards
A-FloorsSlabs A_BSUK_Slabs | RL | 1 ,SHE_DRAWING+SHEET.dgn,Design Model;18,SHE-04.SECOND.dgn,Design Model:144148 | A_BSUK_ExpandedPolystyreneBoards | New Construction | A-FloorsSlabs::A_BSUK_ExpandedPolystyreneBoards
A-FloorsSlabs A_BSUK_Slabs | RL | 1 ,SHE_DRAWING+SHEET.dgn,Design Model;18,SHE-04.SECOND.dgn,Design Model:144277 | A_BSUK_ExpandedPolystyreneBoards | New Construction | A-FloorsSlabs::A_BSUK_ExpandedPolystyreneBoards
A-FloorsSlabs A_BSUK_Slabs | RL | 1 ,SHE_DRAWING+SHEET.dgn,Design Model;18,SHE-04.SECOND.dgn,Design Model:144370 | A_BSUK_ExpandedPolystyreneBoards | New Construction | A-FloorsSlabs::A_BSUK_ExpandedPolystyreneBoards
A-FloorsSlabs A_BSUK_Slabs | RL | 1 ,SHE_DRAWING+SHEET.dgn,Design Model;18,SHE-04.SECOND.dgn,Design Model:144454 | A_BSUK_ExpandedPolystyreneBoards | New Construction | A-FloorsSlabs::A_BSUK_ExpandedPolystyreneBoards
A-FloorsSlabs A_BSUK_Slabs | RL | 1 ,SHE_DRAWING+SHEET.dgn,Design Model;18,SHE-04.SECOND.dgn,Design Model:144538 | A_BSUK_ExpandedPolystyreneBoards | New Construction | A-FloorsSlabs::A_BSUK_ExpandedPolystyreneBoards
A-FloorsSlabs A_BSUK_Slabs | RL | 1 ,SHE_DRAWING+SHEET.dgn,Design Model;18,SHE-04.SECOND.dgn,Design Model:144628 | A_BSUK_ExpandedPolystyreneBoards | New Construction | A-FloorsSlabs::A_BSUK_ExpandedPolystyreneBoards
A-FloorsSlabs A_BSUK_Slabs | RL | 1 ,SHE_DRAWING+SHEET.dgn,Design Model;18,SHE-04.SECOND.dgn,Design Model:144629 | A_BSUK_Parquet_Floor |  | A-Finishes::A_BSUK_Parquet_Floor
A-FloorsSlabs A_BSUK_Slabs | RL | 1 ,SHE_DRAWING+SHEET.dgn,Design Model;18,SHE-04.SECOND.dgn,Design Model:144740 | A_BSUK_Carpet-Pile | New Construction | A-Finishes::A_BSUK_Carpet-Pile
A-FloorsSlabs A_BSUK_Slabs | RL | 1 ,SHE_DRAWING+SHEET.dgn,Design Model;18,SHE-04.SECOND.dgn,Design Model:144773 | A_BSUK_Ceramic_FloorTiles |  | A-Finishes::A_BSUK_Ceramic_FloorTiles
A-FloorsSlabs A_BSUK_Slabs | RL | 1 ,SHE_DRAWING+SHEET.dgn,Design Model;18,SHE-04.SECOND.dgn,Design Model:144788 | A_BSUK_Parquet_Floor |  | A-Finishes::A_BSUK_Parquet_Floor
A-FloorsSlabs A_BSUK_Slabs | RL | 1 ,SHE_DRAWING+SHEET.dgn,Design Model;18,SHE-04.SECOND.dgn,Design Model:144899 | A_BSUK_Parquet_Floor |  | A-Finishes::A_BSUK_Parquet_Floor
A-FloorsSlabs A_BSUK_Slabs | RL | 1 ,SHE_DRAWING+SHEET.dgn,Design Model;18,SHE-04.SECOND.dgn,Design Model:144914 | A_BSUK_Carpet-Pile |  | A-Finishes::A_BSUK_Carpet-Pile
A-FloorsSlabs A_BSUK_Slabs | RL | 1 ,SHE_DRAWING+SHEET.dgn,Design Model;18,SHE-04.SECOND.dgn,Design Model:144959 | A_BSUK_Ceramic_FloorTiles |  | A-Finishes::A_BSUK_Ceramic_FloorTiles
A-FloorsSlabs A_BSUK_Slabs | RL | 1 ,SHE_DRAWING+SHEET.dgn,Design Model;18,SHE-04.SECOND.dgn,Design Model:144974 | A_BSUK_Parquet_Floor |  | A-Finishes::A_BSUK_Parquet_Floor
A-FloorsSlabs A_BSUK_Slabs | RL | 1 ,SHE_DRAWING+SHEET.dgn,Design Model;18,SHE-04.SECOND.dgn,Design Model:145109 | A_BSUK_Ceramic_FloorTiles |  | A-Finishes::A_BSUK_Ceramic_FloorTiles
A-FloorsSlabs A_BSUK_Slabs | RL | 1 ,SHE_DRAWING+SHEET.dgn,Design Model;18,SHE-04.SECOND.dgn,Design Model:145124 | A_BSUK_Carpet-Pile |  | A-Finishes::A_BSUK_Carpet-Pile
A-FloorsSlabs A_BSUK_Slabs | RL | 1 ,SHE_DRAWING+SHEET.dgn,Design Model;18,SHE-04.SECOND.dgn,Design Model:145163 | A_BSUK_Carpet-Pile |  | A-Finishes::A_BSUK_Carpet-Pile
A-FloorsSlabs A_BSUK_Slabs | RL | 1 ,SHE_DRAWING+SHEET.dgn,Design Model;18,SHE-04.SECOND.dgn,Design Model:145196 | A_BSUK_Parquet_Floor |  | A-Finishes::A_BSUK_Parquet_Floor
A-FloorsSlabs A_BSUK_Slabs | RL | 1 ,SHE_DRAWING+SHEET.dgn,Design Model;18,SHE-04.SECOND.dgn,Design Model:145313 | A_BSUK_Ceramic_FloorTiles |  | A-Finishes::A_BSUK_Ceramic_FloorTiles
A-FloorsSlabs A_BSUK_Slabs | RL | 1 ,SHE_DRAWING+SHEET.dgn,Design Model;18,SHE-04.SECOND.dgn,Design Model:145328 | A_BSUK_Parquet_Floor |  | A-Finishes::A_BSUK_Parquet_Floor
A-FloorsSlabs A_BSUK_Slabs | RL | 1 ,SHE_DRAWING+SHEET.dgn,Design Model;18,SHE-04.SECOND.dgn,Design Model:145427 | A_BSUK_Ceramic_FloorTiles |  | A-Finishes::A_BSUK_Ceramic_FloorTiles
A-FloorsSlabs A_BSUK_Slabs | RL | 1 ,SHE_DRAWING+SHEET.dgn,Design Model;18,SHE-04.SECOND.dgn,Design Model:145448 | A_BSUK_Carpet-Pile |  | A-Finishes::A_BSUK_Carpet-Pile
A-FloorsSlabs A_BSUK_Slabs | RL | 1 ,SHE_DRAWING+SHEET.dgn,Design Model;18,SHE-04.SECOND.dgn,Design Model:145631 | A_BSUK_Parquet_Floor |  | A-Finishes::A_BSUK_Parquet_Floor
A-FloorsSlabs A_BSUK_Slabs | RL | 1 ,SHE_DRAWING+SHEET.dgn,Design Model;18,SHE-04.SECOND.dgn,Design Model:145632 | A_BSUK_Ceramic_FloorTiles |  | A-Finishes::A_BSUK_Ceramic_FloorTiles
A-FloorsSlabs A_BSUK_Slabs | RL | 1 ,SHE_DRAWING+SHEET.dgn,Design Model;18,SHE-04.SECOND.dgn,Design Model:145633 | A_BSUK_Carpet-Pile |  | A-Finishes::A_BSUK_Carpet-Pile
A-FloorsSlabs A_BSUK_Slabs | RL | 1 ,SHE_DRAWING+SHEET.dgn,Design Model;18,SHE-04.SECOND.dgn,Design Model:145634 | A_BSUK_Parquet_Floor |  | A-Finishes::A_BSUK_Parquet_Floor
A-FloorsSlabs A_BSUK_Slabs | RL | 1 ,SHE_DRAWING+SHEET.dgn,Design Model;18,SHE-04.SECOND.dgn,Design Model:145739 | A_BSUK_Ceramic_FloorTiles |  | A-Finishes::A_BSUK_Ceramic_FloorTiles
A-FloorsSlabs A_BSUK_Slabs | RL | 1 ,SHE_DRAWING+SHEET.dgn,Design Model;18,SHE-04.SECOND.dgn,Design Model:145754 | A_BSUK_Carpet-Pile | New Construction | A-Finishes::A_BSUK_Carpet-Pile
A-FloorsSlabs A_BSUK_Slabs | RL | 1 ,SHE_DRAWING+SHEET.dgn,Design Model;18,SHE-04.SECOND.dgn,Design Model:145787 | A_BSUK_Carpet-Pile |  | A-Finishes::A_BSUK_Carpet-Pile
A-FloorsSlabs A_BSUK_Slabs | RL | 1 ,SHE_DRAWING+SHEET.dgn,Design Model;18,SHE-04.SECOND.dgn,Design Model:145826 | A_BSUK_Carpet-Pile |  | A-Finishes::A_BSUK_Carpet-Pile
A-FloorsSlabs A_BSUK_Slabs | RL | 1 ,SHE_DRAWING+SHEET.dgn,Design Model;18,SHE-04.SECOND.dgn,Design Model:145862 | A_BSUK_Carpet-Pile |  | A-Finishes::A_BSUK_Carpet-Pile
A-FloorsSlabs A_BSUK_Slabs | RL | 1 ,SHE_DRAWING+SHEET.dgn,Design Model;18,SHE-04.SECOND.dgn,Design Model:145967 | A_BSUK_Carpet-Pile |  | A-Finishes::A_BSUK_Carpet-Pile
A-FloorsSlabs A_BSUK_Slabs | RL | 1 ,SHE_DRAWING+SHEET.dgn,Design Model;18,SHE-04.SECOND.dgn,Design Model:154694 | A_BSUK_CeilingSoffitFinishes_Suspended | New Construction | A-Ceilings::A_BSUK_CeilingSoffitFinishes_Suspended
A-FloorsSlabs A_BSUK_Slabs | RL | 1 ,SHE_DRAWING+SHEET.dgn,Design Model;18,SHE-04.SECOND.dgn,Design Model:154742 | A_BSUK_CeilingSoffitFinishes_Suspended |  | A-Ceilings::A_BSUK_CeilingSoffitFinishes_Suspended
A-FloorsSlabs A_BSUK_Slabs | RL | 1 ,SHE_DRAWING+SHEET.dgn,Design Model;18,SHE-04.SECOND.dgn,Design Model:155063 | A_BSUK_CeilingSoffitFinishes_Suspended |  | A-Ceilings::A_BSUK_CeilingSoffitFinishes_Suspended
A-FloorsSlabs A_BSUK_Slabs | RL | 1 ,SHE_DRAWING+SHEET.dgn,Design Model;18,SHE-04.SECOND.dgn,Design Model:155064 | A_BSUK_CeilingSoffitFinishes_Suspended | New Construction | A-Ceilings::A_BSUK_CeilingSoffitFinishes_Suspended
A-FloorsSlabs A_BSUK_Slabs | RL | 1 ,SHE_DRAWING+SHEET.dgn,Design Model;18,SHE-04.SECOND.dgn,Design Model:155065 | A_BSUK_CeilingSoffitFinishes_Suspended |  | A-Ceilings::A_BSUK_CeilingSoffitFinishes_Suspended
A-FloorsSlabs A_BSUK_Slabs | RL | 1 ,SHE_DRAWING+SHEET.dgn,Design Model;18,SHE-04.SECOND.dgn,Design Model:155066 | A_BSUK_CeilingSoffitFinishes_Suspended |  | A-Ceilings::A_BSUK_CeilingSoffitFinishes_Suspended
A-FloorsSlabs A_BSUK_Slabs | RL | 1 ,SHE_DRAWING+SHEET.dgn,Design Model;18,SHE-04.SECOND.dgn,Design Model:155067 | A_BSUK_CeilingSoffitFinishes_Suspended |  | A-Ceilings::A_BSUK_CeilingSoffitFinishes_Suspended
A-FloorsSlabs A_BSUK_Slabs | RL | 1 ,SHE_DRAWING+SHEET.dgn,Design Model;18,SHE-04.SECOND.dgn,Design Model:155068 | A_BSUK_CeilingSoffitFinishes_Suspended |  | A-Ceilings::A_BSUK_CeilingSoffitFinishes_Suspended
A-FloorsSlabs A_BSUK_Slabs | RL | 1 ,SHE_DRAWING+SHEET.dgn,Design Model;18,SHE-04.SECOND.dgn,Design Model:155069 | A_BSUK_CeilingSoffitFinishes_Suspended |  | A-Ceilings::A_BSUK_CeilingSoffitFinishes_Suspended
A-FloorsSlabs A_BSUK_Slabs | RL | 1 ,SHE_DRAWING+SHEET.dgn,Design Model;18,SHE-04.SECOND.dgn,Design Model:155084 | A_BSUK_CeilingSoffitFinishes_Suspended |  | A-Ceilings::A_BSUK_CeilingSoffitFinishes_Suspended
A-FloorsSlabs A_BSUK_Slabs | RL | 1 ,SHE_DRAWING+SHEET.dgn,Design Model;18,SHE-04.SECOND.dgn,Design Model:155099 | A_BSUK_CeilingSoffitFinishes_Suspended |  | A-Ceilings::A_BSUK_CeilingSoffitFinishes_Suspended
A-FloorsSlabs A_BSUK_Slabs | RL | 1 ,SHE_DRAWING+SHEET.dgn,Design Model;18,SHE-04.SECOND.dgn,Design Model:155370 | A_BSUK_CeilingSoffitFinishes_Suspended |  | A-Ceilings::A_BSUK_CeilingSoffitFinishes_Suspended
A-FloorsSlabs A_BSUK_Slabs | RL | 1 ,SHE_DRAWING+SHEET.dgn,Design Model;18,SHE-04.SECOND.dgn,Design Model:155371 | A_BSUK_CeilingSoffitFinishes_Suspended |  | A-Ceilings::A_BSUK_CeilingSoffitFinishes_Suspended
A-FloorsSlabs A_BSUK_Slabs | RL | 1 ,SHE_DRAWING+SHEET.dgn,Design Model;18,SHE-04.SECOND.dgn,Design Model:155619 | A_BSUK_CeilingSoffitFinishes_Suspended | New Construction | A-Ceilings::A_BSUK_CeilingSoffitFinishes_Suspended
A-FloorsSlabs A_BSUK_Slabs | RL | 1 ,SHE_DRAWING+SHEET.dgn,Design Model;18,SHE-04.SECOND.dgn,Design Model:155620 | A_BSUK_CeilingSoffitFinishes_Suspended |  | A-Ceilings::A_BSUK_CeilingSoffitFinishes_Suspended
A-FloorsSlabs A_BSUK_Slabs | RL | 1 ,SHE_DRAWING+SHEET.dgn,Design Model;18,SHE-04.SECOND.dgn,Design Model:155621 | A_BSUK_CeilingSoffitFinishes_Suspended | New Construction | A-Ceilings::A_BSUK_CeilingSoffitFinishes_Suspended
A-FloorsSlabs A_BSUK_Slabs | RL | 1 ,SHE_DRAWING+SHEET.dgn,Design Model;18,SHE-04.SECOND.dgn,Design Model:155622 | A_BSUK_CeilingSoffitFinishes_Suspended | New Construction | A-Ceilings::A_BSUK_CeilingSoffitFinishes_Suspended
A-FloorsSlabs A_BSUK_Slabs | RL | 1 ,SHE_DRAWING+SHEET.dgn,Design Model;18,SHE-04.SECOND.dgn,Design Model:155623 | A_BSUK_CeilingSoffitFinishes_Suspended | New Construction | A-Ceilings::A_BSUK_CeilingSoffitFinishes_Suspended
A-FloorsSlabs A_BSUK_Slabs | RL | 1 ,SHE_DRAWING+SHEET.dgn,Design Model;18,SHE-04.SECOND.dgn,Design Model:155624 | A_BSUK_CeilingSoffitFinishes_Suspended |  | A-Ceilings::A_BSUK_CeilingSoffitFinishes_Suspended
A-FloorsSlabs A_BSUK_Slabs | RL | 1 ,SHE_DRAWING+SHEET.dgn,Design Model;18,SHE-04.SECOND.dgn,Design Model:155626 | A_BSUK_CeilingSoffitFinishes_Suspended | New Construction | A-Ceilings::A_BSUK_CeilingSoffitFinishes_Suspended
A-FloorsSlabs A_BSUK_Slabs | RL | 1 ,SHE_DRAWING+SHEET.dgn,Design Model;18,SHE-04.SECOND.dgn,Design Model:220881 | A_BSUK_CeilingSoffitFinishes_Suspended |  | A-Ceilings::A_BSUK_CeilingSoffitFinishes_Suspended
A-FloorsSlabs A_BSUK_Slabs | RL | 1 ,SHE_DRAWING+SHEET.dgn,Design Model;18,SHE-04.SECOND.dgn,Design Model:220882 | A_BSUK_CeilingSoffitFinishes_Suspended | New Construction | A-Ceilings::A_BSUK_CeilingSoffitFinishes_Suspended
A-FloorsSlabs A_BSUK_Slabs | RL | 1 ,SHE_DRAWING+SHEET.dgn,Design Model;18,SHE-04.SECOND.dgn,Design Model:220883 | A_BSUK_CeilingSoffitFinishes_Suspended | New Construction | A-Ceilings::A_BSUK_CeilingSoffitFinishes_Suspended
A-FloorsSlabs A_BSUK_Slabs | RL | 1 ,SHE_DRAWING+SHEET.dgn,Design Model;18,SHE-04.SECOND.dgn,Design Model:229439 | A_BSUK_Ceramic_WallTiles | New Construction | A-Finishes::A_BSUK_Ceramic_WallTiles
A-FloorsSlabs A_BSUK_Slabs | RL | 1 ,SHE_DRAWING+SHEET.dgn,Design Model;18,SHE-04.SECOND.dgn,Design Model:232461 | A_BSUK_Ceramic_FloorTiles |  | A-Finishes::A_BSUK_Ceramic_FloorTiles
A-FloorsSlabs A_BSUK_Slabs | RL | 1 ,SHE_DRAWING+SHEET.dgn,Design Model;18,SHE-04.SECOND.dgn,Design Model:270352 | A_BSUK_Ceramic_WallTiles | New Construction | A-Finishes::A_BSUK_Ceramic_WallTiles
A-FloorsSlabs A_BSUK_Slabs | RL | 1 ,SHE_DRAWING+SHEET.dgn,Design Model;18,SHE-04.SECOND.dgn,Design Model:270751 | A_BSUK_Ceramic_WallTiles | New Construction | A-Finishes::A_BSUK_Ceramic_WallTiles
A-FloorsSlabs A_BSUK_Slabs | RL | shelving - bath :1,SHE_DRAWING+SHEET.dgn,Design Model;18,SHE-04.SECOND.dgn ,Design Model:277457 | A_BSUK_Ceramic_WallTiles | New Construction | A-Finishes::A_BSUK_Ceramic_WallTiles | Identification - ID | Description: shelving - bath
A-FloorsSlabs A_BSUK_Slabs | RL | shelving - bath :1,SHE_DRAWING+SHEET.dgn,Design Model;18,SHE-04.SECOND.dgn ,Design Model:280881 | A_BSUK_Ceramic_WallTiles | New Construction | A-Finishes::A_BSUK_Ceramic_WallTiles | Identification - ID | Description: shelving - bath
A-FloorsSlabs A_BSUK_Slabs | RL | 1 ,SHE_DRAWING+SHEET.dgn,Design Model;18,SHE-04.SECOND.dgn,Design Model:282366 | A_BSUK_Ceramic_WallTiles | New Construction | A-Finishes::A_BSUK_Ceramic_WallTiles
A-FloorsSlabs A_BSUK_Slabs | RL | fire board - ceiling :1,SHE_DRAWING+SHEET.dgn,Design Model;18 ,SHE-04.SECOND.dgn,Design Model:385538 | A_BSUK_CeilingSoffitFinishes_Suspended | New Construction | A-Ceilings::A_BSUK_CeilingSoffitFinishes_Suspended | Identification - ID | Description: fire board - ceiling
A-FloorsSlabs A_BSUK_Slabs | RL | fire board - ceiling :1,SHE_DRAWING+SHEET.dgn,Design Model;18 ,SHE-04.SECOND.dgn,Design Model:385553 | A_BSUK_CeilingSoffitFinishes_Suspended | New Construction | A-Ceilings::A_BSUK_CeilingSoffitFinishes_Suspended | Identification - ID | Description: fire board - ceiling
A-FloorsSlabs A_BSUK_Slabs | RL | fire board - ceiling :1,SHE_DRAWING+SHEET.dgn,Design Model;18 ,SHE-04.SECOND.dgn,Design Model:385568 | A_BSUK_CeilingSoffitFinishes_Suspended | New Construction | A-Ceilings::A_BSUK_CeilingSoffitFinishes_Suspended | Identification - ID | Description: fire board - ceiling
A-FloorsSlabs A_BSUK_Slabs | RL | fire board - ceiling :1,SHE_DRAWING+SHEET.dgn,Design Model;18 ,SHE-04.SECOND.dgn,Design Model:385583 | A_BSUK_CeilingSoffitFinishes_Suspended | New Construction | A-Ceilings::A_BSUK_CeilingSoffitFinishes_Suspended | Identification - ID | Description: fire board - ceiling
A-FloorsSlabs A_BSUK_Slabs | RL | fire board - ceiling :1,SHE_DRAWING+SHEET.dgn,Design Model;18 ,SHE-04.SECOND.dgn,Design Model:385598 | A_BSUK_CeilingSoffitFinishes_Suspended | New Construction | A-Ceilings::A_BSUK_CeilingSoffitFinishes_Suspended | Identification - ID | Description: fire board - ceiling
A-FloorsSlabs A_BSUK_Slabs | RL | fire board - ceiling :1,SHE_DRAWING+SHEET.dgn,Design Model;18 ,SHE-04.SECOND.dgn,Design Model:385627 | A_BSUK_CeilingSoffitFinishes_Suspended | New Construction | A-Ceilings::A_BSUK_CeilingSoffitFinishes_Suspended | Identification - ID | Description: fire board - ceiling
A-FloorsSlabs A_BSUK_Slabs | RL | fire board - ceiling :1,SHE_DRAWING+SHEET.dgn,Design Model;18 ,SHE-04.SECOND.dgn,Design Model:385628 | A_BSUK_CeilingSoffitFinishes_Suspended | New Construction | A-Ceilings::A_BSUK_CeilingSoffitFinishes_Suspended | Identification - ID | Description: fire board - ceiling
A-FloorsSlabs A_BSUK_Slabs | RL | fire board - ceiling :1,SHE_DRAWING+SHEET.dgn,Design Model;18 ,SHE-04.SECOND.dgn,Design Model:385643 | A_BSUK_CeilingSoffitFinishes_Suspended | New Construction | A-Ceilings::A_BSUK_CeilingSoffitFinishes_Suspended | Identification - ID | Description: fire board - ceiling
A-FloorsSlabs A_BSUK_Slabs | RL | fire board - ceiling :1,SHE_DRAWING+SHEET.dgn,Design Model;18 ,SHE-04.SECOND.dgn,Design Model:385658 | A_BSUK_CeilingSoffitFinishes_Suspended | New Construction | A-Ceilings::A_BSUK_CeilingSoffitFinishes_Suspended | Identification - ID | Description: fire board - ceiling
A-FloorsSlabs A_BSUK_Slabs | RL | fire board - ceiling :1,SHE_DRAWING+SHEET.dgn,Design Model;18 ,SHE-04.SECOND.dgn,Design Model:385673 | A_BSUK_CeilingSoffitFinishes_Suspended | New Construction | A-Ceilings::A_BSUK_CeilingSoffitFinishes_Suspended | Identification - ID | Description: fire board - ceiling
A-FloorsSlabs A_BSUK_Slabs | RL | fire board - ceiling :1,SHE_DRAWING+SHEET.dgn,Design Model;18 ,SHE-04.SECOND.dgn,Design Model:385688 | A_BSUK_CeilingSoffitFinishes_Suspended | New Construction | A-Ceilings::A_BSUK_CeilingSoffitFinishes_Suspended | Identification - ID | Description: fire board - ceiling
A-FloorsSlabs A_BSUK_Slabs | RL | fire board - ceiling :1,SHE_DRAWING+SHEET.dgn,Design Model;18 ,SHE-04.SECOND.dgn,Design Model:385703 | A_BSUK_CeilingSoffitFinishes_Suspended | New Construction | A-Ceilings::A_BSUK_CeilingSoffitFinishes_Suspended | Identification - ID | Description: fire board - ceiling
A-FloorsSlabs A_BSUK_Slabs | RL | fire board - ceiling :1,SHE_DRAWING+SHEET.dgn,Design Model;18 ,SHE-04.SECOND.dgn,Design Model:385718 | A_BSUK_CeilingSoffitFinishes_Suspended | New Construction | A-Ceilings::A_BSUK_CeilingSoffitFinishes_Suspended | Identification - ID | Description: fire board - ceiling
A-FloorsSlabs A_BSUK_Slabs | RL | fire board - ceiling :1,SHE_DRAWING+SHEET.dgn,Design Model;18 ,SHE-04.SECOND.dgn,Design Model:385733 | A_BSUK_CeilingSoffitFinishes_Suspended | New Construction | A-Ceilings::A_BSUK_CeilingSoffitFinishes_Suspended | Identification - ID | Description: fire board - ceiling
A-FloorsSlabs A_BSUK_Slabs | RL | fire board - ceiling :1,SHE_DRAWING+SHEET.dgn,Design Model;18 ,SHE-04.SECOND.dgn,Design Model:385748 | A_BSUK_CeilingSoffitFinishes_Suspended | New Construction | A-Ceilings::A_BSUK_CeilingSoffitFinishes_Suspended | Identification - ID | Description: fire board - ceiling
A-FloorsSlabs A_BSUK_Slabs | RL | fire board - ceiling :1,SHE_DRAWING+SHEET.dgn,Design Model;18 ,SHE-04.SECOND.dgn,Design Model:385777 | A_BSUK_CeilingSoffitFinishes_Suspended | New Construction | A-Ceilings::A_BSUK_CeilingSoffitFinishes_Suspended | Identification - ID | Description: fire board - ceiling
A-FloorsSlabs A_BSUK_Slabs | RL | fire board - ceiling :1,SHE_DRAWING+SHEET.dgn,Design Model;18 ,SHE-04.SECOND.dgn,Design Model:385778 | A_BSUK_CeilingSoffitFinishes_Suspended | New Construction | A-Ceilings::A_BSUK_CeilingSoffitFinishes_Suspended | Identification - ID | Description: fire board - ceiling
A-FloorsSlabs A_BSUK_Slabs | RL | fire board - ceiling :1,SHE_DRAWING+SHEET.dgn,Design Model;18 ,SHE-04.SECOND.dgn,Design Model:385793 | A_BSUK_CeilingSoffitFinishes_Suspended | New Construction | A-Ceilings::A_BSUK_CeilingSoffitFinishes_Suspended | Identification - ID | Description: fire board - ceiling
A-FloorsSlabs A_BSUK_Slabs | RL | fire board - ceiling :1,SHE_DRAWING+SHEET.dgn,Design Model;18 ,SHE-04.SECOND.dgn,Design Model:385808 | A_BSUK_CeilingSoffitFinishes_Suspended | New Construction | A-Ceilings::A_BSUK_CeilingSoffitFinishes_Suspended | Identification - ID | Description: fire board - ceiling
A-FloorsSlabs A_BSUK_Slabs | RL | fire board - ceiling :1,SHE_DRAWING+SHEET.dgn,Design Model;18 ,SHE-04.SECOND.dgn,Design Model:385823 | A_BSUK_CeilingSoffitFinishes_Suspended | New Construction | A-Ceilings::A_BSUK_CeilingSoffitFinishes_Suspended | Identification - ID | Description: fire board - ceiling

# IfcStair: S-Stairs-ConcreteRC (8)
Material: S_BSUK_Stairs
Pset_StairCommon - FireExit: no; HandicapAccessible: no; HasNonSkidSurface: no; IsExternal: no
Thermal Transmittance - Is External: no; Is Below Grade: no
Stair Walkline - Walkline Offset Type: Custom
Stair Spiral - Inner Radius: 0 m; Sweep Angle: 0 deg
Stair Parameters - Monolithic Part Definition: S-Circulation::S_BSUK_Stairs; Stair Part Definition: S-Circulation::S_BSUK_Stairs; Riser Type: <none>; Riser Thickness: 0.02 m; Riser Tread Relationship: Riser Behind Tread; Begin With Riser: yes; End With Riser: no; Riser Part Definition: S-Circulation::S_BSUK_Stairs; Begin with Riser at Landings: yes; End with Riser at Landings: yes; Base Riser Offset: 0 m; Top Riser Offset: 0 m; Minimum Inside Depth: 0.1 m; Tread Type: Plane; Tread Thickness: 0.03 m; Tread Nosing Distance: 0.025 m; Tread Nosing Profile: <none>; Tread Part Definition: S-Circulation::S_BSUK_Stairs; Tread Nosing Radius/Chamfer: 0.015 m; Stringer Base Offset: 0 m; Stringer Top Seat Offset: 0 m; Stringer Profile: UC203x203x60; Carriage Offset: 0.2 m; Carriage Inset: 0 m; Stringer Offset: 0.0459 m; Left Stringer Type: <none>; Right Stringer Type: <none>; Stringer Part Definition: S-Circulation::S_BSUK_Stairs; Base Profile: Horizontal; Base Seat Distance: 0 m; Base Extension Type: Vertical; Base Extension Distance: 0 m; Top Profile: Vertical; Top Seat Distance: 0 m; Top Extension Type: Horizontal; Top Extension Distance: 0 m; Top Trim Distance: 0.002 m; Monolithic: yes; Monolithic Underside Profile: Smooth; Landing Thickness: 0.2 m; Landing Stringer Offset: 0.0459 m; Landing Part Definition: S-Circulation::S_BSUK_Stairs; Extend Landing On Approach: no; Extend Landing On Departure: no; Fire Exit: no; Place of Refuge: no; Break Line: Slanted; Display Fire Escape Rounding: no; 2D-Display: Undefined; BreakLine Distance: 0.28 m; BreakLine Weight: 1; CenterLine: yes; Up Label: UP; Display Up Label: no; Display Up Start Point And Arrow: yes; Display Nosing: yes; Display Stair Numbers: no; Stair Number By: Tread Number; Stair Number Location: 30; Extend Up Down Arrows: no; Down Label: DN; Display Down Graphics: no; Display Down Label: no; Display Down Arrow: no
Stair Dimensions - Riser Recommended Number: 20
Quantities - Tread Volume: 0 m3; Riser Volume: 0 m3; Landing Top Area: 0 m2; Landing Bottom Area: 0 m2; Landing Side Area: 0 m2; Landing Perimeter: 0 m; Landing Volume: 0 m3; Left Stringer Length: 0 m; Right Stringer Length: 0 m
Identification - ID | Description: Insitu reinforced concrete stairs
Discipline - Discipline: Structural
Construction Phase - Phase: Existing to Remain
Classification - Uniclass2015: Ss_35_10_85
Accessibility - Accessibility | Handicap Accessible: no; Has Non-skid Surface: no
Name | In | Description | NumberOfRiser = Riser Actual Number = Number Of Treads | RiserHeight (m) = Riser Actual Height (m) | TreadLength (m) = Tread Depth (m) | Walkline Offset (m) | Stair Width (m) | Riser Target Height (m) | Stair Height (m) | Stair Actual Slope | Tread Area (m2) | Riser Area (m2)
S-Stairs-ConcreteRC | RL | Insitu reinforced concrete stairs :1,SHE_DRAWING+SHEET.dgn,Design Model;1 ,SHE-01.GROUND.dgn,Design Model:95231 | 16 | 0.189812 | 0.254 | 0.54 | 1.08 | 0.19 | 3.037 | 36.770000 | 4.82112 | 3.30829
S-Stairs-ConcreteRC | GF | Insitu reinforced concrete stairs :1,SHE_DRAWING+SHEET.dgn,Design Model;16 ,SHE-12.STAIR.dgn,Design Model:220524 | 6 | 0.175 | 0.28 | 0.525 | 1.1 | 0.175 | 1.05 | 32.01 | 1.815 | 1.16673
S-Stairs-ConcreteRC | GF | Insitu reinforced concrete stairs :1,SHE_DRAWING+SHEET.dgn,Design Model;16 ,SHE-12.STAIR.dgn,Design Model:220549 | 14 | 0.185714 | 0.24 | 0.525 | 1.1 | 0.186 | 2.6 | 37.730000 | 4.081 | 2.8858
S-Stairs-ConcreteRC | GF | Insitu reinforced concrete stairs :1,SHE_DRAWING+SHEET.dgn,Design Model;16 ,SHE-12.STAIR.dgn,Design Model:220670 | 9 | 0.182222 | 0.25 | 0.525 | 1.1 | 0.185 | 1.64 | 36.090000 | 2.7225 | 1.8209
S-Stairs-ConcreteRC | GF | Insitu reinforced concrete stairs :1,SHE_DRAWING+SHEET.dgn,Design Model;16 ,SHE-12.STAIR.dgn,Design Model:220701 | 10 | 0.185 | 0.25 | 0.525 | 1.1 | 0.185 | 1.85 | 36.500000 | 3.025 | 2.0535
S-Stairs-ConcreteRC | GF | Insitu reinforced concrete stairs :1,SHE_DRAWING+SHEET.dgn,Design Model;16 ,SHE-12.STAIR.dgn,Design Model:224369 | 10 | 0.185 | 0.28 | 0.525 | 1.1 | 0.185 | 1.85 | 33.45 | 3.025 | 2.0535
S-Stairs-ConcreteRC | GF | Insitu reinforced concrete stairs :1,SHE_DRAWING+SHEET.dgn,Design Model;16 ,SHE-12.STAIR.dgn,Design Model:224402 | 4 | 0.175 | 0.28 | 0.525 | 1.1 | 0.175 | 0.7 | 32.01 | 1.21 | 0.777817
S-Stairs-ConcreteRC | GF | Insitu reinforced concrete stairs :1,SHE_DRAWING+SHEET.dgn,Design Model;16 ,SHE-12.STAIR.dgn,Design Model:230112 | 10 | 0.185 | 0.25 | 0.525 | 1.1 | 0.185 | 1.8 | 36.500000 | 3.025 | 2.0535

# IfcSystem (9)
Name | Description
SVP | SVP,Parameters.System ID
RW | RW,Parameters.System ID
SVP3 | SVP3,Parameters.System ID
SVP3-4-5 | SVP3-4-5 ,Parameters.System ID
SVP3-4-5-6 | SVP3-4-5-6 ,Parameters.System ID
SVP1 | SVP1,Parameters.System ID
EXT. Flat | EXT. Flat ,Parameters.System ID
EXT. AOV | EXT. AOV ,Parameters.System ID
DRM | DRM,Parameters.System ID

# IfcTransportElement: A-Ladder-withCage
In: GF
Type - Parametric Definition - Parametric | File Type: PAZ; Parametric | File Name: Ladder_Cage
Type - Discipline - Discipline: Architectural
Type - Construction Phase - Phase: New Construction
Type - Classification - Uniclass2015: Pr_25_30_85
Description: 1 ,SHE_DRAWING+SHEET.dgn,Design Model;16,SHE-12.STAIR.dgn,Design Model:112904; CapacityByWeight: 0 g; CapacityByNumber: 0; Material: A_BSUK_OtherFfe

# IfcWall: A-Walls-ExternalBlock (260)
In: RL
Type - Wall Parameters - Type: Wall; Compound Wall Assembly: no
Type - Thermal Transmittance - Is External: yes; Is Below Grade: no
Type - Structural Usage - Structural | Material: Blockwork
Type - Space Bounding - Is Space Bounding: yes
Type - Materials - Part Definition: A-Walls::A_BSUK_WallsExternal_Block
Type - LEED Parameters - LEED | Pre-consumer Recycled (%): 0; LEED | Regional Material: no; LEED | Post-consumer Recycled (%): 0
Type - Fire Resistance - Fire | IsCombustible: no; Fire | Compartmentation: no
Type - Discipline - Discipline: Architectural
Type - Classification - Uniclass2015: Pr_20_93_52_01
Pset_WallCommon - Combustible: no; Compartmentation: no; IsExternal: yes; LoadBearing: no
Name | Description | Material | ID | Description | ID | Notes | Phase
A-Walls-ExternalBlock | Wall existing :1,SHE_DRAWING+SHEET.dgn,Design Model;1,SHE-01.GROUND.dgn ,Design Model:95457 | A_BSUK_WallsExternal_Block | Wall existing | general | Existing to Remain
A-Walls-ExternalBlock | Wall existing :1,SHE_DRAWING+SHEET.dgn,Design Model;1,SHE-01.GROUND.dgn ,Design Model:95493 | A_BSUK_WallsExternal_Block | Wall existing | general | Existing to Remain
A-Walls-ExternalBlock | Wall existing :1,SHE_DRAWING+SHEET.dgn,Design Model;1,SHE-01.GROUND.dgn ,Design Model:95502 | A_BSUK_WallsExternal_Block | Wall existing | general | Existing to Remain
A-Walls-ExternalBlock | Wall existing :1,SHE_DRAWING+SHEET.dgn,Design Model;1,SHE-01.GROUND.dgn ,Design Model:95511 | A_BSUK_WallsExternal_Block | Wall existing | general | Existing to Remain
A-Walls-ExternalBlock | Wall existing :1,SHE_DRAWING+SHEET.dgn,Design Model;1,SHE-01.GROUND.dgn ,Design Model:95524 | A_BSUK_WallsExternal_Block | Wall existing | general | Existing to Remain
A-Walls-ExternalBlock | Wall existing :1,SHE_DRAWING+SHEET.dgn,Design Model;1,SHE-01.GROUND.dgn ,Design Model:95543 | A_BSUK_WallsExternal_Block | Wall existing | general | Existing to Remain
A-Walls-ExternalBlock | Wall existing :1,SHE_DRAWING+SHEET.dgn,Design Model;1,SHE-01.GROUND.dgn ,Design Model:95939 | A_BSUK_WallsExternal_Block | Wall existing | general | Existing to Remain
A-Walls-ExternalBlock | Wall existing :1,SHE_DRAWING+SHEET.dgn,Design Model;1,SHE-01.GROUND.dgn ,Design Model:95964 | A_BSUK_WallsExternal_Block | Wall existing | general | Existing to Remain
A-Walls-ExternalBlock | Wall existing :1,SHE_DRAWING+SHEET.dgn,Design Model;1,SHE-01.GROUND.dgn ,Design Model:95979 | A_BSUK_WallsExternal_Block | Wall existing | general | Existing to Remain
A-Walls-ExternalBlock | Wall existing :1,SHE_DRAWING+SHEET.dgn,Design Model;1,SHE-01.GROUND.dgn ,Design Model:96004 | A_BSUK_WallsExternal_Block | Wall existing | general | Existing to Remain
A-Walls-ExternalBlock | Wall existing :1,SHE_DRAWING+SHEET.dgn,Design Model;1,SHE-01.GROUND.dgn ,Design Model:96013 | A_BSUK_WallsExternal_Block | Wall existing | general | Existing to Remain
A-Walls-ExternalBlock | Wall existing :1,SHE_DRAWING+SHEET.dgn,Design Model;1,SHE-01.GROUND.dgn ,Design Model:96022 | A_BSUK_WallsExternal_Block | Wall existing | general | Existing to Remain
A-Walls-ExternalBlock | Wall existing :1,SHE_DRAWING+SHEET.dgn,Design Model;1,SHE-01.GROUND.dgn ,Design Model:96043 | A_BSUK_WallsExternal_Block | Wall existing | general | Existing to Remain
A-Walls-ExternalBlock | Wall existing :1,SHE_DRAWING+SHEET.dgn,Design Model;1,SHE-01.GROUND.dgn ,Design Model:96097 | A_BSUK_WallsExternal_Block | Wall existing | general | Existing to Remain
A-Walls-ExternalBlock | Wall existing :1,SHE_DRAWING+SHEET.dgn,Design Model;1,SHE-01.GROUND.dgn ,Design Model:96106 | A_BSUK_WallsExternal_Block | Wall existing | general | Existing to Remain
A-Walls-ExternalBlock | Wall existing :1,SHE_DRAWING+SHEET.dgn,Design Model;1,SHE-01.GROUND.dgn ,Design Model:96133 | A_BSUK_WallsExternal_Block | Wall existing | general | Existing to Remain
A-Walls-ExternalBlock | Wall existing :1,SHE_DRAWING+SHEET.dgn,Design Model;1,SHE-01.GROUND.dgn ,Design Model:96142 | A_BSUK_WallsExternal_Block | Wall existing | general | Existing to Remain
A-Walls-ExternalBlock | Wall existing :1,SHE_DRAWING+SHEET.dgn,Design Model;1,SHE-01.GROUND.dgn ,Design Model:96187 | A_BSUK_WallsExternal_Block | Wall existing | general | Existing to Remain
A-Walls-ExternalBlock | Wall existing :1,SHE_DRAWING+SHEET.dgn,Design Model;1,SHE-01.GROUND.dgn ,Design Model:96222 | A_BSUK_WallsExternal_Block | Wall existing | general | Existing to Remain
A-Walls-ExternalBlock | Wall existing :1,SHE_DRAWING+SHEET.dgn,Design Model;1,SHE-01.GROUND.dgn ,Design Model:96250 | A_BSUK_WallsExternal_Block | Wall existing | general | Existing to Remain
A-Walls-ExternalBlock | Wall existing :1,SHE_DRAWING+SHEET.dgn,Design Model;1,SHE-01.GROUND.dgn ,Design Model:96265 | A_BSUK_WallsExternal_Block | Wall existing | general | Existing to Remain
A-Walls-ExternalBlock | Wall existing :1,SHE_DRAWING+SHEET.dgn,Design Model;1,SHE-01.GROUND.dgn ,Design Model:96274 | A_BSUK_WallsExternal_Block | Wall existing | general | Existing to Remain
A-Walls-ExternalBlock | Wall existing :1,SHE_DRAWING+SHEET.dgn,Design Model;1,SHE-01.GROUND.dgn ,Design Model:96377 | A_BSUK_WallsExternal_Block | Wall existing | general | Existing to Remain
A-Walls-ExternalBlock | Wall existing :1,SHE_DRAWING+SHEET.dgn,Design Model;1,SHE-01.GROUND.dgn ,Design Model:96386 | A_BSUK_WallsExternal_Block | Wall existing | general | Existing to Remain
A-Walls-ExternalBlock | Wall existing :1,SHE_DRAWING+SHEET.dgn,Design Model;1,SHE-01.GROUND.dgn ,Design Model:96648 | A_BSUK_WallsExternal_Block | Wall existing | general | Existing to Remain
A-Walls-ExternalBlock | Wall existing :1,SHE_DRAWING+SHEET.dgn,Design Model;1,SHE-01.GROUND.dgn ,Design Model:96657 | A_BSUK_WallsExternal_Block | Wall existing | general | Existing to Remain
A-Walls-ExternalBlock | Wall existing :1,SHE_DRAWING+SHEET.dgn,Design Model;1,SHE-01.GROUND.dgn ,Design Model:287316 | A_BSUK_WallsExternal_Block | Wall existing | general | Existing to Remain
A-Walls-ExternalBlock | Wall existing :1,SHE_DRAWING+SHEET.dgn,Design Model;2,SHE-02.MEZZANINE.dgn ,Design Model:93176 | A_BSUK_WallsExternal_Block | Wall existing | general | Existing to Remain
A-Walls-ExternalBlock | Wall existing :1,SHE_DRAWING+SHEET.dgn,Design Model;2,SHE-02.MEZZANINE.dgn ,Design Model:93185 | A_BSUK_WallsExternal_Block | Wall existing | general | Existing to Remain
A-Walls-ExternalBlock | Wall existing :1,SHE_DRAWING+SHEET.dgn,Design Model;2,SHE-02.MEZZANINE.dgn ,Design Model:93194 | A_BSUK_WallsExternal_Block | Wall existing | general | Existing to Remain
A-Walls-ExternalBlock | Wall existing :1,SHE_DRAWING+SHEET.dgn,Design Model;2,SHE-02.MEZZANINE.dgn ,Design Model:93203 | A_BSUK_WallsExternal_Block | Wall existing | general | Existing to Remain
A-Walls-ExternalBlock | Wall existing :1,SHE_DRAWING+SHEET.dgn,Design Model;2,SHE-02.MEZZANINE.dgn ,Design Model:93212 | A_BSUK_WallsExternal_Block | Wall existing | general | Existing to Remain
A-Walls-ExternalBlock | Wall existing :1,SHE_DRAWING+SHEET.dgn,Design Model;2,SHE-02.MEZZANINE.dgn ,Design Model:93223 | A_BSUK_WallsExternal_Block | Wall existing | general | Existing to Remain
A-Walls-ExternalBlock | Wall existing :1,SHE_DRAWING+SHEET.dgn,Design Model;2,SHE-02.MEZZANINE.dgn ,Design Model:93232 | A_BSUK_WallsExternal_Block | Wall existing | general | Existing to Remain
A-Walls-ExternalBlock | Wall existing :1,SHE_DRAWING+SHEET.dgn,Design Model;2,SHE-02.MEZZANINE.dgn ,Design Model:93241 | A_BSUK_WallsExternal_Block | Wall existing | general | Existing to Remain
A-Walls-ExternalBlock | Wall existing :1,SHE_DRAWING+SHEET.dgn,Design Model;2,SHE-02.MEZZANINE.dgn ,Design Model:93250 | A_BSUK_WallsExternal_Block | Wall existing | general | Existing to Remain
A-Walls-ExternalBlock | Wall existing :1,SHE_DRAWING+SHEET.dgn,Design Model;2,SHE-02.MEZZANINE.dgn ,Design Model:93259 | A_BSUK_WallsExternal_Block | Wall existing | general | Existing to Remain
A-Walls-ExternalBlock | Wall existing :1,SHE_DRAWING+SHEET.dgn,Design Model;2,SHE-02.MEZZANINE.dgn ,Design Model:93295 | A_BSUK_WallsExternal_Block | Wall existing | general | Existing to Remain
A-Walls-ExternalBlock | Wall existing :1,SHE_DRAWING+SHEET.dgn,Design Model;2,SHE-02.MEZZANINE.dgn ,Design Model:93306 | A_BSUK_WallsExternal_Block | Wall existing | general | Existing to Remain
A-Walls-ExternalBlock | Wall existing :1,SHE_DRAWING+SHEET.dgn,Design Model;2,SHE-02.MEZZANINE.dgn ,Design Model:93335 | A_BSUK_WallsExternal_Block | Wall existing | general | Existing to Remain
A-Walls-ExternalBlock | Wall existing :1,SHE_DRAWING+SHEET.dgn,Design Model;2,SHE-02.MEZZANINE.dgn ,Design Model:93344 | A_BSUK_WallsExternal_Block | Wall existing | general | Existing to Remain
A-Walls-ExternalBlock | Wall existing :1,SHE_DRAWING+SHEET.dgn,Design Model;2,SHE-02.MEZZANINE.dgn ,Design Model:93353 | A_BSUK_WallsExternal_Block | Wall existing | general | Existing to Remain
A-Walls-ExternalBlock | Wall existing :1,SHE_DRAWING+SHEET.dgn,Design Model;2,SHE-02.MEZZANINE.dgn ,Design Model:93369 | A_BSUK_WallsExternal_Block | Wall existing | general | Existing to Remain
A-Walls-ExternalBlock | Wall existing :1,SHE_DRAWING+SHEET.dgn,Design Model;2,SHE-02.MEZZANINE.dgn ,Design Model:93388 | A_BSUK_WallsExternal_Block | Wall existing | general | Existing to Remain
A-Walls-ExternalBlock | Wall existing :1,SHE_DRAWING+SHEET.dgn,Design Model;2,SHE-02.MEZZANINE.dgn ,Design Model:93397 | A_BSUK_WallsExternal_Block | Wall existing | general | Existing to Remain
A-Walls-ExternalBlock | Wall existing :1,SHE_DRAWING+SHEET.dgn,Design Model;2,SHE-02.MEZZANINE.dgn ,Design Model:93406 | A_BSUK_WallsExternal_Block | Wall existing | general | Existing to Remain
A-Walls-ExternalBlock | Wall existing :1,SHE_DRAWING+SHEET.dgn,Design Model;2,SHE-02.MEZZANINE.dgn ,Design Model:93415 | A_BSUK_WallsExternal_Block | Wall existing | general | Existing to Remain
A-Walls-ExternalBlock | Wall existing :1,SHE_DRAWING+SHEET.dgn,Design Model;2,SHE-02.MEZZANINE.dgn ,Design Model:93424 | A_BSUK_WallsExternal_Block | Wall existing | general | Existing to Remain
A-Walls-ExternalBlock | Wall existing :1,SHE_DRAWING+SHEET.dgn,Design Model;2,SHE-02.MEZZANINE.dgn ,Design Model:93433 | A_BSUK_WallsExternal_Block | Wall existing | general | Existing to Remain
A-Walls-ExternalBlock | Wall existing :1,SHE_DRAWING+SHEET.dgn,Design Model;2,SHE-02.MEZZANINE.dgn ,Design Model:93442 | A_BSUK_WallsExternal_Block | Wall existing | general | Existing to Remain
A-Walls-ExternalBlock | Wall existing :1,SHE_DRAWING+SHEET.dgn,Design Model;2,SHE-02.MEZZANINE.dgn ,Design Model:93451 | A_BSUK_WallsExternal_Block | Wall existing | general | Existing to Remain
A-Walls-ExternalBlock | Wall existing :1,SHE_DRAWING+SHEET.dgn,Design Model;2,SHE-02.MEZZANINE.dgn ,Design Model:93460 | A_BSUK_WallsExternal_Block | Wall existing | general | Existing to Remain
A-Walls-ExternalBlock | Wall existing :1,SHE_DRAWING+SHEET.dgn,Design Model;2,SHE-02.MEZZANINE.dgn ,Design Model:93469 | A_BSUK_WallsExternal_Block | Wall existing | general | Existing to Remain
A-Walls-ExternalBlock | Wall existing :1,SHE_DRAWING+SHEET.dgn,Design Model;2,SHE-02.MEZZANINE.dgn ,Design Model:93487 | A_BSUK_WallsExternal_Block | Wall existing | general | Existing to Remain
A-Walls-ExternalBlock | Wall existing :1,SHE_DRAWING+SHEET.dgn,Design Model;2,SHE-02.MEZZANINE.dgn ,Design Model:93496 | A_BSUK_WallsExternal_Block | Wall existing | general | Existing to Remain
A-Walls-ExternalBlock | Wall existing :1,SHE_DRAWING+SHEET.dgn,Design Model;2,SHE-02.MEZZANINE.dgn ,Design Model:93505 | A_BSUK_WallsExternal_Block | Wall existing | general | Existing to Remain
A-Walls-ExternalBlock | Wall existing :1,SHE_DRAWING+SHEET.dgn,Design Model;2,SHE-02.MEZZANINE.dgn ,Design Model:93514 | A_BSUK_WallsExternal_Block | Wall existing | general | Existing to Remain
A-Walls-ExternalBlock | Wall existing :1,SHE_DRAWING+SHEET.dgn,Design Model;2,SHE-02.MEZZANINE.dgn ,Design Model:93550 | A_BSUK_WallsExternal_Block | Wall existing | general | Existing to Remain
A-Walls-ExternalBlock | Wall existing :1,SHE_DRAWING+SHEET.dgn,Design Model;2,SHE-02.MEZZANINE.dgn ,Design Model:93595 | A_BSUK_WallsExternal_Block | Wall existing | general | Existing to Remain
A-Walls-ExternalBlock | Wall existing :1,SHE_DRAWING+SHEET.dgn,Design Model;2,SHE-02.MEZZANINE.dgn ,Design Model:93649 | A_BSUK_WallsExternal_Block | Wall existing | general | Existing to Remain
A-Walls-ExternalBlock | Wall existing :1,SHE_DRAWING+SHEET.dgn,Design Model;2,SHE-02.MEZZANINE.dgn ,Design Model:93660 | A_BSUK_WallsExternal_Block | Wall existing | general | Existing to Remain
A-Walls-ExternalBlock | Wall existing :1,SHE_DRAWING+SHEET.dgn,Design Model;2,SHE-02.MEZZANINE.dgn ,Design Model:93681 | A_BSUK_WallsExternal_Block | Wall existing | general | Existing to Remain
A-Walls-ExternalBlock | Wall existing :1,SHE_DRAWING+SHEET.dgn,Design Model;2,SHE-02.MEZZANINE.dgn ,Design Model:93706 | A_BSUK_WallsExternal_Block | Wall existing | general | Existing to Remain
A-Walls-ExternalBlock | Wall existing :1,SHE_DRAWING+SHEET.dgn,Design Model;2,SHE-02.MEZZANINE.dgn ,Design Model:93880 | A_BSUK_WallsExternal_Block | Wall existing | general | Existing to Remain
A-Walls-ExternalBlock | Wall existing :1,SHE_DRAWING+SHEET.dgn,Design Model;2,SHE-02.MEZZANINE.dgn ,Design Model:93889 | A_BSUK_WallsExternal_Block | Wall existing | general | Existing to Remain
A-Walls-ExternalBlock | Wall existing :1,SHE_DRAWING+SHEET.dgn,Design Model;2,SHE-02.MEZZANINE.dgn ,Design Model:93898 | A_BSUK_WallsExternal_Block | Wall existing | general | Existing to Remain
A-Walls-ExternalBlock | Wall existing :1,SHE_DRAWING+SHEET.dgn,Design Model;2,SHE-02.MEZZANINE.dgn ,Design Model:94037 | A_BSUK_WallsExternal_Block | Wall existing | general | Existing to Remain
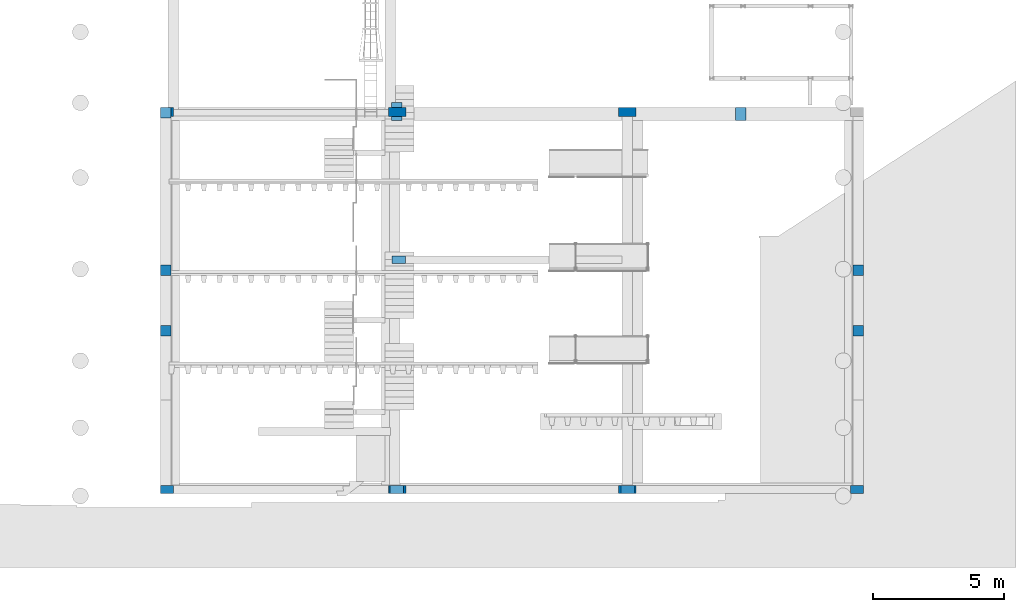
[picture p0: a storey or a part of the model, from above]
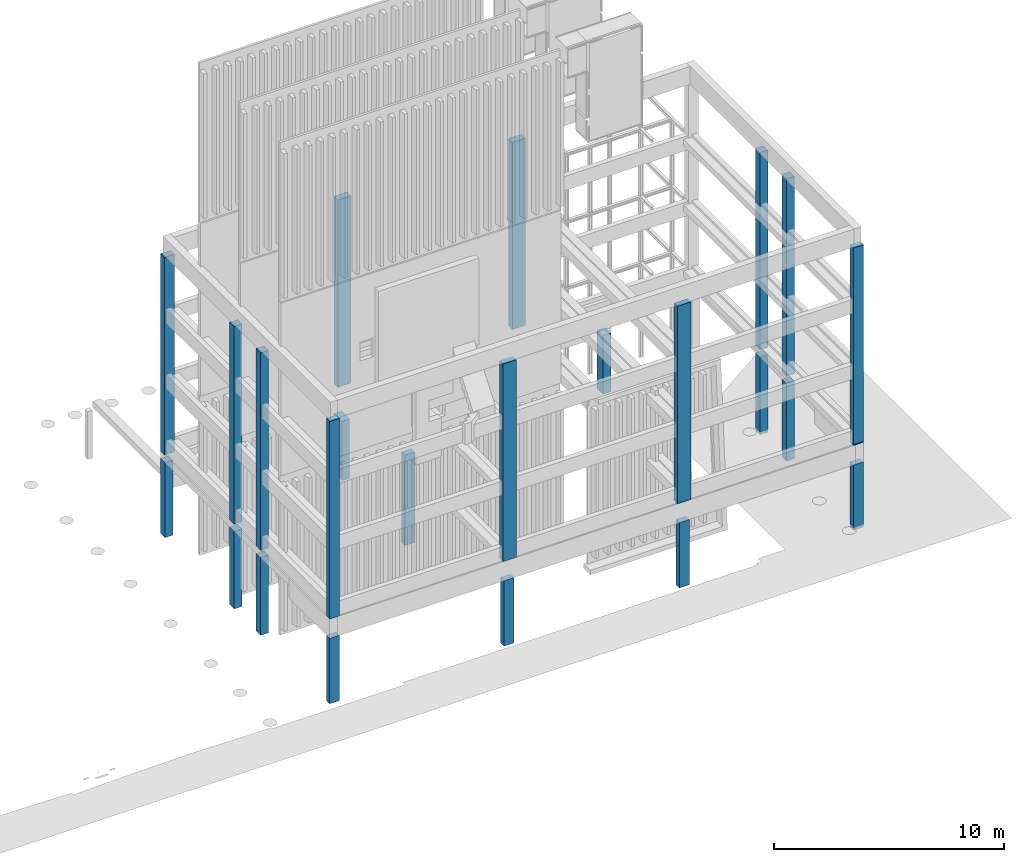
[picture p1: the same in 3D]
Properties of the parts of a building model (IFC2X3), part 12 of 16

# IfcWall: A-Walls-ExternalBlock (260)
Name | Description | Material | ID | Description | ID | Notes | Phase
A-Walls-ExternalBlock | Wall existing :1,SHE_DRAWING+SHEET.dgn,Design Model;2,SHE-02.MEZZANINE.dgn ,Design Model:94046 | A_BSUK_WallsExternal_Block | Wall existing | general | Existing to Remain
A-Walls-ExternalBlock | Upstand :1,SHE_DRAWING+SHEET.dgn,Design Model;2,SHE-02.MEZZANINE.dgn ,Design Model:94055 | A_BSUK_WallsExternal_Block | Upstand | roof light - kdl - flat 1 | New Construction
A-Walls-ExternalBlock | Upstand :1,SHE_DRAWING+SHEET.dgn,Design Model;2,SHE-02.MEZZANINE.dgn ,Design Model:94064 | A_BSUK_WallsExternal_Block | Upstand | roof light - kdl - flat 1 | New Construction
A-Walls-ExternalBlock | Upstand :1,SHE_DRAWING+SHEET.dgn,Design Model;2,SHE-02.MEZZANINE.dgn ,Design Model:94073 | A_BSUK_WallsExternal_Block | Upstand | roof light - kdl - flat 1 | New Construction
A-Walls-ExternalBlock | Upstand :1,SHE_DRAWING+SHEET.dgn,Design Model;2,SHE-02.MEZZANINE.dgn ,Design Model:94082 | A_BSUK_WallsExternal_Block | Upstand | roof light - kdl - flat 1 | New Construction
A-Walls-ExternalBlock | Upstand :1,SHE_DRAWING+SHEET.dgn,Design Model;2,SHE-02.MEZZANINE.dgn ,Design Model:94091 | A_BSUK_WallsExternal_Block | Upstand | roof light - kdl - flat 1 | New Construction
A-Walls-ExternalBlock | Upstand :1,SHE_DRAWING+SHEET.dgn,Design Model;2,SHE-02.MEZZANINE.dgn ,Design Model:94100 | A_BSUK_WallsExternal_Block | Upstand | roof light - kdl - flat 1 | New Construction
A-Walls-ExternalBlock | Upstand :1,SHE_DRAWING+SHEET.dgn,Design Model;2,SHE-02.MEZZANINE.dgn ,Design Model:94109 | A_BSUK_WallsExternal_Block | Upstand | roof light - kdl - flat 1 | New Construction
A-Walls-ExternalBlock | Upstand :1,SHE_DRAWING+SHEET.dgn,Design Model;2,SHE-02.MEZZANINE.dgn ,Design Model:94118 | A_BSUK_WallsExternal_Block | Upstand | roof light - kdl - flat 1 | New Construction
A-Walls-ExternalBlock | Wall existing :1,SHE_DRAWING+SHEET.dgn,Design Model;2,SHE-02.MEZZANINE.dgn ,Design Model:94147 | A_BSUK_WallsExternal_Block | Wall existing | general | Existing to Remain
A-Walls-ExternalBlock | Wall existing :1,SHE_DRAWING+SHEET.dgn,Design Model;2,SHE-02.MEZZANINE.dgn ,Design Model:94201 | A_BSUK_WallsExternal_Block | Wall existing | general | Existing to Remain
A-Walls-ExternalBlock | Wall existing :1,SHE_DRAWING+SHEET.dgn,Design Model;2,SHE-02.MEZZANINE.dgn ,Design Model:94210 | A_BSUK_WallsExternal_Block | Wall existing | general | Existing to Remain
A-Walls-ExternalBlock | Wall existing :1,SHE_DRAWING+SHEET.dgn,Design Model;2,SHE-02.MEZZANINE.dgn ,Design Model:94266 | A_BSUK_WallsExternal_Block | Wall existing | general | Existing to Remain
A-Walls-ExternalBlock | Wall existing :1,SHE_DRAWING+SHEET.dgn,Design Model;2,SHE-02.MEZZANINE.dgn ,Design Model:94275 | A_BSUK_WallsExternal_Block | Wall existing | general | Existing to Remain
A-Walls-ExternalBlock | Wall existing :1,SHE_DRAWING+SHEET.dgn,Design Model;2,SHE-02.MEZZANINE.dgn ,Design Model:94284 | A_BSUK_WallsExternal_Block | Wall existing | general | Existing to Remain
A-Walls-ExternalBlock | Wall existing :1,SHE_DRAWING+SHEET.dgn,Design Model;2,SHE-02.MEZZANINE.dgn ,Design Model:94293 | A_BSUK_WallsExternal_Block | Wall existing | general | Existing to Remain
A-Walls-ExternalBlock | Wall existing :1,SHE_DRAWING+SHEET.dgn,Design Model;2,SHE-02.MEZZANINE.dgn ,Design Model:203521 | A_BSUK_WallsExternal_Block | Wall existing | general | Existing to Remain
A-Walls-ExternalBlock | FacadeBlockwork :1,SHE_DRAWING+SHEET.dgn,Design Model;4,SHE-03.FIRST.dgn ,Design Model:123162 | A_BSUK_WallsExternal_Block | FacadeBlockwork | existing | Existing to Remain
A-Walls-ExternalBlock | FacadeBlockwork :1,SHE_DRAWING+SHEET.dgn,Design Model;4,SHE-03.FIRST.dgn ,Design Model:123171 | A_BSUK_WallsExternal_Block | FacadeBlockwork | existing | Existing to Remain
A-Walls-ExternalBlock | FacadeBlockwork :1,SHE_DRAWING+SHEET.dgn,Design Model;4,SHE-03.FIRST.dgn ,Design Model:123180 | A_BSUK_WallsExternal_Block | FacadeBlockwork | existing | Existing to Remain
A-Walls-ExternalBlock | FacadeBlockwork :1,SHE_DRAWING+SHEET.dgn,Design Model;4,SHE-03.FIRST.dgn ,Design Model:123189 | A_BSUK_WallsExternal_Block | FacadeBlockwork | existing | Existing to Remain
A-Walls-ExternalBlock | FacadeBlockwork :1,SHE_DRAWING+SHEET.dgn,Design Model;4,SHE-03.FIRST.dgn ,Design Model:123198 | A_BSUK_WallsExternal_Block | FacadeBlockwork | existing | Existing to Remain
A-Walls-ExternalBlock | FacadeBlockwork :1,SHE_DRAWING+SHEET.dgn,Design Model;4,SHE-03.FIRST.dgn ,Design Model:123207 | A_BSUK_WallsExternal_Block | FacadeBlockwork | existing | Existing to Remain
A-Walls-ExternalBlock | FacadeBlockwork :1,SHE_DRAWING+SHEET.dgn,Design Model;4,SHE-03.FIRST.dgn ,Design Model:123216 | A_BSUK_WallsExternal_Block | FacadeBlockwork | existing | Existing to Remain
A-Walls-ExternalBlock | FacadeBlockwork :1,SHE_DRAWING+SHEET.dgn,Design Model;4,SHE-03.FIRST.dgn ,Design Model:123225 | A_BSUK_WallsExternal_Block | FacadeBlockwork | existing | Existing to Remain
A-Walls-ExternalBlock | FacadeBlockwork :1,SHE_DRAWING+SHEET.dgn,Design Model;4,SHE-03.FIRST.dgn ,Design Model:124098 | A_BSUK_WallsExternal_Block | FacadeBlockwork | existing | Existing to Remain
A-Walls-ExternalBlock | FacadeBlockwork :1,SHE_DRAWING+SHEET.dgn,Design Model;4,SHE-03.FIRST.dgn ,Design Model:124107 | A_BSUK_WallsExternal_Block | FacadeBlockwork | existing | Existing to Remain
A-Walls-ExternalBlock | FacadeBlockwork :1,SHE_DRAWING+SHEET.dgn,Design Model;4,SHE-03.FIRST.dgn ,Design Model:124116 | A_BSUK_WallsExternal_Block | FacadeBlockwork | existing | Existing to Remain
A-Walls-ExternalBlock | FacadeBlockwork :1,SHE_DRAWING+SHEET.dgn,Design Model;4,SHE-03.FIRST.dgn ,Design Model:124125 | A_BSUK_WallsExternal_Block | FacadeBlockwork | existing | Existing to Remain
A-Walls-ExternalBlock | FacadeBlockwork :1,SHE_DRAWING+SHEET.dgn,Design Model;4,SHE-03.FIRST.dgn ,Design Model:124134 | A_BSUK_WallsExternal_Block | FacadeBlockwork | existing | Existing to Remain
A-Walls-ExternalBlock | FacadeBlockwork :1,SHE_DRAWING+SHEET.dgn,Design Model;4,SHE-03.FIRST.dgn ,Design Model:124143 | A_BSUK_WallsExternal_Block | FacadeBlockwork | existing | Existing to Remain
A-Walls-ExternalBlock | FacadeBlockwork :1,SHE_DRAWING+SHEET.dgn,Design Model;4,SHE-03.FIRST.dgn ,Design Model:124152 | A_BSUK_WallsExternal_Block | FacadeBlockwork | existing | Existing to Remain
A-Walls-ExternalBlock | FacadeBlockwork :1,SHE_DRAWING+SHEET.dgn,Design Model;4,SHE-03.FIRST.dgn ,Design Model:124161 | A_BSUK_WallsExternal_Block | FacadeBlockwork | existing | Existing to Remain
A-Walls-ExternalBlock | FacadeBlockwork :1,SHE_DRAWING+SHEET.dgn,Design Model;4,SHE-03.FIRST.dgn ,Design Model:124170 | A_BSUK_WallsExternal_Block | FacadeBlockwork | existing | Existing to Remain
A-Walls-ExternalBlock | FacadeBlockwork :1,SHE_DRAWING+SHEET.dgn,Design Model;4,SHE-03.FIRST.dgn ,Design Model:124179 | A_BSUK_WallsExternal_Block | FacadeBlockwork | existing | Existing to Remain
A-Walls-ExternalBlock | FacadeBlockwork :1,SHE_DRAWING+SHEET.dgn,Design Model;4,SHE-03.FIRST.dgn ,Design Model:124188 | A_BSUK_WallsExternal_Block | FacadeBlockwork | existing | Existing to Remain
A-Walls-ExternalBlock | FacadeBlockwork :1,SHE_DRAWING+SHEET.dgn,Design Model;4,SHE-03.FIRST.dgn ,Design Model:124197 | A_BSUK_WallsExternal_Block | FacadeBlockwork | existing | Existing to Remain
A-Walls-ExternalBlock | FacadeBlockwork :1,SHE_DRAWING+SHEET.dgn,Design Model;4,SHE-03.FIRST.dgn ,Design Model:124206 | A_BSUK_WallsExternal_Block | FacadeBlockwork | existing | Existing to Remain
A-Walls-ExternalBlock | FacadeBlockwork :1,SHE_DRAWING+SHEET.dgn,Design Model;4,SHE-03.FIRST.dgn ,Design Model:124215 | A_BSUK_WallsExternal_Block | FacadeBlockwork | existing | Existing to Remain
A-Walls-ExternalBlock | FacadeBlockwork :1,SHE_DRAWING+SHEET.dgn,Design Model;4,SHE-03.FIRST.dgn ,Design Model:124224 | A_BSUK_WallsExternal_Block | FacadeBlockwork | existing | Existing to Remain
A-Walls-ExternalBlock | FacadeBlockwork :1,SHE_DRAWING+SHEET.dgn,Design Model;4,SHE-03.FIRST.dgn ,Design Model:124233 | A_BSUK_WallsExternal_Block | FacadeBlockwork | existing | Existing to Remain
A-Walls-ExternalBlock | FacadeBlockwork :1,SHE_DRAWING+SHEET.dgn,Design Model;4,SHE-03.FIRST.dgn ,Design Model:124242 | A_BSUK_WallsExternal_Block | FacadeBlockwork | existing | Existing to Remain
A-Walls-ExternalBlock | FacadeBlockwork :1,SHE_DRAWING+SHEET.dgn,Design Model;4,SHE-03.FIRST.dgn ,Design Model:124251 | A_BSUK_WallsExternal_Block | FacadeBlockwork | existing | Existing to Remain
A-Walls-ExternalBlock | FacadeBlockwork :1,SHE_DRAWING+SHEET.dgn,Design Model;4,SHE-03.FIRST.dgn ,Design Model:124800 | A_BSUK_WallsExternal_Block | FacadeBlockwork | existing | Existing to Remain
A-Walls-ExternalBlock | FacadeBlockwork :1,SHE_DRAWING+SHEET.dgn,Design Model;4,SHE-03.FIRST.dgn ,Design Model:124809 | A_BSUK_WallsExternal_Block | FacadeBlockwork | existing | Existing to Remain
A-Walls-ExternalBlock | FacadeBlockwork :1,SHE_DRAWING+SHEET.dgn,Design Model;4,SHE-03.FIRST.dgn ,Design Model:124818 | A_BSUK_WallsExternal_Block | FacadeBlockwork | existing | Existing to Remain
A-Walls-ExternalBlock | FacadeBlockwork :1,SHE_DRAWING+SHEET.dgn,Design Model;4,SHE-03.FIRST.dgn ,Design Model:124827 | A_BSUK_WallsExternal_Block | FacadeBlockwork | existing | Existing to Remain
A-Walls-ExternalBlock | FacadeBlockwork :1,SHE_DRAWING+SHEET.dgn,Design Model;4,SHE-03.FIRST.dgn ,Design Model:124836 | A_BSUK_WallsExternal_Block | FacadeBlockwork | existing | Existing to Remain
A-Walls-ExternalBlock | FacadeBlockwork :1,SHE_DRAWING+SHEET.dgn,Design Model;4,SHE-03.FIRST.dgn ,Design Model:125043 | A_BSUK_WallsExternal_Block | FacadeBlockwork | existing | Existing to Remain
A-Walls-ExternalBlock | FacadeBlockwork :1,SHE_DRAWING+SHEET.dgn,Design Model;4,SHE-03.FIRST.dgn ,Design Model:341944 | A_BSUK_WallsExternal_Block | FacadeBlockwork | existing | Existing to Remain
A-Walls-ExternalBlock | FacadeBlockwork :1,SHE_DRAWING+SHEET.dgn,Design Model;4,SHE-03.FIRST.dgn ,Design Model:341953 | A_BSUK_WallsExternal_Block | FacadeBlockwork | existing | Existing to Remain
A-Walls-ExternalBlock | FacadeBlockwork :1,SHE_DRAWING+SHEET.dgn,Design Model;4,SHE-03.FIRST.dgn ,Design Model:341962 | A_BSUK_WallsExternal_Block | FacadeBlockwork | existing | Existing to Remain
A-Walls-ExternalBlock | FacadeBlockwork :1,SHE_DRAWING+SHEET.dgn,Design Model;4,SHE-03.FIRST.dgn ,Design Model:341971 | A_BSUK_WallsExternal_Block | FacadeBlockwork | existing | Existing to Remain
A-Walls-ExternalBlock | FacadeBlockwork :1,SHE_DRAWING+SHEET.dgn,Design Model;4,SHE-03.FIRST.dgn ,Design Model:341980 | A_BSUK_WallsExternal_Block | FacadeBlockwork | existing | Existing to Remain
A-Walls-ExternalBlock | FacadeBlockwork :1,SHE_DRAWING+SHEET.dgn,Design Model;4,SHE-03.FIRST.dgn ,Design Model:341989 | A_BSUK_WallsExternal_Block | FacadeBlockwork | existing | Existing to Remain
A-Walls-ExternalBlock | FacadeBlockwork :1,SHE_DRAWING+SHEET.dgn,Design Model;4,SHE-03.FIRST.dgn ,Design Model:341998 | A_BSUK_WallsExternal_Block | FacadeBlockwork | existing | Existing to Remain
A-Walls-ExternalBlock | FacadeBlockwork :1,SHE_DRAWING+SHEET.dgn,Design Model;4,SHE-03.FIRST.dgn ,Design Model:342007 | A_BSUK_WallsExternal_Block | FacadeBlockwork | existing | Existing to Remain
A-Walls-ExternalBlock | FacadeBlockwork :1,SHE_DRAWING+SHEET.dgn,Design Model;4,SHE-03.FIRST.dgn ,Design Model:342016 | A_BSUK_WallsExternal_Block | FacadeBlockwork | existing | Existing to Remain
A-Walls-ExternalBlock | FacadeBlockwork :1,SHE_DRAWING+SHEET.dgn,Design Model;4,SHE-03.FIRST.dgn ,Design Model:350342 | A_BSUK_WallsExternal_Block | FacadeBlockwork | existing | Existing to Remain
A-Walls-ExternalBlock | FacadeBlockwork :1,SHE_DRAWING+SHEET.dgn,Design Model;6,SHE-05.THIRD.dgn ,Design Model:123162 | A_BSUK_WallsExternal_Block | FacadeBlockwork | existing | Existing to Remain
A-Walls-ExternalBlock | FacadeBlockwork :1,SHE_DRAWING+SHEET.dgn,Design Model;6,SHE-05.THIRD.dgn ,Design Model:123171 | A_BSUK_WallsExternal_Block | FacadeBlockwork | existing | Existing to Remain
A-Walls-ExternalBlock | FacadeBlockwork :1,SHE_DRAWING+SHEET.dgn,Design Model;6,SHE-05.THIRD.dgn ,Design Model:123180 | A_BSUK_WallsExternal_Block | FacadeBlockwork | existing | Existing to Remain
A-Walls-ExternalBlock | FacadeBlockwork :1,SHE_DRAWING+SHEET.dgn,Design Model;6,SHE-05.THIRD.dgn ,Design Model:123189 | A_BSUK_WallsExternal_Block | FacadeBlockwork | existing | Existing to Remain
A-Walls-ExternalBlock | FacadeBlockwork :1,SHE_DRAWING+SHEET.dgn,Design Model;6,SHE-05.THIRD.dgn ,Design Model:123198 | A_BSUK_WallsExternal_Block | FacadeBlockwork | existing | Existing to Remain
A-Walls-ExternalBlock | FacadeBlockwork :1,SHE_DRAWING+SHEET.dgn,Design Model;6,SHE-05.THIRD.dgn ,Design Model:123207 | A_BSUK_WallsExternal_Block | FacadeBlockwork | existing | Existing to Remain
A-Walls-ExternalBlock | FacadeBlockwork :1,SHE_DRAWING+SHEET.dgn,Design Model;6,SHE-05.THIRD.dgn ,Design Model:123216 | A_BSUK_WallsExternal_Block | FacadeBlockwork | existing | Existing to Remain
A-Walls-ExternalBlock | FacadeBlockwork :1,SHE_DRAWING+SHEET.dgn,Design Model;6,SHE-05.THIRD.dgn ,Design Model:123225 | A_BSUK_WallsExternal_Block | FacadeBlockwork | existing | Existing to Remain
A-Walls-ExternalBlock | FacadeBlockwork :1,SHE_DRAWING+SHEET.dgn,Design Model;6,SHE-05.THIRD.dgn ,Design Model:124098 | A_BSUK_WallsExternal_Block | FacadeBlockwork | existing | Existing to Remain
A-Walls-ExternalBlock | FacadeBlockwork :1,SHE_DRAWING+SHEET.dgn,Design Model;6,SHE-05.THIRD.dgn ,Design Model:124107 | A_BSUK_WallsExternal_Block | FacadeBlockwork | existing | Existing to Remain
A-Walls-ExternalBlock | FacadeBlockwork :1,SHE_DRAWING+SHEET.dgn,Design Model;6,SHE-05.THIRD.dgn ,Design Model:124116 | A_BSUK_WallsExternal_Block | FacadeBlockwork | existing | Existing to Remain
A-Walls-ExternalBlock | FacadeBlockwork :1,SHE_DRAWING+SHEET.dgn,Design Model;6,SHE-05.THIRD.dgn ,Design Model:124125 | A_BSUK_WallsExternal_Block | FacadeBlockwork | existing | Existing to Remain
A-Walls-ExternalBlock | FacadeBlockwork :1,SHE_DRAWING+SHEET.dgn,Design Model;6,SHE-05.THIRD.dgn ,Design Model:124134 | A_BSUK_WallsExternal_Block | FacadeBlockwork | existing | Existing to Remain
A-Walls-ExternalBlock | FacadeBlockwork :1,SHE_DRAWING+SHEET.dgn,Design Model;6,SHE-05.THIRD.dgn ,Design Model:124143 | A_BSUK_WallsExternal_Block | FacadeBlockwork | existing | Existing to Remain
A-Walls-ExternalBlock | FacadeBlockwork :1,SHE_DRAWING+SHEET.dgn,Design Model;6,SHE-05.THIRD.dgn ,Design Model:124152 | A_BSUK_WallsExternal_Block | FacadeBlockwork | existing | Existing to Remain
A-Walls-ExternalBlock | FacadeBlockwork :1,SHE_DRAWING+SHEET.dgn,Design Model;6,SHE-05.THIRD.dgn ,Design Model:124161 | A_BSUK_WallsExternal_Block | FacadeBlockwork | existing | Existing to Remain
A-Walls-ExternalBlock | FacadeBlockwork :1,SHE_DRAWING+SHEET.dgn,Design Model;6,SHE-05.THIRD.dgn ,Design Model:124170 | A_BSUK_WallsExternal_Block | FacadeBlockwork | existing | Existing to Remain
A-Walls-ExternalBlock | FacadeBlockwork :1,SHE_DRAWING+SHEET.dgn,Design Model;6,SHE-05.THIRD.dgn ,Design Model:124179 | A_BSUK_WallsExternal_Block | FacadeBlockwork | existing | Existing to Remain
A-Walls-ExternalBlock | FacadeBlockwork :1,SHE_DRAWING+SHEET.dgn,Design Model;6,SHE-05.THIRD.dgn ,Design Model:124188 | A_BSUK_WallsExternal_Block | FacadeBlockwork | existing | Existing to Remain
A-Walls-ExternalBlock | FacadeBlockwork :1,SHE_DRAWING+SHEET.dgn,Design Model;6,SHE-05.THIRD.dgn ,Design Model:124197 | A_BSUK_WallsExternal_Block | FacadeBlockwork | existing | Existing to Remain
A-Walls-ExternalBlock | FacadeBlockwork :1,SHE_DRAWING+SHEET.dgn,Design Model;6,SHE-05.THIRD.dgn ,Design Model:124206 | A_BSUK_WallsExternal_Block | FacadeBlockwork | existing | Existing to Remain
A-Walls-ExternalBlock | FacadeBlockwork :1,SHE_DRAWING+SHEET.dgn,Design Model;6,SHE-05.THIRD.dgn ,Design Model:124215 | A_BSUK_WallsExternal_Block | FacadeBlockwork | existing | Existing to Remain
A-Walls-ExternalBlock | FacadeBlockwork :1,SHE_DRAWING+SHEET.dgn,Design Model;6,SHE-05.THIRD.dgn ,Design Model:124224 | A_BSUK_WallsExternal_Block | FacadeBlockwork | existing | Existing to Remain
A-Walls-ExternalBlock | FacadeBlockwork :1,SHE_DRAWING+SHEET.dgn,Design Model;6,SHE-05.THIRD.dgn ,Design Model:124233 | A_BSUK_WallsExternal_Block | FacadeBlockwork | existing | Existing to Remain
A-Walls-ExternalBlock | FacadeBlockwork :1,SHE_DRAWING+SHEET.dgn,Design Model;6,SHE-05.THIRD.dgn ,Design Model:124242 | A_BSUK_WallsExternal_Block | FacadeBlockwork | existing | Existing to Remain
A-Walls-ExternalBlock | FacadeBlockwork :1,SHE_DRAWING+SHEET.dgn,Design Model;6,SHE-05.THIRD.dgn ,Design Model:124251 | A_BSUK_WallsExternal_Block | FacadeBlockwork | existing | Existing to Remain
A-Walls-ExternalBlock | FacadeBlockwork :1,SHE_DRAWING+SHEET.dgn,Design Model;6,SHE-05.THIRD.dgn ,Design Model:124800 | A_BSUK_WallsExternal_Block | FacadeBlockwork | existing | Existing to Remain
A-Walls-ExternalBlock | FacadeBlockwork :1,SHE_DRAWING+SHEET.dgn,Design Model;6,SHE-05.THIRD.dgn ,Design Model:124809 | A_BSUK_WallsExternal_Block | FacadeBlockwork | existing | Existing to Remain
A-Walls-ExternalBlock | FacadeBlockwork :1,SHE_DRAWING+SHEET.dgn,Design Model;6,SHE-05.THIRD.dgn ,Design Model:124818 | A_BSUK_WallsExternal_Block | FacadeBlockwork | existing | Existing to Remain
A-Walls-ExternalBlock | FacadeBlockwork :1,SHE_DRAWING+SHEET.dgn,Design Model;6,SHE-05.THIRD.dgn ,Design Model:124827 | A_BSUK_WallsExternal_Block | FacadeBlockwork | existing | Existing to Remain
A-Walls-ExternalBlock | FacadeBlockwork :1,SHE_DRAWING+SHEET.dgn,Design Model;6,SHE-05.THIRD.dgn ,Design Model:124836 | A_BSUK_WallsExternal_Block | FacadeBlockwork | existing | Existing to Remain
A-Walls-ExternalBlock | FacadeBlockwork :1,SHE_DRAWING+SHEET.dgn,Design Model;6,SHE-05.THIRD.dgn ,Design Model:125043 | A_BSUK_WallsExternal_Block | FacadeBlockwork | existing | Existing to Remain
7C | SFSWall fire lining :1 ,SHE_DRAWING+SHEET.dgn,Design Model;7,SHE-06.FOURTH.dgn,Design Model:100831 | A_BSUK_Roofs | SFSWall fire lining | fire board - internal mansard roof finish | New Construction | Pset_WallCommon - FireRating: F60; Materials - Part Definition: A-Roofs::A_BSUK_Roofs; Identification - ID | Number: 7C; Fire Resistance - Fire | Rating: F60
7C | SFSWall fire lining :1 ,SHE_DRAWING+SHEET.dgn,Design Model;7,SHE-06.FOURTH.dgn,Design Model:100840 | A_BSUK_Roofs | SFSWall fire lining | fire board - internal mansard roof finish | New Construction | Pset_WallCommon - FireRating: F60; Materials - Part Definition: A-Roofs::A_BSUK_Roofs; Identification - ID | Number: 7C; Fire Resistance - Fire | Rating: F60
7C | SFSWall fire lining :1 ,SHE_DRAWING+SHEET.dgn,Design Model;7,SHE-06.FOURTH.dgn,Design Model:100867 | A_BSUK_Roofs | SFSWall fire lining | fire board - internal mansard roof finish | New Construction | Pset_WallCommon - FireRating: F60; Materials - Part Definition: A-Roofs::A_BSUK_Roofs; Identification - ID | Number: 7C; Fire Resistance - Fire | Rating: F60
7C | SFSWall fire lining :1 ,SHE_DRAWING+SHEET.dgn,Design Model;7,SHE-06.FOURTH.dgn,Design Model:100894 | A_BSUK_Roofs | SFSWall fire lining | fire board - internal mansard roof finish | New Construction | Pset_WallCommon - FireRating: F60; Materials - Part Definition: A-Roofs::A_BSUK_Roofs; Identification - ID | Number: 7C; Fire Resistance - Fire | Rating: F60
7C | SFSWall fire lining :1 ,SHE_DRAWING+SHEET.dgn,Design Model;7,SHE-06.FOURTH.dgn,Design Model:100903 | A_BSUK_Roofs | SFSWall fire lining | fire board - internal mansard roof finish | New Construction | Pset_WallCommon - FireRating: F60; Materials - Part Definition: A-Roofs::A_BSUK_Roofs; Identification - ID | Number: 7C; Fire Resistance - Fire | Rating: F60
7C | SFSWall fire lining :1 ,SHE_DRAWING+SHEET.dgn,Design Model;7,SHE-06.FOURTH.dgn,Design Model:100912 | A_BSUK_Roofs | SFSWall fire lining | fire board - internal mansard roof finish | New Construction | Pset_WallCommon - FireRating: F60; Materials - Part Definition: A-Roofs::A_BSUK_Roofs; Identification - ID | Number: 7C; Fire Resistance - Fire | Rating: F60
7C | SFSWall fire lining :1 ,SHE_DRAWING+SHEET.dgn,Design Model;7,SHE-06.FOURTH.dgn,Design Model:100930 | A_BSUK_Roofs | SFSWall fire lining | fire board - internal mansard roof finish | New Construction | Pset_WallCommon - FireRating: F60; Materials - Part Definition: A-Roofs::A_BSUK_Roofs; Identification - ID | Number: 7C; Fire Resistance - Fire | Rating: F60
7C | SFSWall fire lining :1 ,SHE_DRAWING+SHEET.dgn,Design Model;7,SHE-06.FOURTH.dgn,Design Model:100939 | A_BSUK_Roofs | SFSWall fire lining | fire board - internal mansard roof finish | New Construction | Pset_WallCommon - FireRating: F60; Materials - Part Definition: A-Roofs::A_BSUK_Roofs; Identification - ID | Number: 7C; Fire Resistance - Fire | Rating: F60
7C | SFSWall fire lining :1 ,SHE_DRAWING+SHEET.dgn,Design Model;7,SHE-06.FOURTH.dgn,Design Model:100957 | A_BSUK_Roofs | SFSWall fire lining | fire board - internal mansard roof finish | New Construction | Pset_WallCommon - FireRating: F60; Materials - Part Definition: A-Roofs::A_BSUK_Roofs; Identification - ID | Number: 7C; Fire Resistance - Fire | Rating: F60
7C | SFSWall fire lining :1 ,SHE_DRAWING+SHEET.dgn,Design Model;7,SHE-06.FOURTH.dgn,Design Model:100966 | A_BSUK_Roofs | SFSWall fire lining | fire board - internal mansard roof finish | New Construction | Pset_WallCommon - FireRating: F60; Materials - Part Definition: A-Roofs::A_BSUK_Roofs; Identification - ID | Number: 7C; Fire Resistance - Fire | Rating: F60
7C | SFSWall fire lining :1 ,SHE_DRAWING+SHEET.dgn,Design Model;7,SHE-06.FOURTH.dgn,Design Model:100984 | A_BSUK_Roofs | SFSWall fire lining | fire board - internal mansard roof finish | New Construction | Pset_WallCommon - FireRating: F60; Materials - Part Definition: A-Roofs::A_BSUK_Roofs; Identification - ID | Number: 7C; Fire Resistance - Fire | Rating: F60
7C | SFSWall fire lining :1 ,SHE_DRAWING+SHEET.dgn,Design Model;7,SHE-06.FOURTH.dgn,Design Model:100993 | A_BSUK_Roofs | SFSWall fire lining | fire board - internal mansard roof finish | New Construction | Pset_WallCommon - FireRating: F60; Materials - Part Definition: A-Roofs::A_BSUK_Roofs; Identification - ID | Number: 7C; Fire Resistance - Fire | Rating: F60
7C | SFSWall fire lining :1 ,SHE_DRAWING+SHEET.dgn,Design Model;7,SHE-06.FOURTH.dgn,Design Model:101011 | A_BSUK_Roofs | SFSWall fire lining | fire board - internal mansard roof finish | New Construction | Pset_WallCommon - FireRating: F60; Materials - Part Definition: A-Roofs::A_BSUK_Roofs; Identification - ID | Number: 7C; Fire Resistance - Fire | Rating: F60
7C | SFSWall fire lining :1 ,SHE_DRAWING+SHEET.dgn,Design Model;7,SHE-06.FOURTH.dgn,Design Model:101020 | A_BSUK_Roofs | SFSWall fire lining | fire board - internal mansard roof finish | New Construction | Pset_WallCommon - FireRating: F60; Materials - Part Definition: A-Roofs::A_BSUK_Roofs; Identification - ID | Number: 7C; Fire Resistance - Fire | Rating: F60
7C | SFSWall fire lining :1 ,SHE_DRAWING+SHEET.dgn,Design Model;7,SHE-06.FOURTH.dgn,Design Model:101038 | A_BSUK_Roofs | SFSWall fire lining | fire board - internal mansard roof finish | New Construction | Pset_WallCommon - FireRating: F60; Materials - Part Definition: A-Roofs::A_BSUK_Roofs; Identification - ID | Number: 7C; Fire Resistance - Fire | Rating: F60
7C | SFSWall fire lining :1 ,SHE_DRAWING+SHEET.dgn,Design Model;7,SHE-06.FOURTH.dgn,Design Model:101047 | A_BSUK_Roofs | SFSWall fire lining | fire board - internal mansard roof finish | New Construction | Pset_WallCommon - FireRating: F60; Materials - Part Definition: A-Roofs::A_BSUK_Roofs; Identification - ID | Number: 7C; Fire Resistance - Fire | Rating: F60
7C | SFSWall fire lining :1 ,SHE_DRAWING+SHEET.dgn,Design Model;7,SHE-06.FOURTH.dgn,Design Model:101065 | A_BSUK_Roofs | SFSWall fire lining | fire board - internal mansard roof finish | New Construction | Pset_WallCommon - FireRating: F60; Materials - Part Definition: A-Roofs::A_BSUK_Roofs; Identification - ID | Number: 7C; Fire Resistance - Fire | Rating: F60
7C | SFSWall fire lining :1 ,SHE_DRAWING+SHEET.dgn,Design Model;7,SHE-06.FOURTH.dgn,Design Model:101074 | A_BSUK_Roofs | SFSWall fire lining | fire board - internal mansard roof finish | New Construction | Pset_WallCommon - FireRating: F60; Materials - Part Definition: A-Roofs::A_BSUK_Roofs; Identification - ID | Number: 7C; Fire Resistance - Fire | Rating: F60
7C | SFSWall fire lining :1 ,SHE_DRAWING+SHEET.dgn,Design Model;7,SHE-06.FOURTH.dgn,Design Model:101092 | A_BSUK_Roofs | SFSWall fire lining | fire board - internal mansard roof finish | New Construction | Pset_WallCommon - FireRating: F60; Materials - Part Definition: A-Roofs::A_BSUK_Roofs; Identification - ID | Number: 7C; Fire Resistance - Fire | Rating: F60
7C | SFSWall fire lining :1 ,SHE_DRAWING+SHEET.dgn,Design Model;7,SHE-06.FOURTH.dgn,Design Model:101101 | A_BSUK_Roofs | SFSWall fire lining | fire board - internal mansard roof finish | New Construction | Pset_WallCommon - FireRating: F60; Materials - Part Definition: A-Roofs::A_BSUK_Roofs; Identification - ID | Number: 7C; Fire Resistance - Fire | Rating: F60
7C | SFSWall fire lining :1 ,SHE_DRAWING+SHEET.dgn,Design Model;7,SHE-06.FOURTH.dgn,Design Model:101166 | A_BSUK_Roofs | SFSWall fire lining | fire board - internal mansard roof finish | New Construction | Pset_WallCommon - FireRating: F60; Materials - Part Definition: A-Roofs::A_BSUK_Roofs; Identification - ID | Number: 7C; Fire Resistance - Fire | Rating: F60
7C | SFSWall fire lining :1 ,SHE_DRAWING+SHEET.dgn,Design Model;7,SHE-06.FOURTH.dgn,Design Model:101175 | A_BSUK_Roofs | SFSWall fire lining | fire board - internal mansard roof finish | New Construction | Pset_WallCommon - FireRating: F60; Materials - Part Definition: A-Roofs::A_BSUK_Roofs; Identification - ID | Number: 7C; Fire Resistance - Fire | Rating: F60
7C | SFSWall fire lining :1 ,SHE_DRAWING+SHEET.dgn,Design Model;7,SHE-06.FOURTH.dgn,Design Model:101184 | A_BSUK_Roofs | SFSWall fire lining | fire board - internal mansard roof finish | New Construction | Pset_WallCommon - FireRating: F60; Materials - Part Definition: A-Roofs::A_BSUK_Roofs; Identification - ID | Number: 7C; Fire Resistance - Fire | Rating: F60
7C | SFSWall fire lining :1 ,SHE_DRAWING+SHEET.dgn,Design Model;7,SHE-06.FOURTH.dgn,Design Model:101202 | A_BSUK_Roofs | SFSWall fire lining | fire board - internal mansard roof finish | New Construction | Pset_WallCommon - FireRating: F60; Materials - Part Definition: A-Roofs::A_BSUK_Roofs; Identification - ID | Number: 7C; Fire Resistance - Fire | Rating: F60
7C | SFSWall fire lining :1 ,SHE_DRAWING+SHEET.dgn,Design Model;7,SHE-06.FOURTH.dgn,Design Model:101211 | A_BSUK_Roofs | SFSWall fire lining | fire board - internal mansard roof finish | New Construction | Pset_WallCommon - FireRating: F60; Materials - Part Definition: A-Roofs::A_BSUK_Roofs; Identification - ID | Number: 7C; Fire Resistance - Fire | Rating: F60
7C | SFSWall fire lining :1 ,SHE_DRAWING+SHEET.dgn,Design Model;7,SHE-06.FOURTH.dgn,Design Model:101220 | A_BSUK_Roofs | SFSWall fire lining | fire board - internal mansard roof finish | New Construction | Pset_WallCommon - FireRating: F60; Materials - Part Definition: A-Roofs::A_BSUK_Roofs; Identification - ID | Number: 7C; Fire Resistance - Fire | Rating: F60
7C | SFSWall fire lining :1 ,SHE_DRAWING+SHEET.dgn,Design Model;7,SHE-06.FOURTH.dgn,Design Model:101229 | A_BSUK_Roofs | SFSWall fire lining | fire board - internal mansard roof finish | New Construction | Pset_WallCommon - FireRating: F60; Materials - Part Definition: A-Roofs::A_BSUK_Roofs; Identification - ID | Number: 7C; Fire Resistance - Fire | Rating: F60
7C | SFSWall fire lining :1 ,SHE_DRAWING+SHEET.dgn,Design Model;7,SHE-06.FOURTH.dgn,Design Model:101238 | A_BSUK_Roofs | SFSWall fire lining | fire board - internal mansard roof finish | New Construction | Pset_WallCommon - FireRating: F60; Materials - Part Definition: A-Roofs::A_BSUK_Roofs; Identification - ID | Number: 7C; Fire Resistance - Fire | Rating: F60
7C | SFSWall fire lining :1 ,SHE_DRAWING+SHEET.dgn,Design Model;7,SHE-06.FOURTH.dgn,Design Model:101265 | A_BSUK_Roofs | SFSWall fire lining | fire board - internal mansard roof finish | New Construction | Pset_WallCommon - FireRating: F60; Materials - Part Definition: A-Roofs::A_BSUK_Roofs; Identification - ID | Number: 7C; Fire Resistance - Fire | Rating: F60
7C | SFSWall fire lining :1 ,SHE_DRAWING+SHEET.dgn,Design Model;7,SHE-06.FOURTH.dgn,Design Model:101292 | A_BSUK_Roofs | SFSWall fire lining | fire board - internal mansard roof finish | New Construction | Pset_WallCommon - FireRating: F60; Materials - Part Definition: A-Roofs::A_BSUK_Roofs; Identification - ID | Number: 7C; Fire Resistance - Fire | Rating: F60
7C | SFSWall fire lining :1 ,SHE_DRAWING+SHEET.dgn,Design Model;7,SHE-06.FOURTH.dgn,Design Model:101301 | A_BSUK_Roofs | SFSWall fire lining | fire board - internal mansard roof finish | New Construction | Pset_WallCommon - FireRating: F60; Materials - Part Definition: A-Roofs::A_BSUK_Roofs; Identification - ID | Number: 7C; Fire Resistance - Fire | Rating: F60
7C | SFSWall fire lining :1 ,SHE_DRAWING+SHEET.dgn,Design Model;7,SHE-06.FOURTH.dgn,Design Model:101310 | A_BSUK_Roofs | SFSWall fire lining | fire board - internal mansard roof finish | New Construction | Pset_WallCommon - FireRating: F60; Materials - Part Definition: A-Roofs::A_BSUK_Roofs; Identification - ID | Number: 7C; Fire Resistance - Fire | Rating: F60
7C | SFSWall fire lining :1 ,SHE_DRAWING+SHEET.dgn,Design Model;7,SHE-06.FOURTH.dgn,Design Model:101328 | A_BSUK_Roofs | SFSWall fire lining | fire board - internal mansard roof finish | New Construction | Pset_WallCommon - FireRating: F60; Materials - Part Definition: A-Roofs::A_BSUK_Roofs; Identification - ID | Number: 7C; Fire Resistance - Fire | Rating: F60
7C | SFSWall fire lining :1 ,SHE_DRAWING+SHEET.dgn,Design Model;7,SHE-06.FOURTH.dgn,Design Model:101337 | A_BSUK_Roofs | SFSWall fire lining | fire board - internal mansard roof finish | New Construction | Pset_WallCommon - FireRating: F60; Materials - Part Definition: A-Roofs::A_BSUK_Roofs; Identification - ID | Number: 7C; Fire Resistance - Fire | Rating: F60
7C | SFSWall fire lining :1 ,SHE_DRAWING+SHEET.dgn,Design Model;7,SHE-06.FOURTH.dgn,Design Model:101355 | A_BSUK_Roofs | SFSWall fire lining | fire board - internal mansard roof finish | New Construction | Pset_WallCommon - FireRating: F60; Materials - Part Definition: A-Roofs::A_BSUK_Roofs; Identification - ID | Number: 7C; Fire Resistance - Fire | Rating: F60
7C | SFSWall fire lining :1 ,SHE_DRAWING+SHEET.dgn,Design Model;7,SHE-06.FOURTH.dgn,Design Model:101364 | A_BSUK_Roofs | SFSWall fire lining | fire board - internal mansard roof finish | New Construction | Pset_WallCommon - FireRating: F60; Materials - Part Definition: A-Roofs::A_BSUK_Roofs; Identification - ID | Number: 7C; Fire Resistance - Fire | Rating: F60
7C | SFSWall fire lining :1 ,SHE_DRAWING+SHEET.dgn,Design Model;7,SHE-06.FOURTH.dgn,Design Model:101382 | A_BSUK_Roofs | SFSWall fire lining | fire board - internal mansard roof finish | New Construction | Pset_WallCommon - FireRating: F60; Materials - Part Definition: A-Roofs::A_BSUK_Roofs; Identification - ID | Number: 7C; Fire Resistance - Fire | Rating: F60
7C | SFSWall fire lining :1 ,SHE_DRAWING+SHEET.dgn,Design Model;7,SHE-06.FOURTH.dgn,Design Model:101391 | A_BSUK_Roofs | SFSWall fire lining | fire board - internal mansard roof finish | New Construction | Pset_WallCommon - FireRating: F60; Materials - Part Definition: A-Roofs::A_BSUK_Roofs; Identification - ID | Number: 7C; Fire Resistance - Fire | Rating: F60
7C | SFSWall fire lining :1 ,SHE_DRAWING+SHEET.dgn,Design Model;7,SHE-06.FOURTH.dgn,Design Model:101409 | A_BSUK_Roofs | SFSWall fire lining | fire board - internal mansard roof finish | New Construction | Pset_WallCommon - FireRating: F60; Materials - Part Definition: A-Roofs::A_BSUK_Roofs; Identification - ID | Number: 7C; Fire Resistance - Fire | Rating: F60
7C | SFSWall fire lining :1 ,SHE_DRAWING+SHEET.dgn,Design Model;7,SHE-06.FOURTH.dgn,Design Model:101418 | A_BSUK_Roofs | SFSWall fire lining | fire board - internal mansard roof finish | New Construction | Pset_WallCommon - FireRating: F60; Materials - Part Definition: A-Roofs::A_BSUK_Roofs; Identification - ID | Number: 7C; Fire Resistance - Fire | Rating: F60
7C | SFSWall fire lining :1 ,SHE_DRAWING+SHEET.dgn,Design Model;7,SHE-06.FOURTH.dgn,Design Model:101436 | A_BSUK_Roofs | SFSWall fire lining | fire board - internal mansard roof finish | New Construction | Pset_WallCommon - FireRating: F60; Materials - Part Definition: A-Roofs::A_BSUK_Roofs; Identification - ID | Number: 7C; Fire Resistance - Fire | Rating: F60
7C | SFSWall fire lining :1 ,SHE_DRAWING+SHEET.dgn,Design Model;7,SHE-06.FOURTH.dgn,Design Model:101445 | A_BSUK_Roofs | SFSWall fire lining | fire board - internal mansard roof finish | New Construction | Pset_WallCommon - FireRating: F60; Materials - Part Definition: A-Roofs::A_BSUK_Roofs; Identification - ID | Number: 7C; Fire Resistance - Fire | Rating: F60
7C | SFSWall fire lining :1 ,SHE_DRAWING+SHEET.dgn,Design Model;7,SHE-06.FOURTH.dgn,Design Model:101463 | A_BSUK_Roofs | SFSWall fire lining | fire board - internal mansard roof finish | New Construction | Pset_WallCommon - FireRating: F60; Materials - Part Definition: A-Roofs::A_BSUK_Roofs; Identification - ID | Number: 7C; Fire Resistance - Fire | Rating: F60
7C | SFSWall fire lining :1 ,SHE_DRAWING+SHEET.dgn,Design Model;7,SHE-06.FOURTH.dgn,Design Model:101472 | A_BSUK_Roofs | SFSWall fire lining | fire board - internal mansard roof finish | New Construction | Pset_WallCommon - FireRating: F60; Materials - Part Definition: A-Roofs::A_BSUK_Roofs; Identification - ID | Number: 7C; Fire Resistance - Fire | Rating: F60
7C | SFSWall fire lining :1 ,SHE_DRAWING+SHEET.dgn,Design Model;7,SHE-06.FOURTH.dgn,Design Model:101490 | A_BSUK_Roofs | SFSWall fire lining | fire board - internal mansard roof finish | New Construction | Pset_WallCommon - FireRating: F60; Materials - Part Definition: A-Roofs::A_BSUK_Roofs; Identification - ID | Number: 7C; Fire Resistance - Fire | Rating: F60
7C | SFSWall fire lining :1 ,SHE_DRAWING+SHEET.dgn,Design Model;7,SHE-06.FOURTH.dgn,Design Model:101499 | A_BSUK_Roofs | SFSWall fire lining | fire board - internal mansard roof finish | New Construction | Pset_WallCommon - FireRating: F60; Materials - Part Definition: A-Roofs::A_BSUK_Roofs; Identification - ID | Number: 7C; Fire Resistance - Fire | Rating: F60
7C | SFSWall fire lining :1 ,SHE_DRAWING+SHEET.dgn,Design Model;7,SHE-06.FOURTH.dgn,Design Model:101580 | A_BSUK_Roofs | SFSWall fire lining | fire board - internal mansard roof finish | New Construction | Pset_WallCommon - FireRating: F60; Materials - Part Definition: A-Roofs::A_BSUK_Roofs; Identification - ID | Number: 7C; Fire Resistance - Fire | Rating: F60
7C | SFSWall fire lining :1 ,SHE_DRAWING+SHEET.dgn,Design Model;7,SHE-06.FOURTH.dgn,Design Model:101589 | A_BSUK_Roofs | SFSWall fire lining | fire board - internal mansard roof finish | New Construction | Pset_WallCommon - FireRating: F60; Materials - Part Definition: A-Roofs::A_BSUK_Roofs; Identification - ID | Number: 7C; Fire Resistance - Fire | Rating: F60
7C | SFSWall fire lining :1 ,SHE_DRAWING+SHEET.dgn,Design Model;7,SHE-06.FOURTH.dgn,Design Model:101598 | A_BSUK_Roofs | SFSWall fire lining | fire board - internal mansard roof finish | New Construction | Pset_WallCommon - FireRating: F60; Materials - Part Definition: A-Roofs::A_BSUK_Roofs; Identification - ID | Number: 7C; Fire Resistance - Fire | Rating: F60
7C | SFSWall fire lining :1 ,SHE_DRAWING+SHEET.dgn,Design Model;7,SHE-06.FOURTH.dgn,Design Model:101616 | A_BSUK_Roofs | SFSWall fire lining | fire board - internal mansard roof finish | New Construction | Pset_WallCommon - FireRating: F60; Materials - Part Definition: A-Roofs::A_BSUK_Roofs; Identification - ID | Number: 7C; Fire Resistance - Fire | Rating: F60
7C | SFSWall fire lining :1 ,SHE_DRAWING+SHEET.dgn,Design Model;7,SHE-06.FOURTH.dgn,Design Model:101625 | A_BSUK_Roofs | SFSWall fire lining | fire board - internal mansard roof finish | New Construction | Pset_WallCommon - FireRating: F60; Materials - Part Definition: A-Roofs::A_BSUK_Roofs; Identification - ID | Number: 7C; Fire Resistance - Fire | Rating: F60
7C | SFSWall fire lining :1 ,SHE_DRAWING+SHEET.dgn,Design Model;7,SHE-06.FOURTH.dgn,Design Model:101634 | A_BSUK_Roofs | SFSWall fire lining | fire board - internal mansard roof finish | New Construction | Pset_WallCommon - FireRating: F60; Materials - Part Definition: A-Roofs::A_BSUK_Roofs; Identification - ID | Number: 7C; Fire Resistance - Fire | Rating: F60
7C | SFSWall fire lining :1 ,SHE_DRAWING+SHEET.dgn,Design Model;7,SHE-06.FOURTH.dgn,Design Model:103165 | A_BSUK_Roofs | SFSWall fire lining | fire board - internal mansard roof finish | New Construction | Pset_WallCommon - FireRating: F60; Materials - Part Definition: A-Roofs::A_BSUK_Roofs; Identification - ID | Number: 7C; Fire Resistance - Fire | Rating: F60
7C | SFSWall fire lining :1 ,SHE_DRAWING+SHEET.dgn,Design Model;7,SHE-06.FOURTH.dgn,Design Model:103174 | A_BSUK_Roofs | SFSWall fire lining | fire board - internal mansard roof finish | New Construction | Pset_WallCommon - FireRating: F60; Materials - Part Definition: A-Roofs::A_BSUK_Roofs; Identification - ID | Number: 7C; Fire Resistance - Fire | Rating: F60
7C | SFSWall fire lining :1 ,SHE_DRAWING+SHEET.dgn,Design Model;7,SHE-06.FOURTH.dgn,Design Model:103183 | A_BSUK_Roofs | SFSWall fire lining | fire board - internal mansard roof finish | New Construction | Pset_WallCommon - FireRating: F60; Materials - Part Definition: A-Roofs::A_BSUK_Roofs; Identification - ID | Number: 7C; Fire Resistance - Fire | Rating: F60
7C | SFSWall fire lining :1 ,SHE_DRAWING+SHEET.dgn,Design Model;7,SHE-06.FOURTH.dgn,Design Model:103192 | A_BSUK_Roofs | SFSWall fire lining | fire board - internal mansard roof finish | New Construction | Pset_WallCommon - FireRating: F60; Materials - Part Definition: A-Roofs::A_BSUK_Roofs; Identification - ID | Number: 7C; Fire Resistance - Fire | Rating: F60
7C | SFSWall fire lining :1 ,SHE_DRAWING+SHEET.dgn,Design Model;7,SHE-06.FOURTH.dgn,Design Model:103201 | A_BSUK_Roofs | SFSWall fire lining | fire board - internal mansard roof finish | New Construction | Pset_WallCommon - FireRating: F60; Materials - Part Definition: A-Roofs::A_BSUK_Roofs; Identification - ID | Number: 7C; Fire Resistance - Fire | Rating: F60
7C | SFSWall fire lining :1 ,SHE_DRAWING+SHEET.dgn,Design Model;7,SHE-06.FOURTH.dgn,Design Model:103210 | A_BSUK_Roofs | SFSWall fire lining | fire board - internal mansard roof finish | New Construction | Pset_WallCommon - FireRating: F60; Materials - Part Definition: A-Roofs::A_BSUK_Roofs; Identification - ID | Number: 7C; Fire Resistance - Fire | Rating: F60
A-Walls-ExternalBlock | Upstand :1,SHE_DRAWING+SHEET.dgn,Design Model;14,SHE-08.ROOF.dgn ,Design Model:105104 | A_BSUK_WallsExternal_Block | Upstand | AOV 2 - access roof light | New Construction
A-Walls-ExternalBlock | Upstand :1,SHE_DRAWING+SHEET.dgn,Design Model;14,SHE-08.ROOF.dgn ,Design Model:105113 | A_BSUK_WallsExternal_Block | Upstand | AOV 2 - access roof light | New Construction
A-Walls-ExternalBlock | Upstand :1,SHE_DRAWING+SHEET.dgn,Design Model;14,SHE-08.ROOF.dgn ,Design Model:105122 | A_BSUK_WallsExternal_Block | Upstand | AOV 2 - access roof light | New Construction
A-Walls-ExternalBlock | Upstand :1,SHE_DRAWING+SHEET.dgn,Design Model;14,SHE-08.ROOF.dgn ,Design Model:105131 | A_BSUK_WallsExternal_Block | Upstand | AOV 2 - access roof light | New Construction
A-Walls-ExternalBlock | Upstand :1,SHE_DRAWING+SHEET.dgn,Design Model;14,SHE-08.ROOF.dgn ,Design Model:105140 | A_BSUK_WallsExternal_Block | Upstand | AOV 1 - fan | New Construction
A-Walls-ExternalBlock | Upstand :1,SHE_DRAWING+SHEET.dgn,Design Model;14,SHE-08.ROOF.dgn ,Design Model:105149 | A_BSUK_WallsExternal_Block | Upstand | AOV 1 - fan | New Construction
A-Walls-ExternalBlock | Upstand :1,SHE_DRAWING+SHEET.dgn,Design Model;14,SHE-08.ROOF.dgn ,Design Model:105158 | A_BSUK_WallsExternal_Block | Upstand | AOV 1 - fan | New Construction
A-Walls-ExternalBlock | Upstand :1,SHE_DRAWING+SHEET.dgn,Design Model;14,SHE-08.ROOF.dgn ,Design Model:105167 | A_BSUK_WallsExternal_Block | Upstand | AOV 1 - fan | New Construction
A-Walls-ExternalBlock | Upstand :1,SHE_DRAWING+SHEET.dgn,Design Model;14,SHE-08.ROOF.dgn ,Design Model:105176 | A_BSUK_Roofs | Upstand | mansard roof | New Construction | Materials - Part Definition: A-Roofs::A_BSUK_Roofs
A-Walls-ExternalBlock | Upstand :1,SHE_DRAWING+SHEET.dgn,Design Model;14,SHE-08.ROOF.dgn ,Design Model:105185 | A_BSUK_Roofs | Upstand | mansard roof | New Construction | Materials - Part Definition: A-Roofs::A_BSUK_Roofs
A-Walls-ExternalBlock | Upstand :1,SHE_DRAWING+SHEET.dgn,Design Model;14,SHE-08.ROOF.dgn ,Design Model:105194 | A_BSUK_Roofs | Upstand | mansard roof | New Construction | Materials - Part Definition: A-Roofs::A_BSUK_Roofs
A-Walls-ExternalBlock | Upstand :1,SHE_DRAWING+SHEET.dgn,Design Model;14,SHE-08.ROOF.dgn ,Design Model:105203 | A_BSUK_Roofs | Upstand | mansard roof | New Construction | Materials - Part Definition: A-Roofs::A_BSUK_Roofs
A-Walls-ExternalBlock | FacadeBlockwork :1,SHE_DRAWING+SHEET.dgn,Design Model;18,SHE-04.SECOND.dgn ,Design Model:123162 | A_BSUK_WallsExternal_Block | FacadeBlockwork | existing | Existing to Remain
A-Walls-ExternalBlock | FacadeBlockwork :1,SHE_DRAWING+SHEET.dgn,Design Model;18,SHE-04.SECOND.dgn ,Design Model:123171 | A_BSUK_WallsExternal_Block | FacadeBlockwork | existing | Existing to Remain
A-Walls-ExternalBlock | FacadeBlockwork :1,SHE_DRAWING+SHEET.dgn,Design Model;18,SHE-04.SECOND.dgn ,Design Model:123180 | A_BSUK_WallsExternal_Block | FacadeBlockwork | existing | Existing to Remain
A-Walls-ExternalBlock | FacadeBlockwork :1,SHE_DRAWING+SHEET.dgn,Design Model;18,SHE-04.SECOND.dgn ,Design Model:123189 | A_BSUK_WallsExternal_Block | FacadeBlockwork | existing | Existing to Remain
A-Walls-ExternalBlock | FacadeBlockwork :1,SHE_DRAWING+SHEET.dgn,Design Model;18,SHE-04.SECOND.dgn ,Design Model:123198 | A_BSUK_WallsExternal_Block | FacadeBlockwork | existing | Existing to Remain
A-Walls-ExternalBlock | FacadeBlockwork :1,SHE_DRAWING+SHEET.dgn,Design Model;18,SHE-04.SECOND.dgn ,Design Model:123207 | A_BSUK_WallsExternal_Block | FacadeBlockwork | existing | Existing to Remain
A-Walls-ExternalBlock | FacadeBlockwork :1,SHE_DRAWING+SHEET.dgn,Design Model;18,SHE-04.SECOND.dgn ,Design Model:123216 | A_BSUK_WallsExternal_Block | FacadeBlockwork | existing | Existing to Remain
A-Walls-ExternalBlock | FacadeBlockwork :1,SHE_DRAWING+SHEET.dgn,Design Model;18,SHE-04.SECOND.dgn ,Design Model:123225 | A_BSUK_WallsExternal_Block | FacadeBlockwork | existing | Existing to Remain
A-Walls-ExternalBlock | FacadeBlockwork :1,SHE_DRAWING+SHEET.dgn,Design Model;18,SHE-04.SECOND.dgn ,Design Model:124098 | A_BSUK_WallsExternal_Block | FacadeBlockwork | existing | Existing to Remain
A-Walls-ExternalBlock | FacadeBlockwork :1,SHE_DRAWING+SHEET.dgn,Design Model;18,SHE-04.SECOND.dgn ,Design Model:124107 | A_BSUK_WallsExternal_Block | FacadeBlockwork | existing | Existing to Remain
A-Walls-ExternalBlock | FacadeBlockwork :1,SHE_DRAWING+SHEET.dgn,Design Model;18,SHE-04.SECOND.dgn ,Design Model:124116 | A_BSUK_WallsExternal_Block | FacadeBlockwork | existing | Existing to Remain
A-Walls-ExternalBlock | FacadeBlockwork :1,SHE_DRAWING+SHEET.dgn,Design Model;18,SHE-04.SECOND.dgn ,Design Model:124125 | A_BSUK_WallsExternal_Block | FacadeBlockwork | existing | Existing to Remain
A-Walls-ExternalBlock | FacadeBlockwork :1,SHE_DRAWING+SHEET.dgn,Design Model;18,SHE-04.SECOND.dgn ,Design Model:124134 | A_BSUK_WallsExternal_Block | FacadeBlockwork | existing | Existing to Remain
A-Walls-ExternalBlock | FacadeBlockwork :1,SHE_DRAWING+SHEET.dgn,Design Model;18,SHE-04.SECOND.dgn ,Design Model:124143 | A_BSUK_WallsExternal_Block | FacadeBlockwork | existing | Existing to Remain
A-Walls-ExternalBlock | FacadeBlockwork :1,SHE_DRAWING+SHEET.dgn,Design Model;18,SHE-04.SECOND.dgn ,Design Model:124152 | A_BSUK_WallsExternal_Block | FacadeBlockwork | existing | Existing to Remain
A-Walls-ExternalBlock | FacadeBlockwork :1,SHE_DRAWING+SHEET.dgn,Design Model;18,SHE-04.SECOND.dgn ,Design Model:124161 | A_BSUK_WallsExternal_Block | FacadeBlockwork | existing | Existing to Remain
A-Walls-ExternalBlock | FacadeBlockwork :1,SHE_DRAWING+SHEET.dgn,Design Model;18,SHE-04.SECOND.dgn ,Design Model:124170 | A_BSUK_WallsExternal_Block | FacadeBlockwork | existing | Existing to Remain
A-Walls-ExternalBlock | FacadeBlockwork :1,SHE_DRAWING+SHEET.dgn,Design Model;18,SHE-04.SECOND.dgn ,Design Model:124179 | A_BSUK_WallsExternal_Block | FacadeBlockwork | existing | Existing to Remain
A-Walls-ExternalBlock | FacadeBlockwork :1,SHE_DRAWING+SHEET.dgn,Design Model;18,SHE-04.SECOND.dgn ,Design Model:124188 | A_BSUK_WallsExternal_Block | FacadeBlockwork | existing | Existing to Remain
A-Walls-ExternalBlock | FacadeBlockwork :1,SHE_DRAWING+SHEET.dgn,Design Model;18,SHE-04.SECOND.dgn ,Design Model:124197 | A_BSUK_WallsExternal_Block | FacadeBlockwork | existing | Existing to Remain
A-Walls-ExternalBlock | FacadeBlockwork :1,SHE_DRAWING+SHEET.dgn,Design Model;18,SHE-04.SECOND.dgn ,Design Model:124206 | A_BSUK_WallsExternal_Block | FacadeBlockwork | existing | Existing to Remain
A-Walls-ExternalBlock | FacadeBlockwork :1,SHE_DRAWING+SHEET.dgn,Design Model;18,SHE-04.SECOND.dgn ,Design Model:124215 | A_BSUK_WallsExternal_Block | FacadeBlockwork | existing | Existing to Remain
A-Walls-ExternalBlock | FacadeBlockwork :1,SHE_DRAWING+SHEET.dgn,Design Model;18,SHE-04.SECOND.dgn ,Design Model:124224 | A_BSUK_WallsExternal_Block | FacadeBlockwork | existing | Existing to Remain
A-Walls-ExternalBlock | FacadeBlockwork :1,SHE_DRAWING+SHEET.dgn,Design Model;18,SHE-04.SECOND.dgn ,Design Model:124233 | A_BSUK_WallsExternal_Block | FacadeBlockwork | existing | Existing to Remain
A-Walls-ExternalBlock | FacadeBlockwork :1,SHE_DRAWING+SHEET.dgn,Design Model;18,SHE-04.SECOND.dgn ,Design Model:124242 | A_BSUK_WallsExternal_Block | FacadeBlockwork | existing | Existing to Remain
A-Walls-ExternalBlock | FacadeBlockwork :1,SHE_DRAWING+SHEET.dgn,Design Model;18,SHE-04.SECOND.dgn ,Design Model:124251 | A_BSUK_WallsExternal_Block | FacadeBlockwork | existing | Existing to Remain
A-Walls-ExternalBlock | FacadeBlockwork :1,SHE_DRAWING+SHEET.dgn,Design Model;18,SHE-04.SECOND.dgn ,Design Model:124800 | A_BSUK_WallsExternal_Block | FacadeBlockwork | existing | Existing to Remain
A-Walls-ExternalBlock | FacadeBlockwork :1,SHE_DRAWING+SHEET.dgn,Design Model;18,SHE-04.SECOND.dgn ,Design Model:124809 | A_BSUK_WallsExternal_Block | FacadeBlockwork | existing | Existing to Remain
A-Walls-ExternalBlock | FacadeBlockwork :1,SHE_DRAWING+SHEET.dgn,Design Model;18,SHE-04.SECOND.dgn ,Design Model:124818 | A_BSUK_WallsExternal_Block | FacadeBlockwork | existing | Existing to Remain
A-Walls-ExternalBlock | FacadeBlockwork :1,SHE_DRAWING+SHEET.dgn,Design Model;18,SHE-04.SECOND.dgn ,Design Model:124827 | A_BSUK_WallsExternal_Block | FacadeBlockwork | existing | Existing to Remain
A-Walls-ExternalBlock | FacadeBlockwork :1,SHE_DRAWING+SHEET.dgn,Design Model;18,SHE-04.SECOND.dgn ,Design Model:124836 | A_BSUK_WallsExternal_Block | FacadeBlockwork | existing | Existing to Remain
A-Walls-ExternalBlock | FacadeBlockwork :1,SHE_DRAWING+SHEET.dgn,Design Model;18,SHE-04.SECOND.dgn ,Design Model:125043 | A_BSUK_WallsExternal_Block | FacadeBlockwork | existing | Existing to Remain

# IfcWall: A-Walls-ExternalBrick (107)
In: RL
Type - Wall Parameters - Type: Wall; Compound Wall Assembly: no
Type - Thermal Transmittance - Is External: yes; Is Below Grade: no
Type - Structural Usage - Structural | Material: Brickwork
Type - Space Bounding - Is Space Bounding: yes
Type - Materials - Part Definition: A-Walls::A_BSUK_WallsExternal_Brick
Type - LEED Parameters - LEED | Pre-consumer Recycled (%): 0; LEED | Regional Material: no; LEED | Post-consumer Recycled (%): 0
Type - Fire Resistance - Fire | IsCombustible: no; Fire | Compartmentation: no
Type - Discipline - Discipline: Architectural
Type - Classification - Uniclass2015: Pr_20_93_52_27
Material: A_BSUK_WallsExternal_Brick
Pset_WallCommon - Combustible: no; Compartmentation: no; IsExternal: yes; LoadBearing: no
Name | Description | ID | Description | ID | Notes | Phase
A-Walls-ExternalBrick | Wall existing :1,SHE_DRAWING+SHEET.dgn,Design Model;1,SHE-01.GROUND.dgn ,Design Model:95277 | Wall existing | general | Existing to Remain
A-Walls-ExternalBrick | Wall existing :1,SHE_DRAWING+SHEET.dgn,Design Model;1,SHE-01.GROUND.dgn ,Design Model:95286 | Wall existing | general | Existing to Remain
A-Walls-ExternalBrick | Wall existing :1,SHE_DRAWING+SHEET.dgn,Design Model;1,SHE-01.GROUND.dgn ,Design Model:95295 | Wall existing | general | Existing to Remain
A-Walls-ExternalBrick | Wall existing :1,SHE_DRAWING+SHEET.dgn,Design Model;1,SHE-01.GROUND.dgn ,Design Model:95304 | Wall existing | general | Existing to Remain
A-Walls-ExternalBrick | Wall existing :1,SHE_DRAWING+SHEET.dgn,Design Model;1,SHE-01.GROUND.dgn ,Design Model:95313 | Wall existing | general | Existing to Remain
A-Walls-ExternalBrick | Wall existing :1,SHE_DRAWING+SHEET.dgn,Design Model;1,SHE-01.GROUND.dgn ,Design Model:95322 | Wall existing | general | Existing to Remain
A-Walls-ExternalBrick | Wall existing :1,SHE_DRAWING+SHEET.dgn,Design Model;1,SHE-01.GROUND.dgn ,Design Model:95331 | Wall existing | general | Existing to Remain
A-Walls-ExternalBrick | Wall existing :1,SHE_DRAWING+SHEET.dgn,Design Model;1,SHE-01.GROUND.dgn ,Design Model:95340 | Wall existing | general | Existing to Remain
A-Walls-ExternalBrick | Wall existing :1,SHE_DRAWING+SHEET.dgn,Design Model;1,SHE-01.GROUND.dgn ,Design Model:95349 | Wall existing | general | Existing to Remain
A-Walls-ExternalBrick | Wall existing :1,SHE_DRAWING+SHEET.dgn,Design Model;1,SHE-01.GROUND.dgn ,Design Model:95358 | Wall existing | general | Existing to Remain
A-Walls-ExternalBrick | Wall existing :1,SHE_DRAWING+SHEET.dgn,Design Model;1,SHE-01.GROUND.dgn ,Design Model:95367 | Wall existing | general | Existing to Remain
A-Walls-ExternalBrick | Wall existing :1,SHE_DRAWING+SHEET.dgn,Design Model;1,SHE-01.GROUND.dgn ,Design Model:95376 | Wall existing | general | Existing to Remain
A-Walls-ExternalBrick | Wall existing :1,SHE_DRAWING+SHEET.dgn,Design Model;1,SHE-01.GROUND.dgn ,Design Model:95385 | Wall existing | general | Existing to Remain
A-Walls-ExternalBrick | Wall existing :1,SHE_DRAWING+SHEET.dgn,Design Model;1,SHE-01.GROUND.dgn ,Design Model:95394 | Wall existing | general | Existing to Remain
A-Walls-ExternalBrick | Wall existing :1,SHE_DRAWING+SHEET.dgn,Design Model;1,SHE-01.GROUND.dgn ,Design Model:95403 | Wall existing | general | Existing to Remain
A-Walls-ExternalBrick | Wall existing :1,SHE_DRAWING+SHEET.dgn,Design Model;1,SHE-01.GROUND.dgn ,Design Model:95412 | Wall existing | general | Existing to Remain
A-Walls-ExternalBrick | Wall existing :1,SHE_DRAWING+SHEET.dgn,Design Model;1,SHE-01.GROUND.dgn ,Design Model:95421 | Wall existing | general | Existing to Remain
A-Walls-ExternalBrick | Wall existing :1,SHE_DRAWING+SHEET.dgn,Design Model;1,SHE-01.GROUND.dgn ,Design Model:95430 | Wall existing | general | Existing to Remain
A-Walls-ExternalBrick | Wall existing :1,SHE_DRAWING+SHEET.dgn,Design Model;1,SHE-01.GROUND.dgn ,Design Model:95439 | Wall existing | general | Existing to Remain
A-Walls-ExternalBrick | Wall existing :1,SHE_DRAWING+SHEET.dgn,Design Model;1,SHE-01.GROUND.dgn ,Design Model:95448 | Wall existing | general | Existing to Remain
A-Walls-ExternalBrick | Wall existing :1,SHE_DRAWING+SHEET.dgn,Design Model;1,SHE-01.GROUND.dgn ,Design Model:95552 | Wall existing | general | Existing to Remain
A-Walls-ExternalBrick | Wall existing :1,SHE_DRAWING+SHEET.dgn,Design Model;1,SHE-01.GROUND.dgn ,Design Model:95567 | Wall existing | general | Existing to Remain
A-Walls-ExternalBrick | Wall existing :1,SHE_DRAWING+SHEET.dgn,Design Model;1,SHE-01.GROUND.dgn ,Design Model:95592 | Wall existing | general | Existing to Remain
A-Walls-ExternalBrick | Wall existing :1,SHE_DRAWING+SHEET.dgn,Design Model;1,SHE-01.GROUND.dgn ,Design Model:95601 | Wall existing | general | Existing to Remain
A-Walls-ExternalBrick | Wall existing :1,SHE_DRAWING+SHEET.dgn,Design Model;1,SHE-01.GROUND.dgn ,Design Model:95610 | Wall existing | general | Existing to Remain
A-Walls-ExternalBrick | Wall existing :1,SHE_DRAWING+SHEET.dgn,Design Model;1,SHE-01.GROUND.dgn ,Design Model:95635 | Wall existing | general | Existing to Remain
A-Walls-ExternalBrick | Wall existing :1,SHE_DRAWING+SHEET.dgn,Design Model;1,SHE-01.GROUND.dgn ,Design Model:95682 | Wall existing | general | Existing to Remain
A-Walls-ExternalBrick | Wall existing :1,SHE_DRAWING+SHEET.dgn,Design Model;1,SHE-01.GROUND.dgn ,Design Model:95741 | Wall existing | general | Existing to Remain
A-Walls-ExternalBrick | Wall existing :1,SHE_DRAWING+SHEET.dgn,Design Model;1,SHE-01.GROUND.dgn ,Design Model:95750 | Wall existing | general | Existing to Remain
A-Walls-ExternalBrick | Wall existing :1,SHE_DRAWING+SHEET.dgn,Design Model;1,SHE-01.GROUND.dgn ,Design Model:95759 | Wall existing | general | Existing to Remain
A-Walls-ExternalBrick | Wall existing :1,SHE_DRAWING+SHEET.dgn,Design Model;1,SHE-01.GROUND.dgn ,Design Model:95770 | Wall existing | general | Existing to Remain
A-Walls-ExternalBrick | Wall existing :1,SHE_DRAWING+SHEET.dgn,Design Model;1,SHE-01.GROUND.dgn ,Design Model:95781 | Wall existing | general | Existing to Remain
A-Walls-ExternalBrick | Wall existing :1,SHE_DRAWING+SHEET.dgn,Design Model;1,SHE-01.GROUND.dgn ,Design Model:95790 | Wall existing | general | Existing to Remain
A-Walls-ExternalBrick | Wall existing :1,SHE_DRAWING+SHEET.dgn,Design Model;1,SHE-01.GROUND.dgn ,Design Model:95799 | Wall existing | general | Existing to Remain
A-Walls-ExternalBrick | Wall existing :1,SHE_DRAWING+SHEET.dgn,Design Model;1,SHE-01.GROUND.dgn ,Design Model:95808 | Wall existing | general | Existing to Remain
A-Walls-ExternalBrick | Wall existing :1,SHE_DRAWING+SHEET.dgn,Design Model;1,SHE-01.GROUND.dgn ,Design Model:95821 | Wall existing | general | Existing to Remain
A-Walls-ExternalBrick | Wall existing :1,SHE_DRAWING+SHEET.dgn,Design Model;1,SHE-01.GROUND.dgn ,Design Model:95846 | Wall existing | general | Existing to Remain
A-Walls-ExternalBrick | Wall existing :1,SHE_DRAWING+SHEET.dgn,Design Model;1,SHE-01.GROUND.dgn ,Design Model:95855 | Wall existing | general | Existing to Remain
A-Walls-ExternalBrick | Wall existing :1,SHE_DRAWING+SHEET.dgn,Design Model;1,SHE-01.GROUND.dgn ,Design Model:95864 | Wall existing | general | Existing to Remain
A-Walls-ExternalBrick | Wall existing :1,SHE_DRAWING+SHEET.dgn,Design Model;1,SHE-01.GROUND.dgn ,Design Model:95873 | Wall existing | general | Existing to Remain
A-Walls-ExternalBrick | Wall existing :1,SHE_DRAWING+SHEET.dgn,Design Model;1,SHE-01.GROUND.dgn ,Design Model:95882 | Wall existing | general | Existing to Remain
A-Walls-ExternalBrick | Wall existing :1,SHE_DRAWING+SHEET.dgn,Design Model;1,SHE-01.GROUND.dgn ,Design Model:95891 | Wall existing | general | Existing to Remain
A-Walls-ExternalBrick | Wall existing :1,SHE_DRAWING+SHEET.dgn,Design Model;1,SHE-01.GROUND.dgn ,Design Model:133297 | Wall existing | general | Existing to Remain
A-Walls-ExternalBrick | Wall existing :1,SHE_DRAWING+SHEET.dgn,Design Model;1,SHE-01.GROUND.dgn ,Design Model:137288 | Wall existing | general | Existing to Remain
A-Walls-ExternalBrick | Wall existing :1,SHE_DRAWING+SHEET.dgn,Design Model;1,SHE-01.GROUND.dgn ,Design Model:137299 | Wall existing | general | Existing to Remain
A-Walls-ExternalBrick | Wall existing :1,SHE_DRAWING+SHEET.dgn,Design Model;1,SHE-01.GROUND.dgn ,Design Model:137318 | Wall existing | general | Existing to Remain
A-Walls-ExternalBrick | Wall existing :1,SHE_DRAWING+SHEET.dgn,Design Model;2,SHE-02.MEZZANINE.dgn ,Design Model:92807 | Wall existing | general | Existing to Remain
A-Walls-ExternalBrick | Wall existing :1,SHE_DRAWING+SHEET.dgn,Design Model;2,SHE-02.MEZZANINE.dgn ,Design Model:92816 | Wall existing | general | Existing to Remain
A-Walls-ExternalBrick | Wall existing :1,SHE_DRAWING+SHEET.dgn,Design Model;2,SHE-02.MEZZANINE.dgn ,Design Model:92825 | Wall existing | general | Existing to Remain
A-Walls-ExternalBrick | Wall existing :1,SHE_DRAWING+SHEET.dgn,Design Model;2,SHE-02.MEZZANINE.dgn ,Design Model:92843 | Wall existing | general | Existing to Remain
A-Walls-ExternalBrick | Wall existing :1,SHE_DRAWING+SHEET.dgn,Design Model;2,SHE-02.MEZZANINE.dgn ,Design Model:92852 | Wall existing | general | Existing to Remain
A-Walls-ExternalBrick | Wall existing :1,SHE_DRAWING+SHEET.dgn,Design Model;2,SHE-02.MEZZANINE.dgn ,Design Model:92861 | Wall existing | general | Existing to Remain
A-Walls-ExternalBrick | Wall existing :1,SHE_DRAWING+SHEET.dgn,Design Model;2,SHE-02.MEZZANINE.dgn ,Design Model:92870 | Wall existing | general | Existing to Remain
A-Walls-ExternalBrick | Wall existing :1,SHE_DRAWING+SHEET.dgn,Design Model;2,SHE-02.MEZZANINE.dgn ,Design Model:92933 | Wall existing | general | Existing to Remain
A-Walls-ExternalBrick | Wall existing :1,SHE_DRAWING+SHEET.dgn,Design Model;2,SHE-02.MEZZANINE.dgn ,Design Model:92942 | Wall existing | general | Existing to Remain
A-Walls-ExternalBrick | Wall existing :1,SHE_DRAWING+SHEET.dgn,Design Model;2,SHE-02.MEZZANINE.dgn ,Design Model:92951 | Wall existing | general | Existing to Remain
A-Walls-ExternalBrick | Wall existing :1,SHE_DRAWING+SHEET.dgn,Design Model;2,SHE-02.MEZZANINE.dgn ,Design Model:92960 | Wall existing | general | Existing to Remain
A-Walls-ExternalBrick | FacadeFacingBrick - infill :1,SHE_DRAWING+SHEET.dgn,Design Model;2 ,SHE-02.MEZZANINE.dgn,Design Model:92987 | FacadeFacingBrick - infill | front elevation | New Construction
A-Walls-ExternalBrick | Wall existing :1,SHE_DRAWING+SHEET.dgn,Design Model;2,SHE-02.MEZZANINE.dgn ,Design Model:93068 | Wall existing | general | Existing to Remain
A-Walls-ExternalBrick | FacadeFacingBrick - infill :1,SHE_DRAWING+SHEET.dgn,Design Model;2 ,SHE-02.MEZZANINE.dgn,Design Model:93077 | FacadeFacingBrick - infill | back elevation | New Construction
A-Walls-ExternalBrick | FacadeFacingBrick - infill :1,SHE_DRAWING+SHEET.dgn,Design Model;2 ,SHE-02.MEZZANINE.dgn,Design Model:93086 | FacadeFacingBrick - infill | back elevation | New Construction
A-Walls-ExternalBrick | FacadeFacingBrick - infill :1,SHE_DRAWING+SHEET.dgn,Design Model;2 ,SHE-02.MEZZANINE.dgn,Design Model:93095 | FacadeFacingBrick - infill | back elevation | New Construction
A-Walls-ExternalBrick | FacadeFacingBrick - infill :1,SHE_DRAWING+SHEET.dgn,Design Model;2 ,SHE-02.MEZZANINE.dgn,Design Model:93104 | FacadeFacingBrick - infill | back elevation | New Construction
A-Walls-ExternalBrick | FacadeFacingBrick - infill :1,SHE_DRAWING+SHEET.dgn,Design Model;2 ,SHE-02.MEZZANINE.dgn,Design Model:93113 | FacadeFacingBrick - infill | back elevation | New Construction
A-Walls-ExternalBrick | Wall existing :1,SHE_DRAWING+SHEET.dgn,Design Model;2,SHE-02.MEZZANINE.dgn ,Design Model:93478 | Wall existing | general | Existing to Remain
A-Walls-ExternalBrick | Wall existing :1,SHE_DRAWING+SHEET.dgn,Design Model;2,SHE-02.MEZZANINE.dgn ,Design Model:93559 | Wall existing | general | Existing to Remain
A-Walls-ExternalBrick | Wall existing :1,SHE_DRAWING+SHEET.dgn,Design Model;2,SHE-02.MEZZANINE.dgn ,Design Model:93568 | Wall existing | general | Existing to Remain
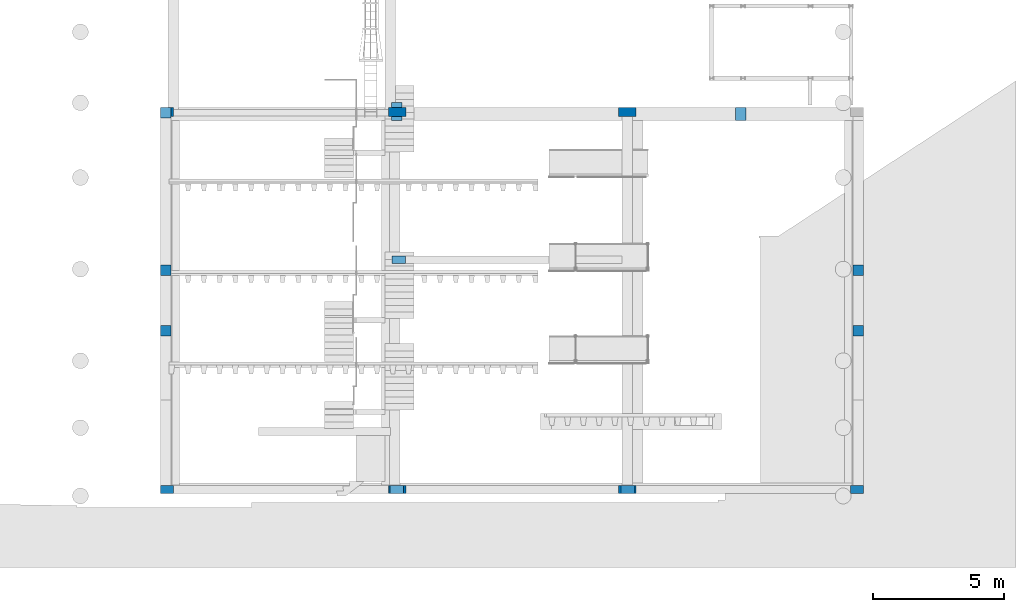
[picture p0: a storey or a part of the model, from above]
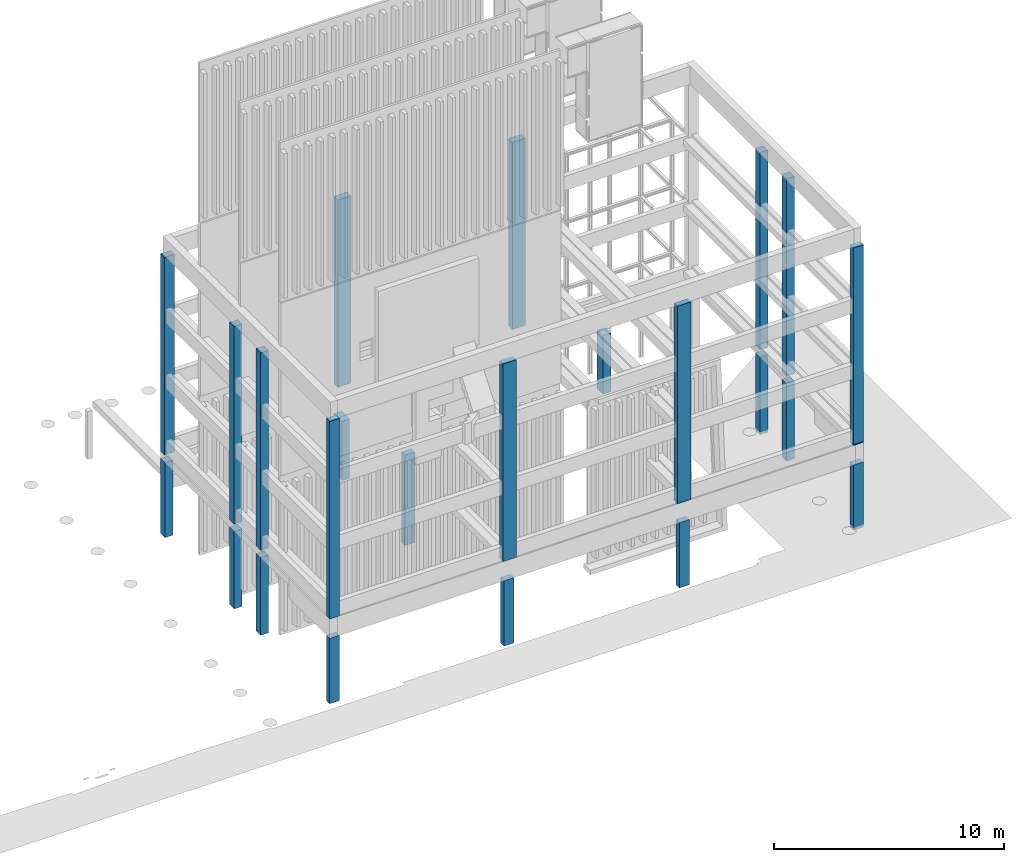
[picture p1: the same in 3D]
Properties of the parts of a building model (IFC2X3), part 13 of 16

# IfcWall: A-Walls-ExternalBrick (107)
Name | Description | ID | Description | ID | Notes | Phase
A-Walls-ExternalBrick | Wall existing :1,SHE_DRAWING+SHEET.dgn,Design Model;2,SHE-02.MEZZANINE.dgn ,Design Model:93577 | Wall existing | general | Existing to Remain
A-Walls-ExternalBrick | Wall existing :1,SHE_DRAWING+SHEET.dgn,Design Model;2,SHE-02.MEZZANINE.dgn ,Design Model:93586 | Wall existing | general | Existing to Remain
A-Walls-ExternalBrick | Wall existing :1,SHE_DRAWING+SHEET.dgn,Design Model;2,SHE-02.MEZZANINE.dgn ,Design Model:93604 | Wall existing | general | Existing to Remain
A-Walls-ExternalBrick | Wall existing :1,SHE_DRAWING+SHEET.dgn,Design Model;2,SHE-02.MEZZANINE.dgn ,Design Model:93613 | Wall existing | general | Existing to Remain
A-Walls-ExternalBrick | Wall existing :1,SHE_DRAWING+SHEET.dgn,Design Model;2,SHE-02.MEZZANINE.dgn ,Design Model:93622 | Wall existing | general | Existing to Remain
A-Walls-ExternalBrick | Wall existing :1,SHE_DRAWING+SHEET.dgn,Design Model;2,SHE-02.MEZZANINE.dgn ,Design Model:93640 | Wall existing | general | Existing to Remain
A-Walls-ExternalBrick | Wall existing :1,SHE_DRAWING+SHEET.dgn,Design Model;2,SHE-02.MEZZANINE.dgn ,Design Model:93737 | Wall existing | general | Existing to Remain
A-Walls-ExternalBrick | Wall existing :1,SHE_DRAWING+SHEET.dgn,Design Model;2,SHE-02.MEZZANINE.dgn ,Design Model:93749 | Wall existing | general | Existing to Remain
A-Walls-ExternalBrick | Wall existing :1,SHE_DRAWING+SHEET.dgn,Design Model;2,SHE-02.MEZZANINE.dgn ,Design Model:93768 | Wall existing | general | Existing to Remain
A-Walls-ExternalBrick | Wall existing :1,SHE_DRAWING+SHEET.dgn,Design Model;2,SHE-02.MEZZANINE.dgn ,Design Model:93779 | Wall existing | general | Existing to Remain
A-Walls-ExternalBrick | Wall existing :1,SHE_DRAWING+SHEET.dgn,Design Model;2,SHE-02.MEZZANINE.dgn ,Design Model:93804 | Wall existing | general | Existing to Remain
A-Walls-ExternalBrick | Wall existing :1,SHE_DRAWING+SHEET.dgn,Design Model;2,SHE-02.MEZZANINE.dgn ,Design Model:93835 | Wall existing | general | Existing to Remain
A-Walls-ExternalBrick | Wall existing :1,SHE_DRAWING+SHEET.dgn,Design Model;2,SHE-02.MEZZANINE.dgn ,Design Model:93844 | Wall existing | general | Existing to Remain
A-Walls-ExternalBrick | Wall existing :1,SHE_DRAWING+SHEET.dgn,Design Model;2,SHE-02.MEZZANINE.dgn ,Design Model:93853 | Wall existing | general | Existing to Remain
A-Walls-ExternalBrick | Wall existing :1,SHE_DRAWING+SHEET.dgn,Design Model;2,SHE-02.MEZZANINE.dgn ,Design Model:93862 | Wall existing | general | Existing to Remain
A-Walls-ExternalBrick | Wall existing :1,SHE_DRAWING+SHEET.dgn,Design Model;2,SHE-02.MEZZANINE.dgn ,Design Model:93871 | Wall existing | general | Existing to Remain
A-Walls-ExternalBrick | Wall existing :1,SHE_DRAWING+SHEET.dgn,Design Model;2,SHE-02.MEZZANINE.dgn ,Design Model:93907 | Wall existing | general | Existing to Remain
A-Walls-ExternalBrick | Wall existing :1,SHE_DRAWING+SHEET.dgn,Design Model;2,SHE-02.MEZZANINE.dgn ,Design Model:93916 | Wall existing | general | Existing to Remain
A-Walls-ExternalBrick | Wall existing :1,SHE_DRAWING+SHEET.dgn,Design Model;2,SHE-02.MEZZANINE.dgn ,Design Model:93925 | Wall existing | general | Existing to Remain
A-Walls-ExternalBrick | Wall existing :1,SHE_DRAWING+SHEET.dgn,Design Model;2,SHE-02.MEZZANINE.dgn ,Design Model:94127 | Wall existing | general | Existing to Remain
A-Walls-ExternalBrick | Wall existing :1,SHE_DRAWING+SHEET.dgn,Design Model;2,SHE-02.MEZZANINE.dgn ,Design Model:94136 | Wall existing | general | Existing to Remain
A-Walls-ExternalBrick | Wall existing :1,SHE_DRAWING+SHEET.dgn,Design Model;2,SHE-02.MEZZANINE.dgn ,Design Model:94165 | Wall existing | general | Existing to Remain
A-Walls-ExternalBrick | Wall existing :1,SHE_DRAWING+SHEET.dgn,Design Model;2,SHE-02.MEZZANINE.dgn ,Design Model:94174 | Wall existing | general | Existing to Remain
A-Walls-ExternalBrick | Wall existing :1,SHE_DRAWING+SHEET.dgn,Design Model;2,SHE-02.MEZZANINE.dgn ,Design Model:94221 | Wall existing | general | Existing to Remain
A-Walls-ExternalBrick | Wall existing :1,SHE_DRAWING+SHEET.dgn,Design Model;2,SHE-02.MEZZANINE.dgn ,Design Model:94230 | Wall existing | general | Existing to Remain
A-Walls-ExternalBrick | Wall existing :1,SHE_DRAWING+SHEET.dgn,Design Model;2,SHE-02.MEZZANINE.dgn ,Design Model:94248 | Wall existing | general | Existing to Remain
A-Walls-ExternalBrick | Wall existing :1,SHE_DRAWING+SHEET.dgn,Design Model;2,SHE-02.MEZZANINE.dgn ,Design Model:94257 | Wall existing | general | Existing to Remain
A-Walls-ExternalBrick | Wall existing :1,SHE_DRAWING+SHEET.dgn,Design Model;2,SHE-02.MEZZANINE.dgn ,Design Model:94302 | Wall existing | general | Existing to Remain
A-Walls-ExternalBrick | Wall existing :1,SHE_DRAWING+SHEET.dgn,Design Model;2,SHE-02.MEZZANINE.dgn ,Design Model:116685 | Wall existing | general | Existing to Remain
A-Walls-ExternalBrick | Wall existing :1,SHE_DRAWING+SHEET.dgn,Design Model;2,SHE-02.MEZZANINE.dgn ,Design Model:116959 | Wall existing | general | Existing to Remain
A-Walls-ExternalBrick | Wall existing :1,SHE_DRAWING+SHEET.dgn,Design Model;2,SHE-02.MEZZANINE.dgn ,Design Model:116968 | Wall existing | general | Existing to Remain
A-Walls-ExternalBrick | Wall existing :1,SHE_DRAWING+SHEET.dgn,Design Model;2,SHE-02.MEZZANINE.dgn ,Design Model:116977 | Wall existing | general | Existing to Remain
A-Walls-ExternalBrick | Wall existing :1,SHE_DRAWING+SHEET.dgn,Design Model;2,SHE-02.MEZZANINE.dgn ,Design Model:116986 | Wall existing | general | Existing to Remain
A-Walls-ExternalBrick | Wall existing :1,SHE_DRAWING+SHEET.dgn,Design Model;2,SHE-02.MEZZANINE.dgn ,Design Model:117599 | Wall existing | general | Existing to Remain
A-Walls-ExternalBrick | Wall existing :1,SHE_DRAWING+SHEET.dgn,Design Model;2,SHE-02.MEZZANINE.dgn ,Design Model:130076 | Wall existing | general | Existing to Remain
A-Walls-ExternalBrick | FacadeFacingBrick :1,SHE_DRAWING+SHEET.dgn,Design Model;3,SHE-09.FACADE.dgn ,Design Model:104882 | FacadeFacingBrick | front elevation - existing | Existing to Remain | Pset_WallCommon - AcousticRating: Rw 52dB Rw+Ctr 48dB; Acoustical Parameters - Acoustic Rating (STC): Rw 52dB Rw+Ctr 48dB
A-Walls-ExternalBrick | FacadeFacingBrick :1,SHE_DRAWING+SHEET.dgn,Design Model;3,SHE-09.FACADE.dgn ,Design Model:104955 | FacadeFacingBrick | side elevation - existing | Existing to Remain | Pset_WallCommon - AcousticRating: Rw 52dB Rw+Ctr 48dB; Acoustical Parameters - Acoustic Rating (STC): Rw 52dB Rw+Ctr 48dB
A-Walls-ExternalBrick | FacadeFacingBrick :1,SHE_DRAWING+SHEET.dgn,Design Model;3,SHE-09.FACADE.dgn ,Design Model:105002 | FacadeFacingBrick | back elevation - existing | Existing to Remain | Pset_WallCommon - AcousticRating: Rw 52dB Rw+Ctr 48dB; Acoustical Parameters - Acoustic Rating (STC): Rw 52dB Rw+Ctr 48dB
A-Walls-ExternalBrick | FacadeFacingBrick :1,SHE_DRAWING+SHEET.dgn,Design Model;3,SHE-09.FACADE.dgn ,Design Model:105053 | FacadeFacingBrick | back elevation - existing | Existing to Remain | Pset_WallCommon - AcousticRating: Rw 52dB Rw+Ctr 48dB; Acoustical Parameters - Acoustic Rating (STC): Rw 52dB Rw+Ctr 48dB
A-Walls-ExternalBrick | FacadeFacingBrick :1,SHE_DRAWING+SHEET.dgn,Design Model;3,SHE-09.FACADE.dgn ,Design Model:105096 | FacadeFacingBrick | side elevation - existing | Existing to Remain | Pset_WallCommon - AcousticRating: Rw 52dB Rw+Ctr 48dB; Acoustical Parameters - Acoustic Rating (STC): Rw 52dB Rw+Ctr 48dB

# IfcWall: A-Walls-Internal (164)
In: RL
Type - Wall Parameters - Type: Wall; Compound Wall Assembly: no
Type - Thermal Transmittance - Is External: no; Is Below Grade: no
Type - Space Bounding - Is Space Bounding: yes
Type - Materials - Part Definition: A-Walls::A_BSUK_WallsInternal
Type - LEED Parameters - LEED | Pre-consumer Recycled (%): 0; LEED | Regional Material: no; LEED | Post-consumer Recycled (%): 0
Type - Fire Resistance - Fire | IsCombustible: no; Fire | Compartmentation: no
Type - Discipline - Discipline: Architectural
Type - Classification - Uniclass2015: EF_25_10
Material: A_BSUK_WallsInternal
Pset_WallCommon - Combustible: no; Compartmentation: no; IsExternal: no; LoadBearing: no
Name | Description | ID | Description | ID | Notes | Phase | FireRating = Fire | Rating | ID | Number
A-Walls-Internal | Wall existing :1,SHE_DRAWING+SHEET.dgn,Design Model;1,SHE-01.GROUND.dgn ,Design Model:96115 | Wall existing | general | Existing to Remain
A-Walls-Internal | Wall existing :1,SHE_DRAWING+SHEET.dgn,Design Model;1,SHE-01.GROUND.dgn ,Design Model:96124 | Wall existing | general | Existing to Remain
A-Walls-Internal | Wall existing :1,SHE_DRAWING+SHEET.dgn,Design Model;1,SHE-01.GROUND.dgn ,Design Model:96196 | Wall existing | general | Existing to Remain
A-Walls-Internal | Wall existing :1,SHE_DRAWING+SHEET.dgn,Design Model;1,SHE-01.GROUND.dgn ,Design Model:96205 | Wall existing | general | Existing to Remain
A-Walls-Internal | Wall existing :1,SHE_DRAWING+SHEET.dgn,Design Model;1,SHE-01.GROUND.dgn ,Design Model:96239 | Wall existing | general | Existing to Remain
A-Walls-Internal | Wall existing :1,SHE_DRAWING+SHEET.dgn,Design Model;1,SHE-01.GROUND.dgn ,Design Model:96283 | Wall existing | general | Existing to Remain
A-Walls-Internal | Wall existing :1,SHE_DRAWING+SHEET.dgn,Design Model;1,SHE-01.GROUND.dgn ,Design Model:96294 | Wall existing | general | Existing to Remain
A-Walls-Internal | Wall existing :1,SHE_DRAWING+SHEET.dgn,Design Model;1,SHE-01.GROUND.dgn ,Design Model:96313 | Wall existing | general | Existing to Remain
A-Walls-Internal | Wall existing :1,SHE_DRAWING+SHEET.dgn,Design Model;1,SHE-01.GROUND.dgn ,Design Model:96332 | Wall existing | general | Existing to Remain
A-Walls-Internal | Wall existing :1,SHE_DRAWING+SHEET.dgn,Design Model;1,SHE-01.GROUND.dgn ,Design Model:96341 | Wall existing | general | Existing to Remain
A-Walls-Internal | Wall existing :1,SHE_DRAWING+SHEET.dgn,Design Model;1,SHE-01.GROUND.dgn ,Design Model:96395 | Wall existing | general | Existing to Remain
A-Walls-Internal | Wall existing :1,SHE_DRAWING+SHEET.dgn,Design Model;1,SHE-01.GROUND.dgn ,Design Model:96404 | Wall existing | general | Existing to Remain
A-Walls-Internal | Wall existing :1,SHE_DRAWING+SHEET.dgn,Design Model;1,SHE-01.GROUND.dgn ,Design Model:96711 | Wall existing | general | Existing to Remain
A-Walls-Internal | Wall existing :1,SHE_DRAWING+SHEET.dgn,Design Model;2,SHE-02.MEZZANINE.dgn ,Design Model:93934 | Wall existing | general | Existing to Remain
A-Walls-Internal | Wall existing :1,SHE_DRAWING+SHEET.dgn,Design Model;2,SHE-02.MEZZANINE.dgn ,Design Model:93946 | Wall existing | general | Existing to Remain
A-Walls-Internal | Wall existing :1,SHE_DRAWING+SHEET.dgn,Design Model;2,SHE-02.MEZZANINE.dgn ,Design Model:93961 | Wall existing | general | Existing to Remain
A-Walls-Internal | Wall existing :1,SHE_DRAWING+SHEET.dgn,Design Model;2,SHE-02.MEZZANINE.dgn ,Design Model:93989 | Wall existing | general | Existing to Remain
A-Walls-Internal | Wall existing :1,SHE_DRAWING+SHEET.dgn,Design Model;2,SHE-02.MEZZANINE.dgn ,Design Model:142907 | Wall existing | general | Existing to Remain
7C | SFSWall fire lining :1 ,SHE_DRAWING+SHEET.dgn,Design Model;7,SHE-06.FOURTH.dgn,Design Model:100849 | SFSWall fire lining | fire board - internal mansard roof finish | New Construction | F60 | 7C
7C | SFSWall fire lining :1 ,SHE_DRAWING+SHEET.dgn,Design Model;7,SHE-06.FOURTH.dgn,Design Model:100858 | SFSWall fire lining | fire board - internal mansard roof finish | New Construction | F60 | 7C
7C | SFSWall fire lining :1 ,SHE_DRAWING+SHEET.dgn,Design Model;7,SHE-06.FOURTH.dgn,Design Model:100876 | SFSWall fire lining | fire board - internal mansard roof finish | New Construction | F60 | 7C
7C | SFSWall fire lining :1 ,SHE_DRAWING+SHEET.dgn,Design Model;7,SHE-06.FOURTH.dgn,Design Model:100885 | SFSWall fire lining | fire board - internal mansard roof finish | New Construction | F60 | 7C
7C | SFSWall fire lining :1 ,SHE_DRAWING+SHEET.dgn,Design Model;7,SHE-06.FOURTH.dgn,Design Model:100921 | SFSWall fire lining | fire board - internal mansard roof finish | New Construction | F60 | 7C
7C | SFSWall fire lining :1 ,SHE_DRAWING+SHEET.dgn,Design Model;7,SHE-06.FOURTH.dgn,Design Model:100948 | SFSWall fire lining | fire board - internal mansard roof finish | New Construction | F60 | 7C
7C | SFSWall fire lining :1 ,SHE_DRAWING+SHEET.dgn,Design Model;7,SHE-06.FOURTH.dgn,Design Model:100975 | SFSWall fire lining | fire board - internal mansard roof finish | New Construction | F60 | 7C
7C | SFSWall fire lining :1 ,SHE_DRAWING+SHEET.dgn,Design Model;7,SHE-06.FOURTH.dgn,Design Model:101002 | SFSWall fire lining | fire board - internal mansard roof finish | New Construction | F60 | 7C
7C | SFSWall fire lining :1 ,SHE_DRAWING+SHEET.dgn,Design Model;7,SHE-06.FOURTH.dgn,Design Model:101029 | SFSWall fire lining | fire board - internal mansard roof finish | New Construction | F60 | 7C
7C | SFSWall fire lining :1 ,SHE_DRAWING+SHEET.dgn,Design Model;7,SHE-06.FOURTH.dgn,Design Model:101056 | SFSWall fire lining | fire board - internal mansard roof finish | New Construction | F60 | 7C
7C | SFSWall fire lining :1 ,SHE_DRAWING+SHEET.dgn,Design Model;7,SHE-06.FOURTH.dgn,Design Model:101083 | SFSWall fire lining | fire board - internal mansard roof finish | New Construction | F60 | 7C
7C | SFSWall fire lining :1 ,SHE_DRAWING+SHEET.dgn,Design Model;7,SHE-06.FOURTH.dgn,Design Model:101110 | SFSWall fire lining | fire board - internal mansard roof finish | New Construction | F60 | 7C
7C | SFSWall fire lining :1 ,SHE_DRAWING+SHEET.dgn,Design Model;7,SHE-06.FOURTH.dgn,Design Model:101119 | SFSWall fire lining | fire board - internal mansard roof finish | New Construction | F60 | 7C
7C | SFSWall fire lining :1 ,SHE_DRAWING+SHEET.dgn,Design Model;7,SHE-06.FOURTH.dgn,Design Model:101128 | SFSWall fire lining | fire board - internal mansard roof finish | New Construction | F60 | 7C
7C | SFSWall fire lining :1 ,SHE_DRAWING+SHEET.dgn,Design Model;7,SHE-06.FOURTH.dgn,Design Model:101137 | SFSWall fire lining | fire board - internal mansard roof finish | New Construction | F60 | 7C
7C | SFSWall fire lining :1 ,SHE_DRAWING+SHEET.dgn,Design Model;7,SHE-06.FOURTH.dgn,Design Model:101146 | SFSWall fire lining | fire board - internal mansard roof finish | New Construction | F60 | 7C
7C | SFSWall fire lining :1 ,SHE_DRAWING+SHEET.dgn,Design Model;7,SHE-06.FOURTH.dgn,Design Model:101155 | SFSWall fire lining | fire board - internal mansard roof finish | New Construction | F60 | 7C
7C | SFSWall fire lining :1 ,SHE_DRAWING+SHEET.dgn,Design Model;7,SHE-06.FOURTH.dgn,Design Model:101193 | SFSWall fire lining | fire board - internal mansard roof finish | New Construction | F60 | 7C
7C | SFSWall fire lining :1 ,SHE_DRAWING+SHEET.dgn,Design Model;7,SHE-06.FOURTH.dgn,Design Model:101247 | SFSWall fire lining | fire board - internal mansard roof finish | New Construction | F60 | 7C
7C | SFSWall fire lining :1 ,SHE_DRAWING+SHEET.dgn,Design Model;7,SHE-06.FOURTH.dgn,Design Model:101256 | SFSWall fire lining | fire board - internal mansard roof finish | New Construction | F60 | 7C
7C | SFSWall fire lining :1 ,SHE_DRAWING+SHEET.dgn,Design Model;7,SHE-06.FOURTH.dgn,Design Model:101274 | SFSWall fire lining | fire board - internal mansard roof finish | New Construction | F60 | 7C
7C | SFSWall fire lining :1 ,SHE_DRAWING+SHEET.dgn,Design Model;7,SHE-06.FOURTH.dgn,Design Model:101283 | SFSWall fire lining | fire board - internal mansard roof finish | New Construction | F60 | 7C
7C | SFSWall fire lining :1 ,SHE_DRAWING+SHEET.dgn,Design Model;7,SHE-06.FOURTH.dgn,Design Model:101319 | SFSWall fire lining | fire board - internal mansard roof finish | New Construction | F60 | 7C
7C | SFSWall fire lining :1 ,SHE_DRAWING+SHEET.dgn,Design Model;7,SHE-06.FOURTH.dgn,Design Model:101346 | SFSWall fire lining | fire board - internal mansard roof finish | New Construction | F60 | 7C
7C | SFSWall fire lining :1 ,SHE_DRAWING+SHEET.dgn,Design Model;7,SHE-06.FOURTH.dgn,Design Model:101373 | SFSWall fire lining | fire board - internal mansard roof finish | New Construction | F60 | 7C
7C | SFSWall fire lining :1 ,SHE_DRAWING+SHEET.dgn,Design Model;7,SHE-06.FOURTH.dgn,Design Model:101400 | SFSWall fire lining | fire board - internal mansard roof finish | New Construction | F60 | 7C
7C | SFSWall fire lining :1 ,SHE_DRAWING+SHEET.dgn,Design Model;7,SHE-06.FOURTH.dgn,Design Model:101427 | SFSWall fire lining | fire board - internal mansard roof finish | New Construction | F60 | 7C
7C | SFSWall fire lining :1 ,SHE_DRAWING+SHEET.dgn,Design Model;7,SHE-06.FOURTH.dgn,Design Model:101454 | SFSWall fire lining | fire board - internal mansard roof finish | New Construction | F60 | 7C
7C | SFSWall fire lining :1 ,SHE_DRAWING+SHEET.dgn,Design Model;7,SHE-06.FOURTH.dgn,Design Model:101481 | SFSWall fire lining | fire board - internal mansard roof finish | New Construction | F60 | 7C
7C | SFSWall fire lining :1 ,SHE_DRAWING+SHEET.dgn,Design Model;7,SHE-06.FOURTH.dgn,Design Model:101508 | SFSWall fire lining | fire board - internal mansard roof finish | New Construction | F60 | 7C
7C | SFSWall fire lining :1 ,SHE_DRAWING+SHEET.dgn,Design Model;7,SHE-06.FOURTH.dgn,Design Model:101517 | SFSWall fire lining | fire board - internal mansard roof finish | New Construction | F60 | 7C
7C | SFSWall fire lining :1 ,SHE_DRAWING+SHEET.dgn,Design Model;7,SHE-06.FOURTH.dgn,Design Model:101526 | SFSWall fire lining | fire board - internal mansard roof finish | New Construction | F60 | 7C
7C | SFSWall fire lining :1 ,SHE_DRAWING+SHEET.dgn,Design Model;7,SHE-06.FOURTH.dgn,Design Model:101553 | SFSWall fire lining | fire board - internal mansard roof finish | New Construction | F60 | 7C
7C | SFSWall fire lining :1 ,SHE_DRAWING+SHEET.dgn,Design Model;7,SHE-06.FOURTH.dgn,Design Model:101571 | SFSWall fire lining | fire board - internal mansard roof finish | New Construction | F60 | 7C
7C | SFSWall fire lining :1 ,SHE_DRAWING+SHEET.dgn,Design Model;7,SHE-06.FOURTH.dgn,Design Model:101607 | SFSWall fire lining | fire board - internal mansard roof finish | New Construction | F60 | 7C
A-Walls-Internal | WoodPanel :1 ,SHE_DRAWING+SHEET.dgn,Design Model;7,SHE-06.FOURTH.dgn,Design Model:103246 | WoodPanel | built in wardrobes | New Construction
A-Walls-Internal | WoodPanel :1 ,SHE_DRAWING+SHEET.dgn,Design Model;7,SHE-06.FOURTH.dgn,Design Model:103255 | WoodPanel | built in wardrobes | New Construction
A-Walls-Internal | WoodPanel :1 ,SHE_DRAWING+SHEET.dgn,Design Model;7,SHE-06.FOURTH.dgn,Design Model:103264 | WoodPanel | built in wardrobes | New Construction
A-Walls-Internal | WoodPanel :1 ,SHE_DRAWING+SHEET.dgn,Design Model;7,SHE-06.FOURTH.dgn,Design Model:103327 | WoodPanel | built in wardrobes | New Construction
A-Walls-Internal | WoodPanel :1 ,SHE_DRAWING+SHEET.dgn,Design Model;7,SHE-06.FOURTH.dgn,Design Model:103336 | WoodPanel | built in wardrobes | New Construction
A-Walls-Internal | WoodPanel :1 ,SHE_DRAWING+SHEET.dgn,Design Model;7,SHE-06.FOURTH.dgn,Design Model:103345 | WoodPanel | built in wardrobes | New Construction
A-Walls-Internal | WoodPanel :1 ,SHE_DRAWING+SHEET.dgn,Design Model;7,SHE-06.FOURTH.dgn,Design Model:103354 | WoodPanel | built in wardrobes | New Construction
A-Walls-Internal | WoodPanel :1 ,SHE_DRAWING+SHEET.dgn,Design Model;7,SHE-06.FOURTH.dgn,Design Model:103363 | WoodPanel | built in wardrobes | New Construction
A-Walls-Internal | WoodPanel :1 ,SHE_DRAWING+SHEET.dgn,Design Model;7,SHE-06.FOURTH.dgn,Design Model:103372 | WoodPanel | built in wardrobes | New Construction
A-Walls-Internal | WoodPanel :1 ,SHE_DRAWING+SHEET.dgn,Design Model;7,SHE-06.FOURTH.dgn,Design Model:103381 | WoodPanel | built in wardrobes | New Construction
A-Walls-Internal | WoodPanel :1 ,SHE_DRAWING+SHEET.dgn,Design Model;7,SHE-06.FOURTH.dgn,Design Model:103390 | WoodPanel | built in wardrobes | New Construction
A-Walls-Internal | WoodPanel :1 ,SHE_DRAWING+SHEET.dgn,Design Model;7,SHE-06.FOURTH.dgn,Design Model:103399 | WoodPanel | built in wardrobes | New Construction
A-Walls-Internal | WoodPanel :1 ,SHE_DRAWING+SHEET.dgn,Design Model;7,SHE-06.FOURTH.dgn,Design Model:103408 | WoodPanel | built in wardrobes | New Construction
A-Walls-Internal | WoodPanel :1 ,SHE_DRAWING+SHEET.dgn,Design Model;7,SHE-06.FOURTH.dgn,Design Model:103426 | WoodPanel | built in wardrobes | New Construction
A-Walls-Internal | WoodPanel :1 ,SHE_DRAWING+SHEET.dgn,Design Model;7,SHE-06.FOURTH.dgn,Design Model:103435 | WoodPanel | built in wardrobes | New Construction
A-Walls-Internal | WoodPanel :1 ,SHE_DRAWING+SHEET.dgn,Design Model;7,SHE-06.FOURTH.dgn,Design Model:103444 | WoodPanel | built in wardrobes | New Construction
A-Walls-Internal | WoodPanel :1 ,SHE_DRAWING+SHEET.dgn,Design Model;7,SHE-06.FOURTH.dgn,Design Model:103453 | WoodPanel | built in wardrobes | New Construction
A-Walls-Internal | WoodPanel :1 ,SHE_DRAWING+SHEET.dgn,Design Model;7,SHE-06.FOURTH.dgn,Design Model:103462 | WoodPanel | built in wardrobes | New Construction
A-Walls-Internal | WoodPanel :1 ,SHE_DRAWING+SHEET.dgn,Design Model;7,SHE-06.FOURTH.dgn,Design Model:103480 | WoodPanel | built in wardrobes | New Construction
A-Walls-Internal | WoodPanel :1 ,SHE_DRAWING+SHEET.dgn,Design Model;7,SHE-06.FOURTH.dgn,Design Model:103489 | WoodPanel | built in wardrobes | New Construction
A-Walls-Internal | WoodPanel :1 ,SHE_DRAWING+SHEET.dgn,Design Model;7,SHE-06.FOURTH.dgn,Design Model:103498 | WoodPanel | built in wardrobes | New Construction
A-Walls-Internal | WoodPanel :1 ,SHE_DRAWING+SHEET.dgn,Design Model;7,SHE-06.FOURTH.dgn,Design Model:103507 | WoodPanel | built in wardrobes | New Construction
A-Walls-Internal | WoodPanel :1 ,SHE_DRAWING+SHEET.dgn,Design Model;7,SHE-06.FOURTH.dgn,Design Model:103516 | WoodPanel | built in wardrobes | New Construction
A-Walls-Internal | WoodPanel :1 ,SHE_DRAWING+SHEET.dgn,Design Model;7,SHE-06.FOURTH.dgn,Design Model:103525 | WoodPanel | built in wardrobes | New Construction
A-Walls-Internal | WoodPanel :1 ,SHE_DRAWING+SHEET.dgn,Design Model;7,SHE-06.FOURTH.dgn,Design Model:103534 | WoodPanel | built in wardrobes | New Construction
A-Walls-Internal | WoodPanel :1 ,SHE_DRAWING+SHEET.dgn,Design Model;7,SHE-06.FOURTH.dgn,Design Model:238252 | WoodPanel | built in wardrobes | New Construction
A-Walls-Internal | WoodPanel :1 ,SHE_DRAWING+SHEET.dgn,Design Model;7,SHE-06.FOURTH.dgn,Design Model:238261 | WoodPanel | built in wardrobes | New Construction
A-Walls-Internal | WoodPanel :1 ,SHE_DRAWING+SHEET.dgn,Design Model;7,SHE-06.FOURTH.dgn,Design Model:238270 | WoodPanel | built in wardrobes | New Construction
7C | SFSWall fire lining :1 ,SHE_DRAWING+SHEET.dgn,Design Model;7,SHE-06.FOURTH.dgn,Design Model:469199 | SFSWall fire lining | fire board - internal mansard roof finish | New Construction | F60 | 7C
7C | SFSWall fire lining :1 ,SHE_DRAWING+SHEET.dgn,Design Model;7,SHE-06.FOURTH.dgn,Design Model:469208 | SFSWall fire lining | fire board - internal mansard roof finish | New Construction | F60 | 7C
7C | SFSWall fire lining :1 ,SHE_DRAWING+SHEET.dgn,Design Model;7,SHE-06.FOURTH.dgn,Design Model:469443 | SFSWall fire lining | fire board - internal mansard roof finish | New Construction | F60 | 7C
7C | SFSWall fire lining :1 ,SHE_DRAWING+SHEET.dgn,Design Model;7,SHE-06.FOURTH.dgn,Design Model:469452 | SFSWall fire lining | fire board - internal mansard roof finish | New Construction | F60 | 7C
7C | SFSWall fire lining :1 ,SHE_DRAWING+SHEET.dgn,Design Model;7,SHE-06.FOURTH.dgn,Design Model:469479 | SFSWall fire lining | fire board - internal mansard roof finish | New Construction | F60 | 7C
7C | SFSWall fire lining :1 ,SHE_DRAWING+SHEET.dgn,Design Model;7,SHE-06.FOURTH.dgn,Design Model:469488 | SFSWall fire lining | fire board - internal mansard roof finish | New Construction | F60 | 7C
7C | SFSWall fire lining :1 ,SHE_DRAWING+SHEET.dgn,Design Model;7,SHE-06.FOURTH.dgn,Design Model:469497 | SFSWall fire lining | fire board - internal mansard roof finish | New Construction | F60 | 7C
7C | SFSWall fire lining :1 ,SHE_DRAWING+SHEET.dgn,Design Model;7,SHE-06.FOURTH.dgn,Design Model:469506 | SFSWall fire lining | fire board - internal mansard roof finish | New Construction | F60 | 7C
7C | SFSWall fire lining :1 ,SHE_DRAWING+SHEET.dgn,Design Model;7,SHE-06.FOURTH.dgn,Design Model:469515 | SFSWall fire lining | fire board - internal mansard roof finish | New Construction | F60 | 7C
7C | SFSWall fire lining :1 ,SHE_DRAWING+SHEET.dgn,Design Model;7,SHE-06.FOURTH.dgn,Design Model:469750 | SFSWall fire lining | fire board - internal mansard roof finish | New Construction | F60 | 7C
7C | SFSWall fire lining :1 ,SHE_DRAWING+SHEET.dgn,Design Model;7,SHE-06.FOURTH.dgn,Design Model:469759 | SFSWall fire lining | fire board - internal mansard roof finish | New Construction | F60 | 7C
7C | SFSWall fire lining :1 ,SHE_DRAWING+SHEET.dgn,Design Model;7,SHE-06.FOURTH.dgn,Design Model:469768 | SFSWall fire lining | fire board - internal mansard roof finish | New Construction | F60 | 7C
7C | SFSWall fire lining :1 ,SHE_DRAWING+SHEET.dgn,Design Model;7,SHE-06.FOURTH.dgn,Design Model:469777 | SFSWall fire lining | fire board - internal mansard roof finish | New Construction | F60 | 7C
7C | SFSWall fire lining :1 ,SHE_DRAWING+SHEET.dgn,Design Model;7,SHE-06.FOURTH.dgn,Design Model:469786 | SFSWall fire lining | fire board - internal mansard roof finish | New Construction | F60 | 7C
7C | SFSWall fire lining :1 ,SHE_DRAWING+SHEET.dgn,Design Model;7,SHE-06.FOURTH.dgn,Design Model:469795 | SFSWall fire lining | fire board - internal mansard roof finish | New Construction | F60 | 7C
7C | SFSWall fire lining :1 ,SHE_DRAWING+SHEET.dgn,Design Model;7,SHE-06.FOURTH.dgn,Design Model:469804 | SFSWall fire lining | fire board - internal mansard roof finish | New Construction | F60 | 7C
7C | SFSWall fire lining :1 ,SHE_DRAWING+SHEET.dgn,Design Model;7,SHE-06.FOURTH.dgn,Design Model:469813 | SFSWall fire lining | fire board - internal mansard roof finish | New Construction | F60 | 7C
7C | SFSWall fire lining :1 ,SHE_DRAWING+SHEET.dgn,Design Model;7,SHE-06.FOURTH.dgn,Design Model:469822 | SFSWall fire lining | fire board - internal mansard roof finish | New Construction | F60 | 7C
7C | SFSWall fire lining :1 ,SHE_DRAWING+SHEET.dgn,Design Model;7,SHE-06.FOURTH.dgn,Design Model:469831 | SFSWall fire lining | fire board - internal mansard roof finish | New Construction | F60 | 7C
7C | SFSWall fire lining :1 ,SHE_DRAWING+SHEET.dgn,Design Model;7,SHE-06.FOURTH.dgn,Design Model:469840 | SFSWall fire lining | fire board - internal mansard roof finish | New Construction | F60 | 7C
7C | SFSWall fire lining :1 ,SHE_DRAWING+SHEET.dgn,Design Model;7,SHE-06.FOURTH.dgn,Design Model:469851 | SFSWall fire lining | fire board - internal mansard roof finish | New Construction | F60 | 7C
7C | SFSWall fire lining :1 ,SHE_DRAWING+SHEET.dgn,Design Model;7,SHE-06.FOURTH.dgn,Design Model:469860 | SFSWall fire lining | fire board - internal mansard roof finish | New Construction | F60 | 7C
7C | SFSWall fire lining :1 ,SHE_DRAWING+SHEET.dgn,Design Model;7,SHE-06.FOURTH.dgn,Design Model:469869 | SFSWall fire lining | fire board - internal mansard roof finish | New Construction | F60 | 7C
7C | SFSWall fire lining :1 ,SHE_DRAWING+SHEET.dgn,Design Model;7,SHE-06.FOURTH.dgn,Design Model:469878 | SFSWall fire lining | fire board - internal mansard roof finish | New Construction | F60 | 7C
7C | SFSWall fire lining :1 ,SHE_DRAWING+SHEET.dgn,Design Model;7,SHE-06.FOURTH.dgn,Design Model:469887 | SFSWall fire lining | fire board - internal mansard roof finish | New Construction | F60 | 7C
7C | SFSWall fire lining :1 ,SHE_DRAWING+SHEET.dgn,Design Model;7,SHE-06.FOURTH.dgn,Design Model:469896 | SFSWall fire lining | fire board - internal mansard roof finish | New Construction | F60 | 7C
7C | SFSWall fire lining :1 ,SHE_DRAWING+SHEET.dgn,Design Model;7,SHE-06.FOURTH.dgn,Design Model:469905 | SFSWall fire lining | fire board - internal mansard roof finish | New Construction | F60 | 7C
7C | SFSWall fire lining :1 ,SHE_DRAWING+SHEET.dgn,Design Model;7,SHE-06.FOURTH.dgn,Design Model:469914 | SFSWall fire lining | fire board - internal mansard roof finish | New Construction | F60 | 7C
7C | SFSWall fire lining :1 ,SHE_DRAWING+SHEET.dgn,Design Model;7,SHE-06.FOURTH.dgn,Design Model:469923 | SFSWall fire lining | fire board - internal mansard roof finish | New Construction | F60 | 7C
7C | SFSWall fire lining :1 ,SHE_DRAWING+SHEET.dgn,Design Model;7,SHE-06.FOURTH.dgn,Design Model:469932 | SFSWall fire lining | fire board - internal mansard roof finish | New Construction | F60 | 7C
7C | SFSWall fire lining :1 ,SHE_DRAWING+SHEET.dgn,Design Model;7,SHE-06.FOURTH.dgn,Design Model:469951 | SFSWall fire lining | fire board - internal mansard roof finish | New Construction | F60 | 7C
7C | SFSWall fire lining :1 ,SHE_DRAWING+SHEET.dgn,Design Model;7,SHE-06.FOURTH.dgn,Design Model:104228 | SFSWall fire lining | fire board - internal mansard roof finish | New Construction | F60 | 7C
7C | SFSWall fire lining :1 ,SHE_DRAWING+SHEET.dgn,Design Model;7,SHE-06.FOURTH.dgn,Design Model:104266 | SFSWall fire lining | fire board - internal mansard roof finish | New Construction | F60 | 7C
7C | SFSWall fire lining :1 ,SHE_DRAWING+SHEET.dgn,Design Model;7,SHE-06.FOURTH.dgn,Design Model:470048 | SFSWall fire lining | fire board - internal mansard roof finish | New Construction | F60 | 7C
7C | SFSWall fire lining :1 ,SHE_DRAWING+SHEET.dgn,Design Model;7,SHE-06.FOURTH.dgn,Design Model:470057 | SFSWall fire lining | fire board - internal mansard roof finish | New Construction | F60 | 7C
7C | SFSWall fire lining :1 ,SHE_DRAWING+SHEET.dgn,Design Model;7,SHE-06.FOURTH.dgn,Design Model:470066 | SFSWall fire lining | fire board - internal mansard roof finish | New Construction | F60 | 7C
7C | SFSWall fire lining :1 ,SHE_DRAWING+SHEET.dgn,Design Model;7,SHE-06.FOURTH.dgn,Design Model:470075 | SFSWall fire lining | fire board - internal mansard roof finish | New Construction | F60 | 7C
7C | SFSWall fire lining :1 ,SHE_DRAWING+SHEET.dgn,Design Model;7,SHE-06.FOURTH.dgn,Design Model:470084 | SFSWall fire lining | fire board - internal mansard roof finish | New Construction | F60 | 7C
A-Walls-Internal | StairFireWall :1,SHE_DRAWING+SHEET.dgn,Design Model;7,SHE-06.FOURTH.dgn ,Design Model:483592 | StairFireWall | lift wall enforcement | New Construction | F120 | Wall Parameters - Cavity: Insulation: Fire
A-Walls-Internal | StairFireWall :1,SHE_DRAWING+SHEET.dgn,Design Model;7,SHE-06.FOURTH.dgn ,Design Model:483601 | StairFireWall | lift wall enforcement | New Construction | F120 | Wall Parameters - Cavity: Insulation: Fire
A-Walls-Internal | WoodPanel :1 ,SHE_DRAWING+SHEET.dgn,Design Model;8,SHE-07.FIFTH.dgn,Design Model:94365 | WoodPanel | built in wardrobes | New Construction
A-Walls-Internal | WoodPanel :1 ,SHE_DRAWING+SHEET.dgn,Design Model;8,SHE-07.FIFTH.dgn,Design Model:94374 | WoodPanel | built in wardrobes | New Construction
A-Walls-Internal | WoodPanel :1 ,SHE_DRAWING+SHEET.dgn,Design Model;8,SHE-07.FIFTH.dgn,Design Model:94383 | WoodPanel | built in wardrobes | New Construction
7C | SFSWall fire lining :1 ,SHE_DRAWING+SHEET.dgn,Design Model;8,SHE-07.FIFTH.dgn,Design Model:264350 | SFSWall fire lining | fire board - internal mansard roof finish | New Construction | F60 | 7C
7C | SFSWall fire lining :1 ,SHE_DRAWING+SHEET.dgn,Design Model;8,SHE-07.FIFTH.dgn,Design Model:264359 | SFSWall fire lining | fire board - internal mansard roof finish | New Construction | F60 | 7C
7C | SFSWall fire lining :1 ,SHE_DRAWING+SHEET.dgn,Design Model;8,SHE-07.FIFTH.dgn,Design Model:264368 | SFSWall fire lining | fire board - internal mansard roof finish | New Construction | F60 | 7C
7C | SFSWall fire lining :1 ,SHE_DRAWING+SHEET.dgn,Design Model;8,SHE-07.FIFTH.dgn,Design Model:264377 | SFSWall fire lining | fire board - internal mansard roof finish | New Construction | F60 | 7C
7C | SFSWall fire lining :1 ,SHE_DRAWING+SHEET.dgn,Design Model;8,SHE-07.FIFTH.dgn,Design Model:264386 | SFSWall fire lining | fire board - internal mansard roof finish | New Construction | F60 | 7C
7C | SFSWall fire lining :1 ,SHE_DRAWING+SHEET.dgn,Design Model;8,SHE-07.FIFTH.dgn,Design Model:264395 | SFSWall fire lining | fire board - internal mansard roof finish | New Construction | F60 | 7C
7C | SFSWall fire lining :1 ,SHE_DRAWING+SHEET.dgn,Design Model;8,SHE-07.FIFTH.dgn,Design Model:264405 | SFSWall fire lining | fire board - internal mansard roof finish | New Construction | F60 | 7C
7C | SFSWall fire lining :1 ,SHE_DRAWING+SHEET.dgn,Design Model;8,SHE-07.FIFTH.dgn,Design Model:264414 | SFSWall fire lining | fire board - internal mansard roof finish | New Construction | F60 | 7C
7C | SFSWall fire lining :1 ,SHE_DRAWING+SHEET.dgn,Design Model;8,SHE-07.FIFTH.dgn,Design Model:264423 | SFSWall fire lining | fire board - internal mansard roof finish | New Construction | F60 | 7C
7C | SFSWall fire lining :1 ,SHE_DRAWING+SHEET.dgn,Design Model;8,SHE-07.FIFTH.dgn,Design Model:264432 | SFSWall fire lining | fire board - internal mansard roof finish | New Construction | F60 | 7C
7C | SFSWall fire lining :1 ,SHE_DRAWING+SHEET.dgn,Design Model;8,SHE-07.FIFTH.dgn,Design Model:264610 | SFSWall fire lining | fire board - internal mansard roof finish | New Construction | F60 | 7C
7C | SFSWall fire lining :1 ,SHE_DRAWING+SHEET.dgn,Design Model;8,SHE-07.FIFTH.dgn,Design Model:264619 | SFSWall fire lining | fire board - internal mansard roof finish | New Construction | F60 | 7C
7C | SFSWall fire lining :1 ,SHE_DRAWING+SHEET.dgn,Design Model;8,SHE-07.FIFTH.dgn,Design Model:264628 | SFSWall fire lining | fire board - internal mansard roof finish | New Construction | F60 | 7C
7C | SFSWall fire lining :1 ,SHE_DRAWING+SHEET.dgn,Design Model;8,SHE-07.FIFTH.dgn,Design Model:264637 | SFSWall fire lining | fire board - internal mansard roof finish | New Construction | F60 | 7C
7C | SFSWall fire lining :1 ,SHE_DRAWING+SHEET.dgn,Design Model;8,SHE-07.FIFTH.dgn,Design Model:264646 | SFSWall fire lining | fire board - internal mansard roof finish | New Construction | F60 | 7C
7C | SFSWall fire lining :1 ,SHE_DRAWING+SHEET.dgn,Design Model;8,SHE-07.FIFTH.dgn,Design Model:264655 | SFSWall fire lining | fire board - internal mansard roof finish | New Construction | F60 | 7C
7C | SFSWall fire lining :1 ,SHE_DRAWING+SHEET.dgn,Design Model;8,SHE-07.FIFTH.dgn,Design Model:264664 | SFSWall fire lining | fire board - internal mansard roof finish | New Construction | F60 | 7C
7C | SFSWall fire lining :1 ,SHE_DRAWING+SHEET.dgn,Design Model;8,SHE-07.FIFTH.dgn,Design Model:264673 | SFSWall fire lining | fire board - internal mansard roof finish | New Construction | F60 | 7C
7C | SFSWall fire lining :1 ,SHE_DRAWING+SHEET.dgn,Design Model;8,SHE-07.FIFTH.dgn,Design Model:264682 | SFSWall fire lining | fire board - internal mansard roof finish | New Construction | F60 | 7C
7C | SFSWall fire lining :1 ,SHE_DRAWING+SHEET.dgn,Design Model;8,SHE-07.FIFTH.dgn,Design Model:264691 | SFSWall fire lining | fire board - internal mansard roof finish | New Construction | F60 | 7C
7C | SFSWall fire lining :1 ,SHE_DRAWING+SHEET.dgn,Design Model;8,SHE-07.FIFTH.dgn,Design Model:264880 | SFSWall fire lining | fire board - internal mansard roof finish | New Construction | F60 | 7C
7C | SFSWall fire lining :1 ,SHE_DRAWING+SHEET.dgn,Design Model;8,SHE-07.FIFTH.dgn,Design Model:264889 | SFSWall fire lining | fire board - internal mansard roof finish | New Construction | F60 | 7C
7C | SFSWall fire lining :1 ,SHE_DRAWING+SHEET.dgn,Design Model;8,SHE-07.FIFTH.dgn,Design Model:264898 | SFSWall fire lining | fire board - internal mansard roof finish | New Construction | F60 | 7C
7C | SFSWall fire lining :1 ,SHE_DRAWING+SHEET.dgn,Design Model;8,SHE-07.FIFTH.dgn,Design Model:264907 | SFSWall fire lining | fire board - internal mansard roof finish | New Construction | F60 | 7C
7C | SFSWall fire lining :1 ,SHE_DRAWING+SHEET.dgn,Design Model;8,SHE-07.FIFTH.dgn,Design Model:264916 | SFSWall fire lining | fire board - internal mansard roof finish | New Construction | F60 | 7C
7C | SFSWall fire lining :1 ,SHE_DRAWING+SHEET.dgn,Design Model;8,SHE-07.FIFTH.dgn,Design Model:264925 | SFSWall fire lining | fire board - internal mansard roof finish | New Construction | F60 | 7C
7C | SFSWall fire lining :1 ,SHE_DRAWING+SHEET.dgn,Design Model;8,SHE-07.FIFTH.dgn,Design Model:264934 | SFSWall fire lining | fire board - internal mansard roof finish | New Construction | F60 | 7C
7C | SFSWall fire lining :1 ,SHE_DRAWING+SHEET.dgn,Design Model;8,SHE-07.FIFTH.dgn,Design Model:264943 | SFSWall fire lining | fire board - internal mansard roof finish | New Construction | F60 | 7C
7C | SFSWall fire lining :1 ,SHE_DRAWING+SHEET.dgn,Design Model;8,SHE-07.FIFTH.dgn,Design Model:264952 | SFSWall fire lining | fire board - internal mansard roof finish | New Construction | F60 | 7C
7C | SFSWall fire lining :1 ,SHE_DRAWING+SHEET.dgn,Design Model;8,SHE-07.FIFTH.dgn,Design Model:264961 | SFSWall fire lining | fire board - internal mansard roof finish | New Construction | F60 | 7C
7C | SFSWall fire lining :1 ,SHE_DRAWING+SHEET.dgn,Design Model;8,SHE-07.FIFTH.dgn,Design Model:264970 | SFSWall fire lining | fire board - internal mansard roof finish | New Construction | F60 | 7C
7C | SFSWall fire lining :1 ,SHE_DRAWING+SHEET.dgn,Design Model;8,SHE-07.FIFTH.dgn,Design Model:264979 | SFSWall fire lining | fire board - internal mansard roof finish | New Construction | F60 | 7C
7C | SFSWall fire lining :1 ,SHE_DRAWING+SHEET.dgn,Design Model;8,SHE-07.FIFTH.dgn,Design Model:264988 | SFSWall fire lining | fire board - internal mansard roof finish | New Construction | F60 | 7C
7C | SFSWall fire lining :1 ,SHE_DRAWING+SHEET.dgn,Design Model;8,SHE-07.FIFTH.dgn,Design Model:264997 | SFSWall fire lining | fire board - internal mansard roof finish | New Construction | F60 | 7C
7C | SFSWall fire lining :1 ,SHE_DRAWING+SHEET.dgn,Design Model;8,SHE-07.FIFTH.dgn,Design Model:265006 | SFSWall fire lining | fire board - internal mansard roof finish | New Construction | F60 | 7C
7C | SFSWall fire lining :1 ,SHE_DRAWING+SHEET.dgn,Design Model;8,SHE-07.FIFTH.dgn,Design Model:265015 | SFSWall fire lining | fire board - internal mansard roof finish | New Construction | F60 | 7C
7C | SFSWall fire lining :1 ,SHE_DRAWING+SHEET.dgn,Design Model;8,SHE-07.FIFTH.dgn,Design Model:265024 | SFSWall fire lining | fire board - internal mansard roof finish | New Construction | F60 | 7C
7C | SFSWall fire lining :1 ,SHE_DRAWING+SHEET.dgn,Design Model;8,SHE-07.FIFTH.dgn,Design Model:265033 | SFSWall fire lining | fire board - internal mansard roof finish | New Construction | F60 | 7C
7C | SFSWall fire lining :1 ,SHE_DRAWING+SHEET.dgn,Design Model;8,SHE-07.FIFTH.dgn,Design Model:265042 | SFSWall fire lining | fire board - internal mansard roof finish | New Construction | F60 | 7C
7C | SFSWall fire lining :1 ,SHE_DRAWING+SHEET.dgn,Design Model;8,SHE-07.FIFTH.dgn,Design Model:265051 | SFSWall fire lining | fire board - internal mansard roof finish | New Construction | F60 | 7C

# IfcWall: A-Walls-InternalBlock (7)
In: RL
Type - Wall Parameters - Type: Wall; Compound Wall Assembly: no
Type - Thermal Transmittance - Is External: no; Is Below Grade: no
Type - Structural Usage - Structural | Material: Blockwork
Type - Space Bounding - Is Space Bounding: yes
Type - Materials - Part Definition: A-Walls::A_BSUK_WallsInternal_Block
Type - LEED Parameters - LEED | Pre-consumer Recycled (%): 0; LEED | Regional Material: no; LEED | Post-consumer Recycled (%): 0
Type - Fire Resistance - Fire | Compartmentation: no
Type - Discipline - Discipline: Architectural
Type - Classification - Uniclass2015: Pr_20_93_52_01
Material: A_BSUK_WallsInternal_Block
Pset_WallCommon - Combustible: no; Compartmentation: no; IsExternal: no; LoadBearing: no
Identification - ID | Description: Wall existing; ID | Notes: general
Fire Resistance - Fire | IsCombustible: no
Construction Phase - Phase: Existing to Remain
Name | Description
A-Walls-InternalBlock | Wall existing :1,SHE_DRAWING+SHEET.dgn,Design Model;1,SHE-01.GROUND.dgn ,Design Model:96078
A-Walls-InternalBlock | Wall existing :1,SHE_DRAWING+SHEET.dgn,Design Model;1,SHE-01.GROUND.dgn ,Design Model:96151
A-Walls-InternalBlock | Wall existing :1,SHE_DRAWING+SHEET.dgn,Design Model;1,SHE-01.GROUND.dgn ,Design Model:96163
A-Walls-InternalBlock | Wall existing :1,SHE_DRAWING+SHEET.dgn,Design Model;1,SHE-01.GROUND.dgn ,Design Model:96448
A-Walls-InternalBlock | Wall existing :1,SHE_DRAWING+SHEET.dgn,Design Model;1,SHE-01.GROUND.dgn ,Design Model:178785
A-Walls-InternalBlock | Wall existing :1,SHE_DRAWING+SHEET.dgn,Design Model;2,SHE-02.MEZZANINE.dgn ,Design Model:93268
A-Walls-InternalBlock | Wall existing :1,SHE_DRAWING+SHEET.dgn,Design Model;2,SHE-02.MEZZANINE.dgn ,Design Model:93277

# IfcWall: A-Walls:A_BSUK_Insulation (8)
In: RL
Material: A_BSUK_Insulation
Name | Description
A-Walls--A_BSUK_Insulation | 1 ,SHE_DRAWING+SHEET.dgn,Design Model;8,SHE-07.FIFTH.dgn,Design Model:89651
A-Walls--A_BSUK_Insulation | 1 ,SHE_DRAWING+SHEET.dgn,Design Model;8,SHE-07.FIFTH.dgn,Design Model:213302
A-Walls--A_BSUK_Insulation | 1 ,SHE_DRAWING+SHEET.dgn,Design Model;8,SHE-07.FIFTH.dgn,Design Model:213314
A-Walls--A_BSUK_Insulation | 1 ,SHE_DRAWING+SHEET.dgn,Design Model;8,SHE-07.FIFTH.dgn,Design Model:213509
A-Walls--A_BSUK_Insulation | 1 ,SHE_DRAWING+SHEET.dgn,Design Model;8,SHE-07.FIFTH.dgn,Design Model:213521
A-Walls--A_BSUK_Insulation | 1 ,SHE_DRAWING+SHEET.dgn,Design Model;8,SHE-07.FIFTH.dgn,Design Model:214738
A-Walls--A_BSUK_Insulation | 1 ,SHE_DRAWING+SHEET.dgn,Design Model;8,SHE-07.FIFTH.dgn,Design Model:214750
A-Walls--A_BSUK_Insulation | 1 ,SHE_DRAWING+SHEET.dgn,Design Model;8,SHE-07.FIFTH.dgn,Design Model:172709

# IfcWall: A-Walls:A_BSUK_WallInternal_Finishes_Metal (2)
In: RL
Material: A_BSUK_WallInternal_Finishes_Metal
Name | Description
A-Walls--A_BSUK_WallInternal_Finishes_Metal | 1,SHE_DRAWING+SHEET.dgn ,Design Model;8,SHE-07.FIFTH.dgn,Design Model:89638
A-Walls--A_BSUK_WallInternal_Finishes_Metal | 1,SHE_DRAWING+SHEET.dgn ,Design Model;8,SHE-07.FIFTH.dgn,Design Model:213485

# IfcWall: A-Walls:A_BSUK_WallInternal_Finishes_Plasterboard (10)
In: RL
Material: A_BSUK_WallInternal_Finishes_Plasterboard
Name | Description
A-Walls--A_BSUK_WallInternal_Finishes_Plasterboard | 1,SHE_DRAWING+SHEET.dgn ,Design Model;8,SHE-07.FIFTH.dgn,Design Model:172565
A-Walls--A_BSUK_WallInternal_Finishes_Plasterboard | 1,SHE_DRAWING+SHEET.dgn ,Design Model;8,SHE-07.FIFTH.dgn,Design Model:172577
A-Walls--A_BSUK_WallInternal_Finishes_Plasterboard | 1,SHE_DRAWING+SHEET.dgn ,Design Model;8,SHE-07.FIFTH.dgn,Design Model:172589
A-Walls--A_BSUK_WallInternal_Finishes_Plasterboard | 1,SHE_DRAWING+SHEET.dgn ,Design Model;8,SHE-07.FIFTH.dgn,Design Model:172601
A-Walls--A_BSUK_WallInternal_Finishes_Plasterboard | 1,SHE_DRAWING+SHEET.dgn ,Design Model;8,SHE-07.FIFTH.dgn,Design Model:213326
A-Walls--A_BSUK_WallInternal_Finishes_Plasterboard | 1,SHE_DRAWING+SHEET.dgn ,Design Model;8,SHE-07.FIFTH.dgn,Design Model:213533
A-Walls--A_BSUK_WallInternal_Finishes_Plasterboard | 1,SHE_DRAWING+SHEET.dgn ,Design Model;8,SHE-07.FIFTH.dgn,Design Model:89663
A-Walls--A_BSUK_WallInternal_Finishes_Plasterboard | 1,SHE_DRAWING+SHEET.dgn ,Design Model;8,SHE-07.FIFTH.dgn,Design Model:172673
A-Walls--A_BSUK_WallInternal_Finishes_Plasterboard | 1,SHE_DRAWING+SHEET.dgn ,Design Model;8,SHE-07.FIFTH.dgn,Design Model:172685
A-Walls--A_BSUK_WallInternal_Finishes_Plasterboard | 1,SHE_DRAWING+SHEET.dgn ,Design Model;8,SHE-07.FIFTH.dgn,Design Model:172697

# IfcWall: A-Walls:A_BSUK_WallsExternal (10)
In: RL
Material: A_BSUK_WallsExternal
Name | Description
A-Walls--A_BSUK_WallsExternal | 1 ,SHE_DRAWING+SHEET.dgn,Design Model;8,SHE-07.FIFTH.dgn,Design Model:89675
A-Walls--A_BSUK_WallsExternal | 1 ,SHE_DRAWING+SHEET.dgn,Design Model;8,SHE-07.FIFTH.dgn,Design Model:89691
A-Walls--A_BSUK_WallsExternal | 1 ,SHE_DRAWING+SHEET.dgn,Design Model;8,SHE-07.FIFTH.dgn,Design Model:89703
A-Walls--A_BSUK_WallsExternal | 1 ,SHE_DRAWING+SHEET.dgn,Design Model;8,SHE-07.FIFTH.dgn,Design Model:89715
A-Walls--A_BSUK_WallsExternal | 1 ,SHE_DRAWING+SHEET.dgn,Design Model;8,SHE-07.FIFTH.dgn,Design Model:89727
A-Walls--A_BSUK_WallsExternal | 1 ,SHE_DRAWING+SHEET.dgn,Design Model;8,SHE-07.FIFTH.dgn,Design Model:89743
A-Walls--A_BSUK_WallsExternal | 1 ,SHE_DRAWING+SHEET.dgn,Design Model;8,SHE-07.FIFTH.dgn,Design Model:89755
A-Walls--A_BSUK_WallsExternal | 1 ,SHE_DRAWING+SHEET.dgn,Design Model;8,SHE-07.FIFTH.dgn,Design Model:89771
A-Walls--A_BSUK_WallsExternal | 1 ,SHE_DRAWING+SHEET.dgn,Design Model;8,SHE-07.FIFTH.dgn,Design Model:89783
A-Walls--A_BSUK_WallsExternal | 1 ,SHE_DRAWING+SHEET.dgn,Design Model;8,SHE-07.FIFTH.dgn,Design Model:89799

# IfcWall: A-Walls:A_BSUK_WallsExternal_Block (2)
In: RL
Material: A_BSUK_WallsExternal_Block
Name | Description
A-Walls--A_BSUK_WallsExternal_Block | 1,SHE_DRAWING+SHEET.dgn,Design Model;8 ,SHE-07.FIFTH.dgn,Design Model:89811
A-Walls--A_BSUK_WallsExternal_Block | 1,SHE_DRAWING+SHEET.dgn,Design Model;8 ,SHE-07.FIFTH.dgn,Design Model:89824

# IfcWall: A-Walls:A_BSUK_Walls_Timber (2)
In: RL
Material: A_BSUK_Walls_Timber
Name | Description
A-Walls--A_BSUK_Walls_Timber | 1 ,SHE_DRAWING+SHEET.dgn,Design Model;8,SHE-07.FIFTH.dgn,Design Model:213290
A-Walls--A_BSUK_Walls_Timber | 1 ,SHE_DRAWING+SHEET.dgn,Design Model;8,SHE-07.FIFTH.dgn,Design Model:213497

# IfcWall: SHE_A-Walls_Type01a_Partywall_250mm_twin (3)
In: RL
Type - Description: SHE_A-Walls_Type01a_Partywall_250mm_twin
Type - Wall Parameters - Type: Wall; Compound Wall Assembly: yes
Type - Thermal Transmittance - Is External: no; Is Below Grade: no
Type - Space Bounding - Is Space Bounding: yes
Type - Materials - Part Definition: A-CompoundWalls::SHE_A-Walls_Type01a_Partywall_250mm_twin
Type - LEED Parameters - LEED | Pre-consumer Recycled (%): 0; LEED | Regional Material: no; LEED | Post-consumer Recycled (%): 0
Type - Identification - ID | Type ID: A216013 (EN); ID | Description: SHE_A-Walls_Type01a_Partywall_250mm_twin; ID | Notes: https://www.british-gypsu m.com/Specification/White-Book-Specification-Selector/internal-partitions-walls/gypwall-twin-frame-independent/a216013-en
Type - Fire Resistance - Fire | Rating: F90 (min. F60); Fire | IsCombustible: no; Fire | Compartmentation: no
Type - Discipline - Discipline: Architectural
Type - Construction Phase - Phase: New Construction
Type - Classification - Uniclass2015: EF_25_10
Type - Acoustical Parameters - Acoustic Rating (STC): 62 (min. 60)
Pset_WallCommon - AcousticRating: 62 (req. 60); Combustible: no; Compartmentation: no; FireRating: F90 (min. F60); IsExternal: no; LoadBearing: no
Identification - ID | Number: 1A; ID | Description: PartyWall; ID | Keynote: https://www.british-gyp sum.com/Specification/White-Book-Specification-Selector/internal-partitions-walls/gypwall-twin-frame-independent/a216013-en; ID | Notes: SHE_A-Walls_Type01a_Partywall_250mm_twin
Acoustical Parameters - Acoustic Rating (STC): 62 (req. 60)
Name | Description
1A | A216013 (EN) - PartyWall :1 ,SHE_DRAWING+SHEET.dgn,Design Model;1,SHE-01.GROUND.dgn,Design Model:150201
1A | A216013 (EN) - PartyWall :1 ,SHE_DRAWING+SHEET.dgn,Design Model;1,SHE-01.GROUND.dgn,Design Model:150265
1A | A216013 (EN) - PartyWall :1 ,SHE_DRAWING+SHEET.dgn,Design Model;1,SHE-01.GROUND.dgn,Design Model:160929

# IfcWall: SHE_A-Walls_Type01c_Partywall_225mm_twin_tall (48)
In: RL
Type - Description: SHE_A-Walls_Type01c_Partywall_225mm_twin_tall
Type - Wall Parameters - Type: Wall; Compound Wall Assembly: yes
Type - Thermal Transmittance - Is External: no; Is Below Grade: no
Type - Space Bounding - Is Space Bounding: yes
Type - Materials - Part Definition: A-CompoundWalls::SHE_A-Walls_Type01c_Partywall_225mm_twin_tall
Type - LEED Parameters - LEED | Pre-consumer Recycled (%): 0; LEED | Regional Material: no; LEED | Post-consumer Recycled (%): 0
Type - Identification - ID | Type ID: L216017F (EN); ID | Description: SHE_A-Walls_Type01c_Partywall_225mm_twin_tall; ID | Notes: https://www.british-gypsu m.com/Specification/White-Book-Specification-Selector/internal-partitions-walls/gypwall-twin-frame-independent/L216017F-en
Type - Fire Resistance - Fire | Rating: F90 (min. F60); Fire | IsCombustible: no; Fire | Compartmentation: no
Type - Discipline - Discipline: Architectural
Type - Construction Phase - Phase: New Construction
Type - Classification - Uniclass2015: EF_25_10
Type - Acoustical Parameters - Acoustic Rating (STC): 57 (min. 53)
Pset_WallCommon - AcousticRating: 57 (req. 53); Combustible: no; Compartmentation: no; FireRating: F90 (min. F60); IsExternal: no; LoadBearing: no
Identification - ID | Number: 1C; ID | Description: PartyWall; ID | Keynote: https://www.british-gyp sum.com/Specification/White-Book-Specification-Selector/internal-partitions-walls/gypwall-twin-frame-independent/L216017F-en; ID | Notes: SHE_A-Walls_Type01c_Partywall_225mm_twin_tall
Acoustical Parameters - Acoustic Rating (STC): 57 (req. 53)
Name | Description
1C | L216017F (EN) - PartyWall :1 ,SHE_DRAWING+SHEET.dgn,Design Model;4,SHE-03.FIRST.dgn,Design Model:141623
1C | L216017F (EN) - PartyWall :1 ,SHE_DRAWING+SHEET.dgn,Design Model;4,SHE-03.FIRST.dgn,Design Model:142251
1C | L216017F (EN) - PartyWall :1 ,SHE_DRAWING+SHEET.dgn,Design Model;4,SHE-03.FIRST.dgn,Design Model:142252
1C | L216017F (EN) - PartyWall :1 ,SHE_DRAWING+SHEET.dgn,Design Model;4,SHE-03.FIRST.dgn,Design Model:142267
1C | L216017F (EN) - PartyWall :1 ,SHE_DRAWING+SHEET.dgn,Design Model;4,SHE-03.FIRST.dgn,Design Model:142269
1C | L216017F (EN) - PartyWall :1 ,SHE_DRAWING+SHEET.dgn,Design Model;4,SHE-03.FIRST.dgn,Design Model:142540
1C | L216017F (EN) - PartyWall :1 ,SHE_DRAWING+SHEET.dgn,Design Model;4,SHE-03.FIRST.dgn,Design Model:142541
1C | L216017F (EN) - PartyWall :1 ,SHE_DRAWING+SHEET.dgn,Design Model;4,SHE-03.FIRST.dgn,Design Model:142543
1C | L216017F (EN) - PartyWall :1 ,SHE_DRAWING+SHEET.dgn,Design Model;4,SHE-03.FIRST.dgn,Design Model:143075
1C | L216017F (EN) - PartyWall :1 ,SHE_DRAWING+SHEET.dgn,Design Model;4,SHE-03.FIRST.dgn,Design Model:143191
1C | L216017F (EN) - PartyWall :1 ,SHE_DRAWING+SHEET.dgn,Design Model;4,SHE-03.FIRST.dgn,Design Model:147003
1C | L216017F (EN) - PartyWall :1 ,SHE_DRAWING+SHEET.dgn,Design Model;4,SHE-03.FIRST.dgn,Design Model:147004
1C | L216017F (EN) - PartyWall :1 ,SHE_DRAWING+SHEET.dgn,Design Model;4,SHE-03.FIRST.dgn,Design Model:170354
1C | L216017F (EN) - PartyWall :1 ,SHE_DRAWING+SHEET.dgn,Design Model;4,SHE-03.FIRST.dgn,Design Model:258646
1C | L216017F (EN) - PartyWall :1 ,SHE_DRAWING+SHEET.dgn,Design Model;4,SHE-03.FIRST.dgn,Design Model:261780
1C | L216017F (EN) - PartyWall :1 ,SHE_DRAWING+SHEET.dgn,Design Model;4,SHE-03.FIRST.dgn,Design Model:376414
1C | L216017F (EN) - PartyWall :1 ,SHE_DRAWING+SHEET.dgn,Design Model;6,SHE-05.THIRD.dgn,Design Model:141623
1C | L216017F (EN) - PartyWall :1 ,SHE_DRAWING+SHEET.dgn,Design Model;6,SHE-05.THIRD.dgn,Design Model:142251
1C | L216017F (EN) - PartyWall :1 ,SHE_DRAWING+SHEET.dgn,Design Model;6,SHE-05.THIRD.dgn,Design Model:142252
1C | L216017F (EN) - PartyWall :1 ,SHE_DRAWING+SHEET.dgn,Design Model;6,SHE-05.THIRD.dgn,Design Model:142267
1C | L216017F (EN) - PartyWall :1 ,SHE_DRAWING+SHEET.dgn,Design Model;6,SHE-05.THIRD.dgn,Design Model:142269
1C | L216017F (EN) - PartyWall :1 ,SHE_DRAWING+SHEET.dgn,Design Model;6,SHE-05.THIRD.dgn,Design Model:142540
1C | L216017F (EN) - PartyWall :1 ,SHE_DRAWING+SHEET.dgn,Design Model;6,SHE-05.THIRD.dgn,Design Model:142541
1C | L216017F (EN) - PartyWall :1 ,SHE_DRAWING+SHEET.dgn,Design Model;6,SHE-05.THIRD.dgn,Design Model:142543
1C | L216017F (EN) - PartyWall :1 ,SHE_DRAWING+SHEET.dgn,Design Model;6,SHE-05.THIRD.dgn,Design Model:143075
1C | L216017F (EN) - PartyWall :1 ,SHE_DRAWING+SHEET.dgn,Design Model;6,SHE-05.THIRD.dgn,Design Model:143191
1C | L216017F (EN) - PartyWall :1 ,SHE_DRAWING+SHEET.dgn,Design Model;6,SHE-05.THIRD.dgn,Design Model:143374
1C | L216017F (EN) - PartyWall :1 ,SHE_DRAWING+SHEET.dgn,Design Model;6,SHE-05.THIRD.dgn,Design Model:147003
1C | L216017F (EN) - PartyWall :1 ,SHE_DRAWING+SHEET.dgn,Design Model;6,SHE-05.THIRD.dgn,Design Model:147004
1C | L216017F (EN) - PartyWall :1 ,SHE_DRAWING+SHEET.dgn,Design Model;6,SHE-05.THIRD.dgn,Design Model:170354
1C | L216017F (EN) - PartyWall :1 ,SHE_DRAWING+SHEET.dgn,Design Model;6,SHE-05.THIRD.dgn,Design Model:258646
1C | L216017F (EN) - PartyWall :1 ,SHE_DRAWING+SHEET.dgn,Design Model;6,SHE-05.THIRD.dgn,Design Model:261780
1C | L216017F (EN) - PartyWall :1 ,SHE_DRAWING+SHEET.dgn,Design Model;18,SHE-04.SECOND.dgn,Design Model:141623
1C | L216017F (EN) - PartyWall :1 ,SHE_DRAWING+SHEET.dgn,Design Model;18,SHE-04.SECOND.dgn,Design Model:142251
1C | L216017F (EN) - PartyWall :1 ,SHE_DRAWING+SHEET.dgn,Design Model;18,SHE-04.SECOND.dgn,Design Model:142252
1C | L216017F (EN) - PartyWall :1 ,SHE_DRAWING+SHEET.dgn,Design Model;18,SHE-04.SECOND.dgn,Design Model:142267
1C | L216017F (EN) - PartyWall :1 ,SHE_DRAWING+SHEET.dgn,Design Model;18,SHE-04.SECOND.dgn,Design Model:142269
1C | L216017F (EN) - PartyWall :1 ,SHE_DRAWING+SHEET.dgn,Design Model;18,SHE-04.SECOND.dgn,Design Model:142540
1C | L216017F (EN) - PartyWall :1 ,SHE_DRAWING+SHEET.dgn,Design Model;18,SHE-04.SECOND.dgn,Design Model:142541
1C | L216017F (EN) - PartyWall :1 ,SHE_DRAWING+SHEET.dgn,Design Model;18,SHE-04.SECOND.dgn,Design Model:142543
1C | L216017F (EN) - PartyWall :1 ,SHE_DRAWING+SHEET.dgn,Design Model;18,SHE-04.SECOND.dgn,Design Model:143191
1C | L216017F (EN) - PartyWall :1 ,SHE_DRAWING+SHEET.dgn,Design Model;18,SHE-04.SECOND.dgn,Design Model:143374
1C | L216017F (EN) - PartyWall :1 ,SHE_DRAWING+SHEET.dgn,Design Model;18,SHE-04.SECOND.dgn,Design Model:147003
1C | L216017F (EN) - PartyWall :1 ,SHE_DRAWING+SHEET.dgn,Design Model;18,SHE-04.SECOND.dgn,Design Model:147004
1C | L216017F (EN) - PartyWall :1 ,SHE_DRAWING+SHEET.dgn,Design Model;18,SHE-04.SECOND.dgn,Design Model:170354
1C | L216017F (EN) - PartyWall :1 ,SHE_DRAWING+SHEET.dgn,Design Model;18,SHE-04.SECOND.dgn,Design Model:258646
1C | L216017F (EN) - PartyWall :1 ,SHE_DRAWING+SHEET.dgn,Design Model;18,SHE-04.SECOND.dgn,Design Model:261780
1C | L216017F (EN) - PartyWall :1 ,SHE_DRAWING+SHEET.dgn,Design Model;18,SHE-04.SECOND.dgn,Design Model:378082

# IfcWall: SHE_A-Walls_Type01d_Partywall_200mm_twin (23)
In: RL
Type - Description: SHE_A-Walls_Type01d_Partywall_200mm_twin
Type - Wall Parameters - Type: Wall; Compound Wall Assembly: yes
Type - Thermal Transmittance - Is External: no; Is Below Grade: no
Type - Space Bounding - Is Space Bounding: yes
Type - Materials - Part Definition: A-CompoundWalls::SHE_A-Walls_Type01d_Partywall_200mm_twin
Type - LEED Parameters - LEED | Pre-consumer Recycled (%): 0; LEED | Regional Material: no; LEED | Post-consumer Recycled (%): 0
Type - Identification - ID | Type ID: A216014 (EN); ID | Description: SHE_A-Walls_Type01d_Partywall_200mm_twin; ID | Notes: https://www.british-gypsu m.com/Specification/White-Book-Specification-Selector/internal-partitions-walls/gypwall-twin-frame-independent/a216014-en
Type - Fire Resistance - Fire | Rating: F90 (min. F60); Fire | IsCombustible: no; Fire | Compartmentation: no
Type - Discipline - Discipline: Architectural
Type - Construction Phase - Phase: New Construction
Type - Classification - Uniclass2015: EF_25_10
Type - Acoustical Parameters - Acoustic Rating (STC): 58 (min. 55)
Pset_WallCommon - AcousticRating: 58 (req. 55); Combustible: no; Compartmentation: no; FireRating: F90 (min. F60); IsExternal: no; LoadBearing: no
Identification - ID | Number: 1D; ID | Description: PartyWall; ID | Keynote: https://www.british-gyp sum.com/Specification/White-Book-Specification-Selector/internal-partitions-walls/gypwall-twin-frame-independent/a216014-en; ID | Notes: SHE_A-Walls_Type01d_Partywall_200mm_twin
Acoustical Parameters - Acoustic Rating (STC): 58 (req. 55)
Name | Description
1D | A216014 (EN) - PartyWall :1 ,SHE_DRAWING+SHEET.dgn,Design Model;7,SHE-06.FOURTH.dgn,Design Model:200870
1D | A216014 (EN) - PartyWall :1 ,SHE_DRAWING+SHEET.dgn,Design Model;7,SHE-06.FOURTH.dgn,Design Model:201195
1D | A216014 (EN) - PartyWall :1 ,SHE_DRAWING+SHEET.dgn,Design Model;7,SHE-06.FOURTH.dgn,Design Model:213592
1D | A216014 (EN) - PartyWall :1 ,SHE_DRAWING+SHEET.dgn,Design Model;7,SHE-06.FOURTH.dgn,Design Model:213656
1D | A216014 (EN) - PartyWall :1 ,SHE_DRAWING+SHEET.dgn,Design Model;7,SHE-06.FOURTH.dgn,Design Model:213720
1D | A216014 (EN) - PartyWall :1 ,SHE_DRAWING+SHEET.dgn,Design Model;7,SHE-06.FOURTH.dgn,Design Model:228670
1D | A216014 (EN) - PartyWall :1 ,SHE_DRAWING+SHEET.dgn,Design Model;7,SHE-06.FOURTH.dgn,Design Model:238168
1D | A216014 (EN) - PartyWall :1 ,SHE_DRAWING+SHEET.dgn,Design Model;7,SHE-06.FOURTH.dgn,Design Model:258699
1D | A216014 (EN) - PartyWall :1 ,SHE_DRAWING+SHEET.dgn,Design Model;7,SHE-06.FOURTH.dgn,Design Model:329798
1D | A216014 (EN) - PartyWall :1 ,SHE_DRAWING+SHEET.dgn,Design Model;7,SHE-06.FOURTH.dgn,Design Model:329967
1D | A216014 (EN) - PartyWall :1 ,SHE_DRAWING+SHEET.dgn,Design Model;7,SHE-06.FOURTH.dgn,Design Model:330218
1D | A216014 (EN) - PartyWall :1 ,SHE_DRAWING+SHEET.dgn,Design Model;7,SHE-06.FOURTH.dgn,Design Model:450240
1D | A216014 (EN) - PartyWall :1 ,SHE_DRAWING+SHEET.dgn,Design Model;7,SHE-06.FOURTH.dgn,Design Model:453325
1D | A216014 (EN) - PartyWall :1 ,SHE_DRAWING+SHEET.dgn,Design Model;7,SHE-06.FOURTH.dgn,Design Model:454108
1D | A216014 (EN) - PartyWall :1 ,SHE_DRAWING+SHEET.dgn,Design Model;7,SHE-06.FOURTH.dgn,Design Model:455433
1D | A216014 (EN) - PartyWall :1 ,SHE_DRAWING+SHEET.dgn,Design Model;7,SHE-06.FOURTH.dgn,Design Model:483168
1D | A216014 (EN) - PartyWall :1 ,SHE_DRAWING+SHEET.dgn,Design Model;8,SHE-07.FIFTH.dgn,Design Model:170079
1D | A216014 (EN) - PartyWall :1 ,SHE_DRAWING+SHEET.dgn,Design Model;8,SHE-07.FIFTH.dgn,Design Model:301138
1D | A216014 (EN) - PartyWall :1 ,SHE_DRAWING+SHEET.dgn,Design Model;8,SHE-07.FIFTH.dgn,Design Model:304604
1D | A216014 (EN) - PartyWall :1 ,SHE_DRAWING+SHEET.dgn,Design Model;8,SHE-07.FIFTH.dgn,Design Model:304668
1D | A216014 (EN) - PartyWall :1 ,SHE_DRAWING+SHEET.dgn,Design Model;8,SHE-07.FIFTH.dgn,Design Model:305057
1D | A216014 (EN) - PartyWall :1 ,SHE_DRAWING+SHEET.dgn,Design Model;8,SHE-07.FIFTH.dgn,Design Model:305831
1D | A216014 (EN) - PartyWall :1 ,SHE_DRAWING+SHEET.dgn,Design Model;8,SHE-07.FIFTH.dgn,Design Model:306404

# IfcWall: SHE_A-Walls_Type02b_LiftShaftWall_173mm, 2B
In: RL
Type - Description: SHE_A-Walls_Type02b_LiftShaftWall_173mm
Type - Wall Parameters - Type: Wall; Compound Wall Assembly: yes
Type - Thermal Transmittance - Is External: no; Is Below Grade: no
Type - Space Bounding - Is Space Bounding: yes
Type - Materials - Part Definition: A-CompoundWalls::SHE_A-Walls_Type02b_LiftShaftWall_173mm
Type - LEED Parameters - LEED | Pre-consumer Recycled (%): 0; LEED | Regional Material: no; LEED | Post-consumer Recycled (%): 0
Type - Identification - ID | Type ID: A306020 (A) (EN); ID | Description: SHE_A-Walls_Type02b_LiftShaftWall_173mm; ID | Notes: https://www.british-gypsu m.com/Specification/White-Book-Specification-Selector/shaftwall/gypwall-shaft/a306020-a-en #0description
Type - Fire Resistance - Fire | Rating: F60; Fire | IsCombustible: no; Fire | Compartmentation: no
Type - Discipline - Discipline: Architectural
Type - Construction Phase - Phase: New Construction
Type - Classification - Uniclass2015: EF_25_10
Type - Acoustical Parameters - Acoustic Rating (STC): 52 (min. 52)
Description: A306020 (A) (EN ) - LiftShaftWall :1,SHE_DRAWING+SHEET.dgn,Design Model;7,SHE-06.FOURTH.dgn ,Design Model:473824
Pset_WallCommon - AcousticRating: 52 (min. 52); Combustible: no; Compartmentation: no; FireRating: F60; IsExternal: no; LoadBearing: no
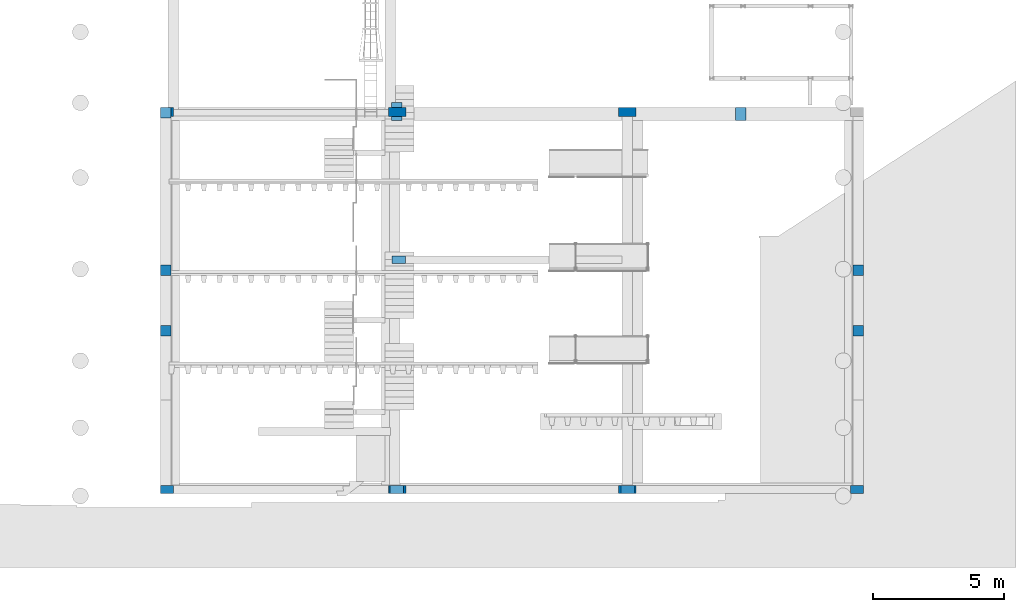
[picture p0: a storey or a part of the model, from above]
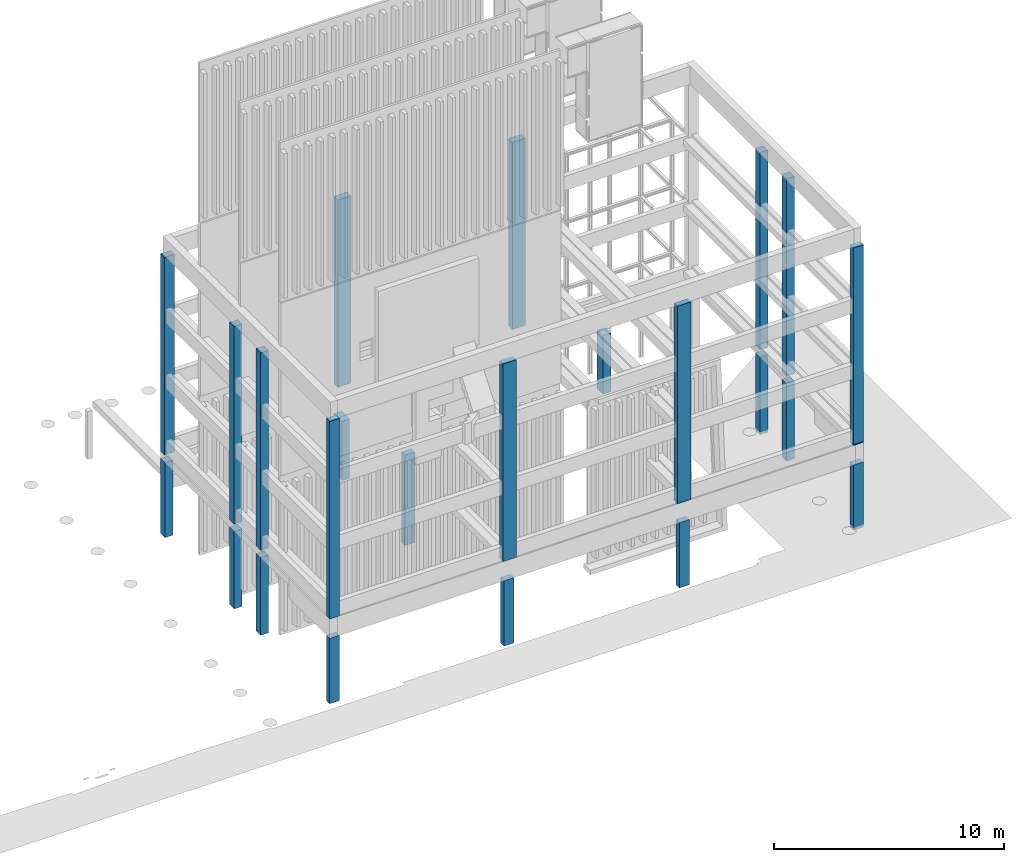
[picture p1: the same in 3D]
Properties of the parts of a building model (IFC2X3), part 14 of 16

# IfcWall: SHE_A-Walls_Type02b_LiftShaftWall_173mm, 2B
Identification - ID | Number: 2B; ID | Description: LiftShaftWall; ID | Keynote: https://www.british-gyp sum.com/Specification/White-Book-Specification-Selector/shaftwall/gypwall-shaft/a306020-a-en #0description; ID | Notes: SHE_A-Walls_Type02b_LiftShaftWall_173mm

# IfcWall: SHE_A-Walls_Type02c_LiftShaftWall_193mm (4)
In: RL
Type - Description: SHE_A-Walls_Type02c_LiftShaftWall_193mm
Type - Wall Parameters - Type: Wall; Compound Wall Assembly: yes
Type - Thermal Transmittance - Is External: no; Is Below Grade: no
Type - Space Bounding - Is Space Bounding: yes
Type - Materials - Part Definition: A-CompoundWalls::SHE_A-Walls_Type02c_LiftShaftWall_193mm
Type - LEED Parameters - LEED | Pre-consumer Recycled (%): 0; LEED | Regional Material: no; LEED | Post-consumer Recycled (%): 0
Type - Identification - ID | Type ID: A306033 (A) (EN); ID | Description: SHE_A-Walls_Type02c_LiftShaftWall_193mm; ID | Notes: https://www.british-gypsu m.com/Specification/White-Book-Specification-Selector/shaftwall/gypwall-shaft/a306033-a-en
Type - Fire Resistance - Fire | Rating: FD120; Fire | IsCombustible: no; Fire | Compartmentation: no
Type - Discipline - Discipline: Architectural
Type - Construction Phase - Phase: New Construction
Type - Classification - Uniclass2015: EF_25_10
Type - Acoustical Parameters - Acoustic Rating (STC): 50 (min. 52)
Pset_WallCommon - AcousticRating: 50 (min. 52); Combustible: no; Compartmentation: no; FireRating: F120; IsExternal: no; LoadBearing: no
Identification - ID | Number: 2C; ID | Description: LiftShaftWall; ID | Keynote: https://www.british-gyp sum.com/Specification/White-Book-Specification-Selector/shaftwall/gypwall-shaft/a306020-a-en #0description; ID | Notes: SHE_A-Walls_Type02c_LiftShaftWall_193mm
Fire Resistance - Fire | Rating: F120
Name | Description
2C | A306033 (A) (EN ) - LiftShaftWall :1,SHE_DRAWING+SHEET.dgn,Design Model;8,SHE-07.FIFTH.dgn ,Design Model:312602
2C | A306033 (A) (EN ) - LiftShaftWall :1,SHE_DRAWING+SHEET.dgn,Design Model;8,SHE-07.FIFTH.dgn ,Design Model:312684
2C | A306033 (A) (EN ) - LiftShaftWall :1,SHE_DRAWING+SHEET.dgn,Design Model;8,SHE-07.FIFTH.dgn ,Design Model:312739
2C | A306033 (A) (EN ) - LiftShaftWall :1,SHE_DRAWING+SHEET.dgn,Design Model;8,SHE-07.FIFTH.dgn ,Design Model:313312

# IfcWall: SHE_A-Walls_Type03a_BlockworkWall_170mm (18)
In: RL
Type - Description: SHE_A-Walls_Type03a_BlockworkWall_170mm
Type - Wall Parameters - Type: Wall; Compound Wall Assembly: yes
Type - Thermal Transmittance - Is External: no; Is Below Grade: no
Type - Space Bounding - Is Space Bounding: yes
Type - Materials - Part Definition: A-CompoundWalls::SHE_A-Walls_Type03a_BlockworkWall_170mm
Type - LEED Parameters - LEED | Pre-consumer Recycled (%): 0; LEED | Regional Material: no; LEED | Post-consumer Recycled (%): 0
Type - Identification - ID | Description: SHE_A-Walls_Type03a_BlockworkWall_170mm
Type - Fire Resistance - Fire | IsCombustible: no; Fire | Compartmentation: no
Type - Discipline - Discipline: Architectural
Type - Construction Phase - Phase: Existing to Remain
Type - Classification - Uniclass2015: EF_25_10
Type - Acoustical Parameters - Acoustic Rating (STC): (min.53)
Pset_WallCommon - Combustible: no; Compartmentation: no; FireRating: F120; IsExternal: no; LoadBearing: no
Identification - ID | Number: 4B; ID | Description: CoreWall existing; ID | Notes: SHE_A-Walls_Type03a_BlockworkWall_170mm
Fire Resistance - Fire | Rating: F120
Name | Description | AcousticRating = Acoustic Rating (STC)
4B | CoreWall existing :1 ,SHE_DRAWING+SHEET.dgn,Design Model;4,SHE-03.FIRST.dgn,Design Model:139322 | (req.53)
4B | CoreWall existing :1 ,SHE_DRAWING+SHEET.dgn,Design Model;4,SHE-03.FIRST.dgn,Design Model:139746 | (req.53)
4B | CoreWall existing :1 ,SHE_DRAWING+SHEET.dgn,Design Model;4,SHE-03.FIRST.dgn,Design Model:143193 | (req.53)
4B | CoreWall existing :1 ,SHE_DRAWING+SHEET.dgn,Design Model;4,SHE-03.FIRST.dgn,Design Model:230556 | (req.53)
4B | CoreWall existing :1 ,SHE_DRAWING+SHEET.dgn,Design Model;4,SHE-03.FIRST.dgn,Design Model:303433 | (req.53)
4B | CoreWall existing :1 ,SHE_DRAWING+SHEET.dgn,Design Model;6,SHE-05.THIRD.dgn,Design Model:139322 | (req.53)
4B | CoreWall existing :1 ,SHE_DRAWING+SHEET.dgn,Design Model;6,SHE-05.THIRD.dgn,Design Model:139746 | (req.53)
4B | CoreWall existing :1 ,SHE_DRAWING+SHEET.dgn,Design Model;6,SHE-05.THIRD.dgn,Design Model:143193 | (req.53)
4B | CoreWall existing :1 ,SHE_DRAWING+SHEET.dgn,Design Model;6,SHE-05.THIRD.dgn,Design Model:230556 | (req.53)
4B | CoreWall existing :1 ,SHE_DRAWING+SHEET.dgn,Design Model;6,SHE-05.THIRD.dgn,Design Model:303433 | (req.53)
4B | CoreWall existing :1 ,SHE_DRAWING+SHEET.dgn,Design Model;7,SHE-06.FOURTH.dgn,Design Model:191045 | (req.55)
4B | CoreWall existing :1 ,SHE_DRAWING+SHEET.dgn,Design Model;7,SHE-06.FOURTH.dgn,Design Model:191469 | (req.55)
4B | CoreWall existing :1 ,SHE_DRAWING+SHEET.dgn,Design Model;7,SHE-06.FOURTH.dgn,Design Model:483583 | (min.55)
4B | CoreWall existing :1 ,SHE_DRAWING+SHEET.dgn,Design Model;18,SHE-04.SECOND.dgn,Design Model:139322 | (req.53)
4B | CoreWall existing :1 ,SHE_DRAWING+SHEET.dgn,Design Model;18,SHE-04.SECOND.dgn,Design Model:139746 | (req.53)
4B | CoreWall existing :1 ,SHE_DRAWING+SHEET.dgn,Design Model;18,SHE-04.SECOND.dgn,Design Model:143193 | (req.53)
4B | CoreWall existing :1 ,SHE_DRAWING+SHEET.dgn,Design Model;18,SHE-04.SECOND.dgn,Design Model:230556 | (req.53)
4B | CoreWall existing :1 ,SHE_DRAWING+SHEET.dgn,Design Model;18,SHE-04.SECOND.dgn,Design Model:303433 | (req.53)

# IfcWall: SHE_A-Walls_Type03b_Firewall_200mm_twin (4)
In: RL
Type - Description: SHE_A-Walls_Type03b_Firewall_200mm_twin
Type - Wall Parameters - Type: Wall; Compound Wall Assembly: yes
Type - Thermal Transmittance - Is External: no; Is Below Grade: no
Type - Space Bounding - Is Space Bounding: yes
Type - Materials - Part Definition: A-CompoundWalls::SHE_A-Walls_Type03b_Firewall_200mm_twin
Type - LEED Parameters - LEED | Pre-consumer Recycled (%): 0; LEED | Regional Material: no; LEED | Post-consumer Recycled (%): 0
Type - Identification - ID | Type ID: X216011 (EN); ID | Description: SHE_A-Walls_Type03b_Firewall_200mm_twin; ID | Notes: https://www.british-gypsu m.com/Specification/White-Book-Specification-Selector/internal-partitions-walls/gypwall-twin-frame-independent/x216011-en
Type - Fire Resistance - Fire | Rating: F120; Fire | IsCombustible: no; Fire | Compartmentation: no
Type - Discipline - Discipline: Architectural
Type - Construction Phase - Phase: New Construction
Type - Classification - Uniclass2015: EF_25_10
Type - Acoustical Parameters - Acoustic Rating (STC): 58 dB (min. 55 Rw+Ctr)
Pset_WallCommon - AcousticRating: 58dB (req. 55); Combustible: no; Compartmentation: no; FireRating: F120; IsExternal: no; LoadBearing: no
Identification - ID | Number: 3B; ID | Description: StairFireWall; ID | Notes: SHE_A-Walls_Type03b_Firewall_200mm_twin
Acoustical Parameters - Acoustic Rating (STC): 58dB (req. 55 )
Name | Description | ID | Keynote
3B | X216011 (EN ) - StairFireWall :1,SHE_DRAWING+SHEET.dgn,Design Model;7,SHE-06.FOURTH.dgn ,Design Model:453738 | https://www.british-gyp sum.com/Specification/White-Book-Specification-Selector/internal-partitions-walls/gypwall-twin-frame-independent/x216011-en
3B | X216011 (EN ) - StairFireWall :1,SHE_DRAWING+SHEET.dgn,Design Model;8,SHE-07.FIFTH.dgn ,Design Model:304928 | https://www.british-gyp sum.com/Specification/White-Book-Specification-Selector/internal-partitions-walls/gypwall-twin-frame-independent/a216014-en
3B | X216011 (EN ) - StairFireWall :1,SHE_DRAWING+SHEET.dgn,Design Model;8,SHE-07.FIFTH.dgn ,Design Model:310293 | https://www.british-gyp sum.com/Specification/White-Book-Specification-Selector/internal-partitions-walls/gypwall-twin-frame-independent/a216014-en
3B | X216011 (EN ) - StairFireWall :1,SHE_DRAWING+SHEET.dgn,Design Model;8,SHE-07.FIFTH.dgn ,Design Model:311878 | https://www.british-gyp sum.com/Specification/White-Book-Specification-Selector/internal-partitions-walls/gypwall-twin-frame-independent/a216014-en

# IfcWall: SHE_A-Walls_Type03c_Firewall_F120_100mm (5)
In: RL
Type - Description: SHE_A-Walls_Type03c_Firewall_F120_100mm
Type - Wall Parameters - Type: Wall; Compound Wall Assembly: yes
Type - Thermal Transmittance - Is External: no; Is Below Grade: no
Type - Space Bounding - Is Space Bounding: yes
Type - Materials - Part Definition: A-CompoundWalls::SHE_A-Walls_Type03c_Firewall_F120_100mm
Type - LEED Parameters - LEED | Pre-consumer Recycled (%): 0; LEED | Regional Material: no; LEED | Post-consumer Recycled (%): 0
Type - Identification - ID | Type ID: A206067A (EN); ID | Description: SHE_A-Walls_Type03c_Firewall_F120_100mm; ID | Notes: https://www.british-gypsu m.com/Specification/White-Book-Specification-Selector/internal-partitions-walls/gypwall-single-frame/a206067a-en
Type - Fire Resistance - Fire | Rating: F120; Fire | IsCombustible: no; Fire | Compartmentation: no
Type - Discipline - Discipline: Architectural
Type - Classification - Uniclass2015: EF_25_10
Type - Acoustical Parameters - Acoustic Rating (STC): 42 (Rw)
Pset_WallCommon - Combustible: no; Compartmentation: no; FireRating: F120; IsExternal: no; LoadBearing: no
Identification - ID | Number: 3C; ID | Description: StairFireWall; ID | Keynote: https://www.british-gyp sum.com/Specification/White-Book-Specification-Selector/internal-partitions-walls/gypwall-single-frame/a206067a-en; ID | Notes: SHE_A-Walls_Type03c_Firewall_F120_100mm
Construction Phase - Phase: New Construction
Name | Description | AcousticRating
3C | A206067A (EN ) - StairFireWall :1,SHE_DRAWING+SHEET.dgn,Design Model;4,SHE-03.FIRST.dgn ,Design Model:349110 | 42 (Rw)
3C | A206067A (EN ) - StairFireWall :1,SHE_DRAWING+SHEET.dgn,Design Model;6,SHE-05.THIRD.dgn ,Design Model:401692 | 42 (Rw)
3C | A206067A (EN ) - StairFireWall :1,SHE_DRAWING+SHEET.dgn,Design Model;7,SHE-06.FOURTH.dgn ,Design Model:396553 | 42 (Rw)
3C | A206067A (EN ) - StairFireWall :1,SHE_DRAWING+SHEET.dgn,Design Model;7,SHE-06.FOURTH.dgn ,Design Model:451300 | 58 (req. 55) | Acoustical Parameters - Acoustic Rating (STC): 58 (req. 55)
3C | A206067A (EN ) - StairFireWall :1,SHE_DRAWING+SHEET.dgn,Design Model;18,SHE-04.SECOND.dgn ,Design Model:356913 | 42 (Rw)

# IfcWall: SHE_A-Walls_Type04a_BlockworkWall_130mm (6)
In: RL
Type - Description: SHE_A-Walls_Type04a_BlockworkWall_130mm
Type - Wall Parameters - Type: Wall; Compound Wall Assembly: yes
Type - Thermal Transmittance - Is External: no; Is Below Grade: no
Type - Space Bounding - Is Space Bounding: yes
Type - Materials - Part Definition: A-CompoundWalls::SHE_A-Walls_Type04a_BlockworkWall_130mm
Type - LEED Parameters - LEED | Pre-consumer Recycled (%): 0; LEED | Regional Material: no; LEED | Post-consumer Recycled (%): 0
Type - Identification - ID | Description: SHE_A-Walls_Type04a_BlockworkWall_130mm
Type - Fire Resistance - Fire | IsCombustible: no; Fire | Compartmentation: no
Type - Discipline - Discipline: Architectural
Type - Construction Phase - Phase: Existing to Remain
Type - Classification - Uniclass2015: EF_25_10
Type - Acoustical Parameters - Acoustic Rating (STC): (min.53)
Pset_WallCommon - AcousticRating: (req.53); Combustible: no; Compartmentation: no; FireRating: F120; IsExternal: no; LoadBearing: no
Identification - ID | Number: 4A; ID | Description: CoreWall existing; ID | Notes: SHE_A-Walls_Type04a_BlockworkWall_130mm
Fire Resistance - Fire | Rating: F120
Acoustical Parameters - Acoustic Rating (STC): (req.53)
Name | Description
4A | CoreWall existing :1 ,SHE_DRAWING+SHEET.dgn,Design Model;4,SHE-03.FIRST.dgn,Design Model:139323
4A | CoreWall existing :1 ,SHE_DRAWING+SHEET.dgn,Design Model;4,SHE-03.FIRST.dgn,Design Model:143192
4A | CoreWall existing :1 ,SHE_DRAWING+SHEET.dgn,Design Model;6,SHE-05.THIRD.dgn,Design Model:139323
4A | CoreWall existing :1 ,SHE_DRAWING+SHEET.dgn,Design Model;6,SHE-05.THIRD.dgn,Design Model:143192
4A | CoreWall existing :1 ,SHE_DRAWING+SHEET.dgn,Design Model;18,SHE-04.SECOND.dgn,Design Model:139323
4A | CoreWall existing :1 ,SHE_DRAWING+SHEET.dgn,Design Model;18,SHE-04.SECOND.dgn,Design Model:143192

# IfcWall: SHE_A-Walls_Type04c_RiserWall_102mm_tall (9)
In: RL
Type - Description: SHE_A-Walls_Type04c_RiserWall_102mm_tall
Type - Wall Parameters - Type: Wall; Compound Wall Assembly: yes
Type - Thermal Transmittance - Is External: no; Is Below Grade: no
Type - Space Bounding - Is Space Bounding: yes
Type - Materials - Part Definition: A-CompoundWalls::SHE_A-Walls_Type04c_RiserWall_102mm_tall
Type - LEED Parameters - LEED | Pre-consumer Recycled (%): 0; LEED | Regional Material: no; LEED | Post-consumer Recycled (%): 0
Type - Identification - ID | Type ID: A206078 (EN); ID | Description: SHE_A-Walls_Type04c_RiserWall_102mm_tall; ID | Notes: https://www.british-gypsu m.com/Specification/White-Book-Specification-Selector/internal-partitions-walls/gypwall-single-frame/a206078-en
Type - Fire Resistance - Fire | Rating: F60; Fire | IsCombustible: no; Fire | Compartmentation: no
Type - Discipline - Discipline: Architectural
Type - Construction Phase - Phase: New Construction
Type - Classification - Uniclass2015: EF_25_10
Type - Acoustical Parameters - Acoustic Rating (STC): 37 (min. tbc )
Pset_WallCommon - AcousticRating: 37 (req. tbc); Combustible: no; Compartmentation: no; FireRating: F60; IsExternal: no; LoadBearing: no
Identification - ID | Number: 4C; ID | Description: RiserWall; ID | Keynote: https://www.british-gyp sum.com/Specification/White-Book-Specification-Selector/internal-partitions-walls/gypwall-single-frame/a206078-en; ID | Notes: SHE_A-Walls_Type04c_RiserWall_102mm_tall
Acoustical Parameters - Acoustic Rating (STC): 37 (req. tbc )
Name | Description
4C | A206078 (EN) - RiserWall :1 ,SHE_DRAWING+SHEET.dgn,Design Model;4,SHE-03.FIRST.dgn,Design Model:162958
4C | A206078 (EN) - RiserWall :1 ,SHE_DRAWING+SHEET.dgn,Design Model;4,SHE-03.FIRST.dgn,Design Model:162987
4C | A206078 (EN) - RiserWall :1 ,SHE_DRAWING+SHEET.dgn,Design Model;4,SHE-03.FIRST.dgn,Design Model:163015
4C | A206078 (EN) - RiserWall :1 ,SHE_DRAWING+SHEET.dgn,Design Model;6,SHE-05.THIRD.dgn,Design Model:162958
4C | A206078 (EN) - RiserWall :1 ,SHE_DRAWING+SHEET.dgn,Design Model;6,SHE-05.THIRD.dgn,Design Model:162987
4C | A206078 (EN) - RiserWall :1 ,SHE_DRAWING+SHEET.dgn,Design Model;6,SHE-05.THIRD.dgn,Design Model:163015
4C | A206078 (EN) - RiserWall :1 ,SHE_DRAWING+SHEET.dgn,Design Model;18,SHE-04.SECOND.dgn,Design Model:162958
4C | A206078 (EN) - RiserWall :1 ,SHE_DRAWING+SHEET.dgn,Design Model;18,SHE-04.SECOND.dgn,Design Model:162987
4C | A206078 (EN) - RiserWall :1 ,SHE_DRAWING+SHEET.dgn,Design Model;18,SHE-04.SECOND.dgn,Design Model:163015

# IfcWall: SHE_A-Walls_Type05a_Partition_95mm_tall (132)
In: RL
Type - Description: SHE_A-Walls_Type05a_Partition_95mm_tall
Type - Wall Parameters - Type: Wall; Compound Wall Assembly: yes
Type - Thermal Transmittance - Is External: no; Is Below Grade: no
Type - Space Bounding - Is Space Bounding: yes
Type - Materials - Part Definition: A-CompoundWalls::SHE_A-Walls_Type05a_Partition_95mm_tall
Type - LEED Parameters - LEED | Pre-consumer Recycled (%): 0; LEED | Regional Material: no; LEED | Post-consumer Recycled (%): 0
Type - Identification - ID | Type ID: A206045 (EN); ID | Description: SHE_A-Walls_Type05a_Partition_95mm_tall; ID | Notes: https://www.british-gypsu m.com/Specification/White-Book-Specification-Selector/internal-partitions-walls/gypwall-single-frame/A206045-en
Type - Fire Resistance - Fire | Rating: F30; Fire | IsCombustible: no; Fire | Compartmentation: no
Type - Discipline - Discipline: Architectural
Type - Classification - Uniclass2015: EF_25_10
Type - Acoustical Parameters - Acoustic Rating (STC): 42 (min. 40)
Pset_WallCommon - AcousticRating: 42 (req. 40); Combustible: no; Compartmentation: no; FireRating: F30; IsExternal: no; LoadBearing: no
Identification - ID | Number: 5A; ID | Description: Partition; ID | Keynote: https://www.british-gyp sum.com/Specification/White-Book-Specification-Selector/internal-partitions-walls/gypwall-single-frame/A206045-en; ID | Notes: SHE_A-Walls_Type05a_Partition_95mm_tall
Construction Phase - Phase: New Construction
Acoustical Parameters - Acoustic Rating (STC): 42 (req. 40)
Name | Description
5A | A206045 (EN) - Partition :1 ,SHE_DRAWING+SHEET.dgn,Design Model;4,SHE-03.FIRST.dgn,Design Model:142264
5A | A206045 (EN) - Partition :1 ,SHE_DRAWING+SHEET.dgn,Design Model;4,SHE-03.FIRST.dgn,Design Model:142271
5A | A206045 (EN) - Partition :1 ,SHE_DRAWING+SHEET.dgn,Design Model;4,SHE-03.FIRST.dgn,Design Model:142272
5A | A206045 (EN) - Partition :1 ,SHE_DRAWING+SHEET.dgn,Design Model;4,SHE-03.FIRST.dgn,Design Model:142274
5A | A206045 (EN) - Partition :1 ,SHE_DRAWING+SHEET.dgn,Design Model;4,SHE-03.FIRST.dgn,Design Model:142275
5A | A206045 (EN) - Partition :1 ,SHE_DRAWING+SHEET.dgn,Design Model;4,SHE-03.FIRST.dgn,Design Model:142806
5A | A206045 (EN) - Partition :1 ,SHE_DRAWING+SHEET.dgn,Design Model;4,SHE-03.FIRST.dgn,Design Model:142807
5A | A206045 (EN) - Partition :1 ,SHE_DRAWING+SHEET.dgn,Design Model;4,SHE-03.FIRST.dgn,Design Model:142813
5A | A206045 (EN) - Partition :1 ,SHE_DRAWING+SHEET.dgn,Design Model;4,SHE-03.FIRST.dgn,Design Model:142814
5A | A206045 (EN) - Partition :1 ,SHE_DRAWING+SHEET.dgn,Design Model;4,SHE-03.FIRST.dgn,Design Model:147005
5A | A206045 (EN) - Partition :1 ,SHE_DRAWING+SHEET.dgn,Design Model;4,SHE-03.FIRST.dgn,Design Model:147006
5A | A206045 (EN) - Partition :1 ,SHE_DRAWING+SHEET.dgn,Design Model;4,SHE-03.FIRST.dgn,Design Model:172228
5A | A206045 (EN) - Partition :1 ,SHE_DRAWING+SHEET.dgn,Design Model;4,SHE-03.FIRST.dgn,Design Model:172449
5A | A206045 (EN) - Partition :1 ,SHE_DRAWING+SHEET.dgn,Design Model;4,SHE-03.FIRST.dgn,Design Model:173632
5A | A206045 (EN) - Partition :1 ,SHE_DRAWING+SHEET.dgn,Design Model;4,SHE-03.FIRST.dgn,Design Model:230031
5A | A206045 (EN) - Partition :1 ,SHE_DRAWING+SHEET.dgn,Design Model;4,SHE-03.FIRST.dgn,Design Model:230345
5A | A206045 (EN) - Partition :1 ,SHE_DRAWING+SHEET.dgn,Design Model;4,SHE-03.FIRST.dgn,Design Model:230391
5A | A206045 (EN) - Partition :1 ,SHE_DRAWING+SHEET.dgn,Design Model;4,SHE-03.FIRST.dgn,Design Model:230437
5A | A206045 (EN) - Partition :1 ,SHE_DRAWING+SHEET.dgn,Design Model;4,SHE-03.FIRST.dgn,Design Model:231743
5A | A206045 (EN) - Partition :1 ,SHE_DRAWING+SHEET.dgn,Design Model;4,SHE-03.FIRST.dgn,Design Model:269095
5A | A206045 (EN) - Partition :1 ,SHE_DRAWING+SHEET.dgn,Design Model;4,SHE-03.FIRST.dgn,Design Model:269141
5A | A206045 (EN) - Partition :1 ,SHE_DRAWING+SHEET.dgn,Design Model;4,SHE-03.FIRST.dgn,Design Model:271053
5A | A206045 (EN) - Partition :1 ,SHE_DRAWING+SHEET.dgn,Design Model;4,SHE-03.FIRST.dgn,Design Model:272162
5A | A206045 (EN) - Partition :1 ,SHE_DRAWING+SHEET.dgn,Design Model;4,SHE-03.FIRST.dgn,Design Model:273961
5A | A206045 (EN) - Partition :1 ,SHE_DRAWING+SHEET.dgn,Design Model;4,SHE-03.FIRST.dgn,Design Model:274457
5A | A206045 (EN) - Partition :1 ,SHE_DRAWING+SHEET.dgn,Design Model;4,SHE-03.FIRST.dgn,Design Model:278735
5A | A206045 (EN) - Partition :1 ,SHE_DRAWING+SHEET.dgn,Design Model;4,SHE-03.FIRST.dgn,Design Model:278736
5A | A206045 (EN) - Partition :1 ,SHE_DRAWING+SHEET.dgn,Design Model;4,SHE-03.FIRST.dgn,Design Model:289175
5A | A206045 (EN) - Partition :1 ,SHE_DRAWING+SHEET.dgn,Design Model;4,SHE-03.FIRST.dgn,Design Model:290266
5A | A206045 (EN) - Partition :1 ,SHE_DRAWING+SHEET.dgn,Design Model;4,SHE-03.FIRST.dgn,Design Model:291273
5A | A206045 (EN) - Partition :1 ,SHE_DRAWING+SHEET.dgn,Design Model;4,SHE-03.FIRST.dgn,Design Model:297916
5A | A206045 (EN) - Partition :1 ,SHE_DRAWING+SHEET.dgn,Design Model;4,SHE-03.FIRST.dgn,Design Model:300531
5A | A206045 (EN) - Partition :1 ,SHE_DRAWING+SHEET.dgn,Design Model;4,SHE-03.FIRST.dgn,Design Model:300532
5A | A206045 (EN) - Partition :1 ,SHE_DRAWING+SHEET.dgn,Design Model;4,SHE-03.FIRST.dgn,Design Model:300570
5A | A206045 (EN) - Partition :1 ,SHE_DRAWING+SHEET.dgn,Design Model;4,SHE-03.FIRST.dgn,Design Model:304357
5A | A206045 (EN) - Partition :1 ,SHE_DRAWING+SHEET.dgn,Design Model;4,SHE-03.FIRST.dgn,Design Model:304647
5A | A206045 (EN) - Partition :1 ,SHE_DRAWING+SHEET.dgn,Design Model;4,SHE-03.FIRST.dgn,Design Model:332442
5A | A206045 (EN) - Partition :1 ,SHE_DRAWING+SHEET.dgn,Design Model;4,SHE-03.FIRST.dgn,Design Model:332488
5A | A206045 (EN) - Partition :1 ,SHE_DRAWING+SHEET.dgn,Design Model;4,SHE-03.FIRST.dgn,Design Model:354651
5A | A206045 (EN) - Partition :1 ,SHE_DRAWING+SHEET.dgn,Design Model;4,SHE-03.FIRST.dgn,Design Model:355951
5A | A206045 (EN) - Partition :1 ,SHE_DRAWING+SHEET.dgn,Design Model;4,SHE-03.FIRST.dgn,Design Model:362997
5A | A206045 (EN) - Partition :1 ,SHE_DRAWING+SHEET.dgn,Design Model;4,SHE-03.FIRST.dgn,Design Model:366252
5A | A206045 (EN) - Partition :1 ,SHE_DRAWING+SHEET.dgn,Design Model;4,SHE-03.FIRST.dgn,Design Model:374761
5A | A206045 (EN) - Partition :1 ,SHE_DRAWING+SHEET.dgn,Design Model;4,SHE-03.FIRST.dgn,Design Model:379423
5A | A206045 (EN) - Partition :1 ,SHE_DRAWING+SHEET.dgn,Design Model;6,SHE-05.THIRD.dgn,Design Model:142264
5A | A206045 (EN) - Partition :1 ,SHE_DRAWING+SHEET.dgn,Design Model;6,SHE-05.THIRD.dgn,Design Model:142271
5A | A206045 (EN) - Partition :1 ,SHE_DRAWING+SHEET.dgn,Design Model;6,SHE-05.THIRD.dgn,Design Model:142272
5A | A206045 (EN) - Partition :1 ,SHE_DRAWING+SHEET.dgn,Design Model;6,SHE-05.THIRD.dgn,Design Model:142274
5A | A206045 (EN) - Partition :1 ,SHE_DRAWING+SHEET.dgn,Design Model;6,SHE-05.THIRD.dgn,Design Model:142275
5A | A206045 (EN) - Partition :1 ,SHE_DRAWING+SHEET.dgn,Design Model;6,SHE-05.THIRD.dgn,Design Model:142804
5A | A206045 (EN) - Partition :1 ,SHE_DRAWING+SHEET.dgn,Design Model;6,SHE-05.THIRD.dgn,Design Model:142805
5A | A206045 (EN) - Partition :1 ,SHE_DRAWING+SHEET.dgn,Design Model;6,SHE-05.THIRD.dgn,Design Model:142806
5A | A206045 (EN) - Partition :1 ,SHE_DRAWING+SHEET.dgn,Design Model;6,SHE-05.THIRD.dgn,Design Model:142807
5A | A206045 (EN) - Partition :1 ,SHE_DRAWING+SHEET.dgn,Design Model;6,SHE-05.THIRD.dgn,Design Model:142813
5A | A206045 (EN) - Partition :1 ,SHE_DRAWING+SHEET.dgn,Design Model;6,SHE-05.THIRD.dgn,Design Model:142814
5A | A206045 (EN) - Partition :1 ,SHE_DRAWING+SHEET.dgn,Design Model;6,SHE-05.THIRD.dgn,Design Model:147005
5A | A206045 (EN) - Partition :1 ,SHE_DRAWING+SHEET.dgn,Design Model;6,SHE-05.THIRD.dgn,Design Model:147006
5A | A206045 (EN) - Partition :1 ,SHE_DRAWING+SHEET.dgn,Design Model;6,SHE-05.THIRD.dgn,Design Model:172228
5A | A206045 (EN) - Partition :1 ,SHE_DRAWING+SHEET.dgn,Design Model;6,SHE-05.THIRD.dgn,Design Model:172449
5A | A206045 (EN) - Partition :1 ,SHE_DRAWING+SHEET.dgn,Design Model;6,SHE-05.THIRD.dgn,Design Model:173632
5A | A206045 (EN) - Partition :1 ,SHE_DRAWING+SHEET.dgn,Design Model;6,SHE-05.THIRD.dgn,Design Model:230031
5A | A206045 (EN) - Partition :1 ,SHE_DRAWING+SHEET.dgn,Design Model;6,SHE-05.THIRD.dgn,Design Model:230345
5A | A206045 (EN) - Partition :1 ,SHE_DRAWING+SHEET.dgn,Design Model;6,SHE-05.THIRD.dgn,Design Model:230391
5A | A206045 (EN) - Partition :1 ,SHE_DRAWING+SHEET.dgn,Design Model;6,SHE-05.THIRD.dgn,Design Model:230437
5A | A206045 (EN) - Partition :1 ,SHE_DRAWING+SHEET.dgn,Design Model;6,SHE-05.THIRD.dgn,Design Model:231743
5A | A206045 (EN) - Partition :1 ,SHE_DRAWING+SHEET.dgn,Design Model;6,SHE-05.THIRD.dgn,Design Model:253334
5A | A206045 (EN) - Partition :1 ,SHE_DRAWING+SHEET.dgn,Design Model;6,SHE-05.THIRD.dgn,Design Model:269095
5A | A206045 (EN) - Partition :1 ,SHE_DRAWING+SHEET.dgn,Design Model;6,SHE-05.THIRD.dgn,Design Model:269141
5A | A206045 (EN) - Partition :1 ,SHE_DRAWING+SHEET.dgn,Design Model;6,SHE-05.THIRD.dgn,Design Model:271053
5A | A206045 (EN) - Partition :1 ,SHE_DRAWING+SHEET.dgn,Design Model;6,SHE-05.THIRD.dgn,Design Model:272162
5A | A206045 (EN) - Partition :1 ,SHE_DRAWING+SHEET.dgn,Design Model;6,SHE-05.THIRD.dgn,Design Model:273961
5A | A206045 (EN) - Partition :1 ,SHE_DRAWING+SHEET.dgn,Design Model;6,SHE-05.THIRD.dgn,Design Model:274457
5A | A206045 (EN) - Partition :1 ,SHE_DRAWING+SHEET.dgn,Design Model;6,SHE-05.THIRD.dgn,Design Model:278735
5A | A206045 (EN) - Partition :1 ,SHE_DRAWING+SHEET.dgn,Design Model;6,SHE-05.THIRD.dgn,Design Model:278736
5A | A206045 (EN) - Partition :1 ,SHE_DRAWING+SHEET.dgn,Design Model;6,SHE-05.THIRD.dgn,Design Model:289175
5A | A206045 (EN) - Partition :1 ,SHE_DRAWING+SHEET.dgn,Design Model;6,SHE-05.THIRD.dgn,Design Model:290266
5A | A206045 (EN) - Partition :1 ,SHE_DRAWING+SHEET.dgn,Design Model;6,SHE-05.THIRD.dgn,Design Model:291273
5A | A206045 (EN) - Partition :1 ,SHE_DRAWING+SHEET.dgn,Design Model;6,SHE-05.THIRD.dgn,Design Model:297916
5A | A206045 (EN) - Partition :1 ,SHE_DRAWING+SHEET.dgn,Design Model;6,SHE-05.THIRD.dgn,Design Model:300531
5A | A206045 (EN) - Partition :1 ,SHE_DRAWING+SHEET.dgn,Design Model;6,SHE-05.THIRD.dgn,Design Model:300532
5A | A206045 (EN) - Partition :1 ,SHE_DRAWING+SHEET.dgn,Design Model;6,SHE-05.THIRD.dgn,Design Model:300570
5A | A206045 (EN) - Partition :1 ,SHE_DRAWING+SHEET.dgn,Design Model;6,SHE-05.THIRD.dgn,Design Model:304357
5A | A206045 (EN) - Partition :1 ,SHE_DRAWING+SHEET.dgn,Design Model;6,SHE-05.THIRD.dgn,Design Model:304647
5A | A206045 (EN) - Partition :1 ,SHE_DRAWING+SHEET.dgn,Design Model;6,SHE-05.THIRD.dgn,Design Model:329167
5A | A206045 (EN) - Partition :1 ,SHE_DRAWING+SHEET.dgn,Design Model;6,SHE-05.THIRD.dgn,Design Model:329592
5A | A206045 (EN) - Partition :1 ,SHE_DRAWING+SHEET.dgn,Design Model;6,SHE-05.THIRD.dgn,Design Model:332442
5A | A206045 (EN) - Partition :1 ,SHE_DRAWING+SHEET.dgn,Design Model;6,SHE-05.THIRD.dgn,Design Model:332488
5A | A206045 (EN) - Partition :1 ,SHE_DRAWING+SHEET.dgn,Design Model;6,SHE-05.THIRD.dgn,Design Model:369086
5A | A206045 (EN) - Partition :1 ,SHE_DRAWING+SHEET.dgn,Design Model;18,SHE-04.SECOND.dgn,Design Model:142264
5A | A206045 (EN) - Partition :1 ,SHE_DRAWING+SHEET.dgn,Design Model;18,SHE-04.SECOND.dgn,Design Model:142271
5A | A206045 (EN) - Partition :1 ,SHE_DRAWING+SHEET.dgn,Design Model;18,SHE-04.SECOND.dgn,Design Model:142272
5A | A206045 (EN) - Partition :1 ,SHE_DRAWING+SHEET.dgn,Design Model;18,SHE-04.SECOND.dgn,Design Model:142274
5A | A206045 (EN) - Partition :1 ,SHE_DRAWING+SHEET.dgn,Design Model;18,SHE-04.SECOND.dgn,Design Model:142275
5A | A206045 (EN) - Partition :1 ,SHE_DRAWING+SHEET.dgn,Design Model;18,SHE-04.SECOND.dgn,Design Model:142804
5A | A206045 (EN) - Partition :1 ,SHE_DRAWING+SHEET.dgn,Design Model;18,SHE-04.SECOND.dgn,Design Model:142805
5A | A206045 (EN) - Partition :1 ,SHE_DRAWING+SHEET.dgn,Design Model;18,SHE-04.SECOND.dgn,Design Model:142806
5A | A206045 (EN) - Partition :1 ,SHE_DRAWING+SHEET.dgn,Design Model;18,SHE-04.SECOND.dgn,Design Model:142807
5A | A206045 (EN) - Partition :1 ,SHE_DRAWING+SHEET.dgn,Design Model;18,SHE-04.SECOND.dgn,Design Model:142813
5A | A206045 (EN) - Partition :1 ,SHE_DRAWING+SHEET.dgn,Design Model;18,SHE-04.SECOND.dgn,Design Model:142814
5A | A206045 (EN) - Partition :1 ,SHE_DRAWING+SHEET.dgn,Design Model;18,SHE-04.SECOND.dgn,Design Model:147005
5A | A206045 (EN) - Partition :1 ,SHE_DRAWING+SHEET.dgn,Design Model;18,SHE-04.SECOND.dgn,Design Model:147006
5A | A206045 (EN) - Partition :1 ,SHE_DRAWING+SHEET.dgn,Design Model;18,SHE-04.SECOND.dgn,Design Model:172228
5A | A206045 (EN) - Partition :1 ,SHE_DRAWING+SHEET.dgn,Design Model;18,SHE-04.SECOND.dgn,Design Model:172449
5A | A206045 (EN) - Partition :1 ,SHE_DRAWING+SHEET.dgn,Design Model;18,SHE-04.SECOND.dgn,Design Model:173632
5A | A206045 (EN) - Partition :1 ,SHE_DRAWING+SHEET.dgn,Design Model;18,SHE-04.SECOND.dgn,Design Model:230031
5A | A206045 (EN) - Partition :1 ,SHE_DRAWING+SHEET.dgn,Design Model;18,SHE-04.SECOND.dgn,Design Model:230345
5A | A206045 (EN) - Partition :1 ,SHE_DRAWING+SHEET.dgn,Design Model;18,SHE-04.SECOND.dgn,Design Model:230391
5A | A206045 (EN) - Partition :1 ,SHE_DRAWING+SHEET.dgn,Design Model;18,SHE-04.SECOND.dgn,Design Model:230437
5A | A206045 (EN) - Partition :1 ,SHE_DRAWING+SHEET.dgn,Design Model;18,SHE-04.SECOND.dgn,Design Model:231743
5A | A206045 (EN) - Partition :1 ,SHE_DRAWING+SHEET.dgn,Design Model;18,SHE-04.SECOND.dgn,Design Model:253334
5A | A206045 (EN) - Partition :1 ,SHE_DRAWING+SHEET.dgn,Design Model;18,SHE-04.SECOND.dgn,Design Model:269095
5A | A206045 (EN) - Partition :1 ,SHE_DRAWING+SHEET.dgn,Design Model;18,SHE-04.SECOND.dgn,Design Model:269141
5A | A206045 (EN) - Partition :1 ,SHE_DRAWING+SHEET.dgn,Design Model;18,SHE-04.SECOND.dgn,Design Model:271053
5A | A206045 (EN) - Partition :1 ,SHE_DRAWING+SHEET.dgn,Design Model;18,SHE-04.SECOND.dgn,Design Model:272162
5A | A206045 (EN) - Partition :1 ,SHE_DRAWING+SHEET.dgn,Design Model;18,SHE-04.SECOND.dgn,Design Model:273961
5A | A206045 (EN) - Partition :1 ,SHE_DRAWING+SHEET.dgn,Design Model;18,SHE-04.SECOND.dgn,Design Model:274457
5A | A206045 (EN) - Partition :1 ,SHE_DRAWING+SHEET.dgn,Design Model;18,SHE-04.SECOND.dgn,Design Model:278735
5A | A206045 (EN) - Partition :1 ,SHE_DRAWING+SHEET.dgn,Design Model;18,SHE-04.SECOND.dgn,Design Model:278736
5A | A206045 (EN) - Partition :1 ,SHE_DRAWING+SHEET.dgn,Design Model;18,SHE-04.SECOND.dgn,Design Model:289175
5A | A206045 (EN) - Partition :1 ,SHE_DRAWING+SHEET.dgn,Design Model;18,SHE-04.SECOND.dgn,Design Model:290266
5A | A206045 (EN) - Partition :1 ,SHE_DRAWING+SHEET.dgn,Design Model;18,SHE-04.SECOND.dgn,Design Model:291273
5A | A206045 (EN) - Partition :1 ,SHE_DRAWING+SHEET.dgn,Design Model;18,SHE-04.SECOND.dgn,Design Model:297916
5A | A206045 (EN) - Partition :1 ,SHE_DRAWING+SHEET.dgn,Design Model;18,SHE-04.SECOND.dgn,Design Model:300531
5A | A206045 (EN) - Partition :1 ,SHE_DRAWING+SHEET.dgn,Design Model;18,SHE-04.SECOND.dgn,Design Model:300532
5A | A206045 (EN) - Partition :1 ,SHE_DRAWING+SHEET.dgn,Design Model;18,SHE-04.SECOND.dgn,Design Model:300570
5A | A206045 (EN) - Partition :1 ,SHE_DRAWING+SHEET.dgn,Design Model;18,SHE-04.SECOND.dgn,Design Model:304357
5A | A206045 (EN) - Partition :1 ,SHE_DRAWING+SHEET.dgn,Design Model;18,SHE-04.SECOND.dgn,Design Model:304647
5A | A206045 (EN) - Partition :1 ,SHE_DRAWING+SHEET.dgn,Design Model;18,SHE-04.SECOND.dgn,Design Model:329167
5A | A206045 (EN) - Partition :1 ,SHE_DRAWING+SHEET.dgn,Design Model;18,SHE-04.SECOND.dgn,Design Model:329592
5A | A206045 (EN) - Partition :1 ,SHE_DRAWING+SHEET.dgn,Design Model;18,SHE-04.SECOND.dgn,Design Model:332442
5A | A206045 (EN) - Partition :1 ,SHE_DRAWING+SHEET.dgn,Design Model;18,SHE-04.SECOND.dgn,Design Model:332488
5A | A206045 (EN) - Partition :1 ,SHE_DRAWING+SHEET.dgn,Design Model;18,SHE-04.SECOND.dgn,Design Model:375811

# IfcWall: SHE_A-Walls_Type05b_Partition_80mm (48)
In: RL
Type - Description: SHE_A-Walls_Type05b_Partition_80mm
Type - Wall Parameters - Type: Wall; Compound Wall Assembly: yes
Type - Thermal Transmittance - Is External: no; Is Below Grade: no
Type - Space Bounding - Is Space Bounding: yes
Type - Materials - Part Definition: A-CompoundWalls::SHE_A-Walls_Type05b_Partition_80mm
Type - LEED Parameters - LEED | Pre-consumer Recycled (%): 0; LEED | Regional Material: no; LEED | Post-consumer Recycled (%): 0
Type - Identification - ID | Type ID: A206034 (EN); ID | Description: SHE_A-Walls_Type05b_Partition_80mm; ID | Notes: https://www.british-gypsu m.com/Specification/White-Book-Specification-Selector/internal-partitions-walls/gypwall-single-frame/a206034-en
Type - Fire Resistance - Fire | Rating: F30; Fire | IsCombustible: no; Fire | Compartmentation: no
Type - Discipline - Discipline: Architectural
Type - Classification - Uniclass2015: EF_25_10
Type - Acoustical Parameters - Acoustic Rating (STC): 42 (min. 40)
Pset_WallCommon - AcousticRating: 42 (req. 40); Combustible: no; Compartmentation: no; FireRating: F30; IsExternal: no; LoadBearing: no
Identification - ID | Number: 5B; ID | Keynote: https://www.british-gyp sum.com/Specification/White-Book-Specification-Selector/internal-partitions-walls/gypwall-single-frame/a206034-en; ID | Notes: SHE_A-Walls_Type05b_Partition_80mm
Construction Phase - Phase: New Construction
Acoustical Parameters - Acoustic Rating (STC): 42 (req. 40)
Name | Description | ID | Description
5B | A206034 (EN) - Partition :1 ,SHE_DRAWING+SHEET.dgn,Design Model;1,SHE-01.GROUND.dgn,Design Model:152839 | Partition
5B | A206034 (EN) - Partition :1 ,SHE_DRAWING+SHEET.dgn,Design Model;1,SHE-01.GROUND.dgn,Design Model:159968 | Partition
5B | A206034 (EN) - Partition :1 ,SHE_DRAWING+SHEET.dgn,Design Model;1,SHE-01.GROUND.dgn,Design Model:161854 | Partition
5B | A206034 (EN) - Partition :1 ,SHE_DRAWING+SHEET.dgn,Design Model;1,SHE-01.GROUND.dgn,Design Model:178851 | Partition
5B | A206034 (EN) - Partition :1 ,SHE_DRAWING+SHEET.dgn,Design Model;1,SHE-01.GROUND.dgn,Design Model:178897 | Partition
5B | A206034 (EN) - Partition :1 ,SHE_DRAWING+SHEET.dgn,Design Model;1,SHE-01.GROUND.dgn,Design Model:182566 | Partition
5B | A206034 (EN) - Partition :1 ,SHE_DRAWING+SHEET.dgn,Design Model;1,SHE-01.GROUND.dgn,Design Model:182835 | Partition
5B | A206034 (EN) - Partition :1 ,SHE_DRAWING+SHEET.dgn,Design Model;2,SHE-02.MEZZANINE.dgn,Design Model:143593 | Partition
5B | A206034 (EN) - Partition :1 ,SHE_DRAWING+SHEET.dgn,Design Model;2,SHE-02.MEZZANINE.dgn,Design Model:195705 | Partition
5B | A206034 (EN) - Partition :1 ,SHE_DRAWING+SHEET.dgn,Design Model;7,SHE-06.FOURTH.dgn,Design Model:215591 | Partition
5B | A206034 (EN) - Partition :1 ,SHE_DRAWING+SHEET.dgn,Design Model;7,SHE-06.FOURTH.dgn,Design Model:218434 | Partition
5B | A206034 (EN) - Partition :1 ,SHE_DRAWING+SHEET.dgn,Design Model;7,SHE-06.FOURTH.dgn,Design Model:219317 | Partition
5B | A206034 (EN) - Partition :1 ,SHE_DRAWING+SHEET.dgn,Design Model;7,SHE-06.FOURTH.dgn,Design Model:220209 | Partition
5B | A206034 (EN) - Partition :1 ,SHE_DRAWING+SHEET.dgn,Design Model;7,SHE-06.FOURTH.dgn,Design Model:222926 | Partition
5B | A206034 (EN) - Partition :1 ,SHE_DRAWING+SHEET.dgn,Design Model;7,SHE-06.FOURTH.dgn,Design Model:223212 | Partition
5B | A206034 (EN) - Partition :1 ,SHE_DRAWING+SHEET.dgn,Design Model;7,SHE-06.FOURTH.dgn,Design Model:223258 | Partition
5B | A206034 (EN) - Partition :1 ,SHE_DRAWING+SHEET.dgn,Design Model;7,SHE-06.FOURTH.dgn,Design Model:226024 | Partition
5B | A206034 (EN) - Partition :1 ,SHE_DRAWING+SHEET.dgn,Design Model;7,SHE-06.FOURTH.dgn,Design Model:226231 | Partition
5B | A206034 (EN) - Partition :1 ,SHE_DRAWING+SHEET.dgn,Design Model;7,SHE-06.FOURTH.dgn,Design Model:226611 | Partition
5B | A206034 (EN) - Partition :1 ,SHE_DRAWING+SHEET.dgn,Design Model;7,SHE-06.FOURTH.dgn,Design Model:226765 | Partition
5B | A206034 (EN) - Partition :1 ,SHE_DRAWING+SHEET.dgn,Design Model;7,SHE-06.FOURTH.dgn,Design Model:229615 | Partition
5B | A206034 (EN) - Partition :1 ,SHE_DRAWING+SHEET.dgn,Design Model;7,SHE-06.FOURTH.dgn,Design Model:229661 | Partition
5B | A206034 (EN) - Partition :1 ,SHE_DRAWING+SHEET.dgn,Design Model;7,SHE-06.FOURTH.dgn,Design Model:260211 | Partition
5B | A206034 (EN) - Partition :1 ,SHE_DRAWING+SHEET.dgn,Design Model;7,SHE-06.FOURTH.dgn,Design Model:262439 | Partition
5B | A206034 (EN) - Partition :1 ,SHE_DRAWING+SHEET.dgn,Design Model;7,SHE-06.FOURTH.dgn,Design Model:262558 | Partition
5B | A206034 (EN) - Partition :1 ,SHE_DRAWING+SHEET.dgn,Design Model;7,SHE-06.FOURTH.dgn,Design Model:262821 | Partition
5B | A206034 (EN) - Partition :1 ,SHE_DRAWING+SHEET.dgn,Design Model;7,SHE-06.FOURTH.dgn,Design Model:263509 | Partition
5B | A206034 (EN) - Partition :1 ,SHE_DRAWING+SHEET.dgn,Design Model;7,SHE-06.FOURTH.dgn,Design Model:333108 | Partition
5B | A206034 (EN) - Partition :1 ,SHE_DRAWING+SHEET.dgn,Design Model;7,SHE-06.FOURTH.dgn,Design Model:408223 | Partition
5B | A206034 (EN) - Partition :1 ,SHE_DRAWING+SHEET.dgn,Design Model;7,SHE-06.FOURTH.dgn,Design Model:408273 | Partition
5B | A206034 (EN) - Partition :1 ,SHE_DRAWING+SHEET.dgn,Design Model;7,SHE-06.FOURTH.dgn,Design Model:450822 | Partition
5B | A206034 (EN) - Partition :1 ,SHE_DRAWING+SHEET.dgn,Design Model;7,SHE-06.FOURTH.dgn,Design Model:451097 | Partition
5B | A206034 (EN) - Partition :1 ,SHE_DRAWING+SHEET.dgn,Design Model;7,SHE-06.FOURTH.dgn,Design Model:453259 | Partition
5B | A206034 (EN) - Partition :1 ,SHE_DRAWING+SHEET.dgn,Design Model;7,SHE-06.FOURTH.dgn,Design Model:482970 | Partition
5B | A206034 (EN) - Partition :1 ,SHE_DRAWING+SHEET.dgn,Design Model;7,SHE-06.FOURTH.dgn,Design Model:483089 | Partition
5B | A206034 (EN) - Partition :1 ,SHE_DRAWING+SHEET.dgn,Design Model;7,SHE-06.FOURTH.dgn,Design Model:483315 | Partition
5B | A206034 (EN ) - Partition F30 :1,SHE_DRAWING+SHEET.dgn,Design Model;7,SHE-06.FOURTH.dgn ,Design Model:492922 | Partition F30
5B | A206034 (EN ) - Partition F30 :1,SHE_DRAWING+SHEET.dgn,Design Model;7,SHE-06.FOURTH.dgn ,Design Model:492963 | Partition F30
5B | A206034 (EN ) - Partition F30 :1,SHE_DRAWING+SHEET.dgn,Design Model;7,SHE-06.FOURTH.dgn ,Design Model:493012 | Partition F30
5B | A206034 (EN ) - Partition F30 :1,SHE_DRAWING+SHEET.dgn,Design Model;7,SHE-06.FOURTH.dgn ,Design Model:493161 | Partition F30
5B | A206034 (EN ) - Partition F30 :1,SHE_DRAWING+SHEET.dgn,Design Model;7,SHE-06.FOURTH.dgn ,Design Model:493206 | Partition F30
5B | A206034 (EN ) - Partition F30 :1,SHE_DRAWING+SHEET.dgn,Design Model;7,SHE-06.FOURTH.dgn ,Design Model:493247 | Partition F30
5B | A206034 (EN ) - Partition F30 :1,SHE_DRAWING+SHEET.dgn,Design Model;7,SHE-06.FOURTH.dgn ,Design Model:493288 | Partition F30
5B | A206034 (EN ) - Partition F30 :1,SHE_DRAWING+SHEET.dgn,Design Model;7,SHE-06.FOURTH.dgn ,Design Model:493447 | Partition F30
5B | A206034 (EN ) - Partition F30 :1,SHE_DRAWING+SHEET.dgn,Design Model;7,SHE-06.FOURTH.dgn ,Design Model:493542 | Partition F30
5B | A206034 (EN ) - Partition F30 :1,SHE_DRAWING+SHEET.dgn,Design Model;7,SHE-06.FOURTH.dgn ,Design Model:493583 | Partition F30
5B | A206034 (EN ) - Partition F30 :1,SHE_DRAWING+SHEET.dgn,Design Model;7,SHE-06.FOURTH.dgn ,Design Model:493624 | Partition F30
5B | A206034 (EN ) - Partition F30 :1,SHE_DRAWING+SHEET.dgn,Design Model;7,SHE-06.FOURTH.dgn ,Design Model:493699 | Partition F30

# IfcWall: SHE_A-Walls_Type05c_PreWallShell_65mm (133)
In: RL
Type - Description: SHE_A-Walls_Type05c_PreWallShell_65mm
Type - Wall Parameters - Type: Wall; Compound Wall Assembly: yes
Type - Thermal Transmittance - Is External: no; Is Below Grade: no
Type - Space Bounding - Is Space Bounding: yes
Type - Materials - Part Definition: A-CompoundWalls::SHE_A-Walls_Type05c_PreWallShell_65mm
Type - LEED Parameters - LEED | Pre-consumer Recycled (%): 0; LEED | Regional Material: no; LEED | Post-consumer Recycled (%): 0
Type - Identification - ID | Description: SHE_A-Walls_Type05c_PreWallShell_65mm
Type - Fire Resistance - Fire | IsCombustible: no; Fire | Compartmentation: no
Type - Discipline - Discipline: Architectural
Type - Construction Phase - Phase: New Construction
Type - Classification - Uniclass2015: EF_25_10
Pset_WallCommon - Combustible: no; Compartmentation: no; IsExternal: no; LoadBearing: no
Identification - ID | Number: 5C; ID | Description: PreShellWall; ID | Notes: SHE_A-Walls_Type05c_PreWallShell_65mm
Name | Description
5C | PreShellWall :1 ,SHE_DRAWING+SHEET.dgn,Design Model;1,SHE-01.GROUND.dgn,Design Model:155310
5C | PreShellWall :1 ,SHE_DRAWING+SHEET.dgn,Design Model;1,SHE-01.GROUND.dgn,Design Model:155425
5C | PreShellWall :1 ,SHE_DRAWING+SHEET.dgn,Design Model;1,SHE-01.GROUND.dgn,Design Model:155449
5C | PreShellWall :1 ,SHE_DRAWING+SHEET.dgn,Design Model;1,SHE-01.GROUND.dgn,Design Model:214056
5C | PreShellWall :1 ,SHE_DRAWING+SHEET.dgn,Design Model;2,SHE-02.MEZZANINE.dgn,Design Model:134079
5C | PreShellWall :1 ,SHE_DRAWING+SHEET.dgn,Design Model;2,SHE-02.MEZZANINE.dgn,Design Model:134098
5C | PreShellWall :1 ,SHE_DRAWING+SHEET.dgn,Design Model;2,SHE-02.MEZZANINE.dgn,Design Model:134165
5C | PreShellWall :1 ,SHE_DRAWING+SHEET.dgn,Design Model;2,SHE-02.MEZZANINE.dgn,Design Model:134184
5C | PreShellWall :1 ,SHE_DRAWING+SHEET.dgn,Design Model;2,SHE-02.MEZZANINE.dgn,Design Model:134216
5C | PreShellWall :1 ,SHE_DRAWING+SHEET.dgn,Design Model;2,SHE-02.MEZZANINE.dgn,Design Model:159495
5C | PreShellWall :1 ,SHE_DRAWING+SHEET.dgn,Design Model;4,SHE-03.FIRST.dgn,Design Model:143085
5C | PreShellWall :1 ,SHE_DRAWING+SHEET.dgn,Design Model;4,SHE-03.FIRST.dgn,Design Model:143086
5C | PreShellWall :1 ,SHE_DRAWING+SHEET.dgn,Design Model;4,SHE-03.FIRST.dgn,Design Model:143088
5C | PreShellWall :1 ,SHE_DRAWING+SHEET.dgn,Design Model;4,SHE-03.FIRST.dgn,Design Model:143097
5C | PreShellWall :1 ,SHE_DRAWING+SHEET.dgn,Design Model;4,SHE-03.FIRST.dgn,Design Model:143098
5C | PreShellWall :1 ,SHE_DRAWING+SHEET.dgn,Design Model;4,SHE-03.FIRST.dgn,Design Model:143322
5C | PreShellWall :1 ,SHE_DRAWING+SHEET.dgn,Design Model;4,SHE-03.FIRST.dgn,Design Model:143323
5C | PreShellWall :1 ,SHE_DRAWING+SHEET.dgn,Design Model;4,SHE-03.FIRST.dgn,Design Model:143324
5C | PreShellWall :1 ,SHE_DRAWING+SHEET.dgn,Design Model;4,SHE-03.FIRST.dgn,Design Model:176874
5C | PreShellWall :1 ,SHE_DRAWING+SHEET.dgn,Design Model;4,SHE-03.FIRST.dgn,Design Model:176991
5C | PreShellWall :1 ,SHE_DRAWING+SHEET.dgn,Design Model;4,SHE-03.FIRST.dgn,Design Model:228570
5C | PreShellWall :1 ,SHE_DRAWING+SHEET.dgn,Design Model;4,SHE-03.FIRST.dgn,Design Model:228571
5C | PreShellWall :1 ,SHE_DRAWING+SHEET.dgn,Design Model;4,SHE-03.FIRST.dgn,Design Model:229415
5C | PreShellWall :1 ,SHE_DRAWING+SHEET.dgn,Design Model;4,SHE-03.FIRST.dgn,Design Model:272034
5C | PreShellWall :1 ,SHE_DRAWING+SHEET.dgn,Design Model;4,SHE-03.FIRST.dgn,Design Model:277751
5C | PreShellWall :1 ,SHE_DRAWING+SHEET.dgn,Design Model;4,SHE-03.FIRST.dgn,Design Model:277793
5C | PreShellWall :1 ,SHE_DRAWING+SHEET.dgn,Design Model;4,SHE-03.FIRST.dgn,Design Model:280763
5C | PreShellWall :1 ,SHE_DRAWING+SHEET.dgn,Design Model;4,SHE-03.FIRST.dgn,Design Model:291908
5C | PreShellWall :1 ,SHE_DRAWING+SHEET.dgn,Design Model;4,SHE-03.FIRST.dgn,Design Model:297632
5C | PreShellWall :1 ,SHE_DRAWING+SHEET.dgn,Design Model;4,SHE-03.FIRST.dgn,Design Model:297747
5C | PreShellWall :1 ,SHE_DRAWING+SHEET.dgn,Design Model;4,SHE-03.FIRST.dgn,Design Model:300520
5C | PreShellWall :1 ,SHE_DRAWING+SHEET.dgn,Design Model;4,SHE-03.FIRST.dgn,Design Model:300521
5C | PreShellWall :1 ,SHE_DRAWING+SHEET.dgn,Design Model;4,SHE-03.FIRST.dgn,Design Model:300568
5C | PreShellWall :1 ,SHE_DRAWING+SHEET.dgn,Design Model;4,SHE-03.FIRST.dgn,Design Model:300569
5C | PreShellWall :1 ,SHE_DRAWING+SHEET.dgn,Design Model;4,SHE-03.FIRST.dgn,Design Model:306845
5C | PreShellWall :1 ,SHE_DRAWING+SHEET.dgn,Design Model;4,SHE-03.FIRST.dgn,Design Model:306866
5C | PreShellWall :1 ,SHE_DRAWING+SHEET.dgn,Design Model;4,SHE-03.FIRST.dgn,Design Model:327268
5C | PreShellWall :1 ,SHE_DRAWING+SHEET.dgn,Design Model;4,SHE-03.FIRST.dgn,Design Model:327269
5C | PreShellWall :1 ,SHE_DRAWING+SHEET.dgn,Design Model;4,SHE-03.FIRST.dgn,Design Model:327337
5C | PreShellWall :1 ,SHE_DRAWING+SHEET.dgn,Design Model;4,SHE-03.FIRST.dgn,Design Model:327376
5C | PreShellWall :1 ,SHE_DRAWING+SHEET.dgn,Design Model;6,SHE-05.THIRD.dgn,Design Model:143085
5C | PreShellWall :1 ,SHE_DRAWING+SHEET.dgn,Design Model;6,SHE-05.THIRD.dgn,Design Model:143086
5C | PreShellWall :1 ,SHE_DRAWING+SHEET.dgn,Design Model;6,SHE-05.THIRD.dgn,Design Model:143088
5C | PreShellWall :1 ,SHE_DRAWING+SHEET.dgn,Design Model;6,SHE-05.THIRD.dgn,Design Model:143097
5C | PreShellWall :1 ,SHE_DRAWING+SHEET.dgn,Design Model;6,SHE-05.THIRD.dgn,Design Model:143098
5C | PreShellWall :1 ,SHE_DRAWING+SHEET.dgn,Design Model;6,SHE-05.THIRD.dgn,Design Model:143322
5C | PreShellWall :1 ,SHE_DRAWING+SHEET.dgn,Design Model;6,SHE-05.THIRD.dgn,Design Model:143323
5C | PreShellWall :1 ,SHE_DRAWING+SHEET.dgn,Design Model;6,SHE-05.THIRD.dgn,Design Model:143324
5C | PreShellWall :1 ,SHE_DRAWING+SHEET.dgn,Design Model;6,SHE-05.THIRD.dgn,Design Model:176874
5C | PreShellWall :1 ,SHE_DRAWING+SHEET.dgn,Design Model;6,SHE-05.THIRD.dgn,Design Model:176991
5C | PreShellWall :1 ,SHE_DRAWING+SHEET.dgn,Design Model;6,SHE-05.THIRD.dgn,Design Model:228570
5C | PreShellWall :1 ,SHE_DRAWING+SHEET.dgn,Design Model;6,SHE-05.THIRD.dgn,Design Model:228571
5C | PreShellWall :1 ,SHE_DRAWING+SHEET.dgn,Design Model;6,SHE-05.THIRD.dgn,Design Model:229415
5C | PreShellWall :1 ,SHE_DRAWING+SHEET.dgn,Design Model;6,SHE-05.THIRD.dgn,Design Model:272034
5C | PreShellWall :1 ,SHE_DRAWING+SHEET.dgn,Design Model;6,SHE-05.THIRD.dgn,Design Model:277751
5C | PreShellWall :1 ,SHE_DRAWING+SHEET.dgn,Design Model;6,SHE-05.THIRD.dgn,Design Model:277793
5C | PreShellWall :1 ,SHE_DRAWING+SHEET.dgn,Design Model;6,SHE-05.THIRD.dgn,Design Model:280763
5C | PreShellWall :1 ,SHE_DRAWING+SHEET.dgn,Design Model;6,SHE-05.THIRD.dgn,Design Model:291908
5C | PreShellWall :1 ,SHE_DRAWING+SHEET.dgn,Design Model;6,SHE-05.THIRD.dgn,Design Model:297632
5C | PreShellWall :1 ,SHE_DRAWING+SHEET.dgn,Design Model;6,SHE-05.THIRD.dgn,Design Model:297747
5C | PreShellWall :1 ,SHE_DRAWING+SHEET.dgn,Design Model;6,SHE-05.THIRD.dgn,Design Model:300520
5C | PreShellWall :1 ,SHE_DRAWING+SHEET.dgn,Design Model;6,SHE-05.THIRD.dgn,Design Model:300521
5C | PreShellWall :1 ,SHE_DRAWING+SHEET.dgn,Design Model;6,SHE-05.THIRD.dgn,Design Model:300568
5C | PreShellWall :1 ,SHE_DRAWING+SHEET.dgn,Design Model;6,SHE-05.THIRD.dgn,Design Model:300569
5C | PreShellWall :1 ,SHE_DRAWING+SHEET.dgn,Design Model;6,SHE-05.THIRD.dgn,Design Model:306845
5C | PreShellWall :1 ,SHE_DRAWING+SHEET.dgn,Design Model;6,SHE-05.THIRD.dgn,Design Model:306866
5C | PreShellWall :1 ,SHE_DRAWING+SHEET.dgn,Design Model;6,SHE-05.THIRD.dgn,Design Model:327268
5C | PreShellWall :1 ,SHE_DRAWING+SHEET.dgn,Design Model;6,SHE-05.THIRD.dgn,Design Model:327269
5C | PreShellWall :1 ,SHE_DRAWING+SHEET.dgn,Design Model;6,SHE-05.THIRD.dgn,Design Model:327337
5C | PreShellWall :1 ,SHE_DRAWING+SHEET.dgn,Design Model;6,SHE-05.THIRD.dgn,Design Model:327376
5C | PreShellWall :1 ,SHE_DRAWING+SHEET.dgn,Design Model;7,SHE-06.FOURTH.dgn,Design Model:243791
5C | PreShellWall :1 ,SHE_DRAWING+SHEET.dgn,Design Model;7,SHE-06.FOURTH.dgn,Design Model:244079
5C | PreShellWall :1 ,SHE_DRAWING+SHEET.dgn,Design Model;7,SHE-06.FOURTH.dgn,Design Model:244100
5C | PreShellWall :1 ,SHE_DRAWING+SHEET.dgn,Design Model;7,SHE-06.FOURTH.dgn,Design Model:244310
5C | PreShellWall :1 ,SHE_DRAWING+SHEET.dgn,Design Model;7,SHE-06.FOURTH.dgn,Design Model:245274
5C | PreShellWall :1 ,SHE_DRAWING+SHEET.dgn,Design Model;7,SHE-06.FOURTH.dgn,Design Model:245275
5C | PreShellWall :1 ,SHE_DRAWING+SHEET.dgn,Design Model;7,SHE-06.FOURTH.dgn,Design Model:245276
5C | PreShellWall :1 ,SHE_DRAWING+SHEET.dgn,Design Model;7,SHE-06.FOURTH.dgn,Design Model:245428
5C | PreShellWall :1 ,SHE_DRAWING+SHEET.dgn,Design Model;7,SHE-06.FOURTH.dgn,Design Model:248737
5C | PreShellWall :1 ,SHE_DRAWING+SHEET.dgn,Design Model;7,SHE-06.FOURTH.dgn,Design Model:248738
5C | PreShellWall :1 ,SHE_DRAWING+SHEET.dgn,Design Model;7,SHE-06.FOURTH.dgn,Design Model:248739
5C | PreShellWall :1 ,SHE_DRAWING+SHEET.dgn,Design Model;7,SHE-06.FOURTH.dgn,Design Model:248818
5C | PreShellWall :1 ,SHE_DRAWING+SHEET.dgn,Design Model;7,SHE-06.FOURTH.dgn,Design Model:256500
5C | PreShellWall :1 ,SHE_DRAWING+SHEET.dgn,Design Model;7,SHE-06.FOURTH.dgn,Design Model:256501
5C | PreShellWall :1 ,SHE_DRAWING+SHEET.dgn,Design Model;7,SHE-06.FOURTH.dgn,Design Model:256502
5C | PreShellWall :1 ,SHE_DRAWING+SHEET.dgn,Design Model;7,SHE-06.FOURTH.dgn,Design Model:256518
5C | PreShellWall :1 ,SHE_DRAWING+SHEET.dgn,Design Model;7,SHE-06.FOURTH.dgn,Design Model:408023
5C | PreShellWall :1 ,SHE_DRAWING+SHEET.dgn,Design Model;7,SHE-06.FOURTH.dgn,Design Model:408024
5C | PreShellWall :1 ,SHE_DRAWING+SHEET.dgn,Design Model;7,SHE-06.FOURTH.dgn,Design Model:408025
5C | PreShellWall :1 ,SHE_DRAWING+SHEET.dgn,Design Model;7,SHE-06.FOURTH.dgn,Design Model:408035
5C | PreShellWall :1 ,SHE_DRAWING+SHEET.dgn,Design Model;7,SHE-06.FOURTH.dgn,Design Model:408036
5C | PreShellWall :1 ,SHE_DRAWING+SHEET.dgn,Design Model;7,SHE-06.FOURTH.dgn,Design Model:408037
5C | PreShellWall :1 ,SHE_DRAWING+SHEET.dgn,Design Model;7,SHE-06.FOURTH.dgn,Design Model:483191
5C | PreShellWall :1 ,SHE_DRAWING+SHEET.dgn,Design Model;7,SHE-06.FOURTH.dgn,Design Model:483214
5C | PreShellWall :1 ,SHE_DRAWING+SHEET.dgn,Design Model;7,SHE-06.FOURTH.dgn,Design Model:513853
5C | PreShellWall :1 ,SHE_DRAWING+SHEET.dgn,Design Model;7,SHE-06.FOURTH.dgn,Design Model:513854
5C | PreShellWall :1 ,SHE_DRAWING+SHEET.dgn,Design Model;7,SHE-06.FOURTH.dgn,Design Model:513855
5C | PreShellWall :1 ,SHE_DRAWING+SHEET.dgn,Design Model;7,SHE-06.FOURTH.dgn,Design Model:514019
5C | PreShellWall :1 ,SHE_DRAWING+SHEET.dgn,Design Model;7,SHE-06.FOURTH.dgn,Design Model:514020
5C | PreShellWall :1 ,SHE_DRAWING+SHEET.dgn,Design Model;7,SHE-06.FOURTH.dgn,Design Model:514021
5C | PreShellWall :1 ,SHE_DRAWING+SHEET.dgn,Design Model;7,SHE-06.FOURTH.dgn,Design Model:514108
5C | PreShellWall :1 ,SHE_DRAWING+SHEET.dgn,Design Model;7,SHE-06.FOURTH.dgn,Design Model:514109
5C | PreShellWall :1 ,SHE_DRAWING+SHEET.dgn,Design Model;7,SHE-06.FOURTH.dgn,Design Model:514110
5C | PreShellWall :1 ,SHE_DRAWING+SHEET.dgn,Design Model;18,SHE-04.SECOND.dgn,Design Model:143085
5C | PreShellWall :1 ,SHE_DRAWING+SHEET.dgn,Design Model;18,SHE-04.SECOND.dgn,Design Model:143086
5C | PreShellWall :1 ,SHE_DRAWING+SHEET.dgn,Design Model;18,SHE-04.SECOND.dgn,Design Model:143088
5C | PreShellWall :1 ,SHE_DRAWING+SHEET.dgn,Design Model;18,SHE-04.SECOND.dgn,Design Model:143097
5C | PreShellWall :1 ,SHE_DRAWING+SHEET.dgn,Design Model;18,SHE-04.SECOND.dgn,Design Model:143098
5C | PreShellWall :1 ,SHE_DRAWING+SHEET.dgn,Design Model;18,SHE-04.SECOND.dgn,Design Model:143322
5C | PreShellWall :1 ,SHE_DRAWING+SHEET.dgn,Design Model;18,SHE-04.SECOND.dgn,Design Model:143323
5C | PreShellWall :1 ,SHE_DRAWING+SHEET.dgn,Design Model;18,SHE-04.SECOND.dgn,Design Model:143324
5C | PreShellWall :1 ,SHE_DRAWING+SHEET.dgn,Design Model;18,SHE-04.SECOND.dgn,Design Model:176874
5C | PreShellWall :1 ,SHE_DRAWING+SHEET.dgn,Design Model;18,SHE-04.SECOND.dgn,Design Model:176991
5C | PreShellWall :1 ,SHE_DRAWING+SHEET.dgn,Design Model;18,SHE-04.SECOND.dgn,Design Model:228570
5C | PreShellWall :1 ,SHE_DRAWING+SHEET.dgn,Design Model;18,SHE-04.SECOND.dgn,Design Model:228571
5C | PreShellWall :1 ,SHE_DRAWING+SHEET.dgn,Design Model;18,SHE-04.SECOND.dgn,Design Model:229415
5C | PreShellWall :1 ,SHE_DRAWING+SHEET.dgn,Design Model;18,SHE-04.SECOND.dgn,Design Model:272034
5C | PreShellWall :1 ,SHE_DRAWING+SHEET.dgn,Design Model;18,SHE-04.SECOND.dgn,Design Model:277751
5C | PreShellWall :1 ,SHE_DRAWING+SHEET.dgn,Design Model;18,SHE-04.SECOND.dgn,Design Model:277793
5C | PreShellWall :1 ,SHE_DRAWING+SHEET.dgn,Design Model;18,SHE-04.SECOND.dgn,Design Model:280763
5C | PreShellWall :1 ,SHE_DRAWING+SHEET.dgn,Design Model;18,SHE-04.SECOND.dgn,Design Model:291908
5C | PreShellWall :1 ,SHE_DRAWING+SHEET.dgn,Design Model;18,SHE-04.SECOND.dgn,Design Model:297632
5C | PreShellWall :1 ,SHE_DRAWING+SHEET.dgn,Design Model;18,SHE-04.SECOND.dgn,Design Model:297747
5C | PreShellWall :1 ,SHE_DRAWING+SHEET.dgn,Design Model;18,SHE-04.SECOND.dgn,Design Model:300520
5C | PreShellWall :1 ,SHE_DRAWING+SHEET.dgn,Design Model;18,SHE-04.SECOND.dgn,Design Model:300521
5C | PreShellWall :1 ,SHE_DRAWING+SHEET.dgn,Design Model;18,SHE-04.SECOND.dgn,Design Model:300568
5C | PreShellWall :1 ,SHE_DRAWING+SHEET.dgn,Design Model;18,SHE-04.SECOND.dgn,Design Model:300569
5C | PreShellWall :1 ,SHE_DRAWING+SHEET.dgn,Design Model;18,SHE-04.SECOND.dgn,Design Model:306845
5C | PreShellWall :1 ,SHE_DRAWING+SHEET.dgn,Design Model;18,SHE-04.SECOND.dgn,Design Model:306866
5C | PreShellWall :1 ,SHE_DRAWING+SHEET.dgn,Design Model;18,SHE-04.SECOND.dgn,Design Model:327268
5C | PreShellWall :1 ,SHE_DRAWING+SHEET.dgn,Design Model;18,SHE-04.SECOND.dgn,Design Model:327269
5C | PreShellWall :1 ,SHE_DRAWING+SHEET.dgn,Design Model;18,SHE-04.SECOND.dgn,Design Model:327337
5C | PreShellWall :1 ,SHE_DRAWING+SHEET.dgn,Design Model;18,SHE-04.SECOND.dgn,Design Model:327376

# IfcWall: SHE_A-Walls_Type06c_ExternalWallInsulation_60mm (22)
In: RL
Type - Description: SHE_A-Walls_Type06c_ExternalWallInsulation_60mm
Type - Wall Parameters - Type: Wall; Compound Wall Assembly: yes
Type - Thermal Transmittance - Is External: no; Is Below Grade: no
Type - Space Bounding - Is Space Bounding: yes
Type - Materials - Part Definition: A-CompoundWalls::SHE_A-Walls_Type06c_ExternalWallInsulation_60mm
Type - LEED Parameters - LEED | Pre-consumer Recycled (%): 0; LEED | Regional Material: no; LEED | Post-consumer Recycled (%): 0
Type - Identification - ID | Description: SHE_A-Walls_Type06c_ExternalWallInsulation_60mm; ID | Notes: https://celotex.co.uk/products/celotex-ga4000
Type - Fire Resistance - Fire | IsCombustible: no; Fire | Compartmentation: no
Type - Discipline - Discipline: Architectural
Type - Construction Phase - Phase: New Construction
Type - Classification - Uniclass2015: EF_25_10
Pset_WallCommon - Combustible: no; Compartmentation: no; IsExternal: no; LoadBearing: no
Identification - ID | Type ID: U-Value 0.3; ID | Number: 6C; ID | Description: FacadeInsulation; ID | Keynote: https://celotex.co.uk/products/celotex-ga4000; ID | Notes: SHE_A-Walls_Type06c_ExternalWallInsulation_60mm
Name | Description | AcousticRating = Acoustic Rating (STC)
6C | U-Value 0.3 - FacadeInsulation :1,SHE_DRAWING+SHEET.dgn,Design Model;1 ,SHE-01.GROUND.dgn,Design Model:183216 | req. 48
6C | U-Value 0.3 - FacadeInsulation :1,SHE_DRAWING+SHEET.dgn,Design Model;1 ,SHE-01.GROUND.dgn,Design Model:183330 | req. 48
6C | U-Value 0.3 - FacadeInsulation :1,SHE_DRAWING+SHEET.dgn,Design Model;1 ,SHE-01.GROUND.dgn,Design Model:183358 | req. 48
6C | U-Value 0.3 - FacadeInsulation :1,SHE_DRAWING+SHEET.dgn,Design Model;1 ,SHE-01.GROUND.dgn,Design Model:183895 | req. 48
6C | U-Value 0.3 - FacadeInsulation :1,SHE_DRAWING+SHEET.dgn,Design Model;1 ,SHE-01.GROUND.dgn,Design Model:183923 | req. 48
6C | U-Value 0.3 - FacadeInsulation :1,SHE_DRAWING+SHEET.dgn,Design Model;1 ,SHE-01.GROUND.dgn,Design Model:183951 | req. 48
6C | U-Value 0.3 - FacadeInsulation :1,SHE_DRAWING+SHEET.dgn,Design Model;1 ,SHE-01.GROUND.dgn,Design Model:183979 | req. 48
6C | U-Value 0.3 - FacadeInsulation :1,SHE_DRAWING+SHEET.dgn,Design Model;1 ,SHE-01.GROUND.dgn,Design Model:184491 | req. 48
6C | U-Value 0.3 - FacadeInsulation :1,SHE_DRAWING+SHEET.dgn,Design Model;1 ,SHE-01.GROUND.dgn,Design Model:184519 | req. 48
6C | U-Value 0.3 - FacadeInsulation :1,SHE_DRAWING+SHEET.dgn,Design Model;1 ,SHE-01.GROUND.dgn,Design Model:184547 | req. 48
6C | U-Value 0.3 - FacadeInsulation :1,SHE_DRAWING+SHEET.dgn,Design Model;1 ,SHE-01.GROUND.dgn,Design Model:184575 | req. 48
6C | U-Value 0.3 - FacadeInsulation :1,SHE_DRAWING+SHEET.dgn,Design Model;2 ,SHE-02.MEZZANINE.dgn,Design Model:203802 | Rw 52dB Rw+Ctr 48dB | Identification - ID | Asset Tag: .
6C | U-Value 0.3 - FacadeInsulation :1,SHE_DRAWING+SHEET.dgn,Design Model;2 ,SHE-02.MEZZANINE.dgn,Design Model:203859 | Rw 52dB Rw+Ctr 48dB | Identification - ID | Asset Tag: .
6C | U-Value 0.3 - FacadeInsulation :1,SHE_DRAWING+SHEET.dgn,Design Model;2 ,SHE-02.MEZZANINE.dgn,Design Model:203884 | Rw 52dB Rw+Ctr 48dB | Identification - ID | Asset Tag: .
6C | U-Value 0.3 - FacadeInsulation :1,SHE_DRAWING+SHEET.dgn,Design Model;2 ,SHE-02.MEZZANINE.dgn,Design Model:203909 | Rw 52dB Rw+Ctr 48dB | Identification - ID | Asset Tag: .
6C | U-Value 0.3 - FacadeInsulation :1,SHE_DRAWING+SHEET.dgn,Design Model;2 ,SHE-02.MEZZANINE.dgn,Design Model:203966 | Rw 52dB Rw+Ctr 48dB | Identification - ID | Asset Tag: .
6C | U-Value 0.3 - FacadeInsulation :1,SHE_DRAWING+SHEET.dgn,Design Model;2 ,SHE-02.MEZZANINE.dgn,Design Model:203991 | Rw 52dB Rw+Ctr 48dB | Identification - ID | Asset Tag: .
6C | U-Value 0.3 - FacadeInsulation :1,SHE_DRAWING+SHEET.dgn,Design Model;2 ,SHE-02.MEZZANINE.dgn,Design Model:204016 | Rw 52dB Rw+Ctr 48dB | Identification - ID | Asset Tag: .
6C | U-Value 0.3 - FacadeInsulation :1,SHE_DRAWING+SHEET.dgn,Design Model;2 ,SHE-02.MEZZANINE.dgn,Design Model:204041 | Rw 52dB Rw+Ctr 48dB | Identification - ID | Asset Tag: .
6C | U-Value 0.3 - FacadeInsulation :1,SHE_DRAWING+SHEET.dgn,Design Model;2 ,SHE-02.MEZZANINE.dgn,Design Model:204066 | Rw 52dB Rw+Ctr 48dB | Identification - ID | Asset Tag: .
6C | U-Value 0.3 - FacadeInsulation :1,SHE_DRAWING+SHEET.dgn,Design Model;2 ,SHE-02.MEZZANINE.dgn,Design Model:204091 | Rw 52dB Rw+Ctr 48dB | Identification - ID | Asset Tag: .
6C | U-Value 0.3 - FacadeInsulation :1,SHE_DRAWING+SHEET.dgn,Design Model;2 ,SHE-02.MEZZANINE.dgn,Design Model:204136 | Rw 52dB Rw+Ctr 48dB | Identification - ID | Asset Tag: .

# IfcWall: SHE_A-Walls_Type06d_ExternalWallInsulation_48mm (227)
In: RL
Type - Description: SHE_A-Walls_Type06d_ExternalWallInsulation_48mm
Type - Wall Parameters - Type: Wall; Compound Wall Assembly: yes
Type - Thermal Transmittance - Is External: no; Is Below Grade: no
Type - Space Bounding - Is Space Bounding: yes
Type - Materials - Part Definition: A-CompoundWalls::SHE_A-Walls_Type06d_ExternalWallInsulation_48mm
Type - LEED Parameters - LEED | Pre-consumer Recycled (%): 0; LEED | Regional Material: no; LEED | Post-consumer Recycled (%): 0
Type - Identification - ID | Description: SHE_A-Walls_Type06d_ExternalWallInsulation_48mm
Type - Fire Resistance - Fire | IsCombustible: no; Fire | Compartmentation: no
Type - Discipline - Discipline: Architectural
Type - Construction Phase - Phase: New Construction
Type - Classification - Uniclass2015: EF_25_10
Pset_WallCommon - AcousticRating: req. 48; Combustible: no; Compartmentation: no; IsExternal: no; LoadBearing: no
Identification - ID | Type ID: U-Value 0.5; ID | Number: 6D; ID | Description: FacadeInsulation; ID | Keynote: https://www.british-gyp sum.com/products/board-products/gyproc-thermaline-plus-48mm; ID | Notes: SHE_A-Walls_Type06d_ExternalWallInsulation_48mm
Acoustical Parameters - Acoustic Rating (STC): req. 48
Name | Description
6D | U-Value 0.5 - FacadeInsulation :1,SHE_DRAWING+SHEET.dgn,Design Model;4 ,SHE-03.FIRST.dgn,Design Model:141902
6D | U-Value 0.5 - FacadeInsulation :1,SHE_DRAWING+SHEET.dgn,Design Model;4 ,SHE-03.FIRST.dgn,Design Model:141903
6D | U-Value 0.5 - FacadeInsulation :1,SHE_DRAWING+SHEET.dgn,Design Model;4 ,SHE-03.FIRST.dgn,Design Model:141904
6D | U-Value 0.5 - FacadeInsulation :1,SHE_DRAWING+SHEET.dgn,Design Model;4 ,SHE-03.FIRST.dgn,Design Model:141907
6D | U-Value 0.5 - FacadeInsulation :1,SHE_DRAWING+SHEET.dgn,Design Model;4 ,SHE-03.FIRST.dgn,Design Model:141908
6D | U-Value 0.5 - FacadeInsulation :1,SHE_DRAWING+SHEET.dgn,Design Model;4 ,SHE-03.FIRST.dgn,Design Model:141909
6D | U-Value 0.5 - FacadeInsulation :1,SHE_DRAWING+SHEET.dgn,Design Model;4 ,SHE-03.FIRST.dgn,Design Model:141910
6D | U-Value 0.5 - FacadeInsulation :1,SHE_DRAWING+SHEET.dgn,Design Model;4 ,SHE-03.FIRST.dgn,Design Model:141911
6D | U-Value 0.5 - FacadeInsulation :1,SHE_DRAWING+SHEET.dgn,Design Model;4 ,SHE-03.FIRST.dgn,Design Model:141912
6D | U-Value 0.5 - FacadeInsulation :1,SHE_DRAWING+SHEET.dgn,Design Model;4 ,SHE-03.FIRST.dgn,Design Model:141913
6D | U-Value 0.5 - FacadeInsulation :1,SHE_DRAWING+SHEET.dgn,Design Model;4 ,SHE-03.FIRST.dgn,Design Model:141914
6D | U-Value 0.5 - FacadeInsulation :1,SHE_DRAWING+SHEET.dgn,Design Model;4 ,SHE-03.FIRST.dgn,Design Model:141917
6D | U-Value 0.5 - FacadeInsulation :1,SHE_DRAWING+SHEET.dgn,Design Model;4 ,SHE-03.FIRST.dgn,Design Model:141918
6D | U-Value 0.5 - FacadeInsulation :1,SHE_DRAWING+SHEET.dgn,Design Model;4 ,SHE-03.FIRST.dgn,Design Model:141919
6D | U-Value 0.5 - FacadeInsulation :1,SHE_DRAWING+SHEET.dgn,Design Model;4 ,SHE-03.FIRST.dgn,Design Model:141920
6D | U-Value 0.5 - FacadeInsulation :1,SHE_DRAWING+SHEET.dgn,Design Model;4 ,SHE-03.FIRST.dgn,Design Model:141921
6D | U-Value 0.5 - FacadeInsulation :1,SHE_DRAWING+SHEET.dgn,Design Model;4 ,SHE-03.FIRST.dgn,Design Model:141922
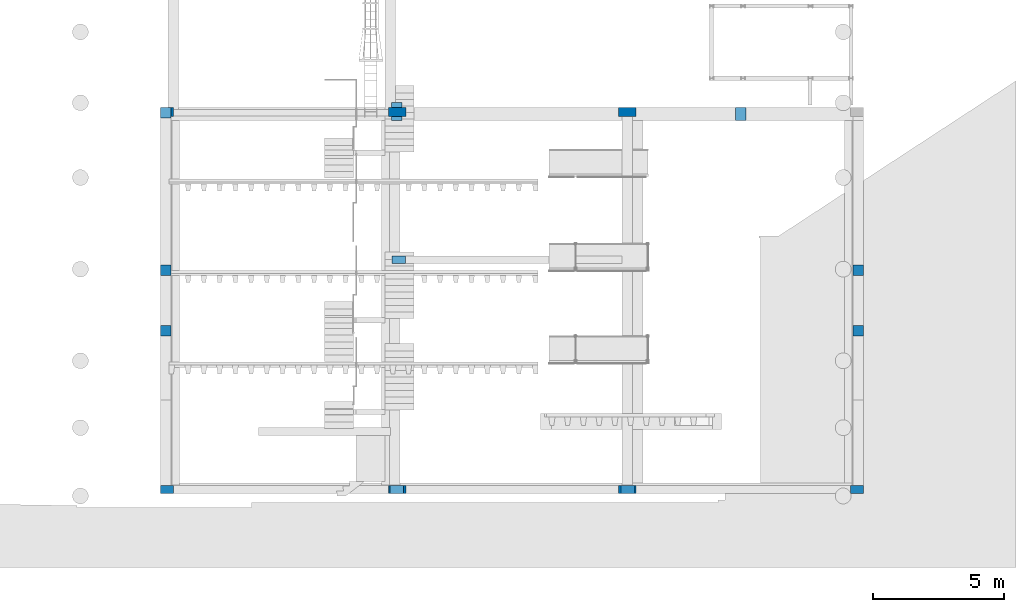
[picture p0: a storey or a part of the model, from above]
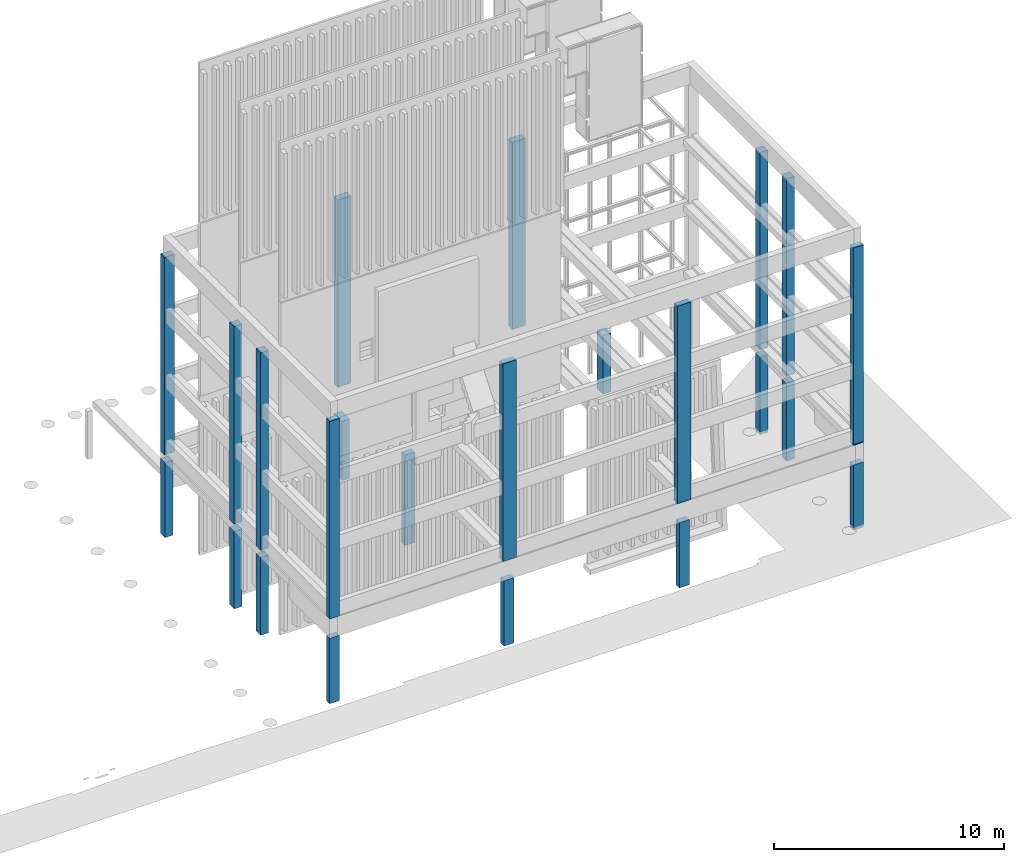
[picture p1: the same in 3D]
Properties of the parts of a building model (IFC2X3), part 15 of 16

# IfcWall: SHE_A-Walls_Type06d_ExternalWallInsulation_48mm (227)
Name | Description
6D | U-Value 0.5 - FacadeInsulation :1,SHE_DRAWING+SHEET.dgn,Design Model;4 ,SHE-03.FIRST.dgn,Design Model:141927
6D | U-Value 0.5 - FacadeInsulation :1,SHE_DRAWING+SHEET.dgn,Design Model;4 ,SHE-03.FIRST.dgn,Design Model:141928
6D | U-Value 0.5 - FacadeInsulation :1,SHE_DRAWING+SHEET.dgn,Design Model;4 ,SHE-03.FIRST.dgn,Design Model:141929
6D | U-Value 0.5 - FacadeInsulation :1,SHE_DRAWING+SHEET.dgn,Design Model;4 ,SHE-03.FIRST.dgn,Design Model:141960
6D | U-Value 0.5 - FacadeInsulation :1,SHE_DRAWING+SHEET.dgn,Design Model;4 ,SHE-03.FIRST.dgn,Design Model:141961
6D | U-Value 0.5 - FacadeInsulation :1,SHE_DRAWING+SHEET.dgn,Design Model;4 ,SHE-03.FIRST.dgn,Design Model:141962
6D | U-Value 0.5 - FacadeInsulation :1,SHE_DRAWING+SHEET.dgn,Design Model;4 ,SHE-03.FIRST.dgn,Design Model:390499
6D | U-Value 0.5 - FacadeInsulation :1,SHE_DRAWING+SHEET.dgn,Design Model;4 ,SHE-03.FIRST.dgn,Design Model:390500
6D | U-Value 0.5 - FacadeInsulation :1,SHE_DRAWING+SHEET.dgn,Design Model;4 ,SHE-03.FIRST.dgn,Design Model:390501
6D | U-Value 0.5 - FacadeInsulation :1,SHE_DRAWING+SHEET.dgn,Design Model;4 ,SHE-03.FIRST.dgn,Design Model:392991
6D | U-Value 0.5 - FacadeInsulation :1,SHE_DRAWING+SHEET.dgn,Design Model;4 ,SHE-03.FIRST.dgn,Design Model:394187
6D | U-Value 0.5 - FacadeInsulation :1,SHE_DRAWING+SHEET.dgn,Design Model;4 ,SHE-03.FIRST.dgn,Design Model:394284
6D | U-Value 0.5 - FacadeInsulation :1,SHE_DRAWING+SHEET.dgn,Design Model;4 ,SHE-03.FIRST.dgn,Design Model:394429
6D | U-Value 0.5 - FacadeInsulation :1,SHE_DRAWING+SHEET.dgn,Design Model;4 ,SHE-03.FIRST.dgn,Design Model:394526
6D | U-Value 0.5 - FacadeInsulation :1,SHE_DRAWING+SHEET.dgn,Design Model;4 ,SHE-03.FIRST.dgn,Design Model:394647
6D | U-Value 0.5 - FacadeInsulation :1,SHE_DRAWING+SHEET.dgn,Design Model;4 ,SHE-03.FIRST.dgn,Design Model:394744
6D | U-Value 0.5 - FacadeInsulation :1,SHE_DRAWING+SHEET.dgn,Design Model;4 ,SHE-03.FIRST.dgn,Design Model:394841
6D | U-Value 0.5 - FacadeInsulation :1,SHE_DRAWING+SHEET.dgn,Design Model;4 ,SHE-03.FIRST.dgn,Design Model:394938
6D | U-Value 0.5 - FacadeInsulation :1,SHE_DRAWING+SHEET.dgn,Design Model;4 ,SHE-03.FIRST.dgn,Design Model:395059
6D | U-Value 0.5 - FacadeInsulation :1,SHE_DRAWING+SHEET.dgn,Design Model;4 ,SHE-03.FIRST.dgn,Design Model:395132
6D | U-Value 0.5 - FacadeInsulation :1,SHE_DRAWING+SHEET.dgn,Design Model;4 ,SHE-03.FIRST.dgn,Design Model:395237
6D | U-Value 0.5 - FacadeInsulation :1,SHE_DRAWING+SHEET.dgn,Design Model;4 ,SHE-03.FIRST.dgn,Design Model:395334
6D | U-Value 0.5 - FacadeInsulation :1,SHE_DRAWING+SHEET.dgn,Design Model;4 ,SHE-03.FIRST.dgn,Design Model:395431
6D | U-Value 0.5 - FacadeInsulation :1,SHE_DRAWING+SHEET.dgn,Design Model;4 ,SHE-03.FIRST.dgn,Design Model:395552
6D | U-Value 0.5 - FacadeInsulation :1,SHE_DRAWING+SHEET.dgn,Design Model;4 ,SHE-03.FIRST.dgn,Design Model:395649
6D | U-Value 0.5 - FacadeInsulation :1,SHE_DRAWING+SHEET.dgn,Design Model;4 ,SHE-03.FIRST.dgn,Design Model:395722
6D | U-Value 0.5 - FacadeInsulation :1,SHE_DRAWING+SHEET.dgn,Design Model;4 ,SHE-03.FIRST.dgn,Design Model:395795
6D | U-Value 0.5 - FacadeInsulation :1,SHE_DRAWING+SHEET.dgn,Design Model;4 ,SHE-03.FIRST.dgn,Design Model:395892
6D | U-Value 0.5 - FacadeInsulation :1,SHE_DRAWING+SHEET.dgn,Design Model;4 ,SHE-03.FIRST.dgn,Design Model:395965
6D | U-Value 0.5 - FacadeInsulation :1,SHE_DRAWING+SHEET.dgn,Design Model;4 ,SHE-03.FIRST.dgn,Design Model:396078
6D | U-Value 0.5 - FacadeInsulation :1,SHE_DRAWING+SHEET.dgn,Design Model;4 ,SHE-03.FIRST.dgn,Design Model:396215
6D | U-Value 0.5 - FacadeInsulation :1,SHE_DRAWING+SHEET.dgn,Design Model;4 ,SHE-03.FIRST.dgn,Design Model:396288
6D | U-Value 0.5 - FacadeInsulation :1,SHE_DRAWING+SHEET.dgn,Design Model;4 ,SHE-03.FIRST.dgn,Design Model:396361
6D | U-Value 0.5 - FacadeInsulation :1,SHE_DRAWING+SHEET.dgn,Design Model;4 ,SHE-03.FIRST.dgn,Design Model:396498
6D | U-Value 0.5 - FacadeInsulation :1,SHE_DRAWING+SHEET.dgn,Design Model;4 ,SHE-03.FIRST.dgn,Design Model:396611
6D | U-Value 0.5 - FacadeInsulation :1,SHE_DRAWING+SHEET.dgn,Design Model;4 ,SHE-03.FIRST.dgn,Design Model:396684
6D | U-Value 0.5 - FacadeInsulation :1,SHE_DRAWING+SHEET.dgn,Design Model;4 ,SHE-03.FIRST.dgn,Design Model:396781
6D | U-Value 0.5 - FacadeInsulation :1,SHE_DRAWING+SHEET.dgn,Design Model;4 ,SHE-03.FIRST.dgn,Design Model:396854
6D | U-Value 0.5 - FacadeInsulation :1,SHE_DRAWING+SHEET.dgn,Design Model;4 ,SHE-03.FIRST.dgn,Design Model:396927
6D | U-Value 0.5 - FacadeInsulation :1,SHE_DRAWING+SHEET.dgn,Design Model;4 ,SHE-03.FIRST.dgn,Design Model:397024
6D | U-Value 0.5 - FacadeInsulation :1,SHE_DRAWING+SHEET.dgn,Design Model;4 ,SHE-03.FIRST.dgn,Design Model:397097
6D | U-Value 0.5 - FacadeInsulation :1,SHE_DRAWING+SHEET.dgn,Design Model;4 ,SHE-03.FIRST.dgn,Design Model:397202
6D | U-Value 0.5 - FacadeInsulation :1,SHE_DRAWING+SHEET.dgn,Design Model;4 ,SHE-03.FIRST.dgn,Design Model:397355
6D | U-Value 0.5 - FacadeInsulation :1,SHE_DRAWING+SHEET.dgn,Design Model;4 ,SHE-03.FIRST.dgn,Design Model:397444
6D | U-Value 0.5 - FacadeInsulation :1,SHE_DRAWING+SHEET.dgn,Design Model;4 ,SHE-03.FIRST.dgn,Design Model:397517
6D | U-Value 0.5 - FacadeInsulation :1,SHE_DRAWING+SHEET.dgn,Design Model;4 ,SHE-03.FIRST.dgn,Design Model:397614
6D | U-Value 0.5 - FacadeInsulation :1,SHE_DRAWING+SHEET.dgn,Design Model;4 ,SHE-03.FIRST.dgn,Design Model:397711
6D | U-Value 0.5 - FacadeInsulation :1,SHE_DRAWING+SHEET.dgn,Design Model;4 ,SHE-03.FIRST.dgn,Design Model:398116
6D | U-Value 0.5 - FacadeInsulation :1,SHE_DRAWING+SHEET.dgn,Design Model;4 ,SHE-03.FIRST.dgn,Design Model:398245
6D | U-Value 0.5 - FacadeInsulation :1,SHE_DRAWING+SHEET.dgn,Design Model;4 ,SHE-03.FIRST.dgn,Design Model:398342
6D | U-Value 0.5 - FacadeInsulation :1,SHE_DRAWING+SHEET.dgn,Design Model;4 ,SHE-03.FIRST.dgn,Design Model:398487
6D | U-Value 0.5 - FacadeInsulation :1,SHE_DRAWING+SHEET.dgn,Design Model;4 ,SHE-03.FIRST.dgn,Design Model:398584
6D | U-Value 0.5 - FacadeInsulation :1,SHE_DRAWING+SHEET.dgn,Design Model;4 ,SHE-03.FIRST.dgn,Design Model:398729
6D | U-Value 0.5 - FacadeInsulation :1,SHE_DRAWING+SHEET.dgn,Design Model;4 ,SHE-03.FIRST.dgn,Design Model:398826
6D | U-Value 0.5 - FacadeInsulation :1,SHE_DRAWING+SHEET.dgn,Design Model;4 ,SHE-03.FIRST.dgn,Design Model:398971
6D | U-Value 0.5 - FacadeInsulation :1,SHE_DRAWING+SHEET.dgn,Design Model;4 ,SHE-03.FIRST.dgn,Design Model:399044
6D | U-Value 0.5 - FacadeInsulation :1,SHE_DRAWING+SHEET.dgn,Design Model;4 ,SHE-03.FIRST.dgn,Design Model:399141
6D | U-Value 0.5 - FacadeInsulation :1,SHE_DRAWING+SHEET.dgn,Design Model;4 ,SHE-03.FIRST.dgn,Design Model:399238
6D | U-Value 0.5 - FacadeInsulation :1,SHE_DRAWING+SHEET.dgn,Design Model;4 ,SHE-03.FIRST.dgn,Design Model:399335
6D | U-Value 0.5 - FacadeInsulation :1,SHE_DRAWING+SHEET.dgn,Design Model;4 ,SHE-03.FIRST.dgn,Design Model:399496
6D | U-Value 0.5 - FacadeInsulation :1,SHE_DRAWING+SHEET.dgn,Design Model;4 ,SHE-03.FIRST.dgn,Design Model:399593
6D | U-Value 0.5 - FacadeInsulation :1,SHE_DRAWING+SHEET.dgn,Design Model;4 ,SHE-03.FIRST.dgn,Design Model:399690
6D | U-Value 0.5 - FacadeInsulation :1,SHE_DRAWING+SHEET.dgn,Design Model;4 ,SHE-03.FIRST.dgn,Design Model:399787
6D | U-Value 0.5 - FacadeInsulation :1,SHE_DRAWING+SHEET.dgn,Design Model;4 ,SHE-03.FIRST.dgn,Design Model:399908
6D | U-Value 0.5 - FacadeInsulation :1,SHE_DRAWING+SHEET.dgn,Design Model;4 ,SHE-03.FIRST.dgn,Design Model:400005
6D | U-Value 0.5 - FacadeInsulation :1,SHE_DRAWING+SHEET.dgn,Design Model;4 ,SHE-03.FIRST.dgn,Design Model:400102
6D | U-Value 0.5 - FacadeInsulation :1,SHE_DRAWING+SHEET.dgn,Design Model;4 ,SHE-03.FIRST.dgn,Design Model:400199
6D | U-Value 0.5 - FacadeInsulation :1,SHE_DRAWING+SHEET.dgn,Design Model;4 ,SHE-03.FIRST.dgn,Design Model:400296
6D | U-Value 0.5 - FacadeInsulation :1,SHE_DRAWING+SHEET.dgn,Design Model;4 ,SHE-03.FIRST.dgn,Design Model:400417
6D | U-Value 0.5 - FacadeInsulation :1,SHE_DRAWING+SHEET.dgn,Design Model;4 ,SHE-03.FIRST.dgn,Design Model:400514
6D | U-Value 0.5 - FacadeInsulation :1,SHE_DRAWING+SHEET.dgn,Design Model;4 ,SHE-03.FIRST.dgn,Design Model:400667
6D | U-Value 0.5 - FacadeInsulation :1,SHE_DRAWING+SHEET.dgn,Design Model;4 ,SHE-03.FIRST.dgn,Design Model:400780
6D | U-Value 0.5 - FacadeInsulation :1,SHE_DRAWING+SHEET.dgn,Design Model;4 ,SHE-03.FIRST.dgn,Design Model:400987
6D | U-Value 0.5 - FacadeInsulation :1,SHE_DRAWING+SHEET.dgn,Design Model;4 ,SHE-03.FIRST.dgn,Design Model:401092
6D | U-Value 0.5 - FacadeInsulation :1,SHE_DRAWING+SHEET.dgn,Design Model;6 ,SHE-05.THIRD.dgn,Design Model:141882
6D | U-Value 0.5 - FacadeInsulation :1,SHE_DRAWING+SHEET.dgn,Design Model;6 ,SHE-05.THIRD.dgn,Design Model:141883
6D | U-Value 0.5 - FacadeInsulation :1,SHE_DRAWING+SHEET.dgn,Design Model;6 ,SHE-05.THIRD.dgn,Design Model:141893
6D | U-Value 0.5 - FacadeInsulation :1,SHE_DRAWING+SHEET.dgn,Design Model;6 ,SHE-05.THIRD.dgn,Design Model:141894
6D | U-Value 0.5 - FacadeInsulation :1,SHE_DRAWING+SHEET.dgn,Design Model;6 ,SHE-05.THIRD.dgn,Design Model:141895
6D | U-Value 0.5 - FacadeInsulation :1,SHE_DRAWING+SHEET.dgn,Design Model;6 ,SHE-05.THIRD.dgn,Design Model:141896
6D | U-Value 0.5 - FacadeInsulation :1,SHE_DRAWING+SHEET.dgn,Design Model;6 ,SHE-05.THIRD.dgn,Design Model:141897
6D | U-Value 0.5 - FacadeInsulation :1,SHE_DRAWING+SHEET.dgn,Design Model;6 ,SHE-05.THIRD.dgn,Design Model:141900
6D | U-Value 0.5 - FacadeInsulation :1,SHE_DRAWING+SHEET.dgn,Design Model;6 ,SHE-05.THIRD.dgn,Design Model:141901
6D | U-Value 0.5 - FacadeInsulation :1,SHE_DRAWING+SHEET.dgn,Design Model;6 ,SHE-05.THIRD.dgn,Design Model:141902
6D | U-Value 0.5 - FacadeInsulation :1,SHE_DRAWING+SHEET.dgn,Design Model;6 ,SHE-05.THIRD.dgn,Design Model:141903
6D | U-Value 0.5 - FacadeInsulation :1,SHE_DRAWING+SHEET.dgn,Design Model;6 ,SHE-05.THIRD.dgn,Design Model:141904
6D | U-Value 0.5 - FacadeInsulation :1,SHE_DRAWING+SHEET.dgn,Design Model;6 ,SHE-05.THIRD.dgn,Design Model:141907
6D | U-Value 0.5 - FacadeInsulation :1,SHE_DRAWING+SHEET.dgn,Design Model;6 ,SHE-05.THIRD.dgn,Design Model:141908
6D | U-Value 0.5 - FacadeInsulation :1,SHE_DRAWING+SHEET.dgn,Design Model;6 ,SHE-05.THIRD.dgn,Design Model:141909
6D | U-Value 0.5 - FacadeInsulation :1,SHE_DRAWING+SHEET.dgn,Design Model;6 ,SHE-05.THIRD.dgn,Design Model:141910
6D | U-Value 0.5 - FacadeInsulation :1,SHE_DRAWING+SHEET.dgn,Design Model;6 ,SHE-05.THIRD.dgn,Design Model:141911
6D | U-Value 0.5 - FacadeInsulation :1,SHE_DRAWING+SHEET.dgn,Design Model;6 ,SHE-05.THIRD.dgn,Design Model:141912
6D | U-Value 0.5 - FacadeInsulation :1,SHE_DRAWING+SHEET.dgn,Design Model;6 ,SHE-05.THIRD.dgn,Design Model:141913
6D | U-Value 0.5 - FacadeInsulation :1,SHE_DRAWING+SHEET.dgn,Design Model;6 ,SHE-05.THIRD.dgn,Design Model:141914
6D | U-Value 0.5 - FacadeInsulation :1,SHE_DRAWING+SHEET.dgn,Design Model;6 ,SHE-05.THIRD.dgn,Design Model:141917
6D | U-Value 0.5 - FacadeInsulation :1,SHE_DRAWING+SHEET.dgn,Design Model;6 ,SHE-05.THIRD.dgn,Design Model:141918
6D | U-Value 0.5 - FacadeInsulation :1,SHE_DRAWING+SHEET.dgn,Design Model;6 ,SHE-05.THIRD.dgn,Design Model:141919
6D | U-Value 0.5 - FacadeInsulation :1,SHE_DRAWING+SHEET.dgn,Design Model;6 ,SHE-05.THIRD.dgn,Design Model:141920
6D | U-Value 0.5 - FacadeInsulation :1,SHE_DRAWING+SHEET.dgn,Design Model;6 ,SHE-05.THIRD.dgn,Design Model:141921
6D | U-Value 0.5 - FacadeInsulation :1,SHE_DRAWING+SHEET.dgn,Design Model;6 ,SHE-05.THIRD.dgn,Design Model:141922
6D | U-Value 0.5 - FacadeInsulation :1,SHE_DRAWING+SHEET.dgn,Design Model;6 ,SHE-05.THIRD.dgn,Design Model:141923
6D | U-Value 0.5 - FacadeInsulation :1,SHE_DRAWING+SHEET.dgn,Design Model;6 ,SHE-05.THIRD.dgn,Design Model:141924
6D | U-Value 0.5 - FacadeInsulation :1,SHE_DRAWING+SHEET.dgn,Design Model;6 ,SHE-05.THIRD.dgn,Design Model:141927
6D | U-Value 0.5 - FacadeInsulation :1,SHE_DRAWING+SHEET.dgn,Design Model;6 ,SHE-05.THIRD.dgn,Design Model:141928
6D | U-Value 0.5 - FacadeInsulation :1,SHE_DRAWING+SHEET.dgn,Design Model;6 ,SHE-05.THIRD.dgn,Design Model:141929
6D | U-Value 0.5 - FacadeInsulation :1,SHE_DRAWING+SHEET.dgn,Design Model;6 ,SHE-05.THIRD.dgn,Design Model:141931
6D | U-Value 0.5 - FacadeInsulation :1,SHE_DRAWING+SHEET.dgn,Design Model;6 ,SHE-05.THIRD.dgn,Design Model:141934
6D | U-Value 0.5 - FacadeInsulation :1,SHE_DRAWING+SHEET.dgn,Design Model;6 ,SHE-05.THIRD.dgn,Design Model:141938
6D | U-Value 0.5 - FacadeInsulation :1,SHE_DRAWING+SHEET.dgn,Design Model;6 ,SHE-05.THIRD.dgn,Design Model:141939
6D | U-Value 0.5 - FacadeInsulation :1,SHE_DRAWING+SHEET.dgn,Design Model;6 ,SHE-05.THIRD.dgn,Design Model:141940
6D | U-Value 0.5 - FacadeInsulation :1,SHE_DRAWING+SHEET.dgn,Design Model;6 ,SHE-05.THIRD.dgn,Design Model:141941
6D | U-Value 0.5 - FacadeInsulation :1,SHE_DRAWING+SHEET.dgn,Design Model;6 ,SHE-05.THIRD.dgn,Design Model:141942
6D | U-Value 0.5 - FacadeInsulation :1,SHE_DRAWING+SHEET.dgn,Design Model;6 ,SHE-05.THIRD.dgn,Design Model:141943
6D | U-Value 0.5 - FacadeInsulation :1,SHE_DRAWING+SHEET.dgn,Design Model;6 ,SHE-05.THIRD.dgn,Design Model:141944
6D | U-Value 0.5 - FacadeInsulation :1,SHE_DRAWING+SHEET.dgn,Design Model;6 ,SHE-05.THIRD.dgn,Design Model:141945
6D | U-Value 0.5 - FacadeInsulation :1,SHE_DRAWING+SHEET.dgn,Design Model;6 ,SHE-05.THIRD.dgn,Design Model:141948
6D | U-Value 0.5 - FacadeInsulation :1,SHE_DRAWING+SHEET.dgn,Design Model;6 ,SHE-05.THIRD.dgn,Design Model:141949
6D | U-Value 0.5 - FacadeInsulation :1,SHE_DRAWING+SHEET.dgn,Design Model;6 ,SHE-05.THIRD.dgn,Design Model:141950
6D | U-Value 0.5 - FacadeInsulation :1,SHE_DRAWING+SHEET.dgn,Design Model;6 ,SHE-05.THIRD.dgn,Design Model:141951
6D | U-Value 0.5 - FacadeInsulation :1,SHE_DRAWING+SHEET.dgn,Design Model;6 ,SHE-05.THIRD.dgn,Design Model:141952
6D | U-Value 0.5 - FacadeInsulation :1,SHE_DRAWING+SHEET.dgn,Design Model;6 ,SHE-05.THIRD.dgn,Design Model:141953
6D | U-Value 0.5 - FacadeInsulation :1,SHE_DRAWING+SHEET.dgn,Design Model;6 ,SHE-05.THIRD.dgn,Design Model:141954
6D | U-Value 0.5 - FacadeInsulation :1,SHE_DRAWING+SHEET.dgn,Design Model;6 ,SHE-05.THIRD.dgn,Design Model:141955
6D | U-Value 0.5 - FacadeInsulation :1,SHE_DRAWING+SHEET.dgn,Design Model;6 ,SHE-05.THIRD.dgn,Design Model:141956
6D | U-Value 0.5 - FacadeInsulation :1,SHE_DRAWING+SHEET.dgn,Design Model;6 ,SHE-05.THIRD.dgn,Design Model:141957
6D | U-Value 0.5 - FacadeInsulation :1,SHE_DRAWING+SHEET.dgn,Design Model;6 ,SHE-05.THIRD.dgn,Design Model:141958
6D | U-Value 0.5 - FacadeInsulation :1,SHE_DRAWING+SHEET.dgn,Design Model;6 ,SHE-05.THIRD.dgn,Design Model:141959
6D | U-Value 0.5 - FacadeInsulation :1,SHE_DRAWING+SHEET.dgn,Design Model;6 ,SHE-05.THIRD.dgn,Design Model:141960
6D | U-Value 0.5 - FacadeInsulation :1,SHE_DRAWING+SHEET.dgn,Design Model;6 ,SHE-05.THIRD.dgn,Design Model:141961
6D | U-Value 0.5 - FacadeInsulation :1,SHE_DRAWING+SHEET.dgn,Design Model;6 ,SHE-05.THIRD.dgn,Design Model:141962
6D | U-Value 0.5 - FacadeInsulation :1,SHE_DRAWING+SHEET.dgn,Design Model;6 ,SHE-05.THIRD.dgn,Design Model:141965
6D | U-Value 0.5 - FacadeInsulation :1,SHE_DRAWING+SHEET.dgn,Design Model;6 ,SHE-05.THIRD.dgn,Design Model:141966
6D | U-Value 0.5 - FacadeInsulation :1,SHE_DRAWING+SHEET.dgn,Design Model;6 ,SHE-05.THIRD.dgn,Design Model:141967
6D | U-Value 0.5 - FacadeInsulation :1,SHE_DRAWING+SHEET.dgn,Design Model;6 ,SHE-05.THIRD.dgn,Design Model:141968
6D | U-Value 0.5 - FacadeInsulation :1,SHE_DRAWING+SHEET.dgn,Design Model;6 ,SHE-05.THIRD.dgn,Design Model:141969
6D | U-Value 0.5 - FacadeInsulation :1,SHE_DRAWING+SHEET.dgn,Design Model;6 ,SHE-05.THIRD.dgn,Design Model:141978
6D | U-Value 0.5 - FacadeInsulation :1,SHE_DRAWING+SHEET.dgn,Design Model;6 ,SHE-05.THIRD.dgn,Design Model:141979
6D | U-Value 0.5 - FacadeInsulation :1,SHE_DRAWING+SHEET.dgn,Design Model;6 ,SHE-05.THIRD.dgn,Design Model:141980
6D | U-Value 0.5 - FacadeInsulation :1,SHE_DRAWING+SHEET.dgn,Design Model;6 ,SHE-05.THIRD.dgn,Design Model:142263
6D | U-Value 0.5 - FacadeInsulation :1,SHE_DRAWING+SHEET.dgn,Design Model;6 ,SHE-05.THIRD.dgn,Design Model:142268
6D | U-Value 0.5 - FacadeInsulation :1,SHE_DRAWING+SHEET.dgn,Design Model;6 ,SHE-05.THIRD.dgn,Design Model:142542
6D | U-Value 0.5 - FacadeInsulation :1,SHE_DRAWING+SHEET.dgn,Design Model;6 ,SHE-05.THIRD.dgn,Design Model:171807
6D | U-Value 0.5 - FacadeInsulation :1,SHE_DRAWING+SHEET.dgn,Design Model;18 ,SHE-04.SECOND.dgn,Design Model:141882
6D | U-Value 0.5 - FacadeInsulation :1,SHE_DRAWING+SHEET.dgn,Design Model;18 ,SHE-04.SECOND.dgn,Design Model:141883
6D | U-Value 0.5 - FacadeInsulation :1,SHE_DRAWING+SHEET.dgn,Design Model;18 ,SHE-04.SECOND.dgn,Design Model:141893
6D | U-Value 0.5 - FacadeInsulation :1,SHE_DRAWING+SHEET.dgn,Design Model;18 ,SHE-04.SECOND.dgn,Design Model:141894
6D | U-Value 0.5 - FacadeInsulation :1,SHE_DRAWING+SHEET.dgn,Design Model;18 ,SHE-04.SECOND.dgn,Design Model:141895
6D | U-Value 0.5 - FacadeInsulation :1,SHE_DRAWING+SHEET.dgn,Design Model;18 ,SHE-04.SECOND.dgn,Design Model:141896
6D | U-Value 0.5 - FacadeInsulation :1,SHE_DRAWING+SHEET.dgn,Design Model;18 ,SHE-04.SECOND.dgn,Design Model:141897
6D | U-Value 0.5 - FacadeInsulation :1,SHE_DRAWING+SHEET.dgn,Design Model;18 ,SHE-04.SECOND.dgn,Design Model:141900
6D | U-Value 0.5 - FacadeInsulation :1,SHE_DRAWING+SHEET.dgn,Design Model;18 ,SHE-04.SECOND.dgn,Design Model:141901
6D | U-Value 0.5 - FacadeInsulation :1,SHE_DRAWING+SHEET.dgn,Design Model;18 ,SHE-04.SECOND.dgn,Design Model:141902
6D | U-Value 0.5 - FacadeInsulation :1,SHE_DRAWING+SHEET.dgn,Design Model;18 ,SHE-04.SECOND.dgn,Design Model:141903
6D | U-Value 0.5 - FacadeInsulation :1,SHE_DRAWING+SHEET.dgn,Design Model;18 ,SHE-04.SECOND.dgn,Design Model:141904
6D | U-Value 0.5 - FacadeInsulation :1,SHE_DRAWING+SHEET.dgn,Design Model;18 ,SHE-04.SECOND.dgn,Design Model:141907
6D | U-Value 0.5 - FacadeInsulation :1,SHE_DRAWING+SHEET.dgn,Design Model;18 ,SHE-04.SECOND.dgn,Design Model:141908
6D | U-Value 0.5 - FacadeInsulation :1,SHE_DRAWING+SHEET.dgn,Design Model;18 ,SHE-04.SECOND.dgn,Design Model:141909
6D | U-Value 0.5 - FacadeInsulation :1,SHE_DRAWING+SHEET.dgn,Design Model;18 ,SHE-04.SECOND.dgn,Design Model:141910
6D | U-Value 0.5 - FacadeInsulation :1,SHE_DRAWING+SHEET.dgn,Design Model;18 ,SHE-04.SECOND.dgn,Design Model:141911
6D | U-Value 0.5 - FacadeInsulation :1,SHE_DRAWING+SHEET.dgn,Design Model;18 ,SHE-04.SECOND.dgn,Design Model:141912
6D | U-Value 0.5 - FacadeInsulation :1,SHE_DRAWING+SHEET.dgn,Design Model;18 ,SHE-04.SECOND.dgn,Design Model:141913
6D | U-Value 0.5 - FacadeInsulation :1,SHE_DRAWING+SHEET.dgn,Design Model;18 ,SHE-04.SECOND.dgn,Design Model:141914
6D | U-Value 0.5 - FacadeInsulation :1,SHE_DRAWING+SHEET.dgn,Design Model;18 ,SHE-04.SECOND.dgn,Design Model:141917
6D | U-Value 0.5 - FacadeInsulation :1,SHE_DRAWING+SHEET.dgn,Design Model;18 ,SHE-04.SECOND.dgn,Design Model:141918
6D | U-Value 0.5 - FacadeInsulation :1,SHE_DRAWING+SHEET.dgn,Design Model;18 ,SHE-04.SECOND.dgn,Design Model:141919
6D | U-Value 0.5 - FacadeInsulation :1,SHE_DRAWING+SHEET.dgn,Design Model;18 ,SHE-04.SECOND.dgn,Design Model:141920
6D | U-Value 0.5 - FacadeInsulation :1,SHE_DRAWING+SHEET.dgn,Design Model;18 ,SHE-04.SECOND.dgn,Design Model:141921
6D | U-Value 0.5 - FacadeInsulation :1,SHE_DRAWING+SHEET.dgn,Design Model;18 ,SHE-04.SECOND.dgn,Design Model:141922
6D | U-Value 0.5 - FacadeInsulation :1,SHE_DRAWING+SHEET.dgn,Design Model;18 ,SHE-04.SECOND.dgn,Design Model:141923
6D | U-Value 0.5 - FacadeInsulation :1,SHE_DRAWING+SHEET.dgn,Design Model;18 ,SHE-04.SECOND.dgn,Design Model:141924
6D | U-Value 0.5 - FacadeInsulation :1,SHE_DRAWING+SHEET.dgn,Design Model;18 ,SHE-04.SECOND.dgn,Design Model:141927
6D | U-Value 0.5 - FacadeInsulation :1,SHE_DRAWING+SHEET.dgn,Design Model;18 ,SHE-04.SECOND.dgn,Design Model:141928
6D | U-Value 0.5 - FacadeInsulation :1,SHE_DRAWING+SHEET.dgn,Design Model;18 ,SHE-04.SECOND.dgn,Design Model:141929
6D | U-Value 0.5 - FacadeInsulation :1,SHE_DRAWING+SHEET.dgn,Design Model;18 ,SHE-04.SECOND.dgn,Design Model:141931
6D | U-Value 0.5 - FacadeInsulation :1,SHE_DRAWING+SHEET.dgn,Design Model;18 ,SHE-04.SECOND.dgn,Design Model:141934
6D | U-Value 0.5 - FacadeInsulation :1,SHE_DRAWING+SHEET.dgn,Design Model;18 ,SHE-04.SECOND.dgn,Design Model:141938
6D | U-Value 0.5 - FacadeInsulation :1,SHE_DRAWING+SHEET.dgn,Design Model;18 ,SHE-04.SECOND.dgn,Design Model:141939
6D | U-Value 0.5 - FacadeInsulation :1,SHE_DRAWING+SHEET.dgn,Design Model;18 ,SHE-04.SECOND.dgn,Design Model:141940
6D | U-Value 0.5 - FacadeInsulation :1,SHE_DRAWING+SHEET.dgn,Design Model;18 ,SHE-04.SECOND.dgn,Design Model:141941
6D | U-Value 0.5 - FacadeInsulation :1,SHE_DRAWING+SHEET.dgn,Design Model;18 ,SHE-04.SECOND.dgn,Design Model:141942
6D | U-Value 0.5 - FacadeInsulation :1,SHE_DRAWING+SHEET.dgn,Design Model;18 ,SHE-04.SECOND.dgn,Design Model:141943
6D | U-Value 0.5 - FacadeInsulation :1,SHE_DRAWING+SHEET.dgn,Design Model;18 ,SHE-04.SECOND.dgn,Design Model:141944
6D | U-Value 0.5 - FacadeInsulation :1,SHE_DRAWING+SHEET.dgn,Design Model;18 ,SHE-04.SECOND.dgn,Design Model:141945
6D | U-Value 0.5 - FacadeInsulation :1,SHE_DRAWING+SHEET.dgn,Design Model;18 ,SHE-04.SECOND.dgn,Design Model:141948
6D | U-Value 0.5 - FacadeInsulation :1,SHE_DRAWING+SHEET.dgn,Design Model;18 ,SHE-04.SECOND.dgn,Design Model:141949
6D | U-Value 0.5 - FacadeInsulation :1,SHE_DRAWING+SHEET.dgn,Design Model;18 ,SHE-04.SECOND.dgn,Design Model:141950
6D | U-Value 0.5 - FacadeInsulation :1,SHE_DRAWING+SHEET.dgn,Design Model;18 ,SHE-04.SECOND.dgn,Design Model:141951
6D | U-Value 0.5 - FacadeInsulation :1,SHE_DRAWING+SHEET.dgn,Design Model;18 ,SHE-04.SECOND.dgn,Design Model:141952
6D | U-Value 0.5 - FacadeInsulation :1,SHE_DRAWING+SHEET.dgn,Design Model;18 ,SHE-04.SECOND.dgn,Design Model:141953
6D | U-Value 0.5 - FacadeInsulation :1,SHE_DRAWING+SHEET.dgn,Design Model;18 ,SHE-04.SECOND.dgn,Design Model:141954
6D | U-Value 0.5 - FacadeInsulation :1,SHE_DRAWING+SHEET.dgn,Design Model;18 ,SHE-04.SECOND.dgn,Design Model:141955
6D | U-Value 0.5 - FacadeInsulation :1,SHE_DRAWING+SHEET.dgn,Design Model;18 ,SHE-04.SECOND.dgn,Design Model:141956
6D | U-Value 0.5 - FacadeInsulation :1,SHE_DRAWING+SHEET.dgn,Design Model;18 ,SHE-04.SECOND.dgn,Design Model:141957
6D | U-Value 0.5 - FacadeInsulation :1,SHE_DRAWING+SHEET.dgn,Design Model;18 ,SHE-04.SECOND.dgn,Design Model:141958
6D | U-Value 0.5 - FacadeInsulation :1,SHE_DRAWING+SHEET.dgn,Design Model;18 ,SHE-04.SECOND.dgn,Design Model:141959
6D | U-Value 0.5 - FacadeInsulation :1,SHE_DRAWING+SHEET.dgn,Design Model;18 ,SHE-04.SECOND.dgn,Design Model:141960
6D | U-Value 0.5 - FacadeInsulation :1,SHE_DRAWING+SHEET.dgn,Design Model;18 ,SHE-04.SECOND.dgn,Design Model:141961
6D | U-Value 0.5 - FacadeInsulation :1,SHE_DRAWING+SHEET.dgn,Design Model;18 ,SHE-04.SECOND.dgn,Design Model:141962
6D | U-Value 0.5 - FacadeInsulation :1,SHE_DRAWING+SHEET.dgn,Design Model;18 ,SHE-04.SECOND.dgn,Design Model:141965
6D | U-Value 0.5 - FacadeInsulation :1,SHE_DRAWING+SHEET.dgn,Design Model;18 ,SHE-04.SECOND.dgn,Design Model:141966
6D | U-Value 0.5 - FacadeInsulation :1,SHE_DRAWING+SHEET.dgn,Design Model;18 ,SHE-04.SECOND.dgn,Design Model:141967
6D | U-Value 0.5 - FacadeInsulation :1,SHE_DRAWING+SHEET.dgn,Design Model;18 ,SHE-04.SECOND.dgn,Design Model:141968
6D | U-Value 0.5 - FacadeInsulation :1,SHE_DRAWING+SHEET.dgn,Design Model;18 ,SHE-04.SECOND.dgn,Design Model:141969
6D | U-Value 0.5 - FacadeInsulation :1,SHE_DRAWING+SHEET.dgn,Design Model;18 ,SHE-04.SECOND.dgn,Design Model:141978
6D | U-Value 0.5 - FacadeInsulation :1,SHE_DRAWING+SHEET.dgn,Design Model;18 ,SHE-04.SECOND.dgn,Design Model:141979
6D | U-Value 0.5 - FacadeInsulation :1,SHE_DRAWING+SHEET.dgn,Design Model;18 ,SHE-04.SECOND.dgn,Design Model:141980
6D | U-Value 0.5 - FacadeInsulation :1,SHE_DRAWING+SHEET.dgn,Design Model;18 ,SHE-04.SECOND.dgn,Design Model:142263
6D | U-Value 0.5 - FacadeInsulation :1,SHE_DRAWING+SHEET.dgn,Design Model;18 ,SHE-04.SECOND.dgn,Design Model:142268
6D | U-Value 0.5 - FacadeInsulation :1,SHE_DRAWING+SHEET.dgn,Design Model;18 ,SHE-04.SECOND.dgn,Design Model:142542
6D | U-Value 0.5 - FacadeInsulation :1,SHE_DRAWING+SHEET.dgn,Design Model;18 ,SHE-04.SECOND.dgn,Design Model:171807

# IfcWall: SHE_A-Walls_Type06e_ExternalWallPenthouse_280mm (32)
In: RL
Type - Description: SHE_A-Walls_Type06e_ExternalWallPenthouse_280mm
Type - Wall Parameters - Type: Wall; Compound Wall Assembly: yes
Type - Thermal Transmittance - Is External: no; Is Below Grade: no
Type - Space Bounding - Is Space Bounding: yes
Type - Materials - Part Definition: A-CompoundWalls::SHE_A-Walls_Type06e_ExternalWallPenthouse_280mm
Type - LEED Parameters - LEED | Pre-consumer Recycled (%): 0; LEED | Regional Material: no; LEED | Post-consumer Recycled (%): 0
Type - Identification - ID | Description: SHE_A-Walls_Type06e_ExternalWallPenthouse_280mm
Type - Fire Resistance - Fire | IsCombustible: no; Fire | Compartmentation: no; Fire | Surface Spread of Flame: A2-s1,d0 or better
Type - Discipline - Discipline: Architectural
Type - Construction Phase - Phase: New Construction
Type - Classification - Uniclass2015: EF_25_10
Type - Acoustical Parameters - Acoustic Rating (STC): (min. Rw+Ctr 48)
Pset_WallCommon - AcousticRating: Rw 52dB , Rw+Ctr 48dB; Combustible: no; Compartmentation: no; FireRating: F60; IsExternal: no; LoadBearing: no; SurfaceSpreadOfFlame: A2-s1 ,d0 or better
Identification - ID | Type ID: U-Value 0.18; ID | Number: 6E; ID | Description: SFSWall; ID | Notes: SHE_A-Walls_Type06e_ExternalWallPenthouse_280mm
Fire Resistance - Fire | Rating: F60
Acoustical Parameters - Acoustic Rating (STC): Rw 52dB , Rw+Ctr 48dB
Name | Description
6E | U-Value 0.18 - SFSWall :1 ,SHE_DRAWING+SHEET.dgn,Design Model;7,SHE-06.FOURTH.dgn,Design Model:376624
6E | U-Value 0.18 - SFSWall :1 ,SHE_DRAWING+SHEET.dgn,Design Model;7,SHE-06.FOURTH.dgn,Design Model:376764
6E | U-Value 0.18 - SFSWall :1 ,SHE_DRAWING+SHEET.dgn,Design Model;7,SHE-06.FOURTH.dgn,Design Model:376873
6E | U-Value 0.18 - SFSWall :1 ,SHE_DRAWING+SHEET.dgn,Design Model;7,SHE-06.FOURTH.dgn,Design Model:376874
6E | U-Value 0.18 - SFSWall :1 ,SHE_DRAWING+SHEET.dgn,Design Model;7,SHE-06.FOURTH.dgn,Design Model:377033
6E | U-Value 0.18 - SFSWall :1 ,SHE_DRAWING+SHEET.dgn,Design Model;7,SHE-06.FOURTH.dgn,Design Model:377082
6E | U-Value 0.18 - SFSWall :1 ,SHE_DRAWING+SHEET.dgn,Design Model;7,SHE-06.FOURTH.dgn,Design Model:377137
6E | U-Value 0.18 - SFSWall :1 ,SHE_DRAWING+SHEET.dgn,Design Model;7,SHE-06.FOURTH.dgn,Design Model:377192
6E | U-Value 0.18 - SFSWall :1 ,SHE_DRAWING+SHEET.dgn,Design Model;7,SHE-06.FOURTH.dgn,Design Model:377301
6E | U-Value 0.18 - SFSWall :1 ,SHE_DRAWING+SHEET.dgn,Design Model;7,SHE-06.FOURTH.dgn,Design Model:377302
6E | U-Value 0.18 - SFSWall :1 ,SHE_DRAWING+SHEET.dgn,Design Model;7,SHE-06.FOURTH.dgn,Design Model:377411
6E | U-Value 0.18 - SFSWall :1 ,SHE_DRAWING+SHEET.dgn,Design Model;7,SHE-06.FOURTH.dgn,Design Model:377412
6E | U-Value 0.18 - SFSWall :1 ,SHE_DRAWING+SHEET.dgn,Design Model;7,SHE-06.FOURTH.dgn,Design Model:377521
6E | U-Value 0.18 - SFSWall :1 ,SHE_DRAWING+SHEET.dgn,Design Model;7,SHE-06.FOURTH.dgn,Design Model:377522
6E | U-Value 0.18 - SFSWall :1 ,SHE_DRAWING+SHEET.dgn,Design Model;7,SHE-06.FOURTH.dgn,Design Model:377631
6E | U-Value 0.18 - SFSWall :1 ,SHE_DRAWING+SHEET.dgn,Design Model;7,SHE-06.FOURTH.dgn,Design Model:377632
6E | U-Value 0.18 - SFSWall :1 ,SHE_DRAWING+SHEET.dgn,Design Model;7,SHE-06.FOURTH.dgn,Design Model:377741
6E | U-Value 0.18 - SFSWall :1 ,SHE_DRAWING+SHEET.dgn,Design Model;7,SHE-06.FOURTH.dgn,Design Model:377742
6E | U-Value 0.18 - SFSWall :1 ,SHE_DRAWING+SHEET.dgn,Design Model;7,SHE-06.FOURTH.dgn,Design Model:377851
6E | U-Value 0.18 - SFSWall :1 ,SHE_DRAWING+SHEET.dgn,Design Model;7,SHE-06.FOURTH.dgn,Design Model:377852
6E | U-Value 0.18 - SFSWall :1 ,SHE_DRAWING+SHEET.dgn,Design Model;7,SHE-06.FOURTH.dgn,Design Model:377961
6E | U-Value 0.18 - SFSWall :1 ,SHE_DRAWING+SHEET.dgn,Design Model;7,SHE-06.FOURTH.dgn,Design Model:377962
6E | U-Value 0.18 - SFSWall :1 ,SHE_DRAWING+SHEET.dgn,Design Model;7,SHE-06.FOURTH.dgn,Design Model:378071
6E | U-Value 0.18 - SFSWall :1 ,SHE_DRAWING+SHEET.dgn,Design Model;7,SHE-06.FOURTH.dgn,Design Model:378072
6E | U-Value 0.18 - SFSWall :1 ,SHE_DRAWING+SHEET.dgn,Design Model;7,SHE-06.FOURTH.dgn,Design Model:378181
6E | U-Value 0.18 - SFSWall :1 ,SHE_DRAWING+SHEET.dgn,Design Model;7,SHE-06.FOURTH.dgn,Design Model:378182
6E | U-Value 0.18 - SFSWall :1 ,SHE_DRAWING+SHEET.dgn,Design Model;8,SHE-07.FIFTH.dgn,Design Model:204325
6E | U-Value 0.18 - SFSWall :1 ,SHE_DRAWING+SHEET.dgn,Design Model;8,SHE-07.FIFTH.dgn,Design Model:204435
6E | U-Value 0.18 - SFSWall :1 ,SHE_DRAWING+SHEET.dgn,Design Model;8,SHE-07.FIFTH.dgn,Design Model:210006
6E | U-Value 0.18 - SFSWall :1 ,SHE_DRAWING+SHEET.dgn,Design Model;8,SHE-07.FIFTH.dgn,Design Model:210116
6E | U-Value 0.18 - SFSWall :1 ,SHE_DRAWING+SHEET.dgn,Design Model;8,SHE-07.FIFTH.dgn,Design Model:212671
6E | U-Value 0.18 - SFSWall :1 ,SHE_DRAWING+SHEET.dgn,Design Model;8,SHE-07.FIFTH.dgn,Design Model:213117

# IfcWall: SHE_A-Walls_Type06f_ExternalWallInsulation_48+15mm (87)
In: RL
Type - Description: SHE_A-Walls_Type06f_ExternalWallInsulation_48+15mm
Type - Wall Parameters - Type: Wall; Compound Wall Assembly: yes
Type - Thermal Transmittance - Is External: no; Is Below Grade: no
Type - Space Bounding - Is Space Bounding: yes
Type - Materials - Part Definition: A-CompoundWalls::SHE_A-Walls_Type06f_ExternalWallInsulation_48+15mm
Type - LEED Parameters - LEED | Pre-consumer Recycled (%): 0; LEED | Regional Material: no; LEED | Post-consumer Recycled (%): 0
Type - Identification - ID | Description: SHE_A-Walls_Type06f_ExternalWallInsulation_48+15mm
Type - Fire Resistance - Fire | IsCombustible: no; Fire | Compartmentation: no
Type - Discipline - Discipline: Architectural
Type - Construction Phase - Phase: New Construction
Type - Classification - Uniclass2015: EF_25_10
Pset_WallCommon - Combustible: no; Compartmentation: no; FireRating: F60; IsExternal: no; LoadBearing: no
Identification - ID | Type ID: U-Value 0.5; ID | Number: 6F; ID | Description: FacadeInsulation; ID | Keynote: https://www.british-gyp sum.com/products/board-products/gyproc-thermaline-plus-48mm; ID | Notes: SHE_A-Walls_Type06f_ExternalWallInsulation_48+15mm
Fire Resistance - Fire | Rating: F60
Name | Description | AcousticRating = Acoustic Rating (STC)
6F | U-Value 0.5 - FacadeInsulation :1,SHE_DRAWING+SHEET.dgn,Design Model;4 ,SHE-03.FIRST.dgn,Design Model:376780 | req. 48
6F | U-Value 0.5 - FacadeInsulation :1,SHE_DRAWING+SHEET.dgn,Design Model;4 ,SHE-03.FIRST.dgn,Design Model:376817 | req. 48
6F | U-Value 0.5 - FacadeInsulation :1,SHE_DRAWING+SHEET.dgn,Design Model;4 ,SHE-03.FIRST.dgn,Design Model:376854 | req. 48
6F | U-Value 0.5 - FacadeInsulation :1,SHE_DRAWING+SHEET.dgn,Design Model;4 ,SHE-03.FIRST.dgn,Design Model:376928 | req. 48
6F | U-Value 0.5 - FacadeInsulation :1,SHE_DRAWING+SHEET.dgn,Design Model;4 ,SHE-03.FIRST.dgn,Design Model:376965 | req. 48
6F | U-Value 0.5 - FacadeInsulation :1,SHE_DRAWING+SHEET.dgn,Design Model;4 ,SHE-03.FIRST.dgn,Design Model:377002 | req. 48
6F | U-Value 0.5 - FacadeInsulation :1,SHE_DRAWING+SHEET.dgn,Design Model;4 ,SHE-03.FIRST.dgn,Design Model:377872 | req. 48
6F | U-Value 0.5 - FacadeInsulation :1,SHE_DRAWING+SHEET.dgn,Design Model;4 ,SHE-03.FIRST.dgn,Design Model:378370
6F | U-Value 0.5 - FacadeInsulation :1,SHE_DRAWING+SHEET.dgn,Design Model;4 ,SHE-03.FIRST.dgn,Design Model:378444
6F | U-Value 0.5 - FacadeInsulation :1,SHE_DRAWING+SHEET.dgn,Design Model;4 ,SHE-03.FIRST.dgn,Design Model:378833
6F | U-Value 0.5 - FacadeInsulation :1,SHE_DRAWING+SHEET.dgn,Design Model;4 ,SHE-03.FIRST.dgn,Design Model:381139
6F | U-Value 0.5 - FacadeInsulation :1,SHE_DRAWING+SHEET.dgn,Design Model;4 ,SHE-03.FIRST.dgn,Design Model:381140
6F | U-Value 0.5 - FacadeInsulation :1,SHE_DRAWING+SHEET.dgn,Design Model;4 ,SHE-03.FIRST.dgn,Design Model:381141
6F | U-Value 0.5 - FacadeInsulation :1,SHE_DRAWING+SHEET.dgn,Design Model;4 ,SHE-03.FIRST.dgn,Design Model:383873 | req. 48
6F | U-Value 0.5 - FacadeInsulation :1,SHE_DRAWING+SHEET.dgn,Design Model;4 ,SHE-03.FIRST.dgn,Design Model:383910 | req. 48
6F | U-Value 0.5 - FacadeInsulation :1,SHE_DRAWING+SHEET.dgn,Design Model;4 ,SHE-03.FIRST.dgn,Design Model:383947 | req. 48
6F | U-Value 0.5 - FacadeInsulation :1,SHE_DRAWING+SHEET.dgn,Design Model;4 ,SHE-03.FIRST.dgn,Design Model:383984 | req. 48
6F | U-Value 0.5 - FacadeInsulation :1,SHE_DRAWING+SHEET.dgn,Design Model;4 ,SHE-03.FIRST.dgn,Design Model:384021 | req. 48
6F | U-Value 0.5 - FacadeInsulation :1,SHE_DRAWING+SHEET.dgn,Design Model;4 ,SHE-03.FIRST.dgn,Design Model:384058 | req. 48
6F | U-Value 0.5 - FacadeInsulation :1,SHE_DRAWING+SHEET.dgn,Design Model;4 ,SHE-03.FIRST.dgn,Design Model:384095 | req. 48
6F | U-Value 0.5 - FacadeInsulation :1,SHE_DRAWING+SHEET.dgn,Design Model;4 ,SHE-03.FIRST.dgn,Design Model:387639 | req. 48
6F | U-Value 0.5 - FacadeInsulation :1,SHE_DRAWING+SHEET.dgn,Design Model;4 ,SHE-03.FIRST.dgn,Design Model:387945 | req. 48
6F | U-Value 0.5 - FacadeInsulation :1,SHE_DRAWING+SHEET.dgn,Design Model;4 ,SHE-03.FIRST.dgn,Design Model:388254 | req. 48
6F | U-Value 0.5 - FacadeInsulation :1,SHE_DRAWING+SHEET.dgn,Design Model;4 ,SHE-03.FIRST.dgn,Design Model:388591 | req. 48
6F | U-Value 0.5 - FacadeInsulation :1,SHE_DRAWING+SHEET.dgn,Design Model;4 ,SHE-03.FIRST.dgn,Design Model:388592 | req. 48
6F | U-Value 0.5 - FacadeInsulation :1,SHE_DRAWING+SHEET.dgn,Design Model;4 ,SHE-03.FIRST.dgn,Design Model:388593 | req. 48
6F | U-Value 0.5 - FacadeInsulation :1,SHE_DRAWING+SHEET.dgn,Design Model;4 ,SHE-03.FIRST.dgn,Design Model:389291 | req. 48
6F | U-Value 0.5 - FacadeInsulation :1,SHE_DRAWING+SHEET.dgn,Design Model;4 ,SHE-03.FIRST.dgn,Design Model:389292 | req. 48
6F | U-Value 0.5 - FacadeInsulation :1,SHE_DRAWING+SHEET.dgn,Design Model;4 ,SHE-03.FIRST.dgn,Design Model:389293 | req. 48
6F | U-Value 0.5 - FacadeInsulation :1,SHE_DRAWING+SHEET.dgn,Design Model;6 ,SHE-05.THIRD.dgn,Design Model:445172 | req. 48
6F | U-Value 0.5 - FacadeInsulation :1,SHE_DRAWING+SHEET.dgn,Design Model;6 ,SHE-05.THIRD.dgn,Design Model:445209 | req. 48
6F | U-Value 0.5 - FacadeInsulation :1,SHE_DRAWING+SHEET.dgn,Design Model;6 ,SHE-05.THIRD.dgn,Design Model:445448 | req. 48
6F | U-Value 0.5 - FacadeInsulation :1,SHE_DRAWING+SHEET.dgn,Design Model;6 ,SHE-05.THIRD.dgn,Design Model:445449 | req. 48
6F | U-Value 0.5 - FacadeInsulation :1,SHE_DRAWING+SHEET.dgn,Design Model;6 ,SHE-05.THIRD.dgn,Design Model:445672 | req. 48
6F | U-Value 0.5 - FacadeInsulation :1,SHE_DRAWING+SHEET.dgn,Design Model;6 ,SHE-05.THIRD.dgn,Design Model:445673 | req. 48
6F | U-Value 0.5 - FacadeInsulation :1,SHE_DRAWING+SHEET.dgn,Design Model;6 ,SHE-05.THIRD.dgn,Design Model:445784 | req. 48
6F | U-Value 0.5 - FacadeInsulation :1,SHE_DRAWING+SHEET.dgn,Design Model;6 ,SHE-05.THIRD.dgn,Design Model:445785 | req. 48
6F | U-Value 0.5 - FacadeInsulation :1,SHE_DRAWING+SHEET.dgn,Design Model;6 ,SHE-05.THIRD.dgn,Design Model:445896 | req. 48
6F | U-Value 0.5 - FacadeInsulation :1,SHE_DRAWING+SHEET.dgn,Design Model;6 ,SHE-05.THIRD.dgn,Design Model:445897 | req. 48
6F | U-Value 0.5 - FacadeInsulation :1,SHE_DRAWING+SHEET.dgn,Design Model;6 ,SHE-05.THIRD.dgn,Design Model:446007 | req. 48
6F | U-Value 0.5 - FacadeInsulation :1,SHE_DRAWING+SHEET.dgn,Design Model;6 ,SHE-05.THIRD.dgn,Design Model:446008 | req. 48
6F | U-Value 0.5 - FacadeInsulation :1,SHE_DRAWING+SHEET.dgn,Design Model;6 ,SHE-05.THIRD.dgn,Design Model:446009 | req. 48
6F | U-Value 0.5 - FacadeInsulation :1,SHE_DRAWING+SHEET.dgn,Design Model;6 ,SHE-05.THIRD.dgn,Design Model:446112 | req. 48
6F | U-Value 0.5 - FacadeInsulation :1,SHE_DRAWING+SHEET.dgn,Design Model;6 ,SHE-05.THIRD.dgn,Design Model:446149 | req. 48
6F | U-Value 0.5 - FacadeInsulation :1,SHE_DRAWING+SHEET.dgn,Design Model;6 ,SHE-05.THIRD.dgn,Design Model:446186 | req. 48
6F | U-Value 0.5 - FacadeInsulation :1,SHE_DRAWING+SHEET.dgn,Design Model;6 ,SHE-05.THIRD.dgn,Design Model:446223 | req. 48
6F | U-Value 0.5 - FacadeInsulation :1,SHE_DRAWING+SHEET.dgn,Design Model;6 ,SHE-05.THIRD.dgn,Design Model:446477 | req. 48
6F | U-Value 0.5 - FacadeInsulation :1,SHE_DRAWING+SHEET.dgn,Design Model;6 ,SHE-05.THIRD.dgn,Design Model:446478 | req. 48
6F | U-Value 0.5 - FacadeInsulation :1,SHE_DRAWING+SHEET.dgn,Design Model;6 ,SHE-05.THIRD.dgn,Design Model:446480 | req. 48
6F | U-Value 0.5 - FacadeInsulation :1,SHE_DRAWING+SHEET.dgn,Design Model;6 ,SHE-05.THIRD.dgn,Design Model:446481 | req. 48
6F | U-Value 0.5 - FacadeInsulation :1,SHE_DRAWING+SHEET.dgn,Design Model;6 ,SHE-05.THIRD.dgn,Design Model:446482 | req. 48
6F | U-Value 0.5 - FacadeInsulation :1,SHE_DRAWING+SHEET.dgn,Design Model;6 ,SHE-05.THIRD.dgn,Design Model:446483 | req. 48
6F | U-Value 0.5 - FacadeInsulation :1,SHE_DRAWING+SHEET.dgn,Design Model;6 ,SHE-05.THIRD.dgn,Design Model:446753 | req. 48
6F | U-Value 0.5 - FacadeInsulation :1,SHE_DRAWING+SHEET.dgn,Design Model;6 ,SHE-05.THIRD.dgn,Design Model:446970 | req. 48
6F | U-Value 0.5 - FacadeInsulation :1,SHE_DRAWING+SHEET.dgn,Design Model;6 ,SHE-05.THIRD.dgn,Design Model:447159 | req. 48
6F | U-Value 0.5 - FacadeInsulation :1,SHE_DRAWING+SHEET.dgn,Design Model;6 ,SHE-05.THIRD.dgn,Design Model:447388 | req. 48
6F | U-Value 0.5 - FacadeInsulation :1,SHE_DRAWING+SHEET.dgn,Design Model;6 ,SHE-05.THIRD.dgn,Design Model:447563 | req. 48
6F | U-Value 0.5 - FacadeInsulation :1,SHE_DRAWING+SHEET.dgn,Design Model;6 ,SHE-05.THIRD.dgn,Design Model:447728 | req. 48
6F | U-Value 0.5 - FacadeInsulation :1,SHE_DRAWING+SHEET.dgn,Design Model;18 ,SHE-04.SECOND.dgn,Design Model:378238 | req. 48
6F | U-Value 0.5 - FacadeInsulation :1,SHE_DRAWING+SHEET.dgn,Design Model;18 ,SHE-04.SECOND.dgn,Design Model:378275 | req. 48
6F | U-Value 0.5 - FacadeInsulation :1,SHE_DRAWING+SHEET.dgn,Design Model;18 ,SHE-04.SECOND.dgn,Design Model:378440 | req. 48
6F | U-Value 0.5 - FacadeInsulation :1,SHE_DRAWING+SHEET.dgn,Design Model;18 ,SHE-04.SECOND.dgn,Design Model:378622 | req. 48
6F | U-Value 0.5 - FacadeInsulation :1,SHE_DRAWING+SHEET.dgn,Design Model;18 ,SHE-04.SECOND.dgn,Design Model:378623 | req. 48
6F | U-Value 0.5 - FacadeInsulation :1,SHE_DRAWING+SHEET.dgn,Design Model;18 ,SHE-04.SECOND.dgn,Design Model:378624 | req. 48
6F | U-Value 0.5 - FacadeInsulation :1,SHE_DRAWING+SHEET.dgn,Design Model;18 ,SHE-04.SECOND.dgn,Design Model:378731 | req. 48
6F | U-Value 0.5 - FacadeInsulation :1,SHE_DRAWING+SHEET.dgn,Design Model;18 ,SHE-04.SECOND.dgn,Design Model:378768 | req. 48
6F | U-Value 0.5 - FacadeInsulation :1,SHE_DRAWING+SHEET.dgn,Design Model;18 ,SHE-04.SECOND.dgn,Design Model:378906 | req. 48
6F | U-Value 0.5 - FacadeInsulation :1,SHE_DRAWING+SHEET.dgn,Design Model;18 ,SHE-04.SECOND.dgn,Design Model:378943 | req. 48
6F | U-Value 0.5 - FacadeInsulation :1,SHE_DRAWING+SHEET.dgn,Design Model;18 ,SHE-04.SECOND.dgn,Design Model:379081 | req. 48
6F | U-Value 0.5 - FacadeInsulation :1,SHE_DRAWING+SHEET.dgn,Design Model;18 ,SHE-04.SECOND.dgn,Design Model:379118 | req. 48
6F | U-Value 0.5 - FacadeInsulation :1,SHE_DRAWING+SHEET.dgn,Design Model;18 ,SHE-04.SECOND.dgn,Design Model:379564 | req. 48
6F | U-Value 0.5 - FacadeInsulation :1,SHE_DRAWING+SHEET.dgn,Design Model;18 ,SHE-04.SECOND.dgn,Design Model:379565 | req. 48
6F | U-Value 0.5 - FacadeInsulation :1,SHE_DRAWING+SHEET.dgn,Design Model;18 ,SHE-04.SECOND.dgn,Design Model:379566 | req. 48
6F | U-Value 0.5 - FacadeInsulation :1,SHE_DRAWING+SHEET.dgn,Design Model;18 ,SHE-04.SECOND.dgn,Design Model:379567 | req. 48
6F | U-Value 0.5 - FacadeInsulation :1,SHE_DRAWING+SHEET.dgn,Design Model;18 ,SHE-04.SECOND.dgn,Design Model:379568 | req. 48
6F | U-Value 0.5 - FacadeInsulation :1,SHE_DRAWING+SHEET.dgn,Design Model;18 ,SHE-04.SECOND.dgn,Design Model:379569 | req. 48
6F | U-Value 0.5 - FacadeInsulation :1,SHE_DRAWING+SHEET.dgn,Design Model;18 ,SHE-04.SECOND.dgn,Design Model:379570 | req. 48
6F | U-Value 0.5 - FacadeInsulation :1,SHE_DRAWING+SHEET.dgn,Design Model;18 ,SHE-04.SECOND.dgn,Design Model:379735 | req. 48
6F | U-Value 0.5 - FacadeInsulation :1,SHE_DRAWING+SHEET.dgn,Design Model;18 ,SHE-04.SECOND.dgn,Design Model:380133 | req. 48
6F | U-Value 0.5 - FacadeInsulation :1,SHE_DRAWING+SHEET.dgn,Design Model;18 ,SHE-04.SECOND.dgn,Design Model:380134 | req. 48
6F | U-Value 0.5 - FacadeInsulation :1,SHE_DRAWING+SHEET.dgn,Design Model;18 ,SHE-04.SECOND.dgn,Design Model:380135 | req. 48
6F | U-Value 0.5 - FacadeInsulation :1,SHE_DRAWING+SHEET.dgn,Design Model;18 ,SHE-04.SECOND.dgn,Design Model:380271 | req. 48
6F | U-Value 0.5 - FacadeInsulation :1,SHE_DRAWING+SHEET.dgn,Design Model;18 ,SHE-04.SECOND.dgn,Design Model:380272 | req. 48
6F | U-Value 0.5 - FacadeInsulation :1,SHE_DRAWING+SHEET.dgn,Design Model;18 ,SHE-04.SECOND.dgn,Design Model:380273 | req. 48
6F | U-Value 0.5 - FacadeInsulation :1,SHE_DRAWING+SHEET.dgn,Design Model;18 ,SHE-04.SECOND.dgn,Design Model:380473 | req. 48
6F | U-Value 0.5 - FacadeInsulation :1,SHE_DRAWING+SHEET.dgn,Design Model;18 ,SHE-04.SECOND.dgn,Design Model:380474 | req. 48
6F | U-Value 0.5 - FacadeInsulation :1,SHE_DRAWING+SHEET.dgn,Design Model;18 ,SHE-04.SECOND.dgn,Design Model:380475 | req. 48

# IfcWall: default (114)
In: RL
Name | Description | Material | Wall Function | Part Definition
default | 1,SHE_DRAWING+SHEET.dgn ,Design Model;4,SHE-03.FIRST.dgn,Design Model:126329 | A_BSUK_WallInternal_Finishes_Plasterboard | Finish | A-Walls::A_BSUK_WallInternal_Finishes_Plasterboard
default | 1,SHE_DRAWING+SHEET.dgn ,Design Model;4,SHE-03.FIRST.dgn,Design Model:126338 | A_BSUK_WallInternal_Finishes_Plasterboard | Finish | A-Walls::A_BSUK_WallInternal_Finishes_Plasterboard
default | 1,SHE_DRAWING+SHEET.dgn ,Design Model;4,SHE-03.FIRST.dgn,Design Model:126347 | A_BSUK_Insulation | Structure | A-Walls::A_BSUK_Insulation
default | 1,SHE_DRAWING+SHEET.dgn ,Design Model;4,SHE-03.FIRST.dgn,Design Model:126356 | A_BSUK_WallInternal_Finishes_Plasterboard | Finish | A-Walls::A_BSUK_WallInternal_Finishes_Plasterboard
default | 1,SHE_DRAWING+SHEET.dgn ,Design Model;4,SHE-03.FIRST.dgn,Design Model:126365 | A_BSUK_WallInternal_Finishes_Plasterboard | Finish | A-Walls::A_BSUK_WallInternal_Finishes_Plasterboard
default | 1,SHE_DRAWING+SHEET.dgn ,Design Model;4,SHE-03.FIRST.dgn,Design Model:126374 | A_BSUK_Walls_Timber | Finish | A-Walls::A_BSUK_Walls_Timber
default | 1,SHE_DRAWING+SHEET.dgn ,Design Model;4,SHE-03.FIRST.dgn,Design Model:126646 | A_BSUK_WallInternal_Finishes_Plasterboard |  | A-Walls::A_BSUK_WallInternal_Finishes_Plasterboard
default | 1,SHE_DRAWING+SHEET.dgn ,Design Model;4,SHE-03.FIRST.dgn,Design Model:128119 | A_BSUK_Walls_Timber |  | A-Walls::A_BSUK_Walls_Timber
default | 1,SHE_DRAWING+SHEET.dgn ,Design Model;4,SHE-03.FIRST.dgn,Design Model:128128 | A_BSUK_WallInternal_Finishes_Plasterboard |  | A-Walls::A_BSUK_WallInternal_Finishes_Plasterboard
default | 1,SHE_DRAWING+SHEET.dgn ,Design Model;4,SHE-03.FIRST.dgn,Design Model:128137 | A_BSUK_WallInternal_Finishes_Plasterboard |  | A-Walls::A_BSUK_WallInternal_Finishes_Plasterboard
default | 1,SHE_DRAWING+SHEET.dgn ,Design Model;4,SHE-03.FIRST.dgn,Design Model:128146 | A_BSUK_Insulation |  | A-Walls::A_BSUK_Insulation
default | 1,SHE_DRAWING+SHEET.dgn ,Design Model;4,SHE-03.FIRST.dgn,Design Model:128155 | A_BSUK_WallInternal_Finishes_Plasterboard |  | A-Walls::A_BSUK_WallInternal_Finishes_Plasterboard
default | 1,SHE_DRAWING+SHEET.dgn ,Design Model;4,SHE-03.FIRST.dgn,Design Model:128166 | A_BSUK_WallInternal_Finishes_Plasterboard |  | A-Walls::A_BSUK_WallInternal_Finishes_Plasterboard
default | 1,SHE_DRAWING+SHEET.dgn ,Design Model;4,SHE-03.FIRST.dgn,Design Model:128177 | A_BSUK_Walls_Timber |  | A-Walls::A_BSUK_Walls_Timber
default | 1,SHE_DRAWING+SHEET.dgn ,Design Model;4,SHE-03.FIRST.dgn,Design Model:130799 | A_BSUK_Walls_Timber |  | A-Walls::A_BSUK_Walls_Timber
default | 1,SHE_DRAWING+SHEET.dgn ,Design Model;4,SHE-03.FIRST.dgn,Design Model:132321 | A_BSUK_Walls_Timber |  | A-Walls::A_BSUK_Walls_Timber
default | 1,SHE_DRAWING+SHEET.dgn ,Design Model;6,SHE-05.THIRD.dgn,Design Model:123270 | A_BSUK_WallInternal_Finishes_Plasterboard | Finish | A-Walls::A_BSUK_WallInternal_Finishes_Plasterboard
default | 1,SHE_DRAWING+SHEET.dgn ,Design Model;6,SHE-05.THIRD.dgn,Design Model:123279 | A_BSUK_Insulation | Rigid Insulation | A-Walls::A_BSUK_Insulation
default | 1,SHE_DRAWING+SHEET.dgn ,Design Model;6,SHE-05.THIRD.dgn,Design Model:123414 | A_BSUK_WallInternal_Finishes_Plasterboard | Finish | A-Walls::A_BSUK_WallInternal_Finishes_Plasterboard
default | 1,SHE_DRAWING+SHEET.dgn ,Design Model;6,SHE-05.THIRD.dgn,Design Model:123423 | A_BSUK_Insulation | Rigid Insulation | A-Walls::A_BSUK_Insulation
default | 1,SHE_DRAWING+SHEET.dgn ,Design Model;6,SHE-05.THIRD.dgn,Design Model:123522 | A_BSUK_WallInternal_Finishes_Plasterboard | Finish | A-Walls::A_BSUK_WallInternal_Finishes_Plasterboard
default | 1,SHE_DRAWING+SHEET.dgn ,Design Model;6,SHE-05.THIRD.dgn,Design Model:123531 | A_BSUK_Insulation | Rigid Insulation | A-Walls::A_BSUK_Insulation
default | 1,SHE_DRAWING+SHEET.dgn ,Design Model;6,SHE-05.THIRD.dgn,Design Model:123540 | A_BSUK_WallInternal_Finishes_Plasterboard | Finish | A-Walls::A_BSUK_WallInternal_Finishes_Plasterboard
default | 1,SHE_DRAWING+SHEET.dgn ,Design Model;6,SHE-05.THIRD.dgn,Design Model:123549 | A_BSUK_Insulation | Rigid Insulation | A-Walls::A_BSUK_Insulation
default | 1,SHE_DRAWING+SHEET.dgn ,Design Model;6,SHE-05.THIRD.dgn,Design Model:124260 | A_BSUK_WallInternal_Finishes_Plasterboard | Finish | A-Walls::A_BSUK_WallInternal_Finishes_Plasterboard
default | 1,SHE_DRAWING+SHEET.dgn ,Design Model;6,SHE-05.THIRD.dgn,Design Model:124269 | A_BSUK_Insulation | Rigid Insulation | A-Walls::A_BSUK_Insulation
default | 1,SHE_DRAWING+SHEET.dgn ,Design Model;6,SHE-05.THIRD.dgn,Design Model:124296 | A_BSUK_WallInternal_Finishes_Plasterboard | Finish | A-Walls::A_BSUK_WallInternal_Finishes_Plasterboard
default | 1,SHE_DRAWING+SHEET.dgn ,Design Model;6,SHE-05.THIRD.dgn,Design Model:124305 | A_BSUK_Insulation | Rigid Insulation | A-Walls::A_BSUK_Insulation
default | 1,SHE_DRAWING+SHEET.dgn ,Design Model;6,SHE-05.THIRD.dgn,Design Model:124314 | A_BSUK_WallInternal_Finishes_Plasterboard | Finish | A-Walls::A_BSUK_WallInternal_Finishes_Plasterboard
default | 1,SHE_DRAWING+SHEET.dgn ,Design Model;6,SHE-05.THIRD.dgn,Design Model:124323 | A_BSUK_Insulation | Rigid Insulation | A-Walls::A_BSUK_Insulation
default | 1,SHE_DRAWING+SHEET.dgn ,Design Model;6,SHE-05.THIRD.dgn,Design Model:124350 | A_BSUK_WallInternal_Finishes_Plasterboard | Finish | A-Walls::A_BSUK_WallInternal_Finishes_Plasterboard
default | 1,SHE_DRAWING+SHEET.dgn ,Design Model;6,SHE-05.THIRD.dgn,Design Model:124359 | A_BSUK_Insulation | Rigid Insulation | A-Walls::A_BSUK_Insulation
default | 1,SHE_DRAWING+SHEET.dgn ,Design Model;6,SHE-05.THIRD.dgn,Design Model:124899 | A_BSUK_WallInternal_Finishes_Plasterboard | Finish | A-Walls::A_BSUK_WallInternal_Finishes_Plasterboard
default | 1,SHE_DRAWING+SHEET.dgn ,Design Model;6,SHE-05.THIRD.dgn,Design Model:124908 | A_BSUK_Insulation | Rigid Insulation | A-Walls::A_BSUK_Insulation
default | 1,SHE_DRAWING+SHEET.dgn ,Design Model;6,SHE-05.THIRD.dgn,Design Model:124917 | A_BSUK_WallInternal_Finishes_Plasterboard | Finish | A-Walls::A_BSUK_WallInternal_Finishes_Plasterboard
default | 1,SHE_DRAWING+SHEET.dgn ,Design Model;6,SHE-05.THIRD.dgn,Design Model:124926 | A_BSUK_Insulation | Rigid Insulation | A-Walls::A_BSUK_Insulation
default | 1,SHE_DRAWING+SHEET.dgn ,Design Model;6,SHE-05.THIRD.dgn,Design Model:125025 | A_BSUK_WallInternal_Finishes_Plasterboard | Finish | A-Walls::A_BSUK_WallInternal_Finishes_Plasterboard
default | 1,SHE_DRAWING+SHEET.dgn ,Design Model;6,SHE-05.THIRD.dgn,Design Model:125034 | A_BSUK_Insulation | Rigid Insulation | A-Walls::A_BSUK_Insulation
default | 1,SHE_DRAWING+SHEET.dgn ,Design Model;6,SHE-05.THIRD.dgn,Design Model:125160 | A_BSUK_WallInternal_Finishes_Plasterboard | Finish | A-Walls::A_BSUK_WallInternal_Finishes_Plasterboard
default | 1,SHE_DRAWING+SHEET.dgn ,Design Model;6,SHE-05.THIRD.dgn,Design Model:125169 | A_BSUK_Insulation | Rigid Insulation | A-Walls::A_BSUK_Insulation
default | 1,SHE_DRAWING+SHEET.dgn ,Design Model;6,SHE-05.THIRD.dgn,Design Model:126329 | A_BSUK_WallInternal_Finishes_Plasterboard | Finish | A-Walls::A_BSUK_WallInternal_Finishes_Plasterboard
default | 1,SHE_DRAWING+SHEET.dgn ,Design Model;6,SHE-05.THIRD.dgn,Design Model:126338 | A_BSUK_WallInternal_Finishes_Plasterboard | Finish | A-Walls::A_BSUK_WallInternal_Finishes_Plasterboard
default | 1,SHE_DRAWING+SHEET.dgn ,Design Model;6,SHE-05.THIRD.dgn,Design Model:126347 | A_BSUK_Insulation | Structure | A-Walls::A_BSUK_Insulation
default | 1,SHE_DRAWING+SHEET.dgn ,Design Model;6,SHE-05.THIRD.dgn,Design Model:126356 | A_BSUK_WallInternal_Finishes_Plasterboard | Finish | A-Walls::A_BSUK_WallInternal_Finishes_Plasterboard
default | 1,SHE_DRAWING+SHEET.dgn ,Design Model;6,SHE-05.THIRD.dgn,Design Model:126365 | A_BSUK_WallInternal_Finishes_Plasterboard | Finish | A-Walls::A_BSUK_WallInternal_Finishes_Plasterboard
default | 1,SHE_DRAWING+SHEET.dgn ,Design Model;6,SHE-05.THIRD.dgn,Design Model:126374 | A_BSUK_Walls_Timber | Finish | A-Walls::A_BSUK_Walls_Timber
default | 1,SHE_DRAWING+SHEET.dgn ,Design Model;6,SHE-05.THIRD.dgn,Design Model:128119 | A_BSUK_Walls_Timber |  | A-Walls::A_BSUK_Walls_Timber
default | 1,SHE_DRAWING+SHEET.dgn ,Design Model;6,SHE-05.THIRD.dgn,Design Model:128128 | A_BSUK_WallInternal_Finishes_Plasterboard |  | A-Walls::A_BSUK_WallInternal_Finishes_Plasterboard
default | 1,SHE_DRAWING+SHEET.dgn ,Design Model;6,SHE-05.THIRD.dgn,Design Model:128137 | A_BSUK_WallInternal_Finishes_Plasterboard |  | A-Walls::A_BSUK_WallInternal_Finishes_Plasterboard
default | 1,SHE_DRAWING+SHEET.dgn ,Design Model;6,SHE-05.THIRD.dgn,Design Model:128146 | A_BSUK_Insulation |  | A-Walls::A_BSUK_Insulation
default | 1,SHE_DRAWING+SHEET.dgn ,Design Model;6,SHE-05.THIRD.dgn,Design Model:128155 | A_BSUK_WallInternal_Finishes_Plasterboard |  | A-Walls::A_BSUK_WallInternal_Finishes_Plasterboard
default | 1,SHE_DRAWING+SHEET.dgn ,Design Model;6,SHE-05.THIRD.dgn,Design Model:128166 | A_BSUK_WallInternal_Finishes_Plasterboard |  | A-Walls::A_BSUK_WallInternal_Finishes_Plasterboard
default | 1,SHE_DRAWING+SHEET.dgn ,Design Model;6,SHE-05.THIRD.dgn,Design Model:128177 | A_BSUK_Walls_Timber |  | A-Walls::A_BSUK_Walls_Timber
default | 1,SHE_DRAWING+SHEET.dgn ,Design Model;6,SHE-05.THIRD.dgn,Design Model:128834 | A_BSUK_Walls_Timber |  | A-Walls::A_BSUK_Walls_Timber
default | 1,SHE_DRAWING+SHEET.dgn ,Design Model;6,SHE-05.THIRD.dgn,Design Model:128843 | A_BSUK_WallInternal_Finishes_Plasterboard |  | A-Walls::A_BSUK_WallInternal_Finishes_Plasterboard
default | 1,SHE_DRAWING+SHEET.dgn ,Design Model;6,SHE-05.THIRD.dgn,Design Model:128852 | A_BSUK_Insulation |  | A-Walls::A_BSUK_Insulation
default | 1,SHE_DRAWING+SHEET.dgn ,Design Model;6,SHE-05.THIRD.dgn,Design Model:130799 | A_BSUK_Walls_Timber |  | A-Walls::A_BSUK_Walls_Timber
default | 1,SHE_DRAWING+SHEET.dgn ,Design Model;6,SHE-05.THIRD.dgn,Design Model:132321 | A_BSUK_Walls_Timber |  | A-Walls::A_BSUK_Walls_Timber
default | 1,SHE_DRAWING+SHEET.dgn ,Design Model;7,SHE-06.FOURTH.dgn,Design Model:334314 | A_BSUK_WallInternal_Finishes_Plasterboard |  | A-Walls::A_BSUK_WallInternal_Finishes_Plasterboard
default | 1,SHE_DRAWING+SHEET.dgn ,Design Model;7,SHE-06.FOURTH.dgn,Design Model:334325 | A_BSUK_WallInternal_Finishes_Plasterboard |  | A-Walls::A_BSUK_WallInternal_Finishes_Plasterboard
default | 1,SHE_DRAWING+SHEET.dgn ,Design Model;7,SHE-06.FOURTH.dgn,Design Model:406639 | A_BSUK_Walls_Timber |  | A-Walls::A_BSUK_Walls_Timber
default | 1,SHE_DRAWING+SHEET.dgn ,Design Model;7,SHE-06.FOURTH.dgn,Design Model:406656 | A_BSUK_WallInternal_Finishes_Plasterboard |  | A-Walls::A_BSUK_WallInternal_Finishes_Plasterboard
default | 1,SHE_DRAWING+SHEET.dgn ,Design Model;7,SHE-06.FOURTH.dgn,Design Model:406731 | A_BSUK_Walls_Timber |  | A-Walls::A_BSUK_Walls_Timber
default | 1,SHE_DRAWING+SHEET.dgn ,Design Model;7,SHE-06.FOURTH.dgn,Design Model:406748 | A_BSUK_Walls_Timber |  | A-Walls::A_BSUK_Walls_Timber
default | 1,SHE_DRAWING+SHEET.dgn ,Design Model;7,SHE-06.FOURTH.dgn,Design Model:406759 | A_BSUK_WallInternal_Finishes_Plasterboard |  | A-Walls::A_BSUK_WallInternal_Finishes_Plasterboard
default | 1,SHE_DRAWING+SHEET.dgn ,Design Model;7,SHE-06.FOURTH.dgn,Design Model:406770 | A_BSUK_WallInternal_Finishes_Plasterboard |  | A-Walls::A_BSUK_WallInternal_Finishes_Plasterboard
default | 1,SHE_DRAWING+SHEET.dgn ,Design Model;7,SHE-06.FOURTH.dgn,Design Model:406798 | A_BSUK_Walls_Timber |  | A-Walls::A_BSUK_Walls_Timber
default | 1,SHE_DRAWING+SHEET.dgn ,Design Model;7,SHE-06.FOURTH.dgn,Design Model:406815 | A_BSUK_Walls_Timber |  | A-Walls::A_BSUK_Walls_Timber
default | 1,SHE_DRAWING+SHEET.dgn ,Design Model;7,SHE-06.FOURTH.dgn,Design Model:407005 | A_BSUK_Walls_Timber |  | A-Walls::A_BSUK_Walls_Timber
default | 1,SHE_DRAWING+SHEET.dgn ,Design Model;7,SHE-06.FOURTH.dgn,Design Model:407616 | A_BSUK_Walls_Timber |  | A-Walls::A_BSUK_Walls_Timber
default | 1,SHE_DRAWING+SHEET.dgn ,Design Model;18,SHE-04.SECOND.dgn,Design Model:123270 | A_BSUK_WallInternal_Finishes_Plasterboard | Finish | A-Walls::A_BSUK_WallInternal_Finishes_Plasterboard
default | 1,SHE_DRAWING+SHEET.dgn ,Design Model;18,SHE-04.SECOND.dgn,Design Model:123279 | A_BSUK_Insulation | Rigid Insulation | A-Walls::A_BSUK_Insulation
default | 1,SHE_DRAWING+SHEET.dgn ,Design Model;18,SHE-04.SECOND.dgn,Design Model:123414 | A_BSUK_WallInternal_Finishes_Plasterboard | Finish | A-Walls::A_BSUK_WallInternal_Finishes_Plasterboard
default | 1,SHE_DRAWING+SHEET.dgn ,Design Model;18,SHE-04.SECOND.dgn,Design Model:123423 | A_BSUK_Insulation | Rigid Insulation | A-Walls::A_BSUK_Insulation
default | 1,SHE_DRAWING+SHEET.dgn ,Design Model;18,SHE-04.SECOND.dgn,Design Model:123522 | A_BSUK_WallInternal_Finishes_Plasterboard | Finish | A-Walls::A_BSUK_WallInternal_Finishes_Plasterboard
default | 1,SHE_DRAWING+SHEET.dgn ,Design Model;18,SHE-04.SECOND.dgn,Design Model:123531 | A_BSUK_Insulation | Rigid Insulation | A-Walls::A_BSUK_Insulation
default | 1,SHE_DRAWING+SHEET.dgn ,Design Model;18,SHE-04.SECOND.dgn,Design Model:123540 | A_BSUK_WallInternal_Finishes_Plasterboard | Finish | A-Walls::A_BSUK_WallInternal_Finishes_Plasterboard
default | 1,SHE_DRAWING+SHEET.dgn ,Design Model;18,SHE-04.SECOND.dgn,Design Model:123549 | A_BSUK_Insulation | Rigid Insulation | A-Walls::A_BSUK_Insulation
default | 1,SHE_DRAWING+SHEET.dgn ,Design Model;18,SHE-04.SECOND.dgn,Design Model:124260 | A_BSUK_WallInternal_Finishes_Plasterboard | Finish | A-Walls::A_BSUK_WallInternal_Finishes_Plasterboard
default | 1,SHE_DRAWING+SHEET.dgn ,Design Model;18,SHE-04.SECOND.dgn,Design Model:124269 | A_BSUK_Insulation | Rigid Insulation | A-Walls::A_BSUK_Insulation
default | 1,SHE_DRAWING+SHEET.dgn ,Design Model;18,SHE-04.SECOND.dgn,Design Model:124296 | A_BSUK_WallInternal_Finishes_Plasterboard | Finish | A-Walls::A_BSUK_WallInternal_Finishes_Plasterboard
default | 1,SHE_DRAWING+SHEET.dgn ,Design Model;18,SHE-04.SECOND.dgn,Design Model:124305 | A_BSUK_Insulation | Rigid Insulation | A-Walls::A_BSUK_Insulation
default | 1,SHE_DRAWING+SHEET.dgn ,Design Model;18,SHE-04.SECOND.dgn,Design Model:124314 | A_BSUK_WallInternal_Finishes_Plasterboard | Finish | A-Walls::A_BSUK_WallInternal_Finishes_Plasterboard
default | 1,SHE_DRAWING+SHEET.dgn ,Design Model;18,SHE-04.SECOND.dgn,Design Model:124323 | A_BSUK_Insulation | Rigid Insulation | A-Walls::A_BSUK_Insulation
default | 1,SHE_DRAWING+SHEET.dgn ,Design Model;18,SHE-04.SECOND.dgn,Design Model:124350 | A_BSUK_WallInternal_Finishes_Plasterboard | Finish | A-Walls::A_BSUK_WallInternal_Finishes_Plasterboard
default | 1,SHE_DRAWING+SHEET.dgn ,Design Model;18,SHE-04.SECOND.dgn,Design Model:124359 | A_BSUK_Insulation | Rigid Insulation | A-Walls::A_BSUK_Insulation
default | 1,SHE_DRAWING+SHEET.dgn ,Design Model;18,SHE-04.SECOND.dgn,Design Model:124899 | A_BSUK_WallInternal_Finishes_Plasterboard | Finish | A-Walls::A_BSUK_WallInternal_Finishes_Plasterboard
default | 1,SHE_DRAWING+SHEET.dgn ,Design Model;18,SHE-04.SECOND.dgn,Design Model:124908 | A_BSUK_Insulation | Rigid Insulation | A-Walls::A_BSUK_Insulation
default | 1,SHE_DRAWING+SHEET.dgn ,Design Model;18,SHE-04.SECOND.dgn,Design Model:124917 | A_BSUK_WallInternal_Finishes_Plasterboard | Finish | A-Walls::A_BSUK_WallInternal_Finishes_Plasterboard
default | 1,SHE_DRAWING+SHEET.dgn ,Design Model;18,SHE-04.SECOND.dgn,Design Model:124926 | A_BSUK_Insulation | Rigid Insulation | A-Walls::A_BSUK_Insulation
default | 1,SHE_DRAWING+SHEET.dgn ,Design Model;18,SHE-04.SECOND.dgn,Design Model:125025 | A_BSUK_WallInternal_Finishes_Plasterboard | Finish | A-Walls::A_BSUK_WallInternal_Finishes_Plasterboard
default | 1,SHE_DRAWING+SHEET.dgn ,Design Model;18,SHE-04.SECOND.dgn,Design Model:125034 | A_BSUK_Insulation | Rigid Insulation | A-Walls::A_BSUK_Insulation
default | 1,SHE_DRAWING+SHEET.dgn ,Design Model;18,SHE-04.SECOND.dgn,Design Model:125160 | A_BSUK_WallInternal_Finishes_Plasterboard | Finish | A-Walls::A_BSUK_WallInternal_Finishes_Plasterboard
default | 1,SHE_DRAWING+SHEET.dgn ,Design Model;18,SHE-04.SECOND.dgn,Design Model:125169 | A_BSUK_Insulation | Rigid Insulation | A-Walls::A_BSUK_Insulation
default | 1,SHE_DRAWING+SHEET.dgn ,Design Model;18,SHE-04.SECOND.dgn,Design Model:125304 | A_BSUK_Walls_Timber | Finish | A-Walls::A_BSUK_Walls_Timber
default | 1,SHE_DRAWING+SHEET.dgn ,Design Model;18,SHE-04.SECOND.dgn,Design Model:126329 | A_BSUK_WallInternal_Finishes_Plasterboard | Finish | A-Walls::A_BSUK_WallInternal_Finishes_Plasterboard
default | 1,SHE_DRAWING+SHEET.dgn ,Design Model;18,SHE-04.SECOND.dgn,Design Model:126338 | A_BSUK_WallInternal_Finishes_Plasterboard | Finish | A-Walls::A_BSUK_WallInternal_Finishes_Plasterboard
default | 1,SHE_DRAWING+SHEET.dgn ,Design Model;18,SHE-04.SECOND.dgn,Design Model:126347 | A_BSUK_Insulation | Structure | A-Walls::A_BSUK_Insulation
default | 1,SHE_DRAWING+SHEET.dgn ,Design Model;18,SHE-04.SECOND.dgn,Design Model:126356 | A_BSUK_WallInternal_Finishes_Plasterboard | Finish | A-Walls::A_BSUK_WallInternal_Finishes_Plasterboard
default | 1,SHE_DRAWING+SHEET.dgn ,Design Model;18,SHE-04.SECOND.dgn,Design Model:126365 | A_BSUK_WallInternal_Finishes_Plasterboard | Finish | A-Walls::A_BSUK_WallInternal_Finishes_Plasterboard
default | 1,SHE_DRAWING+SHEET.dgn ,Design Model;18,SHE-04.SECOND.dgn,Design Model:126374 | A_BSUK_Walls_Timber | Finish | A-Walls::A_BSUK_Walls_Timber
default | 1,SHE_DRAWING+SHEET.dgn ,Design Model;18,SHE-04.SECOND.dgn,Design Model:126646 | A_BSUK_WallInternal_Finishes_Plasterboard |  | A-Walls::A_BSUK_WallInternal_Finishes_Plasterboard
default | 1,SHE_DRAWING+SHEET.dgn ,Design Model;18,SHE-04.SECOND.dgn,Design Model:128119 | A_BSUK_Walls_Timber |  | A-Walls::A_BSUK_Walls_Timber
default | 1,SHE_DRAWING+SHEET.dgn ,Design Model;18,SHE-04.SECOND.dgn,Design Model:128128 | A_BSUK_WallInternal_Finishes_Plasterboard |  | A-Walls::A_BSUK_WallInternal_Finishes_Plasterboard
default | 1,SHE_DRAWING+SHEET.dgn ,Design Model;18,SHE-04.SECOND.dgn,Design Model:128137 | A_BSUK_WallInternal_Finishes_Plasterboard |  | A-Walls::A_BSUK_WallInternal_Finishes_Plasterboard
default | 1,SHE_DRAWING+SHEET.dgn ,Design Model;18,SHE-04.SECOND.dgn,Design Model:128146 | A_BSUK_Insulation |  | A-Walls::A_BSUK_Insulation
default | 1,SHE_DRAWING+SHEET.dgn ,Design Model;18,SHE-04.SECOND.dgn,Design Model:128155 | A_BSUK_WallInternal_Finishes_Plasterboard |  | A-Walls::A_BSUK_WallInternal_Finishes_Plasterboard
default | 1,SHE_DRAWING+SHEET.dgn ,Design Model;18,SHE-04.SECOND.dgn,Design Model:128166 | A_BSUK_WallInternal_Finishes_Plasterboard |  | A-Walls::A_BSUK_WallInternal_Finishes_Plasterboard
default | 1,SHE_DRAWING+SHEET.dgn ,Design Model;18,SHE-04.SECOND.dgn,Design Model:128177 | A_BSUK_Walls_Timber |  | A-Walls::A_BSUK_Walls_Timber
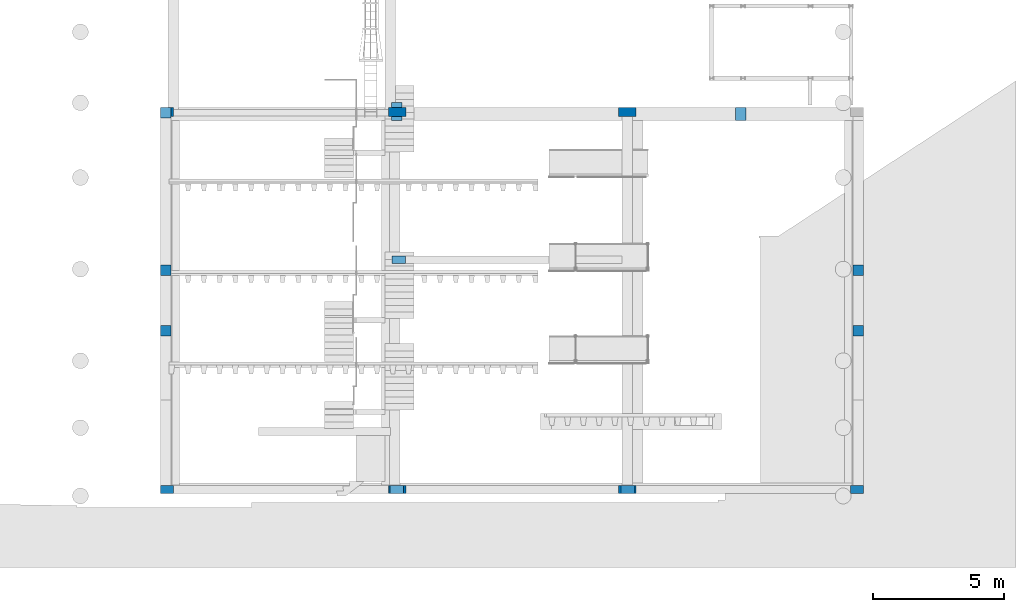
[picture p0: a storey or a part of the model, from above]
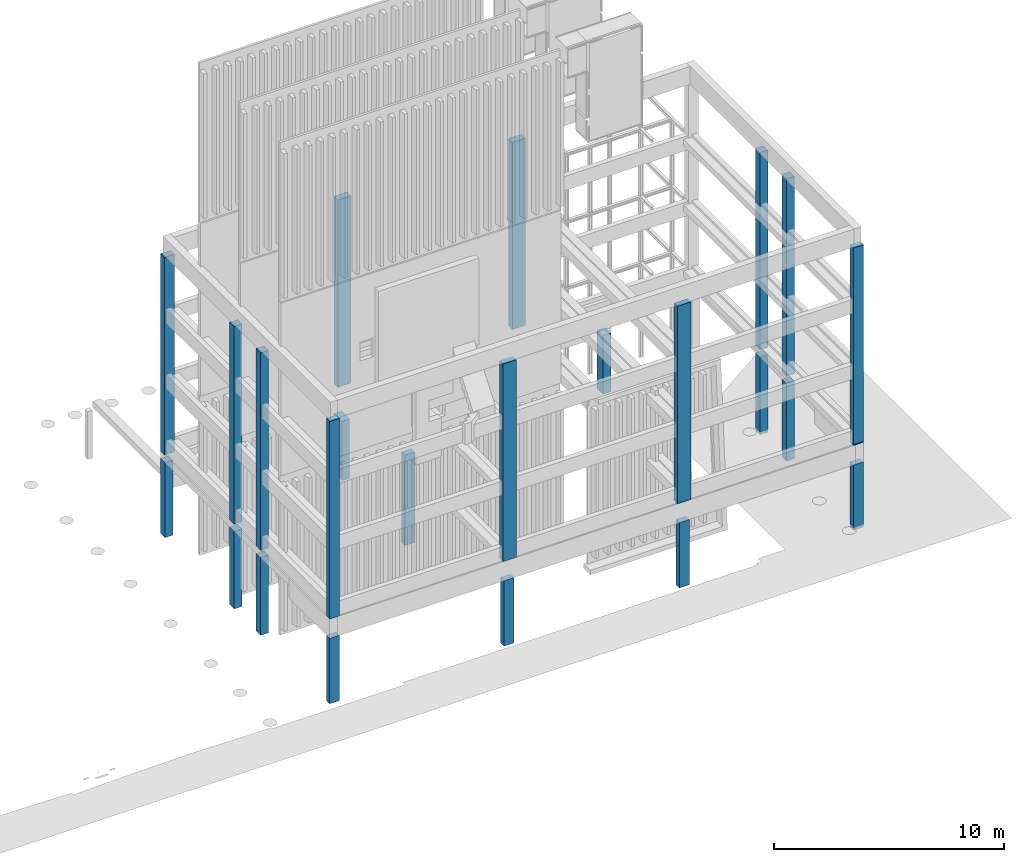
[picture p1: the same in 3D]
Properties of the parts of a building model (IFC2X3), part 16 of 16

# IfcWall: default (114)
Name | Description | Material | Wall Function | Part Definition
default | 1,SHE_DRAWING+SHEET.dgn ,Design Model;18,SHE-04.SECOND.dgn,Design Model:128834 | A_BSUK_Walls_Timber |  | A-Walls::A_BSUK_Walls_Timber
default | 1,SHE_DRAWING+SHEET.dgn ,Design Model;18,SHE-04.SECOND.dgn,Design Model:128843 | A_BSUK_WallInternal_Finishes_Plasterboard |  | A-Walls::A_BSUK_WallInternal_Finishes_Plasterboard
default | 1,SHE_DRAWING+SHEET.dgn ,Design Model;18,SHE-04.SECOND.dgn,Design Model:128852 | A_BSUK_Insulation |  | A-Walls::A_BSUK_Insulation
default | 1,SHE_DRAWING+SHEET.dgn ,Design Model;18,SHE-04.SECOND.dgn,Design Model:130799 | A_BSUK_Walls_Timber |  | A-Walls::A_BSUK_Walls_Timber
default | 1,SHE_DRAWING+SHEET.dgn ,Design Model;18,SHE-04.SECOND.dgn,Design Model:132321 | A_BSUK_Walls_Timber |  | A-Walls::A_BSUK_Walls_Timber

# IfcWallStandardCase: A-Walls-ExternalBlock (20)
In: RL
Type - Wall Parameters - Type: Wall; Compound Wall Assembly: no
Type - Thermal Transmittance - Is External: yes; Is Below Grade: no
Type - Structural Usage - Structural | Material: Blockwork
Type - Space Bounding - Is Space Bounding: yes
Type - Materials - Part Definition: A-Walls::A_BSUK_WallsExternal_Block
Type - LEED Parameters - LEED | Pre-consumer Recycled (%): 0; LEED | Regional Material: no; LEED | Post-consumer Recycled (%): 0
Type - Fire Resistance - Fire | IsCombustible: no; Fire | Compartmentation: no
Type - Discipline - Discipline: Architectural
Type - Classification - Uniclass2015: Pr_20_93_52_01
Material: A_BSUK_Roofs 0.3 m
Pset_WallCommon - Combustible: no; Compartmentation: no; FireRating: F60; IsExternal: yes; LoadBearing: no
Materials - Part Definition: A-Roofs::A_BSUK_Roofs
Identification - ID | Number: 7C; ID | Description: SFSWall fire lining; ID | Notes: fire board - internal mansard roof finish
Fire Resistance - Fire | Rating: F60
Construction Phase - Phase: New Construction
Name | Description
7C | SFSWall fire lining :1,SHE_DRAWING+SHEET.dgn,Design Model;7,SHE-06.FOURTH.dgn ,Design Model:102985
7C | SFSWall fire lining :1,SHE_DRAWING+SHEET.dgn,Design Model;7,SHE-06.FOURTH.dgn ,Design Model:102994
7C | SFSWall fire lining :1,SHE_DRAWING+SHEET.dgn,Design Model;7,SHE-06.FOURTH.dgn ,Design Model:103003
7C | SFSWall fire lining :1,SHE_DRAWING+SHEET.dgn,Design Model;7,SHE-06.FOURTH.dgn ,Design Model:103012
7C | SFSWall fire lining :1,SHE_DRAWING+SHEET.dgn,Design Model;7,SHE-06.FOURTH.dgn ,Design Model:103021
7C | SFSWall fire lining :1,SHE_DRAWING+SHEET.dgn,Design Model;7,SHE-06.FOURTH.dgn ,Design Model:103030
7C | SFSWall fire lining :1,SHE_DRAWING+SHEET.dgn,Design Model;7,SHE-06.FOURTH.dgn ,Design Model:103039
7C | SFSWall fire lining :1,SHE_DRAWING+SHEET.dgn,Design Model;7,SHE-06.FOURTH.dgn ,Design Model:103048
7C | SFSWall fire lining :1,SHE_DRAWING+SHEET.dgn,Design Model;7,SHE-06.FOURTH.dgn ,Design Model:103057
7C | SFSWall fire lining :1,SHE_DRAWING+SHEET.dgn,Design Model;7,SHE-06.FOURTH.dgn ,Design Model:103066
7C | SFSWall fire lining :1,SHE_DRAWING+SHEET.dgn,Design Model;7,SHE-06.FOURTH.dgn ,Design Model:103075
7C | SFSWall fire lining :1,SHE_DRAWING+SHEET.dgn,Design Model;7,SHE-06.FOURTH.dgn ,Design Model:103084
7C | SFSWall fire lining :1,SHE_DRAWING+SHEET.dgn,Design Model;7,SHE-06.FOURTH.dgn ,Design Model:103093
7C | SFSWall fire lining :1,SHE_DRAWING+SHEET.dgn,Design Model;7,SHE-06.FOURTH.dgn ,Design Model:103102
7C | SFSWall fire lining :1,SHE_DRAWING+SHEET.dgn,Design Model;7,SHE-06.FOURTH.dgn ,Design Model:103111
7C | SFSWall fire lining :1,SHE_DRAWING+SHEET.dgn,Design Model;7,SHE-06.FOURTH.dgn ,Design Model:103120
7C | SFSWall fire lining :1,SHE_DRAWING+SHEET.dgn,Design Model;7,SHE-06.FOURTH.dgn ,Design Model:103129
7C | SFSWall fire lining :1,SHE_DRAWING+SHEET.dgn,Design Model;7,SHE-06.FOURTH.dgn ,Design Model:103138
7C | SFSWall fire lining :1,SHE_DRAWING+SHEET.dgn,Design Model;7,SHE-06.FOURTH.dgn ,Design Model:103147
7C | SFSWall fire lining :1,SHE_DRAWING+SHEET.dgn,Design Model;7,SHE-06.FOURTH.dgn ,Design Model:103156

# IfcWindow: A-Awning (36)
In: RL
Type - Description: Awning Window; OperationType: USERDEFINED; ParameterTakesPrecedence: no; Sizeable: no
Type - Lining - LiningDepth: 0.1 m; LiningThickness: 0.042 m
Type - Window Parameters - Parametric | File Type: PAZ; Parametric | File Name: HM_SNG_Awning; Dimension | Frame Width: 1.36 m; Dimension | Frame Height: 1.455 m; Dimension | Frame Depth: 0.1 m; Dimension | Frame Depth Match Wall: no; Dimension | Frame Thickness: 0.042 m
Type - Window Dimensions- Extended - Dimension | Rough Opening Offset: 0 m; Dimension | Number of Frames: 0
Type - Window - Window | Type: Awning
Type - Thermal Transmittance - Is External: no; Is Below Grade: no
Type - Identification - ID | Description: Awning Window
Type - Fire Resistance - Fire | IsCombustible: no; Fire | Compartmentation: no
Type - Discipline - Discipline: Architectural
Type - Classification - Uniclass2015: Pr_30_59_98
Material: A_BSUK_Windows
Window Dimensions- Extended - Dimension | Mullion Thickness: 0 m; Dimension | Mullion Spacing: 0 m; Dimension | Mullion Offset-Left: 0 m; Dimension | Mullion Offset-Right: 0 m; Dimension | Mullion Offset-Horizontal: 0 m; Dimension | Muntin Horizontal Spacing: 0 m; Dimension | Muntin Vertical Spacing: 0 m; Dimension | Muntin Thickness: 0 m; Dimension | Muntin Inset Distance: 0 m; Dimension | Top Sash Height: 0 m
Identification - ID | Notes: Tilt & Turn Window
Name | Description | OverallHeight (m) | OverallWidth (m) | Dimension | Frame Width (m) | Dimension | Frame Height (m) | Window | Type | ID | Type ID | ID | Number | ID | Description | ID | Keynote | ID | Asset Tag | Phase | ID | Name (Alternate)
0.08 | U-Value 1.4 - bedroom :1 ,SHE_DRAWING+SHEET.dgn,Design Model;1,SHE-01.GROUND.dgn,Design Model:107404 | 1.2 | 1.5 | 1.5 | 1.2 | Pivot | U-Value 1.4 | 0.08 | bedroom | Rw 37dB, Rw+Ctr 35dB , trickle vent 45dB | G-Value 0.6 | Existing to Remain | Window - Glazing | Notes: security - Part Q / PAS24 compliance
0.10 | commercial side window :1,SHE_DRAWING+SHEET.dgn,Design Model;1 ,SHE-01.GROUND.dgn,Design Model:107761 | 1.2 | 1.5 | 1.5 | 1.2 | Pivot |  | 0.10 | commercial side window |  | G-Value 0.6 | Existing to Remain | Window - Glazing | Notes: security - Part Q / PAS24 compliance
0.12 | commercial side window :1,SHE_DRAWING+SHEET.dgn,Design Model;1 ,SHE-01.GROUND.dgn,Design Model:108118 | 1.2 | 1.5 | 1.5 | 1.2 | Pivot |  | 0.12 | commercial side window |  | G-Value 0.6 | Existing to Remain | Window - Glazing | Notes: security - Part Q / PAS24 compliance
0.14 | commercial side window :1,SHE_DRAWING+SHEET.dgn,Design Model;1 ,SHE-01.GROUND.dgn,Design Model:108475 | 1.2 | 1.5 | 1.5 | 1.2 | Pivot |  | 0.14 | commercial side window |  | G-Value 0.6 | Existing to Remain | Window - Glazing | Notes: security - Part Q / PAS24 compliance
0.15 | commercial side window / WC :1,SHE_DRAWING+SHEET.dgn,Design Model;1 ,SHE-01.GROUND.dgn,Design Model:108701 | 1.2 | 1.5 | 1.5 | 1.2 | Pivot |  | 0.15 | commercial side window / WC |  | G-Value 0.6 | Existing to Remain | Window - Glazing | Notes: security - Part Q / PAS24 compliance
0.19 | U-Value 1.4 - bedroom :1 ,SHE_DRAWING+SHEET.dgn,Design Model;2,SHE-02.MEZZANINE.dgn,Design Model:98458 | 1.2 | 1.5 | 1.5 | 1.2 | Pivot | U-Value 1.4 | 0.19 | bedroom | Rw 37dB, Rw+Ctr 35dB , trickle vent 45dB | G-Value 0.6 | Existing to Remain
0.20 | U-Value 1.4 - bedroom :1 ,SHE_DRAWING+SHEET.dgn,Design Model;2,SHE-02.MEZZANINE.dgn,Design Model:98684 | 1.2 | 1.5 | 1.5 | 1.2 | Pivot | U-Value 1.4 | 0.20 | bedroom | Rw 37dB, Rw+Ctr 35dB , trickle vent 45dB | G-Value 0.6 | Existing to Remain
0.21 | U-Value 1.4 - KDL :1 ,SHE_DRAWING+SHEET.dgn,Design Model;2,SHE-02.MEZZANINE.dgn,Design Model:98910 | 1.2 | 1.5 | 1.5 | 1.2 | Pivot | U-Value 1.4 | 0.21 | KDL | Rw 34dB, Rw+Ctr 30dB , trickle vent 45dB | G-Value 0.6 | Existing to Remain
0.22 | U-Value 1.4 - bathroom :1,SHE_DRAWING+SHEET.dgn,Design Model;2 ,SHE-02.MEZZANINE.dgn,Design Model:99136 | 0.75 | 0.56 | 0.56 | 0.75 | Pivot | U-Value 1.4 | 0.22 | bathroom |  | G-Value 0.6 | Existing to Remain
0.23 | U-Value 1.4 - bathroom :1,SHE_DRAWING+SHEET.dgn,Design Model;2 ,SHE-02.MEZZANINE.dgn,Design Model:99362 | 0.75 | 0.56 | 0.56 | 0.75 | Pivot | U-Value 1.4 | 0.23 | bathroom |  | G-Value 0.6 | Existing to Remain
4.01 | U-Value 1.2 - dormer front bedroom :1,SHE_DRAWING+SHEET.dgn,Design Model;7 ,SHE-06.FOURTH.dgn,Design Model:124802 | 1.15 | 1.5 | 1.15 | 1.5 | Tilt & Turn | U-Value 1.2 | 4.01 | dormer front bedroom | Rw 46dB, Rw+Ctr 40dB | G-Value 0.4 | New Construction | mechanical ventilation
4.02 | U-Value 1.2 - dormer front bedroom :1,SHE_DRAWING+SHEET.dgn,Design Model;7 ,SHE-06.FOURTH.dgn,Design Model:125028 | 1.15 | 1.5 | 1.15 | 1.5 | Tilt & Turn | U-Value 1.2 | 4.02 | dormer front bedroom | Rw 46dB, Rw+Ctr 40dB | G-Value 0.4 | New Construction | mechanical ventilation
4.03 | U-Value 1.2 - dormer front bedroom :1,SHE_DRAWING+SHEET.dgn,Design Model;7 ,SHE-06.FOURTH.dgn,Design Model:125254 | 1.15 | 1.5 | 1.15 | 1.5 | Tilt & Turn | U-Value 1.2 | 4.03 | dormer front bedroom | Rw 46dB, Rw+Ctr 40dB | G-Value 0.4 | New Construction | mechanical ventilation
4.04 | U-Value 1.2 - dormer front bedroom :1,SHE_DRAWING+SHEET.dgn,Design Model;7 ,SHE-06.FOURTH.dgn,Design Model:125480 | 1.15 | 1.5 | 1.15 | 1.5 | Tilt & Turn | U-Value 1.2 | 4.04 | dormer front bedroom | Rw 46dB, Rw+Ctr 40dB | G-Value 0.4 | New Construction | mechanical ventilation
4.05 | U-Value 1.2 - dormer front bath :1,SHE_DRAWING+SHEET.dgn,Design Model;7 ,SHE-06.FOURTH.dgn,Design Model:125706 | 1.15 | 1.5 | 1.15 | 1.5 | Tilt & Turn | U-Value 1.2 | 4.05 | dormer front bath | Rw 34dB, Rw+Ctr 30dB | G-Value 0.4 | New Construction
4.06 | U-Value 1.2 - dormer front bath :1,SHE_DRAWING+SHEET.dgn,Design Model;7 ,SHE-06.FOURTH.dgn,Design Model:125932 | 1.15 | 1.5 | 1.15 | 1.5 | Tilt & Turn | U-Value 1.2 | 4.06 | dormer front bath | Rw 34dB, Rw+Ctr 30dB | G-Value 0.4 | New Construction
4.07 | U-Value 1.2 - dormer front bedroom :1,SHE_DRAWING+SHEET.dgn,Design Model;7 ,SHE-06.FOURTH.dgn,Design Model:126158 | 1.15 | 1.5 | 1.15 | 1.5 | Tilt & Turn | U-Value 1.2 | 4.07 | dormer front bedroom | Rw 46dB, Rw+Ctr 40dB | G-Value 0.4 | New Construction | mechanical ventilation
4.08 | U-Value 1.2 - dormer front bedroom :1,SHE_DRAWING+SHEET.dgn,Design Model;7 ,SHE-06.FOURTH.dgn,Design Model:126384 | 1.15 | 1.5 | 1.15 | 1.5 | Tilt & Turn | U-Value 1.2 | 4.08 | dormer front bedroom | Rw 46dB, Rw+Ctr 40dB | G-Value 0.4 | New Construction | mechanical ventilation
4.09 | U-Value 1.2 - dormer front bedroom :1,SHE_DRAWING+SHEET.dgn,Design Model;7 ,SHE-06.FOURTH.dgn,Design Model:126610 | 1.15 | 1.5 | 1.15 | 1.5 | Tilt & Turn | U-Value 1.2 | 4.09 | dormer front bedroom | Rw 46dB, Rw+Ctr 40dB | G-Value 0.4 | New Construction | mechanical ventilation
4.10 | U-Value 1.2 - dormer front bedroom :1,SHE_DRAWING+SHEET.dgn,Design Model;7 ,SHE-06.FOURTH.dgn,Design Model:126836 | 1.15 | 1.5 | 1.15 | 1.5 |  | U-Value 1.2 | 4.10 | dormer front bedroom | Rw 46dB, Rw+Ctr 40dB | G-Value 0.4 | New Construction | mechanical ventilation
4.11 | U-Value 1.2 - dormer side bedroom :1,SHE_DRAWING+SHEET.dgn,Design Model;7 ,SHE-06.FOURTH.dgn,Design Model:127062 | 1.5 | 1.15 | 1.15 | 1.5 |  | U-Value 1.2 | 4.11 | dormer side bedroom | Rw 46dB, Rw+Ctr 40dB | G-Value 0.4 | New Construction | mechanical ventilation
4.13 | U-Value 1.2 - dormer side bath :1,SHE_DRAWING+SHEET.dgn,Design Model;7 ,SHE-06.FOURTH.dgn,Design Model:127514 | 1.5 | 1.15 | 1.15 | 1.5 |  | U-Value 1.2 | 4.13 | dormer side bath | Rw 34dB, Rw+Ctr 30dB | G-Value 0.4 | New Construction
4.14 | U-Value 1.2 - dormer rear bedroom :1,SHE_DRAWING+SHEET.dgn,Design Model;7 ,SHE-06.FOURTH.dgn,Design Model:127740 | 1.15 | 1.5 | 1.15 | 1.5 |  | U-Value 1.2 | 4.14 | dormer rear bedroom | Rw 37dB, Rw+Ctr 35dB | G-Value 0.4 | New Construction | mechanical ventilation
4.15 | U-Value 1.2 - dormer rear bedroom :1,SHE_DRAWING+SHEET.dgn,Design Model;7 ,SHE-06.FOURTH.dgn,Design Model:127966 | 1.15 | 1.5 | 1.15 | 1.5 |  | U-Value 1.2 | 4.15 | dormer rear bedroom | Rw 37dB, Rw+Ctr 35dB | G-Value 0.4 | New Construction | mechanical ventilation
4.16 | U-Value 1.2 - dormer rear bedroom :1,SHE_DRAWING+SHEET.dgn,Design Model;7 ,SHE-06.FOURTH.dgn,Design Model:128192 | 1.15 | 1.5 | 1.15 | 1.5 |  | U-Value 1.2 | 4.16 | dormer rear bedroom | Rw 37dB, Rw+Ctr 35dB | G-Value 0.4 | New Construction | mechanical ventilation
4.17 | U-Value 1.2 - dormer rear bedroom :1,SHE_DRAWING+SHEET.dgn,Design Model;7 ,SHE-06.FOURTH.dgn,Design Model:128418 | 1.15 | 1.5 | 1.15 | 1.5 |  | U-Value 1.2 | 4.17 | dormer rear bedroom | Rw 37dB, Rw+Ctr 35dB | G-Value 0.4 | New Construction | mechanical ventilation
4.18 | U-Value 1.2 - dormer rear bedroom :1,SHE_DRAWING+SHEET.dgn,Design Model;7 ,SHE-06.FOURTH.dgn,Design Model:128644 | 1.15 | 1.5 | 1.15 | 1.5 |  | U-Value 1.2 | 4.18 | dormer rear bedroom | Rw 37dB, Rw+Ctr 35dB | G-Value 0.4 | New Construction | mechanical ventilation
4.19 | U-Value 1.2 - dormer rear bedroom :1,SHE_DRAWING+SHEET.dgn,Design Model;7 ,SHE-06.FOURTH.dgn,Design Model:128870 | 1.15 | 1.5 | 1.15 | 1.5 |  | U-Value 1.2 | 4.19 | dormer rear bedroom | Rw 37dB, Rw+Ctr 35dB | G-Value 0.4 | New Construction | mechanical ventilation
4.20 | U-Value 1.2 - dormer rear bedroom :1,SHE_DRAWING+SHEET.dgn,Design Model;7 ,SHE-06.FOURTH.dgn,Design Model:129096 | 1.15 | 1.5 | 1.15 | 1.5 |  | U-Value 1.2 | 4.20 | dormer rear bedroom | Rw 37dB, Rw+Ctr 35dB | G-Value 0.4 | New Construction | mechanical ventilation
4.21 | U-Value 1.2 - dormer rear bedroom :1,SHE_DRAWING+SHEET.dgn,Design Model;7 ,SHE-06.FOURTH.dgn,Design Model:129322 | 1.15 | 1.5 | 1.15 | 1.5 |  | U-Value 1.2 | 4.21 | dormer rear bedroom | Rw 37dB, Rw+Ctr 35dB | G-Value 0.4 | New Construction | mechanical ventilation
4.22 | U-Value 1.2 - sliding rear windows :1,SHE_DRAWING+SHEET.dgn,Design Model;7 ,SHE-06.FOURTH.dgn,Design Model:129548 | 1.15 | 1.5 | 1.15 | 1.5 |  | U-Value 1.2 | 4.22 | sliding rear windows | Rw 37dB, Rw+Ctr 35dB | G-Value 0.4 | New Construction | mechanical ventilation
4.23 | U-Value 1.2 - dormer rear bedroom :1,SHE_DRAWING+SHEET.dgn,Design Model;7 ,SHE-06.FOURTH.dgn,Design Model:129774 | 1.15 | 1.5 | 1.15 | 1.5 |  | U-Value 1.2 | 4.23 | dormer rear bedroom | Rw 37dB, Rw+Ctr 35dB | G-Value 0.4 | New Construction | mechanical ventilation
4.24 | U-Value 1.2 - dormer side bedroom :1,SHE_DRAWING+SHEET.dgn,Design Model;7 ,SHE-06.FOURTH.dgn,Design Model:130000 | 1.5 | 1.15 | 1.15 | 1.5 |  | U-Value 1.2 | 4.24 | dormer side bedroom | Rw 46dB, Rw+Ctr 40dB | G-Value 0.4 | New Construction | mechanical ventilation
4.12 | U-Value 1.2 - dormer side bedroom :1,SHE_DRAWING+SHEET.dgn,Design Model;7 ,SHE-06.FOURTH.dgn,Design Model:130452 | 1.5 | 1.15 | 1.15 | 1.5 |  | U-Value 1.2 | 4.12 | dormer side bedroom | Rw 46dB, Rw+Ctr 40dB | G-Value 0.4 | New Construction | mechanical ventilation
4.12 | U-Value 1.2 - dormer side bedroom :1,SHE_DRAWING+SHEET.dgn,Design Model;7 ,SHE-06.FOURTH.dgn,Design Model:469217 | 1.5 | 1.15 | 1.15 | 1.5 |  | U-Value 1.2 | 4.12 | dormer side bedroom | Rw 46dB, Rw+Ctr 40dB | G-Value 0.4 | New Construction | mechanical ventilation
4.14 | U-Value 1.2 - dormer rear bedroom :1,SHE_DRAWING+SHEET.dgn,Design Model;7 ,SHE-06.FOURTH.dgn,Design Model:469524 | 1.5 | 1.15 | 1.15 | 1.5 |  | U-Value 1.2 | 4.14 | dormer rear bedroom | Rw 37dB, Rw+Ctr 35dB | G-Value 0.4 | New Construction | mechanical ventilation

# IfcWindow: A-Fixed (48)
In: RL
Type - Description: Fixed Window; OperationType: USERDEFINED; ParameterTakesPrecedence: no; Sizeable: no
Type - Lining - LiningDepth: 0.1 m; LiningThickness: 0.042 m
Type - Window Parameters - Parametric | File Type: PAZ; Parametric | File Name: HM_Fixed; Dimension | Frame Width: 1.36 m; Dimension | Frame Height: 1.455 m; Dimension | Frame Depth: 0.1 m; Dimension | Frame Depth Match Wall: no; Dimension | Frame Thickness: 0.042 m
Type - Window Dimensions- Extended - Dimension | Number of Frames: 0
Type - Window - Window | Type: Fixed
Type - Thermal Transmittance - Is External: no; Is Below Grade: no
Type - Identification - ID | Description: Fixed Window
Type - Fire Resistance - Fire | IsCombustible: no; Fire | Compartmentation: no
Type - Discipline - Discipline: Architectural
Type - Classification - Uniclass2015: Pr_30_59_98
Material: A_BSUK_Window_Frames
Window Dimensions- Extended - Dimension | Rough Opening Offset: 0 m; Dimension | Mullion Thickness: 0 m; Dimension | Mullion Spacing: 0 m; Dimension | Mullion Offset-Left: 0 m; Dimension | Mullion Offset-Right: 0 m; Dimension | Mullion Offset-Horizontal: 0 m; Dimension | Muntin Horizontal Spacing: 0 m; Dimension | Muntin Vertical Spacing: 0 m; Dimension | Muntin Thickness: 0 m; Dimension | Muntin Inset Distance: 0 m; Dimension | Top Sash Height: 0 m
Name | Description | OverallHeight (m) | OverallWidth (m) | Dimension | Frame Width (m) | Dimension | Frame Height (m) | Glazing | Notes | ID | Number | ID | Description | ID | Asset Tag | ID | Notes | Phase
0.01 | commercial side window :1,SHE_DRAWING+SHEET.dgn,Design Model;1 ,SHE-01.GROUND.dgn,Design Model:106209 | 0.3 | 1.5 | 1.5 | 0.3 | security - Part Q / PAS24 compliance | 0.01 | commercial side window | G-Value 0.6 | Fixed Window | Existing to Remain
0.02 | commercial shopfront :1 ,SHE_DRAWING+SHEET.dgn,Design Model;1,SHE-01.GROUND.dgn,Design Model:106471 | 2 | 1.9 | 1.9 | 2 | safety glass - both sides | 0.02 | commercial shopfront | G-Value 0.6 | Fixed Window | Existing to Remain
0.03 | commercial shopfront :1 ,SHE_DRAWING+SHEET.dgn,Design Model;1,SHE-01.GROUND.dgn,Design Model:106602 | 2 | 0.55 | 0.55 | 2 | safety glass - both sides | 0.03 | commercial shopfront | G-Value 0.6 | Fixed Window | Existing to Remain
0.04 | commercial shopfront :1 ,SHE_DRAWING+SHEET.dgn,Design Model;1,SHE-01.GROUND.dgn,Design Model:106868 | 2 | 1.9 | 1.9 | 2 | safety glass - both sides | 0.04 | commercial shopfront | G-Value 0.6 | Fixed Window | Existing to Remain
0.09 | U-Value 1.4 - bedroom :1 ,SHE_DRAWING+SHEET.dgn,Design Model;1,SHE-01.GROUND.dgn,Design Model:107630 | 0.3 | 1.5 | 1.5 | 0.3 | security - Part Q / PAS24 compliance | 0.09 | bedroom | G-Value 0.6 | Fixed Window | Existing to Remain | Identification - ID | Type ID: U-Value 1.4; ID | Keynote: Rw 37dB, Rw+Ctr 35dB
0.11 | commercial side window :1,SHE_DRAWING+SHEET.dgn,Design Model;1 ,SHE-01.GROUND.dgn,Design Model:107987 | 0.3 | 1.5 | 1.5 | 0.3 | security - Part Q / PAS24 compliance | 0.11 | commercial side window | G-Value 0.6 | Fixed Window | Existing to Remain
0.13 | commercial side window :1,SHE_DRAWING+SHEET.dgn,Design Model;1 ,SHE-01.GROUND.dgn,Design Model:108344 | 0.3 | 1.5 | 1.5 | 0.3 | security - Part Q / PAS24 compliance | 0.13 | commercial side window | G-Value 0.6 | Fixed Window | Existing to Remain
0.16 | commercial side window / WC :1,SHE_DRAWING+SHEET.dgn,Design Model;1 ,SHE-01.GROUND.dgn,Design Model:108927 | 0.3 | 1.5 | 1.5 | 0.3 | security - Part Q / PAS24 compliance | 0.16 | commercial side window / WC | G-Value 0.6 | Fixed Window | Existing to Remain
0.06 | entrance hall shopfront :1,SHE_DRAWING+SHEET.dgn,Design Model;1 ,SHE-01.GROUND.dgn,Design Model:137329 | 2.4 | 1.59 | 1.59 | 2.4 | safety glass - both sides | 0.06 | entrance hall shopfront | G-Value 0.6 | Fixed Window | Existing to Remain
0.05 | entrance hall shopfront :1,SHE_DRAWING+SHEET.dgn,Design Model;1 ,SHE-01.GROUND.dgn,Design Model:137460 | 2.4 | 1.59 | 1.59 | 2.4 | safety glass - both sides | 0.05 | entrance hall shopfront | G-Value 0.6 | Fixed Window | Existing to Remain
0.07 | entrance hall shopfront :1,SHE_DRAWING+SHEET.dgn,Design Model;1 ,SHE-01.GROUND.dgn,Design Model:137591 | 2.4 | 1.59 | 1.59 | 2.4 | safety glass - both sides | 0.07 | entrance hall shopfront | G-Value 0.6 | Fixed Window | Existing to Remain
0.24 | entrance residential hall :1,SHE_DRAWING+SHEET.dgn,Design Model;1 ,SHE-01.GROUND.dgn,Design Model:288478 | 2.127 | 0.48 | 0.48 | 2.127 | safety glass - both sides | 0.24 | entrance residential hall | G-Value 0.6 | Fixed Window | Existing to Remain
0.25 | entrance residential hall :1,SHE_DRAWING+SHEET.dgn,Design Model;1 ,SHE-01.GROUND.dgn,Design Model:288984 | 2.127 | 0.48 | 0.48 | 2.127 | safety glass - both sides | 0.25 | entrance residential hall | G-Value 0.6 | Fixed Window | Existing to Remain
0.17 | U-Value 1.4 - KDL :1 ,SHE_DRAWING+SHEET.dgn,Design Model;2,SHE-02.MEZZANINE.dgn,Design Model:98188 | 1.5 | 0.9 | 0.9 | 1.5 | security - Part Q / PAS24 compliance | 0.17 | KDL | G-Value 0.6 | Roof Light | New Construction | Identification - ID | Type ID: U-Value 1.4; ID | Keynote: Rw 34dB, Rw+Ctr 30dB
0.18 | U-Value 1.4 - KDL :1 ,SHE_DRAWING+SHEET.dgn,Design Model;2,SHE-02.MEZZANINE.dgn,Design Model:98323 | 1.5 | 0.9 | 0.9 | 1.5 | security - Part Q / PAS24 compliance | 0.18 | KDL | G-Value 0.6 | Roof Light | New Construction | Identification - ID | Type ID: U-Value 1.4; ID | Keynote: Rw 34dB, Rw+Ctr 30dB
5.17 | brise-soleil/shading :1 ,SHE_DRAWING+SHEET.dgn,Design Model;8,SHE-07.FIFTH.dgn,Design Model:100980 | 2.1 | 0.55 | 0.75 | 2.1 | safety glass - single layer | 5.17 | brise-soleil/shading |  | frameless glass | New Construction
5.18 | brise-soleil/shading :1 ,SHE_DRAWING+SHEET.dgn,Design Model;8,SHE-07.FIFTH.dgn,Design Model:101115 | 2.1 | 0.55 | 0.75 | 2.1 | safety glass - single layer | 5.18 | brise-soleil/shading |  | frameless glass | New Construction
5.19 | brise-soleil/shading :1 ,SHE_DRAWING+SHEET.dgn,Design Model;8,SHE-07.FIFTH.dgn,Design Model:101250 | 2.1 | 0.55 | 0.75 | 2.1 | safety glass - single layer | 5.19 | brise-soleil/shading |  | frameless glass | New Construction
5.20 | brise-soleil/shading :1 ,SHE_DRAWING+SHEET.dgn,Design Model;8,SHE-07.FIFTH.dgn,Design Model:101520 | 2.1 | 0.55 | 0.75 | 2.1 | safety glass - single layer | 5.20 | brise-soleil/shading |  | frameless glass | New Construction
5.21 | brise-soleil/shading :1 ,SHE_DRAWING+SHEET.dgn,Design Model;8,SHE-07.FIFTH.dgn,Design Model:101655 | 2.1 | 0.55 | 0.75 | 2.1 | safety glass - single layer | 5.21 | brise-soleil/shading |  | frameless glass | New Construction
5.22 | brise-soleil/shading :1 ,SHE_DRAWING+SHEET.dgn,Design Model;8,SHE-07.FIFTH.dgn,Design Model:101790 | 2.1 | 0.55 | 0.75 | 2.1 | safety glass - single layer | 5.22 | brise-soleil/shading |  | frameless glass | New Construction
5.23 | brise-soleil/shading :1 ,SHE_DRAWING+SHEET.dgn,Design Model;8,SHE-07.FIFTH.dgn,Design Model:101925 | 2.01 | 0.55 | 0.75 | 2.1 | safety glass - single layer | 5.23 | brise-soleil/shading |  | frameless glass | New Construction
5.24 | brise-soleil/shading :1 ,SHE_DRAWING+SHEET.dgn,Design Model;8,SHE-07.FIFTH.dgn,Design Model:102060 | 2.1 | 0.55 | 0.75 | 2.1 | safety glass - single layer | 5.24 | brise-soleil/shading |  | frameless glass | New Construction
5.25 | brise-soleil/shading :1 ,SHE_DRAWING+SHEET.dgn,Design Model;8,SHE-07.FIFTH.dgn,Design Model:102330 | 2.1 | 0.55 | 0.75 | 2.1 | safety glass - single layer | 5.25 | brise-soleil/shading |  | frameless glass | New Construction
5.26 | brise-soleil/shading :1 ,SHE_DRAWING+SHEET.dgn,Design Model;8,SHE-07.FIFTH.dgn,Design Model:102465 | 2.1 | 0.55 | 0.75 | 2.1 | safety glass - single layer | 5.26 | brise-soleil/shading |  | frameless glass | New Construction
5.27 | brise-soleil/shading :1 ,SHE_DRAWING+SHEET.dgn,Design Model;8,SHE-07.FIFTH.dgn,Design Model:102600 | 2.1 | 0.55 | 0.75 | 2.1 | safety glass - single layer | 5.27 | brise-soleil/shading |  | frameless glass | New Construction
5.28 | brise-soleil/shading :1 ,SHE_DRAWING+SHEET.dgn,Design Model;8,SHE-07.FIFTH.dgn,Design Model:102735 | 2.1 | 0.55 | 0.75 | 2.1 | safety glass - single layer | 5.28 | brise-soleil/shading |  | frameless glass | New Construction
5.29 | brise-soleil/shading :1 ,SHE_DRAWING+SHEET.dgn,Design Model;8,SHE-07.FIFTH.dgn,Design Model:102870 | 2.1 | 0.55 | 0.75 | 2.1 | safety glass - single layer | 5.29 | brise-soleil/shading |  | frameless glass | New Construction
5.30 | brise-soleil/shading :1 ,SHE_DRAWING+SHEET.dgn,Design Model;8,SHE-07.FIFTH.dgn,Design Model:119721 | 2.01 | 0.55 | 0.75 | 2.1 | safety glass - single layer | 5.30 | brise-soleil/shading |  | frameless glass | New Construction
5.31 | brise-soleil/shading :1 ,SHE_DRAWING+SHEET.dgn,Design Model;8,SHE-07.FIFTH.dgn,Design Model:120004 | 2.01 | 0.55 | 0.75 | 2.1 | safety glass - single layer | 5.31 | brise-soleil/shading |  | frameless glass | New Construction
5.32 | brise-soleil/shading :1 ,SHE_DRAWING+SHEET.dgn,Design Model;8,SHE-07.FIFTH.dgn,Design Model:120135 | 2.01 | 0.55 | 0.75 | 2.1 | safety glass - single layer | 5.32 | brise-soleil/shading |  | frameless glass | New Construction
5.15 | U-Value 1.2 - fixed rear window :1,SHE_DRAWING+SHEET.dgn,Design Model;8 ,SHE-07.FIFTH.dgn,Design Model:220645 | 2.2 | 1.6 | 1.6 | 2.2 | safety glass - both sides | 5.15 | fixed rear window | G-Value 0.4 | Patio Doors | New Construction | Identification - ID | Type ID: U-Value 1.2; ID | Keynote: Rw 34dB, Rw+Ctr 30dB; ID | Name (Alternate): mechanical ventilation
5.16 | U-Value 1.2 - sliding rear windows :1,SHE_DRAWING+SHEET.dgn,Design Model;8 ,SHE-07.FIFTH.dgn,Design Model:220776 | 2.2 | 1.6 | 1.6 | 2.2 | safety glass - both sides | 5.16 | sliding rear windows | G-Value 0.4 | Patio Doors | New Construction | Identification - ID | Type ID: U-Value 1.2; ID | Keynote: Rw 34dB, Rw+Ctr 30dB; ID | Name (Alternate): mechanical ventilation
5.14 | U-Value 1.2 - sliding rear windows :1,SHE_DRAWING+SHEET.dgn,Design Model;8 ,SHE-07.FIFTH.dgn,Design Model:220907 | 2.2 | 1.6 | 1.6 | 2.2 | safety glass - both sides | 5.14 | sliding rear windows | G-Value 0.4 | Patio Doors | New Construction | Identification - ID | Type ID: U-Value 1.2; ID | Keynote: Rw 34dB, Rw+Ctr 30dB; ID | Name (Alternate): mechanical ventilation
5.13 | U-Value 1.2 - fixed rear window :1,SHE_DRAWING+SHEET.dgn,Design Model;8 ,SHE-07.FIFTH.dgn,Design Model:221038 | 2.2 | 1.6 | 1.6 | 2.2 | safety glass - both sides | 5.13 | fixed rear window | G-Value 0.4 | Patio Doors | New Construction | Identification - ID | Type ID: U-Value 1.2; ID | Keynote: Rw 34dB, Rw+Ctr 30dB; ID | Name (Alternate): mechanical ventilation
5.12 | U-Value 1.2 - fixed rear window :1,SHE_DRAWING+SHEET.dgn,Design Model;8 ,SHE-07.FIFTH.dgn,Design Model:221169 | 2.2 | 1.6 | 1.6 | 2.2 | safety glass - both sides | 5.12 | fixed rear window | G-Value 0.4 | Patio Doors | New Construction | Identification - ID | Type ID: U-Value 1.2; ID | Keynote: Rw 34dB, Rw+Ctr 30dB; ID | Name (Alternate): mechanical ventilation
5.11 | U-Value 1.2 - sliding rear windows :1,SHE_DRAWING+SHEET.dgn,Design Model;8 ,SHE-07.FIFTH.dgn,Design Model:221300 | 2.2 | 1.6 | 1.6 | 2.2 | safety glass - both sides | 5.11 | sliding rear windows | G-Value 0.4 | Patio Doors | New Construction | Identification - ID | Type ID: U-Value 1.2; ID | Keynote: Rw 34dB, Rw+Ctr 30dB; ID | Name (Alternate): mechanical ventilation
5.10 | U-Value 1.2 - fixed rear window :1,SHE_DRAWING+SHEET.dgn,Design Model;8 ,SHE-07.FIFTH.dgn,Design Model:221431 | 2.2 | 1.6 | 1.6 | 2.2 | safety glass - both sides | 5.10 | fixed rear window | G-Value 0.4 | Patio Doors | New Construction | Identification - ID | Type ID: U-Value 1.2; ID | Keynote: Rw 34dB, Rw+Ctr 30dB; ID | Name (Alternate): mechanical ventilation
5.09 | U-Value 1.2 - sliding rear windows :1,SHE_DRAWING+SHEET.dgn,Design Model;8 ,SHE-07.FIFTH.dgn,Design Model:221562 | 2.2 | 1.6 | 1.6 | 2.2 | safety glass - both sides | 5.09 | sliding rear windows | G-Value 0.4 | Patio Doors | New Construction | Identification - ID | Type ID: U-Value 1.2; ID | Keynote: Rw 34dB, Rw+Ctr 30dB; ID | Name (Alternate): mechanical ventilation
5.08 | U-Value 1.2 - sliding front window :1,SHE_DRAWING+SHEET.dgn,Design Model;8 ,SHE-07.FIFTH.dgn,Design Model:223051 | 2.2 | 1.6 | 1.6 | 2.2 | safety glass - both sides | 5.08 | sliding front window | G-Value 0.4 | Patio Doors | New Construction | Identification - ID | Type ID: U-Value 1.2; ID | Keynote: Rw 46dB, Rw+Ctr 40dB; ID | Name (Alternate): mechanical ventilation
5.07 | U-Value 1.2 - fixed front window :1,SHE_DRAWING+SHEET.dgn,Design Model;8 ,SHE-07.FIFTH.dgn,Design Model:223186 | 2.2 | 1.6 | 1.6 | 2.2 | safety glass - both sides | 5.07 | fixed front window | G-Value 0.4 | Patio Doors | New Construction | Identification - ID | Type ID: U-Value 1.2; ID | Keynote: Rw 46dB, Rw+Ctr 40dB; ID | Name (Alternate): mechanical ventilation
5.05 | U-Value 1.2 - sliding front window :1,SHE_DRAWING+SHEET.dgn,Design Model;8 ,SHE-07.FIFTH.dgn,Design Model:223321 | 2.2 | 1.6 | 1.6 | 2.2 | safety glass - both sides | 5.05 | sliding front window | G-Value 0.4 | Patio Doors | New Construction | Identification - ID | Type ID: U-Value 1.2; ID | Keynote: Rw 46dB, Rw+Ctr 40dB; ID | Name (Alternate): mechanical ventilation
5.06 | U-Value 1.2 - fixed front window :1,SHE_DRAWING+SHEET.dgn,Design Model;8 ,SHE-07.FIFTH.dgn,Design Model:223456 | 2.2 | 1.6 | 1.6 | 2.2 | safety glass - both sides | 5.06 | fixed front window | G-Value 0.4 | Patio Doors | New Construction | Identification - ID | Type ID: U-Value 1.2; ID | Keynote: Rw 46dB, Rw+Ctr 40dB; ID | Name (Alternate): mechanical ventilation
5.01 | U-Value 1.2 - fixed front window :1,SHE_DRAWING+SHEET.dgn,Design Model;8 ,SHE-07.FIFTH.dgn,Design Model:223591 | 2.2 | 1.6 | 1.6 | 2.2 | safety glass - both sides | 5.01 | fixed front window | G-Value 0.4 | Patio Doors | New Construction | Identification - ID | Type ID: U-Value 1.2; ID | Keynote: Rw 46dB, Rw+Ctr 40dB; ID | Name (Alternate): mechanical ventilation
5.02 | U-Value 1.2 - sliding front window :1,SHE_DRAWING+SHEET.dgn,Design Model;8 ,SHE-07.FIFTH.dgn,Design Model:223726 | 2.2 | 1.6 | 1.6 | 2.2 | safety glass - both sides | 5.02 | sliding front window | G-Value 0.4 | Patio Doors | New Construction | Identification - ID | Type ID: U-Value 1.2; ID | Keynote: Rw 46dB, Rw+Ctr 40dB; ID | Name (Alternate): mechanical ventilation
5.03 | U-Value 1.2 - fixed front window :1,SHE_DRAWING+SHEET.dgn,Design Model;8 ,SHE-07.FIFTH.dgn,Design Model:223861 | 2.2 | 1.6 | 1.6 | 2.2 | safety glass - both sides | 5.03 | fixed front window | G-Value 0.4 | Patio Doors | New Construction | Identification - ID | Type ID: U-Value 1.2; ID | Keynote: Rw 46dB, Rw+Ctr 40dB; ID | Name (Alternate): mechanical ventilation
5.04 | U-Value 1.2 - sliding front window :1,SHE_DRAWING+SHEET.dgn,Design Model;8 ,SHE-07.FIFTH.dgn,Design Model:223996 | 2.2 | 1.6 | 1.6 | 2.2 | safety glass - both sides | 5.04 | sliding front window | G-Value 0.4 | Patio Doors | New Construction | Identification - ID | Type ID: U-Value 1.2; ID | Keynote: Rw 46dB, Rw+Ctr 40dB; ID | Name (Alternate): mechanical ventilation
6.01 | U-Value 1.2 - AOV2 access over common parts :1,SHE_DRAWING+SHEET.dgn ,Design Model;14,SHE-08.ROOF.dgn,Design Model:104968 | 2.038 | 1 | 1 | 2 | self-opening , safety glass | 6.01 | AOV2 access over common parts | G-Value 0.4 | Roof Light | New Construction | Identification - ID | Type ID: U-Value 1.2
